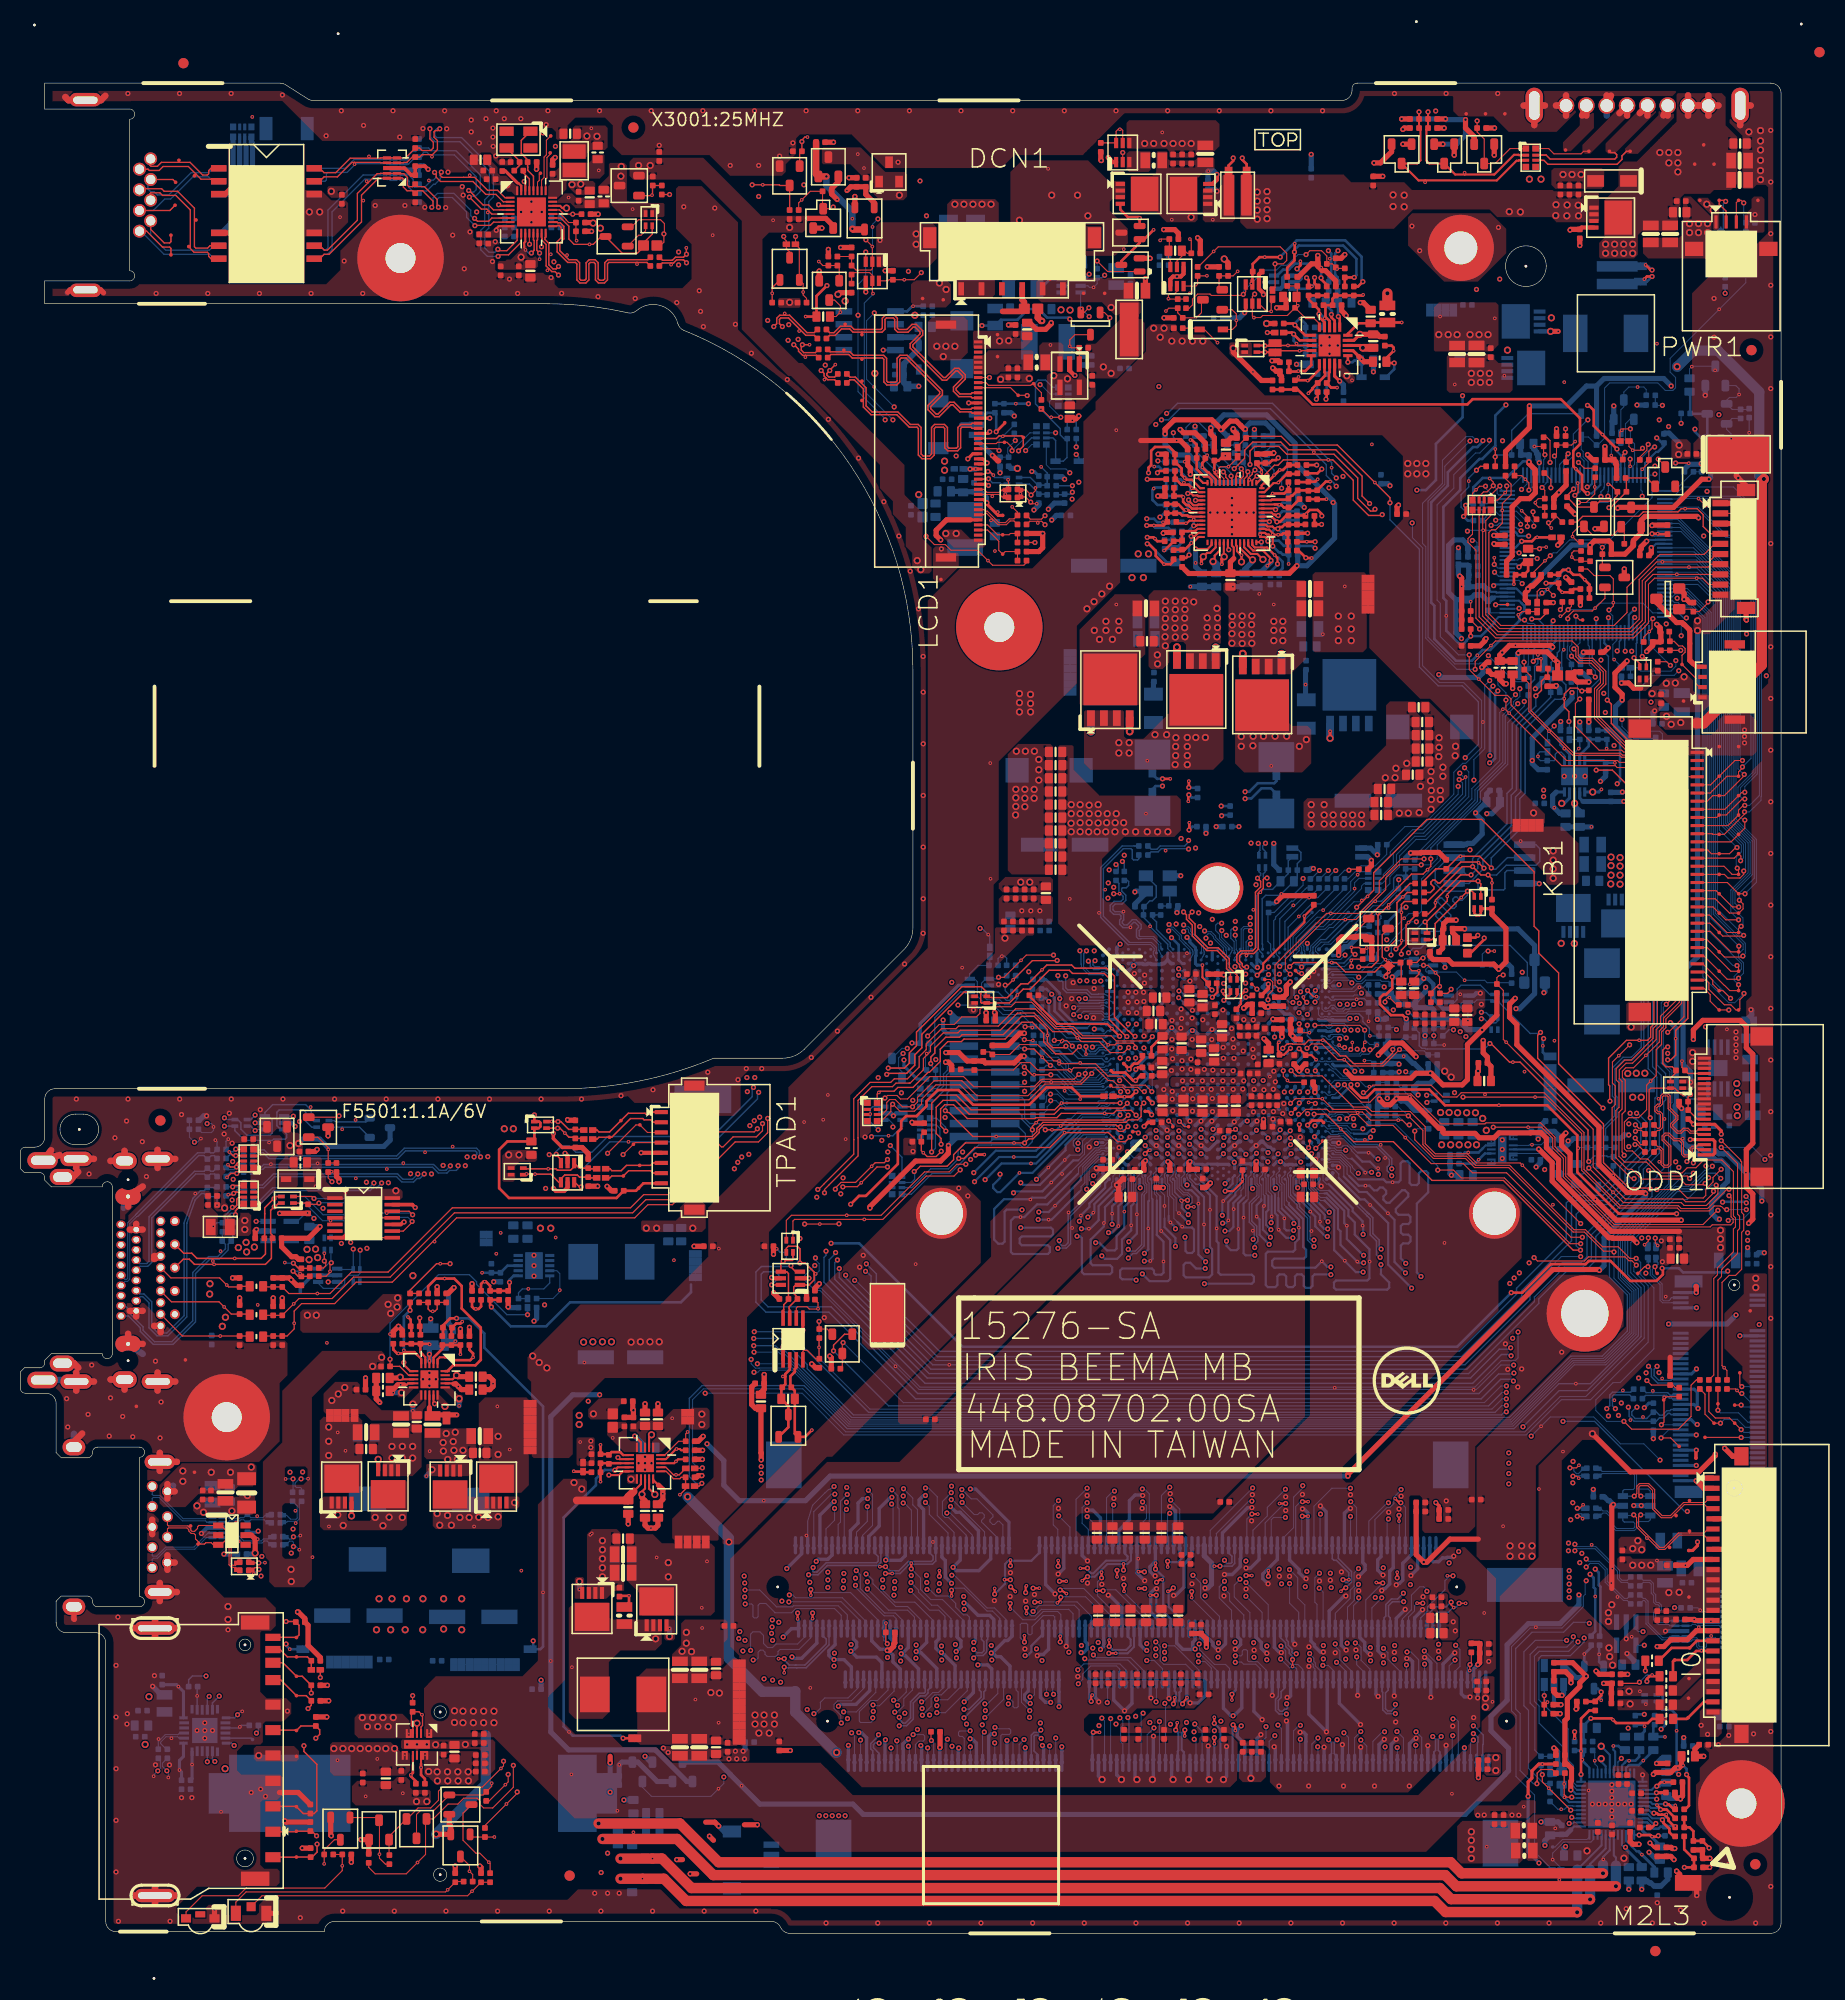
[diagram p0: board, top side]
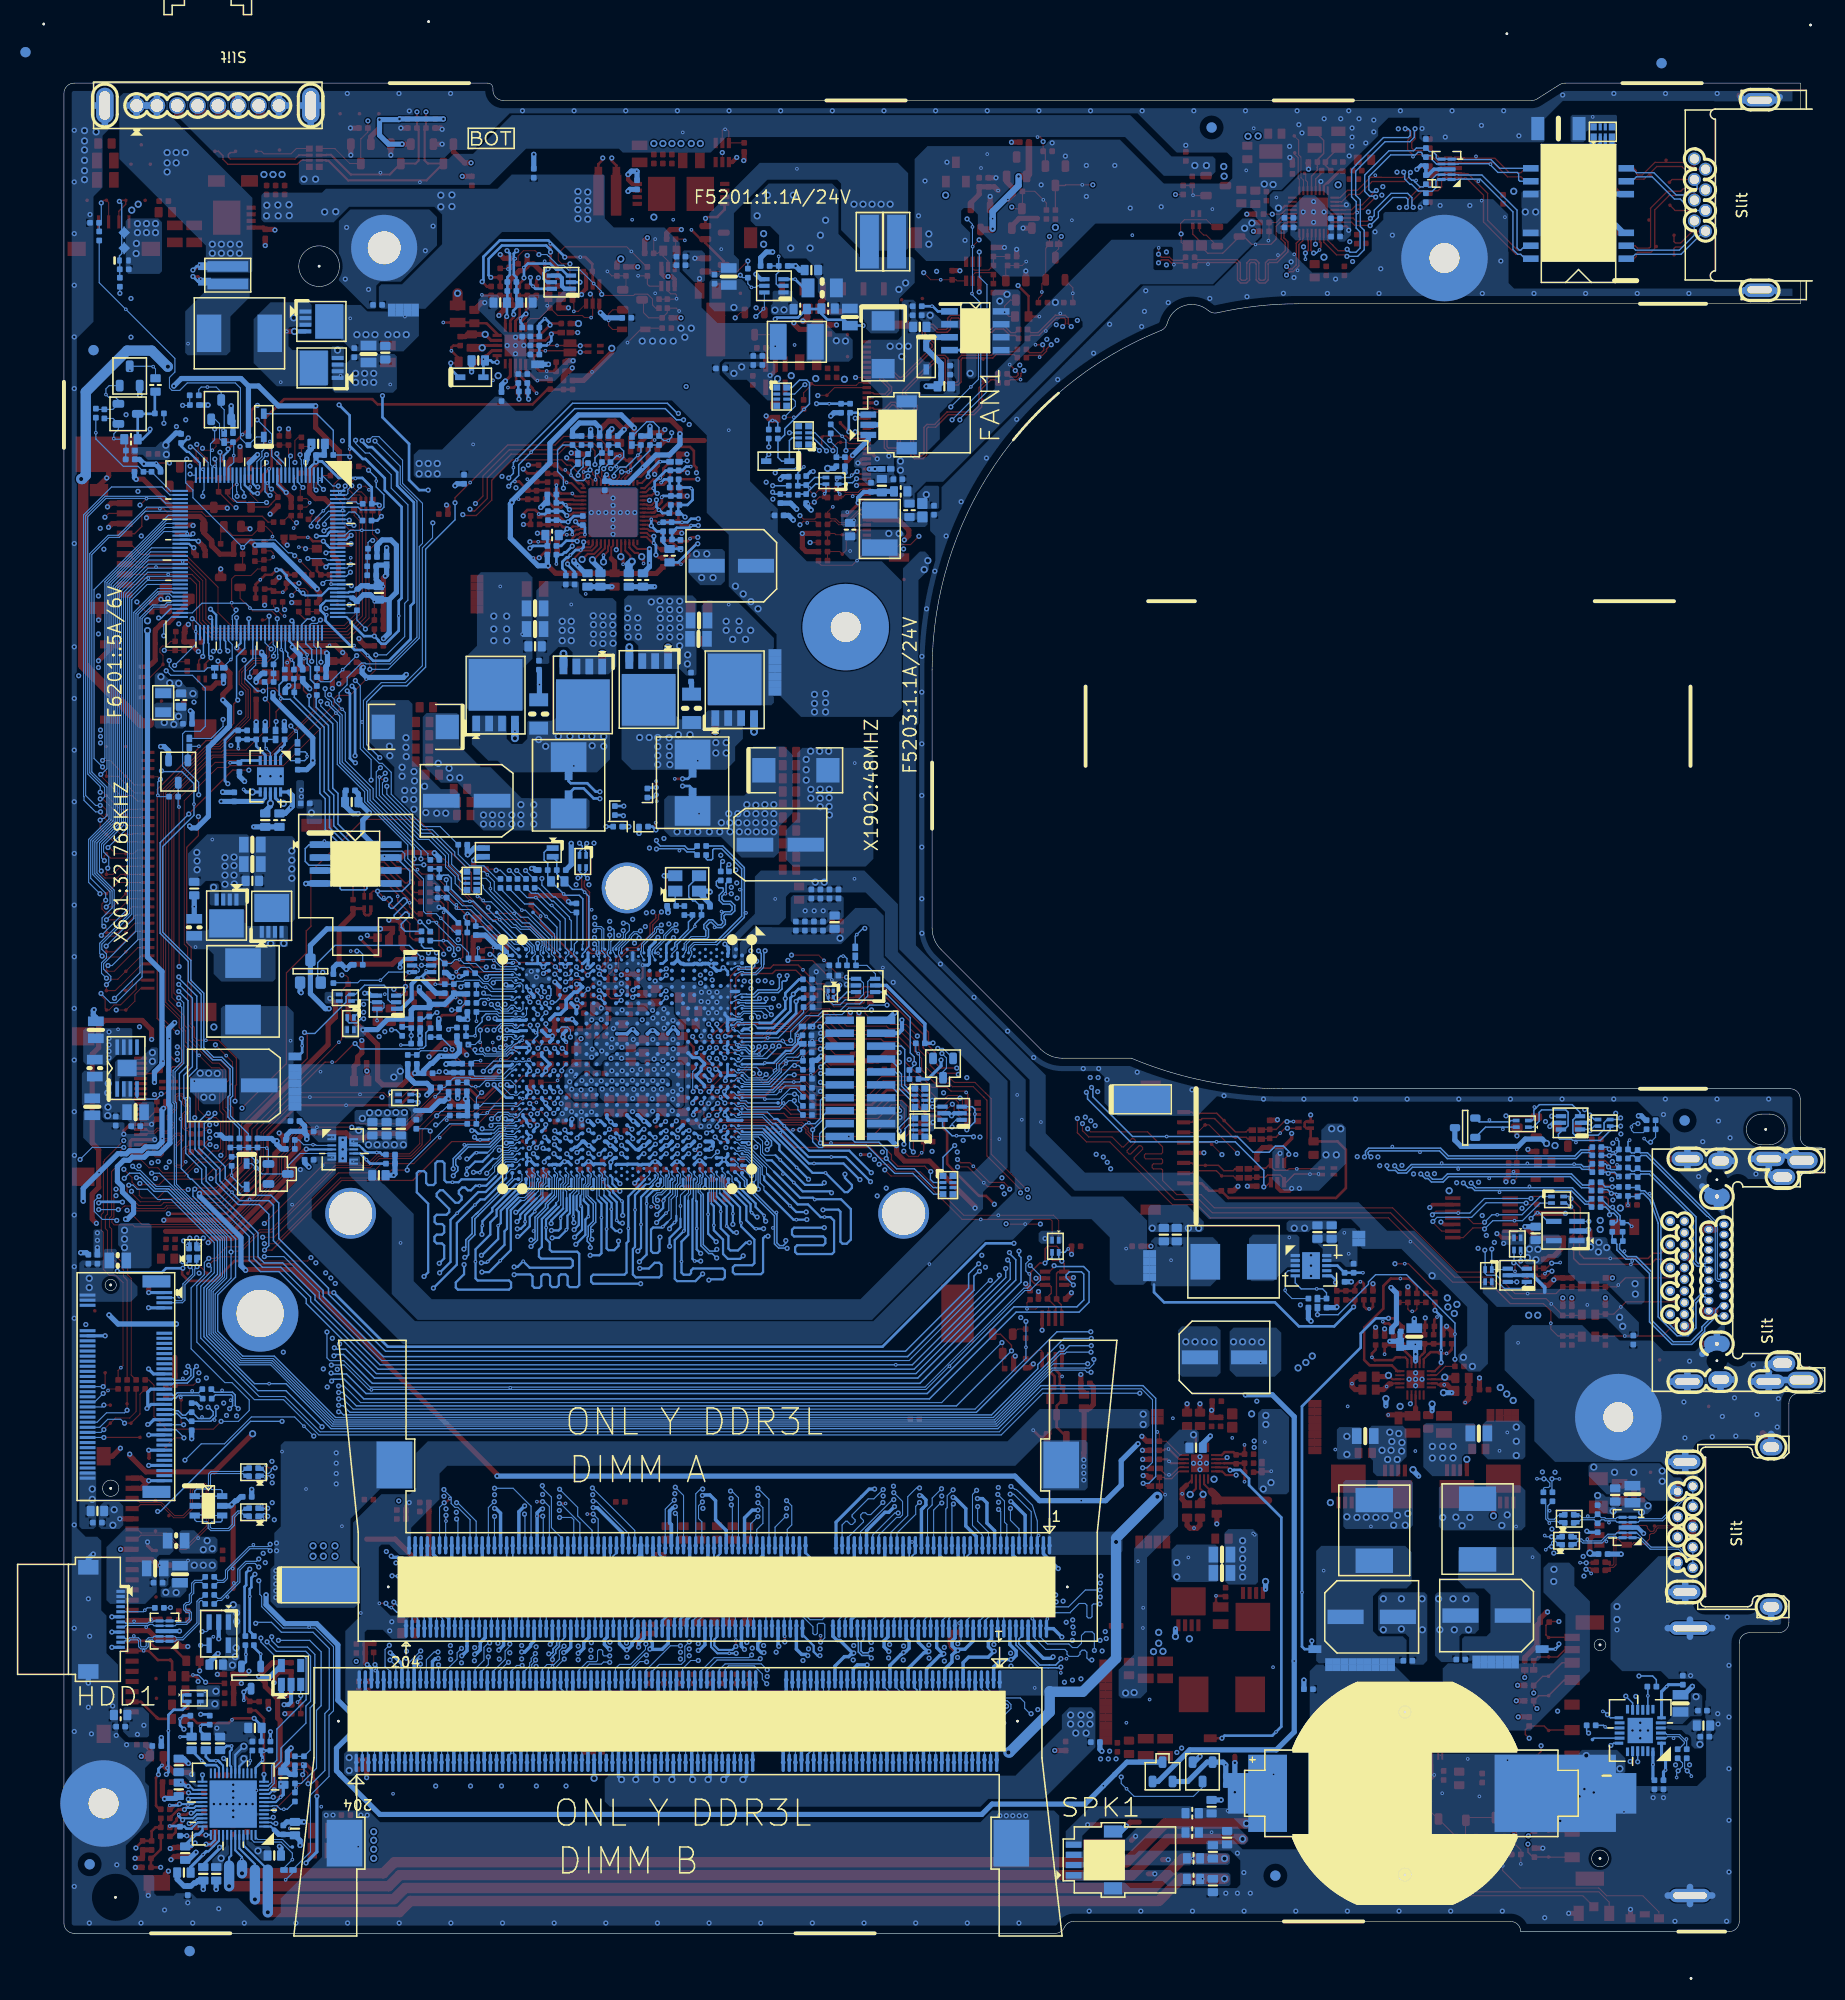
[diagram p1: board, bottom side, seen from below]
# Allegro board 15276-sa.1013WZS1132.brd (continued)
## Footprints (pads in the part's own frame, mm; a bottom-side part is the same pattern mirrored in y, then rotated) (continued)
NTC-402H22-U
  custom 0.14x0.14 smd: 1(0,0.445) 2(0,-0.445)
NTC-603H38
  custom 0.216x0.216 smd: 1(0,0.762) 2(0,-0.762)
OSC-3225-4P-3H36
  rect 1.397x0.914 smd: 1(-1.171,-0.825) 2(1.171,-0.825) 3(1.171,0.825) 4(-1.171,0.825)
OSC-3225-4P-4H36
  rect 1.397x1.067 smd: 1(-1.171,-0.756) 2(1.171,-0.756) 3(1.171,0.756) 4(-1.171,0.756)
PAD-2P-4516-U
  rect 1.854x4.013 smd: 1(0,1.969)
  rect 1.854x1.346 smd: 2(0,-1.969)
PAD-D-SUB-HDMI-COLAY-U
  round 0.254 hole 1.422 unplated: (-8.9,6.45) (8.9,6.45)
  round 0.914 hole 0.61: 1(-4.33,9.65) 2(-2.04,9.65) 3(0.25,9.65) 4(2.54,9.65) 5(4.83,9.65) 6(-5.475,9.65) 7(-3.185,9.65) 8(-0.895,9.65) 9(1.395,9.65) 10(3.685,9.65)
  round 0.965 hole 0.61: 11(-4.33,11.05) 12(-2.04,11.05) 13(0.25,11.05) 14(2.54,11.05) 15(4.83,11.05)
  oval 0.762x0.914 hole 0.508: HP1(-4.5,5.75) HP2(-4,7.25) HP3(-3.5,5.75) HP4(-3,7.25) HP5(-2.5,5.75) HP6(-2,7.25) HP7(-1.5,5.75) HP8(-1,7.25) HP9(-0.5,5.75) HP10(0,7.25) HP11(0.5,5.75) HP12(1,7.25) HP13(1.5,5.75) HP14(2,7.25) HP15(2.5,5.75) HP16(3,7.25) HP17(3.5,5.75) HP18(4,7.25) HP19(4.5,5.75)
  oval 1.422x3.124 hole 0.711x2.413: PTH1(10.95,9.35) PTH4(10.95,1.35) PTH7(-10.95,9.35) PTH10(-10.95,1.35)
  oval 1.626x2.413 hole 0.914x1.702: PTH2(10.75,6.1) PTH9(-10.75,6.1)
  custom 0.404x0.404 hole 0.914x1.803: PTH3(7.25,6.45) PTH8(-7.25,6.45)
  oval 1.575x2.515 hole 0.914x1.803: PTH5(9.15,0) PTH11(-9.15,0)
  oval 1.626x2.997 hole 0.914x2.413: PTH6(10.8,-1.9) PTH12(-10.8,-1.9)
POLYSW-2114H30
  rect 1.6x0.965 smd: 1(0,0.94) 2(0,-0.94)
POLYSW-2114H50
  rect 1.6x0.965 smd: 1(0,0.94) 2(0,-0.94)
POLYSW-4633-UH43
  rect 3.505x1.626 smd: 1(0,1.834) 2(0,-1.834)
PPAK-5PH45
  rect 0.762x1.524 smd: 1(-1.905,-3.81) 2(-0.635,-3.81) 3(0.635,-3.81) 4(1.905,-3.81)
  rect 5.283x5.08 smd: 5(0,0)
  rect 0.025x0.025 smd: 6(0.635,2.032) 7(-0.635,2.032) 8(-1.905,2.032)
PPAK-8P-2H45
  rect 0.406x1.168 smd: 1(-0.975,-2.351) 2(-0.325,-2.351) 3(0.325,-2.351) 4(0.975,-2.351)
  rect 3.404x2.769 smd: 5(0,0)
  rect 0.025x0.025 smd: 6(1.029,0.902) 7(0.013,0.902) 8(-0.991,0.902)
PPAK-8P-3232H36
  rect 0.406x0.914 smd: 1(-0.975,-2.396) 2(-0.325,-2.396) 3(0.325,-2.396) 4(0.975,-2.396)
  rect 3.353x2.692 smd: 5(0,0)
  rect 0.025x0.025 smd: 6(0.65,0.838) 7(0,0.838) 8(-0.65,0.838)
QFN20-G1D75H32
  rect 0.203x0.914 smd: 1(0.8,1.551) 2(0.4,1.551) 3(0,1.551) 4(-0.4,1.551) 5(-0.8,1.551) 11(-0.8,-1.551) 12(-0.4,-1.551) 13(0,-1.551) 14(0.4,-1.551) 15(0.8,-1.551)
  rect 0.914x0.203 smd: 6(-1.551,0.8) 7(-1.551,0.4) 8(-1.551,0) 9(-1.551,-0.4) 10(-1.551,-0.8) 16(1.551,-0.8) 17(1.551,-0.4) 18(1.551,0) 19(1.551,0.4) 20(1.551,0.8)
  rect 1.753x1.753 smd: 21(0,0)
QFN20G3D5-G2D15H40
  rect 0.305x0.914 smd: 1(1,1.801) 5(-1,1.801) 11(-1,-1.801) 15(1,-1.801)
  rect 0.305x0.965 smd: 2(0.5,1.775) 3(0,1.775) 4(-0.5,1.775) 12(-0.5,-1.775) 13(0,-1.775) 14(0.5,-1.775)
  rect 0.914x0.305 smd: 6(-1.801,1) 10(-1.801,-1) 16(1.801,-1) 20(1.801,1)
  rect 0.965x0.305 smd: 7(-1.775,0.5) 8(-1.775,0) 9(-1.775,-0.5) 17(1.775,-0.5) 18(1.775,0) 19(1.775,0.5)
  rect 2.159x2.159 smd: 21(0,0)
QFN24-G2D5H40-U
  rect 0.305x0.838 smd: 1(1.25,2.095) 6(-1.25,2.095) 13(-1.25,-2.095) 18(1.25,-2.095)
  rect 0.305x0.965 smd: 2(0.751,2.032) 3(0.25,2.032) 4(-0.25,2.032) 5(-0.751,2.032) 14(-0.751,-2.032) 15(-0.25,-2.032) 16(0.25,-2.032) 17(0.751,-2.032)
  rect 0.838x0.305 smd: 7(-2.095,1.25) 12(-2.095,-1.25) 19(2.095,-1.25) 24(2.095,1.25)
  rect 0.965x0.305 smd: 8(-2.032,0.751) 9(-2.032,0.25) 10(-2.032,-0.25) 11(-2.032,-0.751) 20(2.032,-0.751) 21(2.032,-0.25) 22(2.032,0.25) 23(2.032,0.751)
  rect 2.489x2.489 smd: 25(0,0)
QFN32J4-G2D85H36
  rect 0.203x0.864 smd: 1(1.4,2.085) 2(1,2.085) 3(0.6,2.085) 4(0.2,2.085) 5(-0.2,2.085) 6(-0.6,2.085) 7(-1,2.085) 8(-1.4,2.085) 17(-1.4,-2.085) 18(-1,-2.085) 19(-0.6,-2.085) 20(-0.2,-2.085) 21(0.2,-2.085) 22(0.6,-2.085) 23(1,-2.085) 24(1.4,-2.085)
  rect 0.864x0.203 smd: 9(-2.085,1.4) 10(-2.085,1) 11(-2.085,0.6) 12(-2.085,0.2) 13(-2.085,-0.2) 14(-2.085,-0.6) 15(-2.085,-1) 16(-2.085,-1.4) 25(2.085,-1.4) 26(2.085,-1) 27(2.085,-0.6) 28(2.085,-0.2) 29(2.085,0.2) 30(2.085,0.6) 31(2.085,1) 32(2.085,1.4)
  rect 2.845x2.845 smd: 33(0,0)
QFN48J6-G465H40
  rect 0.203x0.965 smd: 1(2.2,3.025) 2(1.8,3.025) 3(1.4,3.025) 4(1,3.025) 5(0.6,3.025) 6(0.2,3.025) 7(-0.2,3.025) 8(-0.6,3.025) 9(-1,3.025) 10(-1.4,3.025) 11(-1.8,3.025) 12(-2.2,3.025) 25(-2.2,-3.025) 26(-1.8,-3.025) 27(-1.4,-3.025) 28(-1,-3.025) 29(-0.6,-3.025) 30(-0.2,-3.025) 31(0.2,-3.025) 32(0.6,-3.025) 33(1,-3.025) 34(1.4,-3.025) 35(1.8,-3.025) 36(2.2,-3.025)
  rect 0.965x0.203 smd: 13(-3.025,2.2) 14(-3.025,1.8) 15(-3.025,1.4) 16(-3.025,1) 17(-3.025,0.6) 18(-3.025,0.2) 19(-3.025,-0.2) 20(-3.025,-0.6) 21(-3.025,-1) 22(-3.025,-1.4) 23(-3.025,-1.8) 24(-3.025,-2.2) 37(3.025,-2.2) 38(3.025,-1.8) 39(3.025,-1.4) 40(3.025,-1) 41(3.025,-0.6) 42(3.025,-0.2) 43(3.025,0.2) 44(3.025,0.6) 45(3.025,1) 46(3.025,1.4) 47(3.025,1.8) 48(3.025,2.2)
  rect 4.648x4.648 smd: 49(0,0)
R402H14
  custom 0.14x0.14 smd: 1(0,0.445) 2(0,-0.445)
R402H15
  custom 0.14x0.14 smd: 1(0,0.445) 2(0,-0.445)
R402H16
  custom 0.14x0.14 smd: 1(0,0.445) 2(0,-0.445)
R603H22
  custom 0.197x0.197 smd: 1(0,0.66) 2(0,-0.66)
R805H24
  rect 1.549x0.94 smd: 1(0,0.838) 2(0,-0.838)
R1206H28
  rect 1.854x1.27 smd: 1(0,1.397) 2(0,-1.397)
R3720H40
  rect 4.013x1.041 smd: 1(0,0.867) 2(0,-0.867)
SC70-6H44
  rect 0.406x1.016 smd: 1(-0.65,-0.94) 2(0,-0.94) 3(0.65,-0.94) 4(0.65,0.94) 5(0,0.94) 6(-0.65,0.94)
SE361413H182
  rect 1.372x3.556 smd: 1(0,2.424) 2(0,-2.424)
SE361414H178
  rect 1.372x3.607 smd: 1(0,2.499) 2(0,-2.499)
SE361416H178
  rect 1.422x3.556 smd: 1(0,2.574) 2(0,-2.574)
SKT-USB13-160166-7
  round 1.067 hole 0.711: 1(3.5,9.2) 2(1,9.2) 3(-1,9.2) 4(-3.5,9.2) 5(-4,7.7) 6(-2,7.7) 7(0,7.7) 8(2,7.7) 9(4,7.7)
  oval 1.422x2.997 hole 0.711x2.286: 10(6.4,8.45) 11(-6.4,8.45)
  oval 1.626x2.235 hole 0.914x1.524: 12(7.85,0) 13(-7.85,0)
SMD49-6914-0403H56
  rect 1.168x0.559 smd: 1(-3.38,-0.427) 2(3.38,-0.427) 3(3.38,0.427) 4(-3.38,0.427)
SMD-ARES4
  rect 0.356x0.66 smd: 1(-0.325,-0.599) 2(0.325,-0.599) 3(0.325,0.599) 4(-0.325,0.599)
SMD-ARES4-2H18-U
  rect 0.305x0.406 smd: 1(-0.25,-0.305) 2(0.25,-0.305) 3(0.25,0.305) 4(-0.25,0.305)
SMD-ARES4H18
  rect 0.356x0.66 smd: 1(-0.325,-0.599) 2(0.325,-0.599) 3(0.325,0.599) 4(-0.325,0.599)
SMD-ARES4H20
  rect 0.356x0.66 smd: 1(-0.325,-0.599) 2(0.325,-0.599) 3(0.325,0.599) 4(-0.325,0.599)
SOD123FLAKH40
  rect 1.143x1.651 smd: A(0,1.622) K(0,-1.622)
SOD323AKH38
  rect 0.559x1.016 smd: A(0,1.143) K(0,-1.143)
SOD323AKH42
  rect 0.559x1.016 smd: A(0,1.143) K(0,-1.143)
SOD882-10D6-1H20
  custom 0.114x0.114 smd: 1(0,0.445) 2(0,-0.445)
SOIC8-1H86
  rect 0.635x1.651 smd: 1(-1.905,-3.493) 2(-0.635,-3.493) 3(0.635,-3.493) 4(1.905,-3.493) 5(1.905,3.493) 6(0.635,3.493) 7(-0.635,3.493) 8(-1.905,3.493)
SOIC8H69
  rect 0.635x1.651 smd: 1(-1.905,-2.54) 2(-0.635,-2.54) 3(0.635,-2.54) 4(1.905,-2.54) 5(1.905,2.54) 6(0.635,2.54) 7(-0.635,2.54) 8(-1.905,2.54)
SOT23-2D4-312H44
  custom 0.191x0.191 smd: 1(-0.984,-0.953) 2(0.984,-0.953) 3(0,0.953)
SOT23-2D4-312H48
  custom 0.191x0.191 smd: 1(-0.984,-0.953) 2(0.984,-0.953) 3(0,0.953)
SOT23-2D6-312H46
  custom 0.165x0.165 smd: 1(-0.95,-1.092) 2(0.95,-1.092) 3(0,1.092)
SOT23-2D8-312H58
  custom 0.254x0.254 smd: 1(-1.016,-1.118) 2(1.016,-1.118) 3(0,1.118)
SOT23CBE2D4H44
  custom 0.191x0.191 smd: B(-0.984,-0.953) C(0,0.953) E(0.984,-0.953)
SOT23CBE2D6H46
  custom 0.165x0.165 smd: B(-0.95,-1.092) C(0,1.092) E(0.95,-1.092)
SOT23CBE2D6H62
  custom 0.165x0.165 smd: B(-0.95,-1.092) C(0,1.092) E(0.95,-1.092)
SOT23DGS2D4H44
  custom 0.191x0.191 smd: D(0,0.953) G(-0.984,-0.953) S(0.984,-0.953)
SOT23DGS2D4H48
  custom 0.191x0.191 smd: D(0,0.953) G(-0.984,-0.953) S(0.984,-0.953)
SOT23DGS2D8H56
  custom 0.254x0.254 smd: D(0,1.118) G(-1.016,-1.118) S(1.016,-1.118)
SOT323CBE2D2H40
  custom 0.152x0.152 smd: B(-0.65,-0.902) C(0,0.902) E(0.65,-0.902)
SOT323EBC2D2H40
  custom 0.152x0.152 smd: B(-0.65,-0.902) C(0.65,-0.902) E(0,0.902)
SOT-6H58
  rect 0.584x1.016 smd: 1(-0.953,-1.346) 2(0,-1.346) 3(0.953,-1.346) 4(0.953,1.346) 5(0,1.346) 6(-0.953,1.346)
SOT-23-5H51
  rect 0.508x1.524 smd: 1(-0.95,-1.143) 2(0,-1.143) 3(0.95,-1.143) 4(0.95,1.143) 5(-0.95,1.143)
SOT-23-5H58
  rect 0.508x1.524 smd: 1(-0.95,-1.143) 2(0,-1.143) 3(0.95,-1.143) 4(0.95,1.143) 5(-0.95,1.143)
SOT-23-9H44
  custom 0.178x0.178 smd: 1(-0.95,-0.999) 2(0.95,-0.999) 3(0,0.999)
SOT-23-10H44
  rect 0.762x1.143 smd: 1(-0.984,-0.953) 2(0.984,-0.953) 3(0,0.953)
SOT-23-2924-5PH46
  rect 0.686x1.295 smd: 1(-0.95,-0.933) 2(0,-0.933) 3(0.95,-0.933) 4(0.95,0.933) 5(-0.95,0.933)
SOT-363H44
  rect 0.406x1.016 smd: 1(-0.65,-0.94) 2(0,-0.94) 3(0.65,-0.94) 4(0.65,0.94) 5(0,0.94) 6(-0.65,0.94)
SPR5930H154
  rect 5.588x2.692 smd: 1(-1.702,0)
SPR6035H166
  rect 5.69x3.2 smd: 1(-1.6,0)
SPR6438H83
  rect 6.096x3.505 smd: 1(-1.6,0)
SPR7837H229
  rect 7.493x3.353 smd: 1(-2.095,0)
TPAD14-OP
  round 0.356 smd: 1(0,0)
TSOIC14H48
  rect 0.356x1.524 smd: 1(-1.949,-2.819) 2(-1.3,-2.819) 3(-0.65,-2.819) 4(0,-2.819) 5(0.65,-2.819) 6(1.3,-2.819) 7(1.949,-2.819) 8(1.949,2.819) 9(1.3,2.819) 10(0.65,2.819) 11(0,2.819) 12(-0.65,2.819) 13(-1.3,2.819) 14(-1.949,2.819)
unnamed
  round 1.016 smd: (0,0)
XFORM12A127097H91
  rect 0.635x1.524 smd: 1(-4.445,-4.699) 2(-3.175,-4.699) 3(-1.905,-4.699) 4(1.905,-4.699) 5(3.175,-4.699) 6(4.445,-4.699) 7(4.445,4.699) 8(3.175,4.699) 9(1.905,4.699) 10(-1.905,4.699) 11(-3.175,4.699) 12(-4.445,4.699)

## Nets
3V5V_CT1: C3602.1 U3601.12
3V5V_CT2: C3601.1 U3601.10
3V5V_S0_ON: R3609.1 U3601.3 U3601.5
3V_5V_EN: D3602.1 PR4527.1 PR4529.1 R3602.1 R3603.1
3V_5V_POK: PR4510.2 PR5010.1 PU4509.7 Q601.2 RN602.2(A)
5V_HDD_S0: AFTP5601.1 C5605.1 C5606.1 HDD1.1 HDD1.2 HDD1.3 R5601.2
5V_HDMI_CRT_S0: D5501.K F5501.2 R5506.1 RN5508.1(A) RN5508.2(A) U5603.1 U5603.4 U5603.14
5V_HDMI_CRT_S0_R: C5401.1 C5519.1 F5501.1 HDMI1.9 HDMI1.HP18
5V_PWR: PC4516.1 PG4511.2 PG4512.2 PG4514.2 PG4524.2 PG4527.2 PG4528.2 PG4529.2 PG4531.2 PG4535.2 PG4547.1 PL4503.2 TC4503.1
5V_PWR_2: PG4543.2
5V_PWR_2_R: PC4529.1 PG4543.1 PU4509.13
5V_S0: C2605.1 C2611.1 C3605.1 C5601.1 C5604.1 C5609.1 D5401.3 D5501.A EC9718.1 EC9719.1 EC9720.1 EC9721.1 EC9722.1 EC9723.1 EC9724.1 EC9725.1 EC9726.1 EC9727.1 EC9728.1 F6201.1 FAN261.2 Q5403.G Q6106.E Q6201.E R2702.1 R2703.1 R2704.1 R5230.1 R5413.1 R5506.2 R5601.1 R5603.1 R6205.1 U3601.13 U3601.14 U5601.2 U5601.3
5V_S5: C3505.1 C3510.1 EC9732.1 EC9733.1 EC9734.1 PC4608.1 PC4829.1 PC4901.1 PG4511.1 PG4512.1 PG4514.1 PG4524.1 PG4527.1 PG4528.1 PG4529.1 PG4531.1 PG4535.1 PR4203.1 PR4610.2 PR4660.2 PR4661.2 PU4601.33 PU4806.7 PU4901.12 Q6103.E Q6104.E U3503.5 U3504.5 U3601.1 U3601.2 U3601.4 U3603.4
+3V_1D5V_AVDD: C2715.1 HDA27.40 R2705.2
+3V_AVDD: C2701.1 HDA27.36 R2701.2 R2722.1
+5V_AVDD: C2710.1 C2711.1 HDA27.26 R2703.2
+5V_KB_BL: AFTP6248.1 C6204.1 F6201.2 KBLIT1.1 R6205.2
+5V_PVDD: C2706.1 C2707.1 C2708.1 C2709.1 HDA27.41 HDA27.46 R2702.2 R2704.2
GND: AFTP2501.1 AFTP2803.1 AFTP3301.1 AFTP3906.1 AFTP3909.1 AFTP3910.1 AFTP6102.1 AFTP6201.1 AFTP6217.1 AFTP6235.1 AFTP6245.1 AFTP6314.1 BATT1.6 BATT1.8 BATT1.9 BATT1.10 C1.1 C2.1 C3.1 C401.2 C402.2 C443.1 C501.2 C502.2 C601.1 C603.2 C604.2 C701.2 C702.2 C703.2 C704.2 C705.2 C762.2 C1001.2 C1002.2 C1003.2 C1004.2 C1005.2 C1006.2 C1007.2 C1008.2 C1009.2 C1010.2 C1011.2 C1012.2 C1013.2 C1014.2 C1015.2 C1016.2 C1017.2 C1022.2 C1023.2 C1024.2 C1025.2 C1026.2 C1027.2 C1028.2 C1029.2 C1030.2 C1031.2 C1032.2 C1033.2 C1034.2 C1035.2 C1036.2 C1037.2 C1038.2 C1039.2 C1040.2 C1041.2 C1042.2 C1043.2 C1044.2 C1045.2 C1046.2 C1047.2 C1049.2 C1050.2 C1051.1 C1053.2 C1054.2 C1055.2 C1056.1 C1057.1 C1058.1 C1059.1 C1060.2 C1061.1 C1062.1 C1063.1 C1064.2 C1065.2 C1066.2 C1067.2 C1068.2 C1069.2 C1070.2 C1071.2 C1072.2 C1073.2 C1074.2 C1075.2 C1077.2 C1080.2 C1081.2 C1082.2 C1083.2 C1084.2 C1085.2 C1086.2 C1087.2 C1088.2 C1089.2 C1090.2 C1092.1 C1093.2 C1094.2 C1095.2 C1096.2 C1097.2 C1098.2 C1099.2 C1100.2 C1101.2 C1105.2 C1106.2 C1107.2 C1113.2 C1114.2 C1115.2 C1201.2 C1202.2 C1203.2 C1204.2 C1205.2 C1208.2 C1209.2 C1210.2 C1211.2 C1212.2 C1213.2 C1214.2 C1215.2 C1216.2 C1217.2 C1218.2 C1219.2 C1220.2 C1221.2 C1222.2 C1223.2 C1224.2 C1225.2 C1306.2 C1307.2 C1326.2 C1327.2 C1328.2 C1329.2 C1330.2 C1331.2 C1332.2 C1333.2 C1334.2 C1335.2 C1336.2 C1337.2 C1338.2 C1339.2 C1340.2 C1341.2 C1342.2 C1343.2 C1344.2 C1345.2 C1346.2 C1904.1 C1905.1 C2406.2 C2407.2 C2408.2 C2409.2 C2410.2 C2411.2 C2412.2 C2413.2 C2415.1 C2416.2 C2418.2 C2421.2 C2501.2 C2502.2 C2503.1 C2601.2 C2602.2 C2603.2 C2604.2 C2605.2 C2608.2 C2609.2 C2610.2 C2611.2 C2704.1 C2706.2 C2707.2 C2708.2 C2709.2 C2716.2 C2717.2 C2718.2 C2719.2 C2723.1 C3001.2 C3002.2 C3003.2 C3004.2 C3005.2 C3007.2 C3008.2 C3009.2 C3010.2 C3011.2 C3012.2 C3013.2 C3017.2 C3018.2 C3019.2 C3021.2 C3022.2 C3023.2 C3024.2 C3025.2 C3101.2 C3106.2 C3201.1 C3202.2 C3203.2 C3204.2 C3205.2 C3206.2 C3301.2 C3302.2 C3303.2 C3401.2 C3402.2 C3405.2 C3406.2 C3505.2 C3507.2 C3508.2 C3510.2 C3512.2 C3513.2 C3519.2 C3520.2 C3521.2 C3601.2 C3602.2 C3603.2 C3605.2 C3607.2 C3612.2 C3613.2 C3617.2 C3618.2 C3619.2 C3620.1 C3621.1 C3625.2 C3626.2 C5201.2 C5202.2 C5204.2 C5205.1 C5206.1 C5207.2 C5208.2 C5214.2 C5401.2 C5506.2 C5508.2 C5509.2 C5510.2 C5511.2 C5519.2 C5539.2 C5540.2 C5541.2 C5542.2 C5543.2 C5601.2 C5604.2 C5605.2 C5606.2 C5609.2 C5610.2 C5801.2 C5802.2 C5803.2 C5804.2 C5805.2 C5806.2 C6202.2 C6203.2 C6204.2 CARD1.3 CARD1.6 CARD1.12 CARD1.13 CARD1.14 CARD1.15 CN6301.1 CN6301.2 CN6301.5 CN6301.8 CN6301.25 CN6301.26 CPU1.A8 CPU1.A13 CPU1.A15 CPU1.A31 CPU1.A35 CPU1.A39 CPU1.AA3 CPU1.AA7 CPU1.AA8 CPU1.AA11 CPU1.AA15 CPU1.AA19 CPU1.AA25 CPU1.AA29 CPU1.AA39 CPU1.AC3 CPU1.AC7 CPU1.AC11 CPU1.AC15 CPU1.AC19 CPU1.AC25 CPU1.AC29 CPU1.AC31 CPU1.AC39 CPU1.AC41 CPU1.AE3 CPU1.AE7 CPU1.AE25 CPU1.AE29 CPU1.AE32 CPU1.AE39 CPU1.AG3 CPU1.AG5 CPU1.AG10 CPU1.AG11 CPU1.AG13 CPU1.AG15 CPU1.AG19 CPU1.AG25 CPU1.AG29 CPU1.AG31 CPU1.AG39 CPU1.AG41 CPU1.AH1 CPU1.AH2 CPU1.AJ3 CPU1.AJ7 CPU1.AJ15 CPU1.AJ17 CPU1.AJ19 CPU1.AJ23 CPU1.AJ25 CPU1.AJ29 CPU1.AJ31 CPU1.AJ32 CPU1.AJ39 CPU1.AL3 CPU1.AL8 CPU1.AL15 CPU1.AL17 CPU1.AL19 CPU1.AL25 CPU1.AL29 CPU1.AL31 CPU1.AL39 CPU1.AL41 CPU1.AM11 CPU1.AM27 CPU1.AM29 CPU1.AM31 CPU1.AN3 CPU1.AN7 CPU1.AN39 CPU1.AP31 CPU1.AR3 CPU1.AR13 CPU1.AR17 CPU1.AR21 CPU1.AR25 CPU1.AR29 CPU1.AR39 CPU1.AR41 CPU1.AU1 CPU1.AU2 CPU1.AU3 CPU1.AU15 CPU1.AU19 CPU1.AU23 CPU1.AU27 CPU1.AU39 CPU1.AV9 CPU1.AW3 CPU1.AW7 CPU1.AW13 CPU1.AW15 CPU1.AW17 CPU1.AW19 CPU1.AW21 CPU1.AW23 CPU1.AW25 CPU1.AW27 CPU1.AW31 CPU1.AW33 CPU1.AW35 CPU1.AW37 CPU1.AW39 CPU1.AW41 CPU1.AY13 CPU1.AY15 CPU1.AY18 CPU1.AY30 CPU1.B8 CPU1.B13 CPU1.B23 CPU1.B31 CPU1.B39 CPU1.BA2 CPU1.BA7 CPU1.BA13 CPU1.BA15 CPU1.BA18 CPU1.BA21 CPU1.BA25 CPU1.BA31 CPU1.BA35 CPU1.BA39 CPU1.C1 CPU1.C2 CPU1.C5 CPU1.C7 CPU1.C9 CPU1.C11 CPU1.C13 CPU1.C15 CPU1.C17 CPU1.C19 CPU1.C21 CPU1.C23 CPU1.C25 CPU1.C27 CPU1.C29 CPU1.C31 CPU1.C33 CPU1.C35 CPU1.C37 CPU1.C39 CPU1.C41 CPU1.D9 CPU1.D11 CPU1.D13 CPU1.E3 CPU1.E4 CPU1.E9 CPU1.E11 CPU1.E13 CPU1.E27 CPU1.E31 CPU1.E35 CPU1.E38 CPU1.E39 CPU1.G3 CPU1.G7 CPU1.G11 CPU1.G13 CPU1.G15 CPU1.G17 CPU1.G21 CPU1.G25 CPU1.G29 CPU1.G35 CPU1.G37 CPU1.G39 CPU1.G41 CPU1.H11 CPU1.H13 CPU1.H23 CPU1.H31 CPU1.J3 CPU1.J7 CPU1.J8 CPU1.J39 CPU1.K11 CPU1.K13 CPU1.K17 CPU1.K19 CPU1.K21 CPU1.K23 CPU1.K25 CPU1.K27 CPU1.K29 CPU1.K31 CPU1.L3 CPU1.L7 CPU1.L8 CPU1.L10 CPU1.L11 CPU1.L15 CPU1.L19 CPU1.L31 CPU1.L39 CPU1.L41 CPU1.M1 CPU1.M2 CPU1.N3 CPU1.N7 CPU1.N15 CPU1.N19 CPU1.N25 CPU1.N29 CPU1.N31 CPU1.N39 CPU1.P1 CPU1.P2 CPU1.R3 CPU1.R7 CPU1.R15 CPU1.R19 CPU1.R25 CPU1.R29 CPU1.R39 CPU1.R41 CPU1.U1 CPU1.U2 CPU1.U3 CPU1.U7 CPU1.U8 CPU1.U11 CPU1.U15 CPU1.U19 CPU1.U25 CPU1.U29 CPU1.U31 CPU1.U39 CPU1.W3 CPU1.W5 CPU1.W11 CPU1.W15 CPU1.W19 CPU1.W25 CPU1.W29 CPU1.W39 CPU1.W41 CPU1.Y1 CPU1.Y2 D2601.A D4301.1 D4302.1 D4303.1 DB1.1 DB1.3 DB1.11 DB1.12 DCIN1.7 DCIN1.8 DM1.2 DM1.3 DM1.8 DM1.9 DM1.13 DM1.14 DM1.19 DM1.20 DM1.25 DM1.26 DM1.31 DM1.32 DM1.37 DM1.38 DM1.43 DM1.44 DM1.48 DM1.49 DM1.54 DM1.55 DM1.60 DM1.61 DM1.65 DM1.66 DM1.71 DM1.72 DM1.127 DM1.128 DM1.133 DM1.134 DM1.138 DM1.139 DM1.144 DM1.145 DM1.150 DM1.151 DM1.155 DM1.156 DM1.161 DM1.162 DM1.167 DM1.168 DM1.172 DM1.173 DM1.178 DM1.179 DM1.184 DM1.185 DM1.189 DM1.190 DM1.195 DM1.196 DM1.197 DM1.201 DM1.205 DM1.206 DM2.2 DM2.3 DM2.8 DM2.9 DM2.13 DM2.14 DM2.19 DM2.20 DM2.25 DM2.26 DM2.31 DM2.32 DM2.37 DM2.38 DM2.43 DM2.44 DM2.48 DM2.49 DM2.54 DM2.55 DM2.60 DM2.61 DM2.65 DM2.66 DM2.71 DM2.72 DM2.127 DM2.128 DM2.133 DM2.134 DM2.138 DM2.139 DM2.144 DM2.145 DM2.150 DM2.151 DM2.155 DM2.156 DM2.161 DM2.162 DM2.167 DM2.168 DM2.172 DM2.173 DM2.178 DM2.179 DM2.184 DM2.185 DM2.189 DM2.190 DM2.195 DM2.196 DM2.201 DM2.205 DM2.206 EC2501.2 EC2502.2 EC2503.2 EC2601.2 EC2602.2 EC2701.2 EC2703.2 EC2704.2 EC2705.2 EC2706.2 EC2707.2 EC2708.2 EC2709.2 EC2901.2 EC2902.2 EC2903.2 EC2904.2 EC3101.1 EC3102.1 EC3103.1 EC3104.1 EC3105.1 EC3106.1 EC3107.1 EC3108.1 EC3201.2 EC3301.2 EC3302.2 EC3303.2 EC3304.2 EC3305.2 EC3306.2 EC3307.2 EC4203.2 EC4301.2 EC4302.2 EC4303.2 EC4304.2 EC4305.1 EC4401.2 EC4402.2 EC4601.2 EC5205.2 EC5206.2 EC5210.2 EC5801.2 EC5802.2 EC6101.2 EC6103.2 EC6105.2 EC6106.2 EC6107.2 EC6205.2 EC6206.2 EC6207.2 EC6208.2 EC9701.2 EC9703.2 EC9704.2 EC9705.2 EC9707.2 EC9708.2 EC9709.2 EC9710.2 EC9711.2 EC9712.2 EC9713.2 EC9714.2 EC9715.2 EC9716.2 EC9717.2 EC9718.2 EC9719.2 EC9720.2 EC9721.2 EC9722.2 EC9723.2 EC9724.2 EC9725.2 EC9726.2 EC9727.2 EC9728.2 EC9732.2 EC9733.2 EC9734.2 EC9735.2 EC9736.2 EC9737.2 EC9738.2 EC9739.2 EC9740.2 EC9741.2 EC9742.2 EC9743.2 EC9744.2 EC9745.2 EC9746.2 EC9747.2 EC9748.2 EC9749.2 EC9750.2 EC9751.2 EC9752.2 EC9753.2 EC9754.2 EC9755.2 EC9756.2 EC9757.2 EC9758.2 EC9759.2 EC9760.2 EC9761.2 EC9762.2 ED2401.2 ED2402.2 ED2403.2 ED6101.2 EL4203.1 EU3403.2 EU3404.2 EU5602.3 EU5602.8 FAN1.2 FAN1.4 FAN1.5 FAN261.5 FAN261.6 FAN261.7 FAN261.8 G701.2 G6101.1 G6102.1 H1.1 H2.1 H3.1 H4.1 H5.1 H7.1 HDA27.4 HDA27.49 HDD1.6 HDD1.9 HDD1.12 HDD1.13 HDD1.14 HDLED1.2K HDMI1.5 HDMI1.6 HDMI1.7 HDMI1.8 HDMI1.10 HDMI1.HP2 HDMI1.HP5 HDMI1.HP8 HDMI1.HP11 HDMI1.HP17 HDMI1.PTH1 HDMI1.PTH2 HDMI1.PTH3 HDMI1.PTH4 HDMI1.PTH5 HDMI1.PTH6 HDMI1.PTH7 HDMI1.PTH8 HDMI1.PTH9 HDMI1.PTH10 HDMI1.PTH11 HDMI1.PTH12 HDT1.3 HDT1.5 HDT1.7 HDT1.17 KB1.1 KB1.31 KB1.32 KBC24.5 KBC24.12 KBC24.18 KBC24.45 KBC24.78 KBC24.89 KBC24.116 KBLIT1.5 KBLIT1.6 LCD1.13 LCD1.16 LCD1.19 LCD1.23 LCD1.24 LCD1.25 LCD1.29 LCD1.36 LCD1.41 LCD1.42 LED1.3 LOM30.33 ODD1.1 ODD1.4 ODD1.7 ODD1.18 ODD1.19 ODD1.20 ODD1.21 ODD1.22 PC4202.2 PC4203.2 PC4204.2 PC4205.2 PC4206.2 PC4209.2 PC4401.2 PC4406.2 PC4407.2 PC4408.2 PC4409.2 PC4415.2 PC4416.2 PC4417.2 PC4418.2 PC4419.2 PC4425.2 PC4426.2 PC4503.2 PC4504.2 PC4507.2 PC4508.2 PC4514.2 PC4516.2 PC4523.2 PC4524.2 PC4525.2 PC4528.2 PC4529.2 PC4530.2 PC4602.2 PC4604.2 PC4606.2 PC4607.1 PC4608.2 PC4609.2 PC4614.1 PC4616.1 PC4619.1 PC4622.2 PC4660.1 PC4713.2 PC4715.2 PC4716.2 PC4717.2 PC4718.2 PC4719.2 PC4720.2 PC4721.2 PC4722.2 PC4742.2 PC4743.2 PC4827.2 PC4828.2 PC4829.2 PC4830.2 PC4831.2 PC4834.2 PC4838.2 PC4901.2 PC4902.2 PC4903.2 PC4904.2 PC4906.2 PC4909.2 PC4911.2 PC4912.2 PC4913.1 PC4914.2 PC4915.2 PC4916.2 PC4917.2 PC4918.2 PC4920.2 PC4921.2 PC4922.2 PC4923.2 PC4924.2 PC4925.2 PC4926.2 PC5005.2 PC5010.2 PC5011.2 PC5012.2 PC5013.2 PC5015.2 PD4201.A PD4203.1 PD4204.3 PD4302.A PG4411.2 PQ4202.E PQ4203.1 PQ4203.4 PQ4204.E PQ4206.1 PQ4206.4 PQ4208.S PQ4402.1 PQ4402.4 PQ4408.1 PQ4408.4 PQ4410.1 PQ4410.4 PR4202.2 PR4208.2 PR4213.2 PR4216.2 PR4218.2 PR4405.2 PR4432.2 PR4433.2 PR4436.2 PR4464.2 PR4467.2 PR4470.1 PR4507.2 PR4511.2 PR4518.2 PR4523.2 PR4531.1 PR4604.1 PR4605.1 PR4606.1 PR4611.1 PR4618.1 PR4619.1 PR4625.2 PR4635.2 PR4636.2 PR4638.2 PR4646.2 PR4648.2 PR4817.1 PR4823.2 PR4824.2 PR4902.2 PR4906.2 PR4908.2 PR5013.2 PR5020.2 PT4701.2 PT4702.2 PT4703.2 PT4704.2 PT4705.2 PT4706.2 PT4803.2 PU4404.14 PU4406.1 PU4406.2 PU4406.3 PU4506.1 PU4506.2 PU4506.3 PU4507.1 PU4507.2 PU4507.3 PU4509.21 PU4601.32 PU4601.53 PU4702.1 PU4702.2 PU4702.3 PU4704.1 PU4704.2 PU4704.3 PU4706.1 PU4706.2 PU4706.3 PU4708.1 PU4708.2 PU4708.3 PU4805.1 PU4805.2 PU4805.3 PU4806.11 PU4901.4 PU4901.7 PU4901.10 PU4901.21 PU4903.1 PU4903.2 PU4903.3 PU5002.11 PWR1.4 PWR1.5 PWR1.6 Q601.1 Q601.4 Q603.1 Q603.4 Q701.S Q2401.S Q2403.S Q2404.C Q2505.S Q3001.S Q5403.S Q6203.S Q6205.S R401.2 R402.2 R405.2 R406.2 R407.2 R408.2 R410.2 R411.2 R412.1 R413.2 R415.2 R416.2 R419.2 R423.2 R425.2 R620.2 R621.2 R629.2 R632.2 R633.2 R640.1 R641.2 R643.2 R644.2 R645.1 R646.1 R647.1 R651.2 R702.2 R1902.1 R1903.1 R1909.2 R1912.2 R1914.2 R1916.2 R1917.2 R1919.2 R1926.2 R1928.2 R2435.2 R2437.2 R2442.2 R2445.2 R2447.1 R2504.2 R2605.1 R2612.2 R2706.2 R2717.2 R3015.2 R3023.2 R3032.1 R3203.2 R3501.2 R3602.2 R3626.2 R5201.2 R5202.1 R5209.2 R5410.2 R5412.2 R5413.2 R5418.1 R5523.1 R5524.1 R5525.1 R5604.2 R6207.2 R6208.2 R6301.1 R6302.1 R6305.2 RJ45.9 RJ45.10 RN5203.1(A) RN5203.2(A) RN5203.3(A) RN6502.6(B) RN6502.7(B) RN6502.8(B) RTC1.2 SPI25.4 SPK1.5 SPK1.6 SPR1.1 SPR2.1 SPR3.1 SPR4.1 SSKT2.4 TC3501.2 TC4501.2 TC4503.2 THM26.5 TPAD1.5 TPAD1.9 TPAD1.10 U402.2 U701.1 U3101.3 U3101.8 U3102.3 U3102.8 U3201.25 U3402.3 U3402.8 U3503.2 U3504.2 U3601.11 U3601.15 U3602.2 U3603.11 U3603.15 U5201.2 U5601.1 U5601.9 U5603.7 U5603.10 U5603.13 USB1.4 USB1.7 USB1.10 USB1.11 USB1.12 USB1.13 WLAN1.1 WLAN1.7 WLAN1.18 WLAN1.33 WLAN1.39 WLAN1.45 WLAN1.51 WLAN1.57 WLAN1.63 WLAN1.69 WLAN1.75 X601.2 X601.3 X1902.2 X1902.4
GND_R1: CN6301.9 R6301.2
GND_R2: CN6301.15 R6302.2
V3D3_STB: HDA27.20 R2712.1
V18: C3201.2 U3201.24
VBAT: C2404.1 C2405.1 KBC24.102 R2402.2 R2404.1 R2405.1 R2446.1 R2449.1 R2451.1
VDD10: C3012.1 C3018.1 C3019.1 C3021.1 C3022.1 C3023.1 C3024.1 C3025.1 L3001.2 LOM30.3 LOM30.8 LOM30.22 LOM30.30 R3001.2
VDD_095_FB_H: CPU1.AV33 TP422.1
VDD_095_FB_L: CPU1.AU33 TP423.1
VDDIO_MEM_SENSE: CPU1.E25 R417.2
VDDREG: C3009.1 C3010.1 LOM30.23 R3006.1
0D95_S5_EN: KBC24.79 PR4819.1 R2437.1
0D95V_GFX_S0: C703.1 C704.1 C762.1 CPU1.AA10 CPU1.U10 CPU1.W10 R703.1
0D95V_PWR: PC4834.1 PG4824.2 PG4825.2 PG4826.2 PG4828.2 PG4830.2 PG4831.2 PG4832.2 PL4802.2 PT4803.1
0D95V_PWRGD: C3625.1 D3603.1 PR3622.2 R3604.1 R3605.1
0D95V_S0: C1039.1 C1040.1 C1041.1 C1042.1 C1043.1 C1044.1 C1045.1 C1046.1 C1047.1 C3620.2 CPU1.AG23 CPU1.AG27 CPU1.AJ21 CPU1.AJ27 CPU1.AL21 CPU1.AL23 CPU1.AL27 CPU1.AM23 CPU1.AM25 R301.1 R302.1 R703.2 R1904.1 U3603.13 U3603.14
0D95V_S0_EN: C3626.1 R3624.2 U3603.3
0D95V_S5: C1012.1 C1013.1 C1014.1 C1015.1 C1016.1 C1092.2 C1093.1 C1094.1 C1095.1 C1096.1 C3613.1 CPU1.AE11 CPU1.AE13 CPU1.AJ11 CPU1.AJ13 CPU1.AR5 CPU1.AU4 CPU1.AV7 CPU1.AW5 PG4824.1 PG4825.1 PG4826.1 PG4828.1 PG4830.1 PG4831.1 R1910.2 U3603.1 U3603.2
0D95V_S5_PWRGD: KBC24.106 PR4821.2
0D675V_S0: C1208.1 C1209.1 C1210.1 C1211.1 C1212.1 C1331.1 C1338.1 C1339.1 C1340.1 C1341.1 DM1.203 DM1.204 DM2.203 DM2.204 PG4901.1 PG4902.1
1D5V_S0: C1034.1 C1035.1 C1036.1 C1037.1 C1038.1 C2719.1 C3607.1 CPU1.AL10 CPU1.AL11 HDA27.9 R2705.1 U3602.5
1D5V_S0_EN: R3625.2 R3626.1 U3602.3
1D8V_PWR: PC5010.1 PC5012.1 PC5014.1 PG5010.1 PG5011.1 PG5012.1 PG5013.1 PL5002.2 PR5009.1
1D8V_S0: C443.2 C1025.1 C1026.1 C1027.1 C1028.1 C1029.1 C1030.1 C1031.1 C1032.1 C1033.1 C3621.2 CPU1.A2 CPU1.A3 CPU1.B3 CPU1.C3 HDT1.1 HDT1.19 PC4604.1 PR4608.2 PR4628.1 PR4634.1 PR4645.1 PU4601.6 R403.1 R420.2 R421.1 R422.2 R424.2 R434.1 RN404.5(B) RN404.6(B) RN404.7(B) RN404.8(B) RN407.2(A) RN407.3(A) RN407.4(A) RN408.1(A) RN408.2(A) U402.5 U3603.8 U3603.9
1D8V_S5: C1003.1 C1004.1 C1005.1 C1006.1 C1007.1 C1008.1 C1009.1 C1010.1 C1011.1 C3617.1 CPU1.B1 CPU1.B2 PG5010.2 PG5011.2 PG5012.2 PG5013.2 R627.2 R649.1 U3603.6 U3603.7
1D8V_S5_PWRGD: PR5011.2 PU5002.4
1D35V_PGOOD: PR4904.2 PU4901.20
1D35V_PWR: EC4601.1 PC4904.1 PC4920.1 PC4921.1 PC4923.1 PC4924.1 PC4925.1 PC4926.1 PG4907.2 PG4908.2 PG4909.2 PG4910.2 PG4911.2 PG4913.2 PG4914.2 PG4915.2 PG4916.2 PG4917.2 PG4918.2 PG4919.2 PL4902.2 PU4901.2
1D35V_S3: C1049.1 C1050.1 C1051.2 C1053.1 C1054.1 C1055.1 C1056.2 C1057.2 C1058.2 C1059.2 C1060.1 C1061.2 C1062.2 C1063.2 C1213.1 C1214.1 C1215.1 C1216.1 C1217.1 C1218.1 C1219.1 C1220.1 C1222.1 C1223.1 C1224.1 C1225.1 C1326.1 C1327.1 C1328.1 C1329.1 C1330.1 C1332.1 C1335.1 C1337.1 C1342.1 C1343.1 C1344.1 C1346.1 CPU1.AA31 CPU1.AA35 CPU1.AC32 CPU1.AC37 CPU1.AE31 CPU1.AE35 CPU1.AG32 CPU1.AG37 CPU1.AJ35 CPU1.AL32 CPU1.AL37 CPU1.AR35 CPU1.J35 CPU1.L32 CPU1.L37 CPU1.N35 CPU1.R31 CPU1.R37 CPU1.U32 CPU1.U35 CPU1.W31 CPU1.W32 CPU1.W37 DM1.75 DM1.76 DM1.81 DM1.82 DM1.87 DM1.88 DM1.93 DM1.94 DM1.99 DM1.100 DM1.105 DM1.106 DM1.111 DM1.112 DM1.117 DM1.118 DM1.123 DM1.124 DM2.75 DM2.76 DM2.81 DM2.82 DM2.87 DM2.88 DM2.93 DM2.94 DM2.99 DM2.100 DM2.105 DM2.106 DM2.111 DM2.112 DM2.117 DM2.118 DM2.123 DM2.124 EC9746.1 EC9750.1 EC9751.1 EC9752.1 EC9753.1 EC9754.1 EC9755.1 EC9756.1 EC9757.1 EC9758.1 PG4908.1 PG4909.1 PG4910.1 PG4911.1 PG4913.1 PG4914.1 PG4915.1 PG4916.1 PG4917.1 PG4918.1 PG4919.1 R503.1 R504.1
3D3V_AUX_KBC: D4301.2 D4302.2 D4303.2 PR4412.1 PR4415.1 PR4439.1 Q2402.D R2402.1 R2403.2 R2413.2 R2414.2 R2418.2 R2426.2 R2434.1 R2436.1 R2453.2 R2622.1 RN401.3(B) RN401.4(B) RN2401.1(A) RN2401.2(A)
3D3V_AUX_KBC_VCC: C2406.1 C2407.1 C2408.1 C2409.1 C2410.1 C2411.1 KBC24.19 KBC24.46 KBC24.76 KBC24.88 KBC24.115 R2403.1
3D3V_AUX_S5: C2417.2 D2501.1 KBC24.75 PR4417.1 PR4419.1 PR4434.1 PR4435.1 PR4438.2 PR4526.2 PR4530.1 Q2402.S R2425.2 R2431.2 R2434.2 R2439.1 R2611.1 RN602.3(B) RN602.4(B)
3D3V_CAMERA_S0: AFTP5227.1 C5207.1 EC5210.1 LCD1.32 R5229.2
3D3V_CARD_S0: AFTP3310.1 C3202.1 C3204.1 C3301.1 C3302.1 C3303.1 CARD1.4 U3201.5
3D3V_LAN_S5: C3003.1 C3004.1 C3005.1 C3007.1 C3008.1 C3017.1 LOM30.11 LOM30.32 Q3004.D R3006.2 RN3001.1(A) RN3001.2(A)
3D3V_PWR: PC4508.1 PG4513.1 PG4522.1 PG4523.1 PG4525.1 PG4526.1 PG4530.1 PG4537.1 PL4504.1 TC4501.1
3D3V_PWR_2: PG4538.1 PR4526.1
3D3V_PWR_2_R: PC4528.1 PG4538.2 PU4509.3
3D3V_S0: C1022.1 C1023.1 C1024.1 C1201.1 C1202.1 C1306.1 C1334.1 C2412.1 C2413.1 C2601.1 C2602.1 C2716.1 C2717.1 C3203.1 C3205.1 C3603.1 C3612.1 C5204.1 C5801.1 C5802.1 C5805.1 CPU1.AM15 CPU1.AM17 DB1.10 DM1.199 DM2.199 EC9735.1 EC9736.1 EC9737.1 EC9738.1 EC9759.1 EC9760.1 EC9761.1 EC9762.1 HDA27.1 KBC24.4 PR3622.1 PR4614.1 PR4615.1 Q403.2 Q403.5 Q2601.2 Q2601.5 Q5401.C Q5402.2 Q5402.5 Q5502.2 Q5502.5 Q6105.G Q6202.2 Q6202.5 R426.1 R429.2 R601.2 R603.2 R604.2 R635.2 R638.1 R639.2 R642.1 R1301.2 R1931.1 R2401.2 R2412.2 R2415.2 R2441.2 R2443.2 R2603.1 R2604.1 R2624.1 R2701.1 R3003.1 R3004.1 R3014.1 R3624.1 R3625.1 R5208.1 R5229.1 R5231.1 R5809.1 R5812.2 R6110.1 R6209.1 R6217.1 RN402.3(B) RN402.4(B) RN405.1(A) RN405.2(A) RN405.3(A) RN405.4(A) RN601.1(A) RN601.2(A) RN2602.1(A) RN2602.2(A) RN5509.3(B) RN5509.4(B) RN5601.1(A) RN5601.2(A) RN6201.3(B) RN6201.4(B) THM26.1 U3201.4 U3601.8 U3601.9 U3602.1 U5201.4 U5201.5
3D3V_S5: AFTP6103.1 C1001.1 C1002.1 C2501.1 C2502.1 C3013.1 C3015.1 CPU1.AL13 CPU1.AM13 PD4203.2 PG4513.2 PG4522.2 PG4523.2 PG4525.2 PG4526.2 PG4530.2 PG5009.1 PG5014.1 PR4204.1 PR4211.2 PR4473.2 PR4510.1 PR4835.1 PR4904.1 PR5011.1 PWR1.1 Q3004.S R608.2 R617.2 R626.2 R630.2 R631.2 R634.2 R637.2 R648.1 R650.2 R1911.1 R1913.1 R1915.1 R1918.2 R1920.1 R1927.2 R1929.2 R2421.2 R2429.2 R2452.2 R2501.2 R2712.2 R3021.1 R3033.2 R5610.2 R5810.1 R6215.1 RN603.3(B) RN603.4(B) RN1904.3(B) RN1904.4(B) RN2501.3(B) RN2501.4(B) SPI25.8 SSKT2.8 U3601.6 U3601.7
3D3V_WLAN_S0: AFTP5801.1 C5803.1 C5804.1 C5806.1 R5809.2 R5810.2 WLAN1.2 WLAN1.4 WLAN1.72 WLAN1.74
3D_VEDIO: CPU1.E21 R403.2 R426.2
32K_X1: C603.1 CPU1.AJ2 R623.1 X601.4
32K_X2: C604.1 CPU1.AJ1 R623.2 X601.1
48M_X1: C1904.2 CPU1.N2 R1905.1 X1902.3
48M_X2: CPU1.N1 R1905.2 R1930.2
51123_PGOOD_2: Q601.5 Q601.6 RN602.1(A)
+0D675V_DDR_P: PC4915.1 PC4916.1 PC4917.1 PG4901.2 PG4902.2 PU4901.1 PU4901.3
+DC_IN: AFTP3801.1 AFTP3805.1 EL4201.2 EL4202.2 PC4201.1 PC4202.1 PD4201.K PQ4205.E PR4207.1 PR4212.1 PR4214.1 PU4201.1 PU4201.2 PU4201.3
+DC_IN_C: DCIN1.1 DCIN1.2 EC4201.1 EC4202.1 EL4201.1 EL4202.1
+PWR_SRC_1D35V: PC4909.1 PC4911.1 PC4912.1 PC4913.2 PC4914.1 PG4903.1 PG4904.1 PG4905.1 PG4906.1 PU4902.5 PU4902.6 PU4902.7 PU4902.8
+RTC_VCC: AFTP2502.1 R2502.2 RTC1.1
AC_IN#: PC4401.1 PQ4408.5 PR4425.2 PR4433.1 PR4434.2 PU4404.5 R2413.1 R2430.1
AC_IN#_G: PQ4206.2 PR4212.2 PR4213.1
AC_IN_KBC#: KBC24.65 PQ4206.6 R2426.1
AC_PRESENT: CPU1.AP15 KBC24.84 R617.1
AD+: PC4203.1 PC4204.1 PC4205.1 PC4206.1 PR4404.1 PR4405.1 PR4407.1 PR4408.1 PR4469.1 PU4201.5 PU4201.6 PU4201.7 PU4201.8 PU4402.5 PU4402.6 PU4402.7 PU4402.8 PU4403.4
AD+_G_1: PQ4402.5 PQ4402.6 PR4401.1
AD+_G_2: PR4401.2 PR4403.2 PU4402.4
AD+_TO_SYS: PG4402.1 PR4402.1 PR4403.1 PU4402.1 PU4402.2 PU4402.3
AD_IA: C2414.2 KBC24.97 PR4422.2
AD_IA_HW: KBC24.105 PQ4407.5
AD_IA_HW2: KBC24.25 PQ4407.2
AD_OFF_L: PQ4204.C PQ4205.B
AD_OFF_R: PC4201.2 PC4208.1 PQ4205.C PR4207.2 PR4208.1 PU4201.4
ALERT#: R2603.2 THM26.6
ALL_SYS_PWRGD: ED2402.1 KBC24.10 R3604.2
AMBER_LED_BAT: Q6104.C R6103.2
AMP_MUTE#: KBC24.30 R2708.1
APU_ALERT#: CPU1.B18 RN405.8(B)
APU_DBRDY: CPU1.B25 HDT1.14
APU_DBREQ#: CPU1.A25 HDT1.16 R434.2
APU_DIGON: CPU1.A17 R404.1
APU_LPC_AD0: CPU1.AT2 RN1901.5(B)
APU_LPC_AD1: CPU1.AT1 RN1901.6(B)
APU_LPC_AD2: CPU1.AR2 RN1901.7(B)
APU_LPC_AD3: CPU1.AR1 RN1901.8(B)
APU_PWROK: CPU1.B19 R414.2 R418.2 U402.3
APU_PWROK_C: C402.1 R414.1
APU_PWROK_HDT: HDT1.10 RN408.3(B) U402.4
APU_RST#: CPU1.B20 R409.2 R421.2 U402.1
APU_RST#_C: C401.1 R409.1
APU_RST_L_BUF: HDT1.12 RN408.4(B) U402.6
APU_SIC: CPU1.B22 Q403.1 RN405.7(B) RN2601.1(A)
APU_SID: CPU1.B21 Q403.4 RN405.6(B) RN2601.2(A)
APU_SPI_CLK: CPU1.AU7 R1925.1
APU_SPI_CS0#: CPU1.AW9 R1908.1
APU_SPI_HOLD#: CPU1.AU11 R1923.1
APU_SPI_SI_R: CPU1.AR11 R1921.1
APU_SPI_SO_R: CPU1.AR7 R1922.1
APU_SPI_WP#: CPU1.AU9 R1924.1
APU_SVC: CPU1.D27 PR4638.1 PR4645.2 PR4653.1 RN407.7(B)
APU_SVD: CPU1.E29 PR4634.2 PR4648.1 PR4652.1 RN407.6(B)
APU_SVT: CPU1.G31 PR4628.2 PR4651.1 RN407.5(B)
APU_TCK: CPU1.D35 HDT1.2 RN404.3(A)
APU_TDI: CPU1.D29 HDT1.6 RN404.4(A)
APU_TDO: CPU1.D31 HDT1.8
APU_TEST0: CPU1.AU13 R647.2
APU_TEST1: CPU1.AY10 R646.2
APU_TEST2: CPU1.AY6 R645.2
APU_TEST6_DIRECRACKMON: CPU1.D25 TP403.1
APU_TEST14_BP0: CPU1.A27 R410.1
APU_TEST15_BP1: CPU1.B27 TP404.1
APU_TEST16_BP2: CPU1.A26 R411.1
APU_TEST17_BP3: CPU1.B26 R413.1
APU_TEST18_PLLTEST1: CPU1.B28 HDT1.20 R415.1
APU_TEST19_PLLTEST0: CPU1.A28 HDT1.18 R416.1
APU_TEST28_H_PLLCHRZ: CPU1.AV35 TP410.1
APU_TEST28_L_PLLCHRZ: CPU1.AU35 TP411.1
APU_TEST31_M_TEST: CPU1.E33 TP409.1
APU_TEST36_FREE_2: CPU1.H21 R422.1 R423.1
APU_TEST37_FREE_2: CPU1.H25 R424.1 R425.1
APU_THERMDA: CPU1.H27 TP401.1
APU_THERMDC: CPU1.H29 TP402.1
APU_TMS: CPU1.D33 HDT1.4 RN404.2(A)
APU_TRST#: CPU1.G27 HDT1.9 RN404.1(A)
APU_VDD: C1017.1 C1077.1 C1080.1 C1081.1 C1082.1 C1083.1 C1084.1 C1085.1 C1086.1 C1087.1 C1088.1 C1089.1 C1090.1 C1097.1 C1098.1 C1099.1 C1100.1 C1101.1 CPU1.AA21 CPU1.AA23 CPU1.AA27 CPU1.AC21 CPU1.AC23 CPU1.AC27 CPU1.AE21 CPU1.AE23 CPU1.AE27 CPU1.L21 CPU1.L23 CPU1.L25 CPU1.L27 CPU1.L29 CPU1.N21 CPU1.N23 CPU1.N27 CPU1.R21 CPU1.R23 CPU1.R27 CPU1.U21 CPU1.U23 CPU1.U27 CPU1.W21 CPU1.W23 CPU1.W27 PG4702.2 PL4701.2 PR4602.1 PT4701.1 PT4702.1
APU_VDD_RUN_FB_H: CPU1.G23 PR4601.1 PR4602.2 TP434.1
APU_VDD_RUN_FB_L: CPU1.E23 PC4605.2 PR4603.1 PR4604.2
APU_VDDNB: C1064.1 C1065.1 C1066.1 C1067.1 C1068.1 C1069.1 C1070.1 C1071.1 C1072.1 C1073.1 C1074.1 C1075.1 C1105.1 C1106.1 C1107.1 C1113.1 C1114.1 C1115.1 CPU1.AA13 CPU1.AA17 CPU1.AC13 CPU1.AC17 CPU1.AE15 CPU1.AE17 CPU1.AE19 CPU1.AG17 CPU1.AG21 CPU1.L13 CPU1.L17 CPU1.N11 CPU1.N13 CPU1.N17 CPU1.R11 CPU1.R13 CPU1.R17 CPU1.U13 CPU1.U17 CPU1.W13 CPU1.W17 PG4719.2 PL4702.2 PR4620.1 PT4703.1 PT4704.1
APU_VDDNB_RUN_FB_H: CPU1.D23 PR4620.2 PR4621.1 TP433.1
AUD_AGND: AFTP6313.1 C2701.2 C2702.1 C2705.1 C2710.2 C2711.2 C2712.1 C2713.2 C2715.2 C2901.2 CN6301.16 CN6301.24 EC2703.1 EC2704.1 EC2705.1 EC2706.1 EC2707.1 EC2905.2 EC2906.2 EC2907.2 EC2908.2 EC9739.1 EC9743.1 EC9744.1 EC9745.1 HDA27.25 HDA27.38 R2706.1 R2707.2 R2711.1 R2919.2 R2920.2 R6305.1
AUD_HP1_JACK_L: HDA27.32 R2908.1
AUD_HP1_JACK_L1: EC2907.1 R2907.2 R2908.2 R2912.2 R2919.1 R2922.2
AUD_HP1_JACK_R: HDA27.33 R2910.1
AUD_HP1_JACK_R1: EC2908.1 R2909.2 R2910.2 R2913.2 R2920.1 R2921.2
AUD_PC_BEEP: C2720.2 HDA27.12
AUD_PC_BEEP_C: C2720.1 D2701.3 R2717.1
AUD_PORTA_L_R_B: AFTP6306.1 CN6301.17 R2907.1
AUD_PORTA_R_R_B: AFTP6309.1 CN6301.18 R2909.1
AUD_SENSE: C2901.1 R2709.2 R2923.1
AUD_SENSE_A: HDA27.13 R2709.1 R2722.2
AUD_SPK_L+: EC2902.1 HDA27.42 R2902.2
AUD_SPK_L+_C: AFTP2902.1 R2902.1 SPK1.3
AUD_SPK_L-: EC2901.1 HDA27.43 R2901.2
AUD_SPK_L-_C: AFTP2901.1 R2901.1 SPK1.4
AUD_SPK_R+: EC2904.1 HDA27.45 R2904.2
AUD_SPK_R+_C: AFTP2904.1 R2904.1 SPK1.1
AUD_SPK_R-: EC2903.1 HDA27.44 R2903.2
AUD_SPK_R-_C: AFTP2903.1 R2903.1 SPK1.2
AUD_VREF: C2705.2 HDA27.28
BAT_ALERT: AFTP3901.1 BATT1.7
BAT_AMBER: EC6105.1 LED1.1 R6103.1
BAT_IN#: D4302.3 EC4305.2 KBC24.80 PC4210.2 PQ4203.2 PR4215.2 PR4216.1 R2414.1 RN4301.1(A)
BAT_SCL: D4301.3 EC4301.1 KBC24.70 PG4407.2 PR4415.2 RN2401.3(B) RN4301.3(A)
BAT_SDA: D4303.3 EC4302.1 KBC24.69 PG4408.2 PR4412.2 RN2401.4(B) RN4301.2(A)
BAT_WHITE: EC6103.1 LED1.2 R6101.1
BATT_WHITE_LED#: KBC24.32 R6105.2
BATT_WHITE_LED_R#: Q6103.B Q6107.D R6105.1
BKLT_CTRL: D5202.K R5222.1 RN5201.7(B) RN5203.8(B)
BLINK: CPU1.AU17 R1928.1 R1929.1
BLON_OUT: KBC24.27 RN5201.6(B)
BLON_OUT_C: AFTP5205.1 LCD1.21 RN5201.3(A) RN5203.7(B)
BLUETOOTH_EN: CPU1.AP27 R635.1 R5804.1
BLUETOOTH_EN_NGFF: AFTP5804.1 R5804.2 WLAN1.54
BOOST_MODE#: KBC24.20 PR4418.1 PR4435.2 PR4439.2
BT+: AFTP3905.1 AFTP3907.1 AFTP3908.1 BATT1.1 BATT1.2 EC4303.1 EC4304.1 PC4415.1 PC4416.1 PC4417.1 PC4418.1 PC4419.1 PD4302.K PG4410.2 PR4416.2 PU4403.5 PU4403.6 PU4403.7 PU4403.8
BT+_R: PG4409.2 PL4401.2 PR4416.1
BYPASSCLK_H: CPU1.B24 R419.1
BYPASSCLK_L: CPU1.A24 R420.1
CAP_LED: KB1.4 R6201.2
CAP_LED#: KBC24.109 R6202.1
CAP_LED_Q: Q6201.C R6201.1
CAP_LED_R#: Q6201.B R6202.2
CARD_WLAN_OUT#: KBC24.83 KBC24.100 TP2401.1 TP2402.1
CBN: C2703.1 HDA27.35
CBP: C2703.2 HDA27.37
CHARGER_SRC: EC4401.1 EC4402.1 PC4406.1 PC4408.1 PC4409.1 PC4426.1 PG4412.2 PG4413.2 PG4414.2 PG4415.2 PU4405.5 PU4405.6 PU4405.7 PU4405.8
CHG_AGND: PC4010.2 PC4403.2 PC4404.2 PC4412.2 PC4420.2 PC4422.2 PC4423.2 PG4411.1 PQ4407.1 PQ4407.4 PR4413.2 PR4423.2 PR4424.2 PR4431.2 PU4404.21
CHG_AMBER_LED#: KBC24.16 R6104.2
CHG_AMBER_LED_R#: Q6104.B R6104.1
CLK_LAN_REQ0#_R: LOM30.12 Q3002.E R3004.2 R3005.2
CLK_LAN_REQ#_EN: Q3002.B R3003.2
CLK_MINI1#_R: CPU1.AE5 RN1903.4(B)
CLK_MINI1_R: CPU1.AE4 RN1903.3(B)
CLK_PCI_KBC: KBC24.2 R1906.1
CLK_PCI_LPC: DB1.2 R1907.2
CLK_PCIE_LAN_N0: LOM30.16 RN1902.1(A)
CLK_PCIE_LAN_N0_R: CPU1.AC10 RN1902.4(B)
CLK_PCIE_LAN_P0: LOM30.15 RN1902.2(A)
CLK_PCIE_LAN_P0_R: CPU1.AC8 RN1902.3(B)
CLK_PCIE_LAN_REQ0#: CPU1.AU29 Q3002.C R3005.1
CLK_PCIE_WLAN_N1: EC5801.1 RN1903.1(A) WLAN1.49
CLK_PCIE_WLAN_P1: EC5802.1 RN1903.2(A) WLAN1.47
CLK_PCIE_WLAN_REQ1#: CPU1.AW29 R5803.2 R5812.1
CLK_PCIE_WLAN_REQ#: AFTP5802.1 R5803.1 WLAN1.53
CODEC_BITCLK_R: HDA27.6 R2720.2
CODEC_SDOUT_R: HDA27.5 R2719.2
COMBO-GPI: HDA27.48 TP2702.1
COMPNB_R: PC4611.2 PR4624.2
CPVEE: C2704.2 HDA27.34
CR_GPIO0: TP3201.1 U3201.17
CRT_B: C5543.1 HDMI1.3 L5508.2
CRT_DDCCLK_CON: C5511.1 HDMI1.15 R5527.2
CRT_DDCCLK_CON_R: Q5502.6 R5527.1 RN5508.4(B)
CRT_DDCDATA_CON: C5508.1 HDMI1.12 R5526.2
CRT_DDCDATA_CON_R: Q5502.3 R5526.1 RN5508.3(B)
CRT_G: C5542.1 HDMI1.2 L5509.2
CRT_HSYNC1_1: RN5507.2(A) U5603.8
CRT_HSYNC_CON: C5509.1 HDMI1.13 RN5506.4(B) RN5507.3(B)
CRT_R: C5541.1 HDMI1.1 L5507.2
CRT_VSYNC1_1: RN5507.1(A) U5603.11
CRT_VSYNC_CON: C5510.1 HDMI1.14 RN5506.3(B) RN5507.4(B)
DAC_BLUE: C5540.1 CPU1.B15 L5508.1 R408.1 R5523.2
DAC_GREEN: C5539.1 CPU1.A14 L5509.1 R406.1 R5524.2
DAC_HSYNC: CPU1.G19 R429.1 RN5506.1(A) U5603.9
DAC_RED: C5506.1 CPU1.B14 L5507.1 R405.1 R5525.2
DAC_SCL: CPU1.D19 Q5502.1 RN5509.2(A)
DAC_SDA: CPU1.D21 Q5502.4 RN5509.1(A)
DAC_VSYNC: CPU1.E19 RN5506.2(A) U5603.12
DAC_ZVSS: CPU1.A16 R407.1
DBC_EN: CPU1.AY28 R601.1 R5449.2
DBC_EN_R: LCD1.8 R5449.1
DBRDY1: HDT1.15 RN6502.1(A)
DBRDY2: HDT1.13 RN6502.2(A)
DBRDY3: HDT1.11 RN6502.3(A)
DC_IN_D: PQ4402.3 PR4404.2
DCBATOUT: EC9701.1 EC9703.1 EC9704.1 EC9705.1 EC9707.1 EC9708.1 EC9709.1 EC9710.1 EC9711.1 EC9712.1 EC9713.1 EC9714.1 EC9715.1 EC9716.1 EC9717.1 EC9740.1 EC9741.1 EC9742.1 EC9747.1 EC9748.1 EC9749.1 F5201.1 PC4507.1 PC4524.1 PG4403.1 PG4412.1 PG4413.1 PG4414.1 PG4415.1 PG4502.2 PG4503.2 PG4504.2 PG4505.2 PG4515.2 PG4516.2 PG4517.2 PG4518.2 PG4519.2 PG4520.2 PG4521.2 PG4703.2 PG4704.2 PG4707.2 PG4708.2 PG4709.2 PG4710.2 PG4711.2 PG4712.2 PG4716.2 PG4717.2 PG4718.2 PG4827.2 PG4834.2 PG4837.2 PG4838.2 PG4903.2 PG4904.2 PG4905.2 PG4906.2 PR4402.2 PR4468.1 PR4612.1 PT4705.1 PT4706.1 PU4403.1 PU4403.2 PU4403.3 PU4509.12
DCBATOUT_LCD: AFTP5204.1 C5202.1 C5205.2 F5201.2 LCD1.1 LCD1.2
DDC_CLK_HDMI: HDMI1.HP15 Q5402.3 RN5401.2(A) RN5404.4(B)
DDC_CLK_PH1: D5401.2 RN5401.3(B)
DDC_DATA_HDMI: HDMI1.HP16 Q5402.6 RN5401.1(A) RN5404.3(B)
DDC_DATA_PH2: D5401.1 RN5401.4(B)
DDR3_DRAMRST#: C1221.1 C1333.1 CPU1.G38 DM1.30 DM2.30
DDR_VREF_S3: C501.1 C502.1 C1203.1 C1204.1 C1205.1 C1307.1 C1336.1 C1345.1 CPU1.AC38 CPU1.AD40 DM1.1 DM1.126 DM2.1 DM2.126 PR4911.2
DDR_VTT_PG_CTRL_R: PR4910.1 PU4901.17
DGPU_PRESENT#: CPU1.BA26 R642.2 R643.1
DIFFNB_R: PC4610.1 PR4623.2
DM2_SA0: DM2.197 R1301.1
DMIC_CLK: C2723.2 EC5206.1 R2716.1 RN5204.3(B)
DMIC_CLK_EDP: LCD1.27 RN5204.2(A)
DMIC_CLK_R: HDA27.3 R2716.2
DMIC_DATA: EC5205.1 R2714.1 RN5204.4(B)
DMIC_DATA_EDP: LCD1.28 RN5204.1(A)
DMIC_DATA_R: EC2701.1 HDA27.2 R2714.2
DP_2K_ZVSS: CPU1.A21 R402.1
DP_150_ZVSS: CPU1.B16 R401.1
E51_RX1: TP5802.1 WLAN1.46
E51_RX2: TP5803.1 WLAN1.58
E51_TX1: R5806.2 WLAN1.44
E51_TX2: TP5804.1 WLAN1.38
E51_TXD: KBC24.111 R5806.1
EAPD#: HDA27.47 R2708.2
EC_AGND: C2402.1 C2403.1 C2404.2 C2405.2 C2414.1 KBC24.103 R2406.2 R2407.2 R2435.1
EC_BRIGHTNESS: D5202.A KBC24.62
EC_SCI#: CPU1.AN5 R2408.1
EC_SMI#: CPU1.AL7 R2409.1
EC_SPI_CLK_C: KBC24.92 R2420.2
EC_SPI_CS#_C: KBC24.90 R2419.1
EC_SPI_DI_C: KBC24.87 R2422.1
EC_SPI_DO_C: KBC24.86 R2423.1
EC_SWI#: CPU1.BA9 R608.1 R2410.1
EC_VBKUP: KBC24.114 R2428.1
ECRST#: C2418.1 KBC24.85 Q2404.E R2418.1 R2424.2
ECSCI#_KBC: KBC24.29 R2408.2
ECSMI#_KBC: KBC24.6 R2409.2
ECSWI#_KBC: KBC24.123 R2410.2
EDP_AUX: AFTP5206.1 C5212.2 LCD1.11
EDP_AUX#: AFTP5208.1 C5209.2 LCD1.12
EDP_AUX_DN: C5209.1 CPU1.E15
EDP_AUX_DP: C5212.1 CPU1.D15
EDP_BKLT_CTRL: R5206.2 R5222.2
EDP_HPD: CPU1.H17 R5233.2 RN5203.6(B)
EDP_HPD_CONN: AFTP5201.1 LCD1.9 R5233.1
EDP_TX0: AFTP5210.1 C5210.2 LCD1.15
EDP_TX0#: AFTP5213.1 C5203.2 LCD1.14
EDP_TX0_DN: C5203.1 CPU1.B4
EDP_TX0_DP: C5210.1 CPU1.A4
EDP_TX1: AFTP5212.1 C5213.2 LCD1.18
EDP_TX1#: AFTP5211.1 C5211.2 LCD1.17
EDP_TX1_DN: C5211.1 CPU1.B5
EDP_TX1_DP: C5213.1 CPU1.A5
EDP_VDD_EN: D401.1 D5201.1 R404.2
FAN1_DAC_1: FAN261.4 KBC24.101
FAN_TACH1: EC2602.1 KBC24.31 R2415.1 R2606.1
FAN_TACH1_C: AFTP2802.1 FAN1.3 R2606.2
FAN_VCC1: AFTP2801.1 C2603.1 C2604.1 D2601.K EC2601.1 FAN1.1 FAN261.3
FON#: FAN261.1 R2605.2
GEVENT4#: CPU1.BA4 R620.1
GEVENT7#: CPU1.AR15 R621.1
GPIO71: CPU1.AM21 R632.1
H_A20GATE: CPU1.AR31 KBC24.121 R603.1
H_CPUPWRGD_REG: PR4607.1 PR4608.1 R418.1
H_PROCHOT#: C2421.1 CPU1.A22 PQ4203.3 PR4426.2 PR4466.2 PR4613.2 R2440.2 RN405.5(B)
H_PROCHOT#_EC: Q2401.D R2438.2 R2440.1
H_RCIN#: CPU1.AR23 KBC24.122 R2412.1
HDA_CODEC_BITCLK: EC2709.1 R616.2 R651.1 R2720.1
HDA_CODEC_BITCLK_R: CPU1.AN2 R616.1
HDA_CODEC_RST#: HDA27.11 R614.1
HDA_CODEC_RST#_R: CPU1.AL1 R614.2
HDA_CODEC_SDIN0: HDA27.8 R2718.2
HDA_CODEC_SDOUT: EC2708.1 R612.1 R2719.1
HDA_CODEC_SDOUT_R: CPU1.AN1 R612.2
HDA_CODEC_SYNC: HDA27.10 R613.1
HDA_CODEC_SYNC_R: CPU1.AM2 R613.2
HDA_SDIN0: CPU1.AK2 R633.1 R2718.1
HDA_SPKR: CPU1.BA27 R2721.1
HDA_SPKR_R: D2701.2 R2721.2
HDD_DEVSLP: CPU1.AV23 R5605.1
HDD_DEVSLP_R: HDD1.5 R5605.2
HDMI_CLK: C5403.1 CPU1.A12
HDMI_CLK#: C5402.1 CPU1.B12
HDMI_CLK#_R: C5402.2 R5401.1 RN5403.7(B)
HDMI_CLK#_R_C: HDMI1.HP12 R5401.2 R5414.1
HDMI_CLK_R: C5403.2 R5402.1 RN5403.8(B)
HDMI_CLK_R_C: HDMI1.HP10 R5402.2 R5414.2
HDMI_CRT_DET: CPU1.H19 R5419.1
HDMI_DATA0: C5405.1 CPU1.A11
HDMI_DATA0#: C5404.1 CPU1.B11
HDMI_DATA0#_R: C5404.2 R5403.1 RN5403.5(B)
HDMI_DATA0#_R_C: HDMI1.HP9 R5403.2 R5416.1
HDMI_DATA0_R: C5405.2 R5404.1 RN5403.6(B)
HDMI_DATA0_R_C: HDMI1.HP7 R5404.2 R5416.2
HDMI_DATA1: C5406.1 CPU1.A10
HDMI_DATA1#: C5409.1 CPU1.B10
HDMI_DATA1#_R: C5409.2 R5407.1 RN5402.5(B)
HDMI_DATA1#_R_C: HDMI1.HP6 R5407.2 R5417.1
HDMI_DATA1_R: C5406.2 R5408.1 RN5402.6(B)
HDMI_DATA1_R_C: HDMI1.HP4 R5408.2 R5417.2
HDMI_DATA2: C5408.1 CPU1.A9
HDMI_DATA2#: C5407.1 CPU1.B9
HDMI_DATA2#_R: C5407.2 R5405.1 RN5402.7(B)
HDMI_DATA2#_R_C: HDMI1.HP3 R5405.2 R5415.1
HDMI_DATA2_R: C5408.2 R5406.1 RN5402.8(B)
HDMI_DATA2_R_C: HDMI1.HP1 R5406.2 R5415.2
HDMI_HPD_B: Q5401.B R5411.2
HDMI_HPD_E: Q5401.E R5412.1 R5419.2
HDMI_PLL_GND: Q5403.D R5418.2 RN5402.1(A) RN5402.2(A) RN5402.3(A) RN5402.4(A) RN5403.1(A) RN5403.2(A) RN5403.3(A) RN5403.4(A)
HPD_HDMI_CON: HDMI1.HP19 R5410.1 R5411.1
ILIM_R: PR4642.2 PR4643.1 PR4678.2
ILIMNB_R: PR4629.2 PR4630.1 PR4677.2
IMVP_PWRGD: KBC24.107 PR4616.2 PR4617.2 Q2602.G
INT_SERIRQ: CPU1.AV29 KBC24.125 R2441.1
INT_TP#: AFTP6241.1 R2448.1 R6203.1 TPAD1.4
IRIS_BEEMA_ID: CPU1.AY21 R639.1 R640.2
ISOLATE#: LOM30.20 R3014.2 R3015.1
JACK_PLUG: AFTP6307.1 CN6301.23 R2923.2
JDREF: HDA27.15 R2707.1
JGND: AFTP3803.1 AFTP3806.1 DCIN1.5 DCIN1.6 EC4201.2 EC4202.2 EC4203.1 EL4203.2
KB_BL_CTRL: KBC24.22 Q6203.G R6208.1
KB_BL_CTRL#: AFTP6247.1 KBLIT1.4 Q6203.D
KB_DET#: AFTP6202.1 CPU1.BA28 KB1.30 R604.1
KB_LED_BL_DET: CPU1.AV21 R6206.1 R6207.1
KB_LED_DET_C: AFTP6246.1 C6203.1 KBLIT1.2 R6206.2
KBC_BEEP: KBC24.118 R2723.1
KBC_BEEP_R: D2701.1 R2723.2
KBC_ON#_GATE: C2417.1 Q2402.G Q2403.G R2433.2
KBC_ON#_GATE_L: R2431.1 R2432.2 R2433.1
KBC_PWRBTN#: R2427.1 R6102.1
KBC_PWRBTN#_C: AFTP6101.1 EC6101.1 ED6101.1 G6101.2 G6102.2 PWR1.2 R6102.2
KBC_VCORF: C2416.1 KBC24.44
KCOL0: AFTP6207.1 KB1.13 KBC24.53
KCOL1: AFTP6206.1 KB1.15 KBC24.52
KCOL2: AFTP6226.1 KB1.14 KBC24.51
KCOL3: AFTP6208.1 KB1.16 KBC24.50
KCOL4: AFTP6224.1 KB1.20 KBC24.49
KCOL5: AFTP6215.1 KB1.21 KBC24.48
KCOL6: AFTP6223.1 KB1.18 KBC24.47
KCOL7: AFTP6213.1 KB1.19 KBC24.43
KCOL8: AFTP6231.1 KB1.17 KBC24.42
KCOL9: AFTP6219.1 KB1.7 KBC24.41
KCOL10: AFTP6232.1 KB1.5 KBC24.40
KCOL11: AFTP6220.1 KB1.6 KBC24.39
KCOL12: AFTP6233.1 KB1.12 KBC24.38
KCOL13: AFTP6203.1 KB1.9 KBC24.37
KCOL14: AFTP6216.1 KB1.8 KBC24.36
KCOL15: AFTP6229.1 KB1.10 KBC24.35
KCOL16: AFTP6225.1 KB1.11 KBC24.34
KROW0: AFTP6228.1 KB1.22 KBC24.54
KROW1: AFTP6227.1 KB1.24 KBC24.55
KROW2: AFTP6218.1 KB1.26 KBC24.56
KROW3: AFTP6234.1 KB1.23 KBC24.57
KROW4: AFTP6230.1 KB1.27 KBC24.58
KROW5: AFTP6214.1 KB1.25 KBC24.59
KROW6: AFTP6222.1 KB1.28 KBC24.60
KROW7: AFTP6221.1 KB1.29 KBC24.61
L_BKLT_CTRL: CPU1.A18 R5206.1
L_BKLT_EN: CPU1.B17 R2444.1
L_BKLT_EN_EC: KBC24.9 R2444.2 R2445.1
LAN_ENABLE_R_C: Q3001.D R3021.2 R3022.1
LAN_MDI0N: EC3102.2 LOM30.2 U3101.2 U3101.9 XF3101.11
LAN_MDI0P: EC3101.2 LOM30.1 U3101.1 U3101.10 XF3101.12
LAN_MDI1N: EC3104.2 LOM30.5 U3101.5 U3101.6 XF3101.7
LAN_MDI1P: EC3103.2 LOM30.4 U3101.4 U3101.7 XF3101.8
LAN_MDI2N: EC3107.2 LOM30.7 U3102.2 U3102.9 XF3102.8
LAN_MDI2P: EC3108.2 LOM30.6 U3102.1 U3102.10 XF3102.7
LAN_MDI3N: EC3105.2 LOM30.10 U3102.5 U3102.6 XF3102.12
LAN_MDI3P: EC3106.2 LOM30.9 U3102.4 U3102.7 XF3102.11
LAN_TXN_C_PCH_RXN0: C3016.1 LOM30.18
LAN_TXP_C_PCH_RXP0: C3014.1 LOM30.17
LANXIN: C3001.1 LOM30.28 X3001.1
LANXOUT: LOM30.29 R3002.1
LANXOUT.R: C3011.1 R3002.2 X3001.3
LCD_BRIGHTNESS: AFTP5203.1 LCD1.20 RN5201.2(A)
LCD_TST: R2417.2 RN5201.8(B)
LCD_TST_C: AFTP5207.1 LCD1.10 RN5201.1(A)
LCD_TST_EN: D5201.2 KBC24.28 R2417.1
LCDVDD: R5211.2 U5201.3
LCDVDD_EN: D5201.3 R5202.2 U5201.1
LCDVDD_LCD: AFTP5202.1 C5201.1 C5206.2 LCD1.4 LCD1.5 LCD1.6 LCD1.7 R5211.1
LDO1_CAP: C2702.2 HDA27.27 R2711.2
LDO2_CAP: C2712.2 HDA27.39
LDO3_CAP: C2718.1 HDA27.7
LDRQ0#: CPU1.AP1 TP1903.1
LED0: LOM30.27 TP3003.1
LED1: LOM30.26 TP3002.1
LED2: LOM30.25 TP3001.1
LID_CLOSE#: D2401.K KBC24.17 R2421.1 R6109.1
LID_CLOSE#_C: AFTP6104.1 EC6107.1 PWR1.3 R6109.2
LINE1-L_C: C2907.2 R2922.1
LINE1-L_R: C2908.2 R2921.1
LINE1_L: C2907.1 HDA27.22
LINE1_R: C2908.1 HDA27.21
LINE1_VREFO_L: HDA27.31 R2912.1
LINE1_VREFO_R: HDA27.30 R2913.1
LOM_TCT: C3106.1 XF3101.9 XF3101.10 XF3102.9 XF3102.10
LPC_AD0: KBC24.126 RN1901.4(A) RN6501.4(A)
LPC_AD1: KBC24.127 RN1901.3(A) RN6501.3(A)
LPC_AD2: KBC24.128 RN1901.2(A) RN6501.2(A)
LPC_AD3: KBC24.1 RN1901.1(A) RN6501.1(A)
LPC_FRAME#: KBC24.3 R1901.1 R1913.2 R1914.1 R6501.1
LPC_FRAME#_DEBUG: DB1.5 R6501.2
LPC_FRAME#_R: CPU1.AP2 R1901.2
LPC_LAD0_R: DB1.9 RN6501.5(B)
LPC_LAD1_R: DB1.8 RN6501.6(B)
LPC_LAD2_R: DB1.7 RN6501.7(B)
LPC_LAD3_R: DB1.6 RN6501.8(B)
LPC_PD#: CPU1.AV2 TP1901.1
LPC_RST#: R602.1 R2416.2 R6502.1
LPC_RST#_C: CPU1.AY4 R602.2
LPCCLK0: CPU1.AY2 R1906.2 R1911.2 R1919.1
LPCCLK1: CPU1.AW2 R1907.1 R1912.1 R1920.2
M_A_A0: CPU1.AG38 DM1.98 DM2.98
M_A_A1: CPU1.W35 DM1.97 DM2.97
M_A_A2: CPU1.W38 DM1.96 DM2.96
M_A_A3: CPU1.W34 DM1.95 DM2.95
M_A_A4: CPU1.U38 DM1.92 DM2.92
M_A_A5: CPU1.U37 DM1.91 DM2.91
M_A_A6: CPU1.U34 DM1.90 DM2.90
M_A_A7: CPU1.R35 DM1.86 DM2.86
M_A_A8: CPU1.R38 DM1.89 DM2.89
M_A_A9: CPU1.N38 DM1.85 DM2.85
M_A_A10: CPU1.AG34 DM1.107 DM2.107
M_A_A11: CPU1.R34 DM1.84 DM2.84
M_A_A12: CPU1.N37 DM1.83 DM2.83
M_A_A13: CPU1.AN34 DM1.119 DM2.119
M_A_A14: CPU1.L38 DM1.80 DM2.80
M_A_A15: CPU1.L35 DM1.78 DM2.78
M_A_BS0: CPU1.AJ38 DM1.109 DM2.109
M_A_BS1: CPU1.AG35 DM1.108 DM2.108
M_A_BS2: CPU1.N34 DM1.79 DM2.79
M_A_CAS#: CPU1.AL34 DM1.115 DM2.115
M_A_DIM0_CKE0: CPU1.L34 DM1.73
M_A_DIM0_CKE1: CPU1.J38 DM1.74
M_A_DIM0_CLK_DDR0: CPU1.AC35 DM1.101
M_A_DIM0_CLK_DDR1: CPU1.AA34 DM1.102
M_A_DIM0_CLK_DDR#0: CPU1.AC34 DM1.103
M_A_DIM0_CLK_DDR#1: CPU1.AA32 DM1.104
M_A_DIM0_CS#0: CPU1.AJ34 DM1.114
M_A_DIM0_CS#1: CPU1.AR38 DM1.121
M_A_DIM0_ODT0: CPU1.AN38 DM1.116
M_A_DIM0_ODT1: CPU1.AU38 DM1.120
M_A_DM0: CPU1.B32 DM1.11 DM2.11
M_A_DM1: CPU1.B38 DM1.28 DM2.28
M_A_DM2: CPU1.G40 DM1.46 DM2.46
M_A_DM3: CPU1.N41 DM1.63 DM2.63
M_A_DM4: CPU1.AG40 DM1.136 DM2.136
M_A_DM5: CPU1.AN41 DM1.153 DM2.153
M_A_DM6: CPU1.AY40 DM1.170 DM2.170
M_A_DM7: CPU1.AY34 DM1.187 DM2.187
M_A_DQ<0>: CPU1.B30 DM1.5 DM2.5
M_A_DQ<1>: CPU1.A32 DM1.7 DM2.7
M_A_DQ<2>: CPU1.B35 DM1.15 DM2.15
M_A_DQ<3>: CPU1.A36 DM1.17 DM2.17
M_A_DQ<4>: CPU1.B29 DM1.4 DM2.4
M_A_DQ<5>: CPU1.A30 DM1.6 DM2.6
M_A_DQ<6>: CPU1.A34 DM1.16 DM2.16
M_A_DQ<7>: CPU1.B34 DM1.18 DM2.18
M_A_DQ<8>: CPU1.B37 DM1.21 DM2.21
M_A_DQ<9>: CPU1.A38 DM1.23 DM2.23
M_A_DQ<10>: CPU1.D40 DM1.33 DM2.33
M_A_DQ<11>: CPU1.D41 DM1.35 DM2.35
M_A_DQ<12>: CPU1.B36 DM1.22 DM2.22
M_A_DQ<13>: CPU1.A37 DM1.24 DM2.24
M_A_DQ<14>: CPU1.B41 DM1.34 DM2.34
M_A_DQ<15>: CPU1.C40 DM1.36 DM2.36
M_A_DQ<16>: CPU1.F40 DM1.39 DM2.39
M_A_DQ<17>: CPU1.F41 DM1.41 DM2.41
M_A_DQ<18>: CPU1.K40 DM1.51 DM2.51
M_A_DQ<19>: CPU1.K41 DM1.53 DM2.53
M_A_DQ<20>: CPU1.E40 DM1.40 DM2.40
M_A_DQ<21>: CPU1.E41 DM1.42 DM2.42
M_A_DQ<22>: CPU1.J40 DM1.50 DM2.50
M_A_DQ<23>: CPU1.J41 DM1.52 DM2.52
M_A_DQ<24>: CPU1.M41 DM1.57 DM2.57
M_A_DQ<25>: CPU1.N40 DM1.59 DM2.59
M_A_DQ<26>: CPU1.T41 DM1.67 DM2.67
M_A_DQ<27>: CPU1.U40 DM1.69 DM2.69
M_A_DQ<28>: CPU1.L40 DM1.56 DM2.56
M_A_DQ<29>: CPU1.M40 DM1.58 DM2.58
M_A_DQ<30>: CPU1.R40 DM1.68 DM2.68
M_A_DQ<31>: CPU1.T40 DM1.70 DM2.70
M_A_DQ<32>: CPU1.AF40 DM1.129 DM2.129
M_A_DQ<33>: CPU1.AF41 DM1.131 DM2.131
M_A_DQ<34>: CPU1.AK40 DM1.141 DM2.141
M_A_DQ<35>: CPU1.AK41 DM1.143 DM2.143
M_A_DQ<36>: CPU1.AE40 DM1.130 DM2.130
M_A_DQ<37>: CPU1.AE41 DM1.132 DM2.132
M_A_DQ<38>: CPU1.AJ40 DM1.140 DM2.140
M_A_DQ<39>: CPU1.AJ41 DM1.142 DM2.142
M_A_DQ<40>: CPU1.AM41 DM1.147 DM2.147
M_A_DQ<41>: CPU1.AN40 DM1.149 DM2.149
M_A_DQ<42>: CPU1.AT41 DM1.157 DM2.157
M_A_DQ<43>: CPU1.AU40 DM1.159 DM2.159
M_A_DQ<44>: CPU1.AL40 DM1.146 DM2.146
M_A_DQ<45>: CPU1.AM40 DM1.148 DM2.148
M_A_DQ<46>: CPU1.AR40 DM1.158 DM2.158
M_A_DQ<47>: CPU1.AT40 DM1.160 DM2.160
M_A_DQ<48>: CPU1.AV41 DM1.163 DM2.163
M_A_DQ<49>: CPU1.AW40 DM1.165 DM2.165
M_A_DQ<50>: CPU1.BA38 DM1.175 DM2.175
M_A_DQ<51>: CPU1.AY37 DM1.177 DM2.177
M_A_DQ<52>: CPU1.AU41 DM1.164 DM2.164
M_A_DQ<53>: CPU1.AV40 DM1.166 DM2.166
M_A_DQ<54>: CPU1.AY39 DM1.174 DM2.174
M_A_DQ<55>: CPU1.AY38 DM1.176 DM2.176
M_A_DQ<56>: CPU1.BA36 DM1.181 DM2.181
M_A_DQ<57>: CPU1.AY35 DM1.183 DM2.183
M_A_DQ<58>: CPU1.BA32 DM1.191 DM2.191
M_A_DQ<59>: CPU1.AY31 DM1.193 DM2.193
M_A_DQ<60>: CPU1.BA37 DM1.180 DM2.180
M_A_DQ<61>: CPU1.AY36 DM1.182 DM2.182
M_A_DQ<62>: CPU1.BA33 DM1.192 DM2.192
M_A_DQ<63>: CPU1.AY32 DM1.194 DM2.194
M_A_DQS_DN<0>: CPU1.A33 DM1.10 DM2.10
M_A_DQS_DN<1>: CPU1.A40 DM1.27 DM2.27
M_A_DQS_DN<2>: CPU1.H40 DM1.45 DM2.45
M_A_DQS_DN<3>: CPU1.P40 DM1.62 DM2.62
M_A_DQS_DN<4>: CPU1.AH40 DM1.135 DM2.135
M_A_DQS_DN<5>: CPU1.AP40 DM1.152 DM2.152
M_A_DQS_DN<6>: CPU1.AY41 DM1.169 DM2.169
M_A_DQS_DN<7>: CPU1.BA34 DM1.186 DM2.186
M_A_DQS_DP<0>: CPU1.B33 DM1.12 DM2.12
M_A_DQS_DP<1>: CPU1.B40 DM1.29 DM2.29
M_A_DQS_DP<2>: CPU1.H41 DM1.47 DM2.47
M_A_DQS_DP<3>: CPU1.P41 DM1.64 DM2.64
M_A_DQS_DP<4>: CPU1.AH41 DM1.137 DM2.137
M_A_DQS_DP<5>: CPU1.AP41 DM1.154 DM2.154
M_A_DQS_DP<6>: CPU1.BA40 DM1.171 DM2.171
M_A_DQS_DP<7>: CPU1.AY33 DM1.188 DM2.188
M_A_EVENT#: CPU1.AE34 DM1.198 DM2.198 R504.2
M_A_RAS#: CPU1.AJ37 DM1.110 DM2.110
M_A_WE#: CPU1.AL35 DM1.113 DM2.113
M_ANALOGIN: CPU1.R32 TP418.1
M_ANALOGOUT: CPU1.N32 TP420.1
M_B_DIM0_CKE0: CPU1.J37 DM2.73
M_B_DIM0_CKE1: CPU1.J34 DM2.74
M_B_DIM0_CLK_DDR0: CPU1.AE38 DM2.101
M_B_DIM0_CLK_DDR1: CPU1.AA37 DM2.102
M_B_DIM0_CLK_DDR#0: CPU1.AE37 DM2.103
M_B_DIM0_CLK_DDR#1: CPU1.AA38 DM2.104
M_B_DIM0_CS#0: CPU1.AL38 DM2.114
M_B_DIM0_CS#1: CPU1.AN35 DM2.121
M_B_DIM0_ODT0: CPU1.AN37 DM2.116
M_B_DIM0_ODT1: CPU1.AR37 DM2.120
M_ZVDDIO: CPU1.AD41 R503.2
MCT: C3101.1 RN3101.5(B) RN3101.6(B) RN3101.7(B) RN3101.8(B)
MCT0: RN3101.4(A) XF3102.3
MCT1: RN3101.1(A) XF3102.4
MCT2: RN3101.3(A) XF3101.4
MCT3: RN3101.2(A) XF3101.3
MDO0+: AFTP3107.1 RJ45.1 XF3101.1
MDO0-: AFTP3102.1 RJ45.2 XF3101.2
MDO1+: AFTP3101.1 RJ45.3 XF3101.5
MDO1-: AFTP3106.1 RJ45.6 XF3101.6
MDO2+: AFTP3103.1 RJ45.4 XF3102.6
MDO2-: AFTP3104.1 RJ45.5 XF3102.5
MDO3+: AFTP3105.1 RJ45.7 XF3102.2
MDO3-: AFTP3108.1 RJ45.8 XF3102.1
MEM_1V5: CPU1.BA3 R644.1
MIC2_VREFO: HDA27.29 RN2901.1(A) RN2901.2(A)
MIC_CAP: C2713.1 HDA27.19
MIC_GND: LCD1.26 R5201.1
MODEL_ID_DET: C2403.2 KBC24.94 R2405.2 R2407.1 R2446.2 R2449.2 R2451.2
NCT7718_DXN: C2606.2 C2607.2 Q2603.E THM26.3
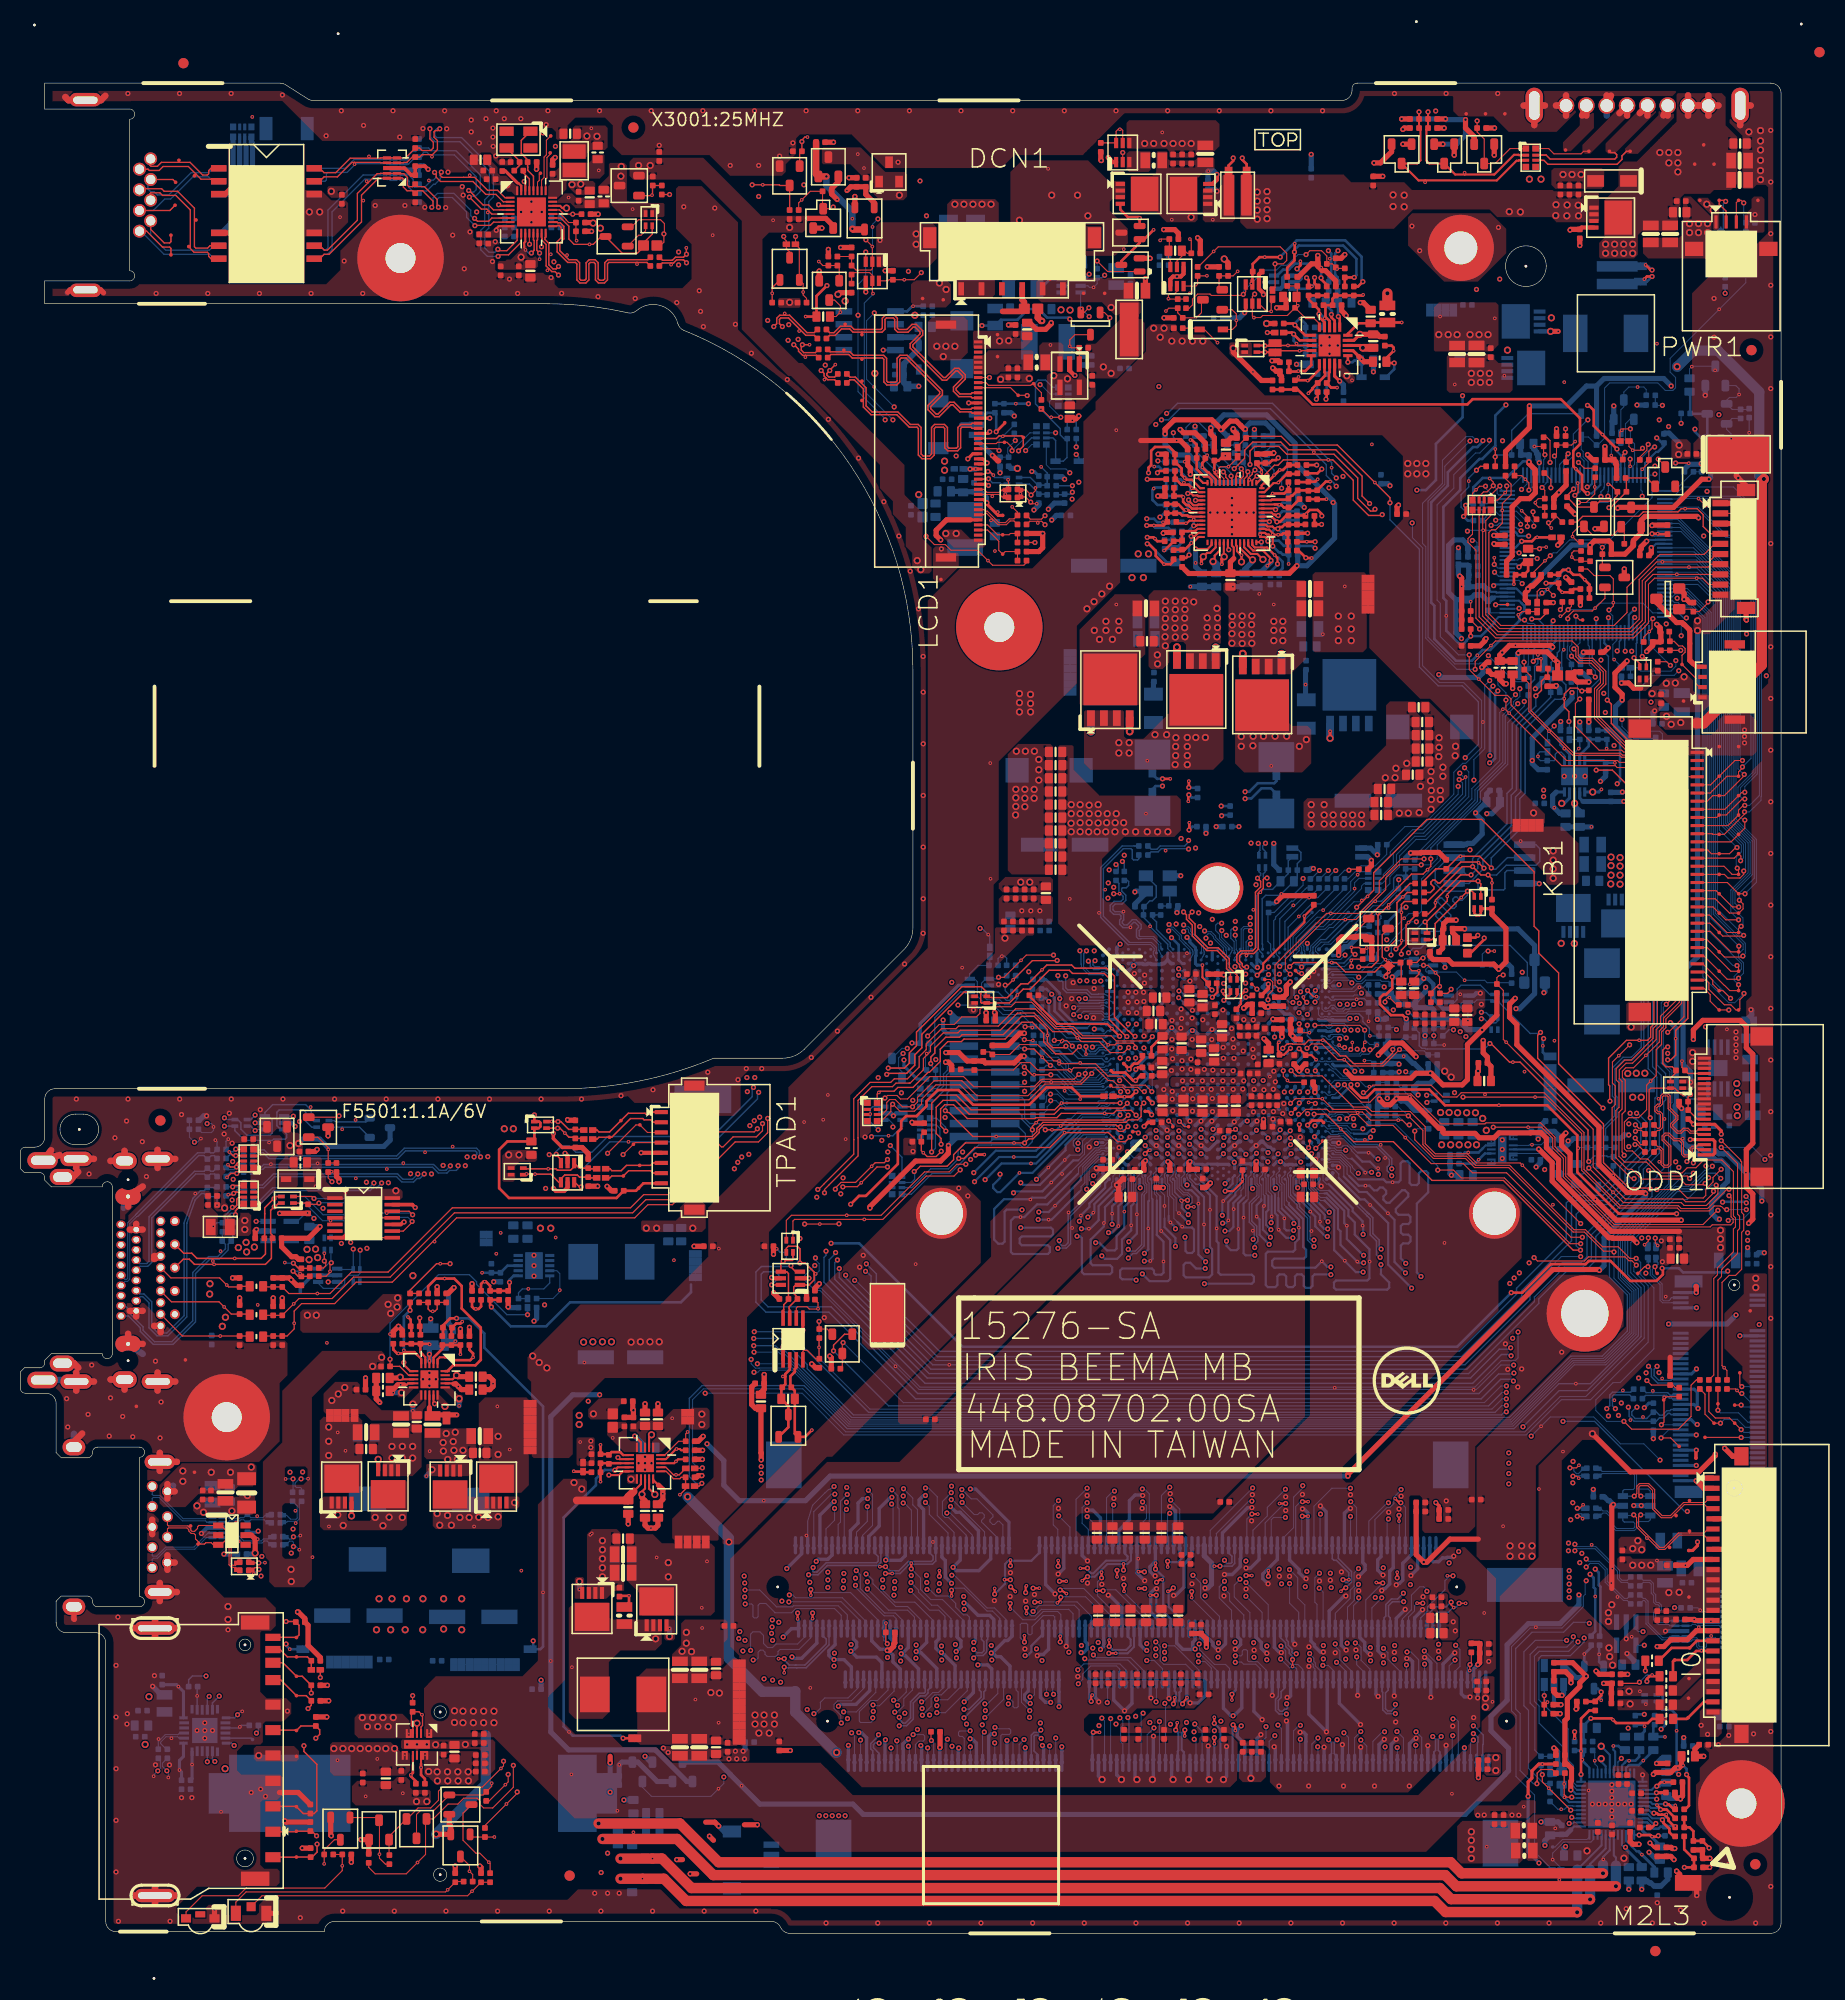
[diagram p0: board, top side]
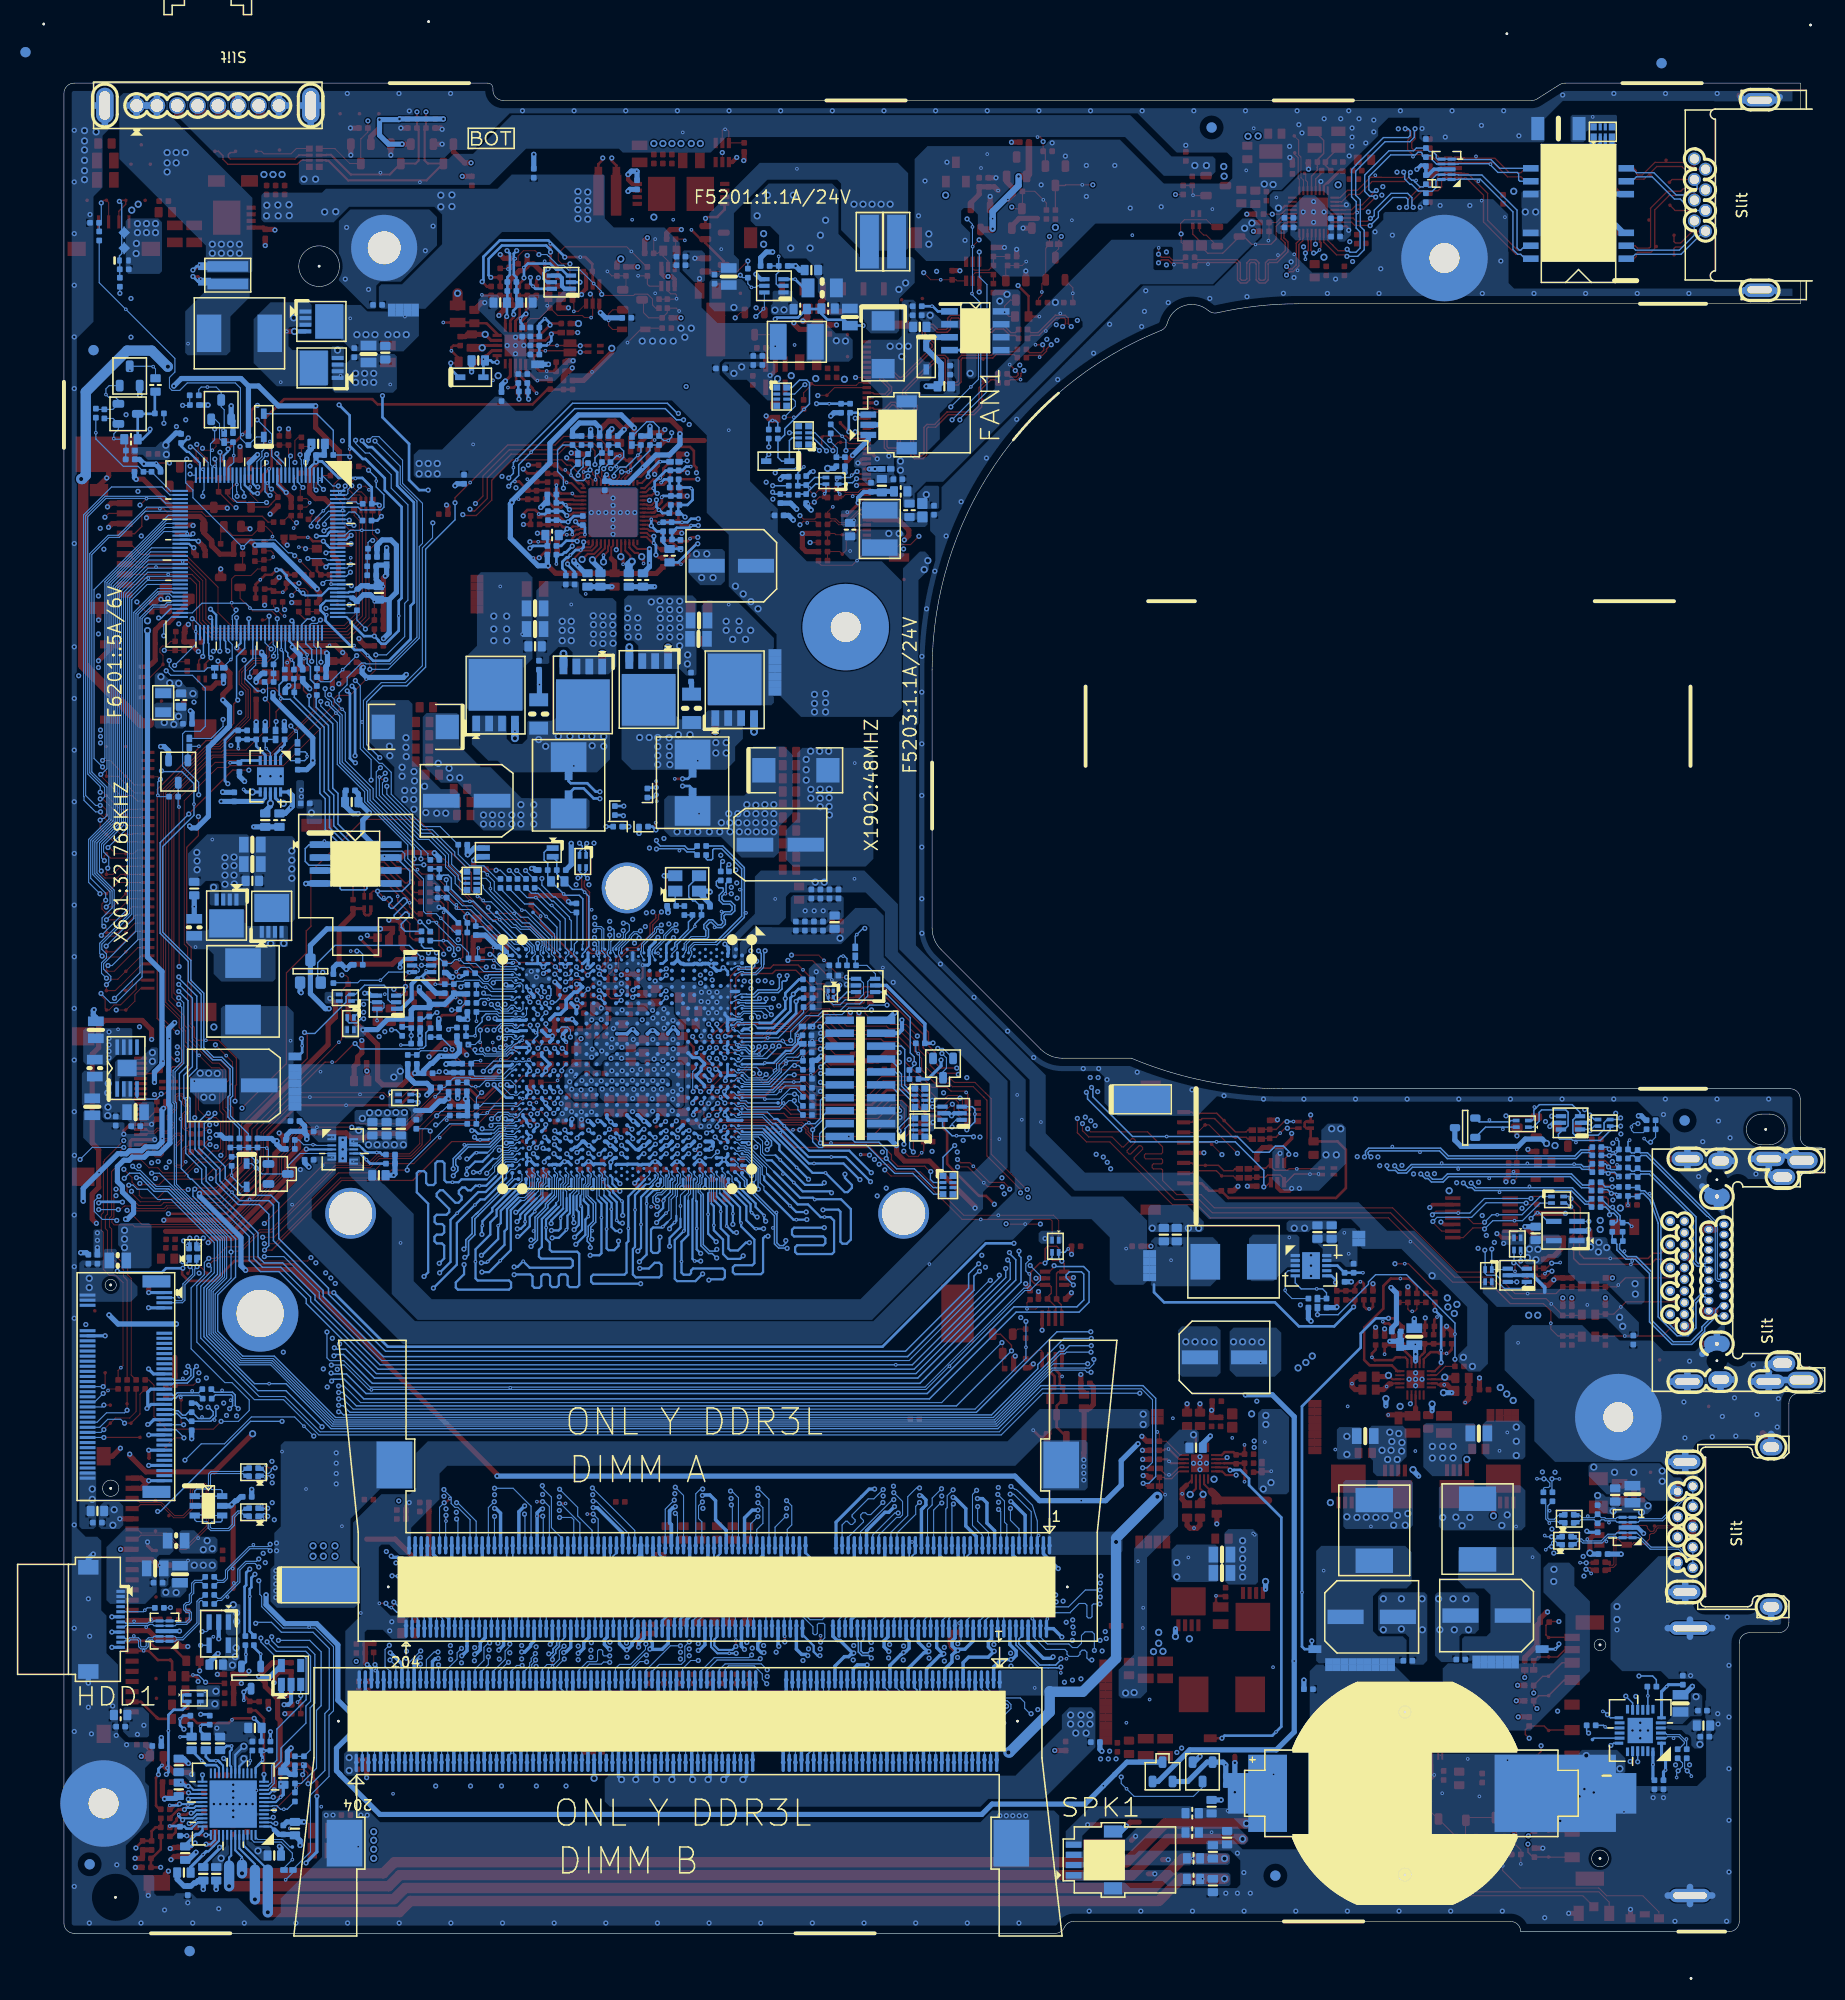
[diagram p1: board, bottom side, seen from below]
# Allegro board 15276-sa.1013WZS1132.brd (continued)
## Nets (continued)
NCT7718_DXP: C2606.1 C2607.1 Q2603.B Q2603.C THM26.2
ODD_PWR_5V: C5610.1 ODD1.10 ODD1.11 ODD1.12 ODD1.13 ODD1.14 ODD1.15 R5603.2 U5601.6 U5601.7 U5601.8
P_RX_ZVDD_095: CPU1.W7 R301.2
P_TX_ZVDD_095: CPU1.W8 R302.2
PANEL_SIZE_ID: CPU1.AY26 R5208.2 R5209.1 R5210.2
PANEL_SIZE_ID_CONN: LCD1.22 R5210.1
PBAT_PRES1#: AFTP3902.1 BATT1.5 RN4301.8(B)
PBAT_SMBCLK1: AFTP3904.1 BATT1.3 RN4301.6(B)
PBAT_SMBDAT1: AFTP3903.1 BATT1.4 RN4301.7(B)
PCB_VER_AD: C2402.2 KBC24.98 R2404.2 R2406.1
PCH_HDMI_CLK: CPU1.D17 Q5402.4 RN402.1(A) RN5404.1(A)
PCH_HDMI_DATA: CPU1.E17 Q5402.1 RN402.2(A) RN5404.2(A)
PCH_SUSCLK_KBC: KBC24.77 R609.2
PCIE_PRX_LANTX_N0: C3016.2 CPU1.R8
PCIE_PRX_LANTX_P0: C3014.2 CPU1.R10
PCIE_PRX_WLANTX_N1: CPU1.R4 R5808.2
PCIE_PRX_WLANTX_N3_R: R5808.1 WLAN1.43
PCIE_PRX_WLANTX_P1: CPU1.R5 R5811.2
PCIE_PRX_WLANTX_P3_R: R5811.1 WLAN1.41
PCIE_PTX_LANRX_N0: C306.1 CPU1.L1
PCIE_PTX_LANRX_N0_C: C306.2 LOM30.14
PCIE_PTX_LANRX_P0: C305.1 CPU1.L2
PCIE_PTX_LANRX_P0_C: C305.2 LOM30.13
PCIE_PTX_WLANRX_N1_C: C304.2 WLAN1.37
PCIE_PTX_WLANRX_P1_C: C303.2 WLAN1.35
PCIE_RST#_C: CPU1.AY9 R618.2
PCIE_TXN1_C: C304.1 CPU1.K1
PCIE_TXP1_C: C303.1 CPU1.K2
PCIE_WAKE#: KBC24.113 LOM30.21 R622.1 R3033.1
PCIE_WAKE#_R: CPU1.AW11 R622.2 R626.1
PD4403_A: PD4404.A PQ4409.B
PD4403_K: PD4404.K PR4468.2
PLT_RST#: C601.2 D401.3 Q3003.E R618.1 R3016.1 R5448.2 R5807.1
PLT_RST#_DEBUG: DB1.4 R6502.2
PLT_RST#_EC: C2415.2 ED2401.1 KBC24.7 R2416.1
PLT_RST#_LAN: LOM30.19 Q3003.C R3016.2 RN3001.4(B)
PLT_RST_NGFF#: AFTP5805.1 R5807.2 WLAN1.52
PM_CLKRUN#_EC: CPU1.AP25 KBC24.8 R2401.1
PM_LAN_ENABLE: KBC24.119 Q3001.G R3023.1
PM_LAN_ENABLE_R: C3015.2 Q3004.G R3022.2
PM_PWRBTN#: KBC24.117 R625.1
PM_PWRBTN#_R: CPU1.BA8 R625.2 R630.1
PM_RSMRST#: Q601.3 Q603.5 R628.1 R629.1
PM_RSMRST#_R: CPU1.AY5 Q603.6 R649.2
PM_SLP_S3#: CPU1.AY3 D3603.3 D3606.K KBC24.64 PR4910.2 R3609.2 U3603.5
PM_SLP_S5#: CPU1.BA5 KBC24.21 PR4907.1
PQ3802_1: PQ4202.B PR4202.1 PR4209.2
PQ3808D: PC4208.2 PQ4208.D
PQ3808G: PC4209.1 PQ4208.G PR4215.1
PQ3809_D: PQ4206.3 PR4214.2
PQ4008_2: PC4425.1 PQ4408.2 PR4437.2
PQ4008_6: PQ4408.6 PR4426.1
PQ4203_5: PC4210.1 PQ4203.5 PR4218.1
PQ4405_2: PQ4410.2 PR4475.2 PR4476.2
PQ4405_3: PQ4410.3 PR4466.1
PQ4405_5: PC4434.1 PQ4410.5 PR4470.2
PQ4405_6: PC4434.2 PQ4410.6 PR4473.1
PQ4408_C: PQ4409.C PR4464.1 PR4475.1
PQ4408_E: PQ4409.E PR4467.1 PR4469.2
PR4601_1: PR4901.2 PR4906.1
PR4605_2: PC4919.1 PR4905.2
PROCHOT_EC: KBC24.24 Q2401.G R2438.1 R2442.1
PS_ID: PQ4201.S PR4205.1
PS_ID_R: AFTP3802.1 DCIN1.4 PR4217.1
PS_ID_R2: PD4204.1 PD4204.2 PQ4201.D PR4209.1 PR4217.2
PSID_DISABLE#_R_C: PQ4201.G PQ4202.C PR4203.2
PSID_EC: KBC24.99 PD4203.3 PR4204.2 PR4205.2
PSL_IN1#: KBC24.73 R2430.2
PSL_IN2#: KBC24.93 R2425.1 R2427.2
PSL_OUT#: KBC24.74 R2432.1
PURE_HW_SHUTDOWN#: C2610.1 D3602.3 Q2404.B Q2602.D R2424.1 R2439.2 R2602.2
PWR_0D95V_BOOT: PR4820.1 PU4806.10
PWR_0D95V_BOOT_R: PC4833.2 PR4820.2
PWR_0D95V_CCM: PR4824.1 PU4806.5
PWR_0D95V_EN: PC4831.1 PR4819.2 PU4806.3
PWR_0D95V_FB: PC4832.2 PR4822.2 PR4823.1 PU4806.4
PWR_0D95V_LGATE: PU4805.4 PU4806.6
PWR_0D95V_PHASE: PC4833.1 PL4802.1 PR4837.1 PU4805.5 PU4805.6 PU4805.7 PU4805.8 PU4806.8 PU4808.1 PU4808.2 PU4808.3
PWR_0D95V_PWR: PC4832.1 PG4832.1 PR4822.1
PWR_0D95V_PWRGD: PR4821.1 PR4835.2 PU4806.1
PWR_0D95V_TRIP: PR4817.2 PU4806.2
PWR_0D95V_UGATE: PU4806.9 PU4808.4
PWR_1D05V_SNUB: PC4838.1 PR4837.2
PWR_1D8V_EN: PC5005.1 PR5010.2 PU5002.5
PWR_1D8V_FB: PC5014.2 PC5020.1 PR5009.2 PR5013.1 PU5002.6
PWR_1D8V_FB_A: PC5020.2 PR5020.1
PWR_1D8V_PHASE: PL5002.1 PU5002.1 PU5002.2 PU5002.3
PWR_1D8V_PVDD: PC5011.1 PC5015.1 PG5009.2 PG5014.2 PR5012.1 PU5002.9 PU5002.10
PWR_1D8V_SVIN: PC5013.1 PR5012.2 PU5002.8
PWR_1D35V_DRVH: PU4901.14 PU4902.4
PWR_1D35V_DRVL: PU4901.11 PU4903.4
PWR_1D35V_EN: PC4906.1 PR4907.2 PU4901.16
PWR_1D35V_MODE: PR4908.1 PU4901.19
PWR_1D35V_REFIN: PC4902.1 PR4901.1 PR4903.2 PU4901.8
PWR_1D35V_SW: PC4919.2 PL4902.1 PR4912.1 PU4901.13 PU4902.1 PU4902.2 PU4902.3 PU4903.5 PU4903.6 PU4903.7 PU4903.8
PWR_1D35V_TRIP: PR4902.1 PU4901.18
PWR_1D35V_VBST: PR4905.1 PU4901.15
PWR_1D35V_VREF: PC4903.1 PR4903.1 PU4901.6
PWR_1D35V_VTTREF: PC4918.1 PR4911.1 PU4901.5
PWR_3D3V_BOOT: PR4505.2 PU4509.9
PWR_3D3V_BOOT_A: PC4505.2 PR4505.1
PWR_3D3V_CS: PR4507.1 PU4509.5
PWR_3D3V_EN2: PR4529.2 PU4509.6
PWR_3D3V_FB: PC4506.2 PR4516.2 PR4518.1 PU4509.4
PWR_3D3V_FB_A: PC4506.1 PR4506.2
PWR_3D3V_FB_B: PG4537.2 PR4506.1 PR4516.1
PWR_3D3V_HG: PU4509.10 PU4510.4
PWR_3D3V_LG: PU4506.4 PU4509.11
PWR_3D3V_PH: PC4505.1 PL4504.2 PU4506.5 PU4506.6 PU4506.7 PU4506.8 PU4509.8 PU4510.1 PU4510.2 PU4510.3
PWR_5V_BOOT: PR4524.1 PU4509.17
PWR_5V_BOOT_A: PC4510.1 PR4524.2
PWR_5V_CS: PR4511.1 PU4509.1
PWR_5V_EN1: PR4528.2 PU4509.20
PWR_5V_EN1_R: PR4527.2 PR4528.1 PR4530.2 PR4531.2
PWR_5V_FB: PC4521.2 PR4514.2 PR4523.1 PU4509.2
PWR_5V_FB_A: PC4521.1 PR4513.2
PWR_5V_HG: PU4508.4 PU4509.16
PWR_5V_LG: PU4507.4 PU4509.15
PWR_5V_PH: PC4510.2 PL4503.1 PU4507.5 PU4507.6 PU4507.7 PU4507.8 PU4508.1 PU4508.2 PU4508.3 PU4509.18
PWR_5V_VO: PG4547.2 PR4513.1 PR4514.1 PU4509.14
PWR_APU_SVC: PR4653.2 PU4601.5
PWR_APU_SVD: PR4652.2 PU4601.3
PWR_APU_SVT: PR4651.2 PU4601.4
PWR_APU_VDD_BST1: PR4701.1 PU4601.28
PWR_APU_VDD_BST1_1: PC4736.1 PR4701.2
PWR_APU_VDD_CSN1: PG4702.1 PR4639.2
PWR_APU_VDD_DCBATOUT: PC4713.1 PC4715.1 PC4719.1 PC4720.1 PG4703.1 PG4704.1 PG4707.1 PG4708.1 PG4709.1 PG4710.1 PU4701.5 PU4701.6 PU4701.7 PU4701.8 PU4703.5 PU4703.6 PU4703.7 PU4703.8
PWR_APU_VDD_HG1: PU4601.29 PU4701.4 PU4703.4
PWR_APU_VDD_LG1: PU4601.31 PU4702.4 PU4704.4
PWR_APU_VDD_PGOOD: PR4615.2 PR4616.1 PU4601.7
PWR_APU_VDD_SNUB: PC4742.1 PR4709.2
PWR_APU_VDD_SW1: PC4736.2 PG4701.2 PL4701.1 PR4709.1 PU4601.30 PU4701.1 PU4701.2 PU4701.3 PU4702.5 PU4702.6 PU4702.7 PU4702.8 PU4703.1 PU4703.2 PU4703.3 PU4704.5 PU4704.6 PU4704.7 PU4704.8
PWR_APU_VDD_SWN1: PG4701.1 PR4637.2 PR4644.2
PWR_APU_VDDNB_DCBATOUT: PC4716.1 PC4717.1 PC4718.1 PC4721.1 PC4722.1 PG4711.1 PG4712.1 PG4716.1 PG4717.1 PG4718.1 PU4707.5 PU4707.6 PU4707.7 PU4707.8
PWR_CHG_ACDET: PC4412.1 PR4407.2 PR4431.1 PU4404.6
PWR_CHG_ACN: PC4402.2 PC4403.1 PG4403.2 PR4406.1 PU4404.1
PWR_CHG_ACOK: PQ4402.2 PQ4408.3 PR4419.2 PR4428.2 PR4436.1 PR4476.1
PWR_CHG_ACP: PC4402.1 PC4404.1 PG4402.2 PR4406.2 PU4404.2
PWR_CHG_AD_OFF: KBC24.11 PQ4206.5 PR4210.1
PWR_CHG_AD_OFF_R: PQ4203.6 PQ4204.B PR4210.2 PR4211.1
PWR_CHG_BAT_SCL: PG4407.1 PU4404.9
PWR_CHG_BAT_SDA: PG4408.1 PU4404.8
PWR_CHG_BTST: PR4409.1 PU4404.17
PWR_CHG_BTST_R: PC4411.1 PD4401.K PR4409.2
PWR_CHG_CMPIN: PR4411.2 PR4413.1 PR4414.2 PR4427.2 PR4429.1 PU4404.4
PWR_CHG_CMPIN_R: PQ4407.3 PR4429.2
PWR_CHG_CMPIN_RR: PQ4407.6 PR4427.1
PWR_CHG_CMPOUT: PR4414.1 PR4430.2 PR4432.1 PR4437.1 PR4438.1 PU4404.3
PWR_CHG_CSON_1: PC4421.2 PC4423.1 PG4410.1 PR4420.2
PWR_CHG_CSOP_1: PC4420.1 PC4421.1 PG4409.1 PR4421.2
PWR_CHG_HIDRV: PC4413.2 PU4404.18 PU4405.4
PWR_CHG_IFAULT: PR4418.2 PU4404.11
PWR_CHG_ILIM: PR4417.2 PR4423.1 PU4404.10
PWR_CHG_IOUT: PC4422.1 PR4411.1 PR4422.1 PR4424.1 PU4404.7
PWR_CHG_LODRV: PU4404.15 PU4406.4
PWR_CHG_PHASE: PC4411.2 PC4413.1 PL4401.1 PU4404.19 PU4405.1 PU4405.2 PU4405.3 PU4406.5 PU4406.6 PU4406.7 PU4406.8
PWR_CHG_REGN: PC4407.1 PD4401.A PR4425.1 PR4428.1 PR4430.1 PU4404.16
PWR_CHG_SRN: PR4420.1 PU4404.12
PWR_CHG_SRP: PR4421.1 PU4404.13
PWR_CHG_VCC: PC4010.1 PR4408.2 PU4404.20
PWR_COMP_R: PC4626.2 PR4647.2
PWR_CPU_COMP: PC4626.1 PC4627.2 PU4601.48
PWR_CPU_COMPNB: PC4611.1 PC4612.2 PU4601.18
PWR_CPU_CSCOMP: PC4603.2 PC4615.1 PC4618.1 PR4640.2 PR4641.2 PR4642.1 PR4678.1 PU4601.45
PWR_CPU_CSCOMPNB: PC4613.1 PC4617.1 PC4624.2 PR4626.2 PR4627.2 PR4629.1 PR4677.1 PU4601.21
PWR_CPU_CSP1: PC4628.2 PR4637.1 PU4601.40
PWR_CPU_CSP1NB: PC4623.1 PR4631.1 PU4601.26
PWR_CPU_CSP2: PR4661.1 PU4601.41
PWR_CPU_CSP2NB: PR4660.1 PU4601.25
PWR_CPU_CSREF: PC4606.1 PC4628.1 PR4639.1 PU4601.42
PWR_CPU_CSREFNB: PC4622.1 PC4623.2 PR4632.1 PU4601.24
PWR_CPU_CSSUM: PC4615.2 PC4618.2 PR4643.2 PR4644.1 PU4601.43
PWR_CPU_CSSUMNB: PC4613.2 PC4617.2 PR4630.2 PR4633.1 PU4601.23
PWR_CPU_DIFF: PR4649.1 PR4650.1 PU4601.50
PWR_CPU_DIFFNB: PR4622.1 PR4623.1 PU4601.16
PWR_CPU_DROOP: PC4603.1 PR4641.1 PU4601.46
PWR_CPU_DROOPNB: PC4624.1 PR4627.1 PU4601.20
PWR_CPU_EN: PR4609.2 PU4601.9
PWR_CPU_FB: PC4627.1 PC4648.2 PR4647.1 PR4649.2 PU4601.49
PWR_CPU_FBNB: PC4610.2 PC4612.1 PR4622.2 PR4624.1 PU4601.17
PWR_CPU_ILIM: PR4640.1 PU4601.44
PWR_CPU_ILIMNB: PR4626.1 PU4601.22
PWR_CPU_IOUT: PC4609.1 PR4646.1 PU4601.47
PWR_CPU_IOUTNB: PC4616.2 PR4625.1 PU4601.19
PWR_CPU_PHCONFIG: PR4635.1 PU4601.38
PWR_CPU_ROSC: PR4611.2 PU4601.11
PWR_CPU_SR: PR4636.1 PU4601.39
PWR_CPU_TEENSE: PC4607.2 PR4605.2 PR4606.2 PU4601.1
PWR_CPU_TSENSENB: PC4619.2 PR4618.2 PR4619.2 PU4601.14
PWR_CPU_VCC: PC4602.1 PR4610.1 PU4601.10
PWR_CPU_VDD: PC4601.1 PR4601.2 PU4601.51
PWR_CPU_VDDNB: PC4605.1 PR4621.2 PU4601.15
PWR_CPU_VRMP: PC4614.2 PR4612.2 PU4601.12
PWR_CPU_VSS: PC4601.2 PR4603.2 PU4601.52
PWR_DCBATOUT_0D95V: PC4827.1 PC4828.1 PC4830.1 PG4827.1 PG4834.1 PG4837.1 PG4838.1 PU4808.5 PU4808.6 PU4808.7 PU4808.8
PWR_DCBATOUT_3D3V: PC4503.1 PC4504.1 PC4523.1 PG4502.1 PG4503.1 PG4504.1 PG4505.1 PU4510.5 PU4510.6 PU4510.7 PU4510.8
PWR_DCBATOUT_5V: PC4514.1 PC4525.1 PC4530.1 PG4515.1 PG4516.1 PG4517.1 PG4518.1 PG4519.1 PG4520.1 PG4521.1 PU4508.5 PU4508.6 PU4508.7 PU4508.8
PWR_DIFF_R: PC4648.1 PR4650.2
PWR_VDDNB_BST2: PR4702.1 PU4601.37
PWR_VDDNB_BST2_1: PC4734.1 PR4702.2
PWR_VDDNB_CSN1NB: PG4719.1 PR4632.2
PWR_VDDNB_HG2: PU4601.36 PU4707.4
PWR_VDDNB_LG2: PU4601.34 PU4706.4 PU4708.4
PWR_VDDNB_PGOOD: PR4614.2 PR4617.1 PU4601.8
PWR_VDDNB_SNUB: PC4743.1 PR4710.2
PWR_VDDNB_SW2: PC4734.2 PG4720.2 PL4702.1 PR4710.1 PU4601.35 PU4706.5 PU4706.6 PU4706.7 PU4706.8 PU4707.1 PU4707.2 PU4707.3 PU4708.5 PU4708.6 PU4708.7 PU4708.8
PWR_VDDNB_SWN1NB: PG4720.1 PR4631.2 PR4633.2
PWR_VDDQ_SENSE_APU: PG4907.1 PU4901.9 R417.1
PWR_VR_HOT: PR4613.1 PU4601.13
PWROK: PR4607.2 PU4601.2
Q402_1: Q3003.B RN3001.3(B)
Q603_2: Q603.2 Q603.3 R648.2
Q6205_Q: Q6205.D R6214.2
R1930.R: C1905.2 R1930.1 X1902.1
REGOUT: C3002.1 L3001.1 LOM30.24 R3001.1
RING2: EC2905.1 HDA27.17 R2906.2 RN2901.3(B)
RING2_R: AFTP6305.1 CN6301.21 CN6301.22 R2906.1
RREF: R3203.1 U3201.1
RSET: LOM30.31 R3032.2
RSMRST#_KBC: KBC24.15 R628.2
RTC_1D5V_PWR: C702.1 R701.1 U701.2
RTC_1D5V_S5: C701.1 CPU1.AN4 G701.1 Q701.D R701.2
RTC_AUX_S5: C705.1 C2503.2 D2501.3 R2428.2 U701.3
RTC_CLK: CPU1.AV11 R609.1 R1917.1 R1918.1
RTC_DET#: CPU1.AV15 Q2505.D R634.1
RTC_PWR: D2501.2 Q2505.G R2502.1 R2504.1
RTCRST_ON: KBC24.120 Q701.G R702.1
RUNPWROK_D: D3606.A R3627.1
S0_PWR_GOOD_R: CPU1.AM19 R611.2 R627.1
S5_ENABLE: KBC24.14 Q2403.D R2436.2 R3603.2
SATA3_PRX_HDDTX_N0: C5616.1 CPU1.BA16
SATA3_PRX_HDDTX_P0: C5615.1 CPU1.AY16
SATA3_PTX_HDDRX_N0: C5603.2 CPU1.AY14
SATA3_PTX_HDDRX_P0: C5602.2 CPU1.BA14
SATA_LED: Q6106.C R6108.1
SATA_LED#: CPU1.BA30 Q6105.S Q6107.S R1931.2 R2450.1 R6106.1
SATA_LED#_B: Q6105.D Q6106.B R6106.2
SATA_LED#_R: KBC24.95 Q6107.G R2450.2 R6110.2
SATA_LED_R: EC6106.1 HDLED1.1A R6108.2
SATA_ODD_DA#: CPU1.AN8 R5602.2 RN5601.3(B)
SATA_ODD_DA#_C: ODD1.17 R5602.1
SATA_ODD_PRSNT#: CPU1.AV1 ODD1.8 R5604.1 R5610.1
SATA_ODD_PWRGT: CPU1.AV31 RN5601.4(B) U5601.4
SATA_PRX_ODDTX_N1: C5607.2 CPU1.AY17
SATA_PRX_ODDTX_P1: C5608.2 CPU1.BA17
SATA_PTX_ODDRX_N1: C5611.2 CPU1.BA19
SATA_PTX_ODDRX_P1: C5612.2 CPU1.AY19
SATA_RXN0_R: C5616.2 EU5602.4 EU5602.7 HDD1.8
SATA_RXN2_R: C5607.1 ODD1.5
SATA_RXP0_R: C5615.2 EU5602.5 EU5602.6 HDD1.7
SATA_RXP2_R: C5608.1 ODD1.6
SATA_TXN0_R: C5603.1 EU5602.2 EU5602.9 HDD1.10
SATA_TXN2_R: C5611.1 ODD1.3
SATA_TXP0_R: C5602.1 EU5602.1 EU5602.10 HDD1.11
SATA_TXP2_R: C5612.1 ODD1.2
SATA_ZVDD_095: CPU1.AP19 R1904.2
SATA_ZVSS: CPU1.AR19 R1903.2
SD_CD#: R3301.1 U3201.13
SD_CD_R#: AFTP3304.1 CARD1.10 EC3305.1 R3301.2
SD_CLK: AFTP3303.1 CARD1.5 EC3201.1 R3201.2
SD_CLK_5170: R3201.1 U3201.15
SD_CMD: AFTP3302.1 CARD1.2 EC3304.1 U3201.18
SD_D0: AFTP3306.1 CARD1.7 EC3306.1 U3201.11
SD_D1: AFTP3307.1 CARD1.8 EC3301.1 U3201.10
SD_D2: AFTP3308.1 CARD1.9 EC3302.1 U3201.21
SD_D3: AFTP3309.1 CARD1.1 EC3303.1 U3201.20
SD_WP: AFTP3305.1 CARD1.11 EC3307.1 R3202.1
SD_WP_5170: R3202.2 U3201.8
SDREFG: C3206.1 U3201.6
SLEEVE: EC2906.1 HDA27.18 R2911.2 RN2901.4(B)
SLEEVE_R: AFTP6310.1 CN6301.19 CN6301.20 R2911.1
SMB0_CLK: CPU1.AU25 DM1.202 DM2.202 RN601.4(B)
SMB0_DATA: CPU1.AV25 DM1.200 DM2.200 RN601.3(B)
SMB1_CLK: CPU1.AY11 Q6202.6 RN603.2(A)
SMB1_DATA: CPU1.BA11 Q6202.3 RN603.1(A)
SML1_CLK: KBC24.67 Q403.6 Q2601.3 RN401.1(A)
SML1_DATA: KBC24.68 Q403.3 Q2601.6 RN401.2(A)
SPI_CLK_R: EC2503.1 R1925.2 R2420.1 SPI25.6 SSKT2.6
SPI_CS0#_R: R1908.2 R2419.2 R2501.1 SPI25.1 SSKT2.1
SPI_CS2#: CPU1.AR4 TP1904.1
SPI_HOLD#: R1923.2 RN1904.1(A) RN2501.2(A) SPI25.7 SSKT2.7
SPI_SI_R: EC2501.1 R1921.2 R2422.2 SPI25.5 SSKT2.5
SPI_SO_R: EC2502.1 R1922.2 R2423.2 SPI25.2 SSKT2.2
SPI_SW: CPU1.AV17 R1915.2 R1916.1
SPI_WP#: R1924.2 RN1904.2(A) RN2501.1(A) SPI25.3 SSKT2.3
SYS_PWRGD: ED2403.1 KBC24.26 R611.1 R3627.2
SYS_RESET#: CPU1.AY7 R1926.1 R1927.1
T_CRIT#: R2601.1 R2604.2 THM26.4
TEMPINRETURN: CPU1.A23 R412.2
THERM_SYS_SHDN#: Q2602.S R2601.2 R2607.2
THM_SML1_CLK: C2608.1 Q2601.4 RN2601.4(B) RN2602.4(B) THM26.8
THM_SML1_DATA: C2609.1 Q2601.1 RN2601.3(B) RN2602.3(B) THM26.7
TOUCH_PANEL_INTR#: D2401.A R2411.1 R2443.1 R5205.2
TOUCH_PANEL_INTR_KBC#: KBC24.124 R2411.2
TP41: CPU1.AP29 TP421.1
TP_LOCK#: AFTP6242.1 R2454.2 TPAD1.3
TP_LOCK#_R: KBC24.23 R2454.1
TP_ON#: KBC24.33 R2452.1 R2453.1 R6218.1
TP_ON#_GATE: C6205.2 Q6204.G Q6205.G R6218.2
TP_ON#_S: C6205.1 Q6204.S R6215.2 R6216.1 R6217.2
TP_RESET: AFTP5214.1 C5214.1 LCD1.38 R5448.1
TP_RS: AFTP5209.1 C5208.1 LCD1.37 R5205.1
TP_SMB1_CLK: EC6207.1 Q6202.1 R6212.1 RN6201.2(A)
TP_SMB1_CLK_R: AFTP6237.1 R6212.2 TPAD1.6
TP_SMB1_DATA: EC6206.1 Q6202.4 R6213.1 RN6201.1(A)
TP_SMB1_DATA_R: AFTP6240.1 R6213.2 TPAD1.7
TP_VDD: AFTP6239.1 C6202.1 Q6204.D R6203.2 R6209.2 R6214.1 R6216.2 RN6203.1(A) RN6203.2(A) TPAD1.8
TP_WAKE_KBC#: KBC24.63 R2448.2
TPAN_VDD: F5203.2 LCD1.40 R5232.1
TPAN_VDD_F: F5203.1 R5230.2 R5231.2 R5232.2
TPCLK: EC6205.1 KBC24.72 R6210.1 RN6203.4(B)
TPCLK_C: AFTP6238.1 R6210.2 TPAD1.1
TPDATA: EC6208.1 KBC24.71 R6211.1 RN6203.3(B)
TPDATA_C: AFTP6236.1 R6211.2 TPAD1.2
TPS51216_PHS_SET: PC4922.1 PR4912.2
USB3_PRX_CTX_N0: CPU1.V1 R3411.1 TR3402.1
USB3_PRX_CTX_N0_C: R3411.2 TR3402.2 U3402.1 U3402.10 USB1.5
USB3_PRX_CTX_P0: CPU1.V2 R3410.1 TR3402.4
USB3_PRX_CTX_P0_C: R3410.2 TR3402.3 U3402.2 U3402.9 USB1.6
USB3_PTX_CRX_N0: C3403.1 CPU1.T1
USB3_PTX_CRX_N0_C: C3402.1 R3409.2 TR3401.2 U3402.4 U3402.7 USB1.8
USB3_PTX_CRX_N0_R: C3403.2 R3409.1 TR3401.1
USB3_PTX_CRX_P0: C3404.1 CPU1.T2
USB3_PTX_CRX_P0_C: C3401.1 R3408.2 TR3401.3 U3402.5 U3402.6 USB1.9
USB3_PTX_CRX_P0_R: C3404.2 R3408.1 TR3401.4
USB20_VCCA: AFTP6311.1 C3406.1 C3519.1 C3520.1 C3521.1 CN6301.10 CN6301.11 CN6301.12 CN6301.13 CN6301.14 EU3404.5 U3503.1
USB30_VCCC: AFTP3401.1 C3405.1 C3507.1 C3508.1 C3512.1 C3513.1 EU3403.5 R3501.1 TC3501.1 U3504.1 USB1.1
USB_ATEST0: CPU1.AJ10 TP416.1
USB_ATEST1: CPU1.AJ8 TP417.1
USB_CAMERA_EDP: LCD1.31 R5207.1 TR5209.2
USB_CAMERA_EDP#: LCD1.30 R5212.1 TR5209.3
USB_OC#0: CPU1.AY8 R650.1 U3503.3
USB_OC#1: CPU1.AW1 R631.1 U3504.3
USB_OC#3: CPU1.AY1 R637.1
USB_PN0: CPU1.AL5 R3414.1 TR3406.4
USB_PN0_C: AFTP6303.1 CN6301.7 EU3404.4 R3414.2 TR3406.3
USB_PN1: CPU1.AJ5 R3412.1 TR3405.1
USB_PN1_C: AFTP6301.1 CN6301.3 EU3404.6 R3412.2 TR3405.2
USB_PN4: CPU1.AF2 R3204.1
USB_PN4_R: R3204.2 U3201.2
USB_PN5: CPU1.AE2 R5801.2 TR5801.3
USB_PN5_R: AFTP5806.1 R5801.1 TR5801.4 WLAN1.5
USB_PN6: CPU1.AD2 R5203.2
USB_PN6_TPNL: LCD1.34 R5203.1
USB_PN7: CPU1.AC2 R5212.2 TR5209.4
USB_PN8: CPU1.AB2 R3401.1 TR3404.4
USB_PN8_C: AFTP3402.1 EU3403.1 R3401.2 TR3404.3 USB1.2
USB_PP0: CPU1.AL4 R3415.1 TR3406.1
USB_PP0_C: AFTP6304.1 CN6301.6 EU3404.3 R3415.2 TR3406.2
USB_PP1: CPU1.AJ4 R3413.1 TR3405.4
USB_PP1_C: AFTP6302.1 CN6301.4 EU3404.1 R3413.2 TR3405.3
USB_PP4: CPU1.AF1 R3205.1
USB_PP4_R: R3205.2 U3201.3
USB_PP5: CPU1.AE1 R5802.2 TR5801.2
USB_PP5_R: AFTP5807.1 R5802.1 TR5801.1 WLAN1.3
USB_PP6: CPU1.AD1 R5204.2
USB_PP6_TPNL: LCD1.35 R5204.1
USB_PP7: CPU1.AC1 R5207.2 TR5209.1
USB_PP8: CPU1.AB1 R3402.1 TR3404.1
USB_PP8_C: AFTP3403.1 EU3403.3 R3402.2 TR3404.2 USB1.3
USB_PWR_EN#: KBC24.91 R2429.1 U3503.4 U3504.4
USB_RCOMP: CPU1.AG4 R1902.2
USB_SS_ZVDD_095: CPU1.AE8 R1910.1
USB_SS_ZVSS: CPU1.AE10 R1909.1
VCORE_EN: PC4660.2 PR4609.1 R3605.2
VD1_EN#: KBC24.66 R2447.2
VD_IN1: C2615.1 C2616.1 KBC24.104 R2610.1 R2611.2 R2622.2
VD_IN1_C: C2615.2 C2616.2 R2610.2 R2612.1
VD_OUT1#: KBC24.110 R2602.1 R2607.1 R2624.2
VRAM SIZE1: CPU1.BA22 R638.2 R641.1
VTT_CT_0.95V: C3619.1 U3603.12
VTT_CT_1.8V: C3618.1 U3603.10
WHITE_LED_BAT: Q6103.C R6101.2
WIFI_RF_EN: KBC24.82 R5805.1
WLAN_DISABLE#1: AFTP5803.1 R5805.2 WLAN1.56
WLAN_WAKE: TP5801.1 WLAN1.55

Pads without a net: CPU1 A6 A7 A19 A20 A29 AA1 AA2 AA4 AA5 AA40 AA41 AB40 AB41 AC4 AC5 AC40 AG1 AG2 AG7 AG8 AK1 AL2 AM1 AP11 AP13 AP17 AP21 AP23 AR27 AU21 AU31 AV13 AV19 AV27 AY12 AY20 AY22 AY23 AY24 AY25 AY27 AY29 B6 B7 BA6 BA10 BA12 BA20 BA23 BA24 BA29 D1 D2 D7 E1 E2 E7 F1 F2 G1 G2 G4 G5 H1 H2 H15 J1 J2 J4 J5 K15 L4 L5 N4 N5 N8 N10 R1 R2 U4 U5 U41 V40 V41 W1 W2 W4 W40 Y40 Y41; D401 2; D3602 2; D3603 2; DCIN1 3; DM1 77 122 125; DM2 77 122 125; EU3403 4 6; HDA27 14 16 23 24; HDD1 4; HDLED1 3; HDMI1 4 11 HP13 HP14; KB1 2 3; KBC24 13 81 96 108 112; KBLIT1 3; LCD1 3 33 39; ODD1 9 16; PU4509 19; PU4601 27; PU5002 7; RN407 1 8; RN4301 4 5; RN5201 4 5; RN5203 4 5; RN6502 4 5; U3201 7 9 12 14 16 19 22 23; U3602 4; U5601 5; U5603 2 3 5 6; WLAN1 6 16 17 19 20 21 22 23 24 25 26 27 28 29 30 31 32 34 36 40 42 48 50 59 60 61 62 64 65 66 67 68 70 71 73 76 77; X3001 2 4

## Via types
v1: diameter 0.508, hole 0.254, TOP to BOTTOM, 2725 vias
v2: diameter 0.356, hole 0.178, TOP to BOTTOM, 877 vias
v3: diameter 0.711, hole 0.406, TOP to BOTTOM, 678 vias

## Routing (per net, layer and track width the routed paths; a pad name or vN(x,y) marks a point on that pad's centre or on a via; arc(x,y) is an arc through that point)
3V5V_CT1: length 3
  TOP w0.203: U3601.12 39.42,16.67
  TOP w0.254: 39.42,16.67 v2(39.42,16.32) 39.42,15.58 39.79,15.2 C3602.1
3V5V_CT2: length 3.1
  TOP w0.203: U3601.10 38.62,16.55
  TOP w0.254: C3601.1 38.91,14.96 38.41,15.45 v2(38.41,15.58) 38.62,15.78 38.62,16.55
3V5V_S0_ON: length 5.2
  TOP w0.127: U3601.5 38.62,20.28 38.47,20.43 38.47,21.66 38.46,21.66 R3609.1 39.21,21.79 v2(39.5,21.5) 39.56,21.44 39.56,20.44 39.42,20.3 U3601.3
3V_5V_EN: length 232.9
  TOP w0.127: PR4527.1 PR4529.1 38.34,63.26 40.94,65.86 v2(41.31,65.86) v1(42.27,65.86) ; D3602.1 160,143.14 R3602.1 157.99,143.06 R3603.1 156.43,140.22 v1(156.27,140.22)
  L3 w0.127: v1(42.27,65.86) 47.18,65.86 50.74,62.3 50.74,61.88 51.4,61.22 70.14,61.22 v1(72.19,59.17) ; v1(146.18,51.93) 146.33,52.08 151.93,52.08 159.11,59.26 159.11,62.67 158.5,63.28 158.5,68.05 159.3,68.85 160.01,68.85 162.95,71.79 165.02,71.79 165.92,72.68 165.92,73.31 166.52,73.91 166.52,74.74 166,75.26 166,75.28 v1(165.81,75.47)
  L4 w0.127: v1(156.27,140.22) 156.27,139.24 157.33,138.17 157.33,132.29 157.78,131.85 157.78,129.66 158.69,128.75 159.53,128.75 161.39,126.88 161.39,124.08 159.96,122.65 159.96,120.38 162.42,117.92 163.12,117.92 166.16,114.88 166.16,90.09 166.69,89.56 166.69,84.73 166.39,84.42 166.39,79.59 166.16,79.36 166.16,76.38 165.81,76.02 v1(165.81,75.47)
  BOTTOM w0.127: v1(146.18,51.93) 146.16,51.93 146.13,51.9 145.73,51.9 145.07,51.24 83.44,51.24 75.51,59.17 v1(72.19,59.17)
3V_5V_POK: length 191.2
  TOP w0.127: v1(36.37,56.46) PR4510.2 37.32,55.76 38.19,54.89 PU4509.7 ; v1(160.33,73.2) 160.23,73.3 158.23,73.3 155.73,75.8 155.73,79.59 149.26,86.07 149.26,88.33 v1(149.54,88.61)
  L3 w0.127: v1(49.89,60.84) 51.06,60.84 51.19,60.72 69.22,60.72 v1(72.14,57.8)
  BOTTOM w0.127: v1(72.14,57.8) 74.29,57.8 74.84,57.24 75.27,57.24 81.78,50.73 146.48,50.73 152.51,56.77 155.61,56.77 158.08,59.24 158.08,62.78 156.32,64.54 156.32,68.3 160.51,72.49 160.51,73.02 v1(160.33,73.2) ; v1(36.37,56.46) v2(36.37,58.94) 36.37,60.02 41.13,64.78 44.17,64.78 44.88,64.08 44.88,63.83 47.86,60.84 v1(49.89,60.84) PR5010.1 ; Q601.2 141.08,91.58 141.33,91.83 141.33,92.87 141.71,93.25 143.62,93.25 144.53,92.34 RN602.2 145.24,92.34 145.45,92.14 145.45,91.58 148.52,88.5 149.44,88.5 v1(149.54,88.61)
5V_HDD_S0: length 1.4
  TOP w0.305: AFTP5601.1 164.5,37.65 164.98,38.14 v1(164.98,38.49)
5V_HDMI_CRT_S0: length 9.6
  L3 w0.508: v1(31.58,67.85) 31.58,71.38 33.23,73.04 v3(36.94,73.04)
  vias: v2(29.24,75.73) v3(22.08,70.11) v3(22.08,69.23)
5V_HDMI_CRT_S0_R: length 3.2
  TOP w0.635: HDMI1.HP18 11.4,69.78 ; HDMI1.HP18 12.04,69.22 ; HDMI1.HP18 10.76,69.22 ; 13.16,66.61 HDMI1.9 13.15,66.33
  vias: v2(17.2,72.76)
5V_PWR:
  vias: v2(49.28,35.67)
5V_PWR_2_R: length 4.6
  TOP w0.203: 40.24,51.7 PU4509.13
  TOP w0.508: v2(42.93,50.99) PG4543.1 40.65,50.99 PC4529.1 40.24,51.19 40.24,51.7
5V_S0: length 205.5
  TOP w0.508: v1(165.59,17.41) R2703.1 164.73,18.13 EC9719.1 ; Q6106.E 30.53,9.65 v1(30.59,9.59)
  TOP w1.016: v3(171.51,143.04) 171.3,142.83 171.3,124.73 165.58,119.01 164.83,119.01
  L3 w0.508: v1(165.59,17.41) 167.24,17.41 169.27,19.44 169.27,32.14 168.13,33.28
  L3 w1.016: v3(84.06,153.43) 88.37,149.11 v3(88.37,141.5) ; v3(162.97,154.09) 163.05,154.16 163.05,163.83 160.38,166.5 160.38,170.69 156.94,174.13 147.3,174.13 146.32,173.15 135.96,173.15 133.84,175.27 130.18,175.27 128.14,173.23 119.19,173.23 118.47,173.95 107.55,173.95 105.95,172.35 90.63,172.35 86.52,168.24 86.52,166.69 84.06,164.22 84.06,163.16 87.99,159.22 v3(87.99,159.14)
  BOTTOM w0.508: v3(27.36,77.68) 27.79,78.12 29.45,78.12 30.17,77.39 35.76,77.39 36.38,78.01 36.38,79.22 D5401.3 ; Q6201.E 162.91,116.3 163.34,116.72 v1(163.68,116.72)
  BOTTOM w1.016: v3(162.97,154.09) 163,154.09 164.57,155.66 166.99,155.66 171.05,151.6 171.05,143.39 171.41,143.04 v3(171.51,143.04)
  vias: v2(144.25,8.52) v2(160,38.87) v3(26.52,77.48) v3(40.17,15.91) v3(41,15.89) v3(41.03,15) v3(42.02,15.89) v3(42.04,15) v3(43.03,15.89) v3(43.06,15) v3(44.05,15.89) v3(44.08,15) v3(142.73,9.99) v3(142.73,9.15) v3(142.73,8.27) v3(142.73,7.38) v3(158.6,37.83) v3(159.11,38.62) v3(159.49,37.73) v3(161.93,119.7) v3(162.39,118.91) v3(163.33,119.09) v3(168.84,83.58) v3(168.89,82.66) v3(168.87,81.27) v3(168.89,80.43)
5V_S5: length 321.4
  TOP w0.203: U3601.4 v3(39.02,20.67) ; 60.33,43.46 61.05,44.19 PU4901.12 ; 119.36,135.22 119.36,136.31 119.18,136.49 PU4601.33
  TOP w0.508: v1(159.01,67.93) 158.58,68.36 156.65,68.36 156.6,68.41 156.26,68.41 150.68,73.99 150.68,75.81 v1(149.36,77.13) ; v1(166.73,47.13) 166.73,46.99 165.12,45.38 158.39,45.38 v3(154.64,49.13) ; v3(40.9,9.76) 40.93,9.74 Q6104.E 42.34,10.55 42.2,10.69 Q6103.E ; v1(170.01,69.84) 170.42,70.24 170.42,72.73 169.78,73.36 169.78,77.08 170.42,77.71 170.42,86.47 169.78,87.11 169.78,89.2 169.18,89.79 165.5,89.79 164.57,88.86 v1(164.57,87.92) ; PR4610.2 117.46,147.1 117.1,147.46 v1(117.1,148.06) ; PR4203.1 v1(79.99,176.16) ; PR4660.2 114.93,133.74 119.01,133.74 PC4608.1 ; PC4608.1 119.03,134.88 119.36,135.22 ; PC4608.1 124.84,133.77 v1(125.57,134.5)
  TOP w0.762: 60.33,43.46 59.8,42.94 PC4901.1 54.73,42.58
  L3 w0.508: v1(164.57,87.92) 164.22,88.28 164.22,108.43 161.32,111.33 v1(157.73,111.33) ; v3(154.64,49.13) 154.64,51.09 158.18,54.62 v1(159.19,54.62)
  L4 w0.508: v1(129.14,140.73) 137.98,131.89 137.98,122.31 143.53,116.76 153.55,116.76 156.13,114.19 156.13,112.75 157.55,111.33 v1(157.73,111.33) ; v1(159.19,54.62) 159.19,64.45 158.17,65.47 158.17,67.5 158.6,67.93 v1(159.01,67.93) ; v1(79.99,176.16) 79.29,176.86 75.86,176.86 74.05,175.06 74.05,167.03 74.83,166.25 76.82,166.25 80.32,162.75 84.4,162.75 85.27,161.88 89.19,161.88 90.28,160.79 96.13,160.79 99.67,157.25 107.79,157.25 116.98,148.06 v1(117.1,148.06) ; v1(170.01,69.84) 169.83,69.84 169.27,69.28 169.27,65.31 169.97,64.61 169.97,51.16 166.73,47.92 v1(166.73,47.13)
  BOTTOM w0.203: v1(149.36,77.13) 149.33,77.1 U3603.4
  BOTTOM w0.305: PU4806.7 153.39,111.65 153.72,111.33
  BOTTOM w0.508: v1(157.73,111.33) PC4829.1 153.72,111.33 ; PR4661.2 125.65,134.58 v1(125.57,134.5) 126.56,134.5 129.28,137.23 129.28,140.58 v1(129.14,140.73) 129.14,140.87 125.39,144.62 125.39,146.54 122.6,149.34 118.38,149.34 v1(117.1,148.06)
  BOTTOM w1.016: v3(40.9,9.76) 45.79,14.65 45.79,19.48
  vias: v2(54.21,15.63) v2(140.82,13.73) v2(149.08,30.11) v2(151.75,47.38) v3(28.2,67.27) v3(28.23,60.79) v3(28.4,66.25) v3(29.04,67.3) v3(29.12,60.79) v3(29.24,66.46) v3(36.18,61.86) v3(36.43,60.97) v3(37.12,62.49) v3(37.07,61.61) v3(42.71,21.88) v3(42.71,20.74) v3(43.54,21.85) v3(43.54,20.71) v3(44.56,21.85) v3(44.56,20.71) v3(45.57,21.85) v3(45.57,20.71) v3(46.59,21.85) v3(46.59,20.71) v3(54.46,44.33) v3(54.97,50.94) v3(54.97,50.05) v3(55.23,43.7) v3(156.27,28.08) v3(156.34,27.21) v3(156.62,26.38)
+3V_1D5V_AVDD: length 25.6
  TOP w0.305: R2705.2 v2(149.71,16.65) 149.37,16.65 148.69,15.97 148.69,15.27 148.32,14.9 v1(148.32,13.47)
  L3 w0.305: v1(149.38,6.92) 149.55,6.75 156.18,6.75 v1(157.89,8.47)
  BOTTOM w0.203: v1(157.89,8.47) 157.77,8.47 157.55,8.69 HDA27.40
  BOTTOM w0.305: C2715.1 159.49,6.74 157.89,8.34 v1(157.89,8.47) ; v1(149.38,6.92) 149.38,6.95 148.32,8.01 v1(148.32,13.47)
+3V_AVDD: length 25.7
  TOP w0.305: v1(160.3,8.89) 160.31,8.88 160.31,8.86 160.71,8.46 R2701.2 ; v1(152.89,19.82) v2(152.89,19.19)
  L3 w0.305: v1(152.89,19.82) 152.51,19.82 152.09,19.4 152.09,15.8 153.4,14.49 153.4,10.55 153.91,10.04 156.32,10.04 157.21,10.93 159.24,10.93 160.18,9.99 160.18,9.03 160.3,8.91 v1(160.3,8.89)
  BOTTOM w0.203: HDA27.36 159.57,10.09
  BOTTOM w0.305: 159.57,10.09 159.93,9.74 160.21,9.74 161.27,8.67 C2701.1 160.66,8.55 160.32,8.89 v1(160.3,8.89) ; R2722.1 v1(152.89,19.82)
+5V_AVDD: length 4
  TOP w0.508: R2703.2 163.41,16.52 163.15,16.27 v2(163.05,16.27) 162.8,16.27 162.35,15.82 C2710.1 160.83,15.82 v1(160.64,15.63)
+5V_KB_BL:
  vias: v3(160.51,121.93) v3(161.91,122.95) v3(162.8,122.97) v3(163.66,123.58)
+5V_PVDD:
  vias: v2(150.98,10.32) v2(155.71,7.28) v3(154.11,8.11) v3(157.74,7.39)
GND: length 1248.6
  TOP w0.203: PU4601.32 118.78,136.25 118.83,136.21 118.83,136.12 v1(118.87,136.08) ; PU4901.4 61.05,48.29 v1(60.43,48.91) ; PU4901.7 58.94,46.64 v1(58.78,46.8) ; PU4901.10 59.28,45.44 58.91,45.07 v1(57.89,45.07)
  TOP w0.305: ODD1.1 166.51,76.57 166.68,76.74 166.68,77.89 166.5,78.07 ODD1.4 v1(164.27,78.07) ; LCD1.23 93.7,145.52 v1(93.2,145.02) ; LCD1.36 93.45,139.02 ; LCD1.29 95.01,142.52 95.13,142.4 v1(95.24,142.4) ; THM26.5 v1(76.98,59.32) ; v1(95.36,147.69) 95.19,147.52 LCD1.19 ; v1(167.32,78.6) 167.32,78.93 166.68,79.57 ODD1.7 v1(164.58,79.57) R5604.2 ; LCD1.24 94.65,145.02 94.72,144.95 94.76,144.95 94.92,144.79 94.92,144.74 95.05,144.61 v1(95.1,144.61) 95.01,144.52 LCD1.25 ; PQ4408.4 120.54,159.51 v1(120.43,159.4) ; PU4404.14 129.29,153.16 v1(129.78,152.66) ; LCD1.16 v1(95.36,149.02) ; G701.2 134.6,94.54 134.32,94.26 v1(134.32,94.09) ; LCD1.13 v1(93.29,150.52)
  TOP w0.33: EC6208.2 53.31,77.29 52.43,78.17 v1(52.43,78.67) ; v1(110.54,79.37) 110.94,79.77 C1063.1 ; AFTP6314.1 164.83,47.49 v1(164.86,47.52) ; PC4606.2 v1(126.63,137.7)
  TOP w0.356: U5603.13 38.56,71.67 v1(38.84,71.38) ; v1(37.75,69.96) 37.68,69.96 37.43,69.72 U5603.10 ; v1(32.24,68.82) 32.16,68.82 31.76,68.42 U5603.7 ; v1(122.77,93.36) 122.77,92.93 R1909.2 ; U3102.8 U3102.3 37.78,173.62 38.48,172.92 EC3107.1 EC3106.1 39.8,173.81 v1(40.11,173.49)
  TOP w0.406: TPAD1.5 v1(61.07,76.77) ; PQ4203.4 83.16,161.44 v1(83.17,161.43) ; PC4425.2 121.84,163.16 PQ4408.1 121.84,161.74 122.28,161.3 v1(122.28,161.17) ; U5201.2 103.22,153.7 103.67,153.24 103.68,153.22 v1(103.74,153.22) ; PQ4402.1 107.45,174.2 107.02,174.64 v1(107.02,174.66) ; PQ4410.1 113.12,162.68 113.39,162.95 v1(113.77,162.95) 114.15,162.95 114.42,163.22 PQ4410.4
  TOP w0.508: v1(117.06,73.79) 116.62,73.35 C1056.1 ; C5214.2 100.18,135.9 100.57,136.28 v1(100.57,137.68) C5208.2 ; PD4203.1 v1(78.85,167.71) ; R423.2 97.07,87.32 97.09,87.34 97.13,87.34 98.32,88.53 v1(98.76,88.53) ; PC4602.2 119.08,147.08 PC4660.1 119.68,147.46 119.31,147.83 v1(119.31,147.97) ; PR4467.2 v1(116.76,163.9) ; v1(80.69,165.81) PR4216.2 ; CN6301.8 v1(167.63,37.77) ; v1(123.58,101.48) 124.15,102.06 R1902.1 ; EC6106.2 v1(32.56,7) ; C5802.2 162.39,8.46 162.5,8.34 v1(162.75,8.34) ; C5539.2 v1(24.87,62.49) ; PQ4202.E v1(82.09,170.83) ; v1(122.29,80.05) 122.28,80.05 122.28,79.62 122.27,79.61 C1058.1 ; C1002.2 139.91,96.89 C705.2 139.91,98.73 C2503.1 140,99.29 140.37,99.66 v1(141.23,99.66) ; C1221.2 86.02,28.57 85.91,28.46 85.91,28.22 85.54,27.85 85.3,27.85 v1(85.28,27.82) ; PR4470.1 116.07,166.5 v1(115.81,166.76) ; v1(167.65,47.71) 168.44,46.92 CN6301.25 ; C2411.2 v1(146.79,122.44) ; R632.2 127.17,83.45 127.34,83.28 v1(127.34,82.72) ; R2437.2 v1(154.29,119.14) ; PR4464.2 v1(112.5,158.89) ; EC6208.2 55.27,77.29 55.86,76.69 EC6207.2 ; v1(153.75,125.99) C2410.2 ; EC3305.2 29.51,27.13 28.3,28.33 28.3,30.3 EC3307.2 27.99,30.96 27.34,31.61 v1(27.26,31.61) ; v1(120.34,91) 120.37,91 120.74,91.36 C1035.2 C1012.2 ; R3602.2 157.02,144.44 156.95,144.51 156.95,144.73 ED2403.2 156.71,144.92 C2408.2 v1(155.87,146.23) ; v1(152.03,133.36) 152.05,133.36 152.52,132.89 R2612.2 ; PR5013.2 v1(47.99,61.61) ; PR4908.2 v1(67.11,47.51) ; EC3201.2 v1(30.14,21.28) ; v1(111.92,145.48) 112.67,145.48 PR4619.1 PC4619.1 ; LED1.3 v1(25.18,1.97) ; v1(114.09,147.9) 114.1,147.9 114.42,147.58 115.55,147.58 116.57,146.57 PR4611.1 ; R651.2 132.9,105 v1(132.9,105.52) ; v1(160.97,128.74) 161.31,128.4 C6203.2 161.37,127.96 R6207.2 161.31,127.01 R2447.1 160.57,126.67 v1(159.98,126.07) ; Q6203.S 163.66,131.79 v1(163.66,131.2) 163.91,131.2 164.23,130.88 R6208.2 ; C3612.2 C3607.2 152.01,25.73 152.53,25.21 v1(152.53,24.65) ; v1(68.69,10.55) 68.31,10.93 AFTP2501.1 ; C1059.1 121.55,75.87 v1(121.6,75.91) ; PQ4208.S v1(78.58,163.49) ; C1062.1 113.08,75.71 v1(112.89,75.9) ; C5202.2 v1(97.2,158.19) ; v1(159.98,136.92) 159.43,136.37 159.43,136.16 159.3,136.03 C2409.2 ; C1333.2 90.47,18.3 v1(90.45,18.28) ; R5524.1 v1(25.76,62.49) ; v1(115.04,75.9) 114.95,75.81 C1061.1 114.96,75.14 C1050.2 ; PC4917.2 v1(62.72,52.08) ; EC2503.2 151.03,122.65 v1(151.09,122.72) ; v1(124.92,93.57) 124.54,93.19 124.54,92.38 C1037.2 C1034.2 ; C3001.2 50.79,173.53 v1(50.77,173.51) ; PR4218.2 80.6,161.36 v3(80.43,161.2) ; v1(144.18,127.34) 144.06,127.23 144.06,127.12 143.58,126.63 EC9707.2 ; C5540.2 R5523.1 26.46,64.46 v1(26.65,64.27) 27.2,63.73 C5508.2 ; C1060.2 112.4,73.35 v1(112.43,73.33) ; PR4523.2 v1(43.29,59.45) ; EC3304.2 28.52,12.67 27.34,13.85 25.48,13.85 ; R621.2 125.48,87.92 v1(125.15,88.25) 124.98,88.42 C1022.2 124.92,89.04 124.92,89.8 C1001.2 ; v1(136.76,106.26) 137.77,106.26 137.82,106.31 139.54,106.31 EC2502.2 ; PC4906.2 66.51,44.85 66.68,45.02 v1(67.04,45.02) ; C2416.2 160.55,138.5 v1(160.5,138.46) ; PC4614.1 114.83,144.38 115.08,144.13 115.08,143.75 115.09,143.74 v1(115.09,143.5) ; v1(136,175.97) D4301.1 ; EC6105.2 v1(42.78,6.61) ; C1338.2 C1340.2 v1(143.43,15.31) ; PR4405.2 v1(153.4,166) ; C2406.2 v1(144.95,137.49) ; C1017.2 95.02,90.52 v1(94.99,90.55) ; C2608.2 74.1,62.96 v1(74.1,63) ; v1(135.57,140.47) 135.43,140.33 EC9715.2 ; PR4902.2 v1(67.09,46.62) ; 4.66,161.4 4.9,161.64 RJ45.9 7.89,161.64 8.19,161.35 ; R425.2 91.61,85.37 91.3,85.68 v1(91.02,85.68) ; EC6206.2 v1(56.79,73.48) ; C3002.2 52.36,174.41 v1(52.61,174.66) ; v1(134.02,172.81) 133.09,172.81 EC9711.2 ; v1(72.88,46.57) 72.88,47.23 72.85,47.25 C2601.2 72.3,51.65 71.94,52.01 71.94,53.74 C2602.2 ; v1(136,177.43) 136.13,177.56 EC4301.2 ; C1049.2 110.51,75.83 v1(110.67,75.99) ; C2609.2 v1(77.34,63.12) ; v1(90.53,137.04) 90.09,137.49 90.09,138 91.11,139.02 93.45,139.02 ; EC4203.2 v1(110.68,162.75) ; EC3302.2 v1(27.73,8.38) ; v1(130.41,159.12) 130.28,159.24 130.28,159.28 129.97,159.6 PR4432.2 ; USB1.13 5.27,30.92 5.32,30.87 ; EC9714.2 v1(66.28,67.57) ; v1(169.81,125.16) 168.65,126.31 KBLIT1.6 ; Q2404.C v1(157.78,134.19) ; C5510.2 23.11,69.11 v1(23.22,69.23) ; DB1.11 169.76,142.38 v1(168.99,143.14) 168.8,143.33 SPR4.1 ; C6202.2 58.15,73.04 v1(57.72,73.47) ; v1(31.35,73.92) 31.35,74.18 31.1,74.43 R5412.2 ; EC9740.2 v1(74.09,66.79) ; C2610.2 79.78,56.61 v1(79.62,56.77) ; v1(101.4,158.41) 101.4,158.3 100.86,157.76 99.94,157.76 99.3,158.41 C5205.1 ; v1(123.3,145.6) 123.27,145.6 123.21,145.54 122.52,145.54 PC4607.1 PR4606.1 ; PR4531.1 v1(41,63.59) ; C1204.2 60.24,51.51 v1(60.31,51.45) PC4915.2 PC4918.2 ; C5511.2 27.37,66.29 27.12,66.55 26.69,66.55 25.7,67.54 C5509.2 28.33,68.36 v1(29.47,69.51) ; v1(129.68,96.21) 129.68,97.7 129.97,97.99 R702.2 131.36,98.05 132.41,98.05 Q701.S 132.94,97.53 R644.2 R620.2 ; AFTP6235.1 164.86,63.6 v1(164.86,63.02) ; D4303.1 v1(141.05,174.89) ; v1(26.02,11.06) 26.13,10.95 EC3303.2 ; EC6205.2 54.55,79.96 54.54,79.97 53.88,79.97 v1(53.83,80.02) ; R2445.2 v1(151.11,147.97) ; Q2403.S 155.54,138.14 v1(154.9,138.14) ; C1045.2 125.31,85.44 125.64,85.11 125.64,85.01 v1(125.81,84.84) 125.97,85 125.97,85.08 126.34,85.46 126.4,85.46 R1903.1 ; DB1.12 169.76,129.25 169.78,129.22 169.78,129.19 v1(169.8,129.17) ; PR4511.2 v1(44.18,59.6) ; C501.2 C502.2 105.91,75.2 v1(105.84,75.26) ; EC3301.2 v1(30.21,24.39) ; PR4518.2 37.57,59.32 v1(37.19,59.7) 36.68,59.19 PR4507.2 ; v1(153.04,22.06) 153.11,22.12 R2717.2 ; CN6301.2 165.61,43.77 v1(164.86,44.52) 165.37,44.52 165.62,44.77 CN6301.1 ; PC4401.2 124.51,160.65 PR4433.2 v1(123.58,159.88) ; PC4622.2 112.5,137.78 v1(112.43,137.7) ; v1(45.19,6.61) 45.32,6.49 EC6103.2 ; v1(29.19,77.1) 28.99,76.9 EC9725.2 ; PC4616.1 PR4625.2 v1(111.89,141.36) ; EC4305.1 v1(145.02,177.56) ; C2415.1 ED2401.2 150.85,141.22 v1(151.34,141.71) 152.05,142.42 ED2402.2 ; v1(168.82,138.29) 168.45,138.66 DB1.3 ; EC9756.2 v1(75.74,17.98) ; C1038.2 144.66,85.27 C1036.2 144.32,86.18 143.9,86.6 v1(143.9,87.82) ; DB1.1 168.56,140.66 168.91,140.3 v1(168.92,140.3) ; v1(130.28,165.11) 129.92,164.74 PR4436.2 ; R2706.2 v1(164.9,3.72) ; C5204.2 103.84,148.96 v1(104.12,149.24) ; R3626.2 v1(151.54,22.49) ; PR5020.2 v1(44.43,63.89) ; C5542.2 v1(21.57,62.49) ; EC4302.2 v1(140.06,177.56) ; PQ4204.E v1(111.13,164.75) ; C2719.2 151.05,18.03 v1(150.86,18.22) ; PC4209.2 v1(79.48,165.62) ; R3015.2 v1(56.19,167.4) ; C1055.2 108.03,73.41 v1(107.85,73.6) 108.43,74.18 EC9752.2 ; CN6301.5 v1(167.71,40.77) ; v1(155,25.79) 155.32,25.47 EC9744.2 ; HDLED1.2K v1(19.1,2.36) ; C5543.2 v1(20.87,64.46) ; EC3306.2 v1(30.33,22.87) ; D4302.1 v1(144.98,174.89) ; EC9710.2 v1(33.95,54.62) ; PC4901.2 v1(59.8,40.27) ; PC4916.2 v1(61.45,52.08) ; PR4202.2 v1(81.52,172.67)
  TOP w0.635: USB1.4 15.18,36.47 ; USB1.4 14.47,35.76 ; USB1.4 14.47,37.18 ; USB1.11 15.4,33.57 ; USB1.11 13.72,32.68 ; USB1.11 13.72,34.46 ; 12.04,73.45 HDMI1.PTH3 10.6,71.48 ; 13.25,29.18 CARD1.15 ; CARD1.15 13.25,30.86 ; CARD1.15 11.07,30.02 ; CARD1.15 15.43,30.02 ; 151.06,179.77 BATT1.8 ; BATT1.8 152.05,180.76 ; BATT1.8 152.05,178.78 ; 8.87,75.97 HDMI1.PTH2 10.25,76.96 ; 10.6,58.96 HDMI1.PTH8 12.04,57.97 ; 11.4,60.66 HDMI1.HP2 ; HDMI1.HP2 12.04,61.22 ; HDMI1.HP2 10.76,61.22 ; USB1.10 13.72,47.26 ; USB1.10 13.72,45.48 ; USB1.10 15.4,46.37 ; 3.02,77.01 HDMI1.PTH6 3.86,76.55 ; 169.17,177.84 BATT1.9 170.22,179.77 ; 12.97,39.26 USB1.7 12.97,40.68 ; 11.07,3.72 CARD1.14 ; CARD1.14 13.25,2.88 ; CARD1.14 15.43,3.72 ; CARD1.14 13.25,4.56 ; 148.93,177.84 BATT1.10 ; BATT1.10 149.97,179.77 ; BATT1.10 147.88,179.77 ; 156.47,180.75 BATT1.6 156.05,180.76 ; 13.8,59.11 HDMI1.6 13.16,59.74 ; HDMI1.PTH10 7.24,54.27 ; HDMI1.PTH10 5.5,53.38 ; HDMI1.PTH10 5.5,55.16 ; 5.5,75.28 HDMI1.PTH4 7.24,76.17 ; USB1.12 5.27,48.35 6.08,49.16 ; 8.36,180.73 7.93,180.3 RJ45.10 4.74,180.3 4.43,180.6 ; HDMI1.PTH7 15.24,54.27 ; HDMI1.PTH7 13.5,53.38 ; HDMI1.PTH7 13.5,55.16 ; 10.25,53.48 HDMI1.PTH9 8.87,54.47 ; 5.7,74.89 5.18,74.37 HDMI1.PTH5 ; 13.5,75.28 HDMI1.PTH1 ; HDMI1.PTH1 13.5,77.06 ; HDMI1.PTH1 15.24,76.17 ; HDMI1.PTH11 5.26,56.07 5.7,55.64
  L3 w0.508: 8.21,161.33 7.89,161.64 RJ45.9 4.9,161.64 4.63,161.38 ; 5.82,55.64 5.39,56.07 HDMI1.PTH11 ; HDMI1.HP11 10.62,65.72 ; HDMI1.HP5 10.62,62.72 ; HDMI1.HP17 10.57,68.72
  L3 w0.635: HDMI1.PTH10 5.5,55.16 ; HDMI1.PTH10 7.24,54.27 ; HDMI1.PTH10 5.5,53.38 ; 13.16,64.32 HDMI1.8 14.44,64.32 ; 10.76,61.22 HDMI1.HP2 ; HDMI1.HP2 11.4,60.66 ; HDMI1.HP2 12.04,61.22 ; 152.47,180.75 BATT1.8 152.05,180.76 ; 13.25,29.18 CARD1.15 ; CARD1.15 15.43,30.02 ; CARD1.15 11.07,30.02 ; CARD1.15 13.25,30.86 ; USB1.13 5.27,30.92 ; 10.25,76.96 HDMI1.PTH2 8.87,75.97 ; 10.6,71.48 HDMI1.PTH3 12.04,72.47 ; 13.72,47.26 USB1.10 13.72,45.48 ; HDMI1.6 14.44,59.74 ; HDMI1.6 13.16,59.74 ; HDMI1.6 13.8,59.11 ; 14.44,68.9 HDMI1.10 13.16,68.9 ; CARD1.14 15.43,3.72 ; CARD1.14 13.25,2.88 ; CARD1.14 13.25,4.56 ; CARD1.14 11.07,3.72 ; 13.16,62.03 HDMI1.7 14.44,62.03 ; 13.5,55.16 HDMI1.PTH7 13.5,53.38 ; 147.88,180.74 BATT1.10 149.97,180.74 ; USB1.11 13.72,34.46 ; USB1.11 15.4,33.57 ; USB1.11 13.72,32.68 ; 170.22,180.74 BATT1.9 168.13,180.74 ; 13.5,75.28 HDMI1.PTH1 ; HDMI1.PTH1 15.24,76.17 ; HDMI1.PTH1 13.5,77.06 ; 10.76,64.22 HDMI1.HP8 12.04,64.22 ; 8.87,54.47 HDMI1.PTH9 10.25,53.48 ; USB1.4 15.18,36.47 ; USB1.4 14.47,35.76 ; USB1.4 14.47,37.18 ; 12.97,39.26 USB1.7 ; USB1.7 12.97,40.68 ; USB1.7 13.68,39.97 ; 3.86,76.55 HDMI1.PTH6 3.02,77.01 ; 8.36,180.73 7.93,180.3 RJ45.10 4.74,180.3 4.43,180.6 ; 13.8,70.69 HDMI1.5 13.16,70.05 ; 156.05,180.76 BATT1.6 156.47,180.75 ; 12.04,57.97 HDMI1.PTH8 10.6,58.96 ; 7.24,76.17 HDMI1.PTH4 5.5,75.28 ; 5.52,74.79 5.1,74.37 HDMI1.PTH5 ; USB1.12 5.27,49.08
  L4 w0.508: 5.82,55.64 5.39,56.07 HDMI1.PTH11 ; 4.6,161.35 4.9,161.64 RJ45.9 7.89,161.64 8.16,161.38
  L4 w0.635: HDMI1.PTH7 13.5,55.16 ; HDMI1.PTH7 13.5,53.38 ; HDMI1.PTH7 15.24,54.27 ; USB1.11 13.72,34.46 ; USB1.11 15.4,33.57 ; USB1.11 13.72,32.68 ; CARD1.15 15.43,30.02 ; CARD1.15 11.07,30.02 ; CARD1.15 13.25,30.86 ; CARD1.15 13.25,29.18 ; 10.6,58.96 HDMI1.PTH8 12.04,57.97 ; 10.6,71.48 HDMI1.PTH3 12.04,72.47 ; 5.27,30.97 USB1.13 ; 11.4,60.66 HDMI1.HP2 ; HDMI1.HP2 12.04,61.22 ; HDMI1.HP2 10.76,61.22 ; 11.07,3.72 CARD1.14 ; CARD1.14 15.43,3.72 ; CARD1.14 13.25,4.56 ; CARD1.14 13.25,2.88 ; HDMI1.6 14.44,59.74 ; HDMI1.6 13.16,59.74 ; HDMI1.6 13.8,59.11 ; 5.5,53.38 HDMI1.PTH10 ; HDMI1.PTH10 5.5,55.16 ; HDMI1.PTH10 7.24,54.27 ; USB1.7 13.68,39.97 ; USB1.7 12.97,40.68 ; USB1.7 12.97,39.26 ; 170.22,180.74 BATT1.9 168.13,180.74 ; 14.47,35.76 USB1.4 ; USB1.4 14.47,37.18 ; USB1.4 15.18,36.47 ; HDMI1.PTH1 13.5,77.06 ; HDMI1.PTH1 15.24,76.17 ; HDMI1.PTH1 13.5,75.28 ; 156.47,180.75 BATT1.6 156.05,180.76 ; 4.43,180.6 4.74,180.3 RJ45.10 7.93,180.3 8.36,180.73 ; 5.6,74.92 5.05,74.37 HDMI1.PTH5 ; USB1.10 13.72,47.26 ; USB1.10 13.72,45.48 ; USB1.10 15.4,46.37 ; 8.87,75.97 HDMI1.PTH2 10.25,76.96 ; 10.25,53.48 HDMI1.PTH9 8.87,54.47 ; 7.24,76.17 HDMI1.PTH4 5.5,75.28 ; 147.88,180.74 BATT1.10 149.97,180.74 ; 3.86,76.55 HDMI1.PTH6 3.02,77.01 ; 152.47,180.75 BATT1.8 152.05,180.76
  BOTTOM w0.152: CPU1.A13 CPU1.B13
  BOTTOM w0.203: KBC24.5 v1(149.42,144.64) ; v1(154.13,142.25) 154.29,142.25 154.62,142.58 KBC24.18 ; KBC24.89 150.62,128.93 v1(150.78,129.09) ; v1(159.98,136.92) 160.13,136.92 160.26,137.04 160.85,137.04 160.88,137.07 KBC24.45 ; v1(151.34,141.71) 151.38,141.71 152.22,142.54 KBC24.12 ; v1(144.95,137.49) 145.16,137.28 145.21,137.28 145.42,137.07 KBC24.116 ; KBC24.78 v1(155.02,129.3)
  BOTTOM w0.254: CPU1.BA39 129.48,75.53 129.48,75.53 v1(129.66,75.34) ; CPU1.AW3 127.67,95.35 126.62,95.35 CPU1.AU3 CPU1.AU2 ; CPU1.G41 110.1,73.42 110.16,73.35 v1(110.16,73.32) ; CPU1.R41 114.51,74.17 114.51,74.14 114.51,74.13 114.51,73.86 v1(114.76,73.61) ; CPU1.AW41 127.75,73.7 v1(127.97,73.48) ; v1(113.24,97.93) 113.95,97.22 CPU1.P1 CPU1.P2 114.3,95.38 CPU1.R3 ; CPU1.E4 108.64,94.68 v1(108.35,94.97) 108.28,94.97 107.9,94.59 CPU1.C5 ; CPU1.AY15 128.49,88.68 128.8,88.68 128.81,88.69 129.01,88.69 CPU1.BA15 ; CPU1.AR41 125.5,73.48 v1(125.65,73.32) ; CPU1.C23 107.92,84.41 107.92,85.45 CPU1.C21 ; CPU1.AL41 123.3,73.44 v1(123.46,73.28) ; v1(105.85,77.69) 105.93,77.78 CPU1.A35 ; CPU1.W41 116.7,74.14 117.04,73.79 v1(117.06,73.79) ; v1(129.77,80.11) 129.64,79.98 129.1,79.98 CPU1.BA31 ; CPU1.M1 CPU1.M2 ; v1(126.6,97.36) 126.6,97.27 126.6,97.26 CPU1.AU1 ; v1(121.21,73.25) 121.1,73.36 CPU1.AG41 ; v1(105.84,75.26) 106.11,75.53 106.36,75.53 ; v1(118.51,73.73) 118.51,73.77 118.9,74.16 CPU1.AC41 ; CPU1.A31 106.53,79.95 107.16,79.95 CPU1.B31 ; CPU1.E38 108.47,76.28 v1(108.27,76.08) ; CPU1.C41 v1(107.85,73.6) ; v1(112.43,73.33) 112.3,73.46 CPU1.L41
  BOTTOM w0.305: CPU1.AN3 124.16,95.38 v1(123.88,95.1) 123.6,95.38 CPU1.AL3 ; CPU1.A15 106.33,88.94 v1(105.65,88.94) ; CPU1.C2 107.9,96.35 107.85,96.4 CPU1.C1 107.85,96.95 v1(108.19,97.29) ; DM1.71 97.25,40.44 94.72,42.96 93.99,43.7 v1(93.45,43.7) ; v1(127.35,79.43) 127.7,79.78 CPU1.AW31 128.05,80.33 CPU1.AY30 ; CPU1.B13 CPU1.C13 ; CPU1.C13 107.9,89.55 107.95,89.5 107.95,89.16 107.9,89.11 CPU1.C15 ; CPU1.C13 107.9,90.07 108.18,90.35 108.18,90.53 ; WLAN1.69 v1(164.86,46.02) ; v1(108.27,76.08) 107.9,75.7 CPU1.C39 CPU1.B39 ; v1(108.27,76.08) 107.9,76.45 CPU1.C37 ; v1(108.27,76.08) 108.77,75.58 CPU1.E39 ; CPU1.AE39 120.1,75.68 120.99,75.68 CPU1.AG39 121.41,75.89 121.6,75.89 ; WLAN1.75 v1(164.86,44.52) ; WLAN1.51 164.36,50.52 164.83,50.05 v1(164.95,50.05) ; 115.04,75.87 114.79,75.87 CPU1.R39 ; 115.04,75.87 115.3,75.87 CPU1.U39 115.66,75.58 115.71,75.63 116.31,75.63 116.37,75.58 CPU1.W39 116.77,75.65 117.72,75.65 CPU1.AA39 117.85,75.63 118.84,75.63 CPU1.AC39 ; 115.04,75.87 v1(115.04,75.9) ; CPU1.C25 107.9,83.16 108.23,82.83 v1(108.23,82.78) 108.23,82.51 CPU1.C27 ; CPU1.AU3 126.38,95.38 v1(126.04,95.04) 125.69,95.38 CPU1.AR3 ; HDD1.9 v1(168.49,29.63) ; v1(127.43,87.05) 127.43,86.84 CPU1.AW19 ; v1(127.43,87.05) 127.43,87.42 CPU1.AW17 ; v1(127.43,87.05) 127.52,87.13 CPU1.AY18 CPU1.BA18 ; R645.1 133.87,94.2 133.99,94.2 134.1,94.09 v1(134.32,94.09) ; WLAN1.18 v1(169.15,58.77) ; CPU1.N39 113.08,75.9 v1(112.89,75.9) 112.62,75.9 CPU1.L39 ; v1(129.73,93.31) 129.6,93.18 CPU1.BA7 ; DM2.61 99.15,23.83 98.79,23.47 98.79,23.03 99.11,22.71 99.25,22.71 v1(99.34,22.62) ; CPU1.AH2 121.65,95.04 v1(121.69,95) 121.48,95 CPU1.AG3 ; CPU1.AH2 CPU1.AH1 ; CPU1.AH2 121.79,95.73 122.14,95.38 CPU1.AJ3 ; CPU1.G39 110.51,75.99 v1(110.67,75.99) 110.84,75.99 111.2,75.64 CPU1.J39 ; C3402.2 23.29,39.44 v1(23.4,39.56) ; v1(127.42,76.11) 127.7,76.39 CPU1.AW37 ; v1(127.42,76.11) 127.7,75.84 CPU1.AW39 ; v1(127.42,76.11) 126.88,75.58 CPU1.AU39 ; HDD1.12 v1(168.49,28.13) ; v1(120.68,79.89) 120.41,79.89 CPU1.AE32 ; CPU1.B23 CPU1.C23 108.14,84.14 v1(108.14,83.88) ; CPU1.A8 CPU1.B8 ; v1(129.68,96.21) 129.65,96.18 CPU1.BA2 ; CPU1.A39 106.36,75.53 ; CPU1.BA35 129.63,77.78 v1(129.68,77.72) ; CPU1.AU27 126.2,82.05 v1(125.81,81.66) 125.81,81.49 CPU1.AR29 ; CPU1.AU23 125.81,84.77 v1(125.81,84.84) 125.81,85.07 CPU1.AR21 126.2,86.28 CPU1.AU19 ; CPU1.C29 108.18,80.8 v1(108.18,80.49) 108.16,80.49 107.9,80.23 CPU1.C31 CPU1.B31 ; CPU1.AR25 125.4,83.13 v1(125.02,82.75) ; 121.6,75.89 v1(121.6,75.91) ; 121.6,75.89 121.71,75.89 122.03,75.58 CPU1.AJ39 ; Q603.4 137.53,94.54 138.06,94.02 v1(138.06,93.91) ; v1(131.27,84.79) 130.73,85.32 129.26,85.32 CPU1.BA21 ; v1(130.79,89.98) 130.61,89.8 129.18,89.8 CPU1.BA13 129.04,89.82 128.45,89.82 CPU1.AY13 128.32,89.8 127.78,89.8 CPU1.AW13 ; WLAN1.39 164.66,53.52 164.95,53.22 164.95,51.7 ; v1(164.86,63.02) WLAN1.1 ; CPU1.AW21 127.38,85.17 v1(127.38,84.84) 127.7,84.52 CPU1.AW23 ; v1(127.39,92.74) 127.7,93.04 CPU1.AW7 ; WLAN1.33 164.39,55.02 v1(164.88,55.51) ; CPU1.AW35 127.7,77.96 v1(127.31,78.35) 127.7,78.74 CPU1.AW33 ; EC5206.2 99.74,143.77 v1(99.5,143.77) ; v1(129.62,88.84) 129.56,88.78 CPU1.BA15 ; WLAN1.63 v1(164.86,47.52) ; 164.95,51.7 164.63,52.02 WLAN1.45 ; 164.95,51.7 v1(165.03,51.62) ; CPU1.AW25 127.7,83.08 v1(127.34,82.72) 127.7,82.37 CPU1.AW27 ; v1(129.62,83.47) 129.43,83.28 CPU1.BA25 ; EC5802.2 160.19,52.14 v1(159.75,51.7) ; CPU1.C19 107.9,86.82 v1(108.19,87.11) 107.9,87.4 CPU1.C17 ; WLAN1.57 v1(164.86,49.02) ; CPU1.C33 107.9,78.69 v1(108.28,78.31) 107.9,77.92 CPU1.C35 ; CPU1.AL39 123.61,75.9 v1(123.96,75.9) 124.08,75.9 CPU1.AN39 124.72,75.58 124.78,75.63 125.11,75.63 125.17,75.58 CPU1.AR39 ; v1(164.88,61.53) 164.73,61.53 164.72,61.52 WLAN1.7 ; CPU1.Y2 CPU1.Y1 ; CPU1.K19 111.34,86.13 110.76,86.13 110.2,85.56 CPU1.G21 110.52,85.16 110.52,84.86 CPU1.H23 111,84.22 110.2,83.42 CPU1.G25 ; CPU1.AW15 CPU1.AY15 ; 116.13,95.23 115.75,95.23 CPU1.U3 CPU1.U2 115.65,96.14 115.65,96.72 CPU1.U1 115.6,96.94 115.04,97.5 115.04,97.67 v1(114.76,97.95) ; HDD1.6 v1(168.49,31.13) ; CPU1.AC15 CPU1.AA15
  BOTTOM w0.33: v1(131.83,20.53) 129.75,22.62 DM2.155 ; DM2.145 126.75,21.55 v1(128.48,19.82) 128.55,19.89 DM2.151 ; v1(122.61,27.54) 122.45,27.71 122.39,27.71 122.07,28.03 122.07,28.61 121.55,29.13 DM1.144 ; DM1.172 129.95,28.32 130.29,27.99 130.3,27.99 v1(130.42,27.86) ; v1(85.1,19.04) 85.1,18.96 85.05,18.91 DM2.14 ; DM1.2 75.86,29.97 v1(75.04,29.14) ; DM1.133 118.25,39.39 120.73,41.87 v1(121.14,41.87) ; DM1.55 92.45,36.7 v1(91.75,36) 92.08,35.67 94.29,35.67 95.45,36.83 DM1.65 ; v1(143.36,23.16) 143.36,23.66 143.55,23.85 DM2.201 ; DM2.3 81.75,26.19 81.02,26.92 v1(80.04,26.92) 79.95,27.01 79.85,27.01 79.53,27.33 79.53,27.78 80.15,28.4 DM1.14 ; DM1.161 126.65,41.37 126.27,41.74 v1(126.12,41.74) ; DM1.168 128.75,31.71 130.22,33.18 v1(130.39,33.18) ; DM1.156 125.15,28.75 125.25,28.65 125.25,28.54 v1(125.37,28.43) ; DM2.167 133.35,23.51 v1(133.56,23.3) ; DM2.138 124.65,20.78 v1(124.54,20.89) ; DM2.37 91.95,26.34 90.86,27.43 90.8,27.43 v1(90.61,27.62) 90.52,27.71 90.38,27.71 90.06,28.03 90.06,28.67 90.35,28.96 DM1.48 ; v1(128.18,27.67) 127.87,27.67 127.3,28.24 127.3,28.41 126.95,28.75 DM1.162 ; DM2.128 121.65,19.16 v1(122.03,19.54) ; DM2.31 90.15,26.05 88.59,27.61 88.23,27.61 v1(88.12,27.72) 88.21,27.81 88.35,27.81 89.15,28.62 DM1.44 ; v1(134.17,19.09) 133.65,18.57 DM2.168 ; v1(136.38,27.04) 136.41,27.01 136.67,27.01 136.95,26.73 DM2.179 ; v1(101.35,22.72) 100.85,22.72 100.35,23.21 DM2.65 ; v1(85.28,27.82) 85.16,27.94 84.58,27.94 83.75,28.77 DM1.26 ; v1(85.28,27.82) 85.39,27.94 85.5,27.94 85.82,28.26 85.82,28.78 85.55,29.05 DM1.32 ; v1(85.28,27.82) 85.33,27.82 85.47,27.68 85.53,27.68 85.85,27.36 85.85,26.69 86.55,25.99 DM2.19 ; DM2.2 v1(81.45,18.49) ; DM1.37 87.05,37.14 86.6,36.69 85.14,36.69 v1(85.12,36.71) 85.25,36.84 DM1.31 ; v1(130.84,41.79) 130.72,41.79 130.25,41.33 DM1.173 ; DM2.38 92.25,18.14 92.31,18.2 v1(92.31,18.23) ; v1(137.29,19.19) 137.15,19.05 137.04,19.05 136.65,18.66 DM2.178 ; v1(137.93,31.84) 137.93,31.82 137.15,31.04 DM1.196 ; v1(75.9,27.19) 76.04,27.05 76.86,27.05 78.35,28.54 DM1.8 ; v1(124.62,23.2) 124.64,23.23 124.82,23.23 124.95,23.35 DM2.139 ; DM1.61 94.25,39.6 92.44,41.41 92.06,41.41 v1(91.5,41.97) ; v1(89.03,43.06) 88.84,43.06 88.41,42.64 88.41,42.12 88.68,41.85 88.85,41.68 DM1.43 ; v1(75.39,35.88) 76.85,37.33 DM1.3 ; v1(134.07,27.29) 133.88,27.48 133.87,27.48 133.55,27.8 133.55,28.25 133.55,28.26 DM1.184 ; v1(135.35,34.28) 135.49,34.42 135.67,34.42 135.99,34.74 135.99,36.4 136.85,37.26 DM1.195 ; DM2.162 v1(131.85,18.31) ; v1(135.34,19.09) 134.85,18.6 DM2.172 ; v1(87.36,19.11) 87.19,18.95 87.13,18.95 86.81,18.63 86.81,18.17 86.85,18.14 DM2.20 ; DM2.9 83.55,23.86 82.2,22.52 80.65,22.52 v1(80.47,22.34) ; v1(83.34,42.76) 82.84,42.76 82.4,42.33 82.4,40.35 81.65,39.59 DM1.19 ; DM2.43 93.75,23.67 v1(92.84,22.77) ; DM2.195 141.75,23.55 142.05,23.25 v1(142.6,23.25) ; v1(102.18,22.3) 102.18,23.74 102.15,23.76 DM2.71 ; v1(80.06,42.47) 79.99,42.47 78.65,41.12 DM1.9 ; DM2.173 v1(135.15,23.35) ; DM2.49 95.55,26.01 95.16,26.4 v1(94.19,26.4) ; DM1.197 137.45,35.85 v1(136.79,35.19) ; v1(119.51,27.95) 119.65,28.09 119.72,28.09 120.04,28.41 120.04,28.86 119.75,29.15 DM1.138 ; v1(100.54,18.48) 100.65,18.37 DM2.66 ; v1(124.04,27.62) 123.95,27.7 123.78,27.7 123.35,28.13 DM1.150 ; DM1.178 131.75,29.1 132.24,28.61 132.24,28.22 132.25,28.21 132.25,27.88 132.57,27.56 132.68,27.56 v1(132.8,27.44) ; DM2.32 v1(90.45,18.28) ; v1(138.13,27.14) 138.24,27.14 138.68,26.7 138.68,26.65 138.75,26.58 DM2.185 v1(138.75,23.22) ; DM2.150 v1(128.25,18.31) ; DM2.26 88.65,18.4 v1(88.58,18.48) ; DM2.196 v1(142.05,18.25) ; v1(127.88,42.03) 128.45,41.47 DM1.167 ; DM2.144 126.45,18.85 126.46,18.86 126.46,19.56 126.25,19.77 v1(125.89,19.77) ; DM1.20 81.95,28.95 82.27,28.63 82.27,28.18 81.83,27.75 v1(81.69,27.75) 82.28,27.16 84.21,27.16 84.75,26.62 DM2.13 ; DM2.72 102.45,17.92 102.45,17.92 v1(102.45,18.35) ; v1(92.82,32.5) 92.98,32.5 94.21,31.27 95.35,31.27 95.75,30.88 DM1.66 ; DM1.145 121.85,36.76 121.01,35.93 v1(120.57,35.93) ; DM2.55 97.35,26.29 96.43,27.21 96,27.21 95.79,27.43 95.65,27.43 v1(95.51,27.57) 95.61,27.57 96.84,28.8 97.13,28.8 97.55,29.22 DM1.72 ; v1(126.47,34.89) 126.37,34.89 125.79,35.47 125.79,35.77 124.85,36.71 DM1.155 ; v1(87.71,87.57) 87.74,87.57 87.77,87.54 C401.2 88.51,89.46 92.29,93.23 U402.2 ; DM2.127 121.35,21.82 v1(122.16,21.02) ; DM1.134 118.55,28.48 117.95,27.87 v1(117.84,27.87) 117.7,28.01 117.64,28.01 117.32,28.33 117.32,28.56 116.75,29.13 DM1.128 ; DM1.185 133.85,37.05 133.52,36.73 133.52,35.73 133.84,35.41 133.88,35.41 v1(134.04,35.24) ; v1(133.92,33.72) 134.11,33.91 134.24,33.91 134.7,34.37 134.7,35.62 135.05,35.97 DM1.189 ; DM2.54 v1(97.05,18.97) ; v1(123.33,18.35) 123.45,18.23 DM2.134 ; v1(131.63,35.09) 132.28,35.74 132.28,36.24 132.05,36.47 DM1.179 ; v1(92.06,27.72) 92.2,27.86 92.21,27.86 92.53,28.18 92.53,28.78 92.15,29.15 DM1.54 ; v1(130.05,18.56) DM2.156 ; DM1.190 135.35,30.99 v1(136.23,31.86) ; DM1.151 123.65,36.77 122.22,35.34 122.22,34.89 122.73,34.38 v1(122.74,34.38) ; DM1.139 120.05,36.89 120,36.84 120,36.08 119.21,35.29 v1(118.45,35.29) ; DM2.189 139.95,26.48 140.9,27.43 140.94,27.43 v1(141.1,27.6) ; DM1.201 138.65,36.88 138.98,36.55 139.52,36.55 139.9,36.93 140.31,36.93 140.36,36.98 140.89,36.98 v1(141,37.09) ; DM2.44 94.05,18.72 93.63,19.14 v1(93.43,19.14) ; DM1.25 83.45,39.03 84.49,40.07 84.49,41.78 85.52,42.81 85.66,42.81 v1(85.73,42.89) ; v1(93.78,28.61) 93.95,28.78 DM1.60 ; DM2.48 95.25,19.36 95.51,19.62 v1(95.82,19.62) ; DM2.184 v1(138.45,18.46) ; DM1.38 87.35,28.11 86.82,27.58 86.74,27.58 v1(86.65,27.5) 86.82,27.33 87.04,27.33 88.35,26.02 DM2.25 ; DM2.133 v1(123.15,23.4) ; DM1.13 79.85,37.21 79.43,36.79 78.49,36.79 v1(78.29,36.59) ; v1(91.6,34.43) 90.99,35.04 90.99,36.66 90.65,37 DM1.49 ; DM2.60 v1(98.85,18.26) ; DM2.8 83.25,19.23 82.74,19.75 v1(82.48,19.75) ; DM2.190 v1(140.25,18.49) ; DM2.161 v1(131.55,23.4)
  BOTTOM w0.356: CPU1.AV9 127,92.23 127.39,92.63 v1(127.39,92.74) ; CPU1.E3 109.29,95.38 109.37,95.3 109.38,95.3 v1(109.51,95.17) ; v1(109.51,95.17) 109.01,94.68 CPU1.E4 ; v1(109.51,95.17) 109.63,95.3 109.72,95.3 109.8,95.38 CPU1.G3 110.39,95.38 110.47,95.3 110.82,95.3 110.9,95.38 CPU1.J3 111.28,95.3 112.22,95.3 CPU1.L3 112.5,95.38 CPU1.M2 113.2,95.38 CPU1.N3 ; 123.8,91.78 CPU1.AM11 124.38,90.4 124.88,90.4 CPU1.AR13 ; Q603.1 139.66,95.84 140.14,95.36 v1(140.14,95.01) ; v1(117.22,88.9) 117.38,88.9 CPU1.AA15 ; CPU1.AR17 125.15,87.92 v1(125.15,88.25) 125.67,88.25 CPU1.AU15 ; CPU1.U15 115.48,88.8 v1(115.29,88.8) 115.12,88.8 CPU1.R15 ; CPU1.AL8 123.01,92.57 122.71,92.57 CPU1.AJ7 122.47,93.36 v1(122.77,93.36) ; v1(40.11,173.49) 39.71,173.9 39.31,173.9 EC3103.1 EC3102.1 39.01,172.92 38.44,173.49 U3101.8 ; CPU1.L15 112.8,88.62 v1(113.26,89.08) 113.8,88.54 CPU1.N15
  BOTTOM w0.381: v1(124.92,93.57) 124.88,93.57 CPU1.AN7 ; R633.2 123.39,101.29 v1(123.58,101.48) ; v1(117.22,88.9) 117.15,88.82 117.14,88.82 CPU1.W15 ; 123.8,91.78 CPU1.AL8 ; CPU1.G37 109.72,77.08 109.61,77.19 v1(109.53,77.19) 109.53,77.26 109.37,77.41 109.37,77.76 CPU1.E35 109.5,77.88 CPU1.G35
  BOTTOM w0.406: v1(143.62,92.47) 143.21,92.47 142.97,92.23 Q601.4 ; EU5602.8 EU5602.3 v1(161.83,29.73) ; HDT1.17 91.12,88.53 90.76,88.89 90.76,89.81 v1(90.77,89.83) ; PQ4206.4 104.65,162.69 v1(105.14,163.18) ; v1(135.63,84.74) 135.55,84.66 C1024.2 134.85,84.65 R640.1 ; v1(138.06,93.91) 138.44,93.91 139,93.36 139,91.92 139.99,90.93 Q601.1 ; U3602.2 150.86,22.74 151.11,22.49 v1(151.54,22.49) ; U3503.2 v1(157.97,28.97) ; v1(17.81,39.33) 18.39,39.91 U3402.3 U3402.8
  BOTTOM w0.457: R1917.2 138.16,88.27 v1(138.17,88.28)
  BOTTOM w0.508: v1(129.78,152.66) 130.16,152.28 EC9704.2 ; C3625.2 157.42,78.18 157.77,78.52 v1(158.22,78.52) ; v1(152,8.55) 151.85,8.39 C2708.2 ; EU3404.2 159.47,42.05 v1(159.44,42.07) v1(158.71,42.07) ; v1(60.43,48.91) 61.17,48.17 PC4904.2 ; C5804.2 v1(169.91,67.45) ; C3617.2 149.52,75.79 v1(149.11,75.37) ; X1902.4 v1(114.15,104.02) ; C2421.2 v1(159.03,150.31) ; R5410.2 17.61,79.97 18.04,80.4 v1(18.32,80.4) ; v1(71.1,17.92) 71.29,18.11 EC9746.2 ; PC4609.2 PR4646.2 125.84,140.7 v1(126.3,140.24) ; v1(149.03,122.41) 149.71,123.1 C2407.2 ; v1(151.09,122.72) 151.43,122.37 EC2501.2 ; DM1.127 116.47,38.15 116.47,37.12 117.18,36.41 117.18,34.34 116.81,33.97 116.54,33.97 v1(116.54,33.95) ; C604.2 126.82,104.57 126.98,104.73 v1(127.19,104.73) ; v1(61.45,17.41) 62.02,16.84 Q2505.S ; v1(133.48,89.88) 133.51,89.91 ; 133.51,89.91 134.26,89.91 C601.1 ; 133.51,89.91 R646.1 ; v1(149.87,92.52) 149.97,92.62 U701.1 ; v1(156.75,150.23) Q2401.S 156.57,148.73 R2442.2 ; PC4202.2 100.82,163.59 v1(101.23,163.99) PR4213.2 ; v1(138.17,88.28) 138.17,88.8 138.15,88.82 R1916.2 ; v1(102.72,143.01) 102.47,143.27 C2723.1 ; v1(113.77,100.39) 113.79,100.41 113.79,100.72 113.83,100.76 113.83,101.02 C1905.1 ; EC9728.2 160.6,120.06 v1(160.76,120.23) ; v1(129.68,96.21) 129.68,96.47 129.68,96.47 129.68,96.48 130.05,96.85 130.06,96.85 130.25,97.04 130.62,97.04 131.75,98.18 R1919.2 ; EC2701.2 101.72,140.66 v1(101.12,140.07) ; C3303.2 13.85,23.46 v1(13.01,24.29) ; C3613.2 149.52,78.71 149.31,78.5 v1(149.31,78.12) ; C3613.2 149.52,79.42 150,79.89 PC4834.2 ; C3613.2 150.91,78.88 151.29,78.5 151.29,78.13 C3626.2 ; EC2901.2 v1(59.37,13.12) ; v1(149.41,103.24) 149.38,103.26 SPI25.4 ; C3405.2 v1(20.02,37.3) ; C2706.2 v1(158.22,4.33) ; EC9741.2 119.92,158.89 v1(120.43,159.4) ; v1(157.59,112.25) 157.55,112.22 PC4829.2 ; C1904.1 109.65,101.24 110.72,102.32 X1902.2 109.72,102.51 v1(109.63,102.42) ; v1(119.31,147.97) 119.62,147.66 PR4638.2 ; EC2602.2 97.45,149.55 v1(97.77,149.24) ; EC9713.2 134.54,142.57 v1(134.73,142.38) ; X601.2 132.83,106.74 v1(133.48,106.08) 133.52,106.12 R1914.2 ; EC9703.2 v1(126.98,174.97) ; R1928.2 139.38,84.28 138.93,83.83 138.92,83.83 138.69,83.6 137.48,83.6 R641.2 137.08,82.88 v1(137.5,82.46) ; PR4817.1 151.49,118.46 151.52,118.49 v1(151.52,119.19) ; 4.6,161.35 4.9,161.64 RJ45.9 7.89,161.64 8.16,161.38 ; R5209.2 v1(96.37,143.65) ; EC2708.2 EC2709.2 150.98,15.63 151.29,15.94 C2718.2 151.62,16.39 151.22,16.79 151.22,17.86 v1(150.86,18.22) ; v1(144.25,110.12) 144.76,110.12 145.55,110.91 C2501.2 145.55,112.32 C2502.2 ; v1(136.76,106.26) 136.76,106.26 136.27,105.77 R1912.2 ; R2504.2 58.02,13.88 v1(58.02,13.88) ; C3621.1 v1(140.77,74.56) 140.63,74.7 C3618.2 C3619.2 ; v1(99.7,139.99) 100.18,140.47 EC5205.2 ; PR4618.1 v1(117.63,108.85) ; PC4528.2 v1(40.37,60.44) ; HDD1.13 170.8,36.81 v1(170.31,37.3) ; C3505.2 158.88,26.68 v1(158.05,27.52) ; PR4648.2 v1(121.39,147.92) ; C2413.2 148.85,146.01 149.16,145.7 149.16,145.51 C2412.2 149.29,144.96 149.42,144.83 v1(149.42,144.64) ; v1(47.99,61.61) 48.05,61.54 PC5005.2 ; v1(23.22,69.23) 23.38,69.07 U3504.2 ; v1(170.24,90.84) 170.31,90.77 170.31,90.33 170.06,90.08 C5610.2 ; v1(149.59,10.96) C2716.2 151.28,10.96 C2717.2 ; 10.14,71.28 10.14,72.01 HDMI1.PTH3 ; C603.2 123.3,105.11 v1(123.3,107.2) ; C3510.2 v1(29.47,69.51) ; PR4823.2 v1(154.29,119.14) ; v1(101.45,139) 101.91,139.46 EC9708.2 ; v1(132.9,105.52) 132.54,105.88 X601.3 ; PR4824.2 155.94,113.8 v1(155.43,113.29) ; v1(138.06,93.91) 138.03,93.91 136.58,92.46 R1926.2 ; v1(153.75,125.99) 153.75,125.84 153.47,125.56 C2418.2 ; PC4831.2 v1(153.4,119.14) ; v1(116.63,108.19) PR4605.1 ; R643.2 v1(134.47,82.13) ; HDD1.14 v1(170.8,24.62) ; Q6205.S 165.75,151.33 165.74,151.32 v1(165.74,151.27) ; EC5801.2 v1(160.64,48.65) ; PC5013.2 v1(46.57,64.08) ; SPK1.6 69.22,10.02 v1(68.69,10.55) ; PC4407.2 v1(133.1,153.58) ; PG4411.2 v1(125.53,154.32) ; C3406.2 v1(154.73,43.66) ; FAN1.2 92.59,148.37 ; EC9733.2 v1(51.23,24.9) ; R2435.2 v1(141.46,136.28)
  BOTTOM w0.635: 7.24,76.17 HDMI1.PTH4 5.5,75.28 ; 11.07,3.72 CARD1.14 ; CARD1.14 13.25,2.88 ; CARD1.14 13.25,4.56 ; CARD1.14 15.43,3.72 ; 148.93,177.84 BATT1.10 ; BATT1.10 149.97,179.77 ; BATT1.10 147.88,179.77 ; 10.6,71.48 HDMI1.PTH3 12.04,73.45 ; 169.17,177.84 BATT1.9 170.22,179.77 ; 13.5,53.38 HDMI1.PTH7 ; HDMI1.PTH7 15.24,54.27 ; HDMI1.PTH7 13.5,55.16 ; 151.06,179.77 BATT1.8 ; BATT1.8 152.05,180.76 ; BATT1.8 152.05,178.78 ; 11.07,30.02 CARD1.15 ; CARD1.15 15.43,30.02 ; CARD1.15 13.25,29.18 ; CARD1.15 13.25,30.86 ; 156.05,180.76 BATT1.6 156.05,178.78 ; USB1.10 15.4,46.37 ; USB1.10 13.72,45.48 ; USB1.10 13.72,47.26 ; 13.72,32.68 USB1.11 ; USB1.11 13.72,34.46 ; USB1.11 15.4,33.57 ; 5.7,55.64 5.26,56.07 HDMI1.PTH11 ; 3.86,76.55 HDMI1.PTH6 3.02,77.01 ; HDMI1.PTH10 5.5,55.16 ; HDMI1.PTH10 5.5,53.38 ; HDMI1.PTH10 7.24,54.27 ; HDMI1.PTH10 5.35,54.42 HDMI1.PTH12 ; 5.65,74.92 5.1,74.37 HDMI1.PTH5 ; 10.6,58.96 HDMI1.PTH8 12.04,56.99 ; 8.87,75.97 HDMI1.PTH2 10.25,76.96 ; 10.25,53.48 HDMI1.PTH9 8.87,54.47 ; 13.5,75.28 HDMI1.PTH1 13.5,77.06 ; USB1.13 5.27,30.98 ; USB1.12 5.27,49.13 ; 8.24,180.6 7.93,180.3 RJ45.10 4.74,180.3 4.43,180.6 ; 14.47,35.76 USB1.4 15.18,36.47
  vias: v1(4.55,52.59) v1(4.66,49.79) v1(5.51,82.05) v1(6.66,51.04) v1(6.76,74.69) v1(7.02,55.89) v1(8.74,48.91) v1(8.87,52.67) v1(9.3,78.24) v1(9.42,26.35) v1(9.42,21.27) v1(9.42,16.19) v1(9.42,11.11) v1(9.42,6.03) v1(9.59,31.1) v1(9.65,1.19) v1(10.07,50.84) v1(10.45,79.89) v1(10.52,21.6) v1(10.48,20.58) v1(10.58,180.95) v1(10.59,82.05) v1(11.06,48.84) v1(12,77.86) v1(12.4,74.43) v1(13.19,25.35) v1(13.29,56.27) v1(13.29,16.57) v1(13.36,161.29) v1(13.75,48.73) v1(13.85,52.26) v1(14.67,16.56) v1(14.73,1.19) v1(15.66,180.95) v1(15.67,82.05) v1(15.86,80.53) v1(15.86,13.35) v1(16.87,13.35) v1(17.38,19.95) v1(18.14,20.71) v1(18.14,19.95) v1(18.14,19.19) v1(18.44,161.29) v1(18.9,19.95) v1(20.05,78.62) v1(20.43,29.86) v1(20.56,80.66) v1(20.74,180.95) v1(20.75,82.05) v1(20.84,77.71) v1(20.84,72.12) v1(20.89,75.91) v1(20.94,74.15) v1(22.71,13.85) v1(23.52,161.29) v1(23.6,81.01) v1(23.64,14.19) v1(23.68,35.14) v1(23.76,37.07) v1(24.11,13.47) v1(25.78,180.81) v1(25.83,82.05) v1(26.27,21.85) v1(26.52,45.35) v1(26.65,37.4) v1(26.83,39.76) v1(27.46,79.84) v1(27.54,1.53) v1(27.77,45.38) v1(28.6,161.29) v1(29.78,71.31) v1(30.08,176.79) v1(30.91,82.05) v1(31.58,179.25) v1(31.71,2.19) v1(31.86,164.48) v1(32.49,67.96) v1(33.28,68.64) v1(33.68,161.29) v1(33.69,70.6) v1(33.76,177.81) v1(34.04,73.87) v1(34.09,67.37) v1(34.91,169.94) v1(35.99,82.05) v1(36.2,73.82) v1(36.66,179.25) v1(36.79,2.19) v1(37.32,176.67) v1(37.83,169.94) v1(38.05,18.58) v1(38.39,74.71) v1(39.02,18.58) v1(39.61,177.51) v1(39.61,54.49) v1(39.78,169.76) v1(39.98,18.58) v1(40.24,55.13) v1(40.24,54.49) v1(40.24,53.86) v1(40.44,74.69) v1(40.88,54.49) v1(41.07,82.05) v1(41.59,75.53) v1(41.74,179.25) v1(41.84,169.73) v1(41.94,177.48) v1(41.87,2.19) v1(42.07,173.21) v1(42.53,167.02) v1(43.47,171.79) v1(43.56,170.95) v1(43.67,163.71) v1(43.84,161.29) v1(43.77,75.5) v1(43.95,76.36) v1(44.23,167.35) v1(44.36,178.34) v1(44.36,177.18) v1(44.89,169.3) v1(45.14,176.08) v1(45.8,178.47) v1(45.98,76.39) v1(46.15,82.05) v1(46.44,164.43) v1(46.49,177.56) v1(46.49,176.67) v1(46.51,175.75) v1(46.72,166.38) v1(46.82,179.25) v1(46.77,174.81) v1(46.95,2.19) v1(47.61,178.47) v1(48.11,162.7) v1(48.92,161.29) v1(49.23,178.47) v1(49.26,169.3) v1(50.27,170.32) v1(50.27,169.3) v1(50.27,168.29) v1(50.53,66.69) v1(50.53,65.67) v1(50.53,64.65) v1(51.23,82.05) v1(51.29,169.3) v1(51.26,165.87) v1(51.42,177.07) v1(51.72,177.89) v1(51.9,179.25) v1(52.03,76.59) v1(52.03,2.19) v1(52.2,162.85) v1(52.48,164.4) v1(52.64,175.75) v1(53.25,161.3) v1(55.2,82.05) v1(56.12,48.42) v1(56.12,47.79) v1(56.5,3.95) v1(56.83,160.97) v1(56.98,179.25) v1(57.13,5.98) v1(57.11,2.19) v1(57.77,7.88) v1(57.77,3.95) v1(58.91,3.95) v1(59.09,82.38) v1(60.48,160.79) v1(60.81,46.24) v1(61.45,46.87) v1(61.45,46.24) v1(61.45,45.6) v1(62.06,179.25) v1(62.08,46.24) v1(62.24,82.97) v1(62.19,2.19) v1(62.85,175.86) v1(63.25,18.22) v1(63.72,17.79) v1(64.57,160.39) v1(64.75,165.36) v1(64.75,164.09) v1(65.26,169.81) v1(66.78,161.55) v1(66.91,159.52) v1(67.14,179.25) v1(67.19,158.02) v1(67.27,2.19) v1(67.62,84.69) v1(68.31,169.68) v1(69.7,17.16) v1(69.83,173.87) v1(70.24,75.19) v1(70.34,158.25) v1(70.34,17.92) v1(70.47,17.16) v1(70.59,83.96) v1(71.08,27.77) v1(71.23,17.16) v1(71.25,34.45) v1(71.25,33.08) v1(71.28,28.81) v1(71.41,85.05) v1(71.51,82.79) v1(71.66,76.62) v1(71.76,79.44) v1(71.91,155.41) v1(72.22,179.25) v1(72.19,79.92) v1(72.35,2.19) v1(72.63,173.87) v1(72.63,170.83) v1(72.73,80.27) v1(72.93,85.05) v1(72.88,45.91) v1(72.88,45.25) v1(72.88,44.59) v1(73.51,158.63) v1(74,24.9) v1(74.61,30.59) v1(74.69,174.79) v1(74.91,32.68) v1(75.45,152.82) v1(75.52,156.68) v1(75.59,158.22) v1(75.99,176.1) v1(76.51,156.77) v1(77.07,171.97) v1(77.3,179.25) v1(77.4,22.01) v1(77.66,34.53) v1(77.81,86.14) v1(78.34,72.4) v1(78.59,11.57) v1(79.08,60.56) v1(79.18,154.24) v1(79.23,11.57) v1(79.26,1.02) v1(79.43,34.76) v1(79.48,148.91) v1(79.86,11.57) v1(80.37,88.73) v1(80.5,11.57) v1(80.7,72.73) v1(80.93,74.31) v1(80.98,34.68) v1(81.13,11.57) v1(81.29,43.85) v1(81.26,42.4) v1(81.36,21.12) v1(82.15,34.94) v1(82.38,179.25) v1(82.46,145.1) v1(82.56,65.52) v1(82.91,66.69) v1(83.32,34.58) v1(83.67,92.06) v1(83.9,21.83) v1(84.34,1.02) v1(84.39,84.16) v1(84.56,166.51) v1(84.74,77.99) v1(84.82,34.76) v1(84.94,140.8) v1(85.33,76.85) v1(85.99,33.92) v1(86.34,174.19) v1(86.29,22.41) v1(86.42,137.42) v1(86.85,43.01) v1(86.98,95.34) v1(87,21.65) v1(87.46,179.25) v1(87.54,133.97) v1(87.64,35.19) v1(87.79,81.93) v1(88.25,20.05) v1(88.35,130.26) v1(88.5,172.35) v1(88.7,22.11) v1(88.81,125.59) v1(88.82,122.07) v1(88.82,116.99) v1(88.82,111.91) v1(88.82,106.83) v1(88.82,101.75) v1(88.81,98.36) v1(89.14,168.92) v1(89.16,34.5) v1(89.44,21.47) v1(89.42,1.02) v1(90.15,22.39) v1(90.41,34.4) v1(90.61,136.15) v1(90.96,80.25) v1(91.6,43.98) v1(92.06,145.3) v1(92.31,73.29) v1(92.54,179.25) v1(92.62,43.01) v1(93.07,20.58) v1(93.2,72.53) v1(94.5,1.02) v1(94.62,20.51) v1(94.93,21.91) v1(97.19,22.57) v1(97.62,179.25) v1(98.51,100.57) v1(98.79,82.81) v1(99.19,94.58) v1(99.27,21.25) v1(99.4,100.57) v1(99.58,1.02) v1(100.29,100.57) v1(100.34,20.69) v1(102.7,179.25) v1(102.88,91.22) v1(103.41,91.93) v1(103.46,141.06) v1(103.56,93.51) v1(104.12,142.72) v1(104.66,1.02) v1(105.64,96.63) v1(105.62,92.92) v1(105.57,90.05) v1(107.02,103.31) v1(106.99,101.81) v1(107.11,104.6) v1(107.78,179.25) v1(108.59,106.03) v1(108.97,92.56) v1(108.97,91.58) v1(108.99,90.55) v1(109.73,92.56) v1(109.73,79.37) v1(109.74,1.02) v1(109.84,91.6) v1(109.8,90.53) v1(109.79,81.62) v1(110.49,92.56) v1(110.52,91.65) v1(110.52,88.25) v1(111.69,148.4) v1(112.86,179.25) v1(113.27,86.98) v1(113.34,86.02) v1(113.36,80.9) v1(113.7,99.27) v1(114.18,107.68) v1(114.28,85.83) v1(114.32,83.85) v1(114.82,1.02) v1(115.04,93.66) v1(115.15,85.99) v1(115.25,34.38) v1(115.27,83.88) v1(115.3,80.86) v1(115.6,106.74) v1(115.91,100.37) v1(116.01,99.02) v1(116.31,89.85) v1(116.28,83.85) v1(117.05,139.74) v1(117.08,97.39) v1(117.25,99.73) v1(117.28,83.91) v1(117.27,80.83) v1(117.76,139.74) v1(117.94,179.25) v1(118.3,90.82) v1(118.35,86.07) v1(118.29,83.85) v1(118.36,93.42) v1(118.4,33.18) v1(118.47,139.74) v1(118.63,98.16) v1(119.18,141.16) v1(119.18,140.45) v1(119.18,139.74) v1(119.18,139.03) v1(119.18,138.31) v1(119.18,137.6) v1(119.3,83.85) v1(119.38,86.06) v1(119.51,99.53) v1(119.48,95.07) v1(119.9,139.74) v1(119.9,1.02) v1(120.34,83.85) v1(120.53,93.46) v1(120.61,139.74) v1(120.57,33.87) v1(120.99,99.91) v1(121.06,107.22) v1(121.11,40.57) v1(121.24,86.96) v1(121.19,43.14) v1(121.32,139.74) v1(121.29,86.17) v1(121.32,83.86) v1(121.3,80.79) v1(121.37,27.85) v1(121.55,103.13) v1(122.26,83.88) v1(122.3,80.8) v1(122.82,103.13) v1(123.02,179.25) v1(123.27,80.82) v1(123.84,35.12) v1(123.81,14.49) v1(124.18,80.62) v1(124.28,81.61) v1(124.47,42.94) v1(124.47,41.59) v1(124.85,35.11) v1(124.98,1.02) v1(126.12,43.17) v1(126.73,14.49) v1(126.75,28.18) v1(126.75,26.25) v1(127.79,34.66) v1(128.1,179.25) v1(128.73,142.17) v1(128.86,34.73) v1(129.34,27.6) v1(129.8,91.37) v1(129.95,35.55) v1(130.11,143.29) v1(130.06,1.02) v1(130.16,14.49) v1(130.84,43.14) v1(131.38,27.87) v1(131.5,86.96) v1(131.55,88.83) v1(131.66,33.69) v1(133.2,14.49) v1(134.6,41.41) v1(135.14,1.02) v1(135.17,180.95) v1(135.16,27.65) v1(135.29,20.79) v1(135.62,41.74) v1(135.82,42.99) v1(136.63,14.49) v1(136.89,167.9) v1(137.65,165.49) v1(137.98,33.11) v1(139.22,179.23) v1(139.5,27.75) v1(140.25,180.95) v1(140.22,1.02) v1(140.27,42.53) v1(140.9,20.38) v1(141.64,88.68) v1(142.96,21.22) v1(143.24,161.68) v1(143.36,11.62) v1(143.72,91.37) v1(144,11.63) v1(144.44,26.74) v1(145.33,180.95) v1(145.3,1.02) v1(145.4,167.78) v1(145.52,162.7) v1(145.78,78.04) v1(145.78,77.1) v1(145.78,76.21) v1(146.08,57.97) v1(146.31,55.47) v1(146.41,47.25) v1(146.41,46.24) v1(146.41,45.22) v1(146.41,44.21) v1(146.73,11.63) v1(147.3,53.73) v1(147.4,11.62) v1(147.68,55.51) v1(149.84,112.43) v1(149.84,111.8) v1(150.38,1.02) v1(151.62,57.16) v1(151.87,113.8) v1(152.29,38.38) v1(152.28,37.63) v1(152.36,35.67) v1(152.36,35.01) v1(152.36,34.35) v1(152.36,33.69) v1(152.36,33.03) v1(152.51,40.68) v1(152.74,46.42) v1(152.71,44.31) v1(152.71,42.35) v1(152.89,113.8) v1(153.4,36.46) v1(153.6,37.37) v1(153.91,113.8) v1(154.64,12.71) v1(155.28,12.71) v1(155.46,1.02) v1(155.76,121.96) v1(155.91,12.71) v1(156.22,50.89) v1(156.55,14.62) v1(156.55,13.98) v1(156.55,13.35) v1(156.55,12.71) v1(156.55,12.08) v1(156.55,11.44) v1(157.21,50.94) v1(157.18,12.71) v1(157.49,52.16) v1(157.82,12.71) v1(157.97,2.42) v1(158.22,79.61) v1(158.22,77.38) v1(158.5,126.1) v1(158.45,12.71) v1(159.49,68.39) v1(159.9,64.93) v1(159.93,55.13) v1(160.54,1.02) v1(161.02,3.01) v1(161.2,55.15) v1(161.42,68.11) v1(161.53,66.05) v1(162.05,86.55) v1(163.3,2.3) v1(165.62,1.02) v1(166.61,160.79) v1(166.61,156.98) v1(167.04,18.55) v1(168,6.74) v1(168.05,19.47) v1(168.41,22.36) v1(169.6,118.35) v1(169.6,117.71) v1(169.6,117.08) v1(169.91,68.9) v1(169.91,68.16) v1(170.49,19.62) v1(170.63,169.05) v1(170.67,29.22) v1(170.7,1.02) v1(170.8,32.9) v1(170.8,22.24) v1(172.18,177.33) v1(172.18,172.25) v1(172.18,167.17) v1(172.18,162.09) v1(172.18,157.01) v1(172.18,151.93) v1(172.18,136.69) v1(172.18,126.53) v1(172.18,121.45) v1(172.18,116.37) v1(172.18,111.29) v1(172.18,106.21) v1(172.18,101.13) v1(172.18,96.05) v1(172.18,90.97) v1(172.18,85.89) v1(172.18,80.81) v1(172.17,76.52) v1(172.18,70.65) v1(172.18,65.57) v1(172.18,60.49) v1(172.18,40.17) v1(172.18,30.01) v1(172.18,19.85) v1(172.18,4.61) v2(19.74,11.95) v2(30.16,58.08) v2(33.97,13.47) v2(37.62,13.78) v2(40.27,47.43) v2(55.07,48.32) v2(56.07,39.2) v2(56.22,39.33) v2(67.06,30.03) v2(68.1,167.02) v2(74.05,168.49) v2(88.07,65.82) v2(91.37,55.92) v2(95.41,115.1) v2(112.33,177.13) v2(121.88,131.74) v2(123.3,130.69) v2(129.29,53.66) v2(141.1,152.33) v2(141.64,92.37) v2(142.96,53.45) v2(144,31.51) v2(145.98,153.2) v2(147.89,12.46) v2(149.38,43.7) v2(154.26,14.06) v2(158.5,29.17) v2(158.6,107.58) v2(160.99,36.66) v2(166.71,153.73) v3(17.38,42.05) v3(18.02,41.41) v3(20.1,71.33) v3(20.43,32.14) v3(20.43,30.87) v3(20.81,41.54) v3(22.33,43.06) v3(30.59,171.33) v3(35.03,29.86) v3(35.29,32.9) v3(36.43,29.86) v3(36.56,47.89) v3(36.56,46.75) v3(36.56,32.9) v3(37.57,47.89) v3(37.57,46.75) v3(37.85,29.86) v3(37.98,32.9) v3(38.59,47.89) v3(38.59,46.75) v3(38.97,12.96) v3(39.61,32.9) v3(39.58,29.86) v3(39.99,12.96) v3(40.85,18.55) v3(41.59,48.27) v3(41.62,47.43) v3(41.64,32.9) v3(41.64,29.93) v3(41.89,49.16) v3(42.04,46.61) v3(42.58,48.37) v3(42.65,47.51) v3(42.78,49.29) v3(42.99,46.61) v3(43.42,32.9) v3(43.42,29.86) v3(43.54,47.51) v3(43.77,18.58) v3(51.16,69.35) v3(52.18,69.35) v3(54.26,171.99) v3(55.13,172.05) v3(55.4,58.15) v3(56.32,58.18) v3(57.26,58.18) v3(57.26,38.62) v3(57.26,37.73) v3(57.26,36.84) v3(57.26,35.95) v3(57.26,35.06) v3(58.15,58.18) v3(61.58,69.35) v3(62.59,69.35) v3(65.09,27.74) v3(65.51,29.6) v3(65.51,28.54) v3(66.02,27.71) v3(66.15,69.35) v3(81.13,160.54) v3(88.12,167.14) v3(88.12,166.13) v3(90.15,156.09) v3(90.79,155.08) v3(91.04,156.09) v3(91.93,156.09) v3(96.43,152.84) v3(97.92,112.52) v3(97.92,111.68) v3(97.92,110.83) v3(97.9,109.99) v3(97.98,116.27) v3(98.81,112.52) v3(98.81,111.64) v3(98.81,110.81) v3(98.86,116.27) v3(99.25,152.92) v3(99.73,112.51) v3(99.73,111.64) v3(99.75,116.27) v3(100.18,115.45) v3(100.18,114.44) v3(100.18,113.42) v3(102.37,159.68) v3(103.26,159.65) v3(104.38,167.17) v3(104.38,166.13) v3(106.53,154.06) v3(107.3,153.43) v3(109.35,133.34) v3(109.96,135.67) v3(110.47,133.34) v3(110.6,176.03) v3(110.98,135.67) v3(111.49,176.03) v3(111.84,125.74) v3(111.87,124.85) v3(112.5,176.03) v3(112.63,131.02) v3(112.63,130.16) v3(112.63,129.32) v3(112.61,128.46) v3(112.61,127.52) v3(112.63,126.63) v3(113.39,176.03) v3(113.61,131.02) v3(113.61,130.19) v3(113.58,129.32) v3(113.58,128.38) v3(113.61,127.49) v3(114.28,176.03) v3(114.54,129.35) v3(114.54,128.41) v3(114.56,131.05) v3(114.56,130.21) v3(114.56,127.52) v3(115.17,176.03) v3(115.42,130.95) v3(116.75,129.37) v3(116.75,128.43) v3(116.69,127.52) v3(117.71,130.31) v3(117.71,127.52) v3(117.76,129.37) v3(117.76,128.43) v3(119.21,129.53) v3(119.21,128.69) v3(119.18,127.82) v3(119.18,126.88) v3(120.19,129.55) v3(120.16,128.69) v3(120.16,127.75) v3(120.19,126.86) v3(121.14,129.58) v3(121.11,128.71) v3(121.11,127.77) v3(121.14,126.88) v3(123.3,129.04) v3(123.3,128.15) v3(123.3,127.14) v3(124.19,129.04) v3(124.19,128.15) v3(124.19,127.14) v3(135.64,110.17) v3(136.53,110.17) v3(137.6,110.22) v3(137.73,112.81) v3(138.72,113.35) v3(138.77,114.26) v3(138.79,112.41) v3(138.79,111.52) v3(138.77,110.55) v3(139.53,115.73) v3(139.55,117.59) v3(139.55,116.65) v3(139.68,112.41) v3(139.68,111.52) v3(139.71,80.73) v3(139.94,114.69) v3(139.94,113.8) v3(140.55,80.73) v3(141.14,115.82) v3(141.18,116.75) v3(141.38,80.71) v3(142.27,80.71) v3(142.73,153.43) v3(142.73,152.54) v3(143.14,80.71) v3(143.62,153.43) v3(143.62,152.54) v3(143.85,80.15) v3(144.51,153.43) v3(144.51,152.54) v3(151.75,172.98) v3(152.64,172.98) v3(153.52,172.98) v3(156.45,103.21) v3(156.47,105.85) v3(156.47,105.01) v3(156.47,104.07) v3(157.36,105.8) v3(157.36,104.96) v3(157.36,104.07) v3(157.36,103.19) v3(158.12,84.57) v3(158.45,89.14) v3(158.6,82.23) v3(158.6,36.21) v3(158.96,84.59) v3(159.44,82.23) v3(159.49,36.21) v3(159.8,84.59) v3(160.13,106.31) v3(160.1,105.47) v3(160.1,104.61) v3(160.38,36.21) v3(164.19,168.16) v3(164.19,167.27) v3(164.5,86.62) v3(164.5,85.76) v3(165.08,168.16) v3(165.08,167.27) v3(165.97,168.16) v3(165.97,167.27) v3(166.07,166.2) v3(166.1,165.21) v3(168.26,41.67) v3(168.38,40.14) v3(170.03,177.18) v3(171.18,177.3) v3(171.18,176.29) v3(171.18,175.4) v3(171.18,174.38) v3(171.18,173.37) v3(171.18,172.48)
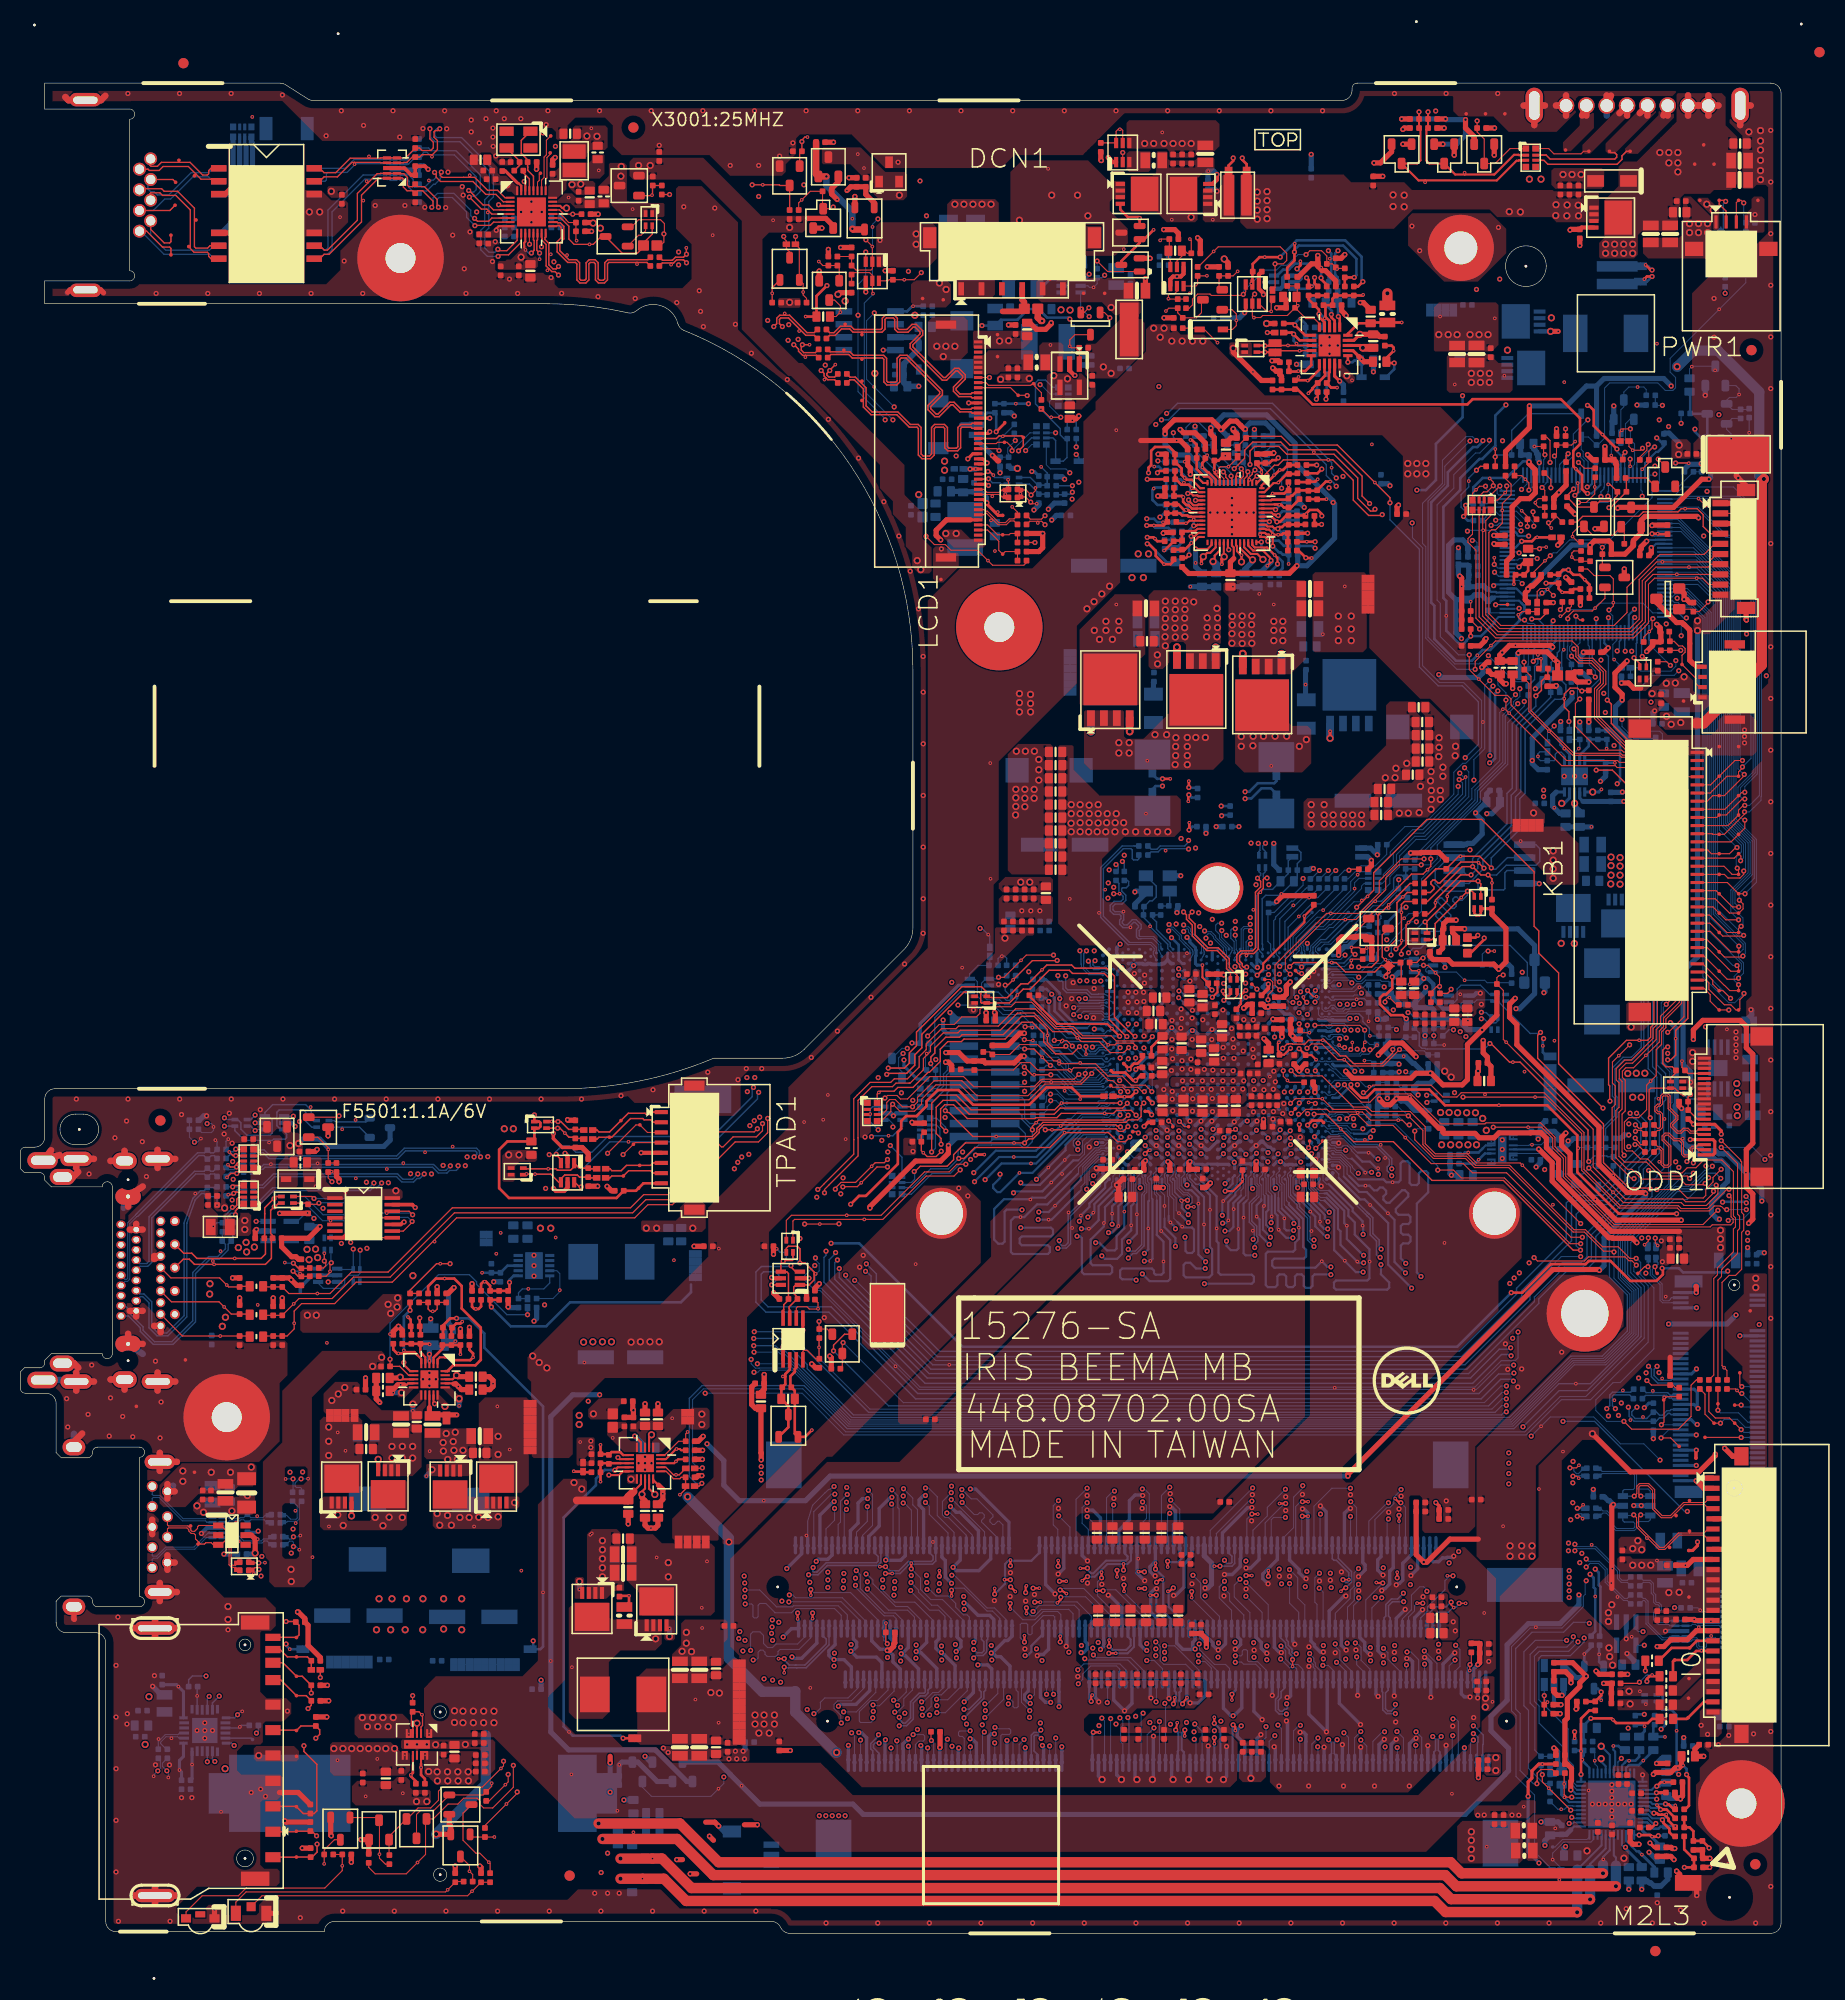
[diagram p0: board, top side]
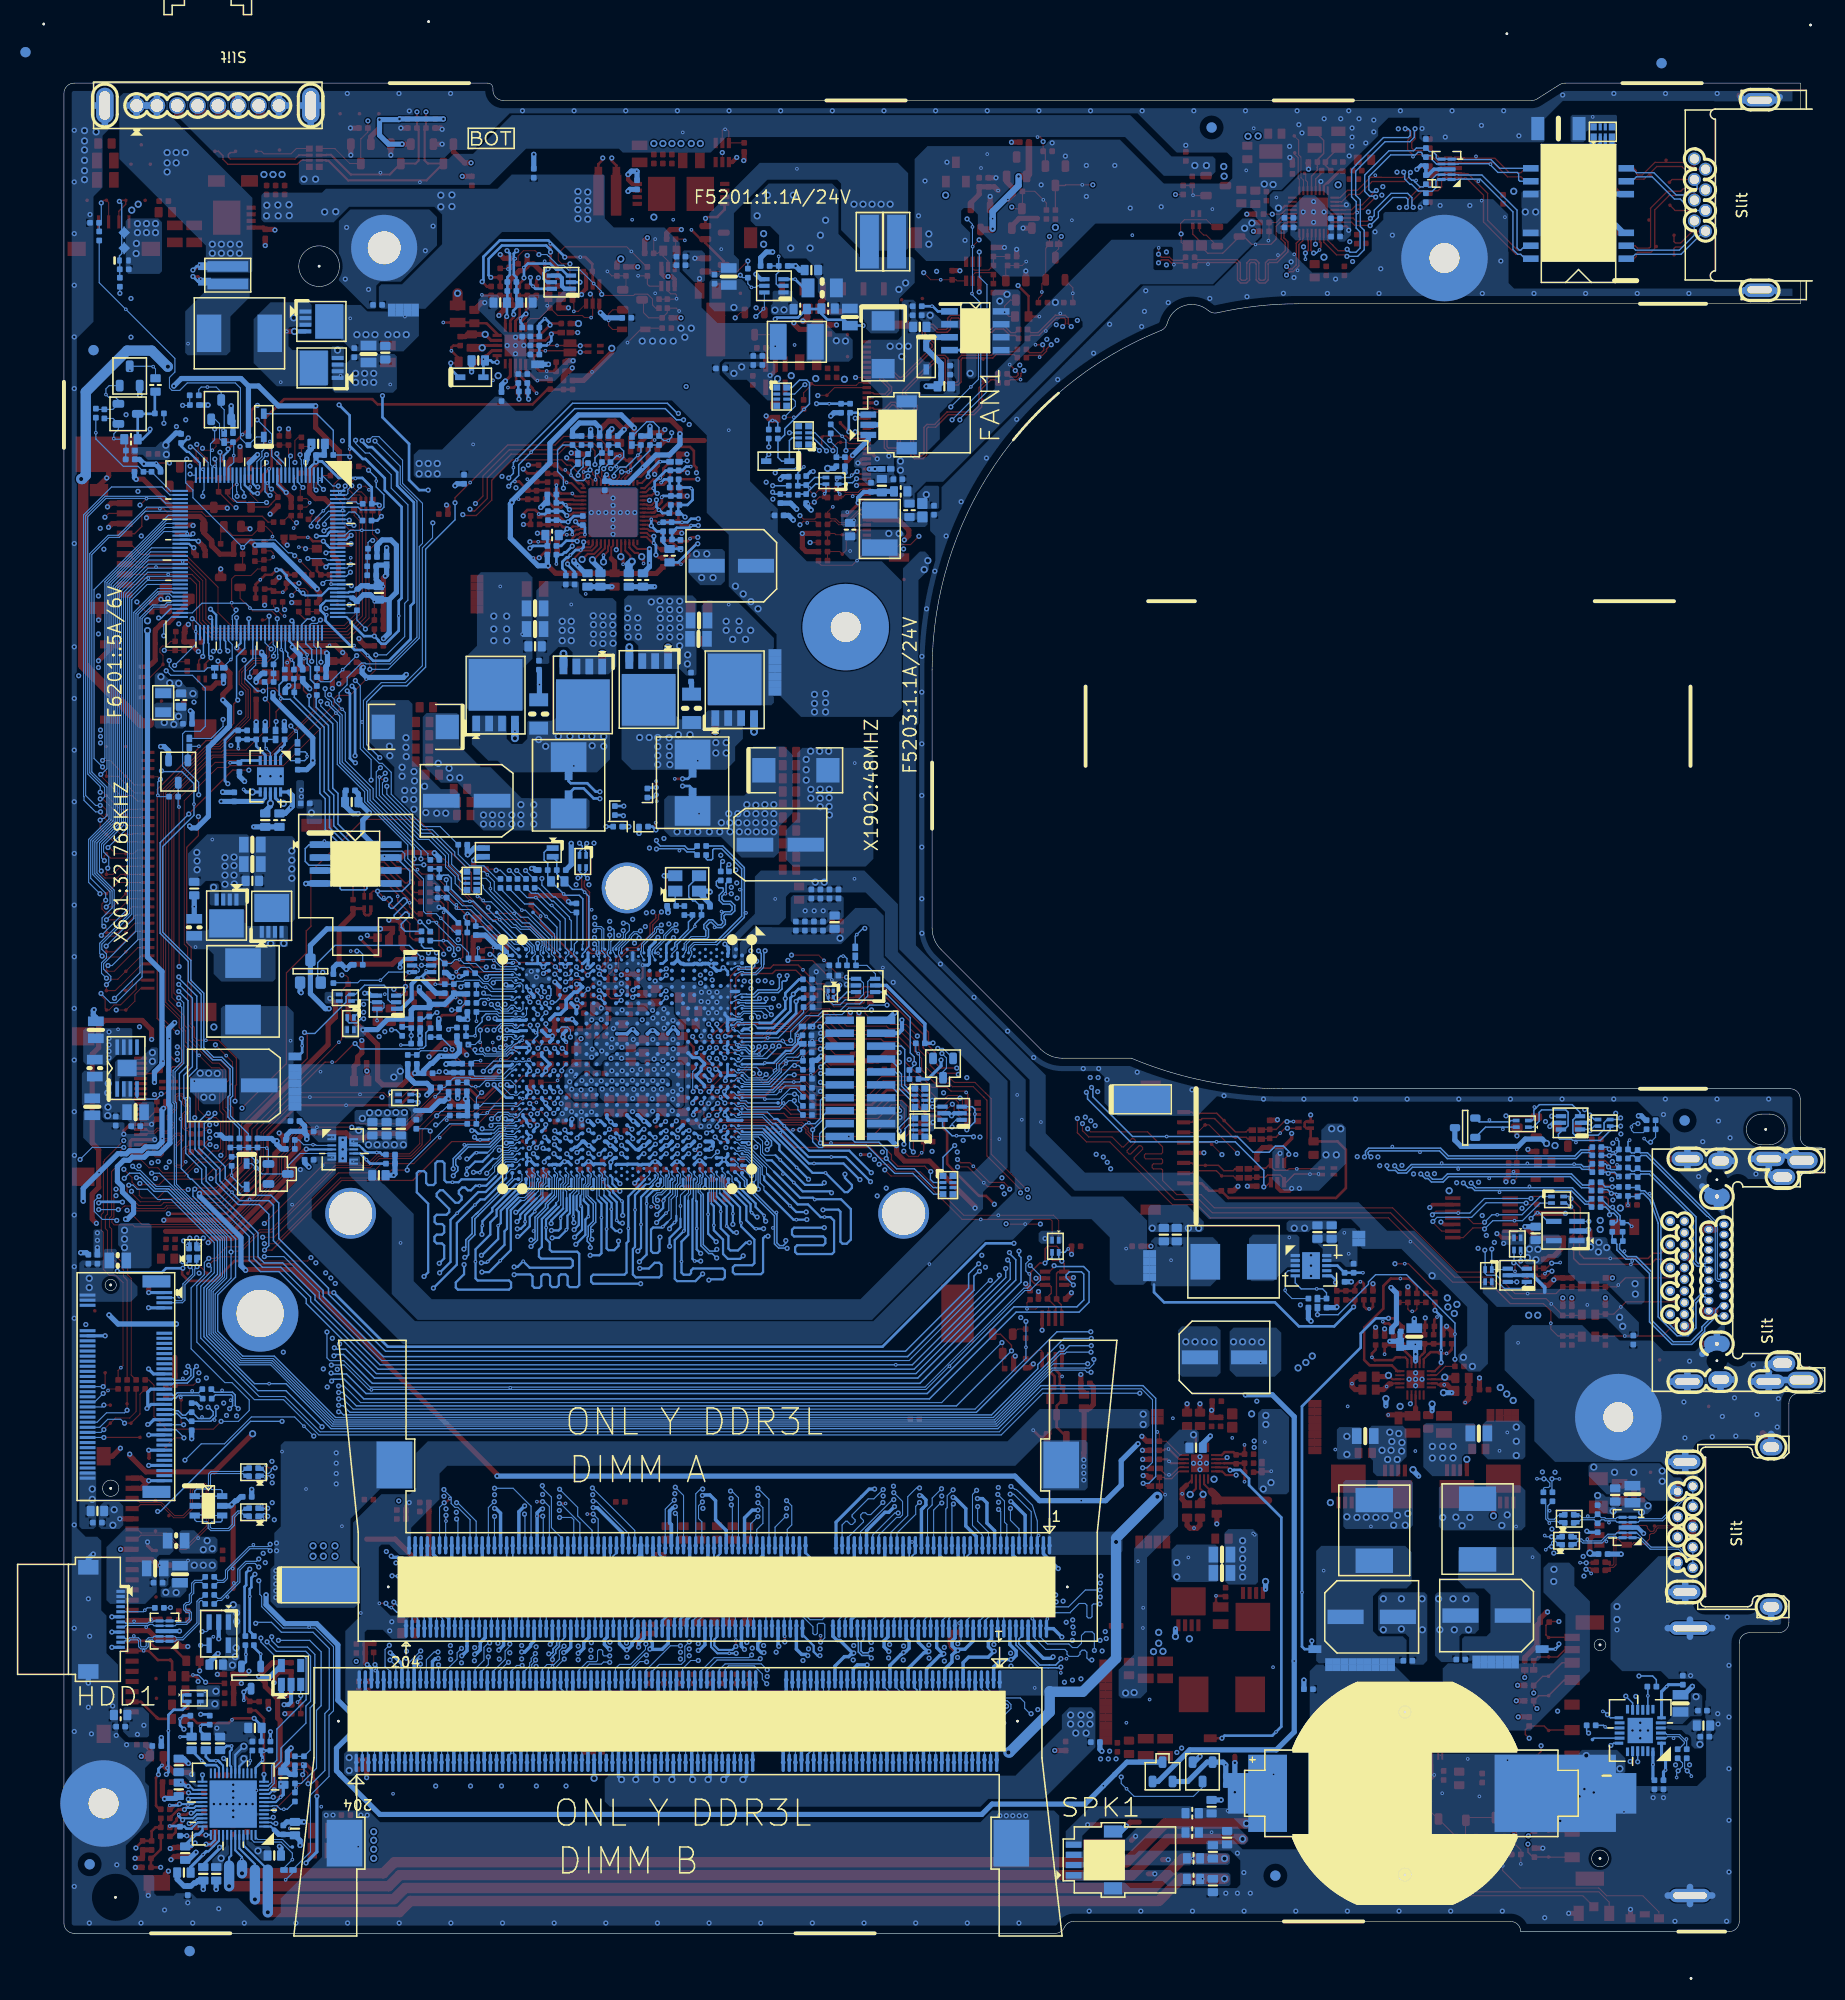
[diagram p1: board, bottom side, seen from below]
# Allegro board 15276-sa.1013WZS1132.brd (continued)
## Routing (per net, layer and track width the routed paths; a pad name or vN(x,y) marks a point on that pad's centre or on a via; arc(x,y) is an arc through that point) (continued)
GND_R1: length 3.9
  TOP w0.508: R6301.2 v2(163.79,36.21) 163.99,36.21 164.55,36.77 CN6301.9
GND_R2: length 2.8
  TOP w0.508: CN6301.15 164.75,30.77 v2(164.65,30.87) R6302.2
V3D3_STB: length 13.6
  TOP w0.127: v1(159.27,24.7) 159.15,24.59 R2712.1
  L3 w0.127: v1(157.49,17.21) 157.72,17.44 157.72,21.07 158.33,21.68 158.91,21.68 159.27,22.03 v1(159.27,24.7)
  BOTTOM w0.127: v2(160.51,25.41) 160.07,25.41 160.03,25.37 159.94,25.37 v1(159.27,24.7) ; HDA27.20 157.15,16.84 157.49,17.18 v1(157.49,17.21)
V18: length 2.9
  BOTTOM w0.305: U3201.24 v2(16.89,16.6) 16.89,15.21 C3201.2
VBAT: length 33.2
  TOP w0.508: v1(147.35,125.92) 147.48,126.04 150.18,126.04 v2(151.24,124.98) 151.21,124.95 R2402.2
  L3 w0.508: v1(147.35,125.92) 146.59,126.68 142.43,126.68 v1(141.76,127.34)
  BOTTOM w0.203: KBC24.102 145.03,131.47 144.89,131.33
  BOTTOM w0.508: R2449.1 R2451.1 147.42,124.63 147.28,124.77 147.28,125.84 v1(147.35,125.92) ; 141.21,131.18 C2405.1 142.58,131.18 143.05,131.65 C2404.1 143.75,131.65 R2404.1 144.44,131.01 144.76,131.33 144.89,131.33 ; 141.21,131.18 141.21,127.9 v1(141.76,127.34) ; 141.21,131.18 140.49,131.89 140.49,136.51 141.03,137.04 141.89,137.04 142.2,136.74 142.2,136.73 142.4,136.52 R2405.1 R2446.1
VDD10: length 5.2
  TOP w0.203: LOM30.3 47.16,169.9 v1(47.05,170.01) ; v1(49.56,172.3) 49.67,172.19 LOM30.30 ; LOM30.8 47.05,167.9 46.82,167.68 v1(46.82,167.5) ; LOM30.22 53.1,169.9 53.32,169.68 v3(53.73,169.68)
  vias: v2(56.17,177.53) v3(55.73,176.77) v3(56.73,176.74)
VDD_095_FB_H: length 2.6
  TOP w0.254: TP422.1 128,79.94 127.08,79.94 v1(126.63,79.49)
  BOTTOM w0.254: CPU1.AV33 127,79.02 126.63,79.39 v1(126.63,79.49)
VDD_095_FB_L: length 1.4
  TOP w0.254: v1(125.81,79.54) 125.81,79.54 125.81,79 TP423.1
  BOTTOM w0.254: v1(125.81,79.54) 125.81,79.54 125.81,79.26 CPU1.AU33
VDDIO_MEM_SENSE: length 3.1
  TOP w0.254: R417.2 107.96,82.33 108.02,82.28 v2(108.62,82.28) 109.23,82.28 v1(109.74,82.78)
  BOTTOM w0.254: CPU1.E25 109.45,82.99 v1(109.74,82.78)
VDDREG:
  vias: v2(53.93,170.72)
0D95_S5_EN: length 13.7
  TOP w0.127: v1(152.33,119.19) 152.33,120.15 151.87,120.61 v2(151.87,121.42) 151.87,121.9 152.45,122.47 153.18,122.47 153.47,122.18 v1(153.6,122.18) 153.66,122.25 R2437.1
  BOTTOM w0.127: v1(153.6,122.18) 154.18,122.18 155.37,123.37 155.37,124.66 154.62,125.41 KBC24.79 ; PR4819.1 152.38,119.14 v1(152.33,119.19)
0D95V_GFX_S0: length 9.5
  TOP w0.508: v1(122.33,88) 122.79,87.54 R703.1
  L4 w0.508: v1(122.33,88) 121.42,88.91 120.35,88.91 119.49,89.77 117.86,89.77 116.86,90.78 v1(115.3,90.78)
0D95V_PWR:
  vias: v2(150.91,87.79)
0D95V_PWRGD: length 5.2
  BOTTOM w0.102: D3603.1 153.08,77.06 v2(153.25,77.23) 153.31,77.29 PR3622.2 R3604.1 R3605.1 C3625.1
0D95V_S0: length 19.7
  TOP w0.508: v1(118.37,94.27) 118.31,94.33 R302.1 R301.1
  L4 w0.254: v1(118.37,94.27) 117.76,94.27 114.76,91.27 114.76,87.7 116.98,85.48 119.72,85.48 120.4,84.8 123.29,84.8 v1(123.3,84.8)
  vias: v1(121.36,83.01) v1(122.32,82.96) v1(123.25,83.02) v1(123.45,83.75) v1(131.52,83.47) v2(122.92,84.26) v3(139.81,77.56) v3(140.7,77.56) v3(141.54,77.56) v3(142.4,77.56) v3(143.24,77.56) v3(144.2,78.98)
0D95V_S0_EN: length 4.7
  BOTTOM w0.102: R3624.2 C3626.1 150.1,78.04 149.62,77.56 v2(148.7,77.56) 148.45,77.56 148.39,77.5 U3603.3
0D95V_S5:
  vias: v1(120.35,89.87) v1(121.29,89.84) v1(126.73,94.07) v1(127.23,94.62) v2(144.08,82.51) v2(147.96,84.75) v3(140.11,84.8) v3(140.75,84.21)
0D95V_S5_PWRGD: length 26.5
  L3 w0.102: v1(147.73,132.75) 147.53,132.75 145.88,131.1 144.91,131.1 141.33,127.52 141.33,125.49 146.56,120.25 149.36,120.25 150.86,118.76 150.88,118.76 v1(150.88,118.75)
  BOTTOM w0.102: PR4821.2 150.22,118.09 v2(150.37,118.23) v1(150.88,118.75) ; v1(147.73,132.75) 147.42,133.07 KBC24.106
0D675V_S0: length 1.7
  TOP w0.33: v1(139.24,42.37) 139.57,42.04 C1210.1
  TOP w0.508: C1211.1 C1210.1
  vias: v1(140.95,30.64) v1(141.16,29.75) v2(144.81,22.77) v3(67.04,51.06) v3(67.04,50.05) v3(144.13,23.12) v3(144.1,22.26) v3(145.14,17.28) v3(145.14,16.01)
1D5V_S0: length 139.6
  TOP w0.508: C1036.1 143.43,84.83 v1(143.4,84.81) 143.34,84.75 C1038.1 ; v1(133.59,86.4) 133.59,86.41 134.75,87.56 135.95,87.56 v1(137.29,86.22) ; C1037.1 C1034.1 122.81,91.18 v1(122.73,91.11) 122.49,91.11 122.23,91.36 C1035.1 ; v1(163.38,70.14) 156.98,70.14 v2(154.93,72.18) 152.45,74.67 152.45,76.66 151.62,77.48 151.62,78.31 v1(152.03,78.71) ; C3607.1 152.7,26.62 v1(154.03,25.28) 153.4,24.65 153.4,24.27 152.18,23.05 152.18,21.17 151.94,20.93 C2719.1 R2705.1 152.15,16.65 152.59,16.22 152.59,15.02 152.51,14.95 v1(152.51,14.11)
  L3 w0.508: v1(152.03,78.71) 151.05,78.71 146.03,83.73 144.48,83.73 v1(143.4,84.81) 141.47,84.81 140.47,85.81 137.7,85.81 v1(137.29,86.22) ; v1(163.38,70.14) 163.38,69.72 163.2,69.54 163.2,65.43 162.14,64.37 v1(162.14,59.93)
  L4 w0.381: v1(133.59,86.4) 133.5,86.4 133.2,86.1 129.43,86.1 128.81,86.73 128.81,87.49 127.92,88.38 126.04,88.38 123.76,90.66 123.18,90.66 v1(122.73,91.11)
  L4 w0.508: v1(154.03,25.28) 154.03,27.03 156,29 156.89,29 158.67,30.78 158.67,31.8 162.28,35.41 162.28,37.2 161.73,37.75 161.73,45.29 164.6,48.16 164.89,48.16 166.17,49.43 166.17,51.65 167.52,53 167.52,59.57 v1(168.76,60.82)
  BOTTOM w0.203: v1(152.51,14.11) 152.61,14.11 153.01,13.71 HDA27.9
  BOTTOM w0.381: CPU1.AL10 122.93,91.11 v1(122.73,91.11) 122.8,91.05 CPU1.AL11
  BOTTOM w0.508: v1(168.76,60.82) 167.88,59.93 v1(162.14,59.93) ; U3602.5 151.83,26.34 153.02,25.16 153.91,25.16 v1(154.03,25.28)
1D5V_S0_EN: length 3.6
  TOP w0.127: v1(149.91,23.38) 149.91,23.38 R3626.1 R3625.2
  BOTTOM w0.127: v2(150.22,22.74) 149.91,23.06 v1(149.91,23.38) U3602.3
1D8V_PWR: length 24.2
  TOP w0.254: PR5009.1 PC5014.1 46.21,61.73 v1(46.34,61.61)
  BOTTOM w0.254: 65.97,63.82 65.97,63.05 64.98,62.06 54.08,62.06 51.72,59.7 48.24,59.7 v1(46.34,61.61)
  vias: v2(64.29,66.2)
1D8V_S0: length 140.6
  TOP w0.203: v1(119.82,143.47) 119.78,143.47 119.58,143.27 PU4601.6
  TOP w0.508: v1(98.74,86.27) 98.43,86.27 97.77,85.61 94.91,85.61 R422.2 R424.2 93.14,85.8 92.31,86.62 v1(91.04,86.62) ; v1(87.71,79.77) 87.8,79.68 R403.1 ; v1(120.5,147.94) 120.4,147.94 120.07,148.27 120.07,148.29 119.62,148.73 118.99,148.73 118.16,147.9 v1(118.09,147.9) 118.09,147.97 117.74,148.32 117.74,148.32 117.37,148.69 117.36,148.69 117.2,148.85 113.52,148.85 112.61,147.94 v1(112.61,147.48) ; v1(91.29,77.48) 91.29,76.73 90.52,75.96 88.06,75.96 83.57,71.47 v1(83.57,71.33)
  L3 w0.406: v1(91.63,93.53) 91.09,93 91.09,90.87 91.4,90.56 v1(91.45,90.56) 91.45,87.03 v1(91.04,86.62)
  L3 w0.508: v1(91.63,93.53) 92.01,93.91 92.01,129.3 95.84,133.13 98.38,133.13 109.76,144.51 109.76,145.47 111.77,147.48 v1(112.61,147.48) ; v1(86.92,85.89) 87.31,85.51 87.31,82.39 87.13,82.21 87.13,80.35 v1(87.71,79.77) 89.24,78.24 90.84,78.24 91.21,77.87 91.21,77.57 v1(91.29,77.48)
  BOTTOM w0.305: R421.1 88.2,84.03 86.92,85.31 v1(86.92,85.89) ; v1(119.82,143.47) 120,143.29 PC4604.1
  BOTTOM w0.508: PC4604.1 119.5,142.82 119.37,142.69 117.68,142.69 114.97,145.4 113.65,145.4 112.61,146.44 v1(112.61,147.48) ; HDT1.19 92.21,89.8 v1(91.45,90.56) ; R434.1 R420.2 99.57,85.86 99.14,85.86 v1(98.74,86.27) ; PR4628.1 v1(120.5,147.94) 120.5,148.09 120.96,148.55 122.49,148.55 123.17,147.86 PR4608.2 PR4634.1 ; HDT1.1 92.18,78.37 v1(91.29,77.48) ; v1(118.09,147.9) PR4645.1
  vias: v1(96.22,93.33) v2(81.19,78.12) v2(92.64,94.98) v2(140.09,67.91) v3(96.86,97.88)
1D8V_S5: length 30.6
  TOP w0.254: v1(136.33,89.95) 136.33,89.96 135.98,90.31 134.82,90.31 133.74,91.39 133.74,91.98 134.09,92.34 134.35,92.34 134.95,92.95 v1(134.95,94.07)
  L4 w0.508: v1(136.33,89.95) 137.04,89.24 139.45,89.24 142.74,85.96 143.15,85.96 148.67,80.44 148.67,76.92 149.94,75.65 v1(149.94,75.12)
  BOTTOM w0.508: v1(136.33,89.95) 136.33,89.78 136.35,89.76 136.35,89.23 136.33,89.21 136.33,89.07 R627.2 ; v1(134.95,94.07) 135.14,94.07 135.57,94.49 R649.1
  vias: v2(68.71,67.35) v2(79.43,82.46) v2(95.44,103.72) v2(150.76,71.66) v3(98.41,103.39) v3(99.3,103.39)
1D8V_S5_PWRGD: length 5.5
  BOTTOM w0.102: PR5011.2 52.39,62.43 53.07,63.1 v2(53.07,63.26) 53.07,64.88 52.78,65.17 PU5002.4
1D35V_PGOOD: length 4
  TOP w0.102: PU4901.20 63.39,47.04 64.75,48.4 PR4904.2 65.45,49.12 v2(65.64,49.31)
1D35V_PWR: length 1.3
  TOP w0.203: v3(62.08,49.03) 61.85,48.8 PU4901.2
  vias: v2(66.4,23) v2(68.69,20.71) v3(67.93,23.68) v3(68.77,23.63)
1D35V_S3: length 133.6
  BOTTOM w0.305: CPU1.W37 116.93,77.08 117.73,77.88 CPU1.AA35 ; CPU1.AL37 123.2,77.08 122.95,77.32 122.75,77.32 CPU1.AJ35 ; CPU1.AR35 125.5,77.9 v1(125.91,78.31) ; CPU1.AE31 119.8,80.2 v1(119.41,79.82) 119.07,79.48 CPU1.AC32
  BOTTOM w0.33: DM2.106 115.05,15.26 v3(114.92,15.12) ; v3(111.36,15.12) 111.45,15.21 DM2.94 111.45,19.38 v1(111.46,19.39) ; DM1.112 111.95,30.84 111.2,31.6 111.2,33.49 111.6,33.89 v1(111.77,33.89) ; v3(106.41,15.12) 106.05,15.48 DM2.76 ; v1(112.99,23.1) 112.95,23.14 DM2.99 ; v3(118.35,15.12) 118.65,15.43 DM2.118 v1(118.65,18.38) ; DM2.123 120.15,22.16 119.52,21.54 119.44,21.54 v1(119.3,21.4) 119.09,21.4 118.35,22.14 DM2.117 ; DM1.82 102.95,28.33 102.88,28.26 v1(102.88,28.23) ; DM2.105 114.75,22.99 v1(115.07,22.67) 115.87,22.67 116.55,23.35 DM2.111 ; v3(109.84,15.12) 109.65,15.31 DM2.88 ; DM2.93 111.15,23.31 111.21,23.25 111.21,23.15 v1(111.21,23.15) ; DM2.124 120.45,18.62 119.7,19.37 119.7,20.01 v1(120.1,20.41) ; DM2.81 107.55,22.95 v1(108.62,21.88) 109.35,22.61 DM2.87 ; DM1.87 104.45,37.16 v1(104.97,36.63) ; DM1.99 108.05,39.63 109.1,40.68 109.1,42.56 109.66,43.11 110.34,43.11 v1(110.4,43.06) ; v1(106.26,27.93) 106.56,28.23 106.56,28.44 106.57,28.46 106.57,28.81 106.55,28.83 DM1.94 ; DM1.124 115.55,28.84 115.32,28.6 115.32,28.24 115.56,27.99 v1(115.56,27.96) 115.56,27.96 115.53,27.93 114.36,27.93 113.75,28.53 DM1.118 ; v1(110.6,34.68) 109.85,35.43 DM1.105 ; DM1.123 115.25,37.1 114.46,36.31 114.46,34.05 113.65,33.23 v1(113.44,33.23) ; DM1.76 101.15,27.95 100.63,27.43 100.15,27.43 v1(100.03,27.32) ; v1(106.08,22.77) 106.08,22.86 105.75,23.18 DM2.75 ; DM1.93 106.25,40.86 105.49,41.62 v1(104.93,41.62) ; DM1.81 102.65,35.89 102.32,35.56 102.31,35.56 v1(102.09,35.34) ; DM1.88 104.75,28.71 104.95,28.51 104.95,27.97 104.59,27.61 v1(104.35,27.61) ; v3(108.31,15.12) 107.85,15.59 DM2.82 ; v1(101.78,33.39) 100.85,34.32 DM1.75 ; DM2.100 113.25,15.27 v3(113.39,15.12) ; v1(111.63,35.15) 111.5,35.28 111.44,35.28 111.12,35.6 111.12,36.05 111.65,36.58 DM1.111 ; v1(110.8,27.82) 110.7,27.82 110.15,28.38 DM1.106 ; v1(107.02,33.26) 107.13,33.26 108.35,32.04 DM1.100 ; v3(116.95,15.12) 116.85,15.22 DM2.112 v1(116.85,18.42)
  BOTTOM w0.356: DM1.117 113.45,40.2 113.62,40.37 113.62,41.54 113.29,41.87 113.16,41.87 v1(113.06,41.97) ; v1(117.2,79.88) 117.25,79.88 117.8,80.43 CPU1.AA31 ; v1(115.05,79.88) 114.8,80.13 CPU1.R31
  BOTTOM w0.381: v1(117.2,79.88) 117.1,79.88 CPU1.W32 ; CPU1.W37 116.64,77.08 116.24,77.48 v1(116.15,77.48) 116.04,77.48 115.64,77.88 CPU1.U35 ; CPU1.W31 116.75,80.48 v1(116.15,79.88) 116,79.88 CPU1.U32 ; v1(112.8,78.99) 112.31,79.48 CPU1.L32 ; CPU1.R37 114.46,77.08 114.06,77.48 v1(113.95,77.48) 113.78,77.48 113.4,77.86 CPU1.N35 ; CPU1.J35 111.6,77.48 v1(111.75,77.48) 111.87,77.48 112.27,77.08 CPU1.L37 ; v1(121.65,79.88) 121.5,79.88 CPU1.AG32 ; v1(123.22,80.08) 123.3,80 CPU1.AL32 ; CPU1.AJ35 122.05,77.88 121.65,77.48 v1(121.57,77.48) 121.5,77.48 CPU1.AG37 ; CPU1.AE35 119.85,77.88 v1(119.45,77.48) 119.3,77.48 118.9,77.08 CPU1.AC37
  vias: v1(95.82,32.73) v1(97.39,35.47) v1(97.37,33.13) v1(98.81,27.98) v1(98.89,32.68) v1(99.76,33.32) v1(102.12,41.79) v1(104.02,25.26) v1(104.93,43.06) v1(104.97,34.45) v1(106.1,20.43) v1(106.38,34.33) v1(107.57,42.77) v1(107.78,20.58) v1(108.52,34.91) v1(109.71,21.35) v1(110.35,41.79) v1(111.11,20.74) v1(111.69,27.98) v1(112.55,27.65) v1(113.11,43.24) v1(113.14,20.56) v1(114.71,20.74) v1(115.45,19.82) v1(117.46,19.92) v1(118.09,20.86) v2(77.32,39.13) v2(77.71,24.14) v2(89.77,38.49) v2(109.96,36.84) v3(72.27,21.47) v3(72.27,20.58) v3(72.65,19.7) v3(73.16,21.47) v3(73.16,20.58) v3(73.67,19.7) v3(74.18,21.47) v3(74.18,20.58)
3D3V_AUX_KBC: length 155
  TOP w0.508: v1(152.92,139.58) 152.15,140.35 R2436.1 ; R2622.1 v1(153.46,130.63) ; v3(119.31,155.89) 119.31,155.51 v2(121.25,153.57) 122.09,152.73 PR4439.1 ; D4301.2 134.89,175.23 133.79,174.13 v1(133.15,174.13) ; D4303.2 v1(139.94,175.97) ; v1(154.29,123.07) 153.17,123.07 R2402.1 152.89,124.06 R2414.2 ; D4302.2 143.02,176.7 142.16,177.56 v1(142.16,178.38) ; PR4412.1 v1(140.19,178.45) ; 159.39,122.46 158.71,122.46 158.2,122.97 v1(157.5,122.97) ; v1(146.16,122.9) 145.96,122.9 145.52,123.33 R2403.2 144.75,123.81 R2434.1 ; PR4415.1 v1(135.87,178.45) ; v1(166.1,143.01) 165.39,143.01 162.62,140.25 Q2402.D 157.21,140.25 v1(157.13,140.17)
  L3 w0.508: v1(157.13,140.17) 156.55,139.58 v1(152.92,139.58) ; v3(119.31,155.89) 119.31,156.14 118.58,156.87 118.58,161.51 131.2,174.13 v1(133.15,174.13) ; v1(146.16,122.9) 146.61,123.35 152.49,123.35 152.76,123.07 v1(154.29,123.07) 154.51,123.07 154.66,122.92 155.19,122.92 155.34,123.07 157.4,123.07 v1(157.5,122.97)
  L4 w0.508: v1(133.15,174.13) 133.15,175.73 v1(135.87,178.45) ; v1(154.29,123.07) 154.29,124.59 154.85,125.15 154.85,128.09 153.98,128.96 153.98,130.11 v1(153.46,130.63) 153.46,138.25 152.92,138.8 v1(152.92,139.58) 152.13,140.37 152.13,144.03 151.62,144.54 151.62,145.49 149.44,147.66 126.65,147.66 119.59,154.72 119.59,155.61 v3(119.31,155.89)
  BOTTOM w0.508: v1(135.87,178.45) v1(140.19,178.45) 140.25,178.38 v1(142.16,178.38) 142.16,176.86 141.27,175.97 v1(139.94,175.97) ; R2418.2 153.73,123.91 154.29,123.35 v1(154.29,123.07) ; R2453.2 166.26,143.18 v1(166.1,143.01) ; R2413.2 v1(157.5,122.97)
3D3V_AUX_KBC_VCC: length 71.6
  TOP w0.508: C2408.1 154.67,144.92 v1(154.16,145.43) ; v1(150.73,126.5) 150.56,126.68 v2(147.07,126.68) 146.48,126.68 v1(145.78,125.97) 145.52,125.72 R2403.1 C2411.1 ; v1(156.19,126.43) 155.76,125.99 C2410.1 ; v1(144.96,136.67) 145.03,136.6 C2406.1 ; C2409.1 160.43,135.76 v1(160.43,136.28)
  L3 w0.508: v1(161.91,128.79) 161.53,128.41 161.53,128.4 160.19,127.06 156.83,127.06 v1(156.19,126.43) 155.48,126.43 154.77,127.14 153.7,127.14 153.68,127.16 151.92,127.16 151.26,126.5 v1(150.73,126.5) ; v1(160.79,144.31) 159.75,144.31 158.97,143.52 156.06,143.52 v1(154.16,145.43)
  L4 w0.508: v1(144.96,136.67) 145.67,136.67 146.15,136.19 146.15,126.34 v1(145.78,125.97) ; v1(160.79,144.31) 160.94,144.16 161.05,144.16 161.42,143.78 161.42,143.67 161.45,143.65 161.45,142.61 161.22,142.38 161.22,136.99 160.51,136.28 v1(160.43,136.28) 160.43,130.9 161.91,129.42 v1(161.91,128.79)
  BOTTOM w0.203: KBC24.88 151.02,127.07 150.73,126.78 v1(150.73,126.5) ; 154.99,144.6 155.02,144.57 KBC24.19 ; v1(156.19,126.43) 156.19,126.51 155.82,126.88 KBC24.76 ; KBC24.46 160.9,136.67 160.51,136.28 v1(160.43,136.28) ; KBC24.115 v1(144.96,136.67)
  BOTTOM w0.508: v1(154.16,145.43) 154.99,144.6 ; C2407.1 149.71,124.5 149.97,124.76 149.97,125.74 v1(150.73,126.5)
3D3V_AUX_S5: length 399.5
  TOP w0.508: PR4419.1 127,164.2 125.72,162.91 PR4434.1 ; PR4419.1 v1(127.63,165.02) ; PR4419.1 127.63,163.98 128.07,163.54 128.38,163.54 129.39,162.52 PR4438.2 ; PR4435.1 124.06,153.13 123.9,153.3 PR4417.1 123.54,153.63 123.27,153.89 123.26,153.89 v1(123.2,153.96) ; R2425.2 148.04,131.16 148.04,131.85 148.29,132.1 v1(148.29,132.22) 148.6,132.52 148.78,132.52 149.6,133.35 R2611.1 ; v1(147.05,91.96) 146.49,91.4 146.49,90.1 147.21,89.38 147.21,87.4 155.29,79.33 155.29,75.62 158.05,72.86 159.77,72.86 v1(159.87,72.76) ; R2434.2 144.27,125.02 v1(143.76,124.51) ; v1(42.65,63.51) 42.08,62.94 PR4530.1 ; v1(130.59,44.97) 130.59,45.14 150.74,65.29 155.25,65.29 v1(155.33,65.21) ; v1(165.08,139.22) 164.94,139.36 159.83,139.36 159.44,138.97 Q2402.S 159.44,137.75 158.67,136.98 C2417.2 158.67,136.47 157.84,135.65 R2439.1 156.51,136.7 156.27,136.94 154.82,136.94 v1(154.41,136.54) R2431.2
  L3 w0.508: v1(155.48,125.23) 155.05,124.8 153.63,124.8 153.22,124.39 145.08,124.39 144.96,124.51 v1(143.76,124.51) ; v1(139.53,123.81) 147.48,115.85 147.48,97.85 146.54,96.91 146.54,93.56 147.05,93.05 v1(147.05,91.96) ; v1(42.65,63.51) 43.8,63.51 45.07,62.24 46.6,62.24 47.23,61.62 47.23,61.47 49.25,59.45 52.94,59.45 56.98,55.4 v1(56.98,52.97) 59.78,50.18 63.61,50.18 65.64,48.14 v1(67.55,48.14) ; v1(127.63,165.02) 127.63,164.84 121.57,158.78 121.57,157.63 122.4,156.81 123.08,156.81 123.76,156.13 123.76,154.41 123.36,154.01 123.27,154.01 123.22,153.96 v1(123.2,153.96)
  L4 w0.508: v1(165.08,139.22) 165.08,143.14 165.97,144.03 165.97,145.71 164.09,147.58 164.09,148.69 163.19,149.59 127.74,149.59 123.44,153.89 123.26,153.89 v1(123.2,153.96) ; v1(154.41,136.54) 154.41,131.12 156.01,129.53 156.09,129.53 v1(156.22,129.4) 156.22,128.05 155.48,127.32 v1(155.48,125.23)
  BOTTOM w0.203: KBC24.75 v1(156.22,129.4)
  BOTTOM w0.508: v1(143.76,124.51) 143.87,124.39 143.87,123.96 143.43,123.52 139.81,123.52 v1(139.53,123.81) ; v1(155.33,65.21) 155.79,65.67 155.79,68.44 159.87,72.53 v1(159.87,72.76) ; v1(148.29,132.22) 152.61,136.54 v1(154.41,136.54) ; v1(56.98,52.97) 56.98,52.97 54.34,52.97 52.18,50.81 v2(52.18,26.78) 52.18,19.8 53.94,18.04 62.46,18.04 65.57,14.93 D2501.1 ; PR4526.2 42.59,59.51 42.12,59.98 42.12,62.98 v1(42.65,63.51) ; v1(130.59,44.97) 79.65,44.97 77.24,42.56 70.72,42.56 69.2,44.08 69.2,46.49 v1(67.55,48.14)
3D3V_CAMERA_S0: length 7.5
  TOP w0.305: LCD1.32 94.76,141.02 v1(95.08,140.7) 95.08,140.57 96.2,139.46 AFTP5227.1
  BOTTOM w0.406: v1(95.08,140.7) 95.08,141.21 94.52,141.77 93.82,141.77 EC5210.1
  BOTTOM w0.508: R5229.2 92.64,141.82 C5207.1 92.81,141.78 EC5210.1
3D3V_CARD_S0: length 13.3
  L3 w1.016: v3(20.14,16.19) 20.14,18.85 20.15,18.85 20.15,21.04 18.78,22.41 13.52,22.41 v3(12.66,23.28)
  vias: v3(23.45,17.49)
3D3V_LAN_S5: length 1.5
  TOP w0.203: 49.56,165.8 49.56,166.27 49.67,166.38 LOM30.11
  vias: v2(60.23,169.58) v3(47.86,171.97) v3(49.26,164.86) v3(59.11,173.77) v3(59.08,172.82)
3D3V_PWR:
  vias: v2(28.73,36.99)
3D3V_PWR_2: length 2
  BOTTOM w0.508: PR4526.1 41.76,59.13 PG4538.1 v2(42.78,58.23)
3D3V_PWR_2_R: length 4
  TOP w0.203: v1(40.24,56.96) PU4509.3
  BOTTOM w0.508: v2(40.24,56.3) v1(40.24,56.96) 40.24,57.72 PC4528.1 40.77,57.85 41,57.62 PG4538.2
3D3V_S0: length 328.4
  TOP w0.254: v1(142.17,140.45) 142.17,139.56 v1(141.97,139.36)
  TOP w0.356: THM26.1 v1(75.03,57.68)
  TOP w0.406: Q2601.2 v1(77.58,64.43) ; v1(73.9,64.5) 73.97,64.43 Q2601.5 ; Q6202.2 53.83,76.46 v1(53.58,76.72) ; v1(52.43,73.26) 52.69,73.01 53.49,73.01 53.83,73.35 Q6202.5
  TOP w0.508: v1(133.69,82.07) 133.71,82.04 133.71,81.98 134.2,81.49 134.75,81.49 v1(135.36,82.1) 135.39,82.13 136.61,82.13 139.55,79.18 139.81,79.18 139.94,79.06 139.94,78.8 140.06,78.67 143.09,78.67 143.52,78.24 144.97,78.24 145.45,78.73 148.55,78.73 148.58,78.75 149.57,78.75 150.12,78.2 150.12,77.27 151.32,76.07 151.32,74.26 156.52,69.05 163.2,69.05 ; R1301.2 143.49,28.52 C1334.1 C1306.1 143.56,26.62 v1(143.36,26.43) ; v1(124.11,88.17) 124.09,88.19 C1022.1 C1023.1 ; R3014.1 56.29,168.26 v3(56.34,168.21) ; v1(77.85,56.01) 78.23,55.62 R2604.1 ; R2603.1 78.16,63.46 v1(78.59,63.89) ; R2701.1 C5802.1 162.35,7.57 v1(162.67,7.25) ; R6110.1 34.27,9.19 Q6105.G v1(33.51,9.22) ; R2624.1 146.2,134.95 146.74,135.49 146.74,140.3 147.56,141.11 148.45,141.11 149.03,141.68 149.03,142.21 149.02,142.22 R2401.2 149.02,143.94 148.4,144.55 v1(148.4,144.72) ; C3612.1 150.86,23.73 151.19,23.4 v1(151.65,23.4) ; C1202.1 C1201.1 137.31,37.25 v1(138.05,36.51) 138.36,36.51 140.62,38.77 143.42,38.77 ; Q5401.C v1(30.27,78.43) ; R5812.2 162.29,56.65 ; C2601.1 72.85,53.2 73.17,53.52 C2602.1 v1(73.17,54.96) ; R429.2 v1(25.51,70.81) ; R3625.1 v1(151.47,21.6)
  L3 w0.508: v1(149.97,8.65) 150.5,9.18 158.08,9.18 158.59,8.67 158.59,8.5 159.84,7.25 v1(162.67,7.25) ; v1(112,152.13) 111.95,152.18 103.72,152.18 v3(103,152.89) ; 164.07,145.17 164.07,143.52 163.43,142.89 155.33,142.89 154.42,143.8 149.32,143.8 v1(148.4,144.72) ; v1(87.81,76.91) 90.46,74.26 92.29,74.26 93.25,73.29 94.96,73.29 95.54,73.86 95.54,77.4 93.76,79.18 v1(93.76,90.82) ; v1(87.81,76.91) 87.17,76.91 85.17,78.9 85.17,80 85.55,80.38 85.86,80.38 v1(85.88,80.4) 85.88,80.61 85.58,80.91 83.8,80.91 83.09,80.2 v1(83.09,78.32) ; v1(87.81,76.91) 86.82,75.93 86.82,66.66 82.3,62.14 78.11,62.14 ; v1(135.62,85.48) 136.9,85.48 139.65,82.74 141.03,82.74 v1(141.08,82.69) 141.36,82.97 145.78,82.97 150.81,77.94 v1(152.25,77.94)
  L4 w0.356: v1(124.11,88.17) 124.59,87.69 127.69,87.69 128.12,87.26 128.12,86.35 128.89,85.58 132.29,85.58 133.07,84.8 134.9,84.8 135.4,85.29 135.43,85.29 v1(135.62,85.48)
  L4 w0.508: v1(115.55,148.22) 115.55,148.58 v1(112,152.13)
  BOTTOM w0.203: KBC24.4 149.02,144.15 148.92,144.25 148.92,144.26 148.8,144.38 148.79,144.38 148.45,144.72 v1(148.4,144.72) ; HDA27.1 152.85,10.51 152.51,10.17
  BOTTOM w0.254: v1(148.4,144.72) 148.36,144.77 147.81,144.77 146.18,143.14 143.85,143.14 142.92,142.21 R2441.2 142.32,140.6 v1(142.17,140.45) ; R2412.2 142.37,138.95 v1(141.97,139.36)
  BOTTOM w0.33: v1(143.36,26.43) 143.15,26.21 143.15,26.2 142.95,26 DM2.199 ; DM1.199 v1(138.05,36.51)
  BOTTOM w0.356: Q5502.5 Q5502.2 28.72,64.72 27.54,63.54 27.54,63.07 ; CPU1.AM15 124.11,88.46 v1(124.11,88.17) 124.11,88 CPU1.AM17
  BOTTOM w0.406: Q5402.5 26.68,79.72 v1(27.03,79.36) ; Q403.2 85.63,80.66 v1(85.88,80.4) 86.14,80.66 Q403.5 ; Q5402.2 v1(23.1,79.72)
  BOTTOM w0.508: v3(164.98,128.13) 164.98,96.02 163.56,94.6 163.56,85.61 163.56,85.61 163.56,85.53 163.56,85.53 163.56,85.45 164.29,84.71 v1(164.29,83.7) ; v1(135.62,85.48) 135.55,85.55 C1024.1 134.03,85.55 R639.2 ; 152.51,10.17 152.06,9.73 C2717.1 150.57,9.73 C2716.1 149.97,9.13 v1(149.97,8.65) ; R635.2 R604.2 ; R604.2 133.51,81.89 v1(133.69,82.07) 133.58,82.18 R642.1 ; R604.2 R601.2 R603.2 ; R3624.1 151.8,77.15 152.25,77.61 v1(152.25,77.94) 152.53,77.94 152.78,78.18 PR3622.1 ; R2415.2 161.77,147.56 162.19,147.56 163.18,146.57 v3(163.18,146.37) ; 138.64,80.93 137.17,80.93 136.24,81.86 135.81,81.86 135.57,82.1 v1(135.36,82.1) R638.1 ; PR4615.1 PR4614.1 v1(115.55,148.22) ; U3602.1 151.81,23.57 v1(151.65,23.4) ; C2413.1 147.59,146.43 R2443.2 148.38,145.4 C2412.1 v1(148.4,144.72) ; R5208.1 97.43,144.08 v3(98.08,144.08)
  vias: v1(51.67,73.26) v1(76.69,68.34) v2(23.35,61.81) v2(31.2,17.03) v2(35.11,17.16) v2(49.79,74.69) v2(145.85,40.04) v2(161.86,62.62) v3(12.28,18.58) v3(19.87,59.7) v3(20.17,60.59) v3(30.84,18.17) v3(31.73,18.17) v3(32.6,18.17) v3(33.43,18.17) v3(34.27,18.17) v3(35.11,18.17) v3(35.95,18.17) v3(36.81,18.17) v3(47.61,79.13) v3(48.04,76.57) v3(48.5,79.13) v3(49.05,76.57) v3(57.06,167.7) v3(75.67,160.41) v3(90.91,144.79) v3(90.91,143.9) v3(101.66,153.2) v3(146.54,38.11) v3(146.54,37.09) v3(147.68,38.11) v3(147.68,37.09) v3(148.7,38.11) v3(148.7,37.09) v3(163.13,145.45) v3(164.98,129.09) v3(167.24,69.15) v3(167.24,68.29) v3(167.24,67.45)
3D3V_S5: length 451.1
  TOP w0.254: RN2501.3 143.01,100.32 143.2,100.14 143.52,100.14 143.66,100.28 RN2501.4
  TOP w0.305: R2501.2 144.76,100.78 RN2501.4
  TOP w0.508: R2429.2 v1(150.79,130.88) ; PD4203.2 79.96,167.94 79.23,168.67 77.43,168.67 ; R3033.2 v1(56.84,169.08) ; R1913.1 146.1,145.74 148.44,148.09 v1(148.44,150.23) ; v1(123.22,89.92) 123.27,89.87 C1001.1 ; v1(67.16,48.88) 66.68,48.4 PR4904.1 ; R650.2 145.24,90.31 v1(143.8,88.86) 142.35,87.41 142.35,83.96 141.84,83.45 139.94,83.45 138.79,84.59 v1(138.69,84.59) 137.29,84.59 136.8,84.1 131.06,84.1 130.38,84.78 v1(130.38,84.79) ; C1002.1 138.67,96.1 139,95.77 140.46,95.77 140.9,95.32 144.93,95.32 v1(145.42,94.83) 146.13,95.54 146.13,98.84 144.76,100.21 R2501.2 ; R2712.2 v1(158.11,25.47) ; v1(163.41,81.14) 163.16,81.38 R5610.2 ; PR4211.2 v1(85.07,163.52) ; v1(112.47,167.57) 113.55,167.57 113.91,167.21 PR4473.2
  L3 w0.508: v1(165.34,144.54) 167.09,146.29 v1(167.09,149.36) ; v3(60.81,173.87) 60.81,173.05 v1(56.84,169.08) ; v1(143.15,110.21) 141.56,110.21 137.42,106.07 137.42,105.7 136.99,105.27 136.99,101.59 136.33,100.93 v1(136.3,100.93) 136.48,100.75 136.48,98.46 137.35,97.6 v1(137.35,96.43) ; v1(85.07,163.52) 86.02,163.52 87.23,164.73 105.14,164.73 107.97,167.57 v1(112.47,167.57) ; v1(169.81,131.53) 167.44,131.53 167.32,131.66 167.32,131.84 167.19,131.96 152.66,131.96 151.58,130.88 v1(150.79,130.88) ; v3(38.62,64.68) 44.54,64.68 45.97,63.26 47.48,63.26 49,61.73 49,60.72 49.51,60.21 v1(50.53,60.21) 64.75,60.21 65.89,59.07 65.89,49.67 66.68,48.88 v1(67.16,48.88) ; v1(171.55,66.94) 171.55,60.38 v1(171.05,59.88)
  L4 w0.254: v1(123.22,89.92) 122.87,89.57 122.87,86.85 123.79,85.93 127.33,85.93 127.74,85.52
  L4 w0.381: 127.74,85.52 128.47,84.79 v1(130.38,84.79)
  L4 w0.508: v1(171.55,66.94) 171.53,66.96 171.53,70.72 171.3,70.95 v1(171.3,72.02) 171.3,73.42 170.87,73.85 170.87,78.42 171.13,78.67 171.13,123.41 171.12,123.42 171.12,123.95 171.13,123.96 171.13,128.74 169.81,130.06 v1(169.81,131.53) 169.81,134.66 171.14,135.99 171.14,140.43 170.24,141.34 170.24,143.43 169.68,143.99 169.68,149.29 ; v1(150.79,130.88) 150.83,130.85 150.83,129.95 151.54,129.24 151.54,125.03 152.64,123.94 v1(152.64,122.03) ; v1(85.07,163.52) 80.61,163.52 76.36,167.78 v3(75.67,167.78) ; v1(143.15,110.21) 148.29,115.35 v1(148.72,115.35) ; v1(138.23,93.05) 138.01,93.28 137.79,93.28 137.35,93.73 v1(137.35,96.43) ; 168.69,149.36 v1(167.09,149.36) 166.75,149.36 163.93,152.18 v1(162.39,152.18) ; v1(171.05,59.88) 171.05,49.65 167.06,45.65 166.92,45.65 163.06,41.8 163.06,38.75 164.4,37.41 164.4,33.72 163.35,32.67 162.46,32.67 160.79,31.01 160.79,29.95 159.81,28.97 159.48,28.97 158.68,28.16 158.68,26.05 v1(158.11,25.47)
  BOTTOM w0.254: R1911.1 134.41,99.38 135.85,100.82 136.2,100.82 v1(136.3,100.93)
  BOTTOM w0.356: CPU1.AM13 123.25,89.88 v1(123.22,89.92) 122.8,89.5 CPU1.AL13
  BOTTOM w0.508: v1(163.41,81.14) 163.56,80.99 163.56,77.83 164.04,77.35 165.18,77.35 165.43,77.1 165.56,76.97 166.75,76.97 167.05,76.67 167.58,76.67 167.61,76.69 167.87,76.69 v2(169.75,74.82) 171.3,73.26 v1(171.3,72.02) ; R648.1 146.69,94.98 146.36,95.31 145.9,95.31 v1(145.42,94.83) 144.99,95.26 R608.2 ; 155.05,152.18 155.79,152.92 161.65,152.92 v1(162.39,152.18) ; 155.05,152.18 154.06,152.18 152.1,150.23 v1(148.44,150.23) ; 155.05,152.18 R2421.2 ; R5810.1 170.99,66.94 v1(171.55,66.94) ; R2452.2 163.7,144.02 164.17,144.49 165.29,144.49 v1(165.34,144.54) 165.77,144.97 R6215.1 ; PR5011.1 50.78,60.46 v1(50.53,60.21) ; 138.62,84.59 138.62,84.67 138.49,84.8 R1929.2 ; 138.62,84.59 v1(138.69,84.59) ; 138.62,84.59 R617.2 137.83,84.85 137.12,85.56 136.99,85.56 136.28,86.27 v2(136.08,86.27) 134.73,86.27 134.3,86.7 R634.2 134.54,87.65 R626.2 ; v1(138.23,93.05) 138.23,92.64 137.26,91.67 R1915.1 ; R1915.1 136.95,91.37 135.74,91.37 134.85,92.27 R1927.2 134.78,92.4 R630.2 ; R1915.1 137.28,91.04 138.79,91.04 139.04,90.8 R1918.2 141.34,89.92 142.37,88.89 143.57,88.89 ; v1(152.64,122.03) 152.64,121.48 148.72,117.57 v1(148.72,115.35) 148.72,115.05 149.32,114.45 PR4835.1 ; C2502.1 144.23,112.06 C2501.1 144.23,111.01 143.95,111.01 v1(143.15,110.21) 143.15,110.14 143.8,109.49 143.8,108.11 142.88,107.2 142.34,107.2 142.21,107.07 SSKT2.8
  vias: v2(40.75,68.03) v2(77.1,79.79) v3(26.63,35.8) v3(26.65,34.61) v3(33.64,21.22) v3(34.14,20.33) v3(34.65,55.76) v3(34.65,21.22) v3(35.16,20.33) v3(35.54,56.65) v3(35.67,21.22) v3(36.18,20.33) v3(36.68,21.22) v3(61.96,173.87) v3(88.22,135.01) v3(88.58,134.12) v3(148.44,172.53) v3(149.59,172.53) v3(165.89,170.06) v3(166.53,169.48)
3D3V_WLAN_S0:
  vias: v3(170.42,43.7) v3(170.42,42.68) v3(170.71,64.43) v3(170.71,63.51)
3D_VEDIO: length 29.2
  TOP w0.127: v1(90.59,76.93) 90.59,76.9 90.09,76.4 89.2,76.4 v2(88.83,76.77) 88.63,76.97 R426.2 88.63,78.51 R403.2
  L4 w0.127: v1(109.71,86.09) 109.06,85.44 108.9,85.44 108.88,85.42 107.41,85.42 106.45,84.46 106.45,82.68 101.05,77.29 95.86,77.29 95.65,77.49 92.45,77.49 91.99,77.04 90.72,77.04 90.61,76.93 v1(90.59,76.93)
  BOTTOM w0.127: CPU1.E21 109.71,85.79 v1(109.71,86.09)
32K_X1: length 12.1
  BOTTOM w0.14: X601.4 124.72,105.48 C603.1 124.72,104.23 R623.1 123.17,102.68 122.26,102.68 v2(121.98,102.4) 121.57,101.99 121.57,101.5 121.57,97.05 121.87,96.75 arc(121.89,96.66) 121.94,96.58 122.2,96.33 CPU1.AJ2
32K_X2: length 13
  BOTTOM w0.14: X601.1 125.54,106.74 125.97,106.31 125.97,105.57 125.61,105.22 C604.1 125.61,103.8 R623.2 v2(124.04,102.23) 123.91,102.09 122.5,102.09 122.16,101.75 122.16,97.32 122.2,97.27 CPU1.AJ1
48M_X1: length 10.2
  BOTTOM w0.102: CPU1.N2 113.4,96.32 112.88,96.84
  BOTTOM w0.14: 112.88,96.84 112.88,97.27 111.13,99.01 v2(111.13,99.05) 111.13,99.27 110.48,99.92 R1905.1 110.48,100.93 C1904.2 111.09,101.53 111.34,101.53 111.74,101.94 111.74,103 X1902.3
48M_X2: length 5
  BOTTOM w0.14: R1930.2 112.16,100.16 R1905.2 111.37,99.86 111.77,99.47 111.77,98.74 113.12,97.39 113.12,97.06 CPU1.N1
51123_PGOOD_2: length 5.7
  BOTTOM w0.102: RN602.1 144.8,91.81 143.27,91.81 143.04,91.58 Q601.5 141.84,91.58 141.71,91.45 141.71,91.04 141.83,90.93 Q601.6 142.4,89.78 v2(142.4,89.78)
+0D675V_DDR_P:
  vias: v2(64.12,50.66)
+DC_IN: length 2.2
  BOTTOM w0.508: PR4212.1 104.67,164.79 104.1,165.36 v1(103.49,165.36)
  vias: v3(90.41,162.32) v3(91.07,161.68) v3(98.28,168.49) v3(98.79,167.02) v3(99.8,165.75) v3(101.45,170.95) v3(101.71,165.75) v3(103.99,170.95) v3(105.01,168.92)
+DC_IN_C:
  vias: v2(101.1,173.54) v2(108.54,165.64) v3(91.93,170.06) v3(92.82,170.06) v3(93.71,170.06) v3(94.6,170.06) v3(95.49,170.06)
+PWR_SRC_1D35V:
  vias: v2(62.59,36.97) v2(67.04,32.01) v2(67.55,36.59) v3(63.74,36.46) v3(63.74,35.06)
+RTC_VCC: length 4.9
  TOP w0.508: AFTP2502.1 v1(58.02,16.77)
  BOTTOM w0.508: v1(58.02,16.77) 58.02,16.77 R2502.2 57.5,15.47 RTC1.1
AC_IN#: length 96.2
  TOP w0.102: PR4433.1 126.46,158.81 127.29,158.81 127.79,158.31 PU4404.5 ; PR4433.1 125.53,160.02 PC4401.1 125.61,161.02 PR4434.2 PR4425.2 ; PR4433.1 124.63,159.12 122.21,159.12 122,158.91 v2(121.34,158.91) 121.19,159.07 PQ4408.5 121.19,161 v1(121.42,161.22)
  L3 w0.102: v1(162.14,148.19) 162.14,150.28 161.67,150.74 147.21,150.74 146.36,149.9 145.8,149.9 144.51,151.19 142.44,151.19 142.05,150.8 129.56,150.8 129.22,150.46 127.26,150.46 124.7,153.01 122.89,153.01 121.32,154.58 121.32,156.44 120.76,157 120.76,159.12 121.42,159.78 v1(121.42,161.22)
  L4 w0.102: v1(162.85,125.18) 162.85,125.77 162.57,126.05 162.57,130.11 162.11,130.57 162.11,147.58 162.14,147.6 v1(162.14,148.19)
  BOTTOM w0.102: v1(162.85,125.18) 162.85,124.62 162.36,124.14 159.39,124.14 159.06,124.47 R2430.1 158.39,124.44 R2413.1
AC_IN#_G: length 4.5
  BOTTOM w0.127: PR4213.1 102.89,163.4 103.13,163.16 103.13,162.22 102.95,162.04 PQ4206.2 ; PR4213.1 v2(102.89,164.93) ; PR4213.1 PR4212.2
AC_IN_KBC#: length 94.5
  TOP w0.102: v1(162.31,124.7) 161.95,125.07 R2426.1
  L3 w0.102: v1(161.22,148.85) 161.07,148.7 159.72,148.7 158.56,147.53 155.07,147.53 155.04,147.56 153.28,147.56 153.25,147.53 145.83,147.53 144.51,148.86 130.28,148.86 130,148.58 126.48,148.58 123.92,151.13 122.11,151.13 118.06,155.18 109.94,155.18 106.11,159.01 v1(105.14,159.01)
  L4 w0.102: v1(161.22,148.85) 161.22,147.89 161.88,147.23 161.88,130.47 162.34,130.01 162.34,128.61 162.34,128.61 162.34,124.73 v1(162.31,124.7)
  BOTTOM w0.102: PQ4206.6 104.3,159.85 v2(104.38,159.77) v1(105.14,159.01) ; KBC24.65 160.22,126.8 160.28,126.73 160.28,126.73 161.52,125.49 161.53,125.49 v1(162.31,124.7)
AC_PRESENT: length 119.9
  TOP w0.102: v1(157.77,76.52) 157.77,76.64 157.56,76.85 157.56,80.57 157.87,80.88 157.87,83.91 157.59,84.19 157.59,84.79 157.93,85.13 158.68,85.13 v2(159.91,86.35) 161.22,87.67 161.22,88.75 161.64,89.17 161.64,90.02 163.19,91.57 163.19,112.15 158.86,116.49 157.84,116.49 154.85,119.48 154.85,122.41 155.43,123 155.43,124.01 154.52,124.93 153.27,124.93 v1(152.59,125.61)
  L3 w0.102: v1(157.77,76.52) 157.77,76.34 148.42,66.99 v1(148.42,65.95)
  L4 w0.102: v1(148.42,65.95) 148.42,67.82 148.73,68.14 148.73,72.65 146.63,74.75 146.21,75.17 146.21,78.9 141.71,83.4 139.45,83.4 138.96,83.88 137.19,83.88 136.33,84.75 v1(136.28,84.75) 135.84,84.3 133.06,84.3 132.14,85.23 128.52,85.23 127.54,86.21 124.41,86.21 123.38,87.24 v1(123.38,88.15)
  BOTTOM w0.102: v1(152.59,125.61) 152.59,125.94 152.38,126.15 152.38,126.5 152.62,126.74 KBC24.84 ; CPU1.AP15 124.24,89.13 123.65,89.13 123.38,88.86 v1(123.38,88.15) ; v1(136.28,84.75) 136.43,84.59 R617.1
AD+: length 54.2
  TOP w0.406: PR4405.1 153.58,167.77 PU4403.4
  TOP w0.508: v1(152.45,167.52) 152.51,167.59 PR4405.1 ; PR4407.1 v3(122.59,158.33) ; PR4469.1 118.8,164.3 v3(118.42,164.68)
  TOP w1.016: PR4408.1 v3(134.47,161.3)
  L3 w1.016: v3(134.47,161.3) 134.25,161.53 127.11,161.53 123.91,158.33 v3(122.59,158.33)
  L4 w0.508: v3(134.47,161.3) 135.74,162.57 142.35,162.57 147.3,167.52 v1(152.45,167.52)
  L4 w1.016: v3(115.17,168.79) 118.42,165.54 v3(118.42,164.68) 119.41,163.69 119.41,159.07 120.15,158.33 v3(122.59,158.33)
  vias: v2(113.27,168.54)
AD+_G_1: length 4.7
  TOP w0.102: PQ4402.5 108.44,177.33 108.34,177.43 v2(108.16,177.43) 107.98,177.43 107.79,177.24 PQ4402.6 107.78,176.1 PR4401.1
AD+_G_2: length 16.3
  TOP w0.406: v1(117.71,172.98) 117.71,172.48 117.29,172.06 PU4402.4
  TOP w0.508: v1(106.33,174.36) 106.28,174.41 PR4401.2
  L4 w0.508: v1(106.33,174.36) 106.81,173.87 116.82,173.87 v1(117.71,172.98)
  BOTTOM w0.508: v1(117.71,172.98) 117.38,173.32 v2(116.85,173.32) 116.82,173.29 PR4403.2
AD+_TO_SYS: length 1
  BOTTOM w0.508: PR4403.1 117.52,171.52 v1(117.71,171.33)
  vias: v2(117.3,168.54)
AD_IA: length 62
  TOP w0.254: C2414.2 v1(142.67,127.58) ; PR4422.2 v1(122.66,157.44)
  L3 w0.254: v1(122.66,157.44) 123.68,157.44 124.29,156.83 124.29,154.54 125.13,153.7 127.29,153.7 129.26,151.74 144.72,151.74 v1(146.13,150.33)
  BOTTOM w0.203: 144.99,129.04 145.42,129.47 KBC24.97
  BOTTOM w0.254: v1(146.13,150.33) 145.09,149.29 145.09,146.3 143.8,145.01 143.53,145.01 141.64,143.11 141.64,141.95 139.99,140.3 139.99,131.33 140.27,131.05 v2(140.27,129.58) 140.27,128.12 141.55,126.83 141.98,126.83 142.27,127.13 142.27,127.19 v1(142.67,127.58) 143.68,127.58 144.99,128.89 144.99,129.04
AD_IA_HW: length 64
  TOP w0.254: v2(125.92,164.45) 125.92,164.04 v1(125.58,163.71)
  L3 w0.254: v1(141.87,151.23) 129.22,151.23 127.14,153.32 123.01,153.32 121.62,154.71 121.62,156.85 121.06,157.41 121.06,158.99 125.58,163.51 v1(125.58,163.71)
  L4 w0.254: v1(137.37,141.95) 141.76,141.95 143.8,139.91 143.8,133.61 144.86,132.54 v1(144.93,132.54)
  BOTTOM w0.203: v1(144.93,132.54) 145.05,132.67 KBC24.105
  BOTTOM w0.254: v1(137.37,141.95) 138.26,141.95 139.25,142.94 139.25,146.49 141.87,149.11 v1(141.87,151.23) ; v1(125.58,163.71) 125.6,163.71 126.02,163.3 126.02,162.72 125.69,162.39 PQ4407.5
AD_IA_HW2: length 55.2
  TOP w0.254: v1(157.06,145.98) v2(155.63,147.41) 154.77,148.27 154.77,149.79 154.29,150.28 v1(154.16,150.28)
  L3 w0.254: v1(154.16,150.28) 153.47,149.59 145.68,149.59 144.38,150.89 142.57,150.89 142.17,150.49 129.69,150.49 129.34,150.15 127.14,150.15 124.58,152.71 122.76,152.71 120.91,154.56 120.91,156.41 119.92,157.4 119.92,159.65 120.81,160.54 120.81,161.56 121.64,162.39 v1(122.44,162.39)
  BOTTOM w0.203: v1(157.06,145.98) 157.06,145.75 157.49,145.32 157.49,144.92 157.42,144.85 KBC24.25
  BOTTOM w0.254: PQ4407.2 v1(122.44,162.39)
AD_OFF_L: length 5
  TOP w0.254: v2(111.48,167.54) 110.55,166.62 PQ4205.B 110.1,166.27 108.3,164.46 PQ4204.C
AD_OFF_R: length 48
  TOP w0.254: PU4201.4 108.2,169.54 108.95,168.79 109.96,168.79 v1(110.09,168.67) 110.1,168.65 PQ4205.C ; v1(79.35,162.06) 78.32,161.03 PC4208.1 v2(77.25,159.01)
  L4 w0.254: v1(110.09,168.67) 110.09,167.4 104.12,161.43 104.12,159.27 103.61,158.76 v1(103.23,158.76) ; v1(79.35,162.06) 79.37,162.04 84.21,162.04 85,161.24 88.93,161.24 90.02,160.16 92.56,160.16 v1(94.6,158.13)
  BOTTOM w0.254: v1(94.6,158.13) PC4201.2 96.46,158.7 98.09,158.7 98.69,159.29 PR4207.2 98.74,159.75 PR4208.1 100.16,159.75 101,158.91 103.08,158.91 v1(103.23,158.76)
ALERT#: length 4.3
  TOP w0.102: THM26.6 76.33,61.5 76.46,61.63 77.38,61.63 77.6,61.4 78.44,61.4 v2(78.47,61.43) 78.47,62.03 R2603.2
ALL_SYS_PWRGD: length 84.9
  TOP w0.127: v1(152.25,145.53) 152.05,145.32 ED2402.1
  L4 w0.127: v1(163.61,114.34) 163.61,114.85 159,119.46 159,123.09 160.42,124.51 160.42,126.43 159.07,127.78 158.29,127.78 156.81,129.26 156.81,131.27 156.06,132.01 156.06,137.72 153.72,140.07 153.72,140.91 153.65,140.97 153.65,143.5 152.25,144.89 v1(152.25,145.53)
  BOTTOM w0.127: KBC24.10 151.42,144.46 152.25,145.3 v1(152.25,145.53) ; R3604.2 155.05,78.62 156.81,80.39 156.81,82.14 156.61,82.35 156.61,85.12 157.65,86.17 158.47,86.17 159.44,87.14 159.44,92.47 159.58,92.6 159.58,92.6 160.71,93.74 160.71,95.7 163.48,98.47 163.48,106.89 160.41,109.97 v2(160.41,111.06) 160.41,113.07 161.6,114.26 163.53,114.26 v1(163.61,114.34)
AMBER_LED_BAT: length 3
  TOP w0.102: Q6104.C 44.18,6.67 v2(44.18,6.11) 44.5,5.79 R6103.2
AMP_MUTE#: length 166.6
  L3 w0.102: v1(159.54,141.34) 161.91,141.34 163.2,140.04 167.77,140.04 v1(169.63,138.19) ; v1(168,70.11) 167.44,70.67 166.72,70.67 166.4,70.36 166.4,69.98 164.27,67.85 164.27,64.73 163.56,64.02 163.56,59.77 161.84,58.05 160.99,58.05 154.11,51.16 154.11,47.97 156.18,45.9 156.18,35.75 155.11,34.68 v1(154.03,34.68)
  L4 w0.102: v1(169.63,138.19) 168.41,136.97 168.41,92.97 169.17,92.21 169.17,90.21 169.81,89.57 169.81,79.51 169.55,79.26 169.55,72.68 v1(169.76,72.48)
  BOTTOM w0.102: KBC24.30 159.42,141.95 159.54,141.82 v1(159.54,141.34) ; v1(169.76,72.48) 170.21,72.02 170.21,71 169.43,70.22 168.1,70.22 v1(168,70.11) ; v2(151.39,5.27) 150.67,5.99 R2708.1 150.67,6.3 148.95,8.01 148.95,13.6 147.12,15.43 147.12,21.45 146.69,21.89 146.69,28.2 148.52,30.03 151.64,30.03 153.75,32.13 153.75,33.15 153.93,33.34 153.93,34.58 v1(154.03,34.68)
APU_ALERT#: length 30.5
  TOP w0.127: v1(104.19,87.21) 103.48,86.5 101.84,86.5 100.67,87.67 100.67,88.49 99.55,89.61 98.52,89.61 96.87,87.96 92.83,87.96 92.57,87.7 91.23,87.7 90.49,86.97 90.49,85.75 89.42,84.68 89.29,84.68 87.81,83.2 86.32,83.2 85.95,82.83 84.58,82.83 v2(84.45,82.7) 84.29,82.54 RN405.8
  BOTTOM w0.127: v1(104.19,87.21) 104.92,86.49 105.79,86.49 106.2,86.9 106.64,86.9 106.72,86.81 106.99,86.81 107.07,86.9 107.31,86.9 CPU1.B18
APU_DBRDY: length 11.7
  TOP w0.127: v1(98.76,85.2) 99.52,84.44 v2(99.73,84.44) v1(101.37,84.44)
  BOTTOM w0.127: HDT1.14 97.98,85.99 v1(98.76,85.2) ; CPU1.B25 106.94,83.28 106.63,82.96 103.46,82.96 101.99,84.44 v1(101.37,84.44)
APU_DBREQ#: length 12.3
  TOP w0.127: v1(101.33,85.35) v2(100.52,86.16) 99.7,86.98 v1(98.79,86.98)
  BOTTOM w0.127: CPU1.A25 103.63,83.28 101.56,85.35 v1(101.33,85.35) 100.92,85.35 R434.2 ; v1(98.79,86.98) 98.71,87.06 98.41,87.06 98.2,87.26 HDT1.16
APU_DIGON: length 7.4
  BOTTOM w0.127: R404.1 101.26,88.48 101.26,87.62 101.53,87.36 102.09,87.36 v2(102.43,87.7) 104.54,87.7 104.57,87.68 CPU1.A17
APU_LPC_AD0: length 10.8
  BOTTOM w0.102: CPU1.AT2 126.05,96 126.35,96.3 126.35,96.6 126.26,96.68 126.26,97.07 126.17,97.17 126.17,97.54 127.37,98.75 128.3,98.75 128.75,99.2 128.92,99.2 131.18,101.46 131.83,101.46 v2(131.96,101.59) 132.59,102.22 RN1901.5
APU_LPC_AD1: length 10.3
  BOTTOM w0.102: RN1901.6 132.19,103.27 131.93,103.01 131.93,102.77 128.17,99 127.34,99 125.96,97.63 125.96,97.05 126.05,96.97 CPU1.AT1
APU_LPC_AD2: length 11.6
  BOTTOM w0.102: CPU1.AR2 125.5,96.35 125.8,96.65 125.8,96.91 125.76,96.94 125.76,97.71 127.43,99.38 128.11,99.38 131.25,102.51 v2(131.25,102.75) 131.25,103.34 131.68,103.77 RN1901.7
APU_LPC_AD3: length 11.4
  BOTTOM w0.102: RN1901.8 131.84,104.42 v2(131.55,104.12) 130.87,103.44 130.87,102.56 128.24,99.93 127.55,99.93 125.5,97.88 CPU1.AR1
APU_PWROK: length 22.1
  TOP w0.102: v1(103.49,87.26) 102.93,87.82 v2(102.52,87.82) v1(101.71,87.82)
  BOTTOM w0.102: v1(103.49,87.26) 104.48,86.27 106.63,86.27 106.8,86.44 107.05,86.44 CPU1.B19 ; R418.2 95.36,95.28 R414.2 94.21,95.2 93.38,94.37 93.38,93.9 U402.3 93.86,93.88 94.13,93.61 94.13,92.19 94.91,91.41 96.18,91.41 96.82,90.77 98.51,90.77 99.02,90.26 100.19,90.26 101.71,88.74 v1(101.71,87.82)
APU_PWROK_C: length 2.4
  BOTTOM w0.127: C402.1 97.02,95.91 96.82,96.11 v2(96.55,96.11) 96.41,96.11 96.18,95.87 R414.1
APU_PWROK_HDT: length 38.1
  TOP w0.102: v1(101.63,96.21) 98.95,96.21 v2(98.44,95.7) 96.77,94.03 v1(96.22,94.03)
  L4 w0.102: v1(101.63,96.21) 102.08,96.21 103.63,94.66 106.21,94.66 107.55,93.33 107.55,89.07 106.18,87.7 102.65,87.7 98.79,83.83 v1(98.79,83.7)
  BOTTOM w0.102: RN408.3 98.02,91.84 97.52,91.33 96.83,91.33 96.34,91.82 95.08,91.82 94.55,92.35 94.55,93.46 94.97,93.88 U402.4 96.03,93.88 96.18,94.03 v1(96.22,94.03) ; v1(98.79,83.7) 98.53,83.45 HDT1.10
APU_RST#: length 34.3
  TOP w0.127: v1(89.55,85.55) 89.57,85.56 89.57,86.18 89.96,86.57 89.96,87.06 91.03,88.14 92.39,88.14 92.65,88.39 96.69,88.39 98.48,90.18 99.74,90.18 101.03,88.89 v2(101.03,88.32) 101.03,87.63 101.56,87.11 102.7,87.11 v1(102.85,87.26)
  BOTTOM w0.127: U402.1 92.47,92.58 89.95,90.05 89.95,86.6 89.55,86.2 v1(89.55,85.55) 89.57,85.53 89.57,85.38 R409.2 R421.2 ; v1(102.85,87.26) 104.07,86.04 106.38,86.04 106.71,85.71 106.98,85.71 107.29,86.03 CPU1.B20
APU_RST#_C: length 2.8
  BOTTOM w0.102: C401.1 89.4,86.76 v2(89.16,86.52) 89.03,86.4 89.03,85.02 R409.1
APU_RST_L_BUF: length 33.2
  TOP w0.127: v1(96.88,93.25) 96.93,93.31 97.19,93.31 v2(97.66,93.78) 99.55,95.67 101.97,95.67 v1(101.99,95.69)
  L4 w0.127: v1(98.76,84.57) 99.12,84.57 102.46,87.91 106.09,87.91 107.34,89.16 107.34,93.24 106.12,94.45 103.23,94.45 v1(101.99,95.69)
  BOTTOM w0.127: v1(98.76,84.57) 98.74,84.59 98.15,84.59 98.03,84.72 HDT1.12 ; v1(96.88,93.25) 96.88,92.71 97.51,92.09 RN408.4 97.52,91.96 97.31,91.75 97.01,91.75 96.18,92.58 U402.6
APU_SIC: length 61.2
  TOP w0.102: RN405.7 84.69,81.03 84.82,81.16 84.82,81.93 v1(85.05,82.15) 85.3,82.41 86.23,82.41 86.58,82.06 87.26,82.06 89.46,84.26 92.78,84.26 93.77,83.27 99.72,83.27 100.41,83.96 100.53,83.96 100.58,84.01 103.65,84.01 v1(104.13,84.48) ; RN2601.1 76,70.06 76.16,70.22 v2(83.01,70.22) 84.84,70.22 89.11,74.48 91.85,74.48 v1(92.46,75.09)
  L3 w0.102: v1(85.05,82.15) 85.15,82.05 85.99,82.05 86.52,81.52 86.52,80.17 85.83,79.49 v1(85.83,79.31) 85.83,79.26 87.54,77.56 88.27,77.56 90.3,75.53 91.72,75.53 92.16,75.09 v1(92.46,75.09)
  BOTTOM w0.102: Q403.1 85.44,80.01 85.83,79.61 v1(85.83,79.31) ; v1(104.13,84.48) 104.47,84.14 105.82,84.14 106.37,84.68 106.67,84.68 106.72,84.63 106.99,84.63 107.29,84.93 CPU1.B22
APU_SID: length 61.5
  TOP w0.102: v1(93.01,75.64) 92.12,75.64 91.37,74.89 89.28,74.89 89.28,74.89 88.94,74.89 84.67,70.62 v2(81.29,70.62) 75.85,70.62 75.35,70.12 RN2601.2 ; v1(104.76,84.57) 104.76,84.26 104.25,83.75 100.49,83.75 99.12,82.38 94.09,82.38 92.62,83.86 89.9,83.86 88.25,82.2 88.25,81.76 87.77,81.29 v1(87.76,81.29) 86.77,81.29 86.06,82 85.51,82 85.22,81.72 85.22,81 84.76,80.53 RN405.6
  L3 w0.102: v1(93.01,75.64) 92.27,75.64 91.82,76.09 91.82,78.12 91.57,78.37 91.57,81.27 91.17,81.67 88.15,81.67 87.97,81.49 v1(87.76,81.29)
  BOTTOM w0.102: Q403.4 86.79,81.29 v1(87.76,81.29) ; CPU1.B21 107.01,85.29 106.76,85.29 106.64,85.18 105.06,85.18 104.81,84.92 104.81,84.62 v1(104.76,84.57)
APU_SPI_CLK: length 29.7
  TOP w0.14: v1(135.85,96.3) 135.85,96.71 136.31,97.18 136.31,99.18 v2(136.55,99.42) 137.26,100.12 R1925.1
  L4 w0.127: v1(125.93,92.6) 125.93,92.68 126.44,93.18 128.77,93.18 128.9,93.31 128.9,94.91 129.02,95.03 129.28,95.03 129.41,94.91 129.41,94.04 129.53,93.91 129.79,93.91 129.91,94.04 129.91,95.21 130.04,95.34 130.29,95.34 130.42,95.21 130.42,94.09 130.55,93.97 130.87,93.97 131,94.09 131,94.35 131.2,94.55 132.24,94.55 132.47,94.78 132.47,95.93 132.6,96.06 133.71,96.06 133.84,96.19 133.84,96.44 133.71,96.57 131.71,96.57 131.58,96.7 131.58,97.13 131.71,97.25 134.86,97.25 134.98,97.38 134.98,97.61 135.11,97.74 135.8,97.74 136.15,97.38 136.15,96.94 136.02,96.81 135.97,96.81 135.85,96.68 v1(135.85,96.3)
  BOTTOM w0.14: v1(125.93,92.6) 125.93,92.68 126.2,92.95 CPU1.AU7
APU_SPI_CS0#: length 22.3
  TOP w0.14: R1908.1 136.15,101.48 135.85,101.19 v2(135.85,100.42) 135.85,97.35 v1(135.31,96.81)
  L4 w0.127: v1(127.36,91.59) 128.06,91.59 128.78,92.31 131.1,92.31 131.86,93.08 132.37,93.08 132.49,92.95 132.49,92.75 132.62,92.62 136.02,92.62 136.13,92.72 136.13,93.25 136,93.38 135.54,93.38 135.41,93.51 135.41,93.91 135.54,94.04 136,94.04 136.13,94.17 136.13,95.46 136,95.59 135.44,95.59 135.31,95.72 v1(135.31,96.81)
  BOTTOM w0.14: v1(127.36,91.59) 127.7,91.93 CPU1.AW9
APU_SPI_HOLD#: length 18.7
  TOP w0.14: v2(126.22,92.09) 126.22,91.89 v1(126.54,91.57)
  L4 w0.127: v1(126.54,91.57) 126.74,91.57 127.16,91.15 128.99,91.15 129.12,91.28 129.12,91.81 129.24,91.93 132.13,91.93 132.38,92.19 136.28,92.19 136.56,92.47 v1(136.56,96.44)
  BOTTOM w0.14: R1923.1 138.03,97.17 137.75,96.88 137,96.88 v1(136.56,96.44) ; v1(126.54,91.57) 126.2,91.22 CPU1.AU11
APU_SPI_SI_R: length 26.6
  TOP w0.14: R1921.1 136.43,102.37 v2(136,101.94) 135.96,101.91 135.95,101.91 135.41,101.37 135.41,97.81 v1(134.41,96.81)
  L3 w0.127: v1(131.83,91.45) 131.33,91.96 130.82,91.96 130.41,92.37 130.41,93.64 131.26,94.49 131.74,94.49 132.5,95.25 132.68,95.25 132.98,94.94 133.16,94.94 133.34,95.12 133.34,95.3 132.86,95.78 132.86,95.96 133.04,96.14 133.22,96.14 134.07,95.29 134.25,95.29 134.43,95.47 134.43,95.65 133.76,96.32 133.76,96.57 133.99,96.81 v1(134.41,96.81)
  L4 w0.127: v1(125.81,91.48) 126.01,91.48 126.45,91.03 126.87,91.03 127.03,90.87 131.48,90.87 131.83,91.22 v1(131.83,91.45)
  BOTTOM w0.14: v1(125.81,91.48) 125.81,91.35 125.44,90.98 CPU1.AR11
APU_SPI_SO_R: length 28
  TOP w0.14: R1922.1 136.71,103.26 v2(134.6,101.15) 133.55,100.11 133.55,95.67 132.92,95.03 v1(131.66,95.03)
  L4 w0.127: v1(131.66,95.03) 132.01,95.39 132.01,95.59 131.88,95.72 129.25,95.72 129.08,95.55 128.94,95.55 128.75,95.74 128.75,95.92 129.88,97.06 129.88,97.24 129.7,97.42 129.52,97.42 128.39,96.28 128.21,96.28 128.12,96.37 127.94,96.37 127.76,96.19 127.76,96.01 128.58,95.19 128.58,95.01 126.98,93.41 126.33,93.41 125.97,93.05 125.75,93.05 125.49,92.79 125.49,92.13 v1(125.56,92.06)
  BOTTOM w0.14: v1(125.56,92.06) 125.49,92.06 125.3,92.25 125.3,92.88 CPU1.AR7
APU_SPI_WP#: length 24.5
  TOP w0.14: v2(127.5,92.13) 127.19,92.13 126.62,92.7 v1(126.62,92.74)
  L4 w0.127: v1(134.83,96.23) 134.83,95.76 134.7,95.63 133.03,95.63 132.9,95.5 132.9,95.24 133.03,95.11 135.34,95.11 135.47,94.98 135.47,94.68 135.34,94.55 133.97,94.55 133.84,94.42 133.84,94.37 133.71,94.24 133.43,94.24 133.08,94.6 132.9,94.6 132.72,94.42 132.72,94.24 133.54,93.41 133.54,93.23 133.36,93.05 133.18,93.05 132.36,93.88 132.18,93.88 131.07,92.77 128.13,92.77 128,92.64 128,92.29 127.87,92.16 126.75,92.16 126.62,92.29 v1(126.62,92.74)
  BOTTOM w0.14: CPU1.AU9 126.62,92.5 v1(126.62,92.74) ; R1924.1 v2(135.87,97.64) 135.5,97.64 134.86,97 134.86,96.26 v1(134.83,96.23)
APU_SVC: length 246.3
  TOP w0.127: v1(108.18,81.66) v2(102.41,81.66) 101.75,81 93.52,81 92.71,81.8 92.08,82.43 90.44,82.43 89.64,81.64 v1(89.64,76.85) ; v1(132.72,140.63) 131.99,141.36 131.99,143.32 129.4,145.91 124.75,145.91 123.99,146.67 121.23,146.67 120.43,145.87 120.43,145.07 v1(119.41,144.05)
  L4 w0.127: v1(89.64,76.85) 89.64,76.8 88.25,75.4 87.77,75.4 85.02,72.65 85.02,69.6 81.19,65.77 v1(81.19,64.73) ; v1(161.91,94.07) 161.43,94.55 161.43,95.82 162.34,96.73 162.34,106.62 159.04,109.92 159.04,113.82 154.61,118.25 144.37,118.25 140.95,121.67 140.95,125.99 139.63,127.31 139.63,135.04 134.04,140.63 v1(132.72,140.63)
  BOTTOM w0.127: RN407.7 89.9,79.01 90.02,78.89 90.02,77.22 v1(89.64,76.85) ; v1(108.18,81.66) 108.6,82.08 CPU1.D27 ; v1(161.91,94.07) 161.91,93.96 160.13,92.18 160.13,85.05 160.98,84.2 160.98,82.32 160.79,82.13 160.79,76.9 159.21,75.32 159.21,73.99 154.11,68.89 154.11,66.55 153.5,65.95 151.69,65.95 148.5,62.76 148.5,62.31 142.11,55.92 89.75,55.92 81.19,64.48 v1(81.19,64.73) ; v1(119.41,144.05) 119.26,144.05 118.14,145.17 118.14,145.79 PR4645.2 PR4638.1 119.62,145.77 PR4653.1
APU_SVD: length 243.4
  TOP w0.127: v1(90.57,77.61) 90.57,78.18 90.09,78.67 90.09,81.25 90.76,81.93 91.98,81.93 92.29,81.61 92.72,81.18 93.34,80.57 101.7,80.57 102.3,81.17 108.42,81.17 v1(108.89,81.64) ; v1(122.61,143.39) 122.61,143.65 123.36,144.4 123.72,144.4 124.24,144.92 v2(128.66,144.92) 129.11,144.92 131.12,142.9 131.12,140.96 132.63,139.45 133.88,139.45 v1(133.97,139.53)
  L4 w0.127: v1(90.57,77.61) 90.35,77.38 89.54,77.38 87.99,75.83 87.59,75.83 84.59,72.82 84.59,69.78 80.56,65.75 v1(80.56,65.38) ; v1(161.91,93.33) 161,94.24 161,96 161.91,96.91 161.91,106.44 158.6,109.74 158.6,113.65 154.43,117.82 144.19,117.82 140.52,121.49 140.52,125.81 139.2,127.13 139.2,134.86 134.83,139.23 134.27,139.23 v1(133.97,139.53)
  BOTTOM w0.127: v1(108.89,81.64) 109.4,81.13 CPU1.E29 ; v1(122.61,143.39) 122.61,143.75 122.13,144.23 122.13,145.01 PR4652.1 121.39,145.74 PR4648.1 PR4634.2 ; v1(90.57,77.61) 90.46,77.73 90.46,79.16 90.11,79.51 RN407.6 ; v1(80.56,65.38) 80.56,64.5 89.57,55.48 142.29,55.48 148.93,62.13 148.93,62.58 151.87,65.51 153.68,65.51 154.54,66.37 154.54,68.71 159.65,73.81 159.65,75.14 161.22,76.72 161.22,81.95 161.41,82.14 161.41,84.38 160.56,85.23 160.56,91.98 v1(161.91,93.33)
APU_SVT: length 245.9
  TOP w0.127: v1(120.96,144.46) 120.96,145.79 121.41,146.24 123.81,146.24 124.57,145.48 129.22,145.48 131.55,143.14 131.55,141.13 132.81,139.88 133.07,139.88 v1(133.26,140.07) ; v1(91.04,78.9) 90.52,79.42 90.52,81.07 90.94,81.49 91.8,81.49 92.12,81.18 93.16,80.14 99.8,80.14 99.89,80.22 101.96,80.22 102.39,80.65 v2(106.66,80.65) 107.53,80.65 107.82,80.94 109.28,80.94 v1(109.75,80.47)
  L4 w0.127: v1(133.26,140.07) 133.16,139.97 133.16,139.68 134.21,138.63 134.82,138.63 135.1,138.34 138.77,134.68 138.77,126.95 140.09,125.63 140.09,121.17 143.87,117.38 154.26,117.38 158.17,113.47 158.17,109.56 161.47,106.26 161.47,97.09 160.56,96.18 160.56,93.99 v1(161.91,92.64) ; v1(91.04,78.9) 89.95,77.81 89.36,77.81 87.81,76.26 87.42,76.26 84.16,73 84.16,69.96 80.43,66.23 v1(80.37,66.23)
  BOTTOM w0.127: RN407.5 90.14,80.16 91.02,79.28 91.02,78.93 v1(91.04,78.9) ; v1(120.96,144.46) 120.96,145.12 120.49,145.59 PR4651.1 120.28,146.15 PR4628.2 ; v1(80.37,66.23) 80.11,65.97 80.11,64.33 89.39,55.05 142.47,55.05 149.37,61.95 149.37,62.4 152.05,65.08 153.86,65.08 154.97,66.19 154.97,68.53 160.61,74.17 160.74,74.17 161.01,74.43 161.01,74.56 161.65,75.21 161.65,81.78 161.84,81.97 161.84,84.56 160.99,85.41 160.99,91.73 v1(161.91,92.64) ; CPU1.G31 110.2,80.03 v1(109.75,80.47)
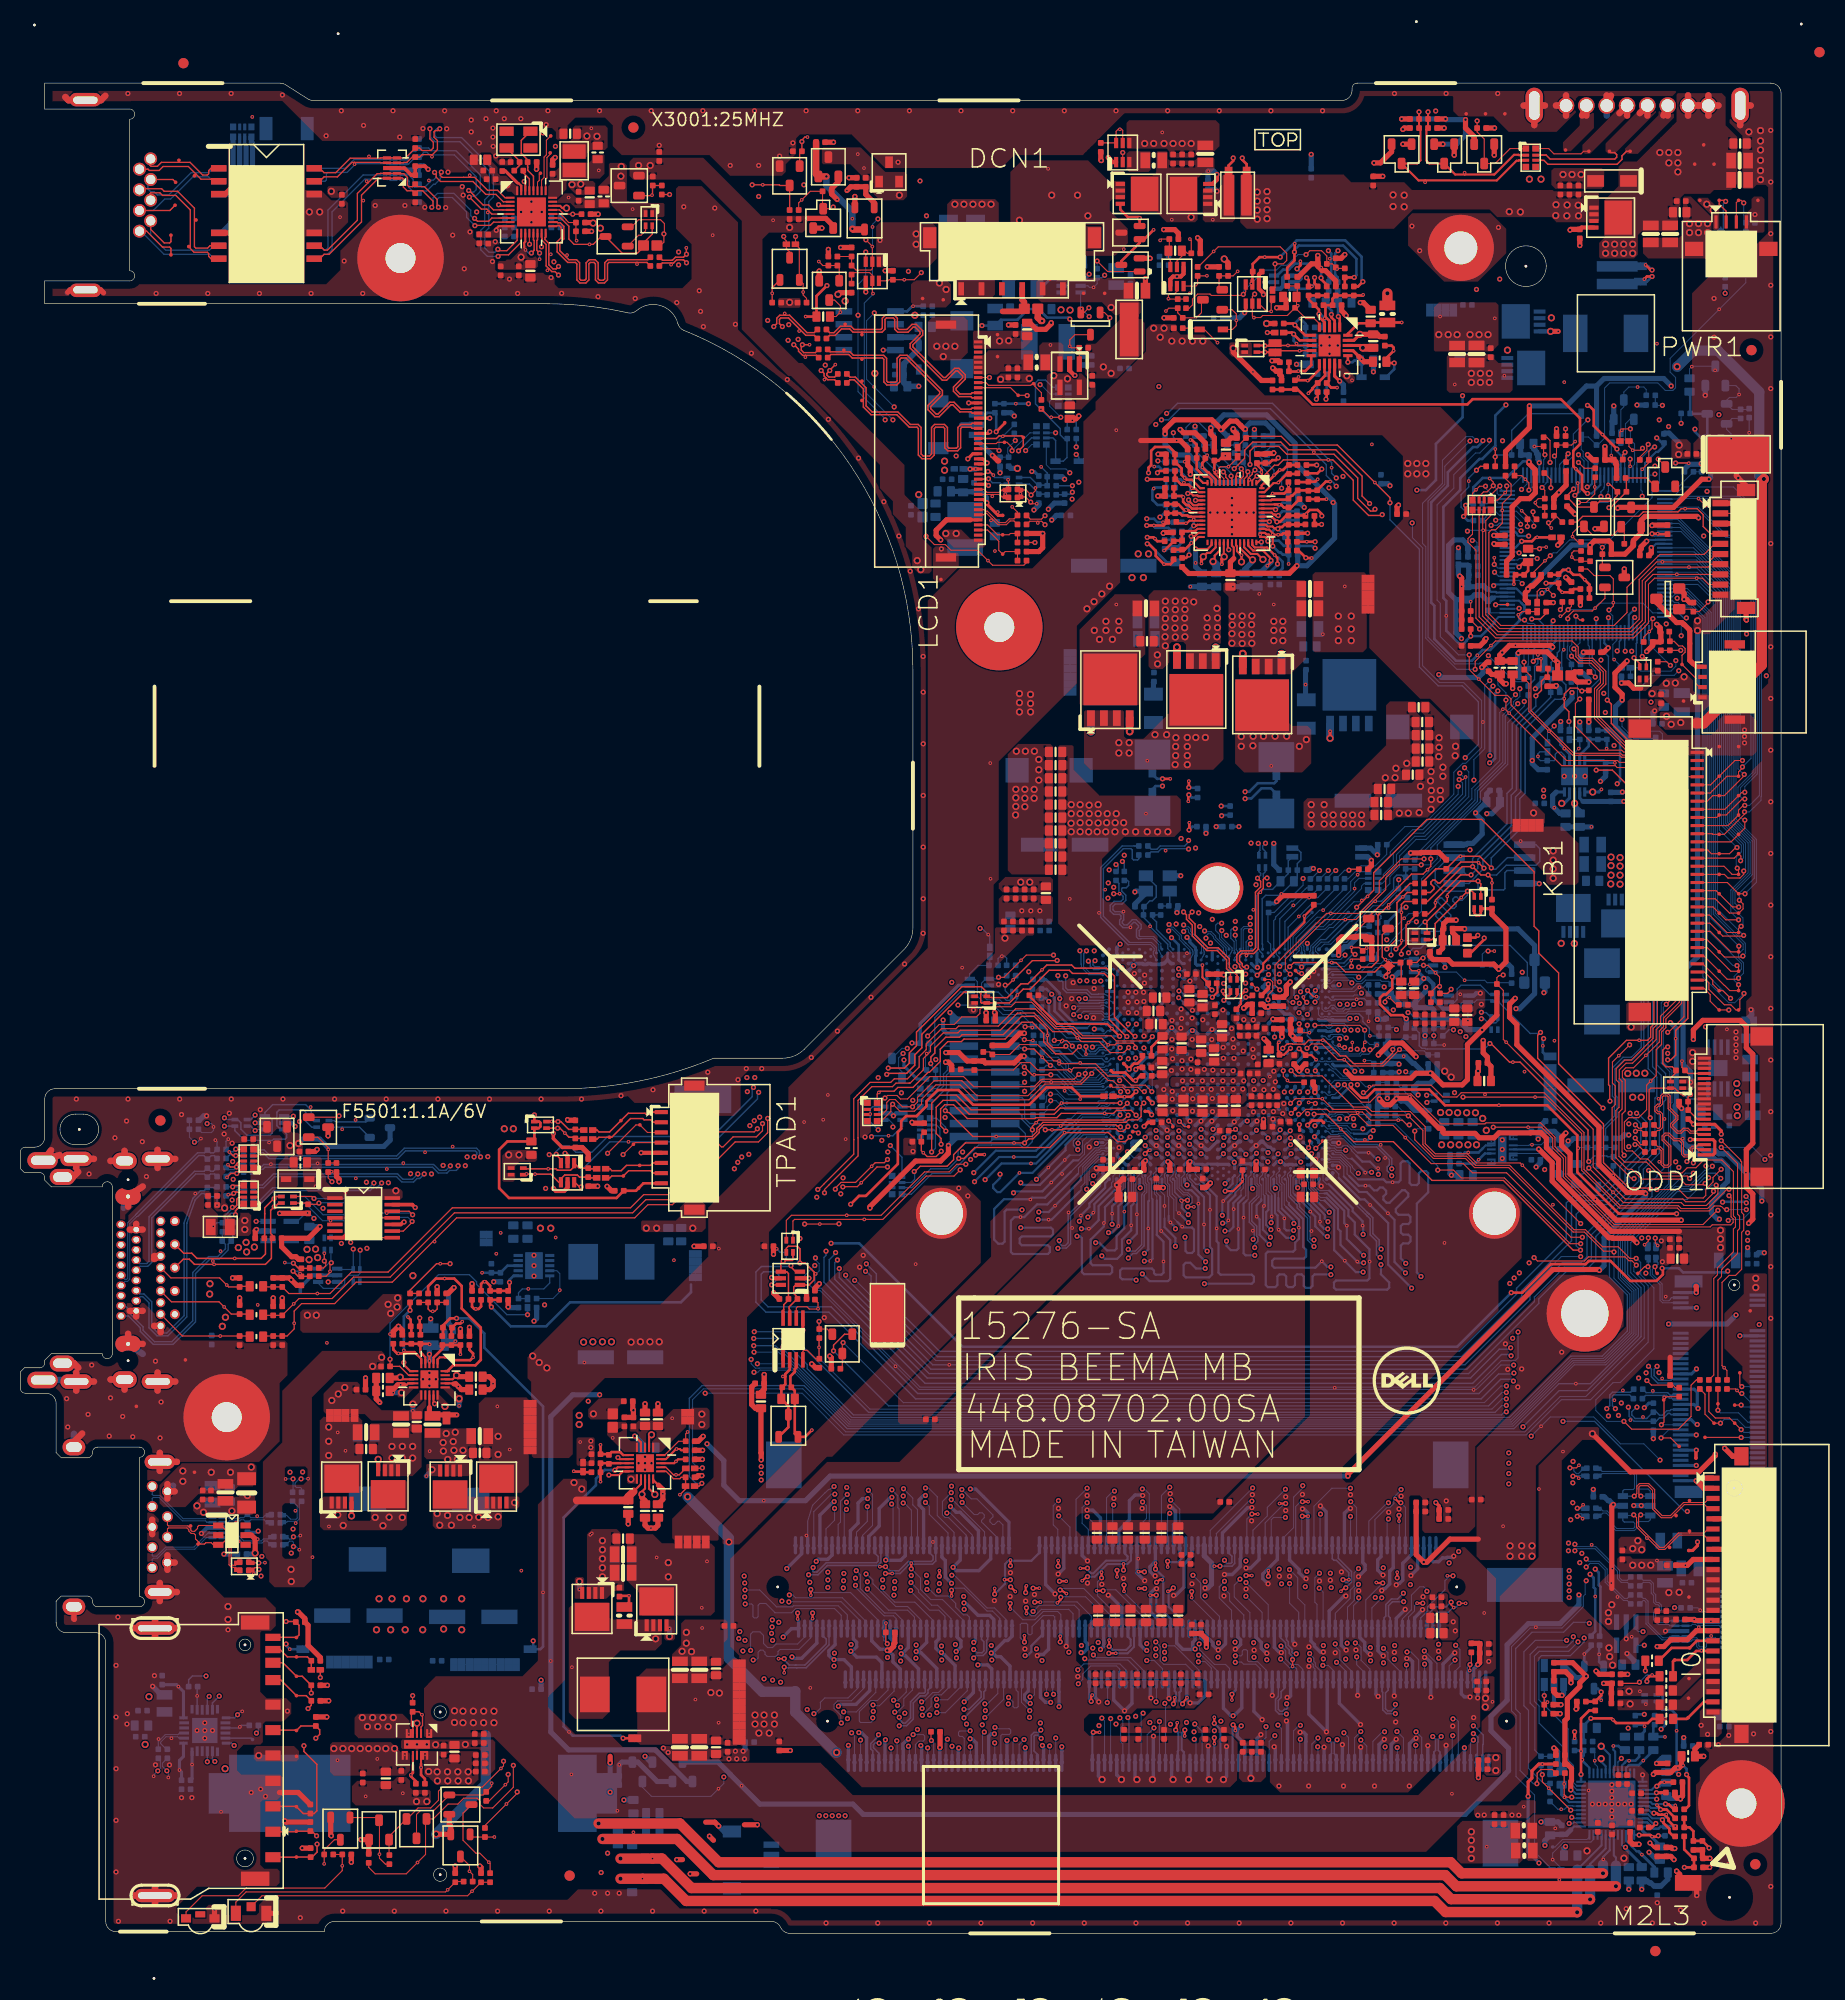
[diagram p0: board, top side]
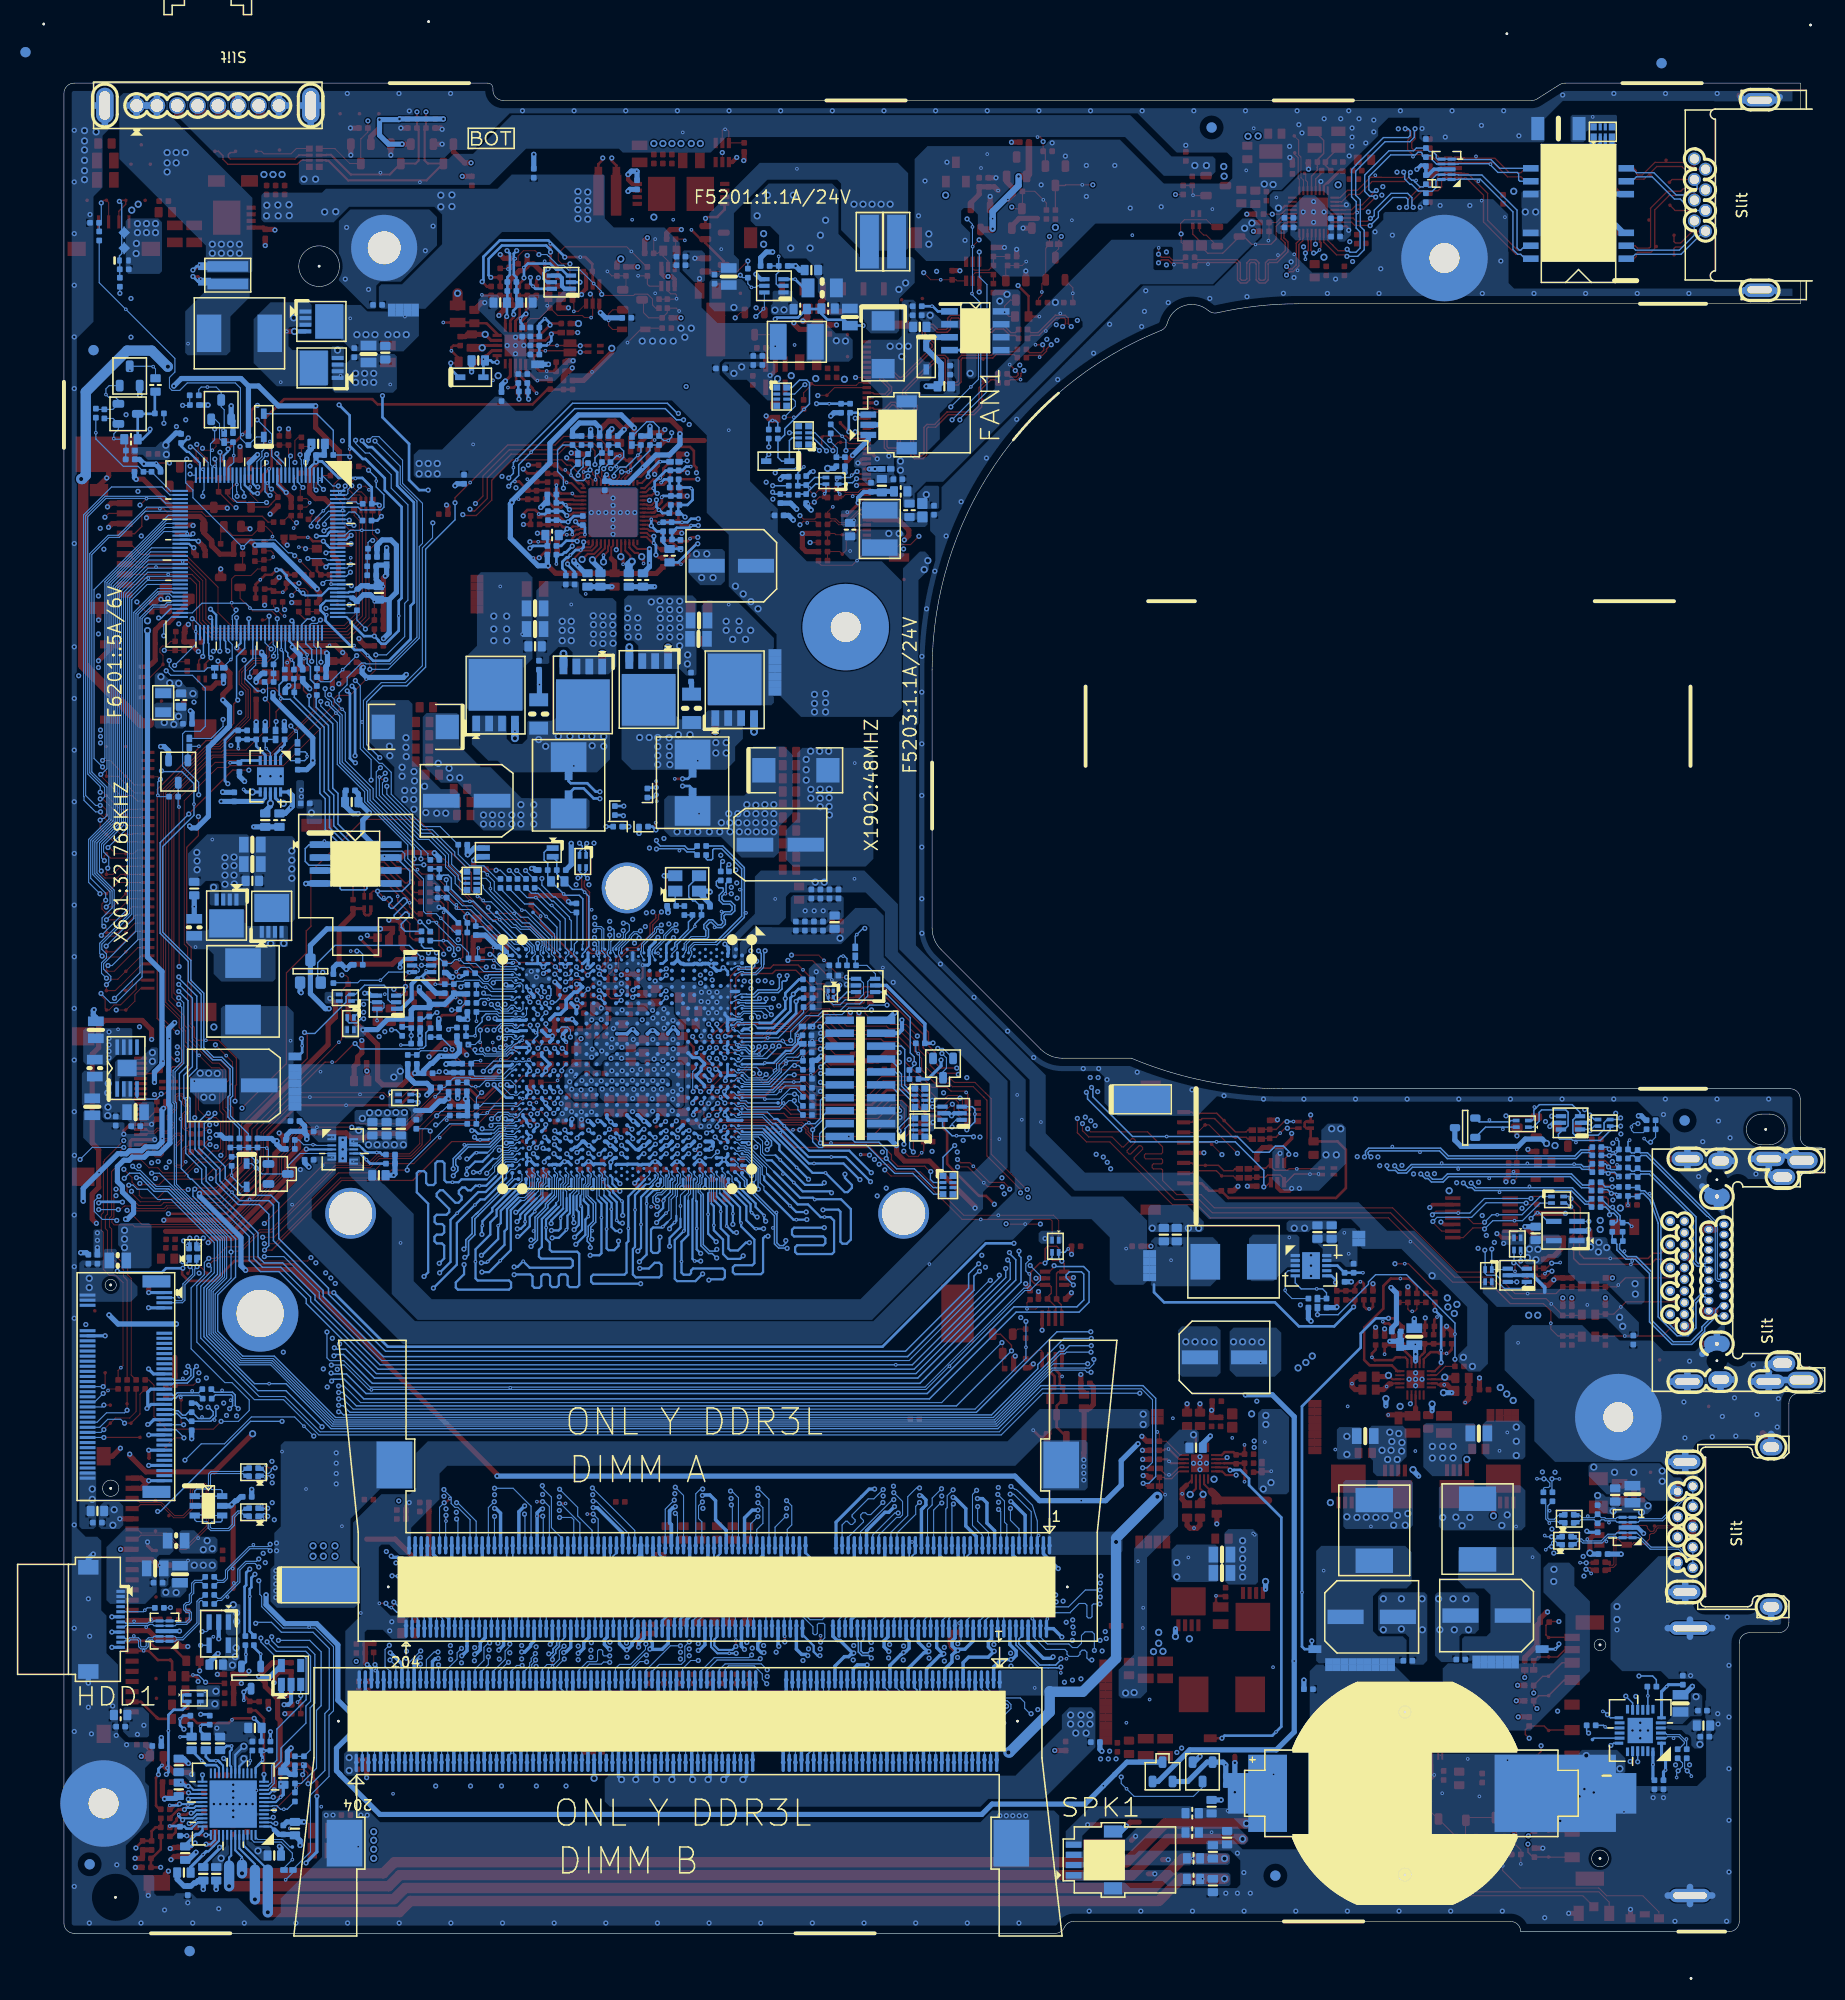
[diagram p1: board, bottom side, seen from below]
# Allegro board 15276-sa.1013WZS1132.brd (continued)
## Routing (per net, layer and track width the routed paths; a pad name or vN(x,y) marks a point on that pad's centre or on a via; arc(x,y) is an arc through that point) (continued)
APU_TCK: length 32
  TOP w0.127: v1(92.31,76.21) 92.82,76.21 93.9,77.29 101.26,77.29 v2(102.72,78.75) 107.04,78.75 107.93,77.86 108.69,77.86 109.14,78.31 v1(109.14,78.33)
  BOTTOM w0.127: HDT1.2 95.95,78.37 95.39,77.81 93.03,77.81 92.25,77.03 92.25,76.27 v1(92.31,76.21) 91.29,75.19 89.54,75.19 87.69,73.34 RN404.3 ; CPU1.D35 109.09,78.28 109.09,78.28 v1(109.14,78.33)
APU_TDI: length 31
  TOP w0.127: v1(108.97,80.46) 108.5,79.99 100.18,79.99 v2(99.92,79.73) 99.55,79.36 v1(99.55,79.03)
  BOTTOM w0.127: CPU1.D29 108.6,80.84 v1(108.97,80.46) ; HDT1.6 98.03,80.91 98.53,80.4 98.53,80.05 v1(99.55,79.03) 99.55,77.87 98.97,77.29 98.6,77.29 98.34,77.55 95.53,77.55 95.5,77.53 94.27,77.53 91.47,74.74 89.69,74.74 87.65,72.69 RN404.4
APU_TDO: length 15.5
  TOP w0.127: v1(108.95,79.34) 108.49,78.87 108.03,78.87 107.78,79.12 102.57,79.12 102.47,79.03 v2(101.48,79.03) v1(100.82,79.03)
  BOTTOM w0.127: HDT1.8 98.53,82.18 98.79,81.93 98.79,80.15 99.3,79.64 100.21,79.64 v1(100.82,79.03) ; CPU1.D31 108.95,79.62 v1(108.95,79.34)
APU_TEST0: length 11.8
  TOP w0.102: v1(134.25,91.6) 134.25,91.81 134.47,92.04 v2(134.68,92.04) 135.39,91.32 R647.2
  L4 w0.102: v1(125.78,90.55) 126.11,90.55 126.38,90.82 126.78,90.82 126.95,90.65 132.07,90.65 133.03,91.6 v1(134.25,91.6)
  BOTTOM w0.102: CPU1.AU13 126.2,90.14 v1(125.78,90.55)
APU_TEST1: length 6.4
  BOTTOM w0.102: CPU1.AY10 128.05,90.9 128.27,90.68 128.57,90.68 128.62,90.73 128.92,90.73 129.15,90.5 130.41,90.5 130.6,90.69 132.56,90.69 R646.2 132.62,89.71 v2(132.62,89.71)
APU_TEST2: length 7.6
  BOTTOM w0.102: CPU1.AY6 128.14,93.83 128.41,93.83 128.61,94.03 128.88,94.03 128.94,93.98 131.11,93.98 131.48,93.61 131.86,93.61 132.68,94.43 R645.2 133.33,95.01 134.17,95.01 v2(134.61,94.57)
APU_TEST6_DIRECRACKMON: length 2.6
  TOP w0.102: TP403.1 107.44,83.22 108.41,83.22 108.84,82.78 v1(108.94,82.78)
  BOTTOM w0.102: v1(108.94,82.78) 108.94,82.78 108.6,83.12 CPU1.D25
APU_TEST14_BP0: length 6.9
  BOTTOM w0.102: R410.1 100.5,82.42 101.18,83.09 101.76,83.09 102.8,82.05 v2(104.25,82.05) 104.38,82.18 CPU1.A27
APU_TEST15_BP1: length 4.5
  BOTTOM w0.102: CPU1.B27 106.92,82.18 106.62,81.88 106.1,81.88 105.9,81.67 TP404.1
APU_TEST16_BP2: length 6.9
  BOTTOM w0.102: R411.1 100.82,83.73 v2(101.4,83.73) 102.38,83.73 103.38,82.73 CPU1.A26
APU_TEST17_BP3: length 7.6
  BOTTOM w0.102: R413.1 100.69,83.35 102.25,83.35 v2(102.72,82.87) 103.11,82.48 106.67,82.48 106.72,82.43 107.01,82.43 107.31,82.73 CPU1.B26
APU_TEST18_PLLTEST1: length 22.6
  TOP w0.102: v1(98.84,89.16) 99.47,89.16 v2(99.55,89.09)
  L4 w0.102: v1(101.35,81.9) 99.01,81.9 97.29,83.62 97.29,87.67 98.58,88.96 98.64,88.96 v1(98.84,89.16)
  BOTTOM w0.102: R415.1 101,80.98 101,81.29 101.35,81.64 v1(101.35,81.9) 101.89,81.9 102.78,81.01 106,81.01 106.37,81.38 106.62,81.38 106.68,81.33 106.97,81.33 107.27,81.63 CPU1.B28 ; v1(98.84,89.16) 98.76,89.16 98.13,89.8 HDT1.20
APU_TEST19_PLLTEST0: length 20
  TOP w0.102: v2(99.6,87.82) 98.84,87.82 v1(98.76,87.89)
  L4 w0.102: v1(98.76,87.89) 97.57,86.71 97.57,83.66 97.98,83.25 100.55,83.25 101.26,82.54 v1(101.34,82.54)
  BOTTOM w0.102: v1(98.76,87.89) 98.61,87.89 97.98,88.53 HDT1.18 ; CPU1.A28 106.26,81.63 105.93,81.29 102.83,81.29 102.6,81.52 102.6,81.97 102.03,82.54 v1(101.34,82.54) 101.12,82.54 100.92,82.33 100.92,81.8 R416.1
APU_TEST28_H_PLLCHRZ: length 1.7
  TOP w0.102: TP410.1 128.09,77.87 v1(127.43,77.21)
  BOTTOM w0.102: CPU1.AV35 127,77.65 v1(127.43,77.21)
APU_TEST28_L_PLLCHRZ: length 1.4
  TOP w0.102: v1(126.72,77.26) 126.82,77.37 TP411.1
  BOTTOM w0.102: v1(126.72,77.26) 126.21,77.78 CPU1.AU35
APU_TEST31_M_TEST: length 1.3
  TOP w0.102: v1(109.98,78.72) 109.86,78.84 TP409.1
  BOTTOM w0.102: CPU1.E33 109.82,78.88 v1(109.98,78.72)
APU_TEST36_FREE_2: length 21.9
  TOP w0.102: R422.1 95.36,86.69 R423.1 97.33,86.43 98.31,87.41 100.06,87.41 101.66,85.81 v2(102.17,85.81) 102.45,85.53 105.76,85.53 106.98,84.31 108.39,84.31 109.28,83.42 110.67,83.42 v1(111.3,82.78)
  BOTTOM w0.102: v1(111.3,82.78) 111.35,82.83 111.35,84.76 111,85.11 CPU1.H21
APU_TEST37_FREE_2: length 20.4
  TOP w0.102: R425.1 92.56,84.91 R424.1 97.68,84.91 98.41,85.63 99.35,85.63 100.06,84.92 v2(103.18,84.92) 103.41,84.92 103.61,85.13 105.76,85.13 107.02,83.87 107.47,83.87 107.9,83.45 108.47,83.45 108.7,83.22 109.92,83.22 110.35,82.78 v1(110.57,82.78)
  BOTTOM w0.102: CPU1.H25 111,83.21 v1(110.57,82.78)
APU_THERMDA: length 1.4
  TOP w0.254: TP401.1 110.9,82.12 v1(111.35,81.66)
  BOTTOM w0.254: v1(111.35,81.66) 111.35,81.82 CPU1.H27
APU_THERMDC: length 1.5
  TOP w0.254: v1(111.29,80.51) 110.95,80.85 TP402.1
  BOTTOM w0.254: CPU1.H29 111.29,80.79 v1(111.29,80.51)
APU_TMS: length 28.8
  TOP w0.127: v1(108.21,79.32) 108.15,79.39 107.89,79.39 107.77,79.51 100.67,79.51 100.22,79.07 100.22,78.75 99.61,78.14 99.19,78.14 v1(98.79,77.73) v2(97.75,77.73) 92.95,77.73 91.8,76.59 91.8,76.08 91.17,75.45 88.53,75.45 88,74.93 v1(87.93,74.93)
  BOTTOM w0.127: CPU1.D33 108.6,78.94 v1(108.21,79.32) ; RN404.2 87.66,73.84 87.97,74.15 87.97,74.89 v1(87.93,74.93) ; HDT1.4 97.87,79.64 98.86,78.65 98.86,77.81 v1(98.79,77.73)
APU_TRST#: length 37.5
  TOP w0.127: v1(90.99,80.91) 91.17,80.73 91.35,80.73 93.71,78.37 v2(95.99,78.37) 99.52,78.37 99.99,78.85 99.99,79.17 100.59,79.76 108.75,79.76 109,80.01 109.93,80.01 110.25,80.33 110.25,81.4 v1(110.52,81.66)
  L4 w0.127: v1(85.58,77.48) 86.91,78.81 88.54,78.81 90.64,80.91 v1(90.99,80.91)
  BOTTOM w0.127: v1(85.58,77.48) 86.73,76.33 RN404.1 ; HDT1.9 91.96,83.45 91.17,82.66 91.17,81.42 91.02,81.27 91.02,80.94 v1(90.99,80.91) ; CPU1.G27 110.2,81.98 v1(110.52,81.66)
APU_VDD: length 0.8
  TOP w0.508: C1017.1 95.91,90.5 v1(95.83,90.57)
  vias: v1(109.43,93.76) v1(109.58,94.4) v1(110.59,94.24) v1(110.57,93.46) v1(112.48,82.99) v1(113.23,84.86) v1(113.31,82.8) v1(113.31,82.04) v1(114.28,85) v1(114.42,83.04) v1(115.15,84.97) v1(115.19,83.01) v1(115.32,82.08) v1(116.28,83.03) v1(116.47,84.97) v1(117.15,83.01) v1(117.3,84.9) v1(117.25,82.1) v1(118.29,84.84) v1(118.25,83.03) v1(119.3,84.84) v1(119.3,83.01) v1(120.25,83.03) v2(103.23,101.74) v2(109.2,98.94) v2(110.73,110.12) v3(103.37,111.01) v3(103.37,110.12) v3(103.36,109.18) v3(103.37,108.34) v3(104.25,111.01) v3(104.25,110.12) v3(104.25,109.23) v3(104.25,108.34) v3(105.14,110.96) v3(105.14,110.12) v3(105.14,109.23) v3(105.09,108.33) v3(105.93,108.34) v3(106.03,111.01) v3(106.03,110.12) v3(106.02,109.21) v3(106.77,108.34) v3(106.92,110.12) v3(106.86,109.23) v3(107.69,109.23) v3(107.68,108.34) v3(107.8,110.12) v3(108.53,109.23) v3(108.69,108.34) v3(109.71,108.34) v3(110.85,108.34) v3(111.87,108.34) v3(112.88,108.34)
APU_VDD_RUN_FB_H: length 121.1
  TOP w0.254: PR4602.2 110.17,84.34 v1(109.7,83.88) 109.46,83.88 108.68,84.66 107.48,84.66 TP434.1 ; PR4601.1 127.6,143.6 128.02,144.01 v1(128.02,144.01)
  L3 w0.254: v1(128.02,144.01) 127.99,143.99 127.91,143.99 127.82,143.9 123.7,143.9 122.05,145.55 114.65,145.55 100.87,131.77 100.87,128.47 93.53,121.13 93.53,91.49 93.12,91.08 93.12,78.89 94.47,77.54 94.47,76.33 94.17,76.03 93.56,76.03 v1(93.48,76.11)
  L4 w0.254: v1(93.48,76.11) 93.71,75.88 101.1,75.88 107.47,82.26 107.47,83.94 107.92,84.38 108.43,84.38 108.71,84.1 109.48,84.1 v1(109.7,83.88)
  BOTTOM w0.254: CPU1.G23 109.8,83.99 109.8,83.98 v1(109.7,83.88)
APU_VDD_RUN_FB_L: length 117.9
  TOP w0.254: PR4603.1 v1(127.52,144.41) ; v2(94.83,76.59) 94.01,76.59 v1(93.96,76.54) ; v1(109.73,84.97) 109.93,85.17 PR4604.2 ; PC4605.2 112.05,143.83 111.87,143.65 v1(111.86,143.65)
  L3 w0.254: v1(93.96,76.54) 93.96,77.51 92.74,78.73 92.74,91.31 93.15,91.72 93.15,121.29 100.49,128.63 100.49,131.93 111.86,143.3 v1(111.86,143.65) 112.21,143.65 114.49,145.93 122.21,145.93 123.86,144.28 127.39,144.28 v1(127.52,144.41)
  L4 w0.254: v1(109.73,84.97) 109.73,84.92 109.29,84.48 108.87,84.48 108.59,84.77 107.77,84.77 107.09,84.09 107.09,82.41 100.94,76.26 94.24,76.26 v1(93.96,76.54)
  BOTTOM w0.254: v1(109.73,84.97) 109.73,84.79 109.4,84.45 CPU1.E23
APU_VDDNB: length 2.4
  TOP w0.254: PR4620.1 111.27,87.16 C1071.1
  vias: v1(113.29,89.79) v1(113.29,87.92) v1(114.19,90.91) v1(114.23,89.98) v1(114.15,89.02) v1(115.27,90.02) v1(115.27,87.92) v1(117.2,87.91) v1(118.32,87.13) v1(119.15,88.98) v1(119.28,87.95) v1(119.34,87.12) v1(120.3,86.79) v2(114.76,96.39) v3(126.98,111.01) v3(126.98,109.99) v3(126.98,109.1) v3(128.25,111.01) v3(128.25,109.99) v3(128.25,109.1) v3(129.14,109.99) v3(129.14,109.1) v3(130.16,109.99) v3(130.16,109.1) v3(131.05,109.99) v3(131.05,109.1) v3(131.93,109.99) v3(131.93,109.1) v3(134.27,113.65) v3(135.23,113.66) v3(135.31,114.59) v3(136.38,115.07)
APU_VDDNB_RUN_FB_H: length 101.2
  TOP w0.254: TP433.1 108.85,85.24 108.85,85.22 v1(109.08,84.99) 109.08,85.08 109.54,85.53 109.88,85.53 110.38,86.03 PR4620.2 ; PR4621.1 v1(110.85,143.01)
  L3 w0.254: v1(92.69,76.85) 92.69,77.93 92.11,78.52 92.11,90.71 91.73,91.09 91.73,91.98 92.64,92.89 92.64,121.5 99.98,128.84 99.98,132.14 v1(110.85,143.01)
  L4 w0.254: v1(92.69,76.85) 92.72,76.85 92.92,77.05 95.05,77.05 95.05,77.05 95.47,77.05 95.75,76.77 100.95,76.77 106.74,82.56 106.74,84.33 107.53,85.12 108.73,85.12 108.86,84.99 v1(109.08,84.99)
  BOTTOM w0.254: CPU1.D23 108.6,84.62 108.97,84.99 108.99,84.99 109,84.99 v1(109.08,84.99)
AUD_AGND: length 30.7
  TOP w0.508: EC2905.2 EC2906.2 156.51,24.52 EC9744.1 v1(155.75,24.59) ; v1(159.23,8.76) 158.62,8.76 158.35,9.03 EC2705.1 ; C2705.1 162.76,13.51 162.96,13.31 163.3,13.31 ; 163.3,13.31 163.3,13.31 163.51,13.52 163.51,14.86 R2711.1 ; 163.3,13.31 v1(163.3,13.22) ; C2710.2 v1(160.95,16.71) ; R2706.1 163.23,5.8 162.92,6.11 v1(162.92,6.12) ; EC2907.2 R2919.2 165.46,7.44 EC2908.2 v1(166.2,7.38) ; R2920.2 v1(166.17,6.49) ; v1(161.02,28.2) 161.67,28.2 162.35,28.88 AFTP6313.1 163.98,28.88 164.87,29.77 CN6301.16
  BOTTOM w0.203: v1(159.23,8.76) 158.77,8.76 158.35,9.18 HDA27.38 ; HDA27.25 v1(159.57,15.58)
  BOTTOM w0.508: v1(159.49,4.33) C2715.2 160,5.19 160.23,4.96 160.38,4.96 160.7,4.65 EC2703.1 161.39,4.65 162.06,5.32 C2712.1 ; C2711.2 161.42,17.18 v1(160.95,16.71) ; v1(163.3,13.22) 163.25,13.27 162.18,13.27 162.09,13.36 162.05,13.36 C2702.1 ; C2701.2 160.96,7.22 v1(160.22,7.97) ; EC9739.1 v1(163.62,19.25)
  vias: v1(158.16,20.18) v1(165.34,20.46) v1(165.97,19.57)
AUD_HP1_JACK_L: length 4
  TOP w0.254: v1(160.69,11.82) 160.99,11.82 161.14,11.67 161.48,11.67 161.49,11.66 161.74,11.66 162.14,11.27 162.14,11.07 R2908.1
  BOTTOM w0.203: v1(160.69,11.82) 160.52,11.82 160.47,11.87 160.44,11.87 160.2,12.11 HDA27.32
AUD_HP1_JACK_L1: length 28.4
  TOP w0.254: R2912.2 R2908.2 164.19,10.42 164.57,10.04 EC2907.1 R2919.1 166.12,8.43 v1(166.12,8.39) ; R2907.2 v1(159.85,25.82)
  L3 w0.254: v1(159.85,25.82) 161.4,24.27 v1(161.4,20.08) 161.4,19.14 164.5,16.05 164.5,15.3 164.09,14.9 164.09,10.42 v1(166.12,8.39)
  BOTTOM w0.254: R2922.2 161.46,21.41 v2(161.78,21.09) 161.78,20.46 v1(161.4,20.08)
AUD_HP1_JACK_R: length 5.1
  TOP w0.254: v1(161.53,11.16) 161.63,11.06 161.63,10.86 162.21,10.28 162.21,9.94 162.62,9.54 R2910.1
  BOTTOM w0.203: v1(161.53,11.16) 161.37,11.31 160.51,11.31 160.11,11.71 HDA27.33
  BOTTOM w0.254: v1(161.53,11.16) 161.91,11.54 v2(161.91,11.69)
AUD_HP1_JACK_R1: length 32.8
  TOP w0.254: R2913.2 163.79,12.2 164.14,12.56 164.14,15.3 163.9,15.54 v1(163.9,15.62) ; v1(160,24.78) 160,25.03 160.26,25.28 R2909.2 ; v1(163.68,6.49) R2920.1 EC2908.1 164.57,7.44 164.49,7.44 163.67,8.26 R2910.2
  L3 w0.254: v1(163.68,6.49) 163.68,8.84 162.8,9.73 162.8,14.5 163.63,15.34 163.63,15.35 v1(163.9,15.62) 163.89,15.63 163.89,15.81 160.76,18.93 160.76,20.52 v1(159.75,21.54) 159.75,24.52 v1(160,24.78)
  BOTTOM w0.254: v1(163.9,15.62) 163.9,16.17 v2(163.56,16.52) ; v1(159.75,21.54) 158.99,21.54 R2921.2
AUD_PC_BEEP: length 7.9
  TOP w0.254: C2720.2 154.33,21.92 153.52,21.12 v2(153.52,17.92) v1(153.52,15.63)
  BOTTOM w0.254: HDA27.12 v1(153.52,15.63)
AUD_PC_BEEP_C: length 3.8
  TOP w0.254: R2717.1 154.91,22.79 C2720.1 155.51,23.39 v1(155.51,23.73)
  BOTTOM w0.254: v2(155.51,22.92) v1(155.51,23.73) 155.18,24.06 D2701.3
AUD_PORTA_L_R_B: length 6.1
  TOP w0.254: CN6301.17 164.91,28.77 AFTP6306.1 162.43,28.07 R2907.1
AUD_PORTA_R_R_B: length 5.8
  TOP w0.254: CN6301.18 164.85,27.77 163.96,26.88 AFTP6309.1 162.57,26.73 R2909.1
AUD_SENSE: length 9.7
  TOP w0.254: R2923.1 160.51,21.09 160.1,20.69 156.98,20.69 v2(156.67,21) 156.52,21.14 v1(154.49,21.14)
  BOTTOM w0.254: v1(154.49,21.14) 153.75,20.41 C2901.1 153.78,20.18 R2709.2
AUD_SENSE_A: length 3.5
  BOTTOM w0.203: HDA27.13 154.35,16.28 154.08,16.55
  BOTTOM w0.254: R2722.2 R2709.1 153.78,17.49 153.66,17.36 v2(153.66,17.07) 153.66,16.97 154.08,16.55
AUD_SPK_L+: length 106.8
  TOP w1.016: v3(57.26,9.28) 64.61,9.28 68.16,5.73 140.16,5.73 141.25,4.63 v3(156.95,4.63)
  BOTTOM w0.203: 156.95,6.67 156.95,7.45 156.75,7.66 HDA27.42
  BOTTOM w1.016: v3(156.95,4.63) 156.95,6.67
  vias: v2(60.31,9.94)
AUD_SPK_L+_C: length 0.6
  TOP w0.508: v1(67.79,9.55) AFTP2902.1
AUD_SPK_L-: length 104.9
  TOP w1.016: v3(155.68,5.9) 141.78,5.9 140.69,7 68.69,7 64.88,10.81 v3(56.88,10.81)
  BOTTOM w0.203: HDA27.43 156.35,8.17 155.68,7.5 155.68,6.77
  BOTTOM w1.016: v3(155.68,5.9) 155.68,6.77
  vias: v2(58.73,12.05)
AUD_SPK_L-_C: length 1.3
  TOP w0.508: AFTP2901.1 v1(72.5,10.68)
AUD_SPK_R+: length 104.1
  TOP w1.016: v3(59.04,5.37) v2(61.2,5.37) 63.31,5.37 65.5,3.19 139.11,3.19 140.2,2.09 153.12,2.09 v3(153.14,2.07)
  BOTTOM w0.203: HDA27.45 155.55,8.66 153.14,6.26
  BOTTOM w1.016: v3(153.14,2.07) 153.14,6.26
AUD_SPK_R+_C: length 0.6
  TOP w0.508: AFTP2904.1 v1(65.89,5.85)
AUD_SPK_R-: length 104
  TOP w1.016: v3(154.41,3.34) 154.39,3.36 140.73,3.36 139.64,4.46 66.02,4.46 63.13,7.35 v2(62.19,7.35) v3(59.04,7.35)
  BOTTOM w0.203: HDA27.44 155.95,8.35 154.41,6.82 154.41,6.26
  BOTTOM w1.016: v3(154.41,3.34) 154.41,6.26
AUD_SPK_R-_C: length 0.6
  TOP w0.508: AFTP2903.1 v1(64.57,7.25)
AUD_VREF: length 2.4
  TOP w0.305: C2705.2 161.41,13.85 161.38,13.83 v1(160.94,13.83)
  BOTTOM w0.203: v1(160.94,13.83) 160.82,13.71 HDA27.28
BAT_ALERT: length 2.1
  TOP w0.635: 153.63,178.79 BATT1.7 154.05,178.78
BAT_AMBER: length 24.3
  TOP w0.102: LED1.1 21.2,3.07 22.21,4.07 41.83,4.07 v2(42.04,4.28) EC6105.1 42.84,5.09 R6103.1
BAT_IN#: length 185.2
  TOP w0.102: RN4301.1 146.55,175.54 145.08,174.06 D4302.3 144,176.48 143.3,177.18 EC4305.2 v1(143.3,178.26) ; PR4215.2 PR4216.1 PC4210.2 82.21,163.59 83.67,163.59 83.81,163.72 PQ4203.2 v2(83.81,165.9) 83.81,165.92 v1(83.17,166.56) ; R2414.1 154.41,124.06 v1(154.92,123.56)
  L3 w0.102: v1(143.3,178.26) 145.08,178.26 145.6,177.73 161.21,177.73 171.43,167.52 171.43,143.72 170.97,143.26 170.97,142.82 171.43,142.36 171.43,127.26 170.54,126.38 169.65,126.38 169.03,125.75 164.03,125.75 163.28,125 163.03,124.75 163.02,124.75 161.98,123.71 155.43,123.71 155.28,123.56 v1(154.92,123.56)
  L4 w0.102: v1(83.17,166.56) 83.23,166.56 83.43,166.76 83.43,175.53 85.83,177.94 131.3,177.94 133.46,180.1 141.46,180.1 v1(143.3,178.26)
  BOTTOM w0.102: v1(154.92,123.56) 154.92,124.15 154.34,124.74 154.34,126.58 154.22,126.7 KBC24.80
BAT_SCL: length 116.1
  TOP w0.203: 138.18,172.4 145.24,172.4 147.18,174.34 147.38,174.34 147.42,174.39 RN4301.3 ; 138.18,172.4 137.54,172.4 D4301.3 137.41,174.06 137.73,174.38 137.73,177.42 EC4301.1 PR4415.2 v1(137.59,179.14) ; 138.18,172.4 v2(138.18,172.22) ; PG4407.2 122.84,155.48 122.82,155.51 v1(122.41,155.51) 122.4,155.51 RN2401.3
  L4 w0.203: v1(137.59,179.14) 137.57,179.16 134.68,179.16 132.32,176.79 132.32,166 132.32,165.63 126.47,159.79 126.47,156.77 125.24,155.54 122.74,155.54 122.71,155.51 v1(122.41,155.51) 122.41,155.42 122.21,155.22 122.21,154.11 127.29,149.03 152.66,149.03 153.86,147.84 157.23,147.84 159.09,145.98 159.09,145.78 159.65,145.22 159.65,143.29 158.96,142.61 158.96,133.28 158.78,133.11 v1(158.78,130.24)
  BOTTOM w0.203: KBC24.70 158.22,129.67 v1(158.78,130.24)
BAT_SDA: length 113.9
  TOP w0.203: RN4301.2 147.42,174.89 147.38,174.93 146.94,174.93 144.99,172.98 142.07,172.98 ; 142.07,172.98 141.14,172.98 D4303.3 138.6,174.06 138.31,174.36 138.31,177.39 EC4302.1 PR4412.2 v1(138.48,179.14) ; 142.07,172.98 v2(142.07,173.16) ; PG4408.2 123.04,156.4 122.79,156.14 v1(122.41,156.14) 122.39,156.17 RN2401.4
  L4 w0.203: v1(158.8,129.42) 158.2,130.02 158.2,133.35 158.38,133.53 158.38,142.85 159.06,143.53 159.06,144.98 158.5,145.54 158.5,145.74 156.99,147.25 153.62,147.25 152.42,148.45 127.04,148.45 121.62,153.87 121.62,155.46 122.31,156.14 v1(122.41,156.14) 122.71,156.14 122.74,156.12 125,156.12 125.89,157.01 125.89,160.03 131.73,165.88 131.73,177.04 134.44,179.74 137.88,179.74 v1(138.48,179.14)
  BOTTOM w0.203: KBC24.69 158.62,129.23 v1(158.8,129.42)
BAT_WHITE: length 24.5
  TOP w0.102: LED1.2 23.77,3.69 43.99,3.69 v2(44.43,4.14) EC6103.1 R6101.1
BATT_WHITE_LED#: length 247
  TOP w0.102: v1(47.99,15.63) 47.99,14.9 v2(47.71,14.62) 46.12,13.03 R6105.2
  L4 w0.102: v1(166.44,75.45) 166.44,79.3 166.63,79.49 166.63,84.32 166.94,84.63 166.94,89.66 166.4,90.19 166.4,116.8 161.37,121.83 161.37,123.4 161.86,123.88 161.86,127.08 159.54,129.39 159.54,138.59 160.74,139.79 160.74,143.47 v1(160.79,143.52) ; v1(47.99,15.63) 48.22,15.63 52.89,20.3 52.89,45.81 62.72,55.64 71.71,55.64 v1(72.17,55.18)
  BOTTOM w0.102: KBC24.32 160.68,143.41 v1(160.79,143.52) ; v1(166.44,75.45) 166.22,75.23 166.18,75.23 165.98,75.04 165.69,75.04 164.12,73.47 162.79,73.47 157.6,68.28 157.6,64.61 158.93,63.29 158.93,58.89 155.96,55.92 152.86,55.92 146.83,49.88 81.43,49.88 75.92,55.4 72.77,55.4 72.55,55.18 v1(72.17,55.18)
BATT_WHITE_LED_R#: length 11.2
  TOP w0.102: v2(46.36,14.77) 46.36,14.45 R6105.1 45.52,13.61 Q6103.B 42.2,13.6 40.67,12.08 39.35,12.08 38.97,11.69 Q6107.D
BKLT_CTRL: length 15.8
  BOTTOM w0.14: RN5201.7 101.58,147.08 101.84,146.82 D5202.K 102.6,144.79 102.96,145.15 102.96,146.99 ; 102.96,146.99 R5222.1 ; 102.96,146.99 102.68,146.99 102.3,147.38 102.3,147.99 v2(100.4,149.89) 99.86,150.43 99.86,152.5 100.13,152.77 100.84,152.77 101.57,152.04 RN5203.8
BLINK: length 15.6
  TOP w0.102: v1(126.57,87.05) 127,87.48 128.03,87.48 129.58,85.93 v2(130.23,85.93) 130.85,85.3 134.04,85.3 v1(135.67,86.93)
  BOTTOM w0.102: R1928.1 R1929.1 138.08,86.8 135.79,86.8 v1(135.67,86.93) ; CPU1.AU17 126.2,87.42 v1(126.57,87.05)
BLON_OUT: length 65.1
  TOP w0.102: v1(158.36,145) 158.36,144.29 v2(158.35,144.28)
  L3 w0.102: v1(101.84,147.58) 103.23,147.58 106.48,150.84 113.91,150.84 116.24,148.5 116.24,147.88 116.76,147.36 123.52,147.36 125.08,145.79 146.13,145.79 146.99,146.66 156.05,146.66 156.29,146.42 157.71,146.42 158.29,145.84 158.29,145.07 v1(158.36,145)
  BOTTOM w0.102: v1(158.36,145) 158.36,144.92 158.27,144.84 158.27,144.75 158.22,144.69 KBC24.27 ; v1(101.84,147.58) 101.71,147.58 101.71,147.58 RN5201.6
BLON_OUT_C: length 18.5
  TOP w0.102: LCD1.21 95.99,146.52 96.12,146.65 AFTP5205.1 97.06,146.65 97.56,146.15 v1(97.56,145.82)
  L3 w0.102: v1(97.56,145.82) 97.56,146.53 97.44,146.64 97.44,146.65 96.76,147.33 96.76,150.51 98.41,152.16 100.15,152.16 v1(100.31,152.32)
  BOTTOM w0.102: v1(97.56,145.82) 99.32,147.58 RN5201.3 ; RN5203.7 101.32,151.39 100.39,152.32 v1(100.31,152.32)
BLUETOOTH_EN: length 77.2
  TOP w0.102: v1(158.95,66.38) 158.33,66.38 157.18,67.52 155.63,67.52 153.96,69.2 152.84,69.2 146.64,75.4 146.5,75.54 143.15,75.54 142.25,76.44 139.1,76.44 137.97,77.57 137.97,78.97 v1(136.53,80.4) 136.46,80.48 132.87,80.48 132.32,81.04 129.12,81.04 v2(128.07,82.09) 125.41,82.09 v1(124.95,81.63) ; v1(157.74,50.35) 158.51,49.59 163.1,49.59 164.35,50.84 164.35,53.91 164.87,54.43 R5804.1
  BOTTOM w0.102: v1(124.95,81.63) 124.95,81.83 CPU1.AP27 ; v1(158.95,66.38) 158.99,66.38 159.39,65.97 159.39,64.78 160.69,63.49 160.69,57.49 157.36,54.16 156.67,54.16 154.97,52.46 154.97,51.42 156.04,50.35 v1(157.74,50.35) ; v1(136.53,80.4) 136.08,80.86 135.97,80.86 135.51,81.32 R635.1
BLUETOOTH_EN_NGFF: length 8.7
  TOP w0.102: R5804.2 165.72,53.03 165.72,51.06 AFTP5804.1 v1(167.24,50.18)
  BOTTOM w0.102: v1(167.24,50.18) 167.62,50.56 168.89,50.56 169.68,49.77 WLAN1.54
BOOST_MODE#: length 42.7
  TOP w0.254: PR4439.2 PR4435.2 125.36,151.84 PR4418.1 125.62,151.86 127.11,150.38 142.35,150.38 142.86,150.89 151.54,150.89 153.42,149.01 153.42,146.47 152.76,145.81 152.76,144.28 v2(153.02,144.03) 153.63,143.42 153.63,142.04 154.05,141.62 v1(154.16,141.62)
  BOTTOM w0.203: v1(154.16,141.62) 154.59,141.62 155.42,142.44 KBC24.20
BT+: length 13.9
  TOP w0.635: 165.06,179.77 BATT1.1 ; BATT1.1 166.05,178.78 ; BATT1.1 166.05,180.76 ; BATT1.1 167.04,179.77 ; 164.05,178.78 BATT1.2 ; BATT1.2 164.05,180.76 ; BATT1.2 165.04,179.77
  BOTTOM w0.635: BATT1.1 167.04,179.77 ; BATT1.1 166.05,178.78 ; BATT1.1 165.06,179.77 ; BATT1.1 166.05,180.76 ; BATT1.2 164.05,180.76 ; BATT1.2 165.04,179.77 ; BATT1.2 164.05,178.78
  vias: v3(155.94,166.13) v3(155.94,165.24) v3(156.83,166.13) v3(156.83,165.24) v3(157.72,166.13) v3(157.72,165.24) v3(158.6,166.13) v3(158.6,165.24) v3(161.27,175.14) v3(162.16,175.14) v3(162.16,174.13) v3(163.05,175.14) v3(163.05,174.13) v3(163.05,173.24)
BT+_R:
  vias: v2(160.99,156.35)
BYPASSCLK_H: length 8.9
  BOTTOM w0.102: R419.1 101.01,86.17 102.07,86.17 102.85,85.39 102.85,84.78 103.57,84.06 103.93,83.7 106.2,83.7 106.58,84.08 106.62,84.08 106.68,84.13 106.97,84.13 107.27,83.83 CPU1.B24
BYPASSCLK_L: length 7.7
  BOTTOM w0.102: CPU1.A24 106.6,83.58 106.37,83.58 106.28,83.5 103.84,83.5 103.36,83.98 102.65,84.69 102.65,85.05 v2(102.17,85.52) 101.88,85.82 R420.1
CAP_LED: length 4.2
  TOP w0.102: KB1.4 163.96,113.75 v1(163.71,113.5)
  BOTTOM w0.102: v1(163.71,113.5) 163.96,113.25 v2(163.96,111.92) 163.84,111.8 R6201.2
CAP_LED#: length 35.6
  TOP w0.102: v2(144.99,135.29) v1(144.99,134.63)
  L3 w0.102: v1(155.91,120.08) 156.6,119.39 v1(157.55,119.39)
  L4 w0.102: v1(155.91,120.08) 155.66,120.08 155.23,120.51 144.71,120.51 143.52,121.7 143.52,123.57 145.16,125.21 145.16,128.6 145.55,128.99 145.55,134.07 v1(144.99,134.63)
  BOTTOM w0.102: KBC24.109 145.35,134.27 v1(144.99,134.63) ; R6202.1 158.72,117.52 157.55,118.7 v1(157.55,119.39)
CAP_LED_Q: length 2.4
  BOTTOM w0.102: Q6201.C 161.96,111.81 R6201.1 161.97,110.87 v2(161.88,110.78)
CAP_LED_R#: length 2.3
  BOTTOM w0.102: Q6201.B 161.01,116.49 R6202.2 160.75,116.75 v2(159.93,116.75)
CARD_WLAN_OUT#: length 13.1
  TOP w0.102: TP2401.1 153.4,129.17 v1(153.02,129.55) ; v1(145.12,130.67) 145.14,130.69 TP2402.1
  L3 w0.102: v1(145.12,130.67) 146.06,129.73 152.4,129.73 152.57,129.55 v1(153.02,129.55)
  BOTTOM w0.102: KBC24.83 153.02,129.55 v1(153.02,129.55) ; KBC24.100 v1(145.12,130.67)
CBN: length 3.6
  BOTTOM w0.203: HDA27.35 160.04,10.91 160.64,10.32 160.64,10.3
  BOTTOM w0.254: 160.64,10.3 161.14,10.3 161.34,10.49 C2703.1 161.84,10.55 v2(162.8,10.55)
CBP: length 3.1
  TOP w0.254: v1(159.24,9.66) 160.36,9.66 v2(160.51,9.51) 161.03,9.51 v1(161.12,9.6)
  BOTTOM w0.203: v1(159.24,9.66) 159.08,9.66 159.06,9.69 HDA27.37
  BOTTOM w0.254: C2703.2 v1(161.12,9.6)
CHARGER_SRC:
  vias: v2(139.66,159.01) v2(145.04,158.84) v3(139.53,157.24) v3(140.46,157.24) v3(141.33,157.24) v3(142.6,157.24) v3(143.49,157.24) v3(144.38,157.24)
CHG_AGND: length 5
  TOP w0.508: v1(131.81,160.39) 132.11,160.39 PC4010.2 ; PR4423.2 123.74,154.67 v1(123.12,154.67)
  BOTTOM w0.406: PQ4407.1 123.94,161.74 124.21,162.01 124.21,162.8 124.46,163.04 PQ4407.4
  vias: v1(127.97,156.17) v1(128.79,156.98) v1(128.79,156.17) v1(128.79,155.36) v1(129.6,156.17) v2(125.66,160.08) v2(125.74,153.07)
CHG_AMBER_LED#: length 257.1
  TOP w0.102: v1(48.88,13.9) 48.88,13.78 v2(47.82,12.72) 45.7,10.6 R6104.2
  L4 w0.102: v1(71.89,56.45) 62.96,56.45 52.48,45.98 52.48,27.48 47.99,22.99 47.99,16.39 47.56,15.96 47.56,15.23 v1(48.88,13.9) ; v1(153.27,145.43) 155.05,143.65 155.05,139.51 156.83,137.73 156.83,132.07 157.28,131.61 157.28,129.45 158.48,128.25 159.32,128.25 160.89,126.68 160.89,124.28 159.47,122.86 159.47,119.77 165.67,113.57 165.67,89.89 166.2,89.36 166.2,84.93 165.89,84.63 165.89,79.79 165.54,79.44 165.54,76.48 165.06,75.99 165.06,75.12 164.7,74.76 v1(164.57,74.76)
  BOTTOM w0.102: KBC24.16 153.82,144.81 153.5,145.13 153.5,145.2 v1(153.27,145.43) ; v1(71.89,56.45) 71.89,56.02 72.32,55.59 72.67,55.59 72.68,55.6 76,55.6 81.51,50.09 146.74,50.09 152.78,56.12 155.88,56.12 158.73,58.97 158.73,63.2 157.4,64.53 157.4,68.37 163.8,74.76 v1(164.57,74.76)
CHG_AMBER_LED_R#: length 2.5
  TOP w0.102: v2(46.63,9.47) R6104.1 44.51,9.47 Q6104.B
CLK_LAN_REQ0#_R: length 35.2
  TOP w0.102: R3004.2 77.34,160.81 77.01,161.14 v2(77.01,161.43) 77.01,162.24 Q3002.E 76.62,165.75 R3005.2 76.26,166.14 v1(76.26,166.89) ; v1(50.09,166.13) 50.09,166.13 50.07,166.15 LOM30.12
  L3 w0.102: v1(50.09,166.13) 50.29,166.33 56.04,166.33 56.06,166.31 60.97,166.31 62.31,167.65 75.05,167.65 75.45,167.24 75.9,167.24 v1(76.26,166.89)
CLK_LAN_REQ#_EN: length 2.6
  TOP w0.127: Q3002.B 73.96,161.86 v2(73.96,161.3) R3003.2
CLK_MINI1#_R: length 13.7
  TOP w0.14: v1(120.54,94.34) 120.17,94.7 120.17,94.8 119.93,95.05 119.93,95.26 119.67,95.53 119.67,96.25 120.05,96.63 121.22,96.63 121.5,96.91 121.5,100.67 ; 121.5,100.67 121.5,102.4 122,102.91 122,103.47 v1(121.7,103.77) ; 121.5,100.67 v2(121.29,100.67)
  BOTTOM w0.14: RN1903.4 121.83,104.43 122,104.25 122,104.07 v1(121.7,103.77) ; CPU1.AE5 v1(120.54,94.34)
CLK_MINI1_R: length 13.6
  TOP w0.14: 120.61,96.37 121.33,96.37 121.76,96.8 121.76,102.29 122.27,102.8 122.27,103.66 122.41,103.8 v1(122.64,103.8) ; 120.61,96.37 v2(120.61,96.18) ; 120.61,96.37 120.16,96.37 119.93,96.14 119.93,95.64 120.2,95.37 120.2,95.16 120.32,95.03 v1(120.63,95.03)
  BOTTOM w0.14: RN1903.3 122.48,104.43 122.27,104.21 122.27,103.91 122.38,103.8 v1(122.64,103.8) ; v1(120.63,95.03) 120.63,94.88 120.54,94.79 120.35,94.79 120.24,94.68 CPU1.AE4
CLK_PCI_KBC: length 60.6
  L3 w0.102: v1(147.67,142.01) 147,141.34 145.04,141.34 144.69,140.98 142.09,140.98 137.8,136.69 137.8,124.09 137.8,123.05 143.8,117.05 143.8,107.76 v1(142.6,106.56)
  BOTTOM w0.102: KBC24.2 148.22,142.56 v1(147.67,142.01) ; R1906.1 134.73,98.44 v2(136.13,99.83) 136.58,100.29 137.6,100.29 137.83,100.52 137.83,103.69 139.68,105.55 139.68,106.18 139.94,106.44 142.48,106.44 v1(142.6,106.56)
CLK_PCI_LPC: length 63.5
  TOP w0.102: DB1.2 168.8,139.66 v1(169.17,139.28)
  L3 w0.102: v1(147.07,121.83) 147.2,121.83 147.38,121.65 148.12,121.65 148.9,120.86 158.2,120.86 159.99,122.66 161.08,122.66 161.45,122.29 167.14,122.29 169.35,124.5 v1(169.81,124.5)
  L4 w0.102: v1(169.81,124.5) 170.31,125 170.31,127.93 169.27,128.97 169.27,135.39 170.06,136.18 170.06,138.39 v1(169.17,139.28)
  BOTTOM w0.102: R1907.2 137.4,105.82 137.4,106.19 142.78,111.57 142.78,112.59 145.52,115.33 145.52,120.08 v2(145.84,120.39) 146.57,121.12 146.57,121.32 v1(147.07,121.83)
CLK_PCIE_LAN_N0: length 150.1
  TOP w0.14: v1(52.94,163.94) 52.7,163.7 52.39,163.7 51.99,164.1 51.99,165.14 ; LOM30.16 51.67,166.83 51.61,166.76 51.61,166.59 51.99,166.21 51.99,165.14 ; RN1902.1 119.69,94.23 118.92,95 118.92,95.85 117.85,96.92 116.83,96.92 115.55,98.2 115.55,99.27 114.98,99.85 114.98,100.17 v1(115.27,100.46) ; 51.99,165.14 v2(52.18,165.14)
  L4 w0.127: v1(115.27,100.46) 115.07,100.66 115.07,104.45 113.77,105.75 109.61,105.75 107.89,104.04 106.27,104.04 105.15,105.15 97.35,105.15 94.03,108.48 94.03,129.39 107.44,142.8 107.44,151 104.22,154.21 88.48,154.21 86.21,156.47 81.26,156.47 75.03,162.71 55.48,162.71 55.48,162.71 54.96,162.71 53.98,163.69 53.19,163.69 v1(52.94,163.94)
CLK_PCIE_LAN_N0_R: length 2.5
  TOP w0.14: v1(118.39,91.76) 118.4,91.77 118.44,91.77 118.6,91.93 119.39,91.93 119.69,92.23 RN1902.4
  BOTTOM w0.14: CPU1.AC10 v1(118.39,91.76)
CLK_PCIE_LAN_P0: length 150.2
  TOP w0.14: 52,163.71 51.72,163.99 51.72,166.1 51.34,166.48 51.34,166.7 51.27,166.76 LOM30.15 ; 52,163.71 v2(51.85,163.56) ; 52,163.71 52.28,163.43 52.6,163.43 v1(52.94,163.09) ; RN1902.2 119.04,94.5 118.65,94.89 118.65,95.74 117.74,96.66 116.72,96.66 115.29,98.09 115.29,99.16 114.71,99.74 114.71,100.17 v1(114.42,100.46)
  L4 w0.127: v1(114.42,100.46) 114.8,100.83 114.8,104.34 113.66,105.48 109.72,105.48 108,103.77 106.16,103.77 105.04,104.89 97.24,104.89 93.76,108.37 93.76,129.5 107.17,142.91 107.17,150.89 104.11,153.95 88.37,153.95 86.1,156.21 81.15,156.21 74.92,162.44 55.59,162.44 54.84,162.44 53.87,163.42 53.27,163.42 v1(52.94,163.09)
CLK_PCIE_LAN_P0_R: length 2.4
  TOP w0.14: RN1902.3 119.04,92.34 118.91,92.21 118.7,92.21 118.67,92.24 118.45,92.24 118.32,92.37 v1(118.32,92.67)
  BOTTOM w0.14: CPU1.AC8 118.83,92.21 118.45,92.21 118.32,92.34 v1(118.32,92.67)
CLK_PCIE_LAN_REQ0#: length 226
  TOP w0.102: v1(142.53,125.74) 142.53,124.29 v2(143.46,123.36) 145.07,121.75 146.29,121.75 146.64,121.4 146.64,120.81 152.1,115.35 157.11,115.35 157.29,115.17 158.31,115.17 161.87,111.61 v1(161.87,95.08) ; v1(75.09,166.89) 75.09,166.71 75.36,166.44 R3005.1 75.36,165.68 75.67,165.36 Q3002.C
  L3 w0.102: v1(75.09,166.89) 75.79,166.19 77.3,166.19 81.88,161.6 81.88,158.91 83.51,157.29 84.72,157.29 84.72,157.29 85.15,157.29 92.58,157.29 94.05,155.81 108.15,155.81 109.6,154.37 117.8,154.37 121.79,150.37 123.61,150.37 126.17,147.81 130.31,147.81 130.59,148.09 143.5,148.09 144.51,147.09 v1(144.51,146.85) ; v1(161.87,95.08) 163.48,93.47 163.48,88 163.96,87.51 163.96,85.51 164.73,84.75 164.73,81.85 159.83,76.95 157.16,76.95 150.08,69.87 150.08,69.74 147.45,67.11 v1(147.45,64.96)
  L4 w0.102: v1(147.45,64.96) 147.45,67.9 148,68.44 148,72.3 143.95,76.35 143.95,77.6 142.77,78.78 139.15,78.78 137.09,80.83 136.35,80.83 136.09,80.57 131.58,80.57 131.4,80.75 128.89,80.75 127.58,82.05 127.21,82.05 126.96,81.8 126.96,80.94 v1(126.63,80.61)
  BOTTOM w0.102: v1(142.53,125.74) 141.47,125.74 139.68,127.53 139.68,130.81 139.36,131.12 139.36,140.5 141.01,142.14 141.01,143.46 143.14,145.59 143.56,145.59 144.51,146.54 v1(144.51,146.85) ; v1(126.63,80.61) 126.63,80.64 CPU1.AU29
CLK_PCIE_WLAN_N1: length 96.3
  L4 w0.127: v1(121.77,107.2) 122.03,106.95 122.03,106.42 125.72,102.73 130.08,102.73 131.72,104.37 141.21,104.37 146.81,98.77 146.81,96.34 148.48,94.66 148.48,88.35 154.77,82.06 154.77,81.02 155.38,80.41 155.38,76.78 155.65,76.51 155.65,73.51 158.39,70.76 160.88,70.76 162.94,68.71 162.94,64.92 162.56,64.54 161.36,63.34 161.36,56.61 161.77,56.2 161.77,54.98 159.91,53.12 158.85,53.12 158.57,52.84 158.57,52.14 v1(158.18,51.75)
  BOTTOM w0.14: v2(158.38,50.48) 158.5,50.61 ; 158.5,50.61 158.25,50.86 158.25,51.67 v1(158.18,51.75) ; 158.5,50.61 158.74,50.37 EC5801.1 160.9,50.37 161.23,50.7 161.64,50.7 162.08,51.14 162.25,51.14 162.37,51.02 WLAN1.49 ; v1(121.77,107.2) 121.94,107.03 121.94,106.51 121.83,106.4 RN1903.1
CLK_PCIE_WLAN_P1: length 96.4
  L4 w0.127: v1(122.48,107.22) 122.29,107.03 122.29,106.53 125.83,103 129.97,103 131.61,104.63 141.32,104.63 147.07,98.88 147.07,96.45 148.75,94.77 148.75,88.46 155.04,82.17 155.04,81.13 155.64,80.52 155.64,76.89 155.91,76.62 155.91,73.62 158.5,71.03 160.99,71.03 163.2,68.82 163.2,64.81 162.67,64.28 161.63,63.23 161.63,56.73 162.04,56.31 162.04,54.87 160.02,52.86 158.96,52.86 158.83,52.73 158.83,51.94 v1(159.02,51.75)
  BOTTOM w0.14: 159.62,50.63 159.98,50.63 160.6,51.26 EC5802.1 160.95,51.26 161.25,50.96 161.53,50.96 161.97,51.4 162.25,51.4 162.37,51.52 WLAN1.47 ; 159.62,50.63 158.86,50.63 158.52,50.97 158.52,51.3 158.96,51.75 v1(159.02,51.75) ; 159.62,50.63 v2(159.62,50.79) ; RN1903.2 122.48,106.4 122.21,106.67 122.21,106.94 v1(122.48,107.22)
CLK_PCIE_WLAN_REQ1#: length 53.5
  TOP w0.102: v1(160,54.37) 160.45,53.92 R5812.1 162.55,53.92 162.81,53.67 R5803.2 ; v1(130.48,80.11) 130.91,80.54 131.53,80.54 132.61,79.47 135.03,79.47 v2(136.24,78.26) 138.79,75.7 141.94,75.7 142.84,74.8 146.2,74.8 152.53,68.46 v1(153.65,68.46)
  L4 w0.102: v1(160,54.37) 159.75,54.11 158.58,54.11 157.94,54.75 157.94,64.53 154.01,68.46 v1(153.65,68.46)
  BOTTOM w0.102: CPU1.AW29 127.93,81.08 128.42,80.58 128.42,80.43 128.62,80.23 128.89,80.23 129.04,80.37 129.39,80.37 129.56,80.54 130.05,80.54 v1(130.48,80.11)
CLK_PCIE_WLAN_REQ#: length 6.1
  TOP w0.102: R5803.1 161.97,52.78 AFTP5802.1 161.68,52.43 161.68,50.28 v1(161.42,50.02)
  BOTTOM w0.102: WLAN1.53 v1(161.42,50.02)
CODEC_BITCLK_R: length 3.5
  BOTTOM w0.114: R2720.2 151.24,12.2 v2(151.57,12.2) 151.9,12.2 152.25,12.55 152.69,12.55 152.73,12.51 HDA27.6
CODEC_SDOUT_R: length 6.6
  TOP w0.114: v1(152.51,12.11) v2(150.35,14.27) 149.71,14.9 v1(149.71,15.61)
  BOTTOM w0.114: R2719.2 149.59,15.88 149.71,15.76 v1(149.71,15.61) ; HDA27.5 v1(152.51,12.11)
COMBO-GPI: length 4.2
  BOTTOM w0.102: TP2702.1 150.96,8.49 151.7,9.23 154.11,9.23 154.35,9.47 HDA27.48
COMPNB_R: length 1.8
  BOTTOM w0.254: v2(114.41,141.23) 114.27,141.37 PC4611.2 PR4624.2
CPVEE: length 2.4
  TOP w0.254: v1(160.88,10.81) 160.5,10.42 C2704.2
  BOTTOM w0.203: HDA27.34 160.08,11.31 160.58,10.81 v1(160.88,10.81)
CR_GPIO0: length 2.7
  BOTTOM w0.14: TP3201.1 22.7,19.2 U3201.17
CRT_B: length 9.6
  TOP w0.114: L5508.2 21.64,63.64 C5543.1 20.49,63.57 v2(20.3,63.76) 19.6,64.46 14.81,64.46 HDMI1.3
CRT_DDCCLK_CON: length 17
  TOP w0.14: R5527.2 28.43,65.4 C5511.1 27.36,65.4 v1(26.86,65.91)
  L4 w0.127: v1(26.86,65.91) 26.83,65.91 26.69,65.77 19.06,65.77 17.99,66.84 17,66.84 16.59,67.24 16.59,68.66 HDMI1.15
  BOTTOM w0.14: v2(26.02,65.97) 26.08,65.91 v1(26.86,65.91)
CRT_DDCCLK_CON_R: length 6.2
  TOP w0.114: v2(29.9,66.89) v1(29.9,66.13) 30.04,65.99 30.04,65.67 29.81,65.44 R5527.1
  L4 w0.102: v1(29.9,66.13) 29.9,64.45 v1(30.28,64.07)
  BOTTOM w0.114: v1(29.9,66.13) 29.91,66.13 RN5508.4 ; Q5502.6 v1(30.28,64.07)
CRT_DDCDATA_CON: length 17
  TOP w0.14: v1(26.83,65.12) 27.34,64.62 C5508.1 28.46,64.62 R5526.2
  L4 w0.127: HDMI1.12 15.45,63.18 16.59,64.32 16.59,65.92 17,66.33 17.78,66.33 18.85,65.26 26.69,65.26 v1(26.83,65.12)
  BOTTOM w0.14: v2(27.52,64.88) 27.27,65.12 v1(26.83,65.12)
CRT_DDCDATA_CON_R: length 5.1
  TOP w0.114: R5526.1 30.08,64.63 30.46,65.01 v2(30.46,65.11) 30.46,65.82 v1(30.59,65.95)
  BOTTOM w0.114: Q5502.3 29.81,65.37 30.39,65.95 v1(30.59,65.95) 30.56,65.98 RN5508.3
CRT_G: length 9.7
  TOP w0.114: HDMI1.2 14.87,62.11 19.54,62.11 v2(20.05,61.61) 20.75,60.91 C5542.1 22.5,60.91 L5509.2
CRT_HSYNC1_1: length 11.2
  TOP w0.114: v1(33.46,69.28) 33.56,69.38 34.6,69.38 35.56,68.42 U5603.8
  BOTTOM w0.114: v1(33.46,69.28) 32.65,70.09 v2(30.51,70.09) 29.73,70.09 27.99,71.82 RN5507.2
CRT_HSYNC_CON: length 17.3
  TOP w0.14: HDMI1.13 16.04,66.3 16.62,66.3 17.13,65.8 v2(19.06,65.8) 24.11,65.8 24.7,66.38 24.7,68.25 C5509.1 24.81,68.64 24.62,68.83 24.62,71.11 v1(24.98,71.46) 25.05,71.46 25.41,71.82 RN5506.4
  BOTTOM w0.14: v1(24.98,71.46) 25.05,71.46 25.41,71.82 RN5506.4
CRT_R: length 9.7
  TOP w0.114: L5507.2 22.5,58.75 C5541.1 v2(19.67,58.75) 15.94,58.75 HDMI1.1
CRT_VSYNC1_1: length 11
  TOP w0.114: v1(33.46,69.94) 33.59,69.81 34.55,69.81 35.11,70.37 U5603.11
  BOTTOM w0.114: v1(33.46,69.94) 32.72,70.67 v2(32.21,70.67) 29.78,70.67 27.98,72.47 RN5507.1
CRT_VSYNC_CON: length 17.2
  TOP w0.14: RN5506.3 25.17,72.47 v1(24.95,72.25) 24.92,72.25 24.04,71.36 24.04,70.76 24.04,68.69 24,68.65 C5510.1 24.11,68.25 24.11,66.81 23.68,66.38 v2(21.09,66.38) 17.37,66.38 16.86,66.89 16.07,66.89 HDMI1.14
  BOTTOM w0.14: RN5506.3 25.17,72.47 v1(24.95,72.25)
DAC_BLUE: length 107.8
  TOP w0.114: v1(72.5,79.13) 72.19,78.83 66.61,78.83 65.13,77.35 65.13,76.79 65.25,76.67 66.78,76.67 66.91,76.55 66.91,76.3 66.78,76.18 65.25,76.18 65.13,76.06 65.13,75.8 65.25,75.68 66.03,75.68 66.15,75.57 66.15,75.3 66.03,75.19 65.25,75.19 65.13,75.07 65.13,74.06 63.73,72.65 61.32,72.65 60.03,71.36 42.5,71.36 36.17,65.04 32.57,65.04 30.46,62.93 v2(29.22,62.93) 26.41,62.93 R5523.2 C5540.1 23.95,63.57 L5508.1
  L4 w0.114: v1(72.5,79.13) 75.99,79.13 91.33,94.47 97.83,94.47 99.19,93.1 99.73,93.1 v1(101.18,91.65)
  BOTTOM w0.114: CPU1.B15 106.94,88.78 106.62,88.47 105.5,88.47 105.44,88.53 105.16,88.53
  BOTTOM w0.254: R408.1 100.87,91.99 101.18,91.68 v1(101.18,91.65) 101.18,90.49 103.13,88.53 105.16,88.53
DAC_GREEN: length 107.2
  TOP w0.114: v1(73.01,79.64) 73.01,78.94 72.4,78.33 70.11,78.33 69.13,77.35 68.96,77.35 68.14,78.17 67.98,78.17 67.79,77.98 67.79,77.82 68.61,77 68.61,76.84 68.43,76.65 68.26,76.65 67.44,77.47 67.28,77.47 67.09,77.28 67.09,77.12 67.91,76.3 67.91,76.14 63.94,72.16 61.53,72.16 60.23,70.86 42.7,70.86 36.38,64.54 32.78,64.54 30.67,62.43 27.41,62.43 v2(26.89,61.91) R5524.2 C5539.1 23.95,60.78 L5509.1
  L4 w0.114: v1(73.01,79.64) 75.62,79.64 90.94,94.96 98.1,94.96 99.32,93.74 100.08,93.74 v1(101.45,92.37)
  BOTTOM w0.114: 104.93,89.04 105.28,89.38 106.25,89.38 106.28,89.36 106.82,89.36 CPU1.A14
  BOTTOM w0.254: 104.93,89.04 103.41,89.04 101.73,90.71 101.73,92.01 101.45,92.29 v1(101.45,92.37) 100.94,92.88 R406.1
DAC_HSYNC: length 105.5
  TOP w0.114: U5603.9 37.67,69.07 38.54,69.94 v1(38.54,70.01) ; RN5506.1 28.18,71.82 R429.1 29.26,71.7 v1(29.37,71.82) ; v1(109.68,87.11) 109.68,87.33 109.46,87.56 107.85,87.56 107.68,87.39 v2(107.01,87.39) 106.38,88.02 104.4,88.02 103.44,88.98 101.8,88.98 99.85,90.93 97.91,90.93 96.21,89.23 92.3,89.23 92.04,88.98 90.62,88.98 89.11,87.47 89.11,87.27 89.11,86.92 88.41,86.22 88.41,85.2 87.25,84.04 85.97,84.04 85.62,83.69 83.59,83.69 82.55,82.66 82.54,82.66 82.32,82.44 81.98,82.09 81.98,78.07 81.99,78.06 81.99,76.64 79.09,73.75 79.09,73.74 78.51,73.16 v1(78.44,73.16)
  L3 w0.102: v1(38.54,70.01) 38.77,70.24 40.01,70.24 43.75,73.98 53.12,73.98 57.13,77.99 66.21,77.99 69.42,74.78 70.7,73.49 78.11,73.49 v1(78.44,73.16)
  BOTTOM w0.114: v1(38.54,70.01) 38.13,70.42 34.73,70.42 33.29,71.85 29.41,71.85 v1(29.37,71.82) ; CPU1.G19 109.68,87.09 v1(109.68,87.11)
DAC_RED: length 107.1
  TOP w0.114: v1(73.51,80.15) 73.51,78.75 73.49,78.73 73.49,78.72 72.6,77.84 70.31,77.84 64.14,71.66 61.73,71.66 60.44,70.37 42.91,70.37 36.59,64.05 33.03,64.05 30.92,61.94 27.67,61.94 26.94,61.21 v2(26.94,60.01) 26.94,59.45 26.24,58.75 R5525.2 C5506.1 23.95,58.75 L5507.1
  L4 w0.114: v1(102.24,91.93) 102.24,92.29 98.95,95.58 90.69,95.58 75.38,80.27 73.64,80.27 v1(73.51,80.15)
  BOTTOM w0.114: CPU1.B14 107.28,89.33 106.97,89.64 106.69,89.64 106.62,89.57 106.37,89.57 106.34,89.6 104.81,89.6 104.77,89.55
  BOTTOM w0.254: R405.1 100.89,93.82 102.24,92.47 v1(102.24,91.93) 102.24,90.92 103.61,89.55 104.76,89.55 104.77,89.55
DAC_SCL: length 95.7
  TOP w0.114: v1(80.17,73.19) 80.17,73.3 80.72,73.86 82.16,73.86 v2(83.74,75.44) 84.09,75.79 84.98,75.79 v1(85.3,76.11)
  L3 w0.102: v1(70.57,75.83) 70.91,75.83 71.16,75.58 72.94,75.58 74.21,74.31 79.44,74.31 80.17,73.58 v1(80.17,73.19)
  L4 w0.102: v1(70.57,75.83) 70.47,75.93 65.3,75.93 64.31,74.94 55.91,74.94 54.67,73.7 44.35,73.7 39.39,68.74 34.77,68.74 33.43,67.41 v1(33.43,67.19) ; v1(85.3,76.11) 85.33,76.14 85.36,76.14 87.62,78.4 88.71,78.4 90.06,79.74 90.4,79.74 92.15,79.74 93.5,78.4 101.55,78.4 106.03,82.87 106.03,84.63 107.24,85.84 107.93,85.84 v1(108.19,86.09)
  BOTTOM w0.114: CPU1.D19 108.6,86.5 v1(108.19,86.09) ; Q5502.1 29.29,63.94 29.8,63.43 31.51,63.43 31.87,63.79 31.87,63.8 31.91,63.84 31.91,64.35 32.29,64.73 33.23,64.73 33.4,64.9 RN5509.2 33.4,67.16 v1(33.43,67.19)
DAC_SDA: length 93
  TOP w0.114: v1(80.91,73.42) 80.93,73.44 82.33,73.44 v2(82.72,73.82) 84.27,75.37 v1(85.3,75.37)
  L3 w0.102: v1(70.96,76.35) 71.33,75.98 73.11,75.98 74.38,74.71 79.61,74.71 v1(80.91,73.42)
  L4 w0.102: v1(70.96,76.35) 70.94,76.34 65.13,76.34 64.14,75.35 55.74,75.35 55.51,75.11 54.5,74.1 44.18,74.1 39.22,69.15 34.6,69.15 v1(32.75,67.3) ; v1(108.99,86.02) 108.6,85.63 107.32,85.63 106.23,84.54 106.23,82.79 101.61,78.17 98.61,78.17 98.43,77.99 93.33,77.99 91.98,79.34 90.23,79.34 88.88,77.99 87.79,77.99 85.3,75.5 v1(85.3,75.37)
  BOTTOM w0.114: v1(32.75,67.3) RN5509.1 31.25,65.29 Q5502.4 ; v1(108.99,86.02) 108.6,85.63 CPU1.D21
DAC_VSYNC: length 105.1
  TOP w0.114: v1(38.59,70.67) 38.24,71.02 U5603.12 ; RN5506.2 28.69,72.47 v1(28.89,72.27) ; v1(79.1,72.83) 79.1,73.16 79.51,73.56 79.51,73.57 82.4,76.46 82.4,78.24 82.4,78.24 82.4,81.92 82.47,81.99 82.72,82.24 82.72,82.24 83.76,83.27 85.79,83.27 86.14,83.62 87.43,83.62 87.44,83.63 87.54,83.63 88.83,84.92 88.83,85.02 88.83,85.03 88.83,86.04 89.53,86.74 89.53,87.3 90.79,88.56 92.22,88.56 92.47,88.82 96.39,88.82 98.08,90.51 98.38,90.51 98.38,90.52 99.72,90.52 101.56,88.68 103.39,88.68 104.35,87.72 106.12,87.72 107.21,86.62 108.54,86.62 v1(109.02,87.11)
  L3 w0.102: v1(79.1,72.83) 79.1,73.42 78.62,73.9 70.87,73.9 69.7,75.07 66.38,78.4 56.96,78.4 52.95,74.38 43.58,74.38 39.84,70.65 38.62,70.65 v1(38.59,70.67)
  BOTTOM w0.114: v1(38.59,70.67) 38.42,70.84 v2(36.05,70.84) 34.9,70.84 33.47,72.27 v1(28.89,72.27) ; CPU1.E19 109.02,86.95 v1(109.02,87.11)
DAC_ZVSS: length 8
  BOTTOM w0.114: R407.1 100.44,90.56 102.93,88.07 v2(103.97,88.07) 106.69,88.07 CPU1.A16
DBC_EN: length 5.9
  BOTTOM w0.102: CPU1.AY28 128.27,81.63 128.58,81.33 128.87,81.33 128.93,81.38 130.88,81.38 v2(131.56,80.7) 131.73,80.53 132.53,80.53 R601.1 132.63,80.43 R5449.2
DBC_EN_R: length 189.7
  TOP w0.102: LCD1.8 v1(95.33,153.02) ; v1(153.49,67.83) 152.45,67.83 145.99,74.29 141.75,74.29 140.98,75.07 v1(139.43,75.07) ; v1(162.05,88.62) 162.06,88.63 162.14,88.63 163.65,90.15 163.65,112.34 159.05,116.95 158.03,116.95 155.3,119.67 155.3,122.19 155.96,122.85 155.96,124.13 154.68,125.41 153.5,125.41 153.25,125.66 153.25,126.5 152.64,127.11 145.11,127.11 v2(144.66,126.66) 143.11,125.11 v1(143.11,124.32)
  L3 w0.102: v1(160.17,75.03) 159.8,74.66 158.56,74.66 157.63,73.73 157.63,72.89 153.64,68.9 153.47,68.9 153.22,68.64 153.22,68.1 v1(153.49,67.83) ; v1(143.24,146.81) 143.18,146.81 142.79,147.2 133.23,147.2 132.95,146.92 125.8,146.92 123.24,149.48 121.42,149.48 117.43,153.48 108.84,153.48 107.49,154.82 97.14,154.82 v1(95.33,153.02)
  L4 w0.102: v1(162.05,88.62) 160.79,87.36 160.79,75.37 160.45,75.03 v1(160.17,75.03)
  BOTTOM w0.102: R5449.1 135.26,79.61 139.43,75.45 v1(139.43,75.07) ; v1(143.24,146.81) 142.85,147.2 142.21,147.2 139.89,144.88 139.89,142.6 137.93,140.64 137.93,136.71 138.25,136.39 138.25,127.39 141.31,124.32 v1(143.11,124.32)
DBRDY1: length 7.1
  BOTTOM w0.127: HDT1.15 90.83,87.26 90.49,86.93 90.49,83.41 90.16,83.08 RN6502.1
DBRDY2: length 5.7
  BOTTOM w0.127: RN6502.2 89.91,82.43 90.81,83.33 90.81,84.51 91.19,84.89 91.19,85.23 91.96,85.99 HDT1.13
DBRDY3: length 5.2
  BOTTOM w0.127: HDT1.11 91.42,84.72 91.09,84.39 91.09,83.13 89.89,81.93 RN6502.3
DCBATOUT: length 5.1
  TOP w0.508: 110.22,146.82 114.1,146.82 114.83,146.1 PR4612.1
  vias: v2(55.48,56.14) v2(78.98,80.02) v2(107.8,147.84) v2(115.04,161.3) v2(132.95,146.44) v2(143.87,119.14) v3(30.64,52.41) v3(31.27,53.05) v3(31.91,53.68) v3(50.4,56.78) v3(51.04,56.14) v3(51.8,55.61) v3(60.08,58.15) v3(60.99,58.18) v3(61.93,58.18) v3(62.85,58.18) v3(98.28,121.93) v3(98.28,121.04) v3(98.28,120.13) v3(99.37,121.85) v3(99.37,120.97) v3(99.37,120.13) v3(104.92,130.27) v3(105.62,130.97) v3(106.38,131.73) v3(107.15,132.5) v3(111.49,157.87) v3(112.12,156.98) v3(112.5,157.87) v3(113.27,156.6) v3(114.28,156.6) v3(115.3,156.6) v3(116.31,156.6) v3(121.67,171.26) v3(121.67,170.37) v3(121.67,169.48) v3(121.67,168.59) v3(122.64,171.31) v3(122.64,170.42) v3(122.64,169.53) v3(122.64,168.64) v3(135.03,170.98) v3(135.03,169.84) v3(136.13,170.95) v3(136.13,169.81) v3(136.48,144.56) v3(136.48,143.55) v3(137.37,144.56) v3(137.37,143.55) v3(138.26,144.56) v3(138.26,143.55) v3(146.46,169.33) v3(147.56,169.3) v3(148.85,110.2) v3(151.04,168.95) v3(151.06,170.01) v3(152.13,168.92) v3(152.15,169.99) v3(153.25,169.96) v3(153.27,168.92)
DCBATOUT_LCD:
  vias: v3(96.32,156.61) v3(97.22,156.64)
DDC_CLK_HDMI: length 32.2
  L4 w0.102: 11.56,70.56 11.56,70.32 11.34,70.09 11.1,70.09 10.53,69.53 10.53,68.35 HDMI1.HP15
  L4 w0.127: v1(20.07,80.2) 19.87,80 19.51,80 18.19,78.68 18.19,77.19 11.56,70.56
  BOTTOM w0.14: v1(20.07,80.2) 20.23,80.04 RN5404.4 21.37,80.04 21.7,79.72 21.7,79.08 22.28,78.5 24.57,78.5 24.77,78.7 24.77,80 24.4,80.37 Q5402.3 24.06,80.73 24.84,81.51 28.06,81.51 28.43,81.14 ; 28.43,81.14 28.61,80.96 28.61,80.09 28.76,79.94 RN5401.2 ; 28.43,81.14 v2(28.56,81.27)
DDC_CLK_PH1: length 4.4
  BOTTOM w0.14: D5401.2 33.99,79.81 32.98,79.81 ; RN5401.3 30.88,79.94 31.01,79.81 32.98,79.81 ; v2(32.98,80) 32.98,79.81
DDC_DATA_HDMI: length 32.6
  L4 w0.102: 11.93,70.21 11.74,70.21 11.42,69.89 11.18,69.89 10.74,69.45 10.74,67.93 10.87,67.8 11.27,67.8 11.4,67.93 HDMI1.HP16
  L4 w0.127: 11.93,70.21 18.7,76.98 18.7,78.47 19.72,79.49 19.98,79.49 v1(20.07,79.39)
  BOTTOM w0.14: v1(20.07,79.39) RN5404.3 21.1,78.94 22.06,77.98 24.47,77.98 ; RN5401.1 28.67,79.29 28.09,79.88 28.09,80.74 27.85,80.99 25.46,80.99 25.24,80.76 25.24,79.43 25.6,79.07 Q5402.6 25.94,78.85 26.19,78.6 26.19,78.24 26.07,78.12 24.92,78.12 24.79,77.98 24.47,77.98 ; 24.47,77.98 v2(24.47,77.79)
DDC_DATA_PH2: length 4.6
  BOTTOM w0.14: D5401.1 33.36,79.29 31.66,79.29 ; v2(31.66,79.08) 31.66,79.29 ; 31.66,79.29 RN5401.4
DDR3_DRAMRST#: length 85.3
  TOP w0.114: v1(89.62,18.97) 89.58,19 C1333.1 ; v2(85.15,30.52) 85.15,29.83 C1221.1 85.14,28.62 v1(85.28,28.48)
  L3 w0.102: v1(108.91,76.86) 108.89,76.85 106.74,76.85 101.1,71.21 101.1,70.52 87.43,56.86 87.43,39.91 84.03,36.51 82.38,36.51 81.72,35.85 81.72,33.36 85.28,29.81 v1(85.28,28.48) 84.84,28.05 84.84,26.98 85.12,26.71 85.63,26.71 86.62,25.72 88.17,25.72 90.58,23.31 90.58,21.52 89.62,20.56 v1(89.62,18.97)
  BOTTOM w0.114: CPU1.G38 109.5,76.28 109.14,76.64 109.1,76.64 108.92,76.82 108.92,76.85 v1(108.91,76.86) ; v1(85.28,28.48) 84.95,28.81 DM1.30 ; DM2.30 89.85,18.73 v1(89.62,18.97)
DDR_VREF_S3: length 128.2
  TOP w0.508: C1205.1 C1203.1 116.67,28.95 v1(116.67,28.15)
  L3 w0.305: v1(116.67,28.15) 116.44,27.93 116.44,27.19 117.08,26.55
  L3 w0.508: 117.08,26.55 121.05,22.58 v3(121.05,15.25)
  L3 w1.016: v3(65.64,42.94) 65.64,45.48 63.1,48.02 59.44,48.02 v3(56.37,51.09)
  L4 w0.508: v1(116.67,28.15) 116.67,25.11 121.05,20.73 v3(121.05,15.25)
  L4 w1.016: v3(121.05,15.25) 119.93,14.13 82.15,14.13 80.3,15.99 v3(80.3,17.79)
  BOTTOM w0.305: CPU1.AD40 119.45,75.8 v1(119.41,75.83)
  BOTTOM w0.33: v1(119.41,75.83) 119.41,75.91 119.05,76.28 CPU1.AC38 ; DM2.126 v3(121.05,15.25) ; v1(116.67,28.15) 116.67,28.54 116.15,29.05 DM1.126
  BOTTOM w0.508: 69.7,38.87 v3(69.7,38.49)
  BOTTOM w1.016: v3(69.7,38.49) 69.7,27.04 72.98,23.76 76.18,23.76 76.23,23.81 76.23,21.76 80.2,17.79 v3(80.3,17.79) ; v3(65.64,42.94) 69.7,38.87
  vias: v1(105.15,77.34) v1(108.08,77.28) v2(73.13,42.56) v2(86.09,55.76) v2(102.47,74.69)
DDR_VTT_PG_CTRL_R: length 3
  TOP w0.127: PR4910.1 64.82,45.1 v2(64.5,45.1) 64.24,45.1 63.5,45.84 PU4901.17
DGPU_PRESENT#: length 7
  BOTTOM w0.102: R643.1 R642.2 133.15,83.27 v2(132.7,83.27) 132.33,83.27 131.7,83.9 129.28,83.9 128.75,83.36 CPU1.BA26
DIFFNB_R: length 1.9
  BOTTOM w0.254: v2(114.46,142.68) 114.14,143 PR4623.2 113.61,142.94 PC4610.1
DM2_SA0: length 3.4
  TOP w0.102: v2(142.58,25.84) 142.58,26.4 v1(142.6,26.43) 142.73,26.55 R1301.1
  BOTTOM w0.102: DM2.197 142.35,26.17 v1(142.6,26.43)
DMIC_CLK: length 5.2
  BOTTOM w0.14: v2(100.41,144.23) 101.01,143.64 C2723.2 R2716.1 100.95,142.44 EC5206.1 100.1,142.44 99.35,143.19 RN5204.3
DMIC_CLK_EDP: length 3.9
  TOP w0.14: v2(95.71,143.42) 95.36,143.77 v1(95.18,143.77) 95.13,143.77 94.88,143.52 LCD1.27
  BOTTOM w0.14: v1(95.18,143.77) 95.26,143.77 95.85,143.19 RN5204.2
DMIC_CLK_R: length 203.6
  L3 w0.127: v1(112.76,149.49) 108.81,149.49 106.41,147.09 106.41,143.22 105.47,142.28 103.59,142.28 v1(103.49,142.38)
  L4 w0.127: v1(152.61,11.42) 152.47,11.42 152,11.88 152,20.33 152.59,20.92 152.59,23.07 153.48,23.97 153.48,25.02 153.46,25.05 153.46,27.27 155.77,29.58 156.66,29.58 157.77,30.69 157.77,31.71 161.7,35.65 161.7,36.97 160.73,37.95 160.73,46.68 164.47,50.43 164.47,51.69 166.64,53.87 166.64,70.66 166.54,70.76 166.54,70.95 162.39,75.1 162.39,75.79 161.98,76.19 161.98,83.72 163,84.74 163,88.54 163.28,88.82 163.28,110.11 160.81,112.57 160.81,114.13 154.81,120.14 143.89,120.14 141.89,122.13 141.89,126.38 140.57,127.7 140.57,137.72 136.55,141.74 131.05,141.74 129.96,142.84 129.75,142.84 v1(129.45,143.14)
  BOTTOM w0.14: HDA27.3 152.72,11.31 v1(152.61,11.42) ; v1(112.76,149.49) 112.85,149.49 113.84,150.48 123.17,150.48 128.99,144.66 v2(128.99,144.16) 128.99,143.6 v1(129.45,143.14) ; R2716.2 v1(103.49,142.38)
DMIC_DATA: length 4.2
  BOTTOM w0.14: R2714.1 100.95,141.55 EC5205.1 100.18,141.62 99.27,142.54 RN5204.4 98.24,141.73 v2(98.38,141.59)
DMIC_DATA_EDP: length 4.1
  TOP w0.14: LCD1.28 95.19,143.02 v1(95.23,143.06)
  BOTTOM w0.14: v2(96.88,141.55) 97.05,141.72 RN5204.1 96.48,142.54 96.35,142.66 95.63,142.66 v1(95.23,143.06)
DMIC_DATA_R: length 203.8
  L3 w0.127: v1(103.49,141.74) 103.51,141.77 105.68,141.77 106.92,143.01 106.92,146.88 109.02,148.98 112.12,148.98 v1(112.25,148.85)
  L4 w0.127: v1(129.45,142.33) 129.75,142.33 130.84,141.23 136.34,141.23 140.06,137.51 140.06,127.49 141.38,126.17 141.38,121.92 143.68,119.63 154.6,119.63 160.31,113.92 160.31,112.36 160.61,112.06 162.77,109.9 162.77,89.03 162.49,88.75 162.49,84.95 161.48,83.93 161.48,75.98 161.88,75.58 161.88,74.89 166.03,70.74 166.03,70.55 166.14,70.45 166.14,54.08 163.96,51.9 163.96,50.64 160.22,46.89 160.22,37.74 161.2,36.76 161.2,35.86 157.26,31.92 157.26,30.9 156.45,30.08 155.56,30.08 152.95,27.48 152.95,24.84 152.98,24.81 152.98,24.18 152.08,23.28 152.08,21.13 151.49,20.54 151.49,11.67 v1(152.36,10.81)
  BOTTOM w0.14: HDA27.2 152.8,10.91 152.68,10.79 152.42,10.79 152.41,10.81 v1(152.36,10.81) ; R2714.2 102.66,141.49 EC2701.1 103.3,141.55 v1(103.49,141.74) ; v1(112.25,148.85) 112.95,148.85 114.05,149.96 122.95,149.96 v2(127.24,145.67) 128.47,144.44 128.47,143.38 129.22,142.63 129.22,142.56 v1(129.45,142.33)
DP_2K_ZVSS: length 7.3
  BOTTOM w0.203: CPU1.A21 104.38,85.48 v2(104.25,85.61) 103.39,85.61 102.2,86.8 101.71,86.8 101,87.51 101,87.88 R402.1
DP_150_ZVSS: length 11.2
  TOP w0.203: R401.1 99.26,92.17 101.99,89.44 106.92,89.44 v2(107.38,88.98) v1(108.14,88.23)
  BOTTOM w0.203: CPU1.B16 108.13,88.23 v1(108.14,88.23)
E51_RX1: length 2.3
  TOP w0.102: TP5802.1 v1(169.27,51.95)
  BOTTOM w0.102: v1(169.27,51.95) 169.46,51.77 WLAN1.46
E51_RX2: length 5.2
  TOP w0.102: TP5803.1 169.26,48.78 v1(169.27,48.77)
  BOTTOM w0.102: WLAN1.58 v1(169.27,48.77)
E51_TX1: length 3.5
  TOP w0.102: R5806.2 168.72,53.54 v2(168.86,53.39) 169.16,53.1 v1(169.34,53.1)
  BOTTOM w0.102: v1(169.34,53.1) 170.17,52.27 WLAN1.44
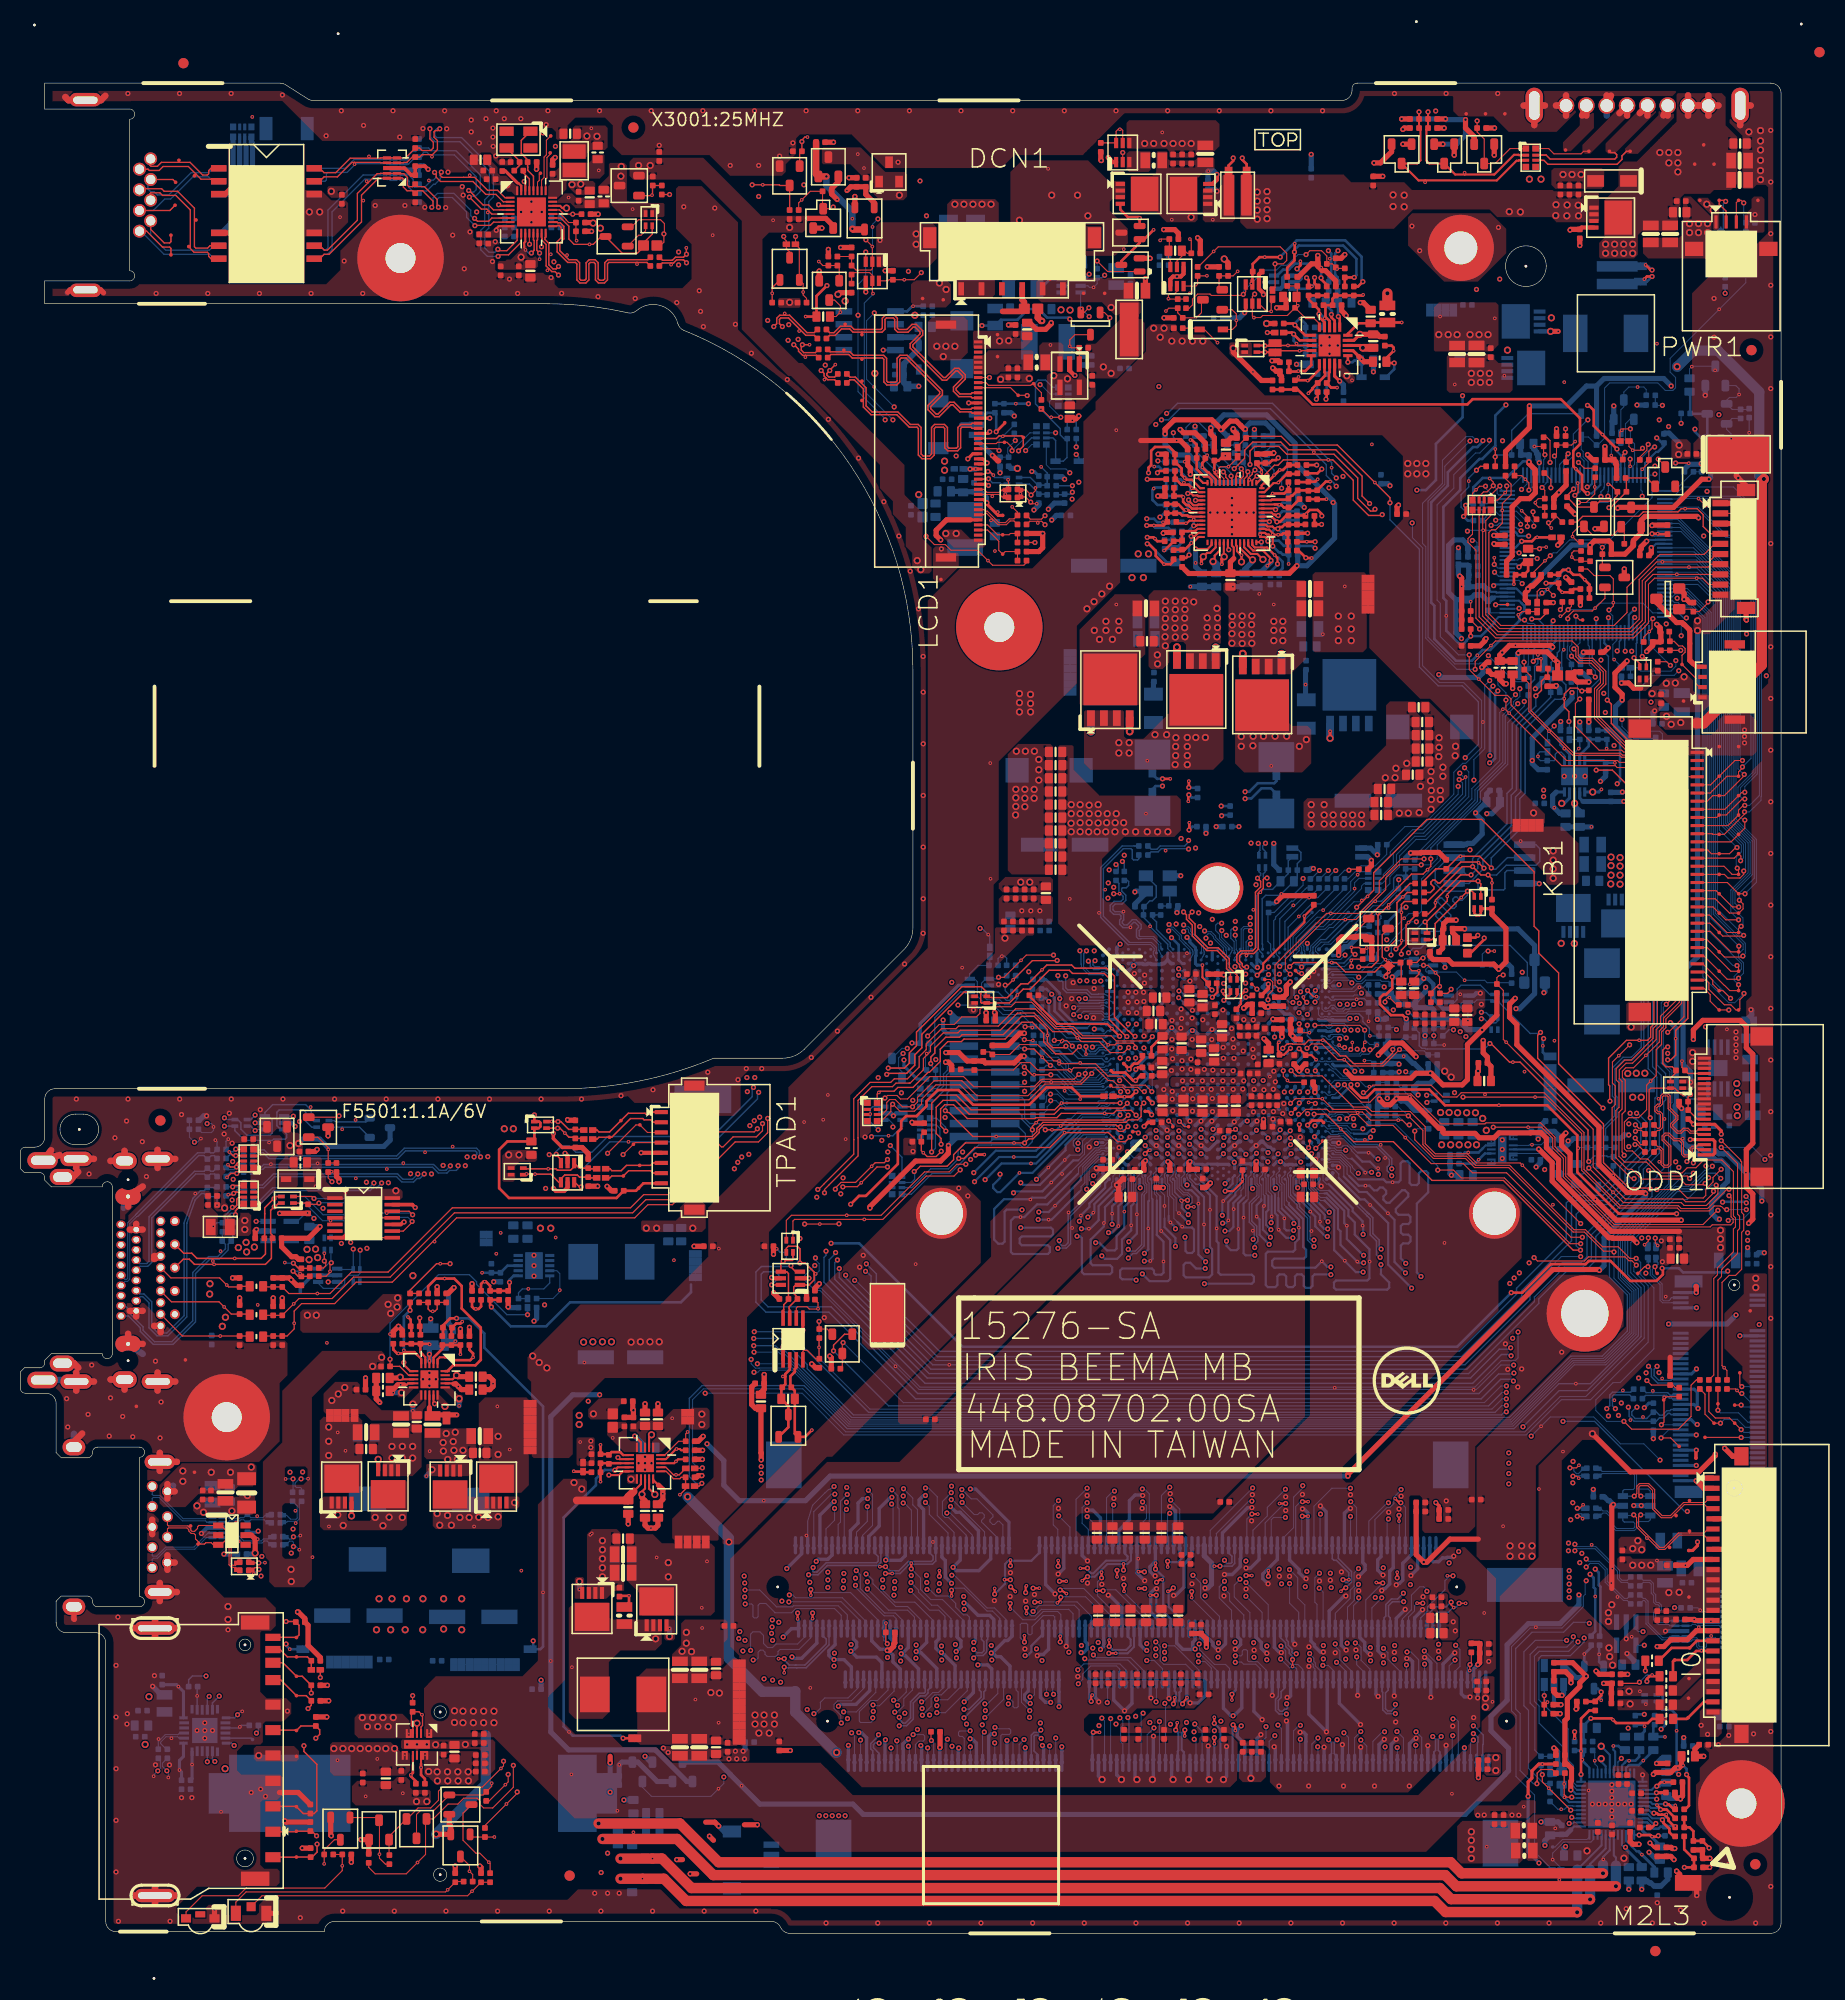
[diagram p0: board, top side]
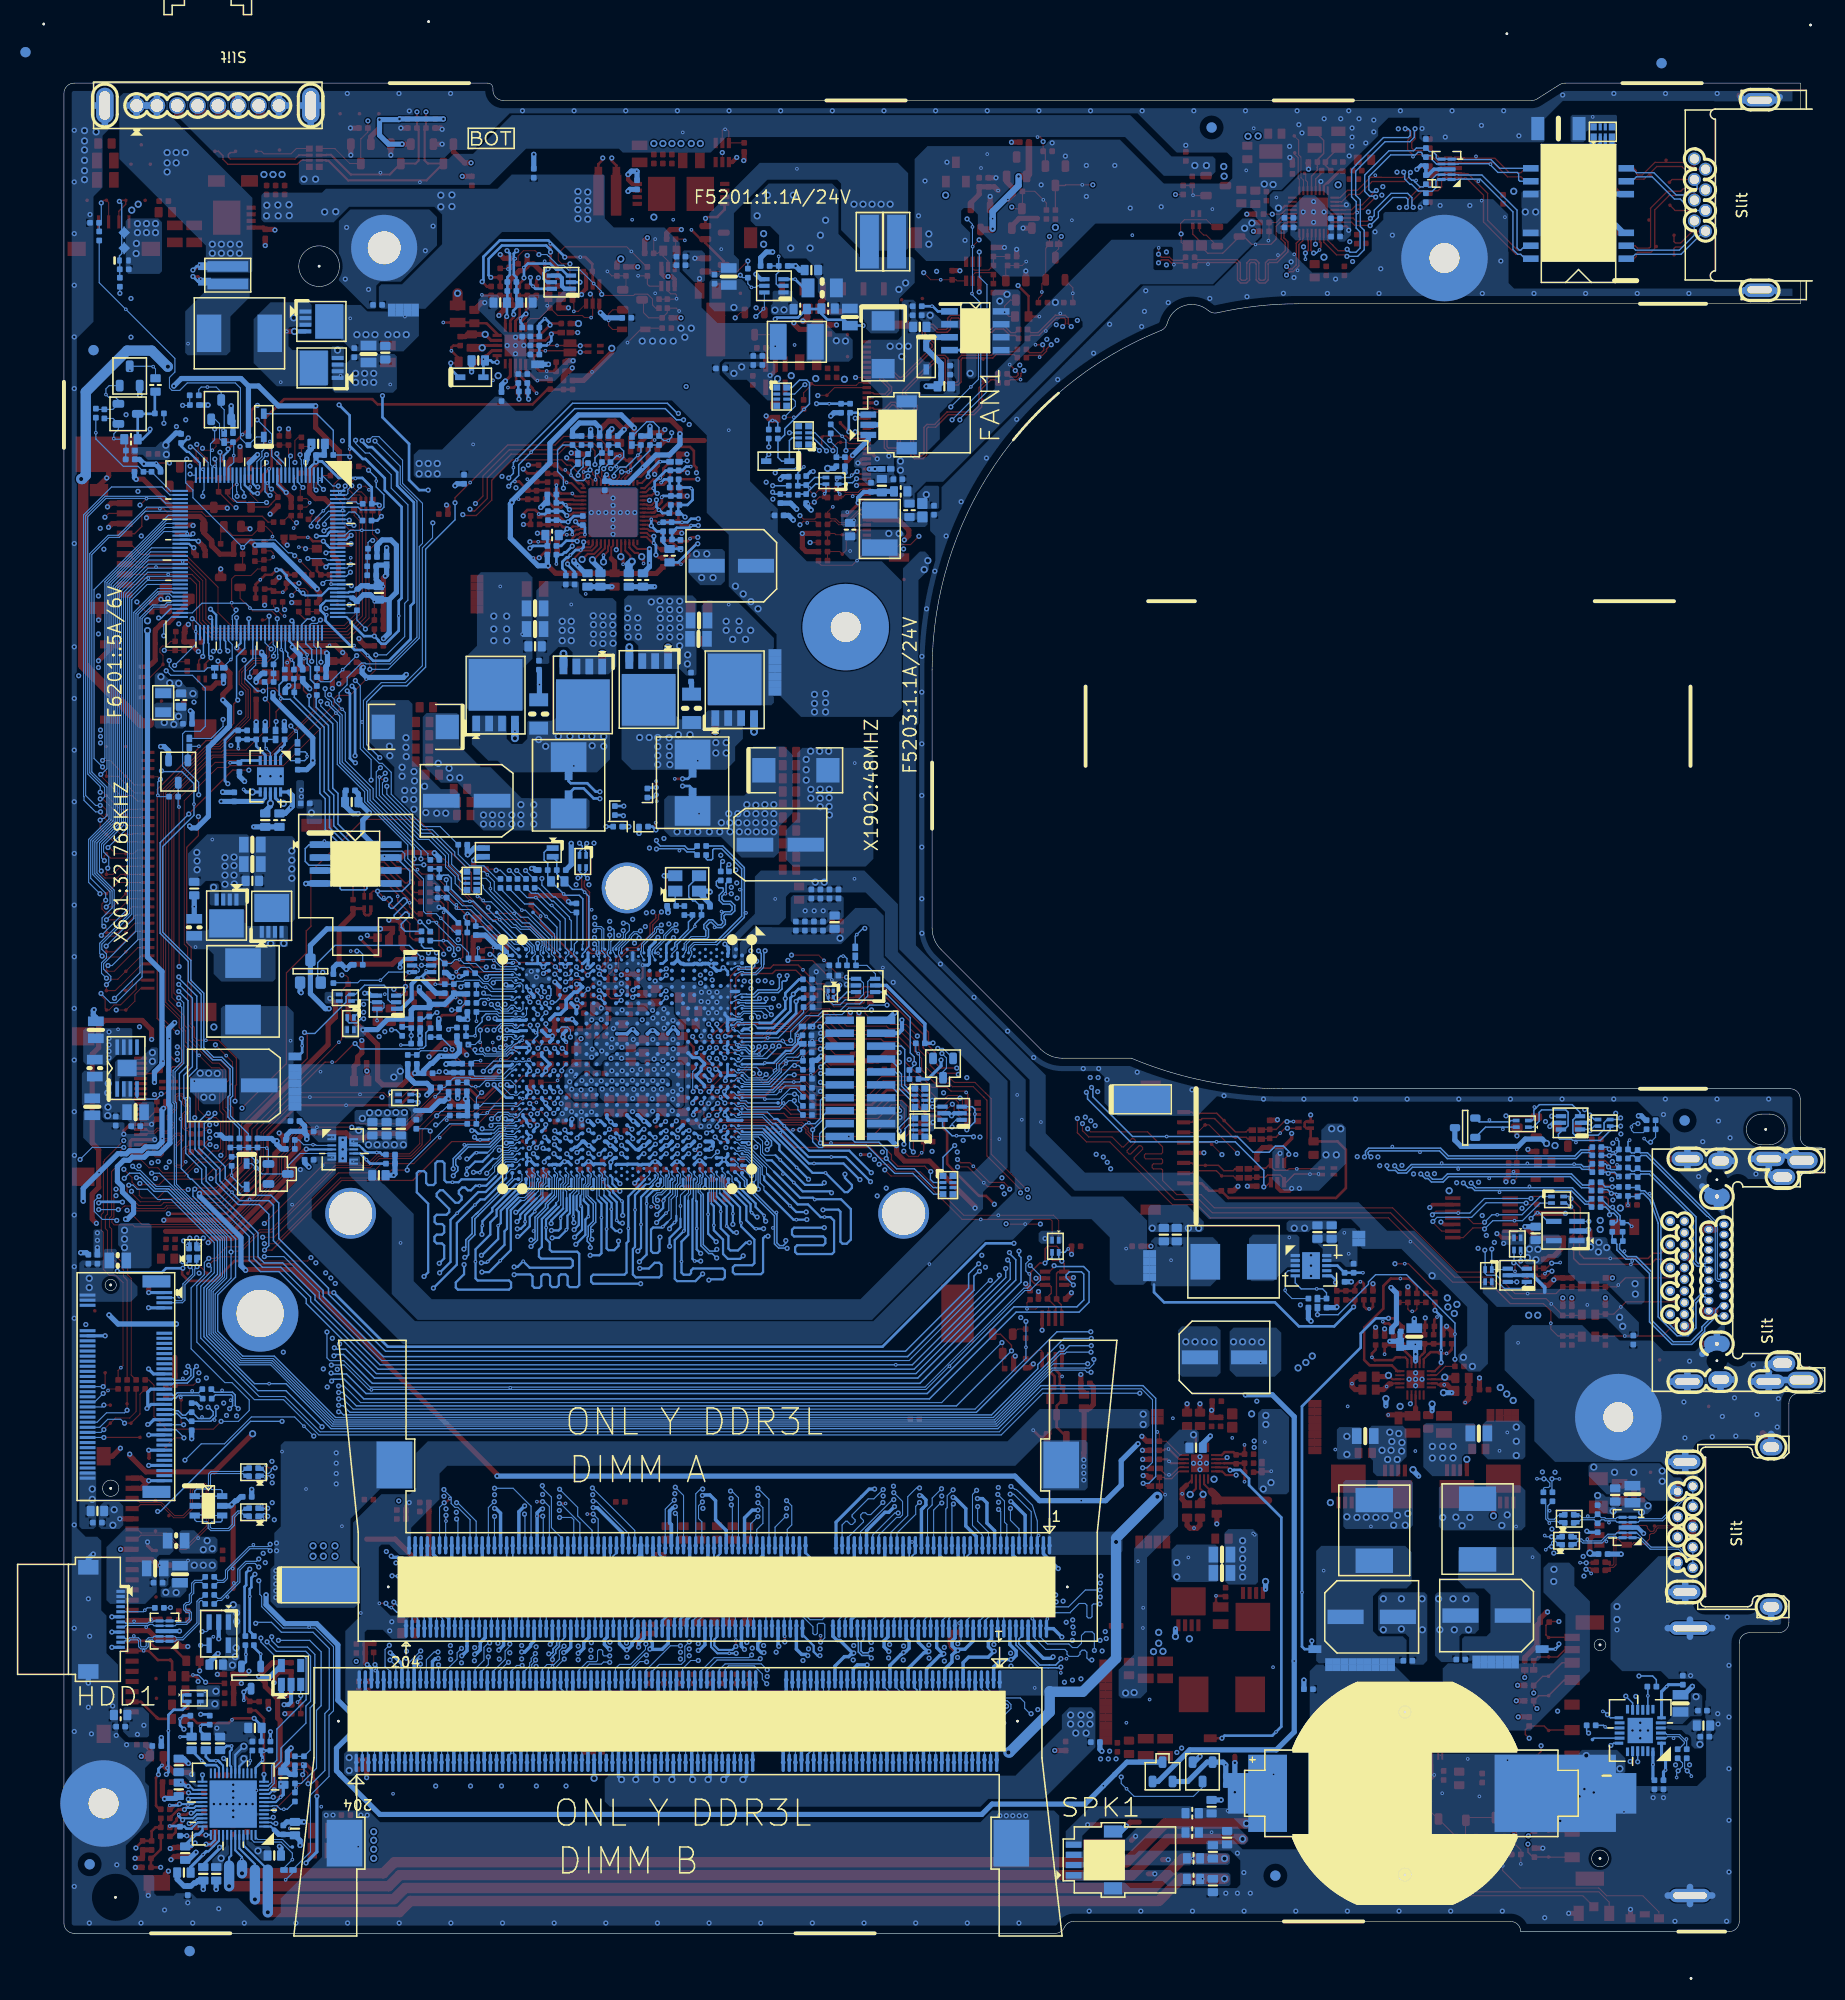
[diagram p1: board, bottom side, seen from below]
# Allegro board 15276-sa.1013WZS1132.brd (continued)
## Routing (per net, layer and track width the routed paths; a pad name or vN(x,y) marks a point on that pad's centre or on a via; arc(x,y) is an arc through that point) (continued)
E51_TX2: length 3
  TOP w0.102: v1(169.34,53.77) 169.15,53.96 TP5804.1
  BOTTOM w0.102: v1(169.34,53.77) WLAN1.38
E51_TXD: length 107.4
  TOP w0.102: R5806.1 167.88,55.36 v2(167.6,55.63) 167.39,55.84 167.39,64.02 168.08,64.7 168.1,64.71 168.72,64.71 169.32,65.31 169.32,68.95 169.53,69.15 169.53,70.7 169.32,70.9 169.32,75.87 169.22,75.97 169.22,76.06 v1(167.32,77.96)
  L3 w0.102: v1(167.32,77.96) 167.52,77.96 168.08,78.52 168.08,89.48 166.85,90.71 166.85,109.5 158.43,117.92 151.06,117.92 149.03,119.95 146.44,119.95 141.03,125.36 141.03,127.65 144.79,131.41 145.5,131.41 149.21,135.11 v1(149.21,135.22)
  BOTTOM w0.102: KBC24.111 147.31,135.07 147.45,135.22 v1(149.21,135.22)
EAPD#: length 7
  BOTTOM w0.102: HDA27.47 154.75,9.23 154.49,8.98 151.82,8.98 150.73,7.89 v2(150.73,7.25) 151.56,6.42 R2708.2
EC_AGND: length 13.9
  TOP w0.508: v1(141.59,133.49) 141.78,133.3 v2(141.78,132.47) R2406.2 C2402.1 C2414.1
  BOTTOM w0.203: 144.38,132.22 144.66,131.94 145.14,131.94 145.21,131.87 KBC24.103
  BOTTOM w0.508: v1(141.59,133.49) 141.46,133.61 R2435.1 142.37,134.57 C2403.1 R2407.2 142.48,133.13 142.22,132.88 C2405.2 142.27,132.45 143.28,132.45 C2404.2 143.94,132.54 144.25,132.22 144.38,132.22
EC_BRIGHTNESS: length 88.9
  TOP w0.14: v1(162.82,144.61) 164.09,144.61 v2(164.12,144.59)
  L3 w0.127: v1(103.87,145.45) 103.42,145.9 103.42,146.5 106.86,149.93 113.21,149.93 114.54,148.61 114.54,147.58 115.67,146.45 123.15,146.45 124.71,144.89 131.33,144.89 133.22,143 141.14,143 141.36,143.23 145.44,143.23 148.18,145.97 154.49,145.97 156.32,144.15 158.71,144.15 160,145.44 162,145.44 v1(162.82,144.61)
  L4 w0.127: v1(162.82,144.61) 162.76,144.55 162.76,133.27 164.1,131.93 164.1,130.38 163.89,130.16 v1(163.89,129.37)
  BOTTOM w0.14: v1(103.87,145.45) 103.87,145.43 104.12,145.17 D5202.A ; KBC24.62 162.71,130.27 163.61,129.37 v1(163.89,129.37)
EC_SCI#: length 83.1
  TOP w0.102: v1(137.8,105.09) 135.62,105.09 134.31,103.78 134.31,102.65 131.37,99.71 v2(130.33,99.71) 128.33,99.71 124.44,95.81 124.44,94.82 v1(124.92,94.34) ; v1(160.13,146.44) 160,146.31 160,145.88 159.3,145.18 R2408.1
  L3 w0.102: v1(147.94,121.16) 148,121.16 148.6,120.56 159.16,120.56 159.7,121.09 v1(160.41,121.09)
  L4 w0.102: v1(160.13,146.44) 160.13,140.83 159.32,140.01 159.32,129.3 161.63,126.99 161.63,123.98 161.13,123.48 161.13,121.74 160.48,121.09 v1(160.41,121.09)
  BOTTOM w0.102: v1(137.8,105.09) 138.77,105.09 139.38,105.7 139.38,107.05 143.62,111.29 143.62,112.28 146.31,114.97 146.31,119.09 147.94,120.71 v1(147.94,121.16) ; v1(124.92,94.34) 124.85,94.34 CPU1.AN5
EC_SMI#: length 71.1
  TOP w0.102: v1(138.08,105.67) 135.85,105.67 133.67,103.5 133.67,102.33 131.66,100.32 v2(128.91,100.32) 128.49,100.32 123.42,95.25 123.42,93.26 v1(123.89,92.79) ; R2409.1 150.16,147.14 150.48,146.82 v1(150.48,144.66)
  L4 w0.102: v1(147.51,122.41) 148.18,122.41 150.27,124.51 150.27,131.79 150.52,132.03 150.52,134.11 149.89,134.73 149.89,141.22 150.12,141.45 150.12,142.67 150.48,143.03 v1(150.48,144.66)
  BOTTOM w0.102: v1(138.08,105.67) 138.08,106.44 143.09,111.44 143.09,112.46 145.83,115.2 145.83,119.81 146.87,120.85 146.87,121.12 147.12,121.37 147.23,121.37 147.51,121.65 v1(147.51,122.41) ; CPU1.AL7 123.6,93.08 v1(123.89,92.79)
EC_SPI_CLK_C: length 5
  TOP w0.14: v1(148.83,125.11) 149.08,125.36 v2(149.59,125.36) 149.59,124.61 R2420.2
  BOTTOM w0.14: KBC24.92 149.42,126.85 148.83,126.26 v1(148.83,125.11)
EC_SPI_CS#_C: length 6
  BOTTOM w0.14: R2419.1 148.95,123.32 148.95,124.6 149.28,124.92 v2(149.28,125.74) 149.28,125.81 150.22,126.75 KBC24.90
EC_SPI_DI_C: length 4
  BOTTOM w0.14: R2422.1 150.58,125 v2(150.83,125.25) 151.18,125.6 151.18,125.94 151.42,126.17 KBC24.87
EC_SPI_DO_C: length 3.8
  BOTTOM w0.14: R2423.1 151.62,124.44 151.62,125.99 151.82,126.2 v2(151.82,126.25) 151.82,126.3 151.82,126.31 KBC24.86
EC_SWI#: length 75.4
  TOP w0.102: R2410.1 148.8,139.42 v1(148.8,139.81) ; v1(144.38,96.61) v2(144.99,96.61)
  L3 w0.102: v1(148.8,139.81) 148.42,140.19 144.02,140.19 138.59,134.76 138.59,123.76 138.59,123.37 146.57,115.4 146.57,98.79 v1(144.38,96.61) 144.03,96.25 140.25,96.25 138.52,94.52 136,94.52 136,94.52 133.97,94.52 v1(131.92,92.48)
  BOTTOM w0.102: CPU1.BA9 129.2,92.19 131.13,92.19 131.23,92.29 131.74,92.29 v1(131.92,92.48) ; v1(144.38,96.61) 144.11,96.61 143.81,96.3 R608.1
EC_VBKUP: length 4.8
  TOP w0.254: v1(147.68,136.92) 148.7,136.92 149.08,137.3 v2(149.21,137.3) R2428.1
  BOTTOM w0.203: v1(147.68,136.92) 147.26,136.5 147.26,136.47 147.13,136.34 147.1,136.34 147.03,136.27 KBC24.114
ECRST#: length 12.1
  TOP w0.102: Q2404.E 155.87,131.31 v2(154.91,130.34) 154.63,130.06 152.76,130.06 152.22,129.51 v1(152.22,129.3)
  BOTTOM w0.102: v1(152.22,129.3) KBC24.85 152.22,126.63 152.18,126.59 152.18,125.82 152.15,125.79 152.15,125.43 152.58,125.01 C2418.1 R2418.1 152.57,123.91 R2424.2
ECSCI#_KBC: length 6.4
  TOP w0.102: v2(159.54,143.99) 160.19,144.65 R2408.2 160.19,145.74 160.64,146.19 v1(160.76,146.19)
  BOTTOM w0.102: KBC24.29 159.02,144.67 160.54,146.19 v1(160.76,146.19)
ECSMI#_KBC: length 3.9
  TOP w0.102: v2(148.93,146.24) 149.83,146.24 R2409.2 149.84,145.55 v1(149.97,145.43)
  BOTTOM w0.102: v1(149.97,145.43) 149.97,145.04 149.85,144.93 149.85,144.46 149.82,144.43 KBC24.6
ECSWI#_KBC: length 4.6
  TOP w0.102: v2(147.68,139.91) 148.25,139.34 R2410.2 148.25,138.37 v1(148.24,138.36)
  BOTTOM w0.102: KBC24.123 147.17,139.87 148.24,138.8 v1(148.24,138.36)
EDP_AUX: length 26.2
  TOP w0.14: C5212.2 79.61,157.43 80.03,157.43 80.67,158.06 81.13,158.06 ; LCD1.11 93.63,151.52 93.51,151.4 92.43,151.4 92.06,151.77 92.06,151.97 92.96,152.87 92.96,153.29 92.32,153.92 91.91,153.92 91.01,153.02 90.81,153.02 87.8,156.03 87.8,156.23 88.76,157.19 88.76,157.61 88.13,158.24 87.71,158.24 87.21,157.74 86.41,157.74 86.27,157.88 86.27,158.85 85.98,159.14 85.08,159.14 84.79,158.85 84.79,157.88 84.65,157.74 82.02,157.74 81.7,158.06 81.13,158.06 ; AFTP5206.1 81.13,158.06
EDP_AUX#: length 26.3
  TOP w0.14: LCD1.12 93.63,151.02 93.51,151.14 92.32,151.14 91.79,151.66 91.79,152.08 92.69,152.98 92.69,153.18 92.21,153.66 92.02,153.66 91.12,152.75 90.7,152.75 87.53,155.92 87.53,156.34 88.49,157.3 88.49,157.5 88.02,157.98 87.82,157.98 87.32,157.48 86.3,157.48 86.01,157.77 86.01,158.74 85.87,158.88 85.19,158.88 85.05,158.74 85.05,157.77 84.76,157.48 82.79,157.48 ; AFTP5208.1 82.79,157.48 ; 82.79,157.48 81.91,157.48 81.59,157.8 80.78,157.8 80.14,157.16 79.6,157.16 C5209.2
EDP_AUX_DN: length 98.7
  TOP w0.14: v1(74.96,158.03) 74.67,158.32 74.67,158.74 74.81,158.88 75.56,158.88 76.73,157.71 ; v2(76.61,157.59) 76.73,157.71 ; 76.73,157.71 77.27,157.17 78.09,157.17 C5209.1
  L4 w0.127: v1(109.78,89.43) 109.13,90.08 108.8,90.08 108.52,90.36 108.52,94.04 107.53,95.03 107.53,96.76 102.83,101.46 97.16,101.46 91.41,107.22 91.41,133.68 93.17,135.44 93.17,139.84 89.62,143.39 89.62,149.46 83.93,155.15 81.03,155.15 78.7,157.48 74.8,157.48 74.67,157.61 74.67,157.74 v1(74.96,158.03)
  BOTTOM w0.127: v1(109.78,89.43) 109.4,89.04 CPU1.E15
EDP_AUX_DP: length 98.7
  TOP w0.14: 75.19,159.14 75.67,159.14 77.38,157.43 78.09,157.43 C5212.1 ; 75.19,159.14 v2(75.19,159.32) ; 75.19,159.14 74.7,159.14 74.4,158.85 74.4,158.32 v1(74.11,158.03)
  L4 w0.127: v1(108.98,89.43) 108.98,89.52 108.25,90.25 108.25,93.93 107.26,94.92 107.26,96.65 102.72,101.19 97.05,101.19 91.14,107.11 91.14,133.79 92.91,135.55 92.91,139.73 89.35,143.28 89.35,149.35 83.82,154.89 80.92,154.89 78.59,157.22 74.69,157.22 74.4,157.5 74.4,157.74 v1(74.11,158.03)
  BOTTOM w0.127: v1(108.98,89.43) 108.98,89.17 CPU1.D15
EDP_BKLT_CTRL: length 2.4
  BOTTOM w0.14: R5222.2 102.98,148.58 103.2,148.8 v2(103.49,148.8) 103.67,148.8 103.87,148.6 R5206.2
EDP_HPD: length 98
  TOP w0.102: v1(111.35,88.2) 110.93,87.77 107.8,87.77 107.3,88.28 104.5,88.28 103.59,89.19 101.88,89.19 99.5,91.58 97.9,91.58 97.45,91.13 94.66,91.13 94.39,90.87 94.39,90.49 94.04,90.13 92.61,90.13 91.87,89.39 90.39,89.39 89.26,88.27 89.26,88.26 v1(89.25,88.25) ; v1(102.34,149.11) v2(101.4,149.11) 101.26,149.11 R5233.2
  L3 w0.102: v1(102.34,149.11) 101.25,148.02 101.25,144.59 99.27,142.61 98.66,142.61 90.91,134.86 90.91,94.5 89.25,92.84 v1(89.25,88.25)
  BOTTOM w0.102: CPU1.H17 111.35,88.04 v1(111.35,88.2) ; v1(102.34,149.11) 101.25,150.2 101.25,150.68 101.46,150.89 RN5203.6
EDP_HPD_CONN: length 7.5
  TOP w0.102: R5233.1 100.44,151.52 99.8,152.16 99.8,152.28 AFTP5201.1 99.57,152.41 99.53,152.37 99.46,152.32 99.39,152.25 95.25,152.25 94.98,152.52 LCD1.9
EDP_TX0: length 25.9
  TOP w0.14: 82.79,154.94 81.83,154.94 81.49,155.28 79.73,155.28 C5210.2 ; 82.79,154.94 AFTP5210.1 ; 82.79,154.94 84.81,154.94 84.94,154.8 84.94,152.58 85.24,152.28 86.21,152.28 86.51,152.58 86.51,154.8 86.65,154.94 87.12,154.94 90.43,151.62 90.43,151.43 89.28,150.27 89.28,149.85 89.97,149.17 90.39,149.17 91.54,150.32 91.74,150.32 92.42,149.64 93.51,149.64 93.63,149.52 LCD1.15
EDP_TX0#: length 25.9
  TOP w0.14: C5203.2 79.66,155.55 81.01,155.55 ; 81.01,155.55 81.6,155.55 81.94,155.2 84.92,155.2 85.21,154.91 85.21,152.69 85.35,152.55 86.1,152.55 86.24,152.69 86.24,154.91 86.54,155.2 87.23,155.2 90.7,151.73 90.7,151.32 89.55,150.16 89.55,149.96 90.08,149.43 90.27,149.43 91.43,150.59 91.85,150.59 92.53,149.9 93.51,149.9 93.63,150.02 LCD1.14 ; 81.01,155.55 AFTP5213.1
EDP_TX0_DN: length 81.6
  TOP w0.14: v2(77.63,156.24) v1(76.93,156.24) 76.82,156.13 76.82,155.71 77.06,155.47 78.21,155.47 C5203.1
  L4 w0.127: v1(76.93,156.24) 76.66,155.98 76.66,154.85 86.18,145.33 86.18,141.09 88.41,138.86 88.41,136.39 89.81,135 89.81,106.55 98.14,98.22 101.98,98.22 102.98,97.22 103.78,96.42 104.05,96.15 105.23,96.15 v1(105.72,95.66)
  BOTTOM w0.102: CPU1.B4 106.97,95.13 106.72,95.13 106.62,95.03 106.16,95.03 106.13,95.06 106.1,95.06
  BOTTOM w0.14: v1(105.72,95.66) 105.52,95.47 105.52,95.24 105.69,95.06 106.1,95.06
EDP_TX0_DP: length 81
  TOP w0.14: C5210.1 78.31,155.2 77.22,155.2 ; v1(76.08,156.24) 76.11,156.24 76.55,155.81 76.55,155.6 76.95,155.2 77.22,155.2 ; v2(77.22,155.03) 77.22,155.2
  L4 w0.127: v1(105.06,95.62) 105.06,95.77 104.95,95.88 103.94,95.88 103.19,96.63 102.79,97.03 101.87,97.95 98.03,97.95 89.54,106.44 89.54,134.89 88.15,136.28 88.15,138.75 85.91,140.98 85.91,145.22 76.4,154.74 76.4,155.93 v1(76.08,156.24)
  BOTTOM w0.102: CPU1.A4 106.16,94.83 106.13,94.8 106.1,94.8
  BOTTOM w0.14: v1(105.06,95.62) 105.25,95.43 105.25,95.13 105.58,94.8 106.1,94.8
EDP_TX1: length 26
  TOP w0.14: 82.93,150.76 82.93,151.89 82.03,152.79 81.6,152.79 C5213.2 ; 82.93,150.76 82.93,150.12 83.68,149.36 86.21,149.36 87.44,148.14 88.2,148.14 88.34,148 88.34,145.39 88.7,145.03 89.54,145.03 89.9,145.39 89.9,148 90.04,148.14 90.79,148.14 90.93,148 90.93,146.1 91.23,145.81 92.2,145.81 92.49,146.1 92.49,148 92.63,148.14 93.51,148.14 93.63,148.02 LCD1.18 ; 82.93,150.76 AFTP5212.1
EDP_TX1#: length 26
  TOP w0.14: LCD1.17 93.63,148.52 93.51,148.4 92.52,148.4 92.23,148.11 92.23,146.21 92.09,146.07 91.34,146.07 91.2,146.21 91.2,148.11 90.9,148.4 89.93,148.4 89.64,148.11 89.64,145.5 89.43,145.3 88.81,145.3 88.61,145.5 88.61,148.11 88.31,148.4 87.55,148.4 86.33,149.63 83.79,149.63 83.19,150.23 83.19,152 82.66,152.54 ; AFTP5211.1 82.66,152.54 ; 82.66,152.54 82.14,153.06 81.62,153.06 C5211.2
EDP_TX1_DN: length 78
  TOP w0.14: C5211.1 80.1,153.06 79.54,153.06 79.33,153.27 79.33,153.41 v1(79.62,153.7) 79.62,153.74 v2(80.17,154.29)
  L4 w0.127: v1(79.62,153.7) 79.42,153.5 79.42,153.23 87,145.65 87,141.44 89.81,138.63 89.81,136.24 90.61,135.45 90.61,106.89 98.23,99.26 103.27,99.26 104.7,97.83 104.7,96.81 v1(104.88,96.63)
  BOTTOM w0.102: CPU1.B5 106.62,94.58 106.37,94.58 106.27,94.48 105.19,94.48 104.58,95.09 104.58,95.31 104.6,95.33
  BOTTOM w0.14: v1(104.88,96.63) 104.6,96.36 104.6,95.33
EDP_TX1_DP: length 77.4
  TOP w0.14: v2(79.1,152.82) 79.26,152.97 ; 79.26,152.97 79.43,152.8 80.1,152.8 C5213.1 ; 79.26,152.97 79.06,153.16 79.06,153.41 v1(78.78,153.7)
  L4 w0.127: v1(104.22,96.64) 104.43,96.85 104.43,97.72 103.16,98.99 98.12,98.99 90.34,106.77 90.34,135.34 89.54,136.13 89.54,138.52 86.74,141.33 86.74,145.54 86.34,145.93 79.15,153.12 79.15,153.33 v1(78.78,153.7)
  BOTTOM w0.102: CPU1.A5 105.1,94.28 104.38,95.01 104.38,95.3 104.34,95.33
  BOTTOM w0.14: v1(104.22,96.64) 104.23,96.63 104.34,96.52 104.34,95.33
EDP_VDD_EN: length 122.2
  TOP w0.102: D5201.1 106.64,159.42 v1(107.17,158.89)
  L3 w0.102: v1(85.96,150.12) 86.9,149.19 86.9,141.32 89.97,138.24 89.97,135.89 90.48,135.38 90.48,94.72 87.25,91.48 v1(87.25,87.04) ; v1(107.17,158.89) 106.88,158.89 105.46,160.31 104.5,160.31 104.25,160.06 104.25,158.63 103.36,157.74 99.04,157.74 98.03,158.76 93.45,158.76 92.97,158.28 85.1,158.28 v1(84.01,159.37)
  L4 w0.102: v1(92.23,91.3) 91.43,91.3 88.78,88.65 88.78,88.03 87.79,87.04 v1(87.25,87.04)
  BOTTOM w0.102: R404.2 98.5,90.36 96.66,90.36 96.01,91.01 94.25,91.01 93.96,91.3 v1(92.23,91.3) ; v1(85.96,150.12) v2(83.99,152.1) 83.24,152.84 83.24,158.61 v1(84.01,159.37) ; v1(87.25,87.04) 86.72,87.04 D401.1
FAN1_DAC_1: length 101.4
  L3 w0.254: v1(143.87,146.81) 143.74,146.94 143.74,147.02 143.26,147.51 130.83,147.51 130.55,147.23 125.92,147.23 123.37,149.79 121.55,149.79 117.56,153.78 109.35,153.78 107.91,155.23 93.81,155.23 92.34,156.7 88.35,156.7 87.36,155.71 v1(84.88,155.71)
  BOTTOM w0.203: 147.68,130.82 147.44,131.07 KBC24.101
  BOTTOM w0.254: v1(143.87,146.81) 143.87,146.73 143.32,146.18 142.89,146.18 140.42,143.7 140.42,142.38 138.78,140.74 138.78,130.88 139.1,130.57 139.1,127.29 141.23,125.16 142.78,125.16 v2(143.32,125.69) 143.85,126.22 144.59,126.22 147.46,129.09 147.46,129.62 147.96,130.13 147.96,130.54 147.68,130.82 ; FAN261.4 v1(84.88,155.71)
FAN_TACH1: length 76.4
  L3 w0.254: v1(160.97,147.08) 156.25,147.08 156.23,147.09 146.81,147.09 145.95,146.23 125.28,146.23 122.99,148.52 119.4,148.52 115.1,152.82 106.13,152.82 104.99,153.95 101.4,153.95 101,153.56 101,152.96 101.18,152.79 101.18,151.96 100.61,151.39 99.96,151.39 99.17,150.61 v1(99.17,150.44)
  BOTTOM w0.203: 161.09,145.71 160.92,145.71 159.82,144.61 KBC24.31
  BOTTOM w0.254: 161.09,145.71 161.68,146.29 R2415.1 161.49,146.58 160.99,147.08 v1(160.97,147.08) ; v1(99.17,150.44) v2(97.92,150.44) EC2602.1 R2606.1
FAN_TACH1_C: length 5
  TOP w0.254: AFTP2802.1 96.83,148.52 v1(95.99,147.69)
  BOTTOM w0.254: FAN1.3 94.93,149.37 95.12,149.55 R2606.2 95.99,149.43 v1(95.99,147.69)
FAN_VCC1: length 22.7
  TOP w0.508: v1(95.62,145.35) 96.16,144.82 AFTP2801.1
  L3 w0.508: v1(88.37,152.16) 89.39,152.16 91.93,149.62 91.93,149.05 v1(95.62,145.35)
  BOTTOM w0.508: v1(95.62,145.35) 94.07,146.9 FAN1.1
  BOTTOM w0.559: v1(88.37,152.16) C2604.1 86.91,152.5 C2603.1 EC2601.1 86.91,154.38 88.37,155.84 D2601.K 88.37,156.6 87.99,156.98 86.09,156.98
FON#: length 2.9
  BOTTOM w0.254: FAN261.1 87.23,159.52 87.74,160.03 v2(87.82,160.03) R2605.2
GEVENT4#: length 4.1
  TOP w0.102: v1(130.94,95.08) 130.92,95.11 v2(130.92,95.69) 131.05,95.82 R620.1
  BOTTOM w0.102: v1(130.94,95.08) 130.69,94.83 CPU1.BA4
GEVENT7#: length 2.5
  TOP w0.102: v1(125.8,89.46) 125.89,89.36 R621.1 126.12,88.58 v2(126.8,88.58)
  BOTTOM w0.102: CPU1.AR15 125.79,89.17 125.79,89.45 v1(125.8,89.46)
GPIO71: length 3.7
  TOP w0.102: R632.1 124.82,83.7 v2(124.64,83.89) 124.23,84.29 v1(124.23,84.84)
  BOTTOM w0.102: CPU1.AM21 124.23,85.04 v1(124.23,84.84)
H_A20GATE: length 142
  TOP w0.102: v1(125.74,80.56) 125.97,80.56 126.45,81.04 128.53,81.04 128.79,80.78 132.01,80.78 132.82,79.98 v2(135.54,79.98) 135.94,79.98 136.41,79.51 v1(136.63,79.51)
  L3 w0.102: v1(146.51,63.92) 147.84,63.92 151.54,67.63 151.54,68.94 158.54,75.93 160.92,75.93 162.14,77.15 164.39,77.15 165.4,78.16 165.4,79.63 166.07,80.3 166.07,87.77 165.03,88.81 165.03,108.77 157.66,116.14 150.6,116.14 148.14,118.6 145.88,118.6 139.68,124.8 139.68,132.8 143.78,136.9 143.78,138.19 144.57,138.98 v1(145.13,138.98)
  L4 w0.102: v1(136.63,79.51) 137.26,79.51 138.34,78.44 138.34,77.84 140.01,76.16 141.54,76.16 142.35,75.35 142.35,69.96 142.51,69.8 142.51,69.79 143.97,68.33 143.98,68.33 146.34,65.97 146.34,64.1 v1(146.51,63.92)
  BOTTOM w0.102: KBC24.121 145.26,139.07 145.18,138.98 v1(145.13,138.98) ; CPU1.AR31 125.74,80.33 v1(125.74,80.56) ; R603.1 135.48,80.43 136.41,79.51 v1(136.63,79.51)
H_CPUPWRGD_REG: length 75.1
  L3 w0.127: v1(94.42,98.84) 94.29,98.84 94.09,99.05 94.09,120.48 101.32,127.71 101.32,131.59 114.83,145.11 121.86,145.11 124.09,142.89 124.09,142.15 v1(124.07,142.13)
  BOTTOM w0.127: PR4607.1 122.64,145.85 PR4608.1 124.12,146.38 124.65,145.86 124.65,143.77 124.07,143.2 v1(124.07,142.13) ; R418.1 95.36,98.08 v2(95.21,98.23) 94.6,98.84 v1(94.42,98.84)
H_PROCHOT#: length 295.6
  TOP w0.102: RN405.5 84.69,79.88 85.63,80.83 85.63,81.34 85.81,81.52 v1(85.81,81.54) 85.83,81.54 86.52,80.86 87.95,80.86 88.65,81.56 88.65,82.04 90.07,83.45 92.45,83.45 93.92,81.98 99.22,81.98 100.77,83.53 104.35,83.53 v1(105.39,84.57) ; PR4426.2 123.43,161.87 v1(123.43,164.2) 124.24,164.2 124.57,164.52 124.57,165.24 123.93,165.87 117.84,165.87 v2(117.38,165.42) 115.87,163.9 PR4466.2 ; PQ4203.3 v1(83.16,165.36)
  L3 w0.102: v1(161.53,150.28) 159.6,150.28 158.79,149.46 154.13,149.46 153.78,149.11 145.48,149.11 144.87,149.72 129.92,149.72 129.64,149.44 126.84,149.44 124.28,152 122.47,152 120.2,154.26 120.2,156.12 119.21,157.11 119.21,161.05 121.04,162.88 122.11,162.88 v1(123.43,164.2) ; v1(85.81,81.54) 84.94,81.54 84.61,81.87 84.61,82.99 85.83,84.21 85.83,92.09 89.26,95.51 89.26,134.88 88.26,135.88 88.26,138.23 85.68,140.81 85.68,148.25 v1(85.07,148.85)
  L4 w0.102: v1(123.43,164.2) 123.43,165.36 126.07,168.01 126.07,172.31 125.42,172.96 119.32,172.96 117.57,174.71 108.26,174.71 106.78,176.19 84.66,176.19 83.93,175.46 83.93,166.13 83.29,165.49 83.29,165.49 v1(83.16,165.36) ; v1(82.4,159.14) 82.81,159.14 84.08,160.41 89.08,160.41 89.82,159.68 92.18,159.68 94.49,157.36 98.7,157.36 99.42,156.64 106.13,156.64 110.12,152.66 110.12,146.52 111.82,144.82 v1(111.89,144.82)
  BOTTOM w0.102: v1(161.53,150.28) 160.84,150.28 C2421.1 160.83,150.33 R2440.2 ; v1(85.07,148.85) 85.07,148.96 82.4,151.62 v1(82.4,159.14) 82.4,162.16 83.16,162.92 v1(83.16,165.36) ; v1(111.89,144.82) 111.97,144.74 PR4613.2 ; v1(105.39,84.57) 105.39,84.69 105.63,84.93 CPU1.A22
H_PROCHOT#_EC: length 7.2
  BOTTOM w0.102: R2440.1 159.94,151.84 159.7,152.08 v2(159.09,152.08) 158.22,152.08 157.73,151.59 Q2401.D 157.73,150.14 157.44,149.85 R2438.2
H_RCIN#: length 138
  TOP w0.102: v1(125,84.85) 125.51,84.34 128.05,84.34 131.12,81.27 132.52,81.27 132.95,80.83 136.71,80.83 138.2,79.35 138.2,77.67 139.19,76.67 142.34,76.67 143.24,75.77 147.53,75.77 v2(147.75,75.55) v1(153.49,69.81)
  L3 w0.102: v1(153.49,69.81) 153.49,70.55 158.64,75.7 161.01,75.7 162.23,76.92 164.49,76.92 165.63,78.06 165.63,79.4 166.3,80.07 166.3,87.86 165.26,88.9 165.26,108.86 157.75,116.37 150.76,116.37 148.29,118.83 145.97,118.83 139.91,124.9 139.91,131.01 146.03,137.12 146.03,137.96 146.64,138.57 147.58,138.57 v1(147.58,138.57)
  BOTTOM w0.102: CPU1.AR23 125.4,84.45 v1(125,84.85) ; R2412.1 144.18,139.29 144.18,139.38 144.58,139.79 145.17,139.79 145.49,139.47 KBC24.122 146.95,139.47 147.58,138.84 147.58,138.57 v1(147.58,138.57)
HDA_CODEC_BITCLK: length 130.9
  TOP w0.114: R651.1 130.79,104.66 v1(130.69,104.56)
  L4 w0.102: v1(130.69,104.56) 130.69,104.74 132.65,106.69 137.62,106.69 138.21,107.28 144.53,107.28 146.21,105.6 146.21,100.62 147.73,99.1 147.73,96.67 149.37,95.03 149.37,89.53 150.27,88.63 150.27,87.82 155.66,82.43 155.66,81.9 156.53,81.02 156.53,73.88 158.76,71.65 161.25,71.65 163.82,69.08 163.82,64.5 162.8,63.47 162.8,54.01 155.46,46.67 155.46,43.55 154.85,42.94 154.85,41.41 155.43,40.82 155.43,34.71 152.1,31.38 v1(152.1,28.81)
  BOTTOM w0.114: R2720.1 EC2709.1 149.85,14.74 148.36,16.23 148.36,21.93 147.9,22.39 147.9,27.69 149.02,28.81 v1(152.1,28.81) ; v1(130.69,104.56) 130.27,104.56 R616.2
HDA_CODEC_BITCLK_R: length 9.3
  BOTTOM w0.114: CPU1.AN2 124.4,96.34 124.7,96.65 124.7,98.95 v2(125.76,100.01) 126.99,101.24 127.89,101.24 129.2,102.56 129.2,102.6 R616.1
HDA_CODEC_RST#: length 134.6
  L4 w0.102: v1(153.83,29.04) 153.83,31.09 156.86,34.12 156.86,41.41 156.27,42 156.27,42.35 156.97,43.05 156.97,46.17 165.31,54.52 165.31,69.6 164.87,70.05 164.87,70.59 161.41,74.05 159.96,74.05 159.33,74.68 159.33,77.09 159.42,77.18 159.42,80.83 158.99,81.27 158.82,81.27 157.96,82.12 157.96,82.15 151.7,88.41 151.7,89.22 151.12,89.8 151.12,95.3 150.75,95.66 149.16,97.26 149.16,99.69 147.63,101.21 147.63,106.19 145.12,108.7 137.62,108.7 137.04,108.11 132.06,108.11 129.62,105.67 128.94,105.67 v1(127.79,104.53)
  BOTTOM w0.114: v1(127.79,104.53) 126.97,103.7 R614.1 ; v1(153.83,29.04) 153.83,28.66 152.49,27.32 149.63,27.32 149.38,27.07 149.38,22.97 152.25,20.09 152.25,17.03 152.76,16.52 152.76,14.84 153.1,14.51 HDA27.11
HDA_CODEC_RST#_R: length 7.9
  BOTTOM w0.114: R614.2 126.51,102.81 126.4,102.7 126.39,102.7 125.21,101.52 125.04,101.52 123.47,99.95 123.47,99.77 123.3,99.6 CPU1.AL1
HDA_CODEC_SDIN0: length 3.9
  TOP w0.114: R2718.2 151.86,15.68 v2(151.86,14.69) 151.86,13.66 152.13,13.39 v1(152.61,13.39)
  BOTTOM w0.114: v1(152.61,13.39) 152.63,13.37 152.71,13.37 152.77,13.31 HDA27.8
HDA_CODEC_SDOUT: length 128.2
  L4 w0.102: v1(129.39,104.53) 129.73,104.86 129.96,104.86 132.39,107.3 137.37,107.3 137.96,107.88 144.79,107.88 146.82,105.85 146.82,100.87 148.34,99.35 148.34,96.92 149.98,95.29 150.3,94.97 150.3,89.47 150.88,88.88 150.88,88.07 157.14,81.81 157.14,74.64 159.48,72.3 162.01,72.3 164.05,70.26 164.05,69.71 164.43,69.33 164.43,64.25 163.41,63.22 163.41,53.76 156.15,46.51 156.15,43.39 155.46,42.69 155.46,41.66 156.04,41.07 156.04,34.45 152.76,31.17 v1(152.76,29.17)
  BOTTOM w0.114: EC2708.1 R2719.1 148.98,18.02 148.98,22.19 148.52,22.64 148.52,27.43 149.24,28.15 152.13,28.15 152.76,28.79 v1(152.76,29.17) ; v1(129.39,104.53) 129.32,104.53 128.58,103.8 R612.1
HDA_CODEC_SDOUT_R: length 8.3
  BOTTOM w0.114: R612.2 127.63,101.86 v2(126.78,101.86) 126.74,101.86 124.4,99.52 CPU1.AN1
HDA_CODEC_SYNC: length 133.9
  L4 w0.102: v1(128.66,104.53) 129.39,105.27 129.79,105.27 132.23,107.71 137.2,107.71 137.79,108.29 144.95,108.29 147.23,106.02 147.23,101.04 148.75,99.52 148.75,97.09 150.71,95.14 150.71,89.64 151.29,89.05 151.29,88.24 157.55,81.98 157.55,77.44 158.2,76.79 158.2,74.16 158.71,73.65 161.24,73.65 164.46,70.42 164.46,69.88 164.84,69.5 164.84,64.08 163.86,63.1 163.86,53.64 156.56,46.34 156.56,43.22 155.86,42.52 155.86,41.83 156.45,41.24 156.45,34.29 153.4,31.23 153.4,28.85 v1(153.22,28.67)
  BOTTOM w0.114: HDA27.10 153.11,14.11 152.88,14.34 152.88,14.37 152.5,14.75 152.5,16.27 151.84,16.94 151.84,18.24 149.4,20.67 149.4,22.36 148.94,22.82 148.94,27.26 149.41,27.74 152.3,27.74 153.22,28.65 v1(153.22,28.67) ; R613.1 127.83,103.71 v1(128.66,104.53)
HDA_CODEC_SYNC_R: length 9.4
  BOTTOM w0.114: R613.2 127.22,102.3 126.8,102.3 126.79,102.28 126.56,102.28 125.38,101.1 v2(125.22,101.1) 123.89,99.77 123.89,96.91 123.54,96.56 123.54,96.3 123.85,95.99 CPU1.AM2
HDA_SDIN0: length 152.1
  TOP w0.114: R2718.1 150.69,16.11 149.56,16.11 149.21,15.76 149.21,15 149.18,14.97 v1(149.18,14.72)
  L4 w0.102: v1(154.34,30.49) 154.34,31.02 157.37,34.06 157.37,46 160.96,49.59 161.6,49.59 161.93,49.92 161.93,50.56 165.72,54.35 165.72,70.28 165.62,70.38 165.62,70.42 161.5,74.54 160.05,74.54 159.73,74.85 159.73,76.92 159.9,77.08 159.9,81.42 159.98,81.49 159.98,82.45 159.61,82.81 157.86,82.81 152.1,88.57 152.1,89.51 151.52,90.09 151.52,95.47 149.64,97.35 149.64,99.83 148.04,101.43 148.04,106.36 147.58,106.81 147.58,106.82 145.3,109.1 145.29,109.1 137.45,109.1 136.87,108.52 131.89,108.52 129.45,106.08 128.77,106.08 128.06,105.37 126.91,105.37 126.18,104.65 v1(126.18,103.74)
  BOTTOM w0.114: v1(126.18,103.74) 126.18,103.09 125.03,101.94 124.87,101.94 123.33,100.4 R633.1 122.73,100.34 122.73,97.55 122.99,97.29 122.99,96.63 123.05,96.57 123.05,96.28 122.75,95.97 CPU1.AK2 ; v1(154.34,30.49) 154.24,30.59 152.79,30.59 151.81,29.61 148.7,29.61 147.1,28.01 147.1,22.06 147.54,21.62 147.54,16.01 148.83,14.72 v1(149.18,14.72)
HDA_SPKR: length 89.4
  TOP w0.254: v1(162.92,70.78) 157.24,70.78 153.16,74.86 153.16,78.48 150.19,81.44 v2(145.45,81.44) 140.14,81.44 138.59,82.99 133.23,82.99 132.42,82.18 131.9,82.18 130.89,83.2 v1(130.89,83.47)
  L3 w0.254: v1(162.92,70.78) 162.57,70.42 162.57,65.7 159.75,62.88 159.75,59.02 153.17,52.44 153.17,47.5 155.24,45.43 155.24,36.14 v1(154.92,35.82)
  BOTTOM w0.254: CPU1.BA27 129.69,82.18 130.89,83.38 v1(130.89,83.47) ; R2721.1 155.43,29.31 155.43,34.09 155.27,34.24 155.27,35.47 v1(154.92,35.82)
HDA_SPKR_R: length 2.3
  BOTTOM w0.254: D2701.2 155.3,26.69 v2(155.3,27.44) 155.3,28.29 R2721.2
HDD_DEVSLP: length 98.5
  TOP w0.102: v1(167.85,71.18) 167.65,71.18 167.34,71.49 167.27,71.49 167.21,71.54 166.63,71.54 166.15,71.05 163.28,71.05 163,71.33 157.29,71.33 153.59,75.04 153.59,78.66 150,82.24 v2(149,82.24) v1(141.92,82.24)
  L4 w0.102: v1(169.78,71.18) 170.47,70.5 170.47,66.64 171.48,65.62 171.48,48.64 168.06,45.22 167.1,45.22 163.49,41.62 163.49,38.93 164.83,37.59 164.83,33.54 164.59,33.3 164.59,32.95 163.67,32.04 v1(162.72,32.04) ; v1(141.92,82.24) 141.68,82 140.14,82 138.72,83.42 132.71,83.42 131.78,84.35 127.07,84.35 v1(126.6,84.82)
  BOTTOM w0.102: v1(126.6,84.82) 126.6,84.77 CPU1.AV23 ; v1(162.72,32.04) 162.85,32.04 162.87,32.01 R5605.1 ; v1(167.85,71.18) v1(169.78,71.18)
HDD_DEVSLP_R: length 3.5
  BOTTOM w0.102: R5605.2 165.01,32.01 v2(165.24,31.78) 165.39,31.63 HDD1.5
HDMI_CLK: length 94.5
  L4 w0.127: v1(43.06,75.5) 43.01,75.5 42.79,75.28 42.79,75.13 42.88,75.04 54.1,75.04 56.76,77.7 76.72,77.7 91.11,92.09 94.47,92.09 95,91.55 99.22,91.55 100.92,89.85 104.1,89.85 104.22,89.98 v1(104.22,90.18)
  BOTTOM w0.102: CPU1.A12 106.66,90.43 106.4,90.69 104.6,90.69 104.22,90.31 v1(104.22,90.18)
  BOTTOM w0.14: C5403.1 23.13,75.14 23.85,75.14 24.06,75.35 36.05,75.35 ; v2(36.05,75.17) 36.05,75.35 ; 36.05,75.35 40.55,75.35 41.12,74.78 41.97,74.78 42.22,75.04 42.88,75.04 43.06,75.21 v1(43.06,75.5)
HDMI_CLK#: length 94.5
  L4 w0.127: v1(104.88,90.1) 104.88,90.08 104.39,89.59 100.8,89.59 99.11,91.29 94.89,91.29 94.36,91.82 91.22,91.82 76.83,77.43 56.87,77.43 54.21,74.78 42.77,74.78 42.53,75.02 42.53,75.26 v1(42.3,75.49)
  BOTTOM w0.102: CPU1.B12 106.97,90.13 106.67,90.13 106.32,90.49 105.26,90.49 v1(104.88,90.1)
  BOTTOM w0.14: v1(42.3,75.49) 41.85,75.04 41.23,75.04 40.66,75.61 37.68,75.61 ; 37.68,75.61 v2(37.68,75.75) ; 37.68,75.61 23.95,75.61 23.74,75.4 23.13,75.4 C5402.1
HDMI_CLK#_R: length 4.1
  TOP w0.14: v2(20.42,75.59) 20.64,75.37 v1(21.26,75.37) 21.26,75.65 21.34,75.72 21.34,75.75 21.55,75.96 RN5403.7
  BOTTOM w0.14: C5402.2 21.57,75.68 v1(21.26,75.37) 21.01,75.12 20.44,75.12 R5401.1
HDMI_CLK#_R_C: length 14.8
  BOTTOM w0.14: R5401.2 18.98,74.95 18.71,74.95 18.41,75.26 R5414.1 18.09,74.95 17.14,74.95 12.66,70.47 12.66,66.1 12.43,65.87 11.75,65.87 HDMI1.HP12
HDMI_CLK_R: length 4
  TOP w0.14: RN5403.8 21.87,75.31 v1(21.29,74.74) 20.71,74.74 v2(20.33,74.36)
  BOTTOM w0.14: C5403.2 21.42,74.86 v1(21.29,74.74) 21.18,74.85 20.66,74.85 R5402.1
HDMI_CLK_R_C: length 14.8
  BOTTOM w0.14: R5402.2 19.1,74.69 18.71,74.69 R5414.2 18.09,74.68 17.25,74.68 12.93,70.36 12.93,65.99 12.54,65.61 11.79,65.61 HDMI1.HP10
HDMI_CRT_DET: length 107.3
  TOP w0.102: v1(30.65,73.92) 30.28,74.29 R5419.1 ; v1(80.53,69.78) 80.5,69.76 v2(78.65,69.76) v1(77.15,69.76)
  L3 w0.102: v1(30.65,73.92) 30.31,73.58 30.31,68.41 32.03,66.69 46.69,66.69 v1(51.57,61.81)
  L4 w0.102: v1(51.57,61.81) 52.6,61.81 53.56,60.85 53.8,60.62 66.71,60.62 67.04,60.62 76.19,69.76 v1(77.15,69.76) ; v1(110.52,87.08) 110.12,86.68 107.79,86.68 105.82,84.71 105.82,82.96 101.46,78.6 99.07,78.6 98.86,78.8 94.73,78.8 91.96,81.57 90.49,81.57 88.26,79.34 86.77,79.34 84.81,77.37 84.81,74.87 82.25,72.32 82.25,71.51 v1(80.53,69.78)
  BOTTOM w0.102: CPU1.H19 111,86.61 v1(110.52,87.08)
HDMI_DATA0: length 94.2
  L4 w0.127: v1(44.64,76.36) 44.64,75.96 44.76,75.83 45.42,75.83 45.68,75.58 53.88,75.58 56.54,78.23 76.5,78.23 90.97,92.71 94.61,92.71 95.24,92.09 99.27,92.09 100.85,90.51 103.46,90.51 v1(103.61,90.36)
  BOTTOM w0.102: v1(103.61,90.36) 104.24,90.98 CPU1.A11
  BOTTOM w0.14: 39.81,76.96 44.76,76.96 44.9,76.81 44.9,76.63 v1(44.64,76.36) ; 39.81,76.96 v2(39.81,76.82) ; 39.81,76.96 37.89,76.96 37.13,76.2 24.46,76.2 23.87,76.79 23.13,76.79 C5405.1
HDMI_DATA0#: length 94.3
  L4 w0.127: v1(103.61,91.04) 103.35,90.78 100.96,90.78 99.38,92.35 95.35,92.35 94.72,92.97 90.86,92.97 80.28,82.4 76.39,78.5 56.42,78.5 53.77,75.84 45.79,75.84 45.27,76.36 v1(45.27,76.36)
  BOTTOM w0.102: CPU1.B11 106.64,91.26 106.62,91.28 106.37,91.28 106.27,91.18 103.75,91.18 v1(103.61,91.04)
  BOTTOM w0.14: v1(45.27,76.36) 45.17,76.46 45.17,76.92 44.87,77.22 42.53,77.22 ; 42.53,77.22 37.78,77.22 37.02,76.46 24.57,76.46 23.98,77.06 23.13,77.06 C5404.1 ; 42.53,77.22 v2(42.53,77.38)
HDMI_DATA0#_R: length 3.9
  TOP w0.14: RN5403.5 21.2,77.11 v1(21.19,77.13)
  BOTTOM w0.14: C5404.2 21.39,77.33 v1(21.19,77.13) 20.94,76.87 20.47,76.87 R5403.1 20.24,77.9 20.45,78.11 v2(20.45,78.12)
HDMI_DATA0#_R_C: length 19.3
  BOTTOM w0.102: HDMI1.HP9 10.29,64.33 10.29,64.32 10.46,64.32 10.56,64.42 10.56,69.88 11.32,70.64 11.33,70.67 11.37,70.71
  BOTTOM w0.14: 11.37,70.71 17.43,76.77 18.13,76.77 R5416.1 18.43,77.04 18.71,76.76 19.01,76.76 R5403.2 19.35,77.85 v2(19.18,78.01)
HDMI_DATA0_R: length 3.5
  TOP w0.14: RN5403.6 21.22,76.46 v1(21.19,76.49) 20.91,76.49 v2(20.56,76.85)
  BOTTOM w0.14: C5405.2 21.22,76.52 v1(21.19,76.49) 21.08,76.6 20.63,76.6 R5404.1
HDMI_DATA0_R_C: length 18.3
  BOTTOM w0.102: 11.56,70.52 11.54,70.51 11.48,70.51 11.47,70.49 11.46,70.49 10.76,69.8 10.76,64.34 10.55,64.12 10.3,64.12 HDMI1.HP7
  BOTTOM w0.14: 11.56,70.52 17.54,76.5 18.04,76.5 R5416.2 18.44,76.15 18.78,76.49 19.07,76.49 R5404.2
HDMI_DATA1: length 97.1
  L4 w0.127: v1(39.73,74.69) 39.61,74.81 39.61,75.09 41.66,77.15 53.24,77.15 55.15,79.06 69.62,79.06 71.64,81.08 73.28,81.08 74.46,82.26 76.4,82.26 90.31,96.18 99.05,96.18 102.58,92.64 104,92.64 104.3,92.34 104.3,92.07 v1(104.14,91.91)
  BOTTOM w0.102: 106.13,91.49 106.17,91.53 CPU1.A10
  BOTTOM w0.14: 106.13,91.49 104.24,91.49 104.14,91.59 v1(104.14,91.91) ; v1(39.73,74.69) 39.56,74.51 39.28,74.24 39.02,74.24 38.68,73.9 37.52,73.9 37,74.42 33,74.42 ; C5406.1 23.2,73.33 23.92,73.33 25.01,74.42 33,74.42 ; 33,74.42 v2(33,74.26)
HDMI_DATA1#: length 97.2
  L4 w0.127: v1(39.1,74.69) 39.34,74.93 39.34,75.2 41.55,77.42 53.13,77.42 55.04,79.32 69.51,79.32 71.53,81.34 73.17,81.34 74.35,82.52 76.28,82.52 90.2,96.44 99.16,96.44 102.69,92.91 104.11,92.91 104.57,92.45 104.57,92.15 v1(104.77,91.95)
  BOTTOM w0.102: CPU1.B10 106.99,91.83 106.72,91.83 106.64,91.75 106.15,91.75
  BOTTOM w0.14: C5409.1 23.2,73.6 23.81,73.6 24.9,74.69 30.61,74.69 ; 30.61,74.69 v2(30.61,74.92) ; 30.61,74.69 37.11,74.69 37.63,74.17 38.57,74.17 v1(39.1,74.69) ; v1(104.77,91.95) 104.96,91.75 106.15,91.75
HDMI_DATA1#_R: length 3.1
  TOP w0.14: v1(20.89,73.42) 21.02,73.56 RN5402.5
  BOTTOM w0.14: C5409.2 21.58,73.42 v1(20.89,73.42) R5407.1
HDMI_DATA1#_R_C: length 23.1
  BOTTOM w0.14: HDMI1.HP6 11.74,62.88 12.16,62.88 12.93,62.12 12.93,59.66 13.55,59.04 14.41,59.04 16.11,60.74 16.11,69.83 16.13,69.93 16.97,72.29 17.71,73.04 18.08,73.04 R5417.1 19.29,73.35 R5407.2
HDMI_DATA1_R: length 3.7
  TOP w0.14: RN5402.6 21.11,72.91 v1(20.99,72.78) 20.85,72.65 v2(20.45,72.65)
  BOTTOM w0.14: R5408.1 20.49,72.78 v1(20.99,72.78) 21.36,73.15 21.95,73.15 C5406.2
HDMI_DATA1_R_C: length 24.1
  BOTTOM w0.14: HDMI1.HP4 11.8,62.62 12.05,62.62 12.66,62.01 12.66,59.55 13.44,58.77 14.52,58.77 16.38,60.63 16.38,69.81 16.39,69.86 17.2,72.15 17.83,72.77 18.09,72.77 R5417.2 19.29,72.46 R5408.2 v2(19.35,71.61)
HDMI_DATA2: length 98.9
  L4 w0.127: v1(102.06,94.19) 102.06,94.55 99.63,96.99 90,96.99 76.06,83.06 74.13,83.06 72.95,81.88 71.17,81.88 69.38,80.08 55.01,80.08 52.88,77.95 46.88,77.95 46.26,78.57 41.71,78.57 39.56,76.41 36.84,76.41 35.06,74.64 35.06,74.28 v1(35.54,73.8)
  BOTTOM w0.14: 31.99,73.06 24.92,73.06 23.57,71.71 23.2,71.71 C5408.1 ; 31.99,73.06 34.42,73.06 34.7,73.34 35.08,73.34 v1(35.54,73.8) ; 31.99,73.06 v2(31.99,72.88) ; v1(102.06,94.19) 102.06,93.79 102.19,93.66 102.46,93.66 102.56,93.56 102.56,92.89 102.92,92.53 104.83,92.53 105.27,92.08 CPU1.A9
HDMI_DATA2#: length 98.9
  L4 w0.127: v1(34.78,73.8) 34.79,73.81 34.79,74.75 36.73,76.68 39.44,76.68 41.6,78.84 46.37,78.84 46.99,78.22 52.77,78.22 54.9,80.35 69.27,80.35 71.06,82.14 72.84,82.14 74.02,83.32 75.95,83.32 89.89,97.25 99.74,97.25 v1(102.83,94.17)
  BOTTOM w0.102: 106.05,92.38 106.62,92.38 CPU1.B9
  BOTTOM w0.14: 29.04,73.33 34.31,73.33 v1(34.78,73.8) ; 29.04,73.33 24.81,73.33 23.46,71.98 23.2,71.98 C5407.1 ; 29.04,73.33 v2(29.04,73.47) ; v1(102.83,94.17) 102.83,93 103.03,92.79 104.94,92.79 105.39,92.35 106.02,92.35 106.05,92.38
HDMI_DATA2#_R: length 6.4
  TOP w0.14: RN5402.7 21.5,72.4 21.29,72.19 21.29,71.61 21.09,71.41 v1(20.86,71.41)
  BOTTOM w0.14: v2(18.98,69.53) 19.34,69.89 R5405.1 20.12,70.14 20.12,70.58 20.86,71.31 v1(20.86,71.41) 21.14,71.41 21.98,72.25 C5407.2
HDMI_DATA2#_R_C: length 20.7
  BOTTOM w0.14: 19.82,66.97 19.41,66.56 18.52,66.56 16.96,65 16.96,60.25 14.9,58.19 13.19,58.19 12.07,59.31 12.07,59.65 10.74,60.99 10.74,61.29 10.31,61.72 HDMI1.HP3 ; 19.82,66.97 v2(19.69,67.09) ; 19.82,66.97 20.17,67.32 20.17,67.77 R5415.1 19.88,68.1 R5405.2
HDMI_DATA2_R: length 4.9
  TOP w0.14: v1(21.17,70.67) 21.17,71.08 21.31,71.22 21.31,71.26 21.81,71.75 RN5402.8
  BOTTOM w0.14: C5408.2 21.54,71.44 21.17,71.06 v1(21.17,70.67) 21.01,70.83 20.75,70.83 20.39,70.47 20.39,70.03 20.53,69.89 R5406.1
HDMI_DATA2_R_C: length 20.7
  BOTTOM w0.14: R5406.2 20.89,68.23 R5415.2 20.44,67.78 20.44,67.21 19.52,66.29 18.93,66.29 ; HDMI1.HP1 10.63,60.72 11.81,59.54 11.81,59.2 13.08,57.92 15.01,57.92 17.23,60.14 17.23,64.89 18.63,66.29 18.93,66.29 ; 18.93,66.29 v2(18.93,66.13)
HDMI_HPD_B: length 20.2
  TOP w0.102: Q5401.B 31.22,80.27 v1(31.35,80.4)
  L4 w0.102: v1(18.37,79.64) 18.4,79.64 20.3,81.54 30.21,81.54 v1(31.35,80.4)
  BOTTOM w0.102: R5411.2 17.85,78.75 18.78,78.75 19.01,78.98 v2(19.01,79.31) 19.01,79.44 18.8,79.64 v1(18.37,79.64)
HDMI_HPD_E: length 4.7
  TOP w0.102: Q5401.E 29.26,78.3 30.28,77.28 v2(30.28,77.1) R5419.2 R5412.1
HDMI_PLL_GND:
  vias: v2(24.65,75.65)
HPD_HDMI_CON: length 14.4
  L4 w0.102: v1(17.13,77.81) 16.52,77.2 16.52,76.03 10.2,69.72 HDMI1.HP19
  BOTTOM w0.102: v2(17.76,78.17) 17.41,77.81 v1(17.13,77.81) 16.63,78.31 R5411.1 R5410.1
ILIM_R: length 50.2
  TOP w0.254: v1(114.94,112.7) v2(114.94,113.32) ; PR4642.2 PR4643.1 v1(128,138.57)
  L4 w0.254: v1(128,138.57) 128.1,138.57 135.87,130.8 135.87,117.93 131.62,113.68 117.8,113.68 117.2,113.68 116.11,112.58 115.06,112.58 v1(114.94,112.7)
  BOTTOM w0.254: v1(114.94,112.7) 114.97,112.67 115.73,112.67 PR4678.2
ILIMNB_R: length 51.8
  L4 w0.254: v1(110.8,139.13) 108.96,139.13 101.62,131.79 101.62,131.12 101.62,116.3 105.52,112.41 107.84,112.41 110.19,110.05 113.11,110.05 113.75,109.41 117.66,109.41 v1(118.17,109.92)
  BOTTOM w0.254: v1(110.8,139.13) 111.51,139.13 111.86,138.78 v2(112.4,138.78) PR4629.2 PR4630.1 ; v1(118.17,109.92) 118.23,109.98 PR4677.2
IMVP_PWRGD: length 232.3
  TOP w0.127: v1(79.99,57.29) 79.99,57.85 81.07,58.93 Q2602.G
  L3 w0.127: v1(145.02,133.87) 140.41,129.26 140.41,125.1 146.18,119.33 148.72,119.33 150.75,117.3 157.17,117.3 166.23,108.23 166.23,90.45 166.77,89.91 166.77,79.63 166.12,78.98 166.12,76.87 165.06,75.8 165.06,74.41 163.07,72.43 162.66,72.43 159.78,69.54 159.1,69.54 157.87,68.31 157.87,63.02 158.48,62.41 158.48,59.53 151.83,52.88 146.49,52.88 v1(146.18,53.2)
  L4 w0.127: v1(145.02,133.87) 144.11,134.77 144.11,140.36 139.14,145.34 126.33,145.34 124.21,147.46 113.55,147.46 v1(113.42,147.58)
  BOTTOM w0.127: KBC24.107 145.42,133.47 v1(145.02,133.87) ; v1(79.99,57.29) 85.4,51.88 144.43,51.88 145.75,53.2 v1(146.18,53.2) ; v1(113.42,147.58) 113.42,147.15 v2(113.75,146.82) 114.22,146.82 PR4617.2 114.66,148.09 115.23,148.66 115.87,148.66 117.27,147.27 PR4616.2
INT_SERIRQ: length 148
  TOP w0.102: v1(127.39,81.62) 127.29,81.72 v2(126.73,81.72)
  L3 w0.102: v1(146.95,64.45) 147.94,64.45 151.24,67.75 151.24,69.06 158.41,76.24 160.79,76.24 162.01,77.46 162.01,78.34 165.77,82.1 165.77,87.64 164.73,88.68 164.73,108.64 157.53,115.83 150.48,115.83 148.01,118.3 145.75,118.3 139.38,124.67 139.38,132.93 143.48,137.03 143.48,138.32 144.59,139.43 145.5,139.43 145.93,139 148.27,139 v1(148.88,138.39)
  L4 w0.102: v1(146.95,64.45) 146.95,68.11 147.49,68.65 147.49,72.09 143.11,76.46 140.14,76.46 138.64,77.96 138.64,78.57 137.24,79.97 131.89,79.97 131.32,80.54 128.47,80.54 v1(127.39,81.62)
  BOTTOM w0.102: CPU1.AV29 127,81.23 v1(127.39,81.62) ; v1(148.88,138.39) 148.88,138.47 148.85,138.5 148.85,138.75 147.18,140.41 147.18,140.43 147.1,140.52 147.08,140.52 146.93,140.67 KBC24.125 145.41,140.67 145.28,140.79 144.47,140.79 144.28,140.6 R2441.1
INT_TP#: length 228.7
  TOP w0.102: v1(167.3,75.14) 166.5,74.34 166.5,73.9 165.79,73.19 165.79,72.58 165.54,72.32 163.96,72.32 163.14,73.15 v1(160.98,73.15) ; v1(151.49,130.19) 151.68,130.38 R2448.1 ; TPAD1.4 60.47,77.77 AFTP6241.1 v1(59.29,76.59)
  L3 w0.102: v1(78.15,65.68) 77.76,66.07 77.76,68.03 76.89,68.9 74.2,68.9 68.33,74.76 61.12,74.76 v1(59.29,76.59) ; v1(151.49,130.19) 152.37,131.06 162.63,131.06 162.88,131.31 v1(162.98,131.31) ; v1(160.98,73.15) 158.96,71.13 158.38,71.13 155.39,68.14 155.39,66.43 153.65,64.69 152.57,64.69 149.61,61.74 149.61,58.61 v1(146.9,55.89)
  L4 w0.102: v1(163.37,148.51) 162.34,147.48 162.34,131.95 v1(162.98,131.31) 162.98,131.3 162.95,131.26 162.95,127.29 166.86,123.38 166.86,90.38 167.39,89.85 167.39,84.44 167.22,84.26 167.22,79.62 167.75,79.09 167.75,77.12 167.14,76.51 167.14,75.31 v1(167.3,75.14)
  BOTTOM w0.102: v1(78.15,65.68) 77.15,64.68 77.15,64.25 78.17,63.22 78.67,63.22 88.4,53.49 143.23,53.49 145.63,55.9 146.89,55.9 v1(146.9,55.89) ; R6203.1 v1(163.37,148.51)
IRIS_BEEMA_ID: length 7.3
  BOTTOM w0.102: CPU1.AY21 128.66,85.48 129.13,85.01 129.41,85.01 130.12,84.3 132.79,84.3 R640.2 R639.1 132.83,85.84 v2(132.21,85.84)
ISOLATE#: length 4.5
  TOP w0.102: v2(54.72,166.48) 54.66,166.55 R3015.1 R3014.2 53.94,168.26 53.68,168.53 53.68,168.57 53.14,169.1 LOM30.20
JACK_PLUG: length 4.6
  TOP w0.254: R2923.2 163.94,21.09 AFTP6307.1 165.62,22.77 CN6301.23
JDREF: length 2.4
  BOTTOM w0.102: R2707.1 154.87,17.78 v2(154.87,16.98) 154.87,16.67 155.15,16.4 HDA27.15
JGND:
  vias: v3(107.3,159.9)
KB_BL_CTRL: length 26.8
  TOP w0.102: Q6203.G 164.33,130.24 R6208.1 165.15,130 166.02,130.87 v1(166.02,130.95) ; v2(165.08,141.11) v1(165.72,140.47)
  L3 w0.102: v1(156.17,141.34) 156.6,141.77 164.22,141.77 165.51,140.47 v1(165.72,140.47)
  L4 w0.102: v1(166.02,130.95) 166.02,136.31 165.11,137.22 165.11,138.39 165.72,139 v1(165.72,140.47)
  BOTTOM w0.102: KBC24.22 156.22,141.82 156.17,141.77 v1(156.17,141.34)
KB_BL_CTRL#: length 9.3
  TOP w0.406: 164.57,124.85 164.86,124.57 KBLIT1.4
  TOP w0.508: Q6203.D 160.94,130.9 162.92,128.92 163.45,128.92 163.63,128.74 163.66,128.74 164.19,128.2 164.19,128.12 164.22,128.1 AFTP6247.1 164.22,125.21 164.57,124.85
KB_DET#: length 72.8
  TOP w0.102: v1(132.11,82.69) 132.31,82.69 133.05,83.42 138.77,83.42 139.94,82.26 141.32,82.26 141.74,82.68 149.9,82.68 153.82,78.75 153.82,75.13 157.39,71.56 163.1,71.56 163.37,71.28 165.97,71.28 167.88,73.19 168.08,73.19 v1(168.08,73.19) ; KB1.30 165.61,92.95 166.22,92.34 166.22,91.67 167.08,90.82 AFTP6202.1 v1(168.05,90.82)
  L4 w0.102: v1(168.05,90.82) 168.26,90.61 168.26,84.08 168.08,83.9 168.08,80.05 168.7,79.43 168.7,73.81 v1(168.08,73.19)
  BOTTOM w0.102: v1(132.11,82.69) 132.14,82.69 132.62,82.2 R604.1 132.26,81.32 131.95,81.63 CPU1.BA28
KB_LED_BL_DET: length 156.9
  TOP w0.102: v1(163.33,126.19) R6206.1 R6207.1
  L4 w0.102: v1(161.3,46.54) 162.24,46.54 164.29,48.6 164.29,49.24 164.57,49.52 165.26,49.52 165.67,49.92 165.67,51.75 167.03,53.11 167.03,59.74 167.01,59.75 167.01,66.45 167.83,67.26 167.83,69.68 167.57,69.94 167.57,70.85 167.42,71 167.42,71.31 166.12,72.6 166.12,73.53 166.5,73.91 166.5,74.66 166.87,75.03 166.87,84.24 167.16,84.53 167.16,89.76 166.63,90.29 166.63,122.88 166.35,123.16 v1(163.33,126.19) ; v1(131.95,84.79) 133.08,83.65 138.87,83.65 139.35,83.17 141.61,83.17 145.32,79.46 145.32,75.69 148.51,72.51 148.51,68.23 147.96,67.69 147.96,64.75 147.81,64.6 147.81,57.36 148.6,56.58 148.6,48.91 v1(148.62,48.91)
  BOTTOM w0.102: v1(131.95,84.79) 130.95,85.78 128.97,85.78 128.91,85.73 128.58,85.73 128.52,85.78 128.27,85.78 128.22,85.73 127.92,85.73 127.86,85.78 127.3,85.78 CPU1.AV21 ; v1(148.62,48.91) v2(149.59,49.87) 150.5,50.79 154.76,50.79 157.4,48.14 159.7,48.14 v1(161.3,46.54)
KB_LED_DET_C: length 7.7
  TOP w0.102: KBLIT1.2 165.18,122.57 164.83,122.92 164.83,123.42 AFTP6246.1 163.46,125.7 163.76,126.01 163.76,126.36 163.51,126.62 163.14,126.62 162.68,127.07 R6206.2 162.26,127.96 C6203.1
KBC_BEEP: length 144.8
  L3 w0.254: v1(169.27,136.13) 168.64,136.76 164.64,136.76 162.44,138.97 160.29,138.97 160.22,138.9 154.46,138.9 152.99,137.42 v1(148.37,137.42) ; v1(154.41,35.32) 155.13,35.32 155.75,35.93 155.75,45.68 153.68,47.75 153.68,51.34 160.84,58.51 161.69,58.51 162.92,59.74 162.92,64.15 163.84,65.06 163.84,68.02 165.97,70.16 165.97,71.2 166.69,71.92 v1(167.44,71.92)
  L4 w0.254: v1(169.27,136.13) 168.84,135.7 168.84,109.56 170.16,108.24 170.16,91.78 169.73,91.35 169.73,90.26 170.24,89.75 170.24,79.33 169.98,79.08 169.98,73.26 170.26,72.99 170.26,72.27 169.84,71.84 v1(169.78,71.84)
  BOTTOM w0.203: KBC24.118 147,137.87 147.1,137.77 147.12,137.77 147.24,137.65 147.24,137.57 147.38,137.42 v1(148.37,137.42)
  BOTTOM w0.254: v1(167.44,71.92) 167.6,71.92 167.62,71.94 169.68,71.94 v1(169.78,71.84) ; R2723.1 154.52,29.3 154.92,29.71 v2(154.92,33.13) 154.92,33.88 154.76,34.03 154.76,34.97 v1(154.41,35.32)
KBC_BEEP_R: length 2.4
  BOTTOM w0.254: R2723.2 154.52,28.14 v2(153.85,27.47) D2701.1
KBC_ON#_GATE: length 9
  TOP w0.102: R2433.2 153.21,136.85 v2(152.69,137.37) 152.69,137.73 153.33,138.38 Q2403.G 154.7,137.49 156.62,137.49 Q2402.G 157.78,138.04 C2417.1
KBC_ON#_GATE_L: length 3.4
  TOP w0.102: R2431.1 153.65,134.95 R2432.2 152.9,135.08 v2(152.61,135.37) 152.61,135.37 152.61,135.75 152.83,135.96 R2433.1
KBC_PWRBTN#: length 55.6
  TOP w0.102: v1(150.8,131.58) 150.8,131.62 v2(150.22,132.19) 150.15,132.27 149.51,132.27 149.21,131.96 R2427.1
  L3 w0.102: v1(167.7,161.3) 167.7,150.07 170.06,147.71 170.06,136.31 169.45,135.7 154.24,135.7 152.97,136.97 151.06,136.97 150.07,135.98 150.07,134.78 150.8,134.06 v1(150.8,131.58)
  BOTTOM w0.102: R6102.1 v1(167.7,161.3)
KBC_PWRBTN#_C: length 10.8
  TOP w0.127: PWR1.2 167.8,169.38 167.11,170.06 AFTP6101.1 167.65,170.44 v1(167.75,170.34)
  BOTTOM w0.127: R6102.2 167.71,162.85 EC6101.1 167.71,164.5 ED6101.1 167.74,164.98 167.52,165.2 G6102.2 G6101.2 167.52,170.11 v1(167.75,170.34)
KBC_VCORF: length 2.9
  TOP w0.254: C2416.1 161.11,137.62 v2(161.07,137.65) v1(160.51,137.65)
  BOTTOM w0.203: KBC24.44 160.7,137.47 v1(160.51,137.65)
KCOL0: length 36.2
  TOP w0.102: KB1.13 165.98,106.55 166.35,106.18 AFTP6207.1 168.13,106.18 168.74,106.79 v1(168.87,106.79)
  BOTTOM w0.102: v1(168.87,106.79) 167.14,108.52 167.14,131.68 164.96,133.87 KBC24.53
KCOL1: length 39.8
  TOP w0.102: v1(168.89,104.76) 169.02,104.63 AFTP6206.1 168.38,104.15 167.58,104.95 KB1.15
  BOTTOM w0.102: v1(168.89,104.76) 168.79,104.86 168.79,105.85 169.3,106.36 169.3,107.01 167.34,108.97 167.34,131.86 164.94,134.27 KBC24.52
KCOL2: length 39.4
  TOP w0.102: v1(169.22,105.5) 169.25,105.52 169.25,105.95 AFTP6226.1 168.59,105.75 KB1.14
  BOTTOM w0.102: KBC24.51 164.92,134.67 167.55,132.04 167.55,109.07 169.5,107.12 169.5,105.78 v1(169.22,105.5)
KCOL3: length 41
  TOP w0.102: KB1.16 167.11,104.15 ; 167.11,104.15 AFTP6208.1 ; 167.11,104.15 167.62,104.15 167.98,103.8 169.17,103.8 169.53,104.16 v1(169.53,104.48)
  BOTTOM w0.102: v1(169.53,104.48) 169.7,104.66 169.7,107.22 167.75,109.17 167.75,132.22 164.9,135.07 KBC24.50
KCOL4: length 46.6
  TOP w0.102: v1(169.02,99.68) 167.77,99.68 AFTP6224.1 166.5,100.95 KB1.20
  BOTTOM w0.102: KBC24.49 164.79,135.47 167.95,132.3 167.95,109.26 169.96,107.25 169.96,104.3 168.26,102.6 168.26,100.44 v1(169.02,99.68)
KCOL5: length 48.7
  TOP w0.102: v1(169.27,99.05) 169.22,99.05 169.02,98.84 AFTP6215.1 167.88,98.44 166.16,100.15 KB1.21
  BOTTOM w0.102: v1(169.27,99.05) 169.45,99.22 169.45,99.86 168.46,100.85 168.46,102.52 170.16,104.22 170.16,107.34 168.16,109.34 168.16,132.39 164.67,135.87 KBC24.48
KCOL6: length 46.2
  TOP w0.102: v1(169.03,100.94) 168.95,100.94 168.94,100.95 168.41,100.95 AFTP6223.1 166.81,102.55 KB1.18
  BOTTOM w0.102: KBC24.47 164.59,136.27 168.36,132.5 168.36,109.43 170.37,107.42 170.37,104.13 168.66,102.43 168.66,101.31 v1(169.03,100.94)
KCOL7: length 47.7
  TOP w0.102: v1(169.1,101.61) 169.46,101.24 169.46,100.76 169.05,100.34 AFTP6213.1 168.13,100.34 166.72,101.75 KB1.19
  BOTTOM w0.102: KBC24.43 163.37,137.87 168.56,132.68 168.56,109.51 170.57,107.5 170.57,103.77 169.1,102.3 v1(169.1,101.61)
KCOL8: length 46.3
  TOP w0.102: v1(169.65,102.25) AFTP6231.1 167.91,103.35 KB1.17
  BOTTOM w0.102: KBC24.42 163.26,138.27 168.76,132.76 168.76,109.6 170.77,107.59 170.77,103.36 v1(169.65,102.25)
KCOL9: length 34.6
  TOP w0.102: v1(169.58,113.98) 169.58,113.85 167.62,111.9 AFTP6219.1 166.48,111.9 165.93,111.35 KB1.7
  BOTTOM w0.102: KBC24.41 163.14,138.67 168.97,132.84 168.97,114.54 169.53,113.98 v1(169.58,113.98)
KCOL10: length 33.1
  TOP w0.102: KB1.5 166.26,112.95 AFTP6232.1 168.66,115.35 v1(169.4,115.35)
  BOTTOM w0.102: KBC24.40 163.03,139.07 169.17,132.93 169.17,115.58 v1(169.4,115.35)
KCOL11: length 35.1
  TOP w0.102: KB1.6 166.22,112.15 167.88,113.8 AFTP6220.1 169.02,114.23 169.4,114.62 v1(169.4,114.72)
  BOTTOM w0.102: v1(169.4,114.72) 170.24,115.56 170.24,132.15 162.92,139.47 KBC24.39
KCOL12: length 43.6
  TOP w0.102: v1(169.63,109.49) 169.63,108.7 AFTP6233.1 168.28,107.35 KB1.12
  BOTTOM w0.102: v1(169.63,109.49) 169.62,109.49 169.47,109.64 169.27,109.64 168.97,109.94 168.97,112.74 170.46,114.23 170.46,135.61 168.76,137.3 167.75,137.3 165.18,139.87 KBC24.38
KCOL13: length 41.3
  TOP w0.102: v1(169.63,111.57) 169.37,111.57 167.8,109.99 AFTP6203.1 166.87,109.75 KB1.9
  BOTTOM w0.102: v1(169.63,111.57) 169.43,111.57 169.2,111.8 169.2,112.68 170.66,114.14 170.66,135.69 168.85,137.5 167.83,137.5 165.07,140.27 KBC24.37
KCOL14: length 43
  TOP w0.102: KB1.8 167.67,110.55 AFTP6216.1 169.32,112.2 169.55,112.2 169.58,112.23 v1(169.63,112.23)
  BOTTOM w0.102: v1(169.63,112.23) 169.63,112.8 170.86,114.03 170.86,139.33 169.06,141.13 163.69,141.13 163.22,140.67 KBC24.36
KCOL15: length 45.3
  TOP w0.102: KB1.10 167.98,108.95 AFTP6229.1 169.02,110.48 169.48,110.93 v1(169.63,110.93)
  BOTTOM w0.102: v1(169.63,110.93) 170.09,110.93 171.07,111.91 171.07,139.42 169.15,141.34 163.28,141.34 163.01,141.07 KBC24.35
KCOL16: length 46.9
  TOP w0.102: v1(169.6,110.3) 169.6,110.07 167.62,108.09 AFTP6225.1 166.48,108.09 166.42,108.15 KB1.11
  BOTTOM w0.102: v1(169.6,110.3) 169.63,110.3 170.09,110.3 170.52,110.73 170.53,110.73 171.23,111.43 171.23,111.79 171.27,111.83 171.27,139.5 168.52,142.25 163.56,142.25 162.77,141.47 KBC24.34
KROW0: length 45.5
  TOP w0.102: KB1.22 166.2,99.35 AFTP6228.1 167.47,98.08 169.27,98.08 169.3,98.11 169.48,98.11 v1(169.52,98.15)
  BOTTOM w0.102: KBC24.54 164.97,133.47 166.94,131.51 166.94,100.73 v1(169.52,98.15)
KROW1: length 47.5
  TOP w0.102: KB1.24 165.9,97.75 AFTP6227.1 167.62,96.02 169.31,96.02 169.4,96.12 v1(169.44,96.12)
  BOTTOM w0.102: KBC24.55 164.99,133.07 166.73,131.33 166.73,100.32 169.68,97.38 169.68,96.35 v1(169.44,96.12)
KROW2: length 49.5
  TOP w0.102: KB1.26 165.59,96.15 AFTP6218.1 167.9,93.84 168.92,93.84 v1(169.02,93.94)
  BOTTOM w0.102: v1(169.02,93.94) 169.5,94.42 169.5,95.45 169.01,95.94 169.01,96.32 169.48,96.78 169.48,97.29 166.53,100.24 166.53,131.15 165.01,132.67 KBC24.56
KROW3: length 45
  TOP w0.102: v1(169.04,97.09) 169.04,96.56 AFTP6234.1 168.26,96.53 166.24,98.55 KB1.23
  BOTTOM w0.102: v1(169.04,97.09) 166.33,99.81 166.33,129.91 163.96,132.27 KBC24.57
KROW4: length 49.3
  TOP w0.102: KB1.27 165.5,95.35 167.62,93.23 167.65,93.23 168.16,92.72 AFTP6230.1 v1(169.02,93.31)
  BOTTOM w0.102: v1(169.02,93.31) 168.59,93.74 168.59,94.12 169.3,94.83 169.3,95.36 166.12,98.54 166.12,129.81 163.99,131.94 162.55,131.94 162.47,131.87 KBC24.58
KROW5: length 46.8
  TOP w0.102: KB1.25 165.93,96.95 168.26,94.63 AFTP6214.1 169.02,95.03 v1(168.87,95.18)
  BOTTOM w0.102: v1(168.87,95.18) 168.46,95.18 165.92,97.72 165.92,129.73 163.91,131.74 162.8,131.74 162.53,131.47 KBC24.59
KROW6: length 47.7
  TOP w0.102: KB1.28 165.67,94.55 166.48,93.74 166.48,93.36 AFTP6222.1 167.47,92.72 v1(168.23,91.96)
  BOTTOM w0.102: v1(168.23,91.96) 165.72,94.47 165.72,129.4 164.47,130.64 163.3,130.64 163.08,130.87 162.72,130.87 162.52,131.07 KBC24.60
KROW7: length 52.5
  TOP w0.102: KB1.29 165.83,93.75 166.1,93.48 166.1,92.85 167.62,91.32 168.26,91.32 168.76,90.82 AFTP6221.1 169.15,90.94 169.15,91.83 169.55,92.24 v1(169.55,92.44)
  BOTTOM w0.102: v1(169.55,92.44) 168.64,91.53 168.05,91.53 165.51,94.07 165.51,129.31 164.39,130.44 163.18,130.44 162.95,130.67 KBC24.61
L_BKLT_CTRL: length 93.2
  TOP w0.14: v1(104.83,87.21) 104.83,86.48 v2(104.83,86.47)
  L3 w0.127: v1(103.87,146.19) 104.31,145.74 104.31,143.83 102.98,142.5 102.98,139.34 97.56,133.92 95.75,133.92 91.38,129.55 91.38,94.17 90.05,92.84 v1(90.05,85.94)
  L4 w0.127: v1(104.83,87.21) 104.34,86.73 102.9,86.73 101.84,85.66 101.84,81.67 101.58,81.42 98.57,81.42 98.36,81.63 95.73,81.63 92.86,84.5 90.88,84.5 90.05,85.33 v1(90.05,85.94)
  BOTTOM w0.14: R5206.1 v1(103.87,146.19) ; v1(104.83,87.21) 104.9,87.14 104.9,87.14 104.99,87.05 104.99,86.99 105.25,86.72 105.27,86.72 105.27,86.72 105.65,86.72 105.69,86.76 105.74,86.76 106.1,87.13 CPU1.A18
L_BKLT_EN: length 218.6
  TOP w0.102: R2444.1 v1(152,147.97)
  L3 w0.102: v1(85.83,148.85) 86.09,148.6 86.09,140.98 88.67,138.4 88.67,136.05 89.67,135.05 89.67,95.05 86.4,91.79 86.4,83.52 86.67,83.25 v1(86.67,82.66)
  L4 w0.102: v1(152,147.97) 151.57,147.53 150.71,147.53 150.15,148.09 126.9,148.09 121.27,153.72 121.27,156.09 122.16,156.98 122.92,156.98 124.01,158.08 124.01,160.79 122.99,161.81 122.99,165.51 125.18,167.69 125.18,171.92 124.59,172.5 119.09,172.5 117.29,174.31 108.09,174.31 107.31,175.09 89.85,175.09 84.36,169.6 v1(84.36,168.62) ; v1(86.67,82.66) 88.09,84.08 92.68,84.08 95.55,81.21 98.47,81.21 98.48,81.2 101.67,81.2 102.05,81.58 102.05,85.42 103.13,86.5 104.79,86.5 v1(105.46,87.17)
  BOTTOM w0.102: v1(105.46,87.17) 105.7,87.21 105.83,87.35 106.6,87.35 106.75,87.5 107.02,87.5 CPU1.B17 ; v1(84.36,168.62) 83.83,168.08 v2(83.83,167.83) 83.83,161.15 83.02,160.34 83.02,151.67 v1(85.83,148.85)
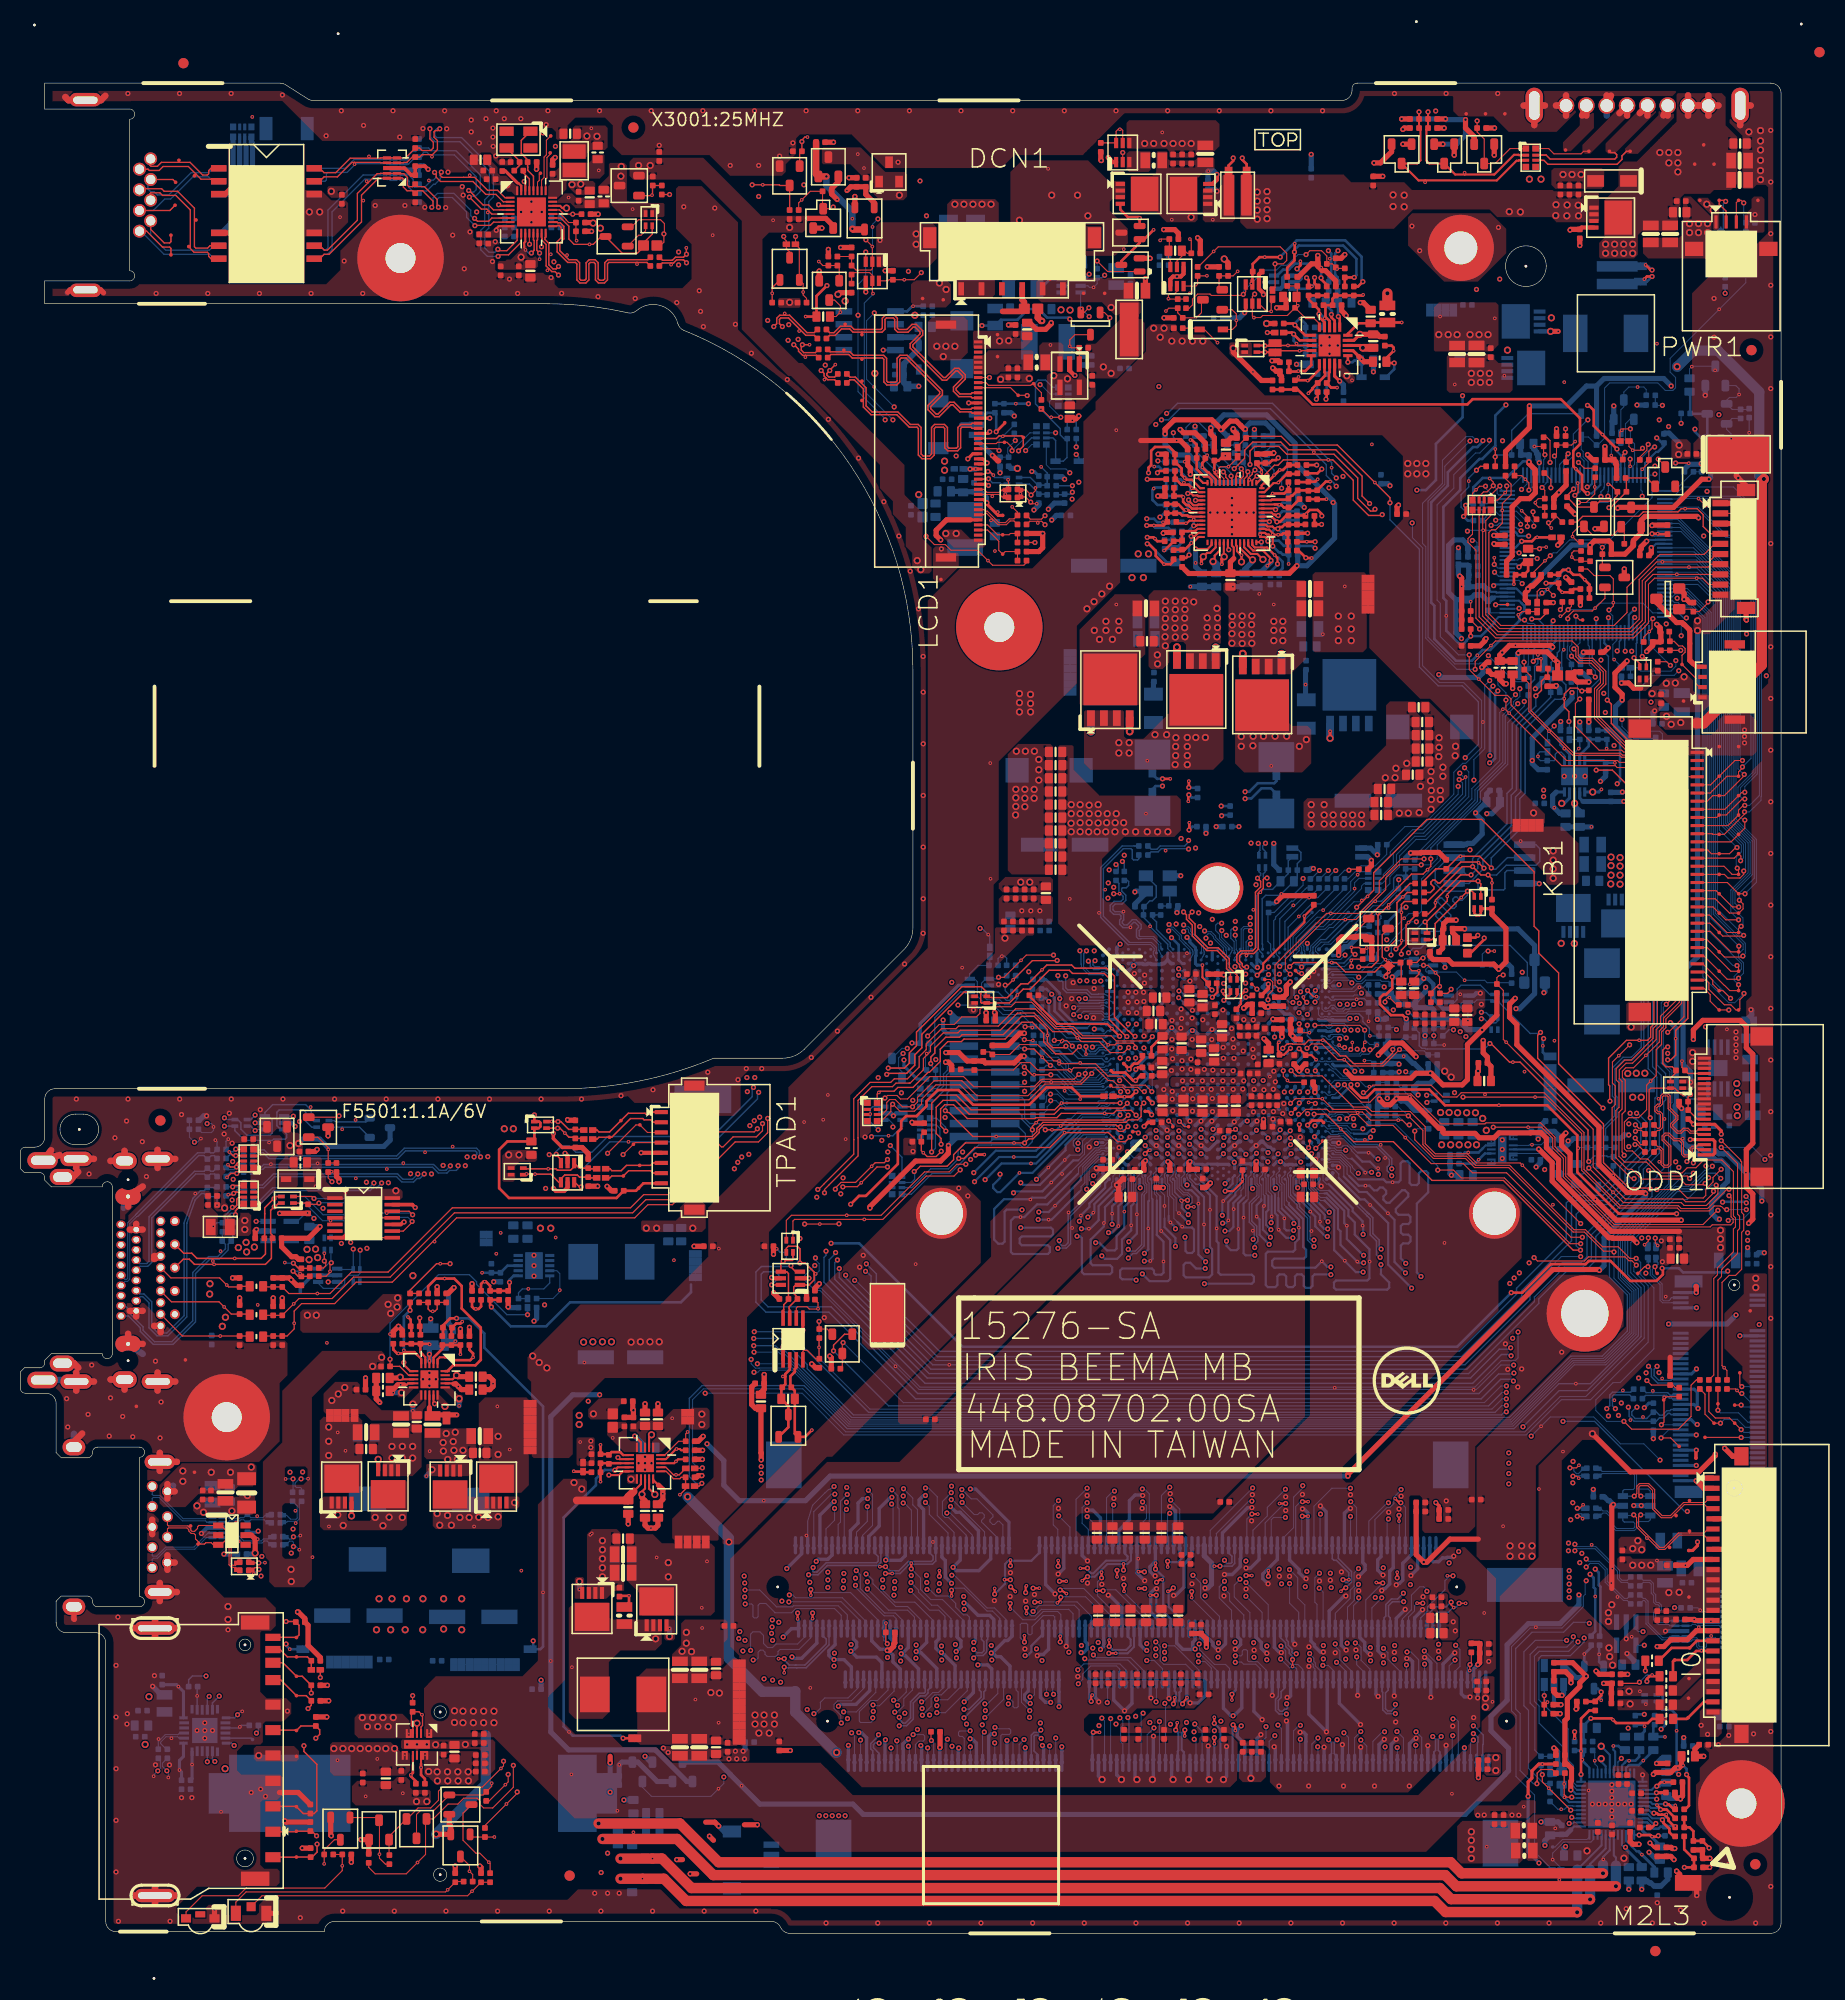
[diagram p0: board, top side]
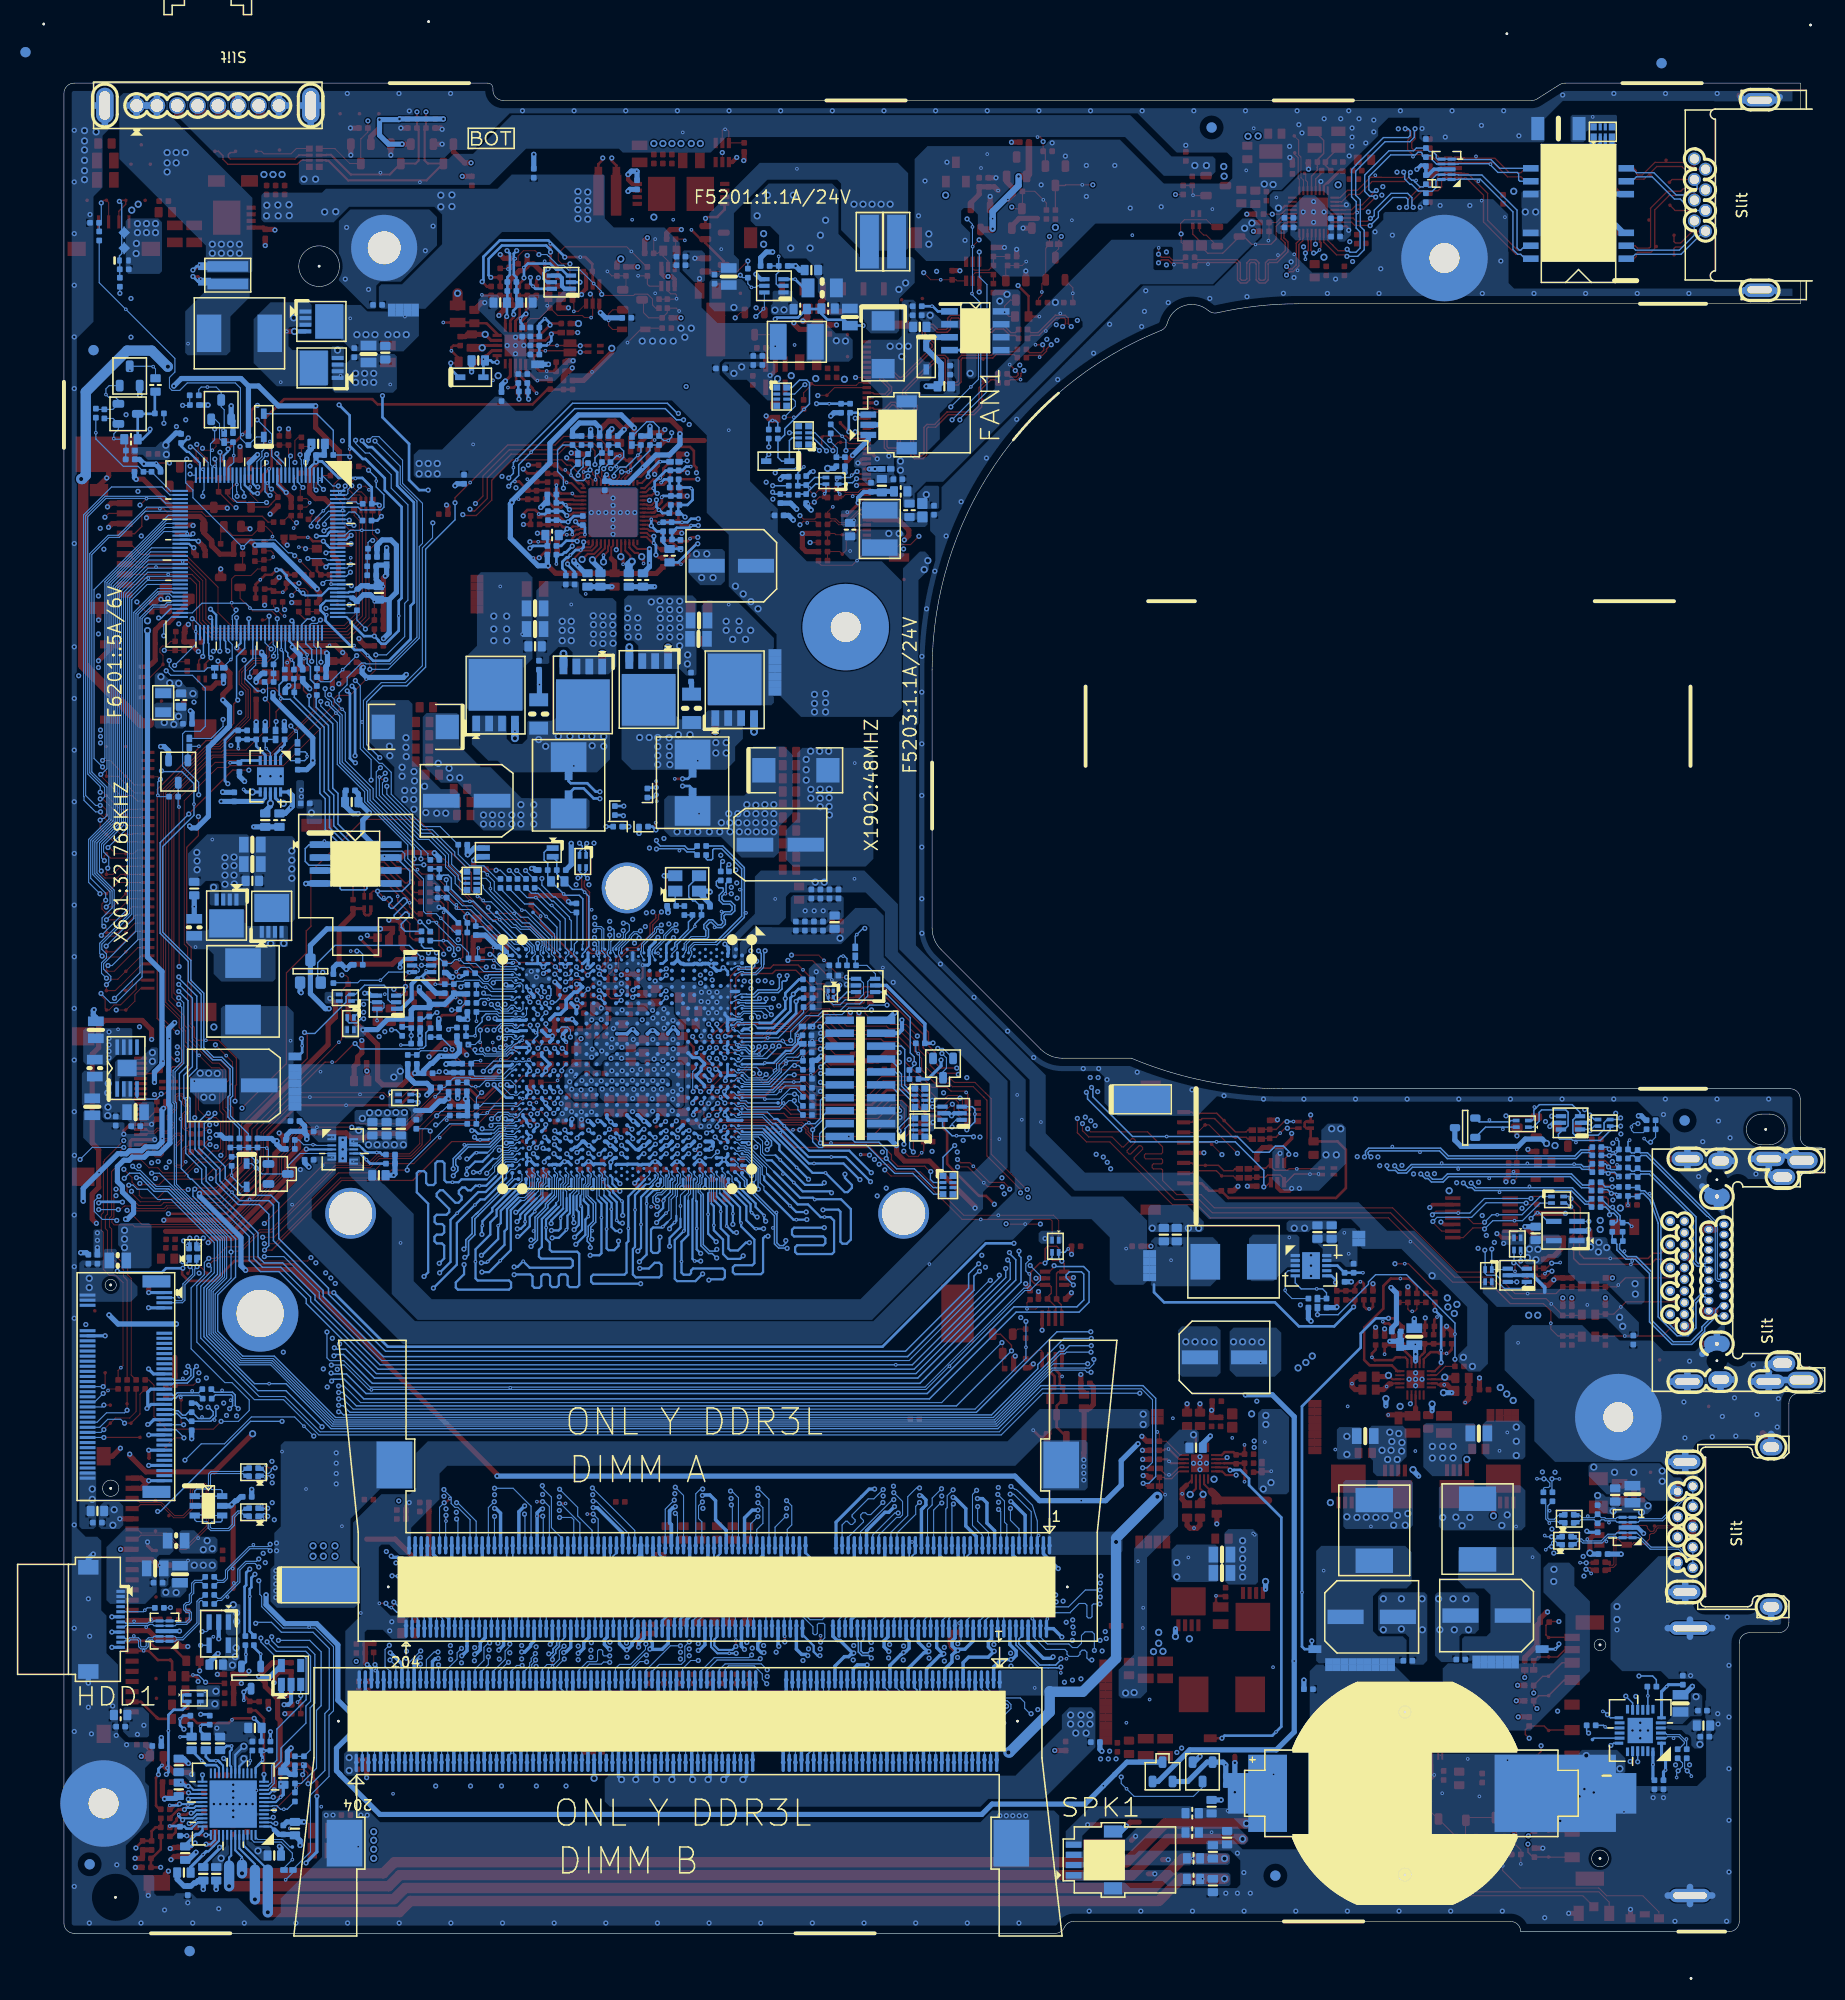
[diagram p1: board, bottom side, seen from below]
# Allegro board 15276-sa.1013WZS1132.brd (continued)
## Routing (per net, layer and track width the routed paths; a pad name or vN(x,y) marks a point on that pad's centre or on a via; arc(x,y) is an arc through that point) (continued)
L_BKLT_EN_EC: length 5.1
  TOP w0.102: v1(150.91,145.3) 151.11,145.5 R2445.1 R2444.2 152.6,146.38 v2(152.94,146.72)
  BOTTOM w0.102: KBC24.9 151.02,145.14 150.91,145.25 v1(150.91,145.3)
LAN_ENABLE_R_C: length 15.4
  TOP w0.127: R3021.2 Q3001.D 74.72,171.91 74.66,171.97 v2(73.03,171.97) v1(71.99,171.97) ; R3022.1 v1(63.86,171.02)
  L4 w0.127: v1(71.99,171.97) 64.82,171.97 v1(63.86,171.02)
LAN_MDI0N: length 28.5
  TOP w0.127: LOM30.2 47.51,170.3 46.78,171.03 45.79,171.03 44.52,172.3 41.33,172.3 40.91,172.72 40.91,173.03 v1(40.75,173.19)
  BOTTOM w0.127: v2(40.19,172.4) 40.32,172.27 ; 40.32,172.27 39.81,171.77 39.49,171.77 EC3102.2 38.93,171.74 38.77,171.74 38.64,171.87 38.64,172.51 38.18,172.97 U3101.9 U3101.2 36.06,172.97 36.03,172.94 33.71,172.94 30.26,169.48 30.26,165.77 30.03,165.54 29.9,165.54 29.47,165.97 XF3101.11 ; 40.32,172.27 40.47,172.43 40.62,172.43 40.9,172.71 40.9,173.04 v1(40.75,173.19)
LAN_MDI0P: length 28.4
  TOP w0.127: 44.2,172.71 44.69,172.71 45.96,171.44 46.95,171.44 47.68,170.7 LOM30.1 ; 44.2,172.71 v2(44.2,172.91) ; 44.2,172.71 43.62,172.71 41.5,172.71 41.32,172.89 41.32,173.12 v1(41.41,173.22)
  BOTTOM w0.127: v1(41.41,173.22) 41.31,173.11 41.31,172.54 40.79,172.02 40.64,172.02 39.98,171.36 39.44,171.36 EC3101.2 39.03,171.33 38.6,171.33 38.23,171.7 38.23,172.34 38.08,172.49 U3101.10 U3101.1 36.06,172.49 36.03,172.53 33.88,172.53 30.67,169.31 30.67,165.6 30.2,165.14 29.9,165.14 29.47,164.7 XF3101.12
LAN_MDI1N: length 26.2
  TOP w0.127: 46.1,169.37 45.89,169.58 45.35,169.58 v1(44.17,170.77) ; 46.1,169.37 v2(45.98,169.25) ; 46.1,169.37 46.38,169.1 47.31,169.1 47.31,169.1 47.47,169.1 47.48,169.1 LOM30.5
  BOTTOM w0.127: v1(44.17,170.77) 44.25,170.85 44.77,170.85 45.24,171.32 45.24,172.93 42.86,175.32 40.43,175.32 40.16,175.59 EC3104.2 38.88,175.25 38.55,175.25 38.21,174.91 38.21,174.61 38.09,174.49 U3101.6 U3101.5 36.06,174.49 36.03,174.46 32.83,174.46 31.97,173.59 XF3101.7
LAN_MDI1P: length 26.2
  TOP w0.127: v1(44.1,171.41) 44.15,171.41 44.55,171.01 44.61,170.95 44.61,170.9 45.52,169.99 46.06,169.99 46.54,169.51 47.48,169.51 47.48,169.5 LOM30.4
  BOTTOM w0.127: XF3101.8 29.98,172.32 30.11,172.45 30.11,173.06 30.23,173.19 32.14,173.19 33,174.05 36.03,174.05 36.06,174.01 U3101.4 U3101.7 38.19,174.01 38.62,174.44 38.62,174.74 38.72,174.84 39.09,174.84 EC3103.2 39.45,174.7 39.58,174.83 39.58,175.06 39.71,175.18 40,175.18 40.26,174.92 40.49,174.92 ; 40.49,174.92 42.69,174.92 44.84,172.77 44.84,171.49 44.61,171.26 44.3,171.26 44.15,171.41 v1(44.1,171.41) ; 40.49,174.92 v2(40.49,174.74)
LAN_MDI2N: length 29.4
  TOP w0.127: XF3102.8 29.47,165.97 29.9,165.54 30.21,165.54 33.15,168.49 33.15,171.12 34.21,172.18 ; v1(41.13,169.76) 41,169.89 41,170.53 39.75,171.79 39.09,171.79 EC3107.2 38.6,171.79 38.21,171.79 38.08,171.92 38.08,172.7 37.72,173.06 37.47,173.06 37.44,173.1 U3102.2 U3102.9 35.43,173.1 35.39,173.06 35.09,173.06 34.21,172.18 ; 34.21,172.18 v2(34.07,172.32) ; LOM30.7 47.48,168.3 47.48,168.3 46.55,168.3 46.24,167.98 44.74,167.98 v1(44.71,167.96)
  BOTTOM w0.127: v1(44.71,167.96) 43.9,168.77 43.9,169.3 42.48,170.72 41.19,170.72 41,170.54 41,169.89 v1(41.13,169.76)
LAN_MDI2P: length 29.3
  TOP w0.127: v1(40.47,169.76) 40.6,169.89 40.6,170.37 39.58,171.38 39.09,171.38 EC3108.2 38.6,171.38 38.04,171.38 37.68,171.75 37.68,172.53 37.55,172.66 37.42,172.66 37.39,172.62 U3102.1 U3102.10 35.43,172.62 35.39,172.66 35.26,172.66 33.56,170.95 33.56,170.42 ; v1(44.69,168.67) 44.97,168.39 46.07,168.39 46.38,168.71 47.31,168.71 47.31,168.71 47.47,168.71 47.48,168.7 LOM30.6 ; 33.56,170.42 33.56,168.32 30.38,165.14 29.88,165.14 29.45,164.7 XF3102.7 ; 33.56,170.42 v2(33.74,170.42)
  BOTTOM w0.127: v1(40.47,169.76) 40.6,169.89 40.6,170.71 41.02,171.13 42.65,171.13 44.3,169.47 44.3,168.94 44.57,168.67 v1(44.69,168.67)
LAN_MDI3N: length 37.2
  TOP w0.127: v2(34.3,174.76) 34.3,174.58 ; 34.3,174.58 35.39,174.58 35.43,174.62 U3102.6 U3102.5 37.69,174.62 37.73,174.58 37.85,174.58 38.84,175.57 EC3105.2 39.28,175.59 39.52,175.35 40.37,175.35 40.62,175.6 40.62,176.16 40.29,176.49 v1(40.29,177.48) ; 34.3,174.58 32.44,174.58 31.02,173.16 29.88,173.16 29.45,173.59 XF3102.12 ; LOM30.10 49.27,166.51 49.28,166.5 49.28,166.34 48.03,165.09 47.15,165.09 v1(47,164.93)
  BOTTOM w0.127: v1(47,164.93) 45.94,164.93 45.29,165.58 45.29,167.49 45.68,167.88 45.68,170.5 46.13,170.95 46.13,173.3 45.68,173.76 45.68,173.77 43.24,176.21 40.8,176.21 40.37,176.64 40.37,177.4 v1(40.29,177.48)
LAN_MDI3P: length 37.2
  TOP w0.127: XF3102.11 29.45,172.32 29.88,172.76 31.19,172.76 32.61,174.18 32.87,174.18 ; v1(41.26,177.48) 41.08,177.3 40.82,177.3 40.7,177.18 40.7,176.66 41.03,176.33 41.03,175.43 40.54,174.94 39.52,174.94 39.28,174.7 EC3106.2 38.76,174.78 38.62,174.78 38.02,174.18 37.73,174.18 37.69,174.14 U3102.4 U3102.7 35.43,174.14 35.39,174.18 32.87,174.18 ; 32.87,174.18 v2(32.87,174) ; LOM30.9 48.87,167.21 48.87,166.5 48.4,166.03 47.86,165.49 47.11,165.49 v1(46.97,165.63)
  BOTTOM w0.127: v1(41.26,177.48) 40.96,177.48 40.77,177.3 40.77,176.81 40.97,176.62 43.41,176.62 46.08,173.94 46.08,173.93 46.54,173.47 46.54,170.78 46.08,170.33 46.08,167.71 45.7,167.33 45.7,165.75 46.11,165.34 46.68,165.34 v1(46.97,165.63)
LAN_TXN_C_PCH_RXN0: length 20.5
  TOP w0.14: 53.64,164.92 53.07,165.49 53.07,166.25 53.46,166.65 53.46,167.89 53.11,168.24 52.88,168.24 52.81,168.3 LOM30.18 ; 53.64,164.92 v2(53.78,165.06) ; 53.64,164.92 53.96,164.6 54.72,164.6 55.01,164.31 55.01,162.72 55.15,162.58 55.52,162.58 55.66,162.72 55.66,164.31 55.95,164.6 56.54,164.6 56.84,164.31 56.84,162.72 56.98,162.58 57.35,162.58 57.49,162.72 57.49,164.31 57.78,164.6 61.73,164.6 C3016.1
LAN_TXP_C_PCH_RXP0: length 20.5
  TOP w0.14: 60.66,164.34 57.89,164.34 57.75,164.2 57.75,162.61 57.46,162.32 56.87,162.32 56.57,162.61 56.57,164.2 56.43,164.34 56.07,164.34 55.93,164.2 55.93,162.61 55.63,162.32 55.04,162.32 54.74,162.61 54.74,164.2 54.6,164.34 53.85,164.34 52.8,165.38 52.8,166.36 53.19,166.76 53.19,167.78 53,167.97 52.81,167.97 52.75,167.9 LOM30.17 ; 60.66,164.34 61.63,164.34 C3014.1 ; 60.66,164.34 v2(60.66,164.17)
LANXIN: length 6.7
  TOP w0.14: LOM30.28 50.47,172.83 49.91,173.4 49.91,173.72 49.9,173.73 C3001.1 49.9,174.43 49.28,175.05 49.28,176.34 X3001.1
LANXOUT: length 2.2
  TOP w0.14: LOM30.29 50.07,172.55 49.47,173.15 R3002.1
LANXOUT.R: length 3
  TOP w0.14: R3002.2 49.11,173.89 C3011.1 49.11,174.31 X3001.3
LCD_BRIGHTNESS: length 8.4
  TOP w0.14: v1(98.19,145.8) 98.66,146.27 AFTP5203.1 98.51,147.27 96.27,147.27 96.01,147.02 LCD1.20
  BOTTOM w0.14: v1(98.19,145.8) 99.47,147.08 RN5201.2
LCD_TST: length 73.2
  TOP w0.102: R2417.2 158.24,146.23 v2(158.6,145.87) 159.38,145.87 v1(159.57,146.06)
  L3 w0.102: v1(159.57,146.06) 159.57,145.6 158.54,144.56 156.49,144.56 154.67,146.39 147.83,146.39 146.23,144.79 142.15,144.79 141.63,145.31 124.88,145.31 123.32,146.87 115.84,146.87 114.96,147.76 114.96,148.78 113.38,150.35 106.69,150.35 103,146.67 103,143.88 v1(103.23,143.65)
  BOTTOM w0.102: v1(103.23,143.65) 102.85,144.03 101.33,144.03 100.93,144.43 RN5201.8
LCD_TST_C: length 12.5
  TOP w0.102: LCD1.10 97.4,152.02 AFTP5207.1 99.02,151.27 v1(99.04,151.25)
  L3 w0.102: v1(98.89,145.83) 99.42,146.37 99.42,149.58 98.74,150.26 98.74,150.79 99.04,151.09 v1(99.04,151.25)
  BOTTOM w0.102: RN5201.1 99.49,146.43 v1(98.89,145.83)
LCD_TST_EN: length 66.3
  TOP w0.102: v1(105.11,159.88) 104.65,159.42 D5201.2 ; R2417.1 157.35,147.65 v2(157.54,147.84) 157.67,147.97 v1(158.38,147.97)
  L3 w0.102: v1(105.11,159.88) 105.57,159.88 110.04,155.41 118.16,155.41 122.2,151.36 124.02,151.36 126.58,148.8 129.9,148.8 130.18,149.08 144.6,149.08 145.21,148.47 153.86,148.47 154.36,147.97 v1(158.38,147.97)
  BOTTOM w0.102: KBC24.28 158.62,144.3 158.79,144.47 158.79,146.49 158.38,146.9 v1(158.38,147.97)
LCDVDD:
  vias: v2(101.33,156.22)
LCDVDD_EN: length 5.5
  TOP w0.102: D5201.3 103.74,157.23 103.23,156.73 v2(103.23,156.09) 103.39,155.94 R5202.2 104.17,155.93 U5201.1
LDO1_CAP: length 4.4
  TOP w0.254: R2711.2 v2(161.7,14.87) 161.38,14.87 v1(160.97,14.46)
  BOTTOM w0.203: HDA27.27 160.46,14.11 160.81,14.46 v1(160.97,14.46)
  BOTTOM w0.305: v1(160.97,14.46) 161.22,14.46 161.58,14.82 C2702.2
LDO2_CAP: length 5
  BOTTOM w0.203: 159.19,8.06 158.99,8.06 158.47,8.57 158.47,8.57 157.95,9.1 HDA27.39
  BOTTOM w0.305: C2712.2 160.74,6.51 v2(159.51,7.74) 159.19,8.06
LDO3_CAP: length 3.2
  BOTTOM w0.203: v2(151.89,13.38) 151.89,13.38 152.36,12.91 HDA27.7
  BOTTOM w0.305: v2(151.89,13.38) 151.62,13.65 C2718.1
LDRQ0#: length 4.9
  BOTTOM w0.102: TP1903.1 127.06,100.39 124.95,98.28 CPU1.AP1
LED0: length 1.8
  TOP w0.102: LOM30.27 50.87,172.23 51.05,172.41 51.05,172.99 TP3003.1
LED1: length 5.8
  TOP w0.102: TP3002.1 51.75,176.35 51.75,174.93 51.52,174.7 51.52,172.68 51.27,172.44 LOM30.26
LED2: length 3.9
  TOP w0.102: LOM30.25 51.67,172.51 51.8,172.64 51.8,174.65 52.12,174.98 TP3001.1
LID_CLOSE#: length 37.3
  BOTTOM w0.102: KBC24.17 154.22,144.73 153.73,145.22 153.73,145.75 153.54,145.93 D2401.K 154.26,147.17 R2421.1 155.16,146.38 155.84,147.05 155.84,151.98 156.34,152.49 161.07,152.49 161.81,151.75 162.57,151.75 162.82,152 162.82,153.02 162.29,153.55 162.29,154.9 v2(167.11,159.73) 169.73,162.34 R6109.1
LID_CLOSE#_C: length 5.7
  TOP w0.102: v1(169.53,170.19) 169.27,170.44 AFTP6104.1 168.8,170.23 PWR1.3
  BOTTOM w0.102: R6109.2 169.73,168.22 EC6107.1 169.53,168.45 v1(169.53,170.19)
LINE1-L_C: length 2.4
  BOTTOM w0.254: v2(161.78,19.31) 161.75,19.34 C2907.2 160.64,20.39 R2922.1
LINE1-L_R: length 2.2
  BOTTOM w0.254: C2908.2 159.77,19.87 v2(159.77,20.37) 159.62,20.52 R2921.1
LINE1_L: length 4
  BOTTOM w0.203: HDA27.22 157.95,16.27 158.22,16.55
  BOTTOM w0.254: 158.22,16.55 159.2,16.55 v2(159.65,16.99) 160.64,17.98 C2907.1
LINE1_R: length 3.5
  BOTTOM w0.203: HDA27.21 157.55,16.5 157.84,16.8
  BOTTOM w0.254: 157.84,16.8 158.02,16.98 v2(158.25,16.98) 158.86,16.98 159.24,17.36 C2908.1
LINE1_VREFO_L: length 4.3
  TOP w0.254: v2(161,12.61) 161.35,12.26 v1(161.35,12.18) 161.69,12.18 161.7,12.17 161.95,12.17 162.64,11.48 162.64,11.45 R2912.1
  BOTTOM w0.203: v1(161.35,12.18) 161.3,12.18 161.14,12.33 160.41,12.33 160.23,12.51 HDA27.31
LINE1_VREFO_R: length 4.5
  TOP w0.254: R2913.1 162.64,12.2 162.15,12.69 161.87,12.69 v1(161.83,12.72)
  BOTTOM w0.203: HDA27.30 160.36,12.91 160.56,12.71 161.81,12.71 161.82,12.72 v1(161.83,12.72)
  BOTTOM w0.254: v1(161.83,12.72) 161.97,12.58 v2(162.8,12.58)
LOM_TCT:
  vias: v2(31.45,168.79) v3(28.43,169.3) v3(29.45,169.3)
LPC_AD0: length 56.9
  TOP w0.102: RN6501.4 142.85,141.63 v2(143.2,141.98) 143.54,142.33 v1(144.13,142.33)
  L3 w0.102: v1(142.07,114.64) 142.56,115.13 142.56,116.56 136.31,122.81 136.31,136.92 141.6,142.21 144.01,142.21 v1(144.13,142.33)
  BOTTOM w0.102: KBC24.126 145.18,141.07 144.13,142.12 v1(144.13,142.33) ; v1(142.07,114.64) 142.48,114.23 142.48,111.78 138.29,107.59 137.3,107.59 135.67,105.96 135.67,104.88 134.72,103.93 134.72,103.25 134.08,102.62 RN1901.4
LPC_AD1: length 57.2
  TOP w0.102: RN6501.3 143.5,141.33 143.93,141.77 144.28,141.77 v1(144.89,142.38) 144.89,142.73 v2(144.53,143.09)
  L3 w0.102: v1(141.59,114.11) 142.14,114.11 142.87,114.83 142.87,116.69 136.62,122.94 136.62,136.8 141.71,141.9 144.31,141.9 144.66,142.25 144.76,142.25 v1(144.89,142.38)
  BOTTOM w0.102: KBC24.127 145.42,141.47 145.27,141.62 145.27,142 v1(144.89,142.38) ; v1(141.59,114.11) 142.17,113.52 142.17,111.91 138.16,107.9 137.17,107.9 135.36,106.09 135.36,105.01 134.41,104.05 134.41,103.7 133.98,103.27 RN1901.3
LPC_AD2: length 55.9
  TOP w0.102: v2(142.17,113.73) 141.92,113.47 v1(141.54,113.47) ; RN6501.2 144,141.33 144.13,141.47 144.65,141.47 v1(145.54,142.35)
  L3 w0.102: v1(145.54,142.35) 145.13,141.95 144.79,141.95 144.43,141.59 141.84,141.59 136.92,136.67 136.92,123.07 143.17,116.82 143.17,114.7 141.94,113.47 v1(141.54,113.47)
  BOTTOM w0.102: v1(145.54,142.35) 145.54,142.31 145.62,142.23 145.62,142.08 145.83,141.87 KBC24.128 ; RN1901.2 133.94,103.77 134.07,103.9 134.07,104.15 135.06,105.13 135.06,106.22 137.05,108.2 138.04,108.2 141.87,112.04 141.87,113.14 v1(141.54,113.47)
LPC_AD3: length 55.4
  TOP w0.102: RN6501.1 145.32,140.96 v2(146.06,141.69) 146.21,141.84 v1(146.21,142.35)
  L3 w0.102: v1(141.44,112.81) 141.71,112.81 143.47,114.57 143.47,116.94 137.23,123.19 137.23,136.54 141.97,141.29 144.56,141.29 144.91,141.64 145.5,141.64 v1(146.21,142.35)
  BOTTOM w0.102: KBC24.1 146.75,142.35 v1(146.21,142.35) ; RN1901.1 133.56,104.81 134.75,106 134.75,106.34 136.96,108.55 137.95,108.55 141.44,112.04 v1(141.44,112.81)
LPC_FRAME#: length 65.4
  TOP w0.102: v1(148.39,141.95) 148.39,142.66 v2(148.04,143.01) 147.68,143.37 R6501.1 R1913.2
  L3 w0.102: v1(148.39,141.95) 147.53,142.81 141.54,142.81 137.45,138.72 v1(136.91,138.72)
  BOTTOM w0.102: R1901.1 130.6,103.71 131.88,104.99 133.28,104.99 134.41,106.12 R1914.1 136.19,108.85 137.82,108.85 141.01,112.04 141.01,114.19 141.89,115.07 142.18,115.07 143.74,116.63 143.74,121.25 141.98,123.01 139.6,123.01 137.94,124.67 137.94,136.26 136.94,137.26 136.94,138.69 v1(136.91,138.72) ; KBC24.3 148.62,142.17 v1(148.39,141.95)
LPC_FRAME#_DEBUG: length 43
  TOP w0.102: R6501.2 146.1,143.08 146.64,142.53 146.64,141.49 145.78,140.63 v2(145.78,139.96) 145.78,138.69 145.13,138.05 144.72,138.05 144.46,137.78 144.46,129.8 145.63,128.63 156.77,128.63 158.05,129.91 158.05,132.39 161.27,135.62 165.63,135.62 166.66,136.66 DB1.5
LPC_FRAME#_R: length 9.5
  BOTTOM w0.102: R1901.2 130.04,102.6 130.04,102.52 128.16,100.64 v2(128.16,100.63) 128.15,100.63 128.14,100.63 127.8,100.63 125.19,98.02 125.19,96.65 125.25,96.6 125.25,96.3 124.95,96 CPU1.AP2
LPC_LAD0_R: length 40.9
  TOP w0.102: DB1.9 166.09,132.65 165.46,133.28 v2(164.9,133.28) 160.76,133.28 160.15,132.68 160.15,128.87 158.7,127.41 145.12,127.41 143.19,129.35 143.19,136.03 142.4,136.81 142.4,137.17 142.85,137.62 RN6501.5
LPC_LAD1_R: length 39.7
  TOP w0.102: DB1.8 v2(162.95,133.65) 160.6,133.65 159.85,132.9 159.85,128.99 158.57,127.72 145.25,127.72 143.5,129.47 RN6501.6
LPC_LAD2_R: length 39.6
  TOP w0.102: DB1.7 166.33,134.65 166.05,134.38 v2(164.14,134.38) 160.89,134.38 159.54,133.03 159.54,129.12 158.45,128.02 145.38,128.02 143.85,129.55 143.85,139.46 143.89,139.51 143.89,139.88 RN6501.7
LPC_LAD3_R: length 39.5
  TOP w0.102: RN6501.8 144.65,139.44 144.15,138.95 144.15,129.68 145.5,128.33 158.32,128.33 159.24,129.25 159.24,133.16 160.97,134.88 v2(161.53,134.88) 166.08,134.88 166.85,135.65 DB1.6
LPC_PD#: length 6.6
  BOTTOM w0.102: TP1901.1 129.14,98.92 128.76,98.92 126.93,97.09 126.93,96.66 126.84,96.57 126.84,96.29 127.15,95.98 CPU1.AV2
LPC_RST#: length 66.2
  TOP w0.102: v2(150.6,138.21) 150.32,138.49 v1(150.32,138.73) 150.49,138.73 150.85,139.09 R2416.2 151.05,139.43 R6502.1
  L3 w0.102: v1(137.33,99.49) 137.33,100.4 144.76,107.83 144.76,110.68 144.1,111.34 144.1,117.18 138.11,123.17 138.11,123.96 138.11,123.96 138.11,136.11 141.92,139.91 142.55,139.91 143.31,140.68 149,140.68 150.32,139.35 v1(150.32,138.73)
  BOTTOM w0.102: v1(137.33,99.49) 136.76,99.49 134.88,97.61 134.88,97.58 134.54,97.24 134.17,97.24 133.4,96.47 R602.1
LPC_RST#_C: length 6
  BOTTOM w0.102: CPU1.AY4 128.16,94.95 128.39,94.95 128.58,95.13 128.87,95.13 128.93,95.08 130.26,95.08 130.95,95.77 132.38,95.77 R602.2 132.51,96.85 v2(132.44,96.91)
LPCCLK0: length 9.4
  BOTTOM w0.14: CPU1.AY2 129.78,97.47 130.44,97.47 131.98,99.01 132.63,99.01 R1919.1 132.69,99.63 133.36,100.3 v2(133.51,100.3) 133.59,100.3 133.84,100.05 133.84,99.83 133.51,99.51 R1911.2 133.52,99.37 R1906.2
LPCCLK1: length 15.3
  BOTTOM w0.102: 129.1,97.89 128.7,97.49 127.95,97.49 127.39,96.93 127.39,96.61 127.41,96.6 127.7,96.31 CPU1.AW2
  BOTTOM w0.14: R1907.1 R1912.1 136.28,104.68 R1920.2 136.1,103.87 135.9,104.08 135.4,104.08 135.09,103.77 135.09,102.7 133.89,101.5 v2(133.27,101.5) 132.92,101.5 130.97,99.55 130.77,99.55 129.1,97.89
M_A_A0: length 93
  TOP w0.216: v1(106.35,34.96) 106.36,34.96 v2(106.36,35.52)
  L3 w0.102: 121.79,73.54 121.16,74.17 121.16,76.16 121.6,76.59 v1(121.6,76.72)
  L3 w0.203: 121.79,73.54 121.79,72.53 123.52,70.81 123.52,67.33 123.22,67.03 123.22,59.73 117.94,54.44 117.94,53.03 109.35,44.44 109.35,41.28 106.64,38.56 106.64,35.39 107.55,34.47 107.55,32.65 110.29,29.91 110.29,27.65 110.6,27.34 111.66,27.34 v1(111.69,27.31)
  L4 w0.102: v1(106.35,34.96) 106.56,34.76 106.56,34.76 107.53,33.79 107.53,33.26 111.23,29.55 111.23,27.76 v1(111.69,27.31) 111.74,27.26 111.74,27.14 115.58,23.3 115.58,22.52 115.04,21.98 113.22,21.98 v1(112.58,22.62)
  BOTTOM w0.102: v1(112.58,22.62) 112.65,22.55 DM2.98 ; DM1.98 107.75,31.41 105.95,33.21 105.95,34.56 v1(106.35,34.96)
  BOTTOM w0.216: v1(121.6,76.72) 121.54,76.66 121.48,76.66 CPU1.AG38
M_A_A1: length 85.3
  TOP w0.216: v2(102.88,34.63) v1(102.22,34.63)
  L3 w0.102: v1(116.15,78.28) 116.58,77.85 116.58,76.47 115.6,75.5 115.6,72.5 115.68,72.43
  L3 w0.203: 115.68,72.43 115.81,72.3 115.81,67.98 115.56,67.74 115.56,64.39 108.87,57.7 108.87,55.88 108.51,55.52 108.23,55.52 107.63,56.11 107.34,56.11 107.06,55.83 107.06,55.54 107.65,54.94 107.65,54.66 107.36,54.37 107.08,54.37 106.52,54.93 106.23,54.93 105.94,54.64 105.94,54.35 106.5,53.79 106.5,53.51 104.36,51.37 104.36,48.22 102.69,46.54 102.69,40.55 102.15,40.01 102.15,38.88 101.59,38.32 101.59,35.15 102.12,34.63 v1(102.22,34.63)
  L4 w0.102: v1(110.8,26.83) 110.75,26.83 102.95,34.63 v1(102.22,34.63) 102.75,35.16 102.75,35.49 104.48,37.22 106.26,37.22 107.47,38.44 107.47,42.06 v1(107.55,42.14)
  BOTTOM w0.102: DM2.97 112.35,26.02 111.54,26.83 v1(110.8,26.83) ; v1(107.55,42.14) 107.45,42.04 DM1.97
  BOTTOM w0.216: v1(116.15,78.28) 116.3,78.28 CPU1.W35
M_A_A2: length 88.3
  TOP w0.216: v2(102.9,33.41) 102.37,33.77 v1(102.29,33.77)
  L3 w0.102: v1(116.15,76.68) 116.15,76.39 115.2,75.44 115.2,72.37 115.29,72.28
  L3 w0.203: v1(106.03,28.61) 105.88,28.61 101.3,33.19 101.3,34.48 101.09,34.69 101.09,38.53 101.58,39.03 101.58,46.16 103.86,48.43 103.86,51.58 105.38,53.11 105.38,54.93 115.06,64.61 115.06,67.94 115.4,68.29 115.4,72.17 115.29,72.28
  L4 w0.102: v1(102.29,33.77) 102.29,33.77 102.47,33.77 105.81,30.43 105.81,30.29 105.69,30.16 105.69,29.99 105.8,29.87 105.97,29.87 106.1,30 106.24,30 106.46,29.78 106.46,29.35 106.03,28.92 v1(106.03,28.61) 106.08,28.66 107.3,28.66 110.5,25.46 110.5,23.2 112.05,21.65 v1(112.05,20.84)
  BOTTOM w0.102: v1(102.29,33.77) 102.29,33.77 102.45,33.92 104.6,33.92 107.15,31.37 DM1.96 ; DM2.96 v1(112.05,20.84)
  BOTTOM w0.216: v1(116.15,76.68) 116.3,76.68 CPU1.W38
M_A_A3: length 91.5
  TOP w0.216: v2(102.09,36.66) v1(102.09,36.1)
  L3 w0.102: v1(116.15,79.08) 116.58,78.65 116.58,78.26 116.78,78.06 116.78,76.39 115.93,75.54 115.93,72.82
  L3 w0.203: 115.93,72.82 116.24,72.52 116.24,67.68 116.07,67.51 116.07,64.18 109.38,57.49 109.38,55.67 104.87,51.16 104.87,48.01 103.19,46.33 103.19,40.34 102.66,39.8 102.66,38.67 102.1,38.11 102.1,36.12 v1(102.09,36.1)
  L4 w0.102: v1(107.63,43.5) 107.55,43.5 106.89,42.84 106.89,40.04 106.79,39.94 106,39.94 105.9,39.84 105.9,39.63 106,39.53 106.79,39.53 106.89,39.43 106.89,39.13 106.53,38.77 105.67,38.77 105.54,38.64 105.54,38.36 105.67,38.24 106.36,38.24 106.48,38.11 106.48,37.91 106.36,37.78 104.3,37.78 102.88,36.36 102.88,36.23 102.75,36.1 v1(102.09,36.1) 101.66,35.67 101.66,34.58 102.04,34.2 102.5,34.2 111.69,25 111.69,23.56 111.72,23.54 v1(111.72,22.77)
  BOTTOM w0.102: DM1.95 106.85,42.85 107.5,43.5 v1(107.63,43.5) ; v1(111.72,22.77) 111.75,22.8 DM2.95
  BOTTOM w0.216: v1(116.15,79.08) 116.3,79.08 CPU1.W34
M_A_A4: length 86.7
  TOP w0.216: v1(102.34,33.06) 102.34,32.83 v2(102.01,32.5)
  L3 w0.102: 114.56,74.1 114.61,74.16 114.61,76.08 114.78,76.25 114.78,76.42 v1(115.05,76.68)
  L3 w0.203: 114.56,74.1 114.13,73.67 114.13,68.71 114.08,68.67 114.08,67.98 114.55,67.51 114.55,64.82 104.88,55.14 104.88,53.32 103.35,51.79 103.35,48.64 101.07,46.37 101.07,39.24 100.58,38.74 100.58,34.48 100.79,34.26 100.79,32.75 101.17,32.38 v1(105.49,28.05)
  L4 w0.102: v1(102.34,33.06) 102.34,32.6 104.03,30.92 104.17,30.92 104.43,31.18 104.6,31.18 104.72,31.06 104.72,30.89 104.46,30.63 104.46,30.48 104.6,30.34 104.75,30.34 104.97,30.57 105.12,30.57 105.26,30.42 105.26,30.28 105.03,30.05 105.03,29.91 105.49,29.45 v1(105.49,28.05) 106.33,27.21 106.33,26.71 111.56,21.47 111.56,20.25 v1(111.51,20.2)
  BOTTOM w0.102: DM1.92 105.95,31.94 104.78,33.11 102.39,33.11 v1(102.34,33.06) ; DM2.92 110.85,19.54 v1(111.51,20.2)
  BOTTOM w0.216: v1(115.05,76.68) 115.2,76.68 CPU1.U38
M_A_A5: length 87.3
  TOP w0.216: v1(99.63,33.95) v2(100.24,33.95)
  L3 w0.102: 113.32,73.92 114.18,74.79 114.18,76.3 114.38,76.5 114.38,76.97 v1(115.02,77.61)
  L3 w0.203: 113.32,73.92 113.32,70.83 112.6,70.11 112.6,66.99 113.53,66.06 113.53,65.24 103.86,55.57 103.86,53.74 103.5,53.38 103.21,53.38 102.61,53.99 102.32,53.99 102.03,53.7 102.03,53.41 102.64,52.81 102.64,52.52 102.33,52.21 102.33,49.06 100.06,46.79 100.06,39.66 99.56,39.17 99.56,34.01 v1(99.63,33.95)
  L4 w0.102: v1(105.56,27.38) 105.06,27.87 105.06,29.45 101.28,33.23 101.13,33.23 100.91,33.01 100.77,33.01 100.62,33.15 100.62,33.3 100.85,33.52 100.85,33.67 100.57,33.95 v1(99.63,33.95) 99.63,34.35 99.82,34.54 100.74,34.54 100.87,34.67 100.87,35.65 104.05,38.82 105.21,38.82 105.34,38.95 105.34,39.3 105.21,39.43 103.89,39.43 103.77,39.56 103.77,39.79 103.89,39.91 104.74,39.91 104.94,40.12 v1(104.94,40.99)
  BOTTOM w0.102: v1(105.56,27.38) 105.82,27.11 109.23,27.11 110.55,25.79 DM2.91 ; v1(104.94,40.99) 104.95,40.98 104.95,40.97 105.65,40.27 DM1.91
  BOTTOM w0.216: CPU1.U37 115.2,77.48 115.15,77.48 v1(115.02,77.61)
M_A_A6: length 88.8
  TOP w0.216: v2(100.34,32.57) v1(99.78,32.57)
  L3 w0.102: 114.18,74.28 114.38,74.48 114.38,76.22 114.58,76.42 114.58,76.83 114.93,77.18 115.2,77.18 115.45,77.43 115.45,77.88 v1(115.05,78.28)
  L3 w0.203: 114.18,74.28 113.75,73.85 113.75,70.32 113.11,69.68 113.11,67.2 114.04,66.27 114.04,65.03 104.37,55.35 104.37,53.53 102.84,52 102.84,48.85 100.57,46.58 100.57,39.45 100.07,38.95 100.07,34.27 100.29,34.05 100.29,32.4 100.81,31.88 v1(104.38,28.31)
  L4 w0.102: v1(110.45,21.65) 110.45,21.88 105.14,27.19 105.14,27.19 104.89,27.44 104.89,27.62 104.76,27.75 104.76,27.89 104.38,28.27 v1(104.38,28.31) 104.38,29.02 100.82,32.57 v1(99.78,32.57)
  BOTTOM w0.102: v1(110.45,21.65) 110.25,21.46 DM2.90 ; DM1.90 105.35,31.19 103.94,32.6 99.8,32.6 v1(99.78,32.57)
  BOTTOM w0.216: v1(115.05,78.28) 115.2,78.28 CPU1.U34
M_A_A7: length 90.8
  TOP w0.216: v2(102.29,29.22) v1(102.29,28.66)
  L3 w0.102: v1(113.95,78.28) 113.51,77.85 113.51,76.5 113.52,76.49 113.52,75.31
  L3 w0.203: v1(102.29,28.66) 102.29,29.12 100.29,31.13 99.17,31.13 98.41,31.89 98.41,39.45 99.04,40.08 99.04,52.18 111.58,64.72 111.58,70.79 112.38,71.59 112.38,72.57 111.94,73.01 111.94,73.59 113.52,75.18 113.52,75.31
  L4 w0.102: v1(108.95,21.22) 109.05,21.32 109.05,22.06 108.8,22.31 108.79,22.31 104.4,26.71 104.21,26.71 103.61,27.31 103.61,28.21 103.16,28.66 v1(102.29,28.66) 102.64,29 102.64,29.18 102.36,29.46 102.18,29.46 101.82,29.1 101.68,29.1 101.53,29.24 101.53,29.38 101.9,29.75 101.9,29.89 101.76,30.04 101.61,30.04 101.25,29.67 101.1,29.67 100.96,29.82 100.96,29.96 101.32,30.32 101.32,30.47 101.18,30.61 101.04,30.61 100.67,30.25 100.53,30.25 100.38,30.39 100.38,30.52 100.75,30.89 100.75,31.07 100.61,31.21 100.43,31.21 100.21,31 100.01,31 99.88,31.13 99.88,31.4 v1(99.63,31.66)
  BOTTOM w0.102: v1(99.63,31.66) 100.24,32.27 103.69,32.27 104.15,31.81 DM1.86 ; DM2.86 109.05,21.12 v1(108.95,21.22)
  BOTTOM w0.216: CPU1.R35 114.1,78.28 v1(113.95,78.28)
M_A_A8: length 89.4
  TOP w0.216: v1(98.89,33.51) 98.89,34.1 v2(98.97,34.17)
  L3 w0.203: v1(113.95,76.68) 113.9,76.63 113.9,75.07 112.91,74.08 112.91,71.26 112.09,70.45 112.09,64.51 101.52,53.95 101.52,52.33 101.32,52.12 99.85,52.12 99.65,51.92 99.65,51.51 99.85,51.31 101.32,51.31 101.52,51.11 101.52,50.7 101.32,50.5 99.85,50.5 99.65,50.29 99.65,49.89 99.85,49.68 101.32,49.68 101.52,49.48 101.52,48.97 99.55,47 99.55,39.87 99.05,39.38 99.05,33.68 v1(98.89,33.51)
  L4 w0.102: v1(104.71,27.01) 104.34,27.01 103.92,27.43 103.92,28.34 100.13,32.12 99.62,32.12 99.35,32.39 99.35,32.98 98.89,33.44 v1(98.89,33.51) 98.89,34.12 103.23,38.47 103.23,39.91 104.5,41.18 104.5,41.92 v1(104.93,42.35)
  BOTTOM w0.102: DM2.89 109.95,25.88 108.95,26.88 104.83,26.88 v1(104.71,27.01) ; DM1.89 105.05,39.72 104.45,40.33 104.45,41.86 v1(104.93,42.35)
  BOTTOM w0.216: CPU1.R38 114.1,76.68 v1(113.95,76.68)
M_A_A9: length 91.5
  TOP w0.216: v2(97.39,36.71) v1(97.39,36.16)
  L3 w0.102: v1(112.85,76.68) 112.85,76.47 112.45,76.08 112.45,75.04 111.13,73.72 111.13,73.44
  L3 w0.203: v1(97.39,36.16) 97.39,39.87 98.03,40.5 98.03,52.6 98.78,53.36 98.78,53.64 98.31,54.11 98.31,54.4 98.6,54.68 98.89,54.68 99.35,54.22 99.64,54.22 99.93,54.51 99.93,54.79 99.46,55.26 99.46,55.55 99.75,55.83 100.04,55.83 100.5,55.37 100.79,55.37 101.08,55.66 101.08,55.94 100.61,56.41 100.61,56.7 100.9,56.98 101.19,56.98 101.65,56.52 101.94,56.52 108.69,63.27 108.69,64.72 110.08,66.11 110.08,67.08 110.42,67.42 110.42,71.26 111.13,71.97 111.13,73.44
  L4 w0.102: v1(104.02,25.92) 103.97,25.92 98.46,31.43 98.46,35.09 v1(97.39,36.16) 97.42,36.18 98.71,36.18 99.42,35.47 99.8,35.47 102.93,38.59 102.93,40.42 103.92,41.41 103.92,42.76 v1(104.93,43.78)
  BOTTOM w0.102: DM1.85 103.85,42.69 v1(104.93,43.78) ; DM2.85 108.75,25.91 108.16,26.5 104.6,26.5 v1(104.02,25.92)
  BOTTOM w0.216: v1(112.85,76.68) 113,76.68 CPU1.N38
M_A_A10: length 88.8
  TOP w0.216: v2(107.88,35.06) v1(107.88,35.7)
  L3 w0.102: v1(121.59,78.99) 122.28,78.3 122.28,74.53 122.64,74.18
  L3 w0.203: v1(107.88,35.7) 107.88,35.8 107.65,36.03 107.65,38.14 111.03,41.52 111.03,44.68 112.23,45.88 112.82,45.88 119.67,52.73 119.67,53.02 118.95,53.74 118.95,54.02 119.24,54.31 119.53,54.31 120.24,53.59 120.53,53.59 120.82,53.88 120.82,54.17 120.1,54.89 120.1,55.17 120.39,55.46 120.68,55.46 121.39,54.74 121.68,54.74 121.97,55.03 121.97,55.32 121.25,56.04 121.25,56.32 124.7,59.77 124.7,66.32 124.24,66.78 124.24,71.31 122.69,72.86 122.64,72.91 122.64,74.18
  L4 w0.102: v1(111.69,28.66) 111.69,29.78 107.88,33.59 v1(107.88,35.7) 108.08,35.9 108.34,36.16 108.52,36.16 110.32,37.96 110.32,39.43 110.19,39.56 109.83,39.56 109.71,39.68 109.71,39.85 109.83,39.97 110.05,39.97 110.17,40.08 110.17,40.25 110.05,40.37 109.88,40.37 109.76,40.49 109.76,40.66 109.88,40.78 110.17,40.78 110.29,40.9 110.29,41.18 110.17,41.31 109.74,41.31 109.61,41.44 109.61,42.3 109.74,42.43 v1(110.4,42.43)
  BOTTOM w0.102: DM2.107 115.35,25.74 114.64,26.45 112.48,26.45 112.12,26.81 112.12,28.23 v1(111.69,28.66) ; v1(110.4,42.43) 110.78,42.05 110.78,40.8 110.45,40.48 DM1.107
  BOTTOM w0.216: CPU1.AG34 121.29,78.68 v1(121.59,78.99)
M_A_A11: length 89.1
  TOP w0.216: v2(98.97,31.46) v1(98.97,32.01)
  L3 w0.102: 112.98,75.3 113.32,75.64 113.32,76.41 113.31,76.42 113.31,78.27 v1(113.97,78.93)
  L3 w0.203: v1(103.14,27.65) 101.92,27.65 97.9,31.68 97.9,39.66 98.53,40.29 98.53,52.39 109.2,63.06 109.2,64.51 110.08,65.39 110.62,65.39 111.06,65.82 111.06,71.05 111.63,71.63 111.63,73.72 112.98,75.07 112.98,75.3
  L4 w0.102: v1(98.97,32.01) 98.97,31.38 102.69,27.65 v1(103.14,27.65) 103.13,27.64 103.13,27.34 104.12,26.35 104.32,26.35 108.16,22.51 v1(108.16,21.19)
  BOTTOM w0.102: DM1.84 103.55,31.44 103.13,31.86 100.44,31.86 100.06,31.48 100.06,31.48 99.81,31.23 99.45,31.23 98.97,31.71 v1(98.97,32.01) ; DM2.84 108.45,18.63 108.23,18.85 108.23,20.21 108.45,20.43 108.45,20.91 v1(108.16,21.19)
  BOTTOM w0.216: v1(113.97,78.93) 114.25,78.93 CPU1.R34
M_A_A12: length 90.5
  TOP w0.216: v2(96.81,34.78) 97.34,34.78 v1(97.39,34.77)
  L3 w0.102: 110.69,73.61 111.71,74.63 112.22,75.14 112.22,76.19 112.38,76.35 112.38,77.01 v1(112.85,77.48)
  L3 w0.203: 110.69,73.61 110.69,72.32 109.91,71.54 109.91,67.68 109.58,67.34 109.58,66.32 108.19,64.93 108.19,63.48 102.49,57.79 100.75,57.79 97.52,54.56 97.52,40.71 96.88,40.08 96.88,35.28 v1(97.39,34.77)
  L4 w0.102: v1(104.07,24.55) 103.59,25.03 103.59,25.87 98.15,31.3 98.15,34.01 v1(97.39,34.77) 97.39,34.8 96.96,35.23 96.96,36.33 97.21,36.59 98.74,36.59 99.35,35.98 99.88,35.98 100.16,36.25 100.16,36.4 99.72,36.84 99.72,37.01 99.84,37.13 100,37.13 100.45,36.69 100.59,36.69 100.73,36.83 100.73,36.97 100.23,37.48 100.23,37.65 100.35,37.77 100.52,37.77 101.02,37.26 101.16,37.26 101.31,37.4 101.31,37.55 100.82,38.04 100.82,38.21 100.94,38.33 101.1,38.33 101.6,37.84 101.74,37.84 102.62,38.72 102.62,40.57 v1(102.14,41.06)
  BOTTOM w0.102: DM2.83 108.15,25.98 107.83,26.3 105.29,26.3 104.5,25.51 104.5,24.98 v1(104.07,24.55) ; DM1.83 103.25,39.95 v1(102.14,41.06)
  BOTTOM w0.216: CPU1.N37 113,77.48 v1(112.85,77.48)
M_A_A13: length 85.2
  TOP w0.216: v2(112.33,34.78) 112.08,34.78 v1(111.77,34.53)
  L3 w0.102: 127.86,74.09 127.11,74.09 125.5,75.7 125.5,76.79 125.17,77.13 124.78,77.13 124.52,77.39 124.52,78.54 v1(124.92,78.94)
  L3 w0.127: 128.04,74.09 127.86,74.09
  L3 w0.203: 128.04,74.09 128.04,74.09 130.08,72.05 130.08,55.29 122.49,47.7 120.39,47.7 116.64,43.96 116.64,41.22 112.22,36.8 112.22,34.99 v1(111.77,34.53)
  L4 w0.102: v1(113.16,42.61) 113.49,42.28 113.49,36.26 v1(111.77,34.53) 112.71,34.53 112.91,34.33 112.91,31.51 v1(115.96,28.46)
  BOTTOM w0.102: v1(115.96,28.46) 116,28.42 116,27.91 117.46,26.45 118.55,26.45 118.95,26.05 DM2.119 ; DM1.119 114.05,41.72 v1(113.16,42.61)
  BOTTOM w0.216: CPU1.AN34 124.66,78.68 v1(124.92,78.94)
M_A_A14: length 89.5
  TOP w0.216: v2(97.37,31.89) v1(97.37,32.45)
  L3 w0.102: v1(111.75,76.68) 111.75,75.81 110.76,74.82
  L3 w0.203: 110.76,74.82 110.24,74.31 110.03,74.31 108.82,73.1 108.82,69.23 107.99,68.39 107.99,66.17 107.17,65.35 107.17,63.9 102.07,58.8 100.33,58.8 96.5,54.98 96.5,41.13 95.87,40.5 95.87,34.77 96.83,33.81 96.83,31.99 99.96,28.87 v1(99.96,27.98)
  L4 w0.102: v1(97.37,32.45) 97.54,32.27 97.54,31.3 97.54,31.05 99.25,29.35 99.25,29.04 99.37,28.92 99.68,28.92 99.83,28.77 99.83,28.59 99.7,28.46 99.37,28.46 99.25,28.33 99.25,27.72 99.37,27.6 99.7,27.6 99.96,27.85 v1(99.96,27.98) 100.59,27.98 102.98,25.59 102.98,24.57 105.21,22.34 106.03,22.34 v1(107.25,21.12)
  BOTTOM w0.102: v1(97.37,32.45) 97.37,32.09 98.61,30.85 99.81,30.85 100.62,31.66 102.04,31.66 102.35,31.35 DM1.80 ; DM2.80 v1(107.25,21.12)
  BOTTOM w0.216: CPU1.L38 111.9,76.68 v1(111.75,76.68)
M_A_A15: length 89.9
  TOP w0.216: v2(98.77,29.27) v1(98.77,28.65)
  L3 w0.102: 110.2,74.71 110.67,75.19 110.76,75.19 111.31,75.73 111.31,77.84 v1(111.75,78.28)
  L3 w0.203: 110.2,74.71 110.01,74.71 108.29,72.99 108.29,69.45 107.48,68.65 107.48,66.38 106.66,65.56 106.66,64.11 101.86,59.31 100.12,59.31 95.99,55.19 95.99,41.35 95.36,40.71 95.36,34.56 96.32,33.6 96.32,31.78 99.42,28.68 99.42,27.24 99.83,26.83 v1(100.5,26.83)
  L4 w0.102: v1(98.77,28.65) 98.31,28.65 98.18,28.52 98.18,26.96 98.31,26.83 v1(100.5,26.83) 101.3,26.83 102.67,25.46 102.67,24.44 105.95,21.17 v1(106.38,21.17)
  BOTTOM w0.102: v1(98.77,28.65) 98.36,29.06 98.36,30.36 98.48,30.49 98.97,30.49 99.09,30.36 99.09,29.5 99.22,29.37 99.4,29.37 99.52,29.5 99.52,30.16 100.62,31.25 101.62,31.25 101.75,31.13 DM1.78 ; DM2.78 106.65,20.9 v1(106.38,21.17)
  BOTTOM w0.216: v1(111.75,78.28) 111.9,78.28 CPU1.L35
M_A_BS0: length 92.4
  TOP w0.216: v2(108.52,36.33) v1(108.52,35.72)
  L3 w0.102: v1(122.71,75.88) 122.71,74.81 122.97,74.56 122.97,73.16 123.53,72.59 123.57,72.59
  L3 w0.203: 123.57,72.59 124.65,71.51 124.65,67.09 125.2,66.53 125.2,57.55 124.84,57.19 124.56,57.19 123.84,57.9 123.55,57.9 123.26,57.62 123.26,57.33 123.98,56.61 123.98,56.33 123.69,56.04 123.41,56.04 122.69,56.75 122.4,56.75 122.12,56.47 122.12,56.18 122.83,55.46 122.83,55.18 113.03,45.38 112.44,45.38 111.54,44.47 111.54,41.31 108.52,38.29 v1(108.52,35.72)
  L4 w0.102: v1(110.37,43.7) 110.4,43.7 110.83,43.27 110.83,41.13 110.93,41.03 111.84,41.03 111.95,40.93 111.95,40.72 111.84,40.62 110.93,40.62 110.83,40.52 110.83,40.32 110.93,40.22 111.84,40.22 111.95,40.11 111.95,39.91 111.84,39.81 110.93,39.81 110.83,39.71 110.83,38.03 v1(108.52,35.72) 109.46,35.72 109.84,35.34 109.84,34.73 109.74,34.63 109.23,34.63 109.13,34.53 109.13,34.33 109.23,34.22 109.74,34.22 109.84,34.12 109.84,33.92 109.74,33.82 109.23,33.82 109.13,33.72 109.13,33.51 109.23,33.41 110.47,33.41 110.62,33.26 110.62,33.03 110.47,32.88 109.91,32.88 109.84,32.8 109.84,32.6 112.66,29.78 112.66,28.38 v1(112.55,28.28)
  BOTTOM w0.102: DM2.109 115.95,25.88 113.55,28.28 v1(112.55,28.28) ; v1(110.37,43.7) 110.58,43.7 111.05,43.23 DM1.109
  BOTTOM w0.216: v1(122.71,75.88) 122.61,75.98 122.61,76 122.33,76.28 CPU1.AJ38
M_A_BS1: length 91.9
  TOP w0.216: v2(105.87,33.69) v1(106.51,33.69)
  L3 w0.102: v1(120.56,78.29) 120.94,77.91 121.83,77.91 122.05,77.68 122.05,72.92 122.51,72.47
  L3 w0.203: 122.51,72.47 123.88,71.09 123.88,67.26 123.73,67.1 123.73,59.52 118.45,54.23 118.45,52.82 109.86,44.23 109.86,41.07 107.14,38.35 107.14,35.6 108.06,34.68 108.06,32.99 110.8,30.24 v1(110.8,28.5)
  L4 w0.102: v1(106.51,33.69) 106.51,33.01 109.8,29.71 109.8,29.57 109.2,28.96 109.2,28.82 109.34,28.67 109.48,28.67 110.09,29.28 110.23,29.28 110.8,28.71 v1(110.8,28.5) 110.8,28.45 110.37,28.01 110.37,27.64 110.66,27.35 110.97,27.35 112.18,26.14 112.18,23.33 112.15,23.29 112.15,22.44 112.48,22.1 112.48,20.56 113.95,19.09 v1(115.48,19.09)
  BOTTOM w0.102: v1(115.48,19.09) 115.65,18.91 DM2.108 ; DM1.108 110.75,30.8 107.75,33.79 106.61,33.79 v1(106.51,33.69)
  BOTTOM w0.216: CPU1.AG35 120.97,77.88 v1(120.56,78.29)
M_A_BS2: length 91.3
  TOP w0.216: v2(97.87,33.62) v1(97.42,34.07)
  L3 w0.102: v1(112.85,78.28) 112.18,77.61 112.18,76.44 112.02,76.28 112.02,75.38 111.51,74.88 110.94,74.31
  L3 w0.203: 110.94,74.31 110.63,73.99 110.15,73.99 109.35,73.2 109.35,69.02 108.5,68.16 108.5,65.96 107.68,65.14 107.68,63.69 102.28,58.3 100.54,58.3 97.01,54.77 97.01,40.92 96.37,40.29 96.37,35.07 97.29,34.15 97.34,34.15 v1(97.42,34.07)
  L4 w0.102: v1(106.92,22.69) 106.13,23.48 105.49,24.12 103.89,24.12 103.28,24.72 103.28,25.74 97.85,31.18 97.85,33.64 v1(97.42,34.07) 96.65,34.83 96.65,36.46 97.09,36.89 98.97,36.89 100.71,38.63 101.94,38.63 102.06,38.76 102.06,38.97 101.94,39.1 101.79,39.1 101.66,39.23 101.66,39.43 101.79,39.56 101.96,39.56 102.09,39.69 102.09,39.94 101.96,40.07 101.81,40.07 101.68,40.19 101.68,42.12 v1(102.12,42.56)
  BOTTOM w0.102: DM2.79 106.95,22.73 v1(106.92,22.69) ; v1(102.12,42.56) 101.61,42.05 101.61,40.17 102.05,39.73 DM1.79
  BOTTOM w0.216: CPU1.N34 113.25,78.68 v1(112.85,78.28)
M_A_CAS#: length 85.4
  TOP w0.216: v1(110.57,35.55) 110.55,35.57 v2(109.99,35.57)
  L3 w0.102: 125.84,73.82 125.83,73.82 124.67,74.98 124.67,76.11 124.37,76.42 124.37,76.97 123.41,77.92 123.41,78.51 v1(123.93,79.03)
  L3 w0.203: v1(110.57,35.55) 110.57,37.33 115.12,41.88 115.12,44.59 126.11,55.58 127.9,55.58 128.46,56.14 128.46,63.3 127.72,64.04 127.72,67.34 127.74,67.36 127.74,68.46 127.37,68.83 127.37,71.92 126.31,72.99 126.31,73.35 125.84,73.82
  L4 w0.102: v1(113.06,41.31) 113.09,41.29 113.09,39.58 112.43,38.92 112.43,38.44 112.53,38.34 112.99,38.34 113.11,38.22 113.11,38.05 112.99,37.93 112.27,37.93 112.15,37.81 112.15,37.65 112.27,37.53 112.97,37.53 113.09,37.41 113.09,37.24 112.97,37.12 112.25,37.12 112.12,36.99 112.12,36.71 112.73,36.1 112.73,35.92 112.54,35.74 112.39,35.74 111.87,36.26 111.29,36.26 v1(110.57,35.55) 111.26,34.86 111.26,32.68 111.77,32.17 111.91,32.17 112.17,32.43 112.32,32.43 112.46,32.29 112.46,32.14 112.2,31.88 112.2,31.74 114.84,29.09 114.84,28 115.48,27.37 v1(115.91,27.37)
  BOTTOM w0.102: v1(115.91,27.37) 116.19,27.37 117.75,25.8 DM2.115 ; DM1.115 112.85,41.1 v1(113.06,41.31)
  BOTTOM w0.216: CPU1.AL34 123.63,78.68 123.93,78.98 v1(123.93,79.03)
M_A_DIM0_CKE0: length 72.1
  TOP w0.216: v2(95.84,33.92) v1(95.84,33.36)
  L3 w0.102: 110.54,75.5 110.79,75.5 111.1,75.81 111.1,78.35 v1(111.71,78.96)
  L3 w0.203: 110.54,75.5 110.17,75.5 108.76,74.1 107.66,74.1 107.36,73.8 107.36,73.4 107.6,73.16 107.6,70.77 106.56,69.73 106.56,67.49 105.9,66.84 105.9,64.07 105.17,63.34 104.88,63.34 104.1,64.13 103.81,64.13 103.52,63.84 103.52,63.55 104.31,62.77 104.31,62.48 104.02,62.19 103.73,62.19 102.95,62.98 102.66,62.98 102.37,62.69 102.37,62.4 103.16,61.62 103.16,61.33 102.87,61.04 102.58,61.04 101.8,61.83 101.51,61.83 101.22,61.54 101.22,61.25 102.01,60.47 102.01,60.18 101.65,59.82 99.91,59.82 95.49,55.4 95.49,41.56 94.85,40.92 94.85,34.35 v1(95.84,33.36)
  BOTTOM w0.216: CPU1.L34 112.01,78.96 v1(111.71,78.96) ; v1(95.84,33.36) 96.86,34.38 96.86,36.31 97.19,36.64 99.45,36.64 100.25,37.44 DM1.73
M_A_DIM0_CKE1: length 73.1
  TOP w0.216: v1(110.65,76.68) 110.99,77.02 v2(111.11,77.02)
  L3 w0.203: v1(98.84,27.32) 98.79,27.32 98.28,27.83 98.28,29.1 95.33,32.05 95.33,33.15 94.34,34.14 94.34,41.13 94.98,41.77 94.98,56.01 96,57.03 96,57.32 95.27,58.05 95.27,58.34 95.55,58.63 95.84,58.63 96.57,57.89 96.86,57.89 97.15,58.18 97.15,58.47 96.42,59.2 96.42,59.49 96.7,59.77 96.99,59.77 97.72,59.04 98.01,59.04 98.3,59.33 98.3,59.62 97.57,60.35 97.57,60.64 97.85,60.92 98.14,60.92 98.87,60.19 99.16,60.19 99.45,60.48 99.45,60.77 98.71,61.5 98.71,61.79 99,62.07 99.29,62.07 100.02,61.34 100.31,61.34 105.29,66.33 105.29,68.5 105.96,69.16 105.96,69.89 106.94,70.88 106.94,74.08 107.45,74.59 108.62,74.59 110.19,76.16 110.19,76.19 110.65,76.65 v1(110.65,76.68)
  BOTTOM w0.216: v1(98.84,27.32) 99.07,27.32 99.45,27.7 99.45,28.28 100.55,29.38 DM1.74 ; v1(110.65,76.68) 110.8,76.68 CPU1.J38
M_A_DIM0_CLK_DDR0: length 75.5
  TOP w0.203: v2(104.27,35.9) 104.95,35.9 v1(104.97,35.92)
  L3 w0.102: v1(119.42,78.28) 119.33,78.37 118.9,78.37 118.83,78.29 118.83,78.12 118.98,77.97 118.98,76.01 118.98,76.01 118.98,75.55 119.03,75.5 119.03,75.47
  L3 w0.178: 119.03,75.47 119.03,74.95 119.29,74.69 119.29,72.85 120.78,71.36 120.78,60.54 120.01,59.77 119.51,59.77 119.26,60.02 118.97,60.02 118.63,59.68 118.63,59.39 118.88,59.14 118.88,58.63 118.32,58.08 117.82,58.08 117.49,58.41 117.2,58.41 116.86,58.06 116.86,57.78 117.19,57.45 117.19,56.94 116.63,56.39 116.13,56.39 115.83,56.69 115.54,56.69 115.2,56.35 115.2,56.06 115.81,55.45 115.81,54.91 115.29,54.39 114.75,54.39 114.18,54.96 113.89,54.96 113.55,54.62 113.55,54.33 114.5,53.38 114.5,52.84 113.98,52.32 113.44,52.32 112.64,53.12 112.35,53.12 112.01,52.78 112.01,52.49 112.98,51.52 112.98,51.03 112.41,50.46 111.92,50.46 110.8,51.59 110.51,51.59 110.17,51.24 110.17,50.96 111.24,49.89 111.24,49.34 110.72,48.82 110.18,48.82 109.1,49.91 108.81,49.91 108.47,49.57 108.47,49.28 109.32,48.43 109.32,47.37 107.04,45.1 107.04,40.83 105.04,38.82 105.04,37.58 104.5,37.04 104.5,35.89 104.6,35.79 104.84,35.79 v1(104.97,35.92)
  BOTTOM w0.203: DM1.101 108.65,37.34 108.92,37.07 108.92,36.82 108.75,36.65 106.79,36.65 105.55,35.41 105.33,35.41 104.97,35.77 v1(104.97,35.92) ; v1(119.42,78.28) 119.04,78.28 118.9,78.13 CPU1.AC35
M_A_DIM0_CLK_DDR1: length 74.8
  TOP w0.203: v2(107.11,28.84) v1(107.11,28.22)
  L3 w0.102: 116.68,73.1 116.68,73.17 116.36,73.48 116.36,74.89 117.08,75.6 117.08,77.34 117.75,78.01 117.75,78.55 117.65,78.65 117.1,78.65 116.97,78.52 116.97,78.42 v1(117.25,78.15)
  L3 w0.178: 116.68,73.1 116.8,72.98 116.8,68.58 117.99,67.38 117.99,63 117.31,62.32 116.7,62.32 116.43,62.58 115.89,62.58 115.37,62.06 115.37,61.52 115.78,61.11 115.78,60.82 115.44,60.48 115.15,60.48 114.69,60.94 114.15,60.94 113.63,60.42 113.63,59.88 114.11,59.41 114.11,59.12 113.77,58.78 113.48,58.78 113.07,59.19 112.53,59.19 112.01,58.67 112.01,58.13 112.42,57.72 112.42,57.43 111.95,56.97 111.67,56.97 111.34,57.29 110.8,57.29 110.28,56.77 110.28,56.23 110.52,55.99 110.52,55.53 105.77,50.79 105.77,47.64 104.1,45.96 104.1,40.54 103.16,39.6 103.16,38.47 102.6,37.91 102.6,35.06 103.08,34.58 103.08,33.39 107.92,28.55 107.92,27.98 107.79,27.85 107.43,27.85 107.11,28.18 v1(107.11,28.22)
  BOTTOM w0.203: v1(117.25,78.15) 117.25,78.32 117.6,78.68 CPU1.AA34 ; DM1.102 108.95,29.17 109.22,28.9 109.22,28.31 108.79,27.87 107.45,27.87 v1(107.11,28.22)
M_A_DIM0_CLK_DDR#0: length 75.4
  TOP w0.203: v1(104.97,35.08) 104.95,35.08 v2(104.45,34.68)
  L3 w0.102: 118.73,75.47 118.73,75.5 118.78,75.55 118.78,76.09 118.78,77.88 118.67,77.99 v1(118.4,78.26)
  L3 w0.178: v1(104.97,35.08) 104.88,35.08 104.2,35.76 104.2,37.17 104.73,37.7 104.73,38.95 106.74,40.95 106.74,45.22 109.01,47.5 109.01,48.3 108.16,49.15 108.16,49.69 108.68,50.21 109.22,50.21 110.31,49.13 110.59,49.13 110.94,49.47 110.94,49.76 109.86,50.83 109.86,51.37 110.38,51.89 110.92,51.89 112.05,50.77 112.28,50.77 112.68,51.16 112.68,51.4 111.71,52.37 111.71,52.91 112.22,53.43 112.77,53.43 113.57,52.62 113.86,52.62 114.2,52.96 114.2,53.25 113.24,54.21 113.24,54.75 113.76,55.27 114.3,55.27 114.88,54.69 115.17,54.69 115.51,55.03 115.51,55.32 114.89,55.94 114.89,56.48 115.41,57 115.95,57 116.26,56.69 116.51,56.69 116.89,57.07 116.89,57.32 116.56,57.65 116.56,58.19 117.08,58.71 117.62,58.71 117.95,58.38 118.2,58.38 118.57,58.76 118.57,59.01 118.32,59.26 118.32,59.8 118.84,60.32 119.38,60.32 119.63,60.07 119.88,60.07 120.48,60.67 120.48,71.23 118.99,72.73 118.99,74.56 118.73,74.82 118.73,75.47
  BOTTOM w0.203: v1(118.4,78.26) 118.81,78.68 CPU1.AC34 ; v1(104.97,35.08) 105.69,35.08 106.93,36.32 108.89,36.32 109.25,36.68 DM1.103
M_A_DIM0_CLK_DDR#1: length 74.9
  TOP w0.203: v2(107.75,27.54) v1(107.07,27.54)
  L3 w0.102: v1(117.32,79.08) 117.55,78.85 117.73,78.85 117.95,78.63 117.95,77.92 117.28,77.25 117.28,75.52 116.57,74.81 116.57,73.57 116.82,73.32 116.89,73.32
  L3 w0.178: 116.89,73.32 117.1,73.11 117.1,68.7 118.3,67.51 118.3,62.87 117.43,62.01 116.57,62.01 116.31,62.28 116.02,62.28 115.68,61.93 115.68,61.65 116.09,61.24 116.09,60.69 115.57,60.17 115.03,60.17 114.57,60.64 114.28,60.64 113.94,60.3 113.94,60.01 114.41,59.53 114.41,58.99 113.89,58.47 113.35,58.47 112.94,58.88 112.65,58.88 112.31,58.54 112.31,58.26 112.72,57.84 112.72,57.3 112.08,56.66 111.54,56.66 111.22,56.98 110.93,56.98 110.59,56.64 110.59,56.35 110.83,56.12 110.83,55.4 106.08,50.66 106.08,47.51 104.4,45.83 104.4,40.41 103.46,39.47 103.46,38.34 102.9,37.78 102.9,35.19 103.39,34.71 103.39,33.51 108.22,28.67 108.22,27.85 107.92,27.54 v1(107.07,27.54)
  BOTTOM w0.203: CPU1.AA32 v1(117.32,79.08) ; DM1.104 109.55,28.17 108.92,27.54 v1(107.07,27.54)
M_A_DIM0_CS#0: length 70.1
  TOP w0.216: v2(111.13,33.26) v1(111.74,33.26)
  L3 w0.102: v1(122.74,78.22) 123.85,77.1 123.91,77.1 124.16,76.85 124.16,76.34 124.16,76.33 124.39,76.1 124.39,75.72 124.34,75.66 124.34,74.53 125.13,73.74 125.13,73.42
  L3 w0.203: 125.13,73.42 125.13,73.16 126.73,71.56 126.73,62.92 126.93,62.71 127.74,62.71 127.95,62.51 127.95,62.1 127.74,61.9 126.93,61.9 126.73,61.7 126.73,61.29 126.93,61.09 127.74,61.09 127.95,60.89 127.95,60.48 127.74,60.28 126.93,60.28 126.73,60.07 126.73,59.67 126.93,59.46 127.74,59.46 127.95,59.26 127.95,58.85 127.74,58.65 126.93,58.65 126.73,58.45 126.73,57.94 127.94,56.73 127.94,56.44 127.65,56.15 127.36,56.15 126.81,56.71 126.52,56.71 114.61,44.8 114.61,43.82 114.41,43.61 113.88,43.61 113.67,43.41 113.67,43 113.88,42.8 114.41,42.8 114.61,42.6 114.61,42.17 114.41,41.97 113.78,41.97 113.58,41.77 113.58,41.05 110.07,37.54 110.07,33.77 110.58,33.26 v1(111.74,33.26)
  BOTTOM w0.216: DM1.114 112.55,30.93 111.74,31.74 v1(111.74,33.26) ; v1(122.74,78.22) 122.74,78.3 122.36,78.68 CPU1.AJ34
M_A_DIM0_CS#1: length 70
  TOP w0.216: v2(112.86,36.03) v1(112.86,36.59)
  L3 w0.102: v1(125.95,75.86) 125.96,75.86 127.11,74.71 127.97,74.71
  L3 w0.203: v1(112.86,36.59) 112.86,36.71 117.15,41.01 117.15,43.75 120.6,47.19 122.7,47.19 123.72,48.21 124.56,48.21 125.25,47.51 125.54,47.51 125.88,47.86 125.88,48.14 124.91,49.11 124.91,49.4 125.2,49.69 125.49,49.69 126.49,48.68 126.78,48.68 127.07,48.97 127.07,49.26 126.06,50.26 126.06,50.55 126.35,50.84 126.64,50.84 127.64,49.83 127.93,49.83 128.22,50.12 128.22,50.41 127.21,51.41 127.21,51.7 127.5,51.99 127.79,51.99 128.79,50.98 129.08,50.98 129.37,51.27 129.37,51.56 128.36,52.56 128.36,52.85 128.65,53.14 128.94,53.14 129.97,52.1 130.2,52.1 130.59,52.49 130.59,52.82 129.78,53.63 129.78,54.27 130.59,55.08 130.59,72.1 127.97,74.71
  BOTTOM w0.216: v1(112.86,36.59) 112.94,36.51 113.88,36.51 114.65,37.29 DM1.121 ; v1(125.95,75.86) 125.94,75.87 125.94,76.01 125.67,76.28 CPU1.AR38
M_A_DIM0_ODT0: length 71.9
  TOP w0.216: v2(111.67,36.41) v1(111.67,35.83)
  L3 w0.102: v1(125,76.68) 125,76.44 125.1,76.34 125.1,75.19 125.78,74.51
  L3 w0.203: 125.78,74.51 126.16,74.51 127.82,72.86 128.35,72.86 129.47,71.74 129.47,55.4 127.97,53.9 127.57,53.9 126.91,54.56 126.62,54.56 126.3,54.24 126.3,53.95 126.99,53.26 126.99,52.97 126.7,52.69 126.41,52.69 125.68,53.42 125.39,53.42 125.1,53.13 125.1,52.85 125.81,52.14 125.81,51.85 125.52,51.56 125.24,51.56 124.53,52.27 124.24,52.27 123.95,51.98 123.95,51.7 124.7,50.95 124.7,50.66 124.41,50.38 124.13,50.38 123.38,51.12 123.09,51.12 122.8,50.84 122.8,50.55 123.55,49.8 123.55,49.51 123.26,49.23 122.98,49.23 122.23,49.97 121.94,49.97 121.65,49.69 121.65,49.4 122.3,48.75 122.3,48.47 122.04,48.21 121.69,48.21 121.08,48.82 120.79,48.82 116.14,44.17 116.14,41.43 111.67,36.96 v1(111.67,35.83)
  BOTTOM w0.216: DM1.116 113.15,30.94 112.43,31.66 112.43,35.07 v1(111.67,35.83) ; v1(125,76.68) 124.6,76.28 CPU1.AN38
M_A_DIM0_ODT1: length 70.4
  TOP w0.216: v1(113.42,33.97) 113.01,33.64 v2(112.88,33.64)
  L3 w0.203: v1(113.42,33.97) 113.8,34.35 113.8,35.39 118.7,40.3 118.7,43.14 121.23,45.67 125.92,45.67 132.75,52.49 132.75,54.3 132.54,54.51 132.32,54.51 132.11,54.71 132.11,55.12 132.32,55.32 132.54,55.32 132.75,55.52 132.75,55.93 132.54,56.13 132.32,56.13 132.11,56.34 132.11,56.74 132.32,56.94 132.54,56.94 132.75,57.15 132.75,57.66 132.54,57.86 132.32,57.86 132.11,58.06 132.11,58.47 132.32,58.67 132.54,58.67 132.75,58.88 132.75,59.28 132.54,59.48 132.32,59.48 132.11,59.69 132.11,60.09 132.32,60.3 132.54,60.3 132.75,60.5 132.75,60.91 132.54,61.11 132.32,61.11 132.11,61.31 132.11,61.72 132.32,61.92 132.54,61.92 132.75,62.13 132.75,62.53 132.54,62.74 132.32,62.74 132.11,62.94 132.11,63.35 132.32,63.55 132.54,63.55 132.75,63.75 132.75,69.29 132.54,69.49 132.32,69.49 132.11,69.7 132.11,70.1 132.32,70.31 132.54,70.31 132.75,70.51 132.75,73.43 132.07,74.11 131.57,74.11 131.12,74.56 131.12,75.68 130.92,75.88 129.34,75.88 128.86,76.36 128.86,77.07 128.63,77.3 128.21,77.3 127.59,76.68 v1(127.02,76.68)
  BOTTOM w0.216: v1(113.42,33.97) 112.95,33.51 112.95,32.12 114.35,30.73 DM1.120 ; CPU1.AU38 126.61,76.28 v1(127.02,76.68)
M_A_DM0: length 121.7
  L3 w0.102: v1(80.98,21.78) 80.98,22.85 75.52,28.31 73.59,28.31 71.23,30.67 71.23,31.86 70.8,32.29 70.8,34.73 v1(71.2,35.14) 71.31,35.14 72.23,36.06 72.37,36.06 72.69,35.75 72.83,35.75 72.98,35.9 72.98,36.04 72.66,36.35 72.66,36.5 72.81,36.64 72.95,36.64 73.26,36.33 73.41,36.33 73.55,36.47 73.55,36.61 73.24,36.93 73.24,37.07 73.46,37.29 73.6,37.29 73.98,36.91 74.12,36.91 74.27,37.06 74.27,37.2 73.89,37.58 73.89,37.72 74.03,37.87 74.18,37.87 74.55,37.49 74.7,37.49 74.84,37.63 74.84,37.78 74.46,38.15 74.46,38.3 74.73,38.57 74.88,38.57 75.18,38.26 75.32,38.26 75.46,38.41 75.46,38.55 75.16,38.85 75.16,39 77.4,41.24 77.71,41.24 77.81,41.34 77.81,41.85 77.93,41.97 78.1,41.97 78.21,41.85 78.21,41.34 78.32,41.24 78.52,41.24 78.62,41.34 78.62,42.06 78.74,42.17 78.91,42.17 79.03,42.06 79.03,41.34 79.13,41.24 79.43,41.24 79.84,41.64 79.94,41.64 v1(80.09,41.79)
  L4 w0.203: v1(71.2,35.14) 71.26,35.2 71.26,35.47 72.75,36.96 72.75,40.5 74.2,41.95 74.2,47.25 85.66,58.71 88.36,58.71 97.16,67.51 97.16,71.44 97.37,71.64 100.37,71.64 100.57,71.84 100.57,72.27 100.37,72.48 98.89,72.48 98.69,72.68 98.69,73.11 98.89,73.32 102.06,73.32 102.89,74.14 102.89,74.42 102.54,74.77 102.25,74.77 101.64,74.16 v1(99.96,74.16)
  BOTTOM w0.102: v1(80.09,41.79) 80.09,40.63 79.25,39.78 DM1.11 ; v1(80.98,21.78) 82.23,21.78 84.15,23.7 DM2.11 ; 104.34,79.07 104.46,79.18 106.62,79.18 106.68,79.13 107,79.13 107.3,79.43 CPU1.B32
  BOTTOM w0.216: 104.34,79.07 102.82,77.55 102.82,77.02 101.12,75.33 v2(101.12,75.32) 101.12,75.32 v1(99.96,74.16)
M_A_DM1: length 101
  TOP w0.216: v2(77.76,33.26) v1(77.76,33.82)
  L3 w0.102: v1(77.76,33.82) 78.52,33.82 81.72,30.62 v1(81.72,28.41) 82.05,28.41 83.32,27.14 83.32,26.25 89.19,20.38 89.19,18.3 v1(89.25,18.24)
  L4 w0.203: v1(81.72,28.41) 82.42,27.71 82.42,27.37 82.22,27.16 80.93,27.16 80.73,27.37 80.73,30.14 77.15,33.72 77.15,34.33 76.89,34.58 76.89,39.08 78.63,40.82 78.63,45.65 87.43,54.44 90.13,54.44 101.48,65.79 101.48,68.49 102.17,69.18 102.17,70.82 103.97,72.63 105.2,72.63 105.97,73.4 105.97,74.11 v1(105.57,74.52)
  BOTTOM w0.102: v1(105.57,74.52) 105.6,74.55 105.77,74.55 106.35,75.13 106.6,75.13 106.89,75.43 106.89,75.71 107.31,76.13 CPU1.B38 ; DM1.28 84.35,30.83 81.67,33.51 78.06,33.51 v1(77.76,33.82) ; DM2.28 v1(89.25,18.24)
M_A_DM2: length 91.9
  L3 w0.102: v1(84.84,34.02) 84.84,33.74 88.7,29.88 88.7,29.6 88.58,29.47 88.44,29.47 88.32,29.36 88.32,29.19 88.44,29.07 88.81,29.07 88.93,28.94 88.93,28.71 88.81,28.59 88.35,28.59 v1(88.12,28.36) 89.26,27.21 89.26,26.78 90.32,25.73 90.8,25.73 94.14,22.39 94.14,20.1 94.44,19.8 v1(94.83,19.8)
  L4 w0.203: v1(88.12,28.36) 88.12,29.12 84.31,32.93 84.31,35.57 84.2,35.69 84.2,35.74 83.97,35.97 83.97,38.55 87.36,41.94 87.36,45.17 90.18,47.99 92.81,47.99 108.26,63.45 108.26,67.91 108.47,68.11 108.96,68.11 v1(109.04,68.02)
  BOTTOM w0.102: CPU1.G40 110.1,74.63 109.73,74.27 109.73,72.89 109.83,72.79 ; DM2.46 94.65,19.62 v1(94.83,19.8) ; DM1.46 89.75,30.82 87.99,32.57 86.01,32.57 84.84,33.74 v1(84.84,34.02)
  BOTTOM w0.216: 109.83,72.79 v2(109.83,70.72) 109.83,68.81 v1(109.04,68.02)
M_A_DM3: length 95.2
  TOP w0.216: v2(90.41,35.67) v1(90.41,35.11)
  L3 w0.102: v1(99.32,23.25) 98.71,23.86 97.97,23.86 94.27,27.57 94.27,28.79 91.17,31.89 91.17,34.35 v1(90.41,35.11) 90.41,35.27 91.93,36.79 91.93,39.33 91.8,39.46 90.78,39.46 90.66,39.58 90.66,39.75 90.78,39.86 91.8,39.86 91.93,39.99 91.93,40.14 91.8,40.27 90.78,40.27 90.66,40.39 90.66,40.56 90.78,40.68 91.8,40.68 91.93,40.8 91.93,42.3 v1(91.57,42.66)
  L4 w0.203: v1(114.89,70.69) 114.13,71.45 114.13,72.73 113.93,72.93 113.55,72.93 113.34,72.73 113.34,71.38 113.19,71.23 112.43,71.23 112.22,71.03 112.22,70.55 112.43,70.34 113.42,70.34 115.05,68.71 115.05,68.27 114.23,67.45 114.23,61.15 90.41,37.33 v1(90.41,35.11)
  BOTTOM w0.102: v1(91.57,42.66) 91.68,42.66 94.85,39.48 DM1.63 ; v1(99.32,23.25) 99.53,23.25 99.75,23.47 DM2.63
  BOTTOM w0.14: CPU1.N41 113.56,74.01 113.56,72.89 114.07,72.39
  BOTTOM w0.216: 114.07,72.39 114.26,72.2 v2(114.26,72.02) 114.26,71.34 114.89,70.71 v1(114.89,70.69)
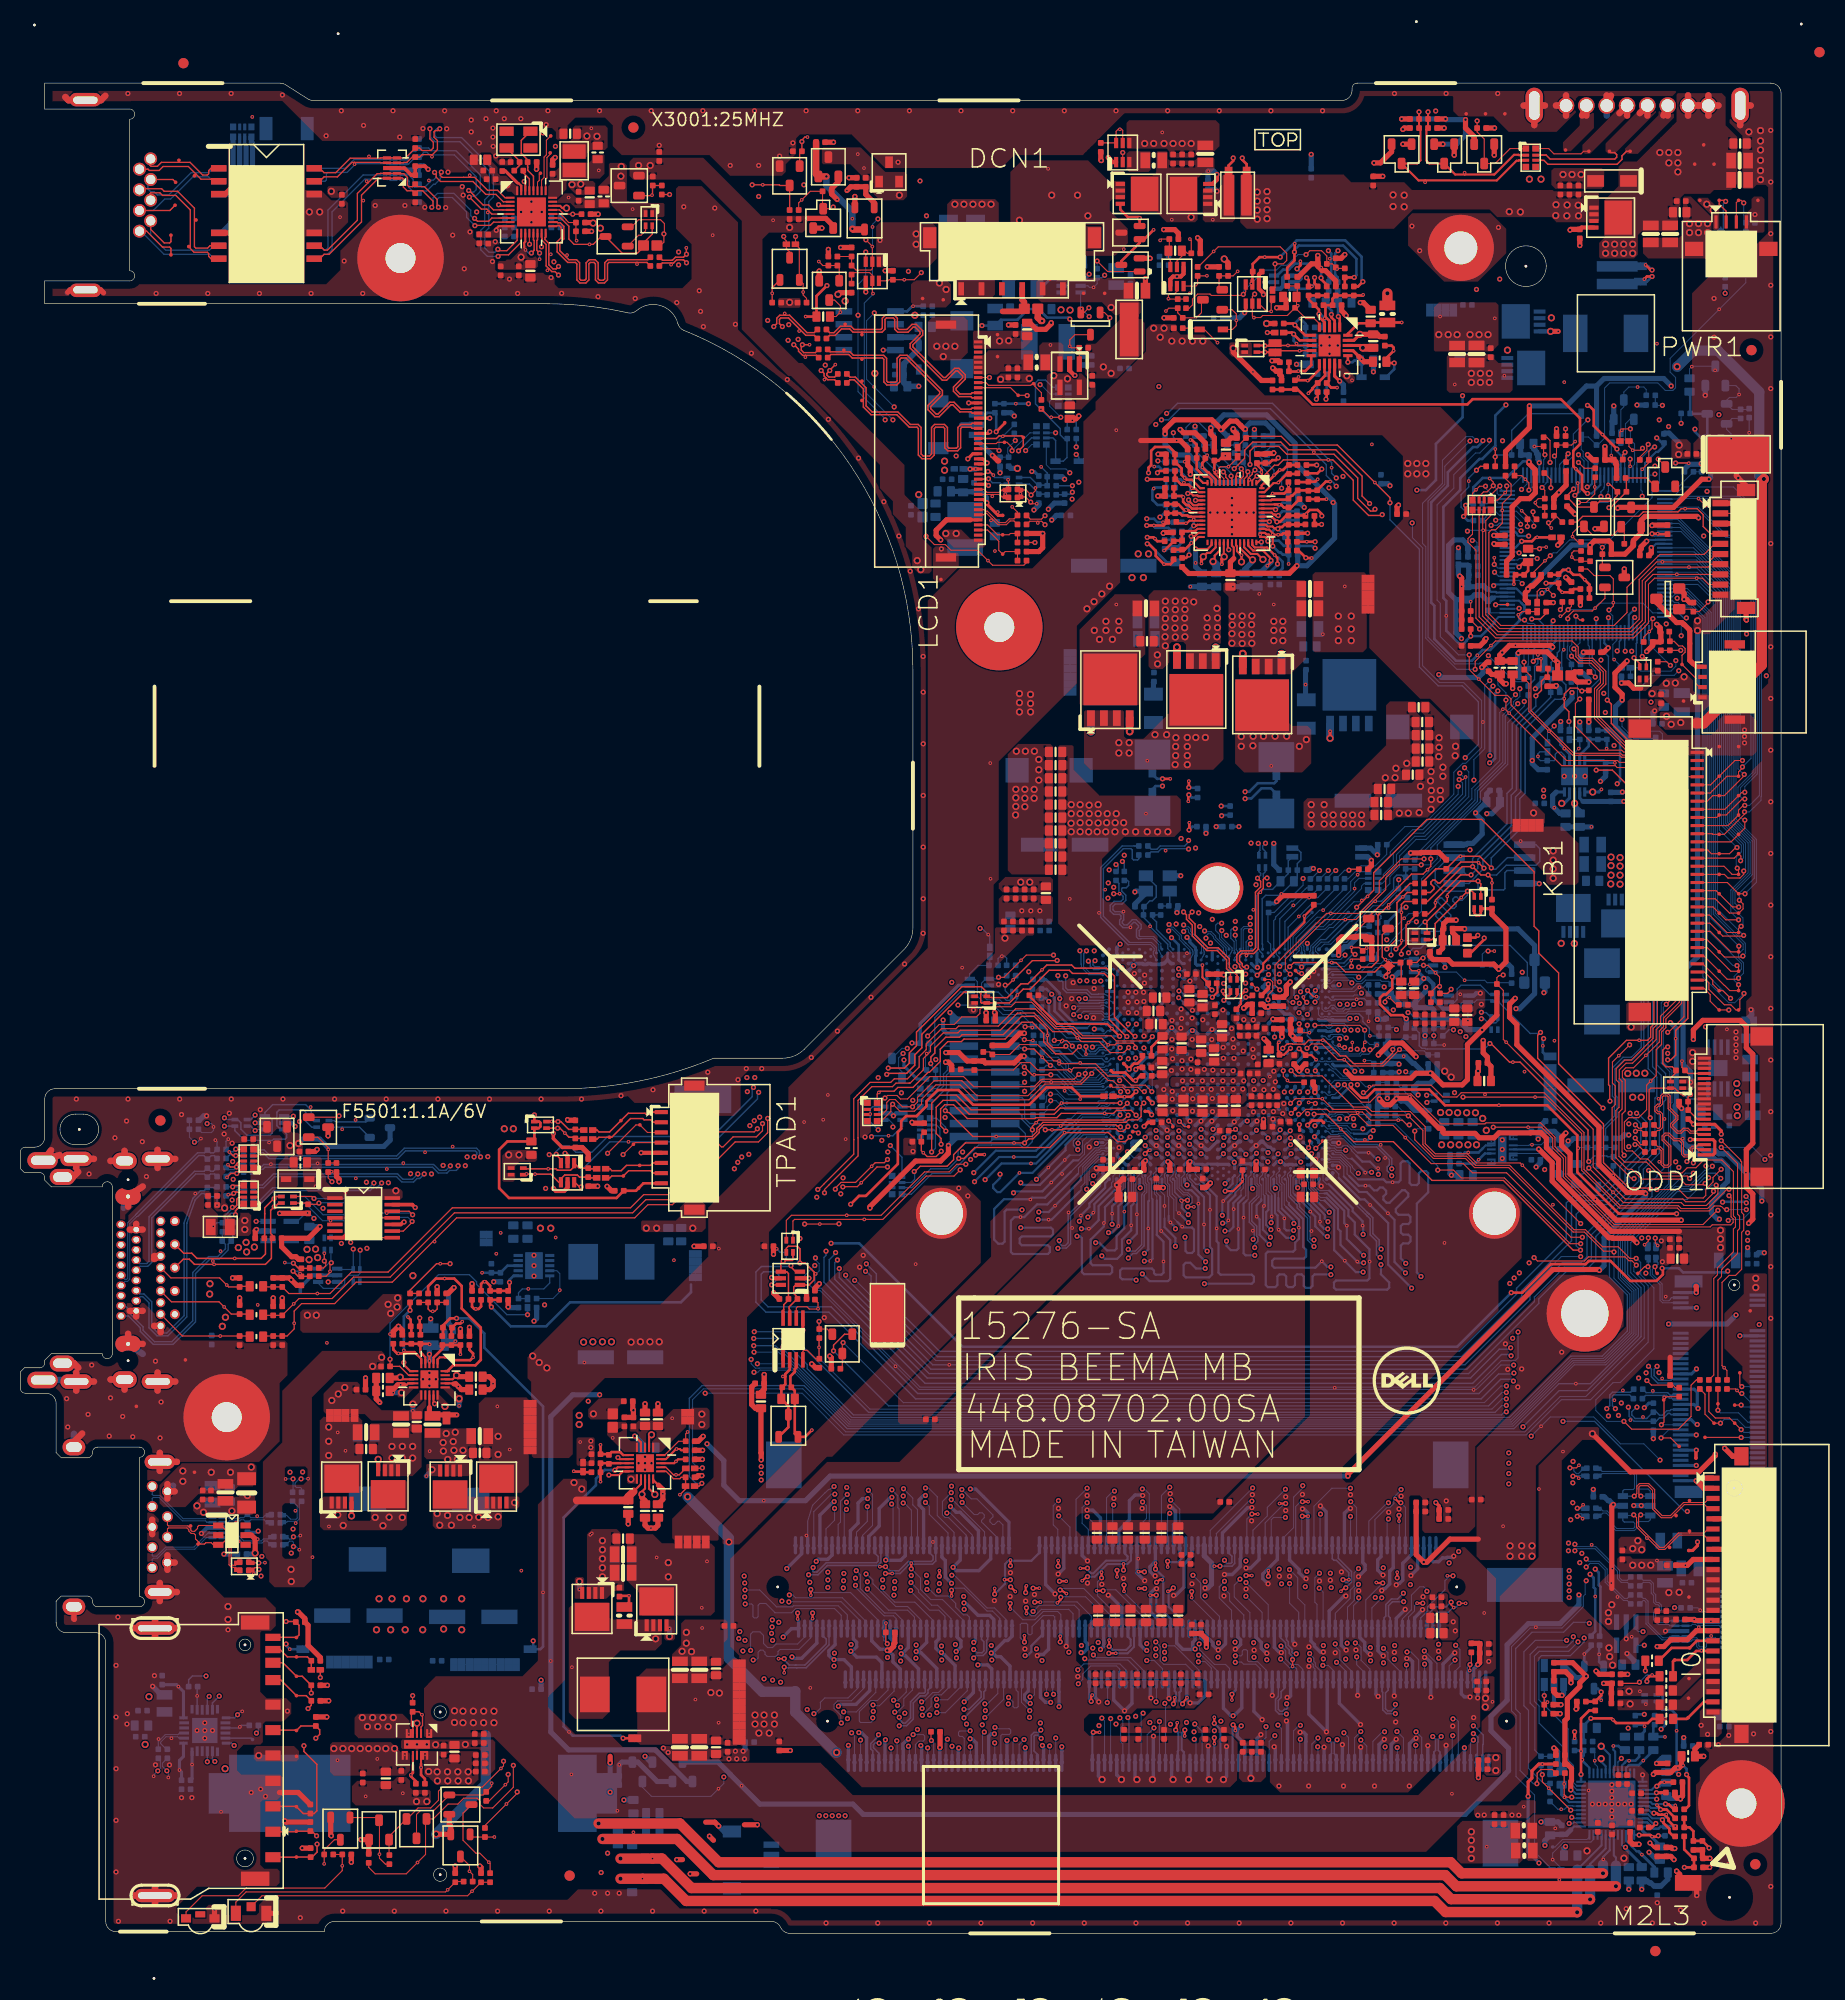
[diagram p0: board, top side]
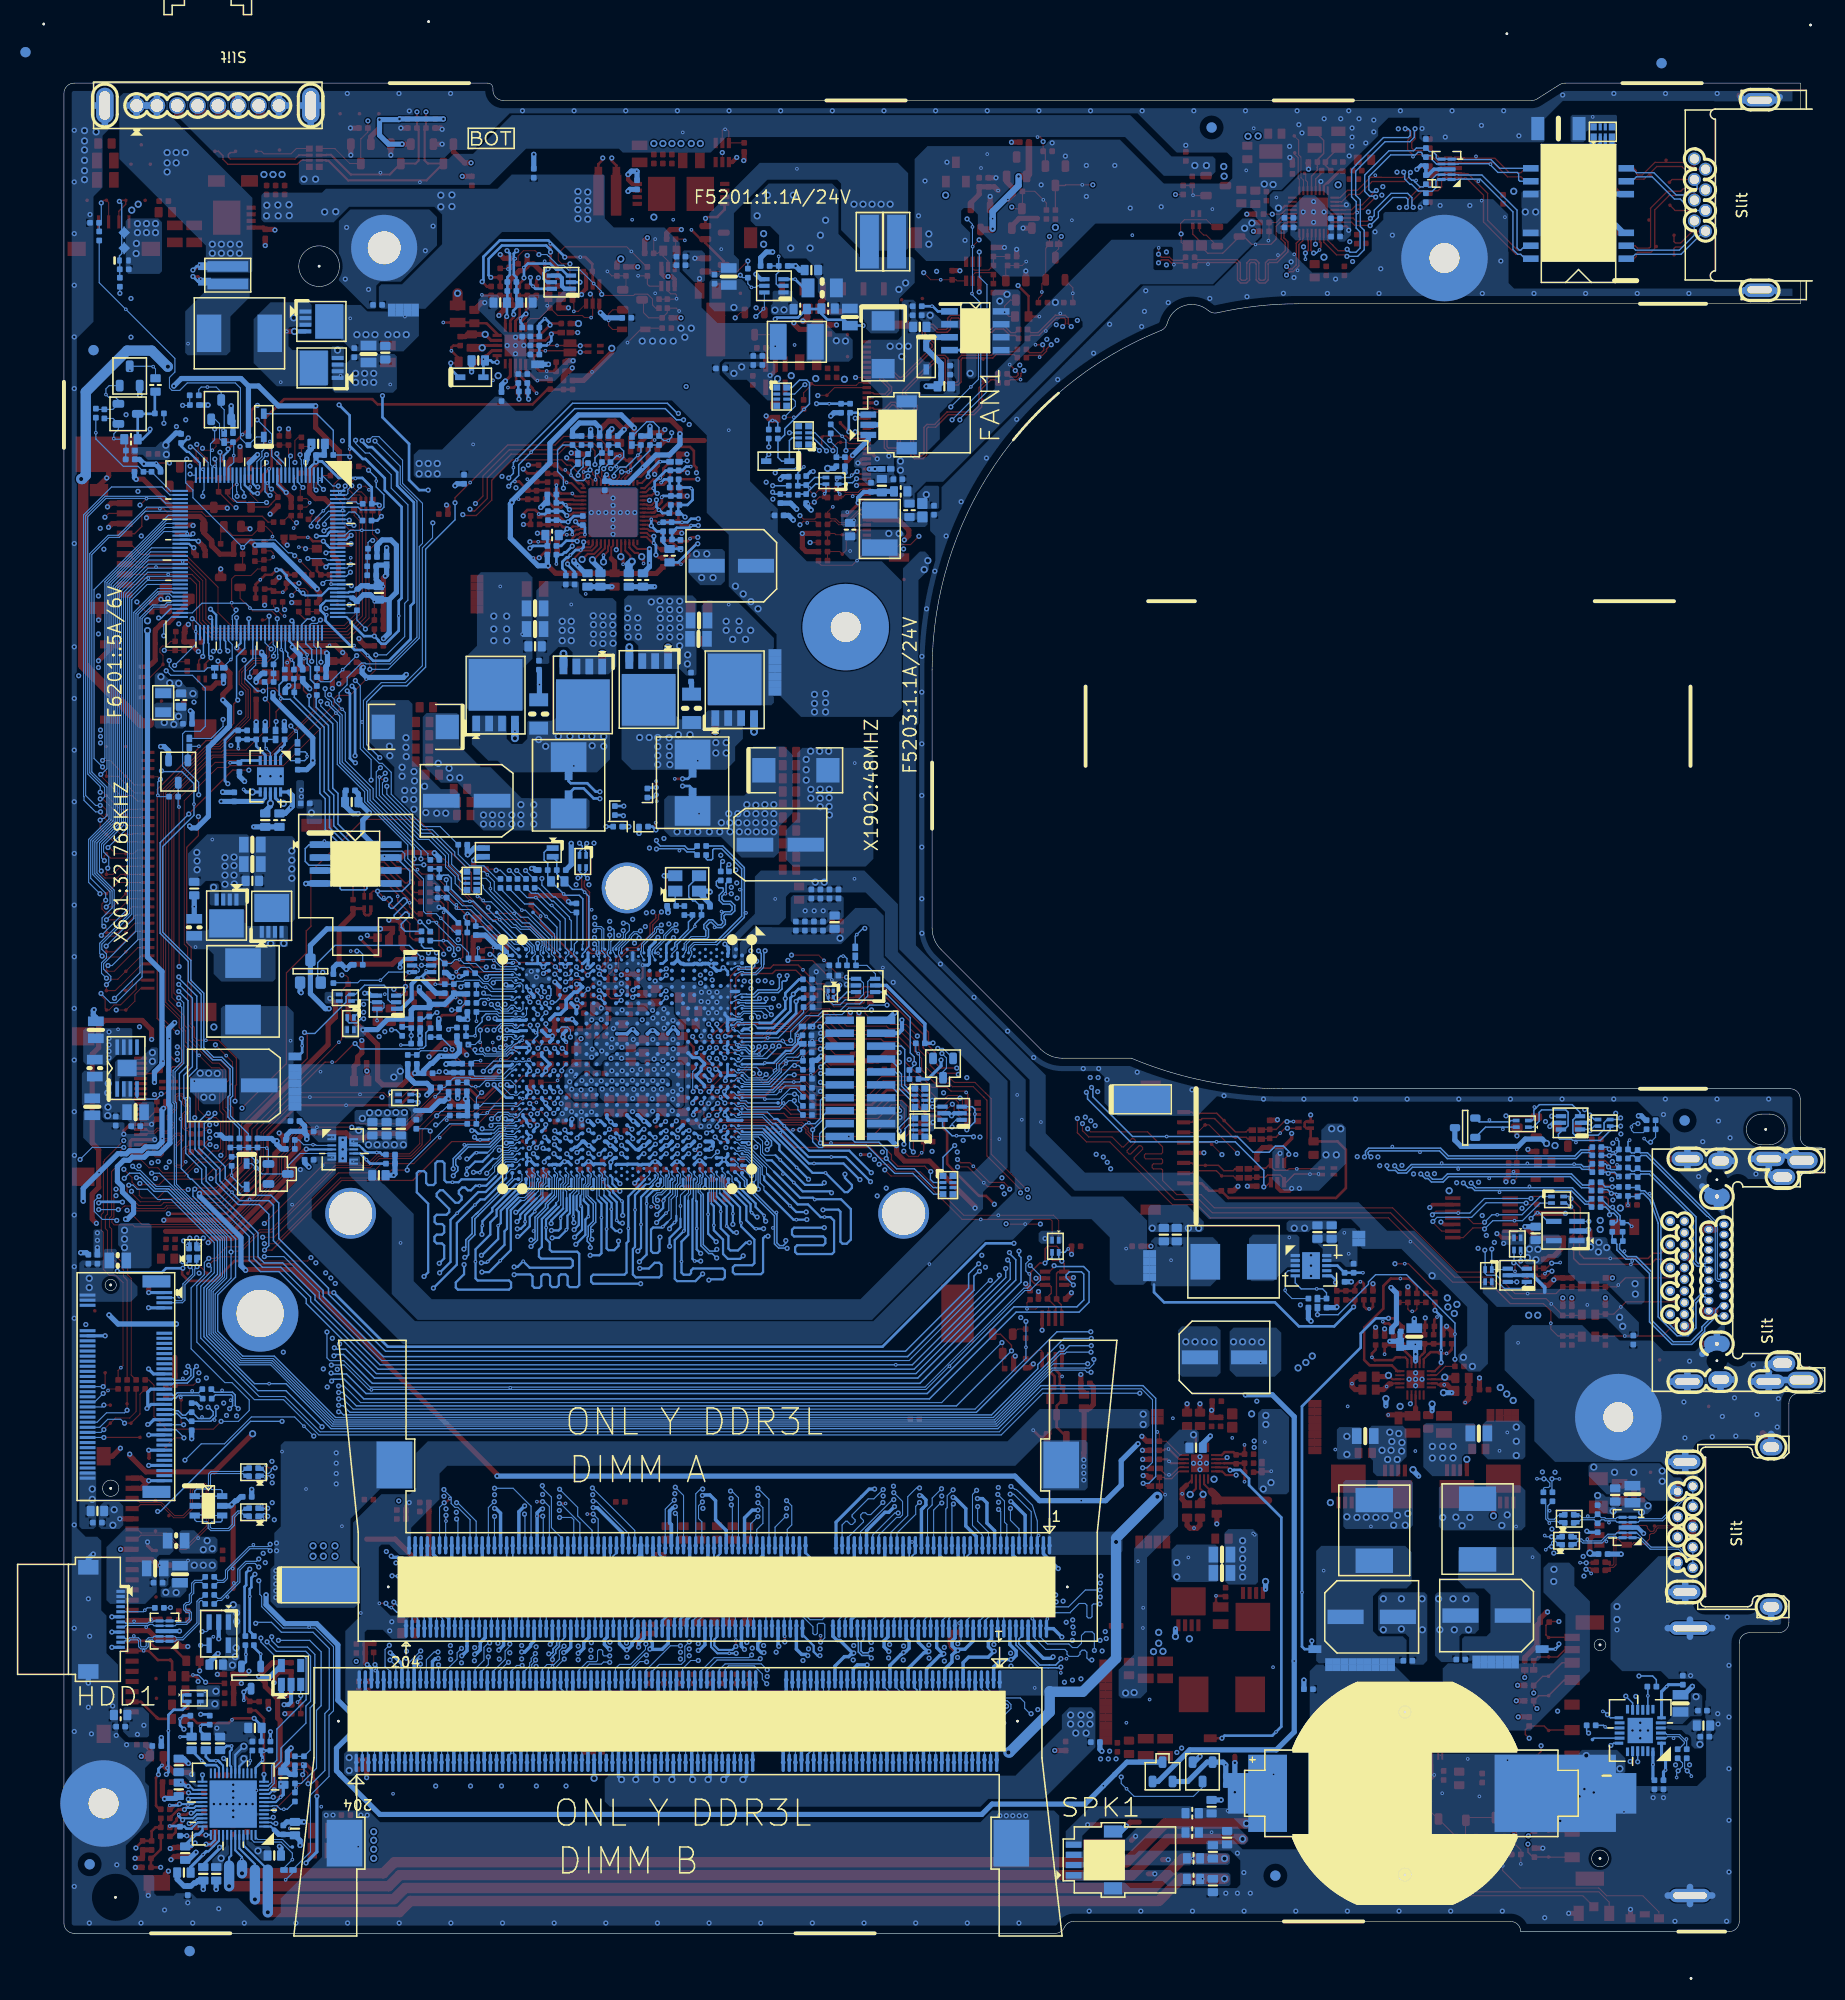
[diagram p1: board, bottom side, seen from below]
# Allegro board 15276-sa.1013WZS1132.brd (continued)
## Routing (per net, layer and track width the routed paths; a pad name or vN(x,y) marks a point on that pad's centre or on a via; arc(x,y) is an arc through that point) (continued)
M_A_DM4: length 80.8
  L3 w0.102: v1(123.71,20.48) 123.48,20.71 123.48,22.41 120.25,25.64 120.25,27.87 v1(119.49,28.64) 119.49,30.88 117.96,32.41 117.96,32.88 117.86,32.98 117.47,32.98 117.36,33.1 117.36,33.27 117.47,33.39 117.86,33.39 117.96,33.49 117.96,33.79 117.86,33.89 117.58,33.89 117.46,34.01 117.46,34.25 117.59,34.38 118.19,34.38 v1(118.45,34.63)
  L4 w0.203: v1(119.49,28.64) 118.37,29.75 118.37,30.16 117.19,31.34 117.19,36.04 117.43,36.28 117.43,44.66 117.23,44.87 117.23,45.38 117.03,45.58 116.57,45.58 116.36,45.78 116.36,46.19 116.57,46.39 117.03,46.39 117.23,46.59 117.23,47 117.03,47.2 116.57,47.2 116.36,47.41 116.36,47.81 116.57,48.02 117.03,48.02 117.23,48.22 117.23,53.17 121.35,57.29 121.35,66.6 v1(121.43,66.69)
  BOTTOM w0.102: v1(123.71,20.48) 124.05,20.14 DM2.136 ; CPU1.AG40 121.06,74.84 121.06,74.6 120.78,74.33 120.78,72.22 120.62,72.06 ; DM1.136 119.15,31.77 117.94,32.98 117.94,34.1 118.45,34.61 v1(118.45,34.63)
  BOTTOM w0.216: 120.62,72.06 120.33,71.76 v2(120.33,70.39) 120.33,66.89 120.53,66.69 v1(121.43,66.69)
M_A_DM5: length 86.2
  L3 w0.102: v1(128.12,26.35) 127.87,26.1 127.87,24.42 127.69,24.24 127.44,24.24 127.26,24.42 127.26,28.76 124.06,31.96 v1(124.06,34.38) 124.06,34.53 124.37,34.83 124.37,40.12 125.36,41.11 125.36,43.24 v1(126.14,44.03)
  L4 w0.203: v1(128.91,65.54) 129.01,65.54 129.52,65.03 129.52,54.11 128.02,52.61 128.02,49.83 126.8,48.62 126.8,45.13 127.13,44.8 127.13,39.97 124.34,37.17 124.34,34.81 124.06,34.53 v1(124.06,34.38)
  BOTTOM w0.102: CPU1.AN41 124.54,74.04 124.54,72.08 124.79,71.83 ; v1(128.12,26.35) 128.66,26.35 129.15,25.86 DM2.153 ; DM1.153 124.25,38.91 125.25,39.91 125.25,42.91 126.14,43.8 v1(126.14,44.03)
  BOTTOM w0.216: v1(128.91,65.54) 128.58,65.54 v2(128.02,66.1) 127.39,65.47 123.35,65.47 123.15,65.67 123.15,66.15 123.35,66.36 126.27,66.36 126.47,66.56 126.47,67.23 126.19,67.51 126.19,70.26 124.79,71.65 124.79,71.83
M_A_DM6: length 83.4
  L3 w0.102: v1(134.25,18.35) 134.63,18.72 134.63,21.74 134.53,21.84 133.73,21.84 133.61,21.96 133.61,22.13 133.73,22.25 134.53,22.25 134.63,22.35 134.63,23.23 132.37,25.49 132.37,27.62 132.8,28.05 v1(132.8,28.1) 132.82,28.13 132.82,29.15 131.2,30.78 131.2,35.44 v1(131.63,35.88)
  L4 w0.203: v1(132.09,68.74) 133.55,68.74 135.64,66.66 135.64,51.96 134.15,50.47 134.15,42.71 134.09,42.66 134.09,39.53 131.15,36.58 131.15,30.69 132.8,29.04 v1(132.8,28.1)
  BOTTOM w0.102: DM2.170 v1(134.25,18.35) ; 128.7,73.69 128.49,73.69 128.14,74.03 128.14,74.63 CPU1.AY40 ; DM1.170 129.35,31.49 130.82,32.95 130.82,33.75 131.2,34.13 131.2,35.44 v1(131.63,35.88)
  BOTTOM w0.216: 128.7,73.69 131.06,71.33 131.06,71.01 132.04,70.04 v2(132.04,69.61) 132.09,69.56 v1(132.09,68.74)
M_A_DM7: length 86.5
  L3 w0.102: v1(138.11,27.77) 138.08,27.77 137.14,28.71 137.14,33.89 v1(136.74,34.3) 136.74,34.63 136.35,35.01 136.35,35.8 134.58,37.58 v1(134.58,40.75)
  L4 w0.203: v1(136.74,34.3) 137.09,34.3 137.29,34.5 137.29,35.32 137.5,35.52 138.59,35.52 139.17,36.1 139.17,37 141.82,39.64 141.82,47.57 141.61,47.77 140.39,47.77 140.21,47.96 140.21,48.4 140.39,48.58 141.61,48.58 141.82,48.79 141.82,49.26 141.28,49.79 141.28,64.82 141.28,65.32 134.8,71.81 134.17,71.81 133.97,72.02 133.97,72.63 134.17,72.83 135.03,72.83 135.2,73 135.2,73.52 135,73.72 134.4,73.72 134.2,73.92 134.2,74.39 134.2,74.9 133.63,75.46 132.56,75.46 130.93,77.08 130.93,77.37 131.23,77.67 131.52,77.67 133.03,76.16 v1(133.56,76.16)
  BOTTOM w0.102: v1(138.11,27.77) 138.11,27.77 139.35,26.53 DM2.187 ; v1(134.58,40.75) 134.58,40.73 134.45,40.6 DM1.187 ; 131.58,76.78 131.53,76.78 130.15,78.16 129.04,78.16 128.91,78.03 128.58,78.03 128.27,78.33 CPU1.AY34
  BOTTOM w0.216: 131.58,76.78 132.61,76.78 v2(132.62,76.77) 132.77,76.77 133.38,76.16 v1(133.56,76.16)
M_A_DQ<0>: length 126.7
  L3 w0.102: v1(78.06,21.6) 78.06,22.38 77.96,22.48 77.1,22.48 76.99,22.59 76.99,22.79 77.1,22.89 78.32,22.89 78.44,23.01 78.44,23.18 78.32,23.3 77.1,23.3 76.99,23.4 76.99,23.6 77.1,23.7 77.96,23.7 78.06,23.81 78.06,24.19 77.02,25.23 76.64,25.23 76.54,25.13 76.54,24.64 76.42,24.52 76.25,24.52 76.13,24.64 76.13,25.13 76.03,25.23 75.82,25.23 75.72,25.13 75.72,24.64 75.6,24.52 75.44,24.52 75.32,24.64 75.32,25.13 75.21,25.23 75.05,25.23 71.97,28.31 71.15,28.31 70.67,28.79 v1(70.67,28.99) 70.19,29.47 70.19,35.17 78.97,43.95 v1(80.04,43.95)
  L4 w0.203: v1(70.67,28.99) 68.41,31.25 68.41,39.56 69.3,40.45 69.3,47.17 76.99,54.86 76.99,55.84 80.58,59.42 81.56,59.42 89.76,67.63 92.46,67.63 93.76,68.92 93.76,72.85 94.9,73.99 v1(94.9,74.13)
  BOTTOM w0.102: v1(80.04,43.95) 79.69,43.7 79.51,43.64 79.14,43.31 77.93,42.1 77.45,40.55 DM1.5 ; 103.53,79.32 104.49,80.28 106.62,80.28 106.68,80.23 107.01,80.23 107.31,80.53 CPU1.B30 ; v1(78.06,21.6) 78.16,21.6 78.7,22.13 78.7,22.72 79.13,23.15 81.41,23.15 82.35,24.09 82.35,24.97 DM2.5
  BOTTOM w0.216: v1(94.9,74.13) 94.93,74.13 96.52,75.72 v2(99.42,75.72) 99.92,75.72 103.53,79.32
M_A_DQ<1>: length 124.7
  L3 w0.102: v1(80.12,43.19) 78.64,43.19 70.49,35.04 70.49,31.84 70.77,31.56 v1(70.77,29.68) 71.05,29.68 73.36,27.37 73.5,27.37 73.83,27.7 74,27.7 74.12,27.58 74.12,27.41 73.79,27.08 73.79,26.94 73.93,26.8 74.08,26.8 74.39,27.11 74.56,27.11 74.68,26.99 74.68,26.82 74.37,26.51 74.37,26.37 74.71,26.02 74.71,26 74.96,25.75 77.65,25.75 77.9,25.49 77.9,25.35 77.69,25.14 77.69,24.99 77.83,24.85 77.98,24.85 78.19,25.06 78.34,25.06 78.48,24.92 78.48,24.78 78.27,24.56 78.27,24.42 78.41,24.28 78.55,24.28 78.77,24.49 78.91,24.49 79.69,23.71 79.69,22.41 80.76,21.34 v1(80.76,20.69)
  L4 w0.203: v1(70.77,29.68) 68.92,31.53 68.92,39.2 69.91,40.2 69.91,46.91 78.82,55.83 78.82,56.8 80.83,58.81 81.81,58.81 90.01,67.02 92.72,67.02 94.37,68.67 94.37,72.59 96.37,74.6 v1(96.37,74.66)
  BOTTOM w0.102: v1(80.76,20.69) 80.7,20.74 80.7,21.45 80.04,22.11 80.04,22.52 80.4,22.87 81.74,22.87 82.95,24.08 DM2.7 ; CPU1.A32 104.19,79.43 104.06,79.3 ; v1(80.12,43.19) 79.76,43.19 78.05,41.48 DM1.7
  BOTTOM w0.216: v1(96.37,74.66) 96.37,74.29 95.69,73.61 95.69,73.32 96.1,72.9 96.39,72.9 v2(98.28,74.79) 99.55,74.79 104.06,79.3
M_A_DQ<2>: length 122.8
  L3 w0.102: v1(81.34,43.17) 80.6,42.43 80.6,41.69 79.84,40.93 79.29,40.93 72.96,34.59 72.96,31.13 v1(73.95,30.14) 75.15,30.14 82.39,22.9 82.39,22.43 82.24,22.29 82.24,22.12 82.36,22 82.53,22 83.04,22.51 83.2,22.51 83.45,22.26 83.45,21.6 v1(83.85,21.19)
  L4 w0.203: v1(73.95,30.14) 73.77,30.31 73.76,30.31 73.46,30.61 73.46,30.92 71.77,32.61 71.77,35.26 73.35,36.84 73.35,39.95 74.84,41.44 74.84,47.02 85.91,58.1 88.62,58.1 97.77,67.26 97.77,70.39 v1(98.53,71.16)
  BOTTOM w0.102: v1(83.85,21.19) 83.85,20.92 83.67,20.74 82.66,20.74 82.53,20.86 82.53,21.8 83.63,22.9 84.31,22.9 85.35,23.94 DM2.15 ; DM1.15 80.45,40.22 80.68,40.45 80.68,42.51 v1(81.34,43.17) ; 103.36,74.92 105.7,77.26 106.02,77.26 106.22,77.45 106.61,77.45 106.94,77.78 CPU1.B35
  BOTTOM w0.216: 103.36,74.92 100.79,72.35 99.53,72.35 v2(99.35,72.17) 99.32,72.2 96.76,72.2 95.79,71.23 95.79,68.24 96.2,67.83 96.62,67.83 96.82,68.03 96.82,70.98 97.02,71.18 98.51,71.18 v1(98.53,71.16)
M_A_DQ<3>: length 119.7
  L3 w0.102: v1(83.88,22.46) 83.44,22.9 82.82,22.9 75.04,30.68 75.04,31.43 74.91,31.56 74.35,31.56 74.23,31.43 74.23,31.08 v1(73.97,30.82) 73.26,31.53 73.26,34.47 79.21,40.41 79.98,40.41 v1(81.26,41.69)
  L4 w0.203: v1(98.41,69.4) 98.38,69.38 98.38,67 88.87,57.49 86.17,57.49 75.47,46.8 75.47,41.29 73.96,39.78 73.96,36.73 72.28,35.05 72.28,32.82 73.97,31.13 v1(73.97,30.82)
  BOTTOM w0.102: DM2.17 85.95,23.82 84.51,22.39 83.95,22.39 v1(83.88,22.46) ; 104.03,74.69 104.09,74.75 104.09,75.29 105.83,77.03 106.09,77.03 106.29,77.23 CPU1.A36 ; DM1.17 81.05,41.48 v1(81.26,41.69)
  BOTTOM w0.216: v1(98.41,69.4) 101.38,69.4 101.58,69.2 101.58,68.74 101.38,68.54 98.51,68.54 98.31,68.34 98.31,67.88 98.51,67.68 101.07,67.68 101.28,67.47 101.28,67.02 101.07,66.81 97.64,66.81 97.44,67.02 97.44,70.09 97.8,70.45 v2(98.38,70.45) 98.76,70.45 100.01,71.69 101.03,71.69 104.03,74.69
M_A_DQ<4>: length 112.7
  L3 w0.102: v1(71.84,27.82) 74.78,24.88 v1(74.78,24.7) 74.78,23.84 78.98,19.65 81.69,19.65 v1(81.77,19.72)
  L4 w0.203: v1(93.78,74.81) 93.56,74.59 89.05,74.59 86.93,72.46 86.93,66.51 82.74,62.33 81.59,62.33 75.78,56.51 75.78,55.37 68.08,47.67 68.08,41.04 67.19,40.14 67.19,30.13 73.74,23.58 74.58,23.58 74.78,23.79 v1(74.78,24.7)
  BOTTOM w0.102: CPU1.B29 106.93,81.08 106.63,80.78 104.01,80.78 103.33,80.09 ; v1(81.77,19.72) 82.05,19.44 DM2.4 ; DM1.4 77.15,29.15 76.46,28.46 74.35,28.46 73.99,28.11 73.51,28.11 73.11,28.51 73.11,29.3 72.75,29.65 72.07,29.65 71.84,29.42 v1(71.84,27.82)
  BOTTOM w0.216: v1(93.78,74.81) 95.95,76.98 99.91,76.98 102.07,79.13 102.07,79.13 v2(102.34,79.41) 103.02,80.09 103.33,80.09
M_A_DQ<5>: length 113.7
  L3 w0.102: v1(72.09,26.88) 72.09,26.83 72.14,26.78 72.14,24.14 72.27,24.01 72.52,24.01 72.65,24.14 72.65,26.07 72.8,26.22 73.01,26.22 73.16,26.07 v1(73.16,25.03) 79.05,19.14 82.52,19.14 v1(82.65,19.01)
  L4 w0.203: v1(93.86,73.92) 93.8,73.98 89.31,73.98 87.54,72.21 87.54,66.26 82.74,61.47 82.38,61.47 82.13,61.72 81.84,61.72 81.55,61.43 81.55,61.14 81.8,60.89 81.8,60.6 81.52,60.32 81.23,60.32 80.98,60.57 80.69,60.57 76.39,56.26 76.39,55.11 68.69,47.42 68.69,40.73 67.8,39.84 67.8,30.24 71.83,26.21 72.28,26.21 72.71,26.64 72.97,26.64 73.31,26.3 73.31,26.04 72.91,25.64 72.91,25.28 v1(73.16,25.03)
  BOTTOM w0.102: CPU1.A30 104.39,80.53 103.49,79.63 103.23,79.63 ; v1(72.09,26.88) 72.37,26.88 72.58,27.09 72.58,27.65 72.77,27.85 73.05,27.85 73.25,27.65 73.25,27.44 73.46,27.24 74.33,27.24 74.53,27.44 74.53,27.72 74.73,27.93 76.61,27.93 77.75,29.06 DM1.6 ; DM2.6 v1(82.65,19.01)
  BOTTOM w0.216: v1(93.86,73.92) 93.86,73.94 96.27,76.35 v2(97.72,76.35) 99.95,76.35 103.23,79.63
M_A_DQ<6>: length 118.2
  L3 w0.102: v1(85.65,18.23) 85.65,19.14 84.68,20.12 83,20.12 81.49,21.63 81.49,22.77 75.65,28.61 74.2,28.61 v1(74,28.81) 73.97,28.84 73.87,28.84 72.22,30.49 72.22,33.46 72.09,33.59 71.84,33.59 71.7,33.46 71.7,32.52 71.58,32.4 v1(71.31,32.4)
  L4 w0.203: v1(98.41,73.82) 97.83,73.82 95.94,71.94 95.94,68.02 93.37,65.44 90.67,65.44 88.65,63.43 88.65,63.14 88.92,62.87 88.92,62.58 88.63,62.29 88.34,62.29 88.08,62.56 87.79,62.56 87.5,62.28 87.5,61.99 88.54,60.95 88.54,60.66 88.26,60.37 87.97,60.37 86.93,61.41 86.64,61.41 86.37,61.15 86.37,60.82 86.6,60.59 86.6,60.21 86.32,59.93 85.15,59.93 72.3,47.07 72.3,43.84 72.5,43.63 72.88,43.63 73.08,43.43 73.08,43.02 72.88,42.82 72.5,42.82 72.3,42.62 72.3,41.72 71.51,40.93 71.51,37.47 70.21,36.17 70.21,32.09 73.31,28.99 73.82,28.99 v1(74,28.81)
  BOTTOM w0.102: DM2.16 v1(85.65,18.23) ; 103.21,76.53 104.22,76.53 104.48,76.79 104.48,77.91 104.89,78.33 106.84,78.33 CPU1.A34 ; DM1.16 80.75,31.28 80.09,31.94 76.27,31.94 75.86,31.53 74.2,31.53 74.2,31.58 73.33,32.44 72.75,32.44 72.58,32.27 72.58,31.15 72.45,31.02 72.19,31.02 72.07,31.15 72.07,32.27 71.94,32.4 v1(71.31,32.4)
  BOTTOM w0.216: v1(98.41,73.82) 98.62,73.61 100.29,73.61 v2(102.74,76.06) 103.21,76.53
M_A_DQ<7>: length 119.5
  L3 w0.102: v1(86.21,18.93) 86.21,19.04 84.68,20.57 83.33,20.57 81.82,22.08 81.82,23.04 75.2,29.65 74.04,29.65 v1(73.89,29.5) 73.71,29.5 72.6,30.61 72.6,35.14 72.4,35.34 71.94,35.34 71.71,35.11 71.71,33.89 71.58,33.77 v1(71.29,33.77)
  L4 w0.203: v1(97.7,72.83) 96.55,71.69 96.55,67.76 92.66,63.87 92.37,63.87 91.43,64.81 91.14,64.81 90.85,64.52 90.85,64.23 91.79,63.29 91.79,63 91.51,62.72 91.22,62.72 90.18,63.76 89.89,63.76 89.6,63.47 89.6,63.18 90.64,62.14 90.64,61.85 90.36,61.57 90.07,61.57 89.57,62.06 89.29,62.06 89,61.77 89,61.49 89.49,60.99 89.49,60.7 88.11,59.32 85.41,59.32 73.59,47.5 73.59,42.06 72.12,40.59 72.12,37.36 70.72,35.96 70.72,32.3 73.52,29.5 v1(73.89,29.5)
  BOTTOM w0.102: 104.06,76.02 104.68,76.64 104.68,77.51 104.91,77.73 104.98,77.73 105.37,78.12 106.59,78.12 106.62,78.1 106.7,78.03 106.98,78.03 107.29,78.33 CPU1.B34 ; DM2.18 86.25,18.9 v1(86.21,18.93) ; v1(71.29,33.77) 72.73,33.77 74.39,32.11 75.95,32.11 76.05,32.22 80.45,32.22 81.35,31.32 DM1.18
  BOTTOM w0.216: 104.06,76.02 103.58,76.02 v2(101.41,73.85) 100.53,72.97 97.84,72.97 v1(97.7,72.83)
M_A_DQ<8>: length 103.1
  TOP w0.216: v1(77.93,31.51) 77.93,30.95 v2(77.93,30.95)
  L3 w0.102: v1(85.9,22.92) 85.9,23.24 82.99,26.15 82.99,26.96 82.63,27.32 81.51,27.32 81.26,27.57 81.26,29.32 81.13,29.45 80.82,29.45 80.51,29.14 80.33,29.14 80.13,29.33 80.13,29.51 80.64,30.02 80.64,30.5 79.46,31.68 78.11,31.68 v1(77.93,31.51) 77.91,31.53 77.91,31.58 77.05,32.45 77.05,35.98 83.04,41.97 v1(83.32,41.97)
  L4 w0.203: v1(104.89,73.19) 104.84,73.24 103.72,73.24 101.56,71.08 101.56,69.43 100.87,68.74 100.87,66.04 89.88,55.05 87.18,55.05 77.96,45.84 77.96,40.86 76.39,39.29 76.39,34.11 76.64,33.85 76.64,33.31 77.07,32.88 77.07,31.02 78.48,29.62 78.76,29.62 79.39,30.25 79.39,30.53 78.42,31.51 v1(77.93,31.51)
  BOTTOM w0.102: v1(83.32,41.97) 83.32,40.52 82.25,39.45 DM1.21 ; v1(85.9,22.92) 86.34,22.92 87.15,23.73 DM2.21 ; CPU1.B37 106.96,76.68 106.64,76.36 106.05,76.36 104.92,75.23 104.92,73.21 v1(104.89,73.19)
M_A_DQ<9>: length 105.9
  TOP w0.216: v2(76.46,30.92) v1(76.46,31.51)
  L3 w0.102: v1(83.42,43.57) 82.9,43.05 82.9,42.26 76.74,36.1 76.74,31.79 v1(76.46,31.51) 76.89,31.07 77.88,31.07 78.27,30.69 78.41,30.69 78.72,31.01 78.89,31.01 79.01,30.89 79.01,30.72 78.7,30.41 78.7,30.26 78.97,29.99 79.11,29.99 79.5,30.38 79.67,30.38 79.79,30.26 79.79,30.09 79.4,29.7 79.4,29.56 80.96,28 80.96,27.44 85.47,22.93 85.47,22.3 v1(86.01,21.75)
  L4 w0.203: v1(76.46,31.51) 76.13,31.84 76.13,33.64 75.88,33.89 75.88,39.5 77.32,40.95 77.32,46.06 86.92,55.66 89.63,55.66 100.26,66.3 100.26,68.99 100.95,69.68 100.95,71.33 103.97,74.35 103.97,75.12 104.17,75.32 104.6,75.32 104.81,75.12 104.81,73.94 105.01,73.74 v1(105.49,73.74)
  BOTTOM w0.102: v1(86.01,21.75) 86.27,21.75 86.9,22.39 86.9,23.07 87.75,23.92 DM2.23 ; v1(105.49,73.74) 105.13,74.09 105.13,75.16 106.1,76.13 CPU1.A38 ; v1(83.42,43.57) 83.83,43.17 83.83,40.12 82.85,39.14 DM1.23
M_A_DQ<10>: length 104.4
  L3 w0.102: v1(85.71,42.23) 85.71,41.74 85.23,41.27 85.09,41.27 84.76,41.59 84.62,41.59 84.47,41.45 84.47,41.31 84.8,40.98 84.8,40.84 84.66,40.69 84.51,40.69 84.19,41.02 84.04,41.02 83.9,40.87 83.9,40.73 84.23,40.41 84.23,40.26 84.08,40.12 83.94,40.12 83.61,40.44 83.47,40.44 83.32,40.3 83.32,40.16 83.65,39.83 83.65,39.69 83.51,39.54 83.36,39.54 83.04,39.87 82.89,39.87 82.75,39.72 82.75,39.58 83.08,39.26 83.08,39.11 79.86,35.9 79.86,34.45 v1(79.43,34.02) 83.93,29.53 83.93,26.6 85.73,24.8 86.8,24.8 88.65,22.95 v1(88.65,22.77)
  L4 w0.203: v1(104.38,69.3) 104.05,69.3 103.64,69.71 103.64,70.22 104.58,71.16 106,71.16 106.18,71.33 106.18,71.74 105.93,71.99 104.2,71.99 102.78,70.57 102.78,69.35 103.21,68.92 103.21,65.29 90.78,52.87 88.11,52.87 80.68,45.44 80.68,41.14 78.93,39.39 78.93,34.53 v1(79.43,34.02)
  BOTTOM w0.102: CPU1.D40 108.45,74.96 108.14,74.66 108.14,74.4 108.28,74.27 108.28,73.42 107.96,73.1 107.65,73.1 ; DM1.33 85.85,42.08 v1(85.71,42.23) ; v1(88.65,22.77) 88.83,22.77 89.75,23.68 90.3,23.68 90.75,24.13 DM2.33
  BOTTOM w0.216: v1(104.38,69.3) v2(105.11,69.3) 105.24,69.3 106.07,70.13 106.07,71.53 107.65,73.1
M_A_DQ<11>: length 111.1
  L3 w0.102: v1(85.73,43.62) 85.73,43.52 82.06,39.84 82.06,39.7 82.55,39.21 82.55,39.07 82.4,38.92 82.26,38.92 81.77,39.41 81.62,39.41 81.48,39.27 81.48,39.13 81.97,38.63 81.97,38.49 81.83,38.35 81.68,38.35 81.19,38.84 81.05,38.84 80.91,38.69 80.91,38.55 81.4,38.06 81.4,37.92 81.25,37.77 81.11,37.77 80.62,38.26 80.47,38.26 80.33,38.12 80.33,37.98 80.82,37.48 80.82,37.34 80.68,37.2 80.53,37.2 80.06,37.67 79.88,37.67 79.75,37.54 79.75,37.36 80.17,36.94 80.17,36.76 80,36.6 79.67,36.6 79.43,36.36 v1(79.43,35.52) 79,35.09 79,33.79 83.62,29.17 83.62,26.48 88.65,21.45 v1(88.73,21.45)
  L4 w0.203: v1(79.43,35.52) 79.43,39.18 81.82,41.57 81.82,44.56 81.72,44.67 81.72,45.62 88.36,52.26 91.04,52.26 103.94,65.17 v1(103.94,68.57)
  BOTTOM w0.102: CPU1.D41 108.45,74.39 108.48,74.35 108.48,73.21 108.25,72.98 ; DM2.35 91.35,24.2 90.61,23.46 89.95,23.46 89.59,23.1 89.59,22.31 v1(88.73,21.45) ; DM1.35 86.45,41.74 86.32,41.87 86.32,43.04 v1(85.73,43.62)
  BOTTOM w0.216: 108.25,72.98 106.69,71.42 106.69,69.97 v2(106.59,69.86) 106.59,69.54 105.28,68.23 105.28,65.91 105.49,65.71 107.2,65.71 107.4,65.5 107.4,65.03 107.2,64.83 104.63,64.83 104.43,65.03 104.43,68.36 104.22,68.57 v1(103.94,68.57)
M_A_DQ<12>: length 103.6
  L3 w0.102: v1(87.36,18.4) 87.59,18.17 87.59,17.82 87.48,17.71 86.77,17.71 86.65,17.84 86.65,19.11 84.86,20.9 84.86,22.68 81.87,25.66 81.25,26.29 v1(80.04,26.29) 80.04,26.31 79.61,26.74 79.61,27.29 75.72,31.18 75.72,32.47 v1(75.6,32.6)
  L4 w0.203: v1(100.18,70.94) 99.84,70.94 98.99,70.09 98.99,66.75 89.12,56.88 86.42,56.88 76.08,46.54 76.08,41.18 74.59,39.69 74.59,36.65 72.79,34.84 72.79,33.2 79.7,26.29 v1(80.04,26.29)
  BOTTOM w0.102: v1(75.6,32.6) 75.62,32.62 80.74,32.62 82.55,30.8 DM1.22 ; v1(87.36,18.4) 87.45,18.31 DM2.22 ; 104.32,74.44 104.51,74.64 104.51,75.43 105.91,76.82 106.18,76.82 106.34,76.98 106.65,76.98 106.72,76.93 107.02,76.93 107.32,77.23 CPU1.B36
  BOTTOM w0.216: v1(100.18,70.94) 101.16,70.94 v2(101.78,71.57) 104.32,74.1 104.32,74.44
M_A_DQ<13>: length 103
  L3 w0.102: v1(75.65,33.28) 76.03,32.9 76.03,31.3 78.76,28.57 78.91,28.57 79.07,28.73 79.24,28.73 79.35,28.61 79.35,28.45 79.19,28.28 79.19,28.14 79.76,27.57 80.07,27.57 v1(80.08,27.56) 80.41,27.56 85.16,22.81 85.16,21.08 86.47,19.77 87.6,19.77 v1(87.82,19.55)
  L4 w0.203: v1(80.08,27.56) 80.07,27.57 79.31,27.57 79.27,27.59 73.29,33.57 73.29,34.63 75.15,36.49 75.15,39.52 76.69,41.06 76.69,46.29 86.67,56.27 89.37,56.27 99.6,66.5 99.6,69.68 v1(100.12,70.2)
  BOTTOM w0.102: 104.2,72.95 104.34,73.1 104.34,73.44 104.71,73.82 104.71,75.32 105.98,76.58 106.4,76.58 CPU1.A37 ; DM1.24 83.15,30.71 80.86,33.01 76.26,33.01 75.98,33.28 v1(75.65,33.28) ; v1(87.82,19.55) 88.83,19.55 88.96,19.42 88.96,19.04 88.83,18.91 88.4,18.91 88.05,18.56 DM2.24
  BOTTOM w0.216: v1(100.12,70.2) 100.14,70.19 v2(101.15,70.19) 101.43,70.19 104.2,72.95
M_A_DQ<14>: length 100.3
  L3 w0.102: v1(91.19,19.09) 90.48,19.09 90.08,19.49 90.08,20.58 90.89,21.4 90.89,23.43 88.3,26.02 86.75,26.02 85.63,27.14 v1(85.3,27.14) 85.71,27.54 85.71,29.96 82.15,33.51 v1(82.15,34.22)
  L4 w0.203: v1(85.3,27.14) 85.3,26.81 86.34,25.77 86.34,24.93 86.19,24.78 84.51,24.78 84.31,24.98 84.31,29.47 81.19,32.6 80.55,32.6 79.94,33.21 79.94,36.1 80.12,36.28 80.12,39.03 82.33,41.24 82.33,45.31 88.67,51.65 91.29,51.65 104.55,64.91 104.55,68.44 105.16,69.05 105.16,69.53 104.65,70.04 v1(104.17,70.04)
  BOTTOM w0.102: v1(82.15,34.22) 82.15,34.05 84.97,31.23 85.88,31.23 86.15,30.96 DM1.34 ; v1(91.19,19.09) 91.05,18.94 DM2.34
  BOTTOM w0.216: CPU1.B41 106.71,73.79 106.71,73.33 105.17,71.79 105.17,71.45 104.33,70.61 v2(104.33,70.6) 104.33,70.19 v1(104.17,70.04)
M_A_DQ<15>: length 103.2
  L3 w0.102: v1(91.65,18.4) 91.65,18.55 91.78,18.68 92.39,18.68 92.45,18.74 92.45,18.92 91.85,19.52 90.5,19.52 90.38,19.64 90.38,19.81 90.5,19.93 91.57,19.93 91.7,20.06 91.7,20.21 91.57,20.34 90.74,20.34 90.61,20.47 90.61,20.66 90.74,20.79 91.07,20.79 91.19,20.92 91.19,24.04 90.42,24.81 89.94,24.81 88.43,26.33 87.05,26.33 v1(86.6,26.78) 86.16,27.21 86.16,29.93 82.58,33.51 82.58,35.32 v1(82.23,35.67)
  L4 w0.203: v1(86.6,26.78) 85.94,27.44 85.94,28.71 81.43,33.22 80.92,33.22 80.45,33.69 80.45,35.57 80.63,35.75 80.63,38.82 82.84,41.03 82.84,44.05 83.29,44.51 83.29,45.41 88.92,51.04 91.54,51.04 105.16,64.66 105.16,68.18 105.69,68.71 106.12,68.71 106.59,69.18 106.59,70.32 106.38,70.52 105.09,70.52 v1(105.01,70.45)
  BOTTOM w0.102: CPU1.C40 107.48,74.46 107.48,73.95 107.34,73.82 107.34,73.42 ; v1(82.23,35.67) 82.63,35.27 82.63,33.89 85.02,31.51 86.06,31.51 86.75,30.82 DM1.36 ; DM2.36 v1(91.65,18.4)
  BOTTOM w0.216: v1(105.01,70.45) 105.11,70.45 v2(105.54,70.88) 105.65,70.99 105.65,71.73 107.34,73.42
M_A_DQ<16>: length 98.1
  L3 w0.102: v1(86.85,42.33) 86.85,40.12 85.99,39.26 85.85,39.26 85.31,39.8 85.16,39.8 85.02,39.66 85.02,39.51 85.56,38.97 85.56,38.83 85.42,38.68 85.27,38.68 84.77,39.19 84.6,39.19 84.48,39.07 84.48,38.9 84.99,38.4 84.99,38.25 84.84,38.11 84.7,38.11 84.22,38.59 84.05,38.59 83.93,38.47 83.93,38.3 84.41,37.82 84.41,37.68 84.27,37.53 84.12,37.53 83.67,37.99 83.5,37.99 83.38,37.87 83.38,37.7 83.84,37.25 83.84,37.1 83.69,36.96 82.4,36.96 81.01,35.57 v1(81.01,35.39) 81.41,34.99 81.41,33.23 84.54,30.11 84.54,26.86 85.99,25.41 87.74,25.41 v1(90.13,23.02)
  L4 w0.203: v1(81.01,35.39) 81.13,35.52 81.13,36.36 81.49,36.71 81.49,38.96 83.9,41.38 83.9,45.16 89.17,50.43 91.8,50.43 105.8,64.43 105.8,66.84 106.41,67.45 106.41,67.78 106.26,67.93 v1(105.77,67.93)
  BOTTOM w0.102: DM2.39 92.55,24.3 91.23,22.97 90.18,22.97 v1(90.13,23.02) ; CPU1.F40 109.55,74.96 109.24,74.66 109.24,74.36 109.3,74.31 109.3,72.16 109.2,72.06 ; DM1.39 87.65,41.63 86.95,42.33 v1(86.85,42.33)
  BOTTOM w0.216: 109.2,72.06 108.59,71.45 108.59,70.99 v2(108.6,70.98) 108.59,70.97 108.59,69.34 107.84,68.59 107.84,67.35 107.65,67.17 106.89,67.17 106.13,67.93 v1(105.77,67.93)
M_A_DQ<17>: length 99.6
  L3 w0.102: v1(86.88,43.72) 86.42,43.27 86.42,42.02 85.96,41.56 85.96,41.42 86.46,40.91 86.46,40.75 86.34,40.63 86.17,40.63 85.67,41.13 85.53,41.13 85.38,40.99 85.38,40.84 85.96,40.26 85.96,40.09 85.84,39.97 85.68,39.97 85.09,40.56 84.95,40.56 80.2,35.8 80.2,34.73 v1(80.96,33.97) 81.01,33.92 81.01,33.21 84.23,29.98 84.23,26.73 85.86,25.11 86.93,25.11 89.67,22.36 89.67,22.18 v1(90.15,21.7)
  L4 w0.203: v1(106.38,66.64) 106.43,66.59 106.43,64.2 92.05,49.82 89.43,49.82 84.53,44.93 84.53,41.29 82.1,38.85 82.1,36.36 81.64,35.9 81.64,34.22 81.39,33.97 v1(80.96,33.97)
  BOTTOM w0.102: v1(86.88,43.72) 87.79,42.81 87.79,42.14 88.25,41.68 DM1.41 ; v1(90.15,21.7) 90.99,21.7 93.15,23.86 DM2.41 ; 109.52,71.77 109.52,74.34 109.55,74.37 CPU1.F41
  BOTTOM w0.216: 109.52,71.77 109.27,71.53 v2(109.27,69.64) 109.27,69.14 108.37,68.23 108.37,66.81 107.88,66.33 106.69,66.33 v1(106.38,66.64)
M_A_DQ<18>: length 97.4
  L3 w0.102: v1(94.88,22.57) 94.83,22.57 90.94,26.45 90.46,26.45 89.87,27.04 89.87,29.65 86.85,32.68 86.85,33.77 v1(86.01,34.61) 86.01,34.91 87.56,36.46 89.19,36.46 89.44,36.71 89.44,37.02 89.34,37.12 88.44,37.12 88.32,37.24 88.32,37.41 88.44,37.53 89.34,37.53 89.44,37.63 89.44,37.93 89.34,38.03 88.54,38.03 88.42,38.15 88.42,38.32 88.54,38.44 89.34,38.44 89.44,38.54 89.44,41.97 v1(89.03,42.38)
  L4 w0.203: v1(109.76,64.25) 109.95,64.06 109.95,62.91 93.46,46.42 90.84,46.42 88.55,44.13 88.55,41.31 86.01,38.77 v1(86.01,34.61)
  BOTTOM w0.102: v1(94.88,22.57) 95.13,22.57 96.15,23.59 DM2.51 ; v1(89.03,42.38) 89.42,42 89.42,41.21 91.25,39.38 DM1.51 ; 111.79,72.07 111.79,72.51 111.56,72.75 111.56,74.25 111.44,74.36 111.44,74.68 111.75,74.98 CPU1.K40
  BOTTOM w0.216: 111.79,72.07 111.79,68.69 112.45,68.03 v2(112.45,66.08) 112.45,64.98 112.25,64.78 111.67,64.78 111.51,64.93 111.51,65.19 111.31,65.39 108.39,65.39 108.19,65.19 108.19,64.53 108.39,64.32 109.68,64.32 v1(109.76,64.25)
M_A_DQ<19>: length 98.9
  L3 w0.102: v1(94.88,21.22) 94.44,21.65 94.44,22.52 90.93,26.03 90.44,26.03 89.57,26.91 89.57,29.53 85.94,33.16 v1(85.94,33.26) 85.55,33.64 85.55,34.88 87.92,37.25 87.92,38.72 88.04,38.85 89.03,38.85 89.14,38.95 89.14,41.36 88.27,42.23 88.27,43.67 88.4,43.8 v1(89.03,43.8)
  L4 w0.203: v1(85.94,33.26) 86.37,33.26 86.55,33.44 86.55,38.49 89.57,41.51 89.57,44.29 91.09,45.81 93.71,45.81 110.56,62.66 110.56,64.67 v1(110.37,64.86)
  BOTTOM w0.102: DM1.53 91.85,39.44 90.2,41.09 90.2,42.94 89.34,43.8 v1(89.03,43.8) ; DM2.53 96.72,24.94 96.72,23.02 94.93,21.22 v1(94.88,21.22) ; 112.13,72.47 111.76,72.84 111.76,74.52 CPU1.K41
  BOTTOM w0.216: 112.13,72.47 112.13,69.17 v2(112.22,69.07) 113.11,68.18 113.11,64.37 112.88,64.15 111.08,64.15 v1(110.37,64.86)
M_A_DQ<20>: length 92.8
  L3 w0.102: v1(93.43,19.92) 92.51,19.92 92.31,20.13 92.31,23.79 90.68,25.42 90.19,25.42 88.55,27.06 v1(88.09,27.06) 88.09,27.09 87.66,27.52 87.66,29.53 v1(83.32,33.87)
  L4 w0.203: v1(88.09,27.06) 88.09,27.06 87.61,27.55 87.61,28.76 83.8,32.57 83.8,35.36 83.69,35.48 83.69,35.53 83.46,35.76 83.46,38.76 86.27,41.58 86.27,44.94 89.93,48.6 92.55,48.6 107.65,63.7 107.65,69.48 v1(107.4,69.73)
  BOTTOM w0.102: v1(93.43,19.92) 93.4,19.9 92.41,19.9 92.29,19.77 92.29,19.49 92.41,19.37 92.67,19.37 92.85,19.18 DM2.40 ; CPU1.E40 109,74.61 108.68,74.3 108.68,72.79 ; v1(83.32,33.87) 85.4,31.79 87.28,31.79 87.95,31.12 DM1.40
  BOTTOM w0.216: v1(107.4,69.73) v2(107.4,70.78) 107.4,71.51 108.68,72.79
M_A_DQ<21>: length 93.6
  L3 w0.102: v1(93.45,18.35) 92.01,19.79 92.01,21.58 91.88,21.71 91.74,21.71 91.63,21.83 91.63,21.99 91.74,22.11 91.88,22.11 92.01,22.24 92.01,22.39 91.88,22.52 91.77,22.52 91.65,22.64 91.65,22.81 91.77,22.93 91.88,22.93 92.01,23.05 92.01,23.66 90.55,25.12 90.06,25.12 88.55,26.63 87.92,26.63 87.36,27.19 87.36,28 87.23,28.13 v1(86.6,28.13) 86.6,29.93 82.89,33.64 82.89,35.04 v1(83.19,35.34)
  L4 w0.203: v1(107.04,68.92) 107.04,63.95 92.3,49.21 89.68,49.21 85.14,44.67 85.14,41.18 82.71,38.75 82.71,32.8 86.6,28.92 v1(86.6,28.13)
  BOTTOM w0.102: v1(93.45,18.35) DM2.42 ; DM1.42 88.55,30.87 87.28,32.14 86.11,32.14 84.67,33.59 84.66,33.59 84.41,33.84 84.41,33.84 83.87,34.39 83.87,34.75 83.27,35.34 v1(83.19,35.34)
  BOTTOM w0.14: 108.97,72.47 109,72.5 CPU1.E41
  BOTTOM w0.216: v1(107.04,68.92) 107.36,68.92 v2(108.01,69.56) 108.01,71.51 108.97,72.47
M_A_DQ<22>: length 91.5
  L3 w0.102: v1(95.84,18.73) 96.32,18.73 96.53,18.93 96.53,20.76 95.89,21.4 95.89,22.59 95.18,23.3 94.95,23.3 92.03,26.23 92.03,26.53 91.32,27.24 91.32,27.54 v1(90.61,28.26) 90.91,28.56 90.91,29.93 90.7,30.15 90.55,30.15 90.47,30.06 90.33,30.06 90.18,30.21 90.18,30.35 90.27,30.44 90.27,30.58 90.12,30.72 89.98,30.72 89.89,30.64 89.75,30.64 89.61,30.78 89.61,30.93 89.69,31.01 89.69,31.16 89.55,31.3 89.4,31.3 89.32,31.21 89.18,31.21 89.03,31.36 89.03,31.5 89.12,31.59 89.12,31.73 88.4,32.45 88.4,34.28 88.27,34.4 88.12,34.4 87.94,34.22 87.94,33.84 87.82,33.72 v1(87.59,33.72)
  L4 w0.203: v1(110.57,66.88) 111.03,67.34 111.45,67.34 111.78,67.02 111.78,62.15 94.32,44.69 91.55,44.69 90.66,43.79 90.66,40.89 88.12,38.36 88.12,32.32 90.95,29.49 90.95,28.6 v1(90.61,28.26)
  BOTTOM w0.102: v1(95.84,18.73) 95.85,18.72 DM2.50 ; DM1.50 90.95,31.19 90.36,31.79 89.44,31.79 87.59,33.64 v1(87.59,33.72) ; 111.03,72.06 111.03,73.8 110.89,73.93 110.89,74.31 111.2,74.62 CPU1.J40
  BOTTOM w0.216: v1(110.57,66.88) 110.95,67.27 v2(110.95,69.33) 110.95,71.98 111.03,72.06
M_A_DQ<23>: length 92.9
  L3 w0.102: v1(87.61,34.5) 87.15,34.05 87.15,32.8 90.18,29.78 90.18,27.34 v1(90.63,26.88) 91.24,26.88 91.73,26.4 91.73,26.1 94.83,23 95.06,23 95.59,22.47 95.59,21.32 95.13,20.86 95.13,20.28 95.23,20.18 95.79,20.18 v1(95.87,20.25)
  L4 w0.203: v1(90.63,26.88) 89.97,27.54 89.97,29.55 87.05,32.47 87.05,38.14 90.15,41.23 90.15,44 91.34,45.2 93.96,45.2 111.17,62.4 111.17,65.51 v1(110.57,66.12)
  BOTTOM w0.102: DM2.52 96.45,19.44 96.58,19.57 97.29,19.57 97.42,19.7 97.42,20 97.29,20.13 95.99,20.13 v1(95.87,20.25) ; DM1.52 91.55,30.95 90.23,32.27 89.64,32.27 88.35,33.56 88.35,33.77 v1(87.61,34.5)
  BOTTOM w0.14: 111.37,72.2 111.28,72.29 111.28,74.1 CPU1.J41
  BOTTOM w0.216: v1(110.57,66.12) 110.58,66.13 v2(111.16,66.13) 111.37,66.34 111.37,72.2
M_A_DQ<24>: length 98.7
  L3 w0.102: v1(91.57,43.34) 90,43.34 89.87,43.22 89.87,42.86 89.97,42.75 90.87,42.75 90.99,42.64 90.99,42.47 90.87,42.35 89.97,42.35 89.87,42.25 89.87,37.12 89.97,37.02 90.79,37.02 90.91,36.9 90.91,36.73 90.79,36.61 89.97,36.61 89.87,36.51 89.87,35.67 89.49,35.29 89.21,35.29 v1(89.14,35.22) 89.62,34.73 89.62,32.52 93,29.14 93,26.55 95.28,24.27 96.48,24.27 97.21,23.53 v1(97.21,23.2)
  L4 w0.203: v1(89.14,35.22) 89.14,37.78 113.01,61.66 113.01,67.93 112.48,68.46 112.48,68.75 112.78,69.04 113.07,69.04 113.64,68.47 v1(114.56,68.47)
  BOTTOM w0.102: DM1.57 93.05,39.15 91.29,40.91 90.96,40.91 90.71,41.16 90.71,42.48 v1(91.57,43.34) ; v1(97.21,23.2) 97.64,22.77 97.64,22.31 97.77,22.19 98.03,22.19 98.15,22.31 98.15,23.73 97.95,23.94 DM2.57 ; CPU1.M41 112.85,73.81 113.06,73.59 113.06,72.58 113.47,72.18 113.47,70.32 113.82,69.97
  BOTTOM w0.216: 113.82,69.97 v2(114.28,69.51) 114.37,69.42 115.25,69.42 115.45,69.21 115.45,67.12 115.25,66.91 114.82,66.91 114.61,67.12 114.61,68.42 v1(114.56,68.47)
M_A_DQ<25>: length 96.4
  L3 w0.102: v1(99.3,21.91) 96.63,24.57 95.41,24.57 93.3,26.68 93.3,29.32 90.33,32.29 v1(90.33,33.69) 89.95,34.07 89.95,35.32 91.55,36.92 91.55,37.32 91.45,37.43 90.32,37.43 90.2,37.55 90.2,37.71 90.32,37.83 91.45,37.83 91.55,37.93 91.55,38.14 91.45,38.24 90.3,38.24 90.18,38.36 90.18,38.53 90.3,38.65 91.45,38.65 91.55,38.75 91.55,38.95 91.45,39.05 90.36,39.05 90.23,39.18 90.23,41.21 90.36,41.33 91.13,41.33 v1(91.14,41.34)
  L4 w0.203: v1(90.33,33.69) 90.33,32.78 90.9,32.21 91.24,32.21 91.6,32.57 91.6,33.06 90.99,33.67 90.99,37.05 114.84,60.9 114.84,67.32 115.63,68.11 115.63,69.84 115.45,70.01 115.01,70.01 v1(114.9,69.91)
  BOTTOM w0.102: DM1.59 93.65,39.16 91.47,41.34 v1(91.14,41.34) ; v2(113.97,70.83) 113.7,71.11 113.7,72.32 113.31,72.71 113.31,73.84 113.09,74.05 113.09,74.31 113.4,74.61 CPU1.N40 ; DM2.59 98.48,24.9 98.48,22.72 v1(99.3,21.91)
  BOTTOM w0.216: v2(113.97,70.83) 113.98,70.83 v1(114.9,69.91)
M_A_DQ<26>: length 95.9
  L3 w0.102: v1(92.64,42.38) 92.62,42.38 92.36,42.12 92.36,32.35 92.64,32.07 v1(92.85,31.86) 92.9,31.81 92.9,31.66 96.3,28.26 96.3,27.16 98.56,24.9 100,24.9 100.2,24.7 102.01,24.7 102.14,24.57 102.14,24.07 102.01,23.94 101.38,23.94 v1(100.95,23.51)
  L4 w0.203: v1(116.56,65.39) 117.08,64.86 117.08,60.05 93.86,36.83 93.86,31.79 93.57,31.49 93.21,31.49 v1(92.85,31.86)
  BOTTOM w0.102: DM1.67 96.05,38.97 94.55,40.47 94.55,40.61 94.82,40.88 94.82,41.16 94.62,41.36 94.34,41.36 94.17,41.18 93.83,41.18 v1(92.64,42.38) ; v1(100.95,23.51) 100.95,23.53 100.95,23.53 DM2.67
  BOTTOM w0.14: CPU1.T41 115.05,74.28 115.65,73.67 115.97,73.67
  BOTTOM w0.216: v1(116.56,65.39) 115.65,65.39 115.09,65.95 114.64,65.95 114.43,65.75 114.43,64.72 114.64,64.51 116.95,64.51 117.23,64.8 117.23,67.3 117.03,67.5 v2(117.03,71.16) 117.03,72.61 115.97,73.67
M_A_DQ<27>: length 98.1
  L3 w0.102: v1(101.63,23.51) 102.22,23.51 102.65,23.94 102.65,24.83 102.27,25.21 98.69,25.21 96.63,27.27 96.63,28.41 93.38,31.66 93.38,32.55 93,32.93 92.99,32.93 v1(92.79,33.13) 92.67,33.26 92.67,41.74 93.1,42.17 93.1,43.24 92.69,43.65 v1(92.62,43.65)
  L4 w0.203: v1(92.79,33.13) 93.1,33.44 93.1,36.93 116.47,60.3 v1(116.47,63.89)
  BOTTOM w0.102: v1(92.62,43.65) 93.1,43.17 93.53,42.73 94.09,42.73 95.67,41.15 95.67,40.96 95.37,40.66 95.37,40.48 95.65,40.21 95.83,40.21 96.15,40.53 96.29,40.53 96.65,40.17 DM1.69 ; v1(101.63,23.51) 101.55,23.59 DM2.69 ; CPU1.U40 115.6,74.62 116.06,74.16
  BOTTOM w0.216: v1(116.47,63.89) 121.14,63.89 121.34,64.1 121.34,64.58 121.14,64.78 118.06,64.78 117.86,64.98 117.86,67.89 117.68,68.07 v2(117.68,69.33) 117.68,72.48 116.06,74.11 116.06,74.16
M_A_DQ<28>: length 97.6
  TOP w0.216: v2(87.64,36.41) v1(87.64,35.85)
  L3 w0.102: v1(87.64,35.85) 88.7,34.78 88.7,32.57 91.22,30.06 91.22,28.08 91.63,27.67 91.63,27.54 91.88,27.29 91.88,27.29 v1(92.08,27.09) 92.34,26.83 92.34,26.35 95.08,23.61 95.31,23.61 96.2,22.72 96.2,22.01 96.32,21.88 96.73,21.88 96.86,21.75 96.86,21.12 96.93,21.04 97.57,21.04 97.7,20.92 97.7,20.76 97.57,20.64 96.98,20.64 96.86,20.52 96.86,20.35 96.98,20.23 98.31,20.23 98.43,20.1 98.43,19.92 98.33,19.82 96.95,19.82 96.83,19.7 96.83,19.53 96.95,19.41 97.55,19.41 v1(97.9,19.06)
  L4 w0.203: v1(113.62,67.57) 113.62,61.41 89.67,37.45 89.67,32.52 92.54,29.65 92.54,27.52 92.26,27.24 92.23,27.24 v1(92.08,27.09)
  BOTTOM w0.102: v1(87.64,35.85) 88.55,34.94 88.55,33.84 89.57,32.83 90.71,32.83 92.75,30.79 DM1.56 ; DM2.56 97.65,18.81 v1(97.9,19.06) ; 112.55,70.3 v2(112.55,71.54) 112.55,72.59 111.99,73.15 111.99,74.31 112.3,74.61 CPU1.L40
  BOTTOM w0.216: 112.55,70.3 112.55,69.45 113.62,68.39 v1(113.62,67.57)
M_A_DQ<29>: length 92.1
  L3 w0.102: v1(98.74,19.06) 98.74,20.38 96.71,22.41 96.71,22.64 95.44,23.91 95.21,23.91 92.69,26.43 92.69,27.75 92.03,28.41 v1(91.98,28.41) 92.21,28.64 92.56,28.64 92.69,28.76 92.69,28.92 92.56,29.04 91.65,29.04 91.52,29.17 91.52,29.35 91.65,29.47 91.83,29.47 91.96,29.6 91.96,29.75 89.31,32.4 89.31,33.69 v1(89.19,33.82)
  L4 w0.203: v1(91.98,28.41) 91.98,29.32 88.63,32.68 88.63,38.15 92.11,41.63 92.11,43.9 92.39,44.18 94.67,44.18 112.39,61.9 112.39,67.54 111.89,68.03 111.89,69.33 112.34,69.78 113.14,69.78 v1(113.63,69.29)
  BOTTOM w0.102: v1(98.74,19.06) 98.25,18.57 DM2.58 ; 112.96,70.57 112.96,72.39 112.86,72.5 112.86,73.51 112.6,73.77 112.6,74.31 112.54,74.36 112.54,74.66 112.85,74.96 CPU1.M40 ; v1(89.19,33.82) 89.44,33.82 90.08,33.18 91.27,33.18 92.01,32.45 92.01,32.09 92.77,31.33 93.12,31.33 93.35,31.1 DM1.58
  BOTTOM w0.216: 112.96,70.57 112.96,70.09 113.13,69.92 v2(113.13,69.91) 113.63,69.42 v1(113.63,69.29)
M_A_DQ<30>: length 93.1
  TOP w0.216: v2(91.6,33.18) v1(91.6,33.74)
  L3 w0.102: v1(101.25,18.43) 101.42,18.6 101.42,19.22 101.29,19.34 101.09,19.34 100.97,19.46 100.97,19.63 101.09,19.75 101.29,19.75 101.42,19.88 101.42,20.16 101.25,20.33 101.05,20.33 100.92,20.46 100.92,20.66 101.05,20.79 101.2,20.79 101.33,20.92 101.33,21.14 101.2,21.27 100.75,21.27 100.08,21.94 100.08,23.81 99.6,24.29 98.15,24.29 95.56,26.88 v1(95.56,26.88) 94.75,27.7 94.75,28.84 91.6,31.99 v1(91.6,33.74)
  L4 w0.203: v1(95.56,26.88) 95.51,26.88 95.03,27.37 95.03,29.27 94.83,29.47 94.14,29.47 93.94,29.68 93.94,30.08 94.14,30.29 94.83,30.29 95.03,30.49 95.03,31 94.37,31.66 94.37,36.62 102.18,44.43 102.32,44.43 117.69,59.8 117.69,65.28 116.92,66.05 v1(116.59,66.05)
  BOTTOM w0.102: v1(91.6,33.74) 91.8,33.95 92.84,33.95 95.09,31.7 95.63,31.7 96.35,30.97 DM1.68 ; DM2.68 v1(101.25,18.43) ; CPU1.R40 114.5,74.63 114.19,74.32 114.19,73.54 114.63,73.1 114.88,73.1
  BOTTOM w0.216: v1(116.59,66.05) 115.88,66.76 v2(115.88,71.77) 115.88,72.4 115.18,73.1 114.88,73.1
M_A_DQ<31>: length 94.8
  L3 w0.102: v1(101.85,19.21) 102.17,19.21 102.29,19.34 102.29,19.82 102.17,19.95 101.99,19.95 101.86,20.08 101.86,20.38 101.99,20.51 102.22,20.51 102.34,20.64 102.34,21.19 102.22,21.32 101.96,21.32 100.39,22.9 100.39,23.94 99.73,24.6 98.28,24.6 95.99,26.88 95.99,27.82 v1(95.51,28.31) 95.51,28.59 92.03,32.07 92.03,34.81 v1(91.63,35.22)
  L4 w0.203: v1(116.75,67.09) 118.3,65.54 118.3,59.55 102.57,43.81 102.28,43.81 94.88,36.41 94.88,32.01 95.79,31.1 95.79,29.58 97.01,28.36 97.01,27.62 96.81,27.42 96.4,27.42 v1(95.51,28.31)
  BOTTOM w0.102: 115.27,73.58 115.27,73.74 114.8,74.2 114.8,74.31 114.74,74.36 114.74,74.66 115.05,74.96 CPU1.T40 ; DM1.70 96.95,30.88 95.83,32 95.09,32 91.88,35.22 v1(91.63,35.22) ; DM2.70 v1(101.85,19.21)
  BOTTOM w0.216: v1(116.75,67.09) 116.43,67.4 v2(116.43,69.72) 116.43,72.41 115.27,73.58
M_A_DQ<32>: length 85.5
  L3 w0.102: v1(119.51,26.66) 119.51,26.66 118.7,27.47 118.7,29.6 118.57,29.73 118.29,29.73 118.09,29.53 117.83,29.53 117.69,29.67 117.69,29.82 118.06,30.18 118.06,30.35 117.94,30.47 117.77,30.47 117.35,30.05 117.21,30.05 117.06,30.2 117.06,30.34 117.48,30.76 117.48,30.92 117.36,31.04 117.19,31.04 116.8,30.65 116.63,30.65 116.51,30.77 116.51,30.94 116.93,31.35 116.93,31.48 116.7,31.71 116.57,31.71 116.29,31.43 116.09,31.43 115.98,31.53 115.98,34.05 v1(116.54,34.61) 116.54,35.85 120,39.3 120,42.58 v1(121.22,43.8)
  L4 w0.203: v1(118.5,69.07) 118.5,68.92 120.74,66.68 120.74,57.55 116.62,53.42 116.62,52.38 116.42,52.18 115.68,52.18 115.48,51.98 115.48,51.57 115.68,51.37 116.42,51.37 116.62,51.17 116.62,50.76 116.42,50.56 115.63,50.56 115.42,50.35 115.42,49.95 115.63,49.74 116.42,49.74 116.62,49.54 116.62,48.93 115.76,48.07 115.76,45.53 116.92,44.36 116.92,36.51 116.54,36.13 v1(116.54,34.61)
  BOTTOM w0.102: v1(119.51,26.66) 119.54,26.68 120.12,26.68 120.33,26.48 121.52,26.48 121.95,26.05 DM2.129 ; 120.07,72.58 120.07,73.06 120.3,73.29 120.3,74.31 120.24,74.36 120.24,74.66 120.55,74.96 CPU1.AF40 ; v1(121.22,43.8) 117.05,39.63 DM1.129
  BOTTOM w0.216: v1(118.5,69.07) 118.93,69.07 119.33,69.47 119.33,71.21 v2(119.35,71.23) 119.33,71.25 119.33,71.83 120.07,72.58
M_A_DQ<33>: length 84.4
  L3 w0.102: v1(121.14,42.51) 120.43,41.79 120.43,39.28 117.1,35.95 117.1,33.75 v1(116.54,33.19) 116.54,32.5 116.62,32.42 116.8,32.42 117.05,32.68 117.23,32.68 117.36,32.55 117.36,32.37 117.01,32.03 117.01,31.83 117.15,31.69 117.29,31.69 117.6,32 117.75,32 117.89,31.86 117.89,31.72 117.58,31.4 117.58,31.26 117.72,31.12 117.86,31.12 118.18,31.43 118.32,31.43 118.47,31.29 118.47,31.14 118.15,30.83 118.15,30.68 118.3,30.54 118.44,30.54 118.75,30.85 118.9,30.85 119.04,30.71 119.04,30.57 118.73,30.25 118.73,30.11 119.03,29.8 119.03,27.77 v1(119.51,27.29)
  L4 w0.203: v1(118.65,68.08) 118.65,67.83 120.13,66.35 120.13,57.8 114.8,52.47 114.8,45.33 116.42,43.72 116.42,36.72 115.83,36.14 115.83,33.54 115.68,33.39 115.68,32.76 115.91,32.53 116.04,32.4 116.26,32.4 116.54,32.68 v1(116.54,33.19)
  BOTTOM w0.102: DM2.131 122.55,25.88 121.71,26.72 120.84,26.72 120.71,26.85 120.71,27.77 120.58,27.9 120.33,27.9 120.2,27.77 120.2,27.42 120.07,27.29 v1(119.51,27.29) ; v1(121.14,42.51) 120.83,42.51 117.65,39.32 DM1.131 ; 120.35,72.34 120.55,72.54 CPU1.AF41
  BOTTOM w0.216: v1(118.65,68.08) 118.65,67.61 119.07,67.19 119.64,67.19 119.82,67.37 v2(119.82,69.28) 119.79,69.3 119.79,71.79 120.35,72.34
M_A_DQ<34>: length 80.4
  TOP w0.216: v2(121.72,41.24) v1(121.14,41.24) ; v2(121.14,35.19) v1(120.57,35.19)
  L3 w0.102: v1(123.98,26.98) 123.57,27.39 123.57,29.97 121.75,31.8 121.75,34.01 v1(120.57,35.19) 120.43,35.19 120.02,35.6 120.02,36.08 119.92,36.18 119.02,36.18 118.9,36.3 118.9,36.47 119.02,36.59 119.92,36.59 120.02,36.69 120.02,38.21 121.57,39.76 121.57,40.8 v1(121.14,41.24)
  L4 w0.203: v1(123.02,69.21) 123.63,68.59 123.63,67.84 124.14,67.32 124.14,56.14 121.95,53.94 121.95,53.66 122.16,53.45 122.59,53.45 122.79,53.25 122.79,52.85 122.59,52.64 120.65,52.64 120.38,52.37 120.38,52 120.58,51.8 121.75,51.8 121.95,51.6 121.95,51.19 121.75,50.99 120.28,50.99 120.07,50.79 120.07,50.35 120.28,50.15 120.86,50.15 121.06,49.95 121.06,49.54 120.86,49.34 120.25,49.34 120.05,49.14 120.05,48.73 120.25,48.53 120.86,48.53 121.06,48.32 121.06,47.92 120.86,47.71 120.25,47.71 120.05,47.51 120.05,47.1 120.25,46.9 120.86,46.9 121.06,46.7 121.06,46.29 120.86,46.09 120.25,46.09 120.05,45.88 120.05,45.48 120.25,45.27 120.86,45.27 121.06,45.07 121.06,44.66 120.86,44.46 120.25,44.46 120.05,44.26 120.05,39.49 119.95,39.39 119.95,35.81 v1(120.57,35.19)
  BOTTOM w0.102: 122.77,72.53 122.54,72.76 122.54,74.26 122.44,74.36 122.44,74.69 122.75,74.99 CPU1.AK40 ; v1(121.14,41.24) 120.65,40.75 DM1.141 ; v1(123.98,26.98) 124.84,26.12 125.45,26.12 125.55,26.02 DM2.141
  BOTTOM w0.216: v1(123.02,69.21) 122.55,69.67 122.55,70.94 122.77,71.16 122.77,72.53
M_A_DQ<35>: length 82
  L3 w0.102: v1(124.44,43.67) 122.05,41.29 122.05,39.53 120.56,38.03 v1(120.56,36.61) 121.14,36.61 122.05,35.7 122.05,32.07 124,30.12 v1(124,28.25)
  L4 w0.203: v1(120.56,36.61) 120.45,36.71 120.45,39.18 121.7,40.43 121.7,50.05 123.4,51.75 123.4,54.53 123.85,54.98 124.75,55.88 124.75,67.47 124.04,68.19 124.04,70.7 123.83,70.9 119.9,70.9 119.69,70.7 119.69,69.45 119.9,69.25 120.3,69.25 120.5,69.45 120.5,69.84 120.71,70.04 121.22,70.04 121.42,69.84 121.42,69.45 121.62,69.25 122.03,69.25 122.23,69.45 122.23,69.73 122.44,69.94 123,69.94 v1(123.04,69.89)
  BOTTOM w0.102: 123.09,72.52 123.08,72.52 123.08,72.67 122.75,73.01 CPU1.AK41 ; v1(124.44,43.67) 122.66,41.9 122.66,41.06 121.25,39.64 DM1.143 ; v1(124,28.25) 124.21,28.05 124.22,28.05 124.47,27.79 124.47,26.96 124.99,26.44 125.67,26.44 126.15,25.96 DM2.143
  BOTTOM w0.216: v1(123.04,69.89) 123.09,69.94 v2(123.09,70.51) 123.09,72.52
M_A_DQ<36>: length 80.1
  TOP w0.216: v2(115.22,33.03) v1(115.22,33.62)
  L3 w0.102: v1(115.22,33.62) 115.22,31.1 117.36,28.97 117.36,28.03 117.23,27.9 117.1,27.9 116.97,27.77 116.97,27.4 117.1,27.27 117.71,27.27 v1(117.81,27.16) 117.81,26.86 122.59,22.08 122.59,20.38 v1(122.54,20.33)
  L4 w0.203: v1(117.81,27.16) 117.36,27.62 117.36,29.65 114.23,32.77 114.23,36 115.4,37.17 115.4,43.01 113.59,44.83 113.59,52.98 118.91,58.3 118.91,65.84 117.53,67.22 117.53,69.91 v1(118.24,70.61)
  BOTTOM w0.102: CPU1.AE40 120,74.62 119.69,74.32 119.69,73.58 ; DM1.130 117.35,30.8 115.22,32.93 v1(115.22,33.62) ; DM2.130 122.25,18.98 122.54,19.26 v1(122.54,20.33)
  BOTTOM w0.216: 119.69,73.58 119.18,73.07 119.18,72.88 v2(118.32,72.02) 118.24,71.94 v1(118.24,70.61)
M_A_DQ<37>: length 80.3
  L3 w0.102: v1(115.35,35.22) 115.68,34.89 115.68,31.15 117.86,28.97 v1(117.86,28.56) 117.86,28.51 118.3,28.08 118.3,27.09 123.07,22.32 123.07,19.77 v1(123.4,19.44)
  L4 w0.203: v1(118.26,69.85) 118.02,69.6 118.02,67.6 119.52,66.09 119.52,58.05 114.19,52.73 114.19,45.08 115.91,43.37 115.91,36.93 114.74,35.76 114.74,32.98 117.86,29.86 v1(117.86,28.56)
  BOTTOM w0.102: v1(123.4,19.44) 122.85,18.89 122.85,16.77 DM2.132 ; DM1.132 117.95,31.17 116.11,33.01 116.11,34.45 v1(115.35,35.22)
  BOTTOM w0.14: CPU1.AE41 120,73.34 119.51,72.86
  BOTTOM w0.216: 119.51,72.86 119.51,72.6 118.82,71.91 118.82,70.13 v2(118.83,70.13) 118.55,69.85 v1(118.26,69.85)
M_A_DQ<38>: length 79.3
  L3 w0.102: v1(118.45,33.89) 118.83,33.51 118.83,31.97 120.61,30.2 120.61,27.9 v1(121.36,27.15) 121.36,27.07 125.92,22.52 v1(125.92,20.46)
  L4 w0.203: v1(121.36,27.15) 121.32,27.19 121.32,27.22 120.81,27.73 120.81,30.54 120.54,30.81 119.78,30.81 119.63,30.96 119.63,31.27 120.08,31.72 120.08,32.13 119.85,32.37 119.56,32.37 119.04,31.84 118.75,31.84 118.49,32.1 118.49,32.51 118.93,32.95 118.93,37.58 118.8,37.7 118.8,52.52 122.92,56.64 122.92,67.68 v1(122.84,67.76)
  BOTTOM w0.102: v1(118.45,33.89) 118.96,33.39 118.96,32.7 120.35,31.31 DM1.140 ; DM2.140 125.25,19.92 125.79,20.46 v1(125.92,20.46) ; CPU1.AJ40 122.2,74.61 121.89,74.31 121.89,73.77 122.06,73.6 122.06,72.21
  BOTTOM w0.216: v1(122.84,67.76) 121.9,68.7 121.9,70.21 v2(121.62,70.5) 121.62,71.61 122.06,72.06 122.06,72.21
M_A_DQ<39>: length 83.9
  L3 w0.102: v1(119.97,34.83) 119.64,35.16 119.64,35.65 119.51,35.77 119.13,35.77 119.01,35.65 119.01,34.76 119.11,34.66 119.31,34.66 119.44,34.53 119.44,34.35 119.31,34.22 119.18,34.22 119.06,34.1 119.06,33.94 119.18,33.82 119.54,33.82 119.67,33.69 119.67,33.5 119.57,33.4 119.26,33.4 119.16,33.29 119.16,33.09 119.26,32.99 119.57,32.99 119.67,32.89 119.67,32.68 119.57,32.58 119.26,32.58 119.16,32.48 119.16,32.28 119.26,32.18 119.57,32.18 119.67,32.07 119.67,31.71 121.04,30.34 121.04,28.87 v1(121.32,28.59) 121.32,28.54 121.85,28 121.85,27.01 126.35,22.51 126.35,19.8 126.58,19.57 126.58,18.65 126.36,18.44 125.23,18.44 125.1,18.57 125.1,18.93 125.23,19.06 125.89,19.06 v1(125.92,19.09)
  L4 w0.203: v1(122.97,68.46) 123.1,68.46 123.32,68.24 123.32,67.45 123.53,67.24 123.53,56.39 119.44,52.29 119.44,33.59 121.32,31.71 v1(121.32,28.59)
  BOTTOM w0.102: v1(125.92,19.09) 125.85,19.02 DM2.142 ; DM1.142 120.95,31.54 119.41,33.08 119.41,34.25 119.82,34.66 119.82,34.68 v1(119.97,34.83) ; 122.4,72.54 122.27,72.66 122.27,74.11 CPU1.AJ41
  BOTTOM w0.216: v1(122.97,68.46) 122.23,69.2 122.23,71.44 v2(122.33,71.54) 122.4,71.6 122.4,72.54
M_A_DQ<40>: length 80.3
  TOP w0.216: v2(122.77,35.67) v1(122.77,35.11) ; v2(123.86,42.28) v1(124.47,42.28)
  L3 w0.102: v1(124.47,42.28) 122.77,40.57 v1(122.77,35.11) 122.77,34.96 123.17,34.56 123.17,31.59 125.84,28.93 125.84,27.85 v1(126.81,26.89)
  L4 w0.203: v1(122.77,35.11) 122.77,38.26 124.98,40.47 124.98,49.37 126.19,50.59 126.19,53.37 127.55,54.72 127.55,66.26 128.2,66.91 128.2,68.23 127.08,69.34 127.08,72.25 126.88,72.45 126.47,72.45 126.27,72.25 126.27,70.67 126.07,70.47 125.66,70.47 125.46,70.67 125.46,72.27 125.25,72.48 124.85,72.48 124.65,72.27 124.65,70.02 124.85,69.82 v1(125.28,69.82)
  BOTTOM w0.102: v1(124.47,42.28) 124.36,42.28 122.45,40.37 DM1.147 ; DM2.147 127.35,26.01 127.19,26.17 127.19,26.43 126.81,26.81 v1(126.81,26.89) ; CPU1.AM41 123.85,73.84 124.09,73.6 124.09,72.88
  BOTTOM w0.14: 124.09,71.29 124.09,72.88
  BOTTOM w0.216: 124.09,71.29 125.28,70.1 v1(125.28,69.82)
M_A_DQ<41>: length 83.7
  L3 w0.102: v1(124.44,40.9) 123.83,40.3 123.83,38.55 123.73,38.45 123.22,38.45 123.12,38.34 123.12,38.14 123.22,38.04 123.73,38.04 123.83,37.94 123.83,37.74 123.73,37.63 123.22,37.63 123.12,37.53 123.12,37.33 123.22,37.23 123.73,37.23 123.83,37.13 123.83,36.92 123.73,36.82 123.22,36.82 123.12,36.72 123.12,36.52 123.22,36.41 123.73,36.41 123.83,36.31 v1(123.83,35.82) 123.41,35.4 123.41,34.92 123.58,34.76 123.58,31.76 126.25,29.09 126.25,28.08 126.8,27.52 v1(126.83,27.52)
  L4 w0.203: v1(128.91,64.78) 128.77,64.63 128.77,54.22 127.41,52.87 127.41,50.09 126.19,48.87 126.19,45.02 126.63,44.59 126.63,40.37 123.81,37.55 123.81,35.85 v1(123.83,35.82)
  BOTTOM w0.102: v1(126.83,27.52) 126.88,27.47 126.88,27.42 127.24,27.06 127.24,26.74 127.39,26.59 127.39,26.3 127.95,25.74 DM2.149 ; v1(124.44,40.9) 123.27,40.9 123.05,40.68 DM1.149 ; CPU1.AN40 124.4,74.61 124.09,74.31 124.09,73.9 124.33,73.66 124.33,71.63 124.52,71.44
  BOTTOM w0.216: v1(128.91,64.78) 128.89,64.81 127.31,64.81 127.11,64.6 127.11,63.69 126.91,63.49 126.45,63.49 126.25,63.69 126.25,64.6 126.04,64.81 125.58,64.81 125.38,64.6 125.38,63.76 125.18,63.56 124.72,63.56 124.52,63.76 124.52,64.6 124.31,64.81 123.86,64.81 123.65,64.6 123.65,63.76 123.45,63.56 122.71,63.56 122.51,63.76 122.51,66.84 122.71,67.04 125.2,67.04 125.41,67.24 125.41,67.95 125.78,68.32 125.78,69.39 v2(125.76,69.4) 125.78,69.42 125.78,70.18 124.52,71.44
M_A_DQ<42>: length 80.4
  TOP w0.216: v2(126.68,42.45) v1(126.12,42.45)
  L3 w0.102: v1(126.12,42.45) 126.02,42.45 125.66,42.1 125.66,40.51 125.94,40.23 125.94,34.55 v1(126.4,34.1) 126.4,33.26 126.3,33.16 125.81,33.16 125.69,33.04 125.69,32.87 125.81,32.75 126.3,32.75 126.4,32.65 126.4,32.45 126.3,32.34 125.78,32.34 125.66,32.23 125.66,32.06 125.78,31.94 126.3,31.94 126.4,31.84 126.4,31.35 128.91,28.83 128.91,27.42 129.47,26.86 v1(129.47,26.66)
  L4 w0.203: v1(128.63,70) 128.63,70.03 129.31,70.71 129.31,72.58 129.51,72.78 129.93,72.78 130.13,72.58 130.13,70.34 129.98,70.19 129.98,69.78 130.18,69.58 130.54,69.58 130.74,69.38 130.74,68.95 130.54,68.75 130.26,68.75 130.06,68.55 130.06,68.14 130.26,67.94 130.54,67.94 130.74,67.74 130.74,67.29 130.56,67.11 130.26,67.11 130.06,66.91 130.06,66.5 130.26,66.3 130.56,66.3 130.74,66.12 130.74,53.61 129.24,52.11 129.24,49.33 128.25,48.34 128.25,43.78 129.02,43.01 129.02,40.12 125.99,37.09 125.99,34.5 v1(126.4,34.1)
  BOTTOM w0.102: DM1.157 125.45,41.98 125.93,42.45 v1(126.12,42.45) ; 126.7,72.29 126.29,72.7 126.29,73.59 126.05,73.83 CPU1.AT41 ; v1(129.47,26.66) 129.52,26.66 130.35,25.83 DM2.157
  BOTTOM w0.216: 126.7,72.29 128.32,70.67 128.32,70.31 v1(128.63,70)
M_A_DQ<43>: length 79.6
  TOP w0.216: v2(126.68,41.03) v1(126.1,41.03)
  L3 w0.102: v1(129.34,28.46) 129.34,28.87 127.03,31.18 127.03,35.11 v1(126.55,35.6) 126.78,35.82 126.78,36.25 126.68,36.35 126.35,36.35 126.25,36.45 126.25,36.65 126.35,36.76 126.68,36.76 126.78,36.86 126.78,37.06 126.68,37.16 126.35,37.16 126.25,37.26 126.25,37.47 126.35,37.57 126.68,37.57 126.78,37.67 126.78,37.87 126.68,37.97 126.35,37.97 126.25,38.08 126.25,38.28 126.35,38.38 126.68,38.38 126.78,38.48 126.78,38.69 126.68,38.79 126.35,38.79 126.25,38.89 126.25,39.09 126.35,39.19 126.68,39.19 126.78,39.3 126.78,40.36 v1(126.1,41.03)
  L4 w0.203: v1(126.55,35.6) 126.65,35.7 126.65,37.04 129.53,39.91 129.53,43.54 128.86,44.21 128.86,48.09 129.85,49.08 129.85,51.86 131.35,53.35 131.35,65.01 131.35,69.81 130.8,70.36 130.8,72.79 130.21,73.39 128.76,73.39 128.18,73.98 126.83,73.98 126.63,73.77 126.63,73.26 126.83,73.06 127.67,73.06 127.87,72.86 127.87,71.12 128.07,70.92 v1(128.75,70.92)
  BOTTOM w0.102: v1(129.34,28.46) 129.34,28.23 129.8,27.77 129.8,26.93 130.95,25.79 DM2.159 ; CPU1.AU40 126.6,74.61 126.29,74.31 126.29,74 126.52,73.78 126.52,73.02 126.82,72.72 ; v1(126.1,41.03) 126.1,41.02 126.05,40.96 DM1.159
  BOTTOM w0.216: 126.82,72.72 128.63,70.92 v1(128.75,70.92)
M_A_DQ<44>: length 80.1
  L3 w0.102: v1(120.56,33.16) 120.81,33.41 121.34,33.41 121.44,33.31 121.44,32.62 121.32,32.5 120.45,32.5 120.33,32.37 120.33,32.17 120.45,32.04 121.27,32.04 121.34,31.96 121.34,31.41 122.61,30.14 122.61,29.78 122.54,29.7 121.88,29.7 121.75,29.58 121.75,29.4 121.95,29.2 122.49,29.2 122.61,29.07 v1(122.61,28.26) 123.17,27.7 123.17,27.18 127.64,22.71 v1(127.64,19.21)
  L4 w0.203: v1(122.61,28.26) 122.64,28.28 122.64,31.91 121.56,32.99 121.56,38.81 122.94,40.19 122.94,49.57 124.62,51.25 124.62,54.02 125.97,55.38 125.97,67.63 126.57,68.23 126.57,68.52 126.09,69 125.8,69 125.2,68.4 v1(125.17,68.4)
  BOTTOM w0.102: CPU1.AL40 123.3,74.61 122.99,74.31 122.99,73.1 123.42,72.68 ; v1(120.56,33.16) 122.15,31.56 DM1.146 ; v1(127.64,19.21) 127.05,18.62 DM2.146
  BOTTOM w0.216: v1(125.17,68.4) 124.53,68.4 123.78,69.15 v2(123.78,69.2) 123.67,69.31 123.67,70.58 123.42,70.83 123.42,72.68
M_A_DQ<45>: length 81.3
  L3 w0.102: v1(120.57,34.5) 120.38,34.5 119.97,34.1 119.97,32.07 121.38,30.66 121.38,29.34 122.16,28.56 122.16,27.24 122.49,26.91 v1(122.61,26.91) 127.21,22.31 127.21,22.01 127.11,21.91 126.75,21.91 126.65,21.8 126.65,21.6 126.75,21.5 127.11,21.5 127.21,21.4 127.21,21.19 127.11,21.09 126.75,21.09 126.65,20.99 126.65,20.79 126.75,20.69 127.11,20.69 127.21,20.58 127.21,18.76 v1(127.62,18.35)
  L4 w0.203: v1(125.25,69.13) 125.22,69.13 124.69,68.6 124.69,67.96 125.36,67.29 125.36,55.63 124.01,54.28 124.01,51.5 122.33,49.82 122.33,40.3 121.05,39.02 121.05,32.78 122.05,31.78 122.05,27.37 122.51,26.91 v1(122.61,26.91)
  BOTTOM w0.102: 123.75,72.33 123.75,72.96 123.89,73.1 123.89,73.46 123.6,73.75 123.6,74.35 123.54,74.4 123.54,74.66 123.85,74.96 CPU1.AM40 ; v1(120.57,34.5) 122.75,32.32 DM1.148 ; DM2.148 127.65,18.32 v1(127.62,18.35)
  BOTTOM w0.216: 123.75,72.33 123.75,71.09 124.34,70.5 v2(124.34,70.32) 124.34,69.34 124.54,69.13 v1(125.25,69.13)
M_A_DQ<46>: length 80.7
  L3 w0.102: v1(130.2,19.72) 129.47,19.72 129.27,19.93 129.27,20.23 129.47,20.43 129.88,20.43 130.03,20.58 130.03,20.79 129.88,20.94 128.81,20.94 128.66,21.1 128.66,26.5 v1(128.18,26.99) 127.59,27.57 127.59,29 124.85,31.74 v1(124.85,34.4)
  L4 w0.203: v1(128.57,68.54) 128.81,68.3 128.81,66.66 128.16,66.01 128.16,54.47 126.8,53.12 126.8,50.34 125.58,49.12 125.58,40.19 123.3,37.91 123.3,35.64 123.35,35.59 123.35,33.54 124.31,32.57 124.31,31.3 127.57,28.05 127.57,27.6 v1(128.18,26.99)
  BOTTOM w0.102: 125.35,72.67 125.19,72.83 125.19,74.34 125.5,74.64 CPU1.AR40 ; DM2.158 130.65,19.27 v1(130.2,19.72) ; v1(124.85,34.4) 124.85,32.47 125.75,31.57 DM1.158
  BOTTOM w0.216: 125.35,72.67 126.88,71.14 v2(126.88,70.98) 127.38,70.48 127.38,69.54 128.38,68.54 v1(128.57,68.54)
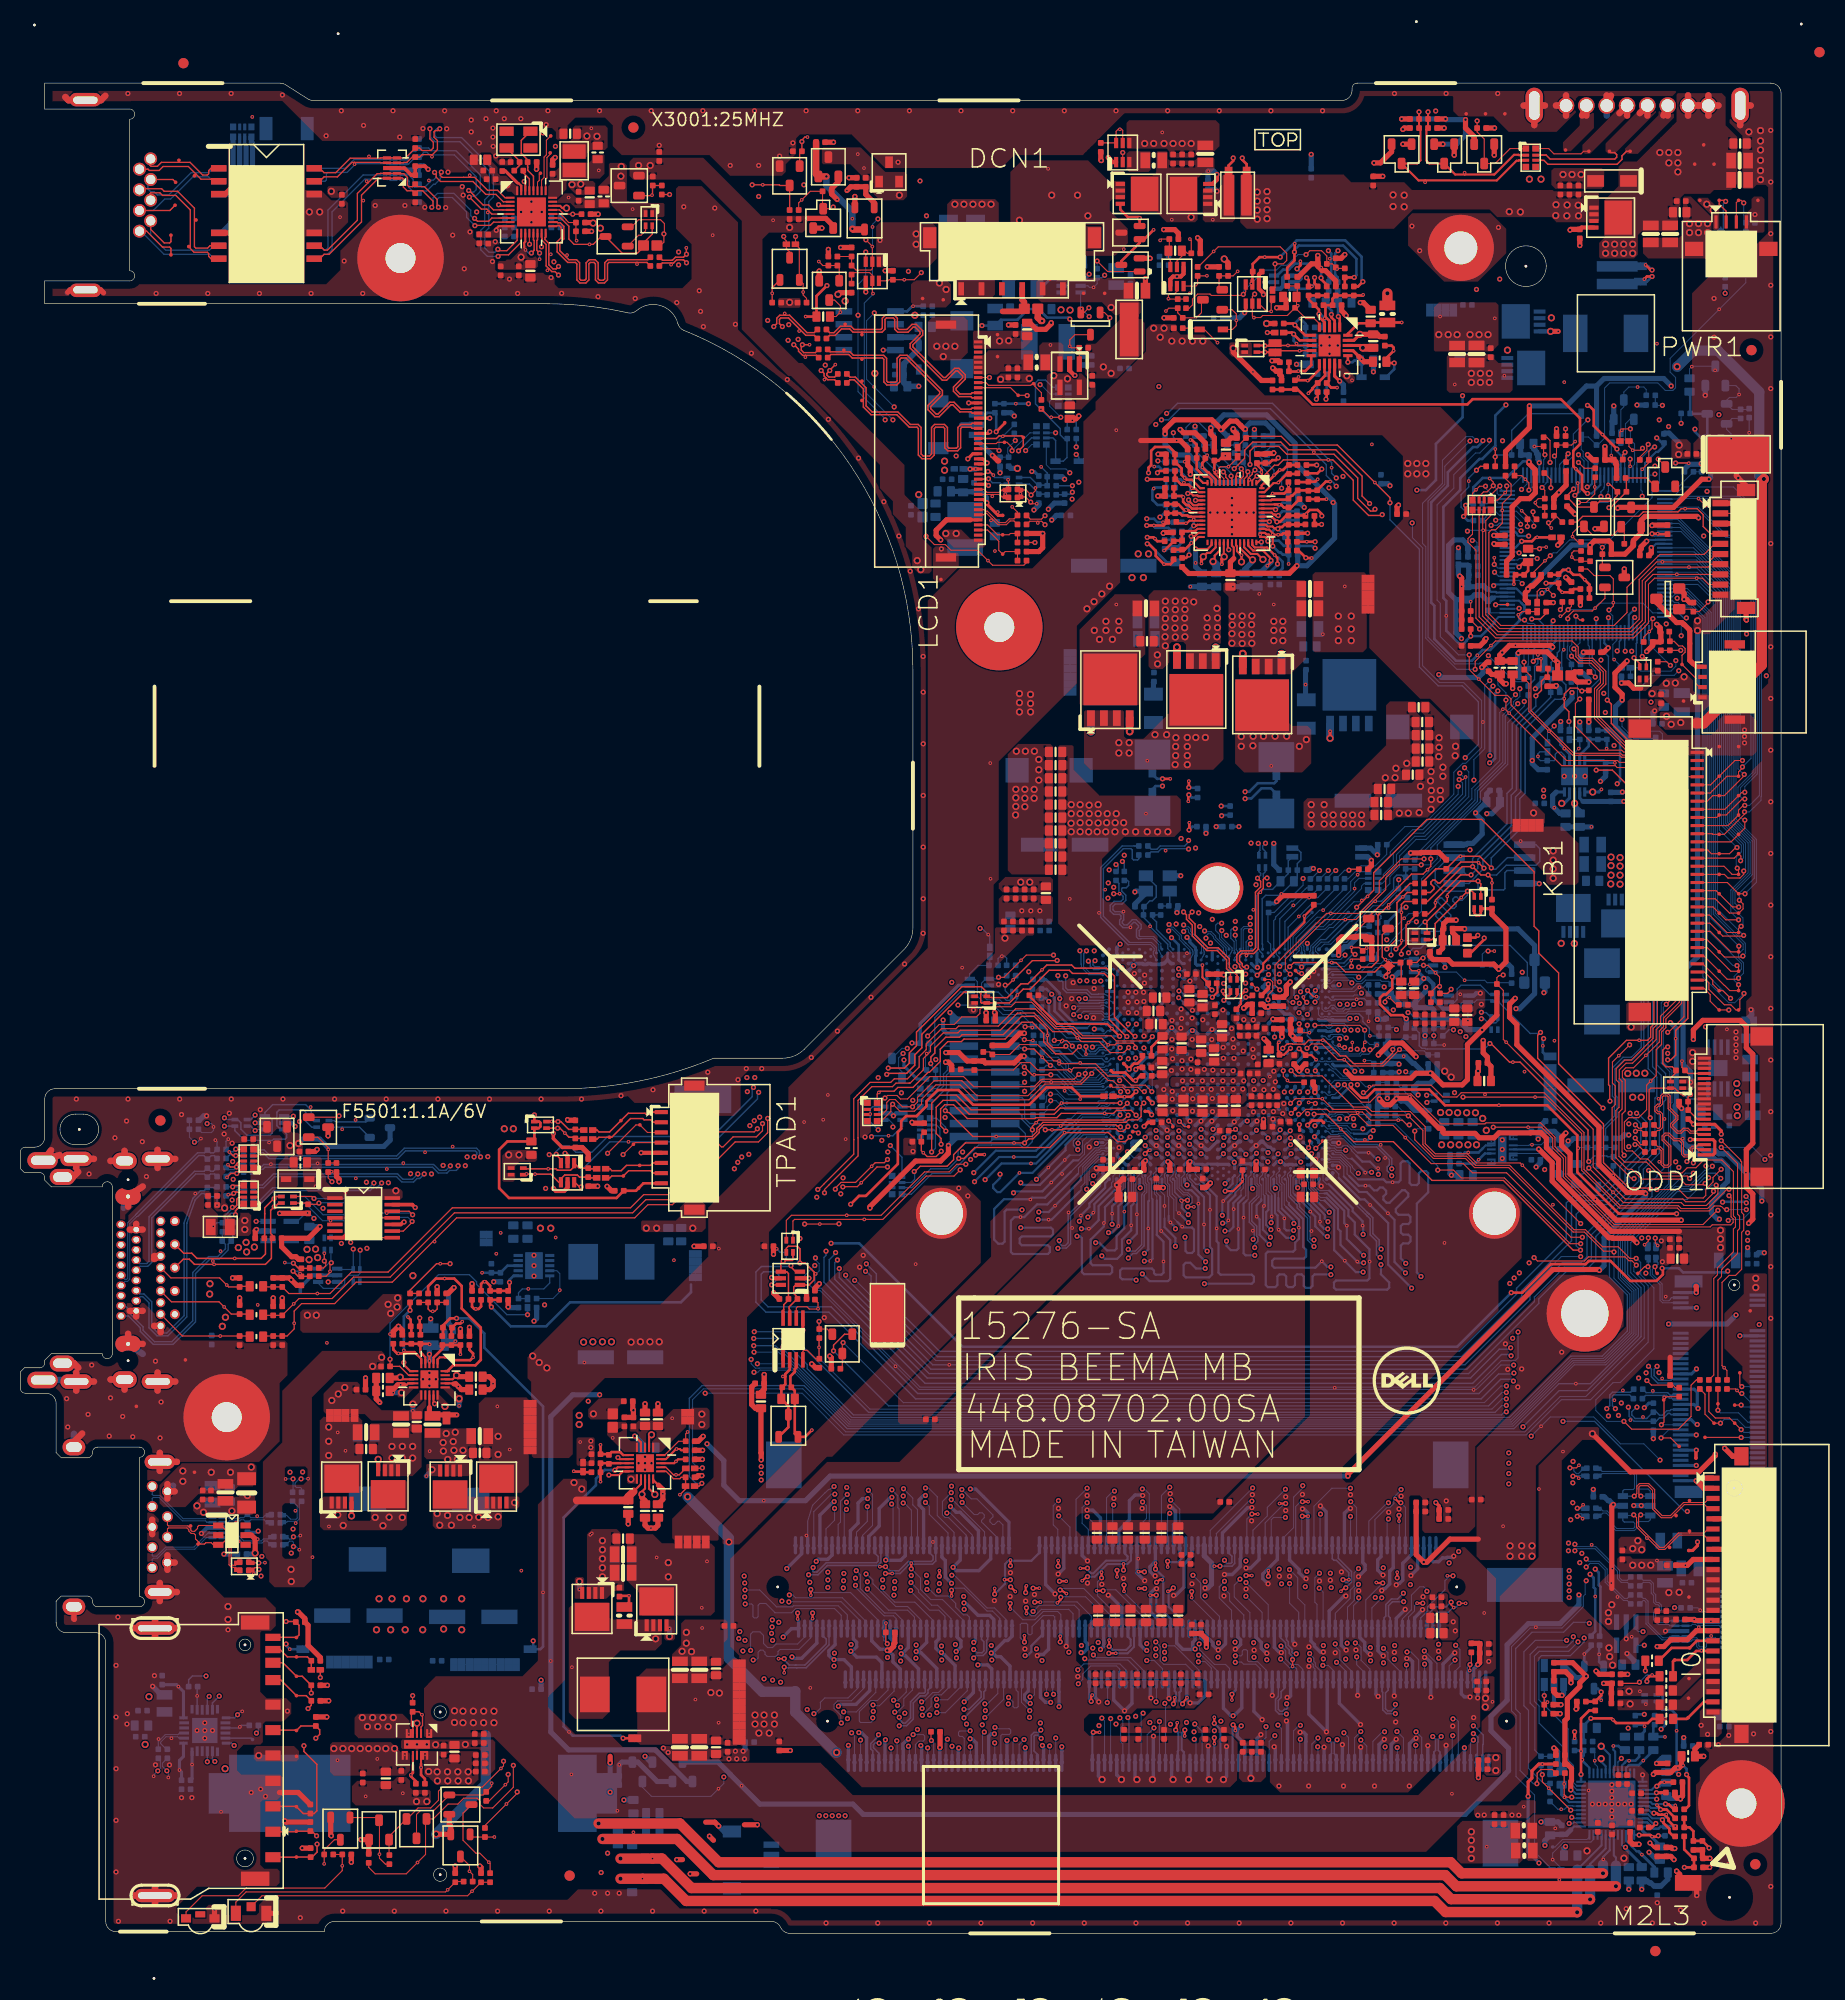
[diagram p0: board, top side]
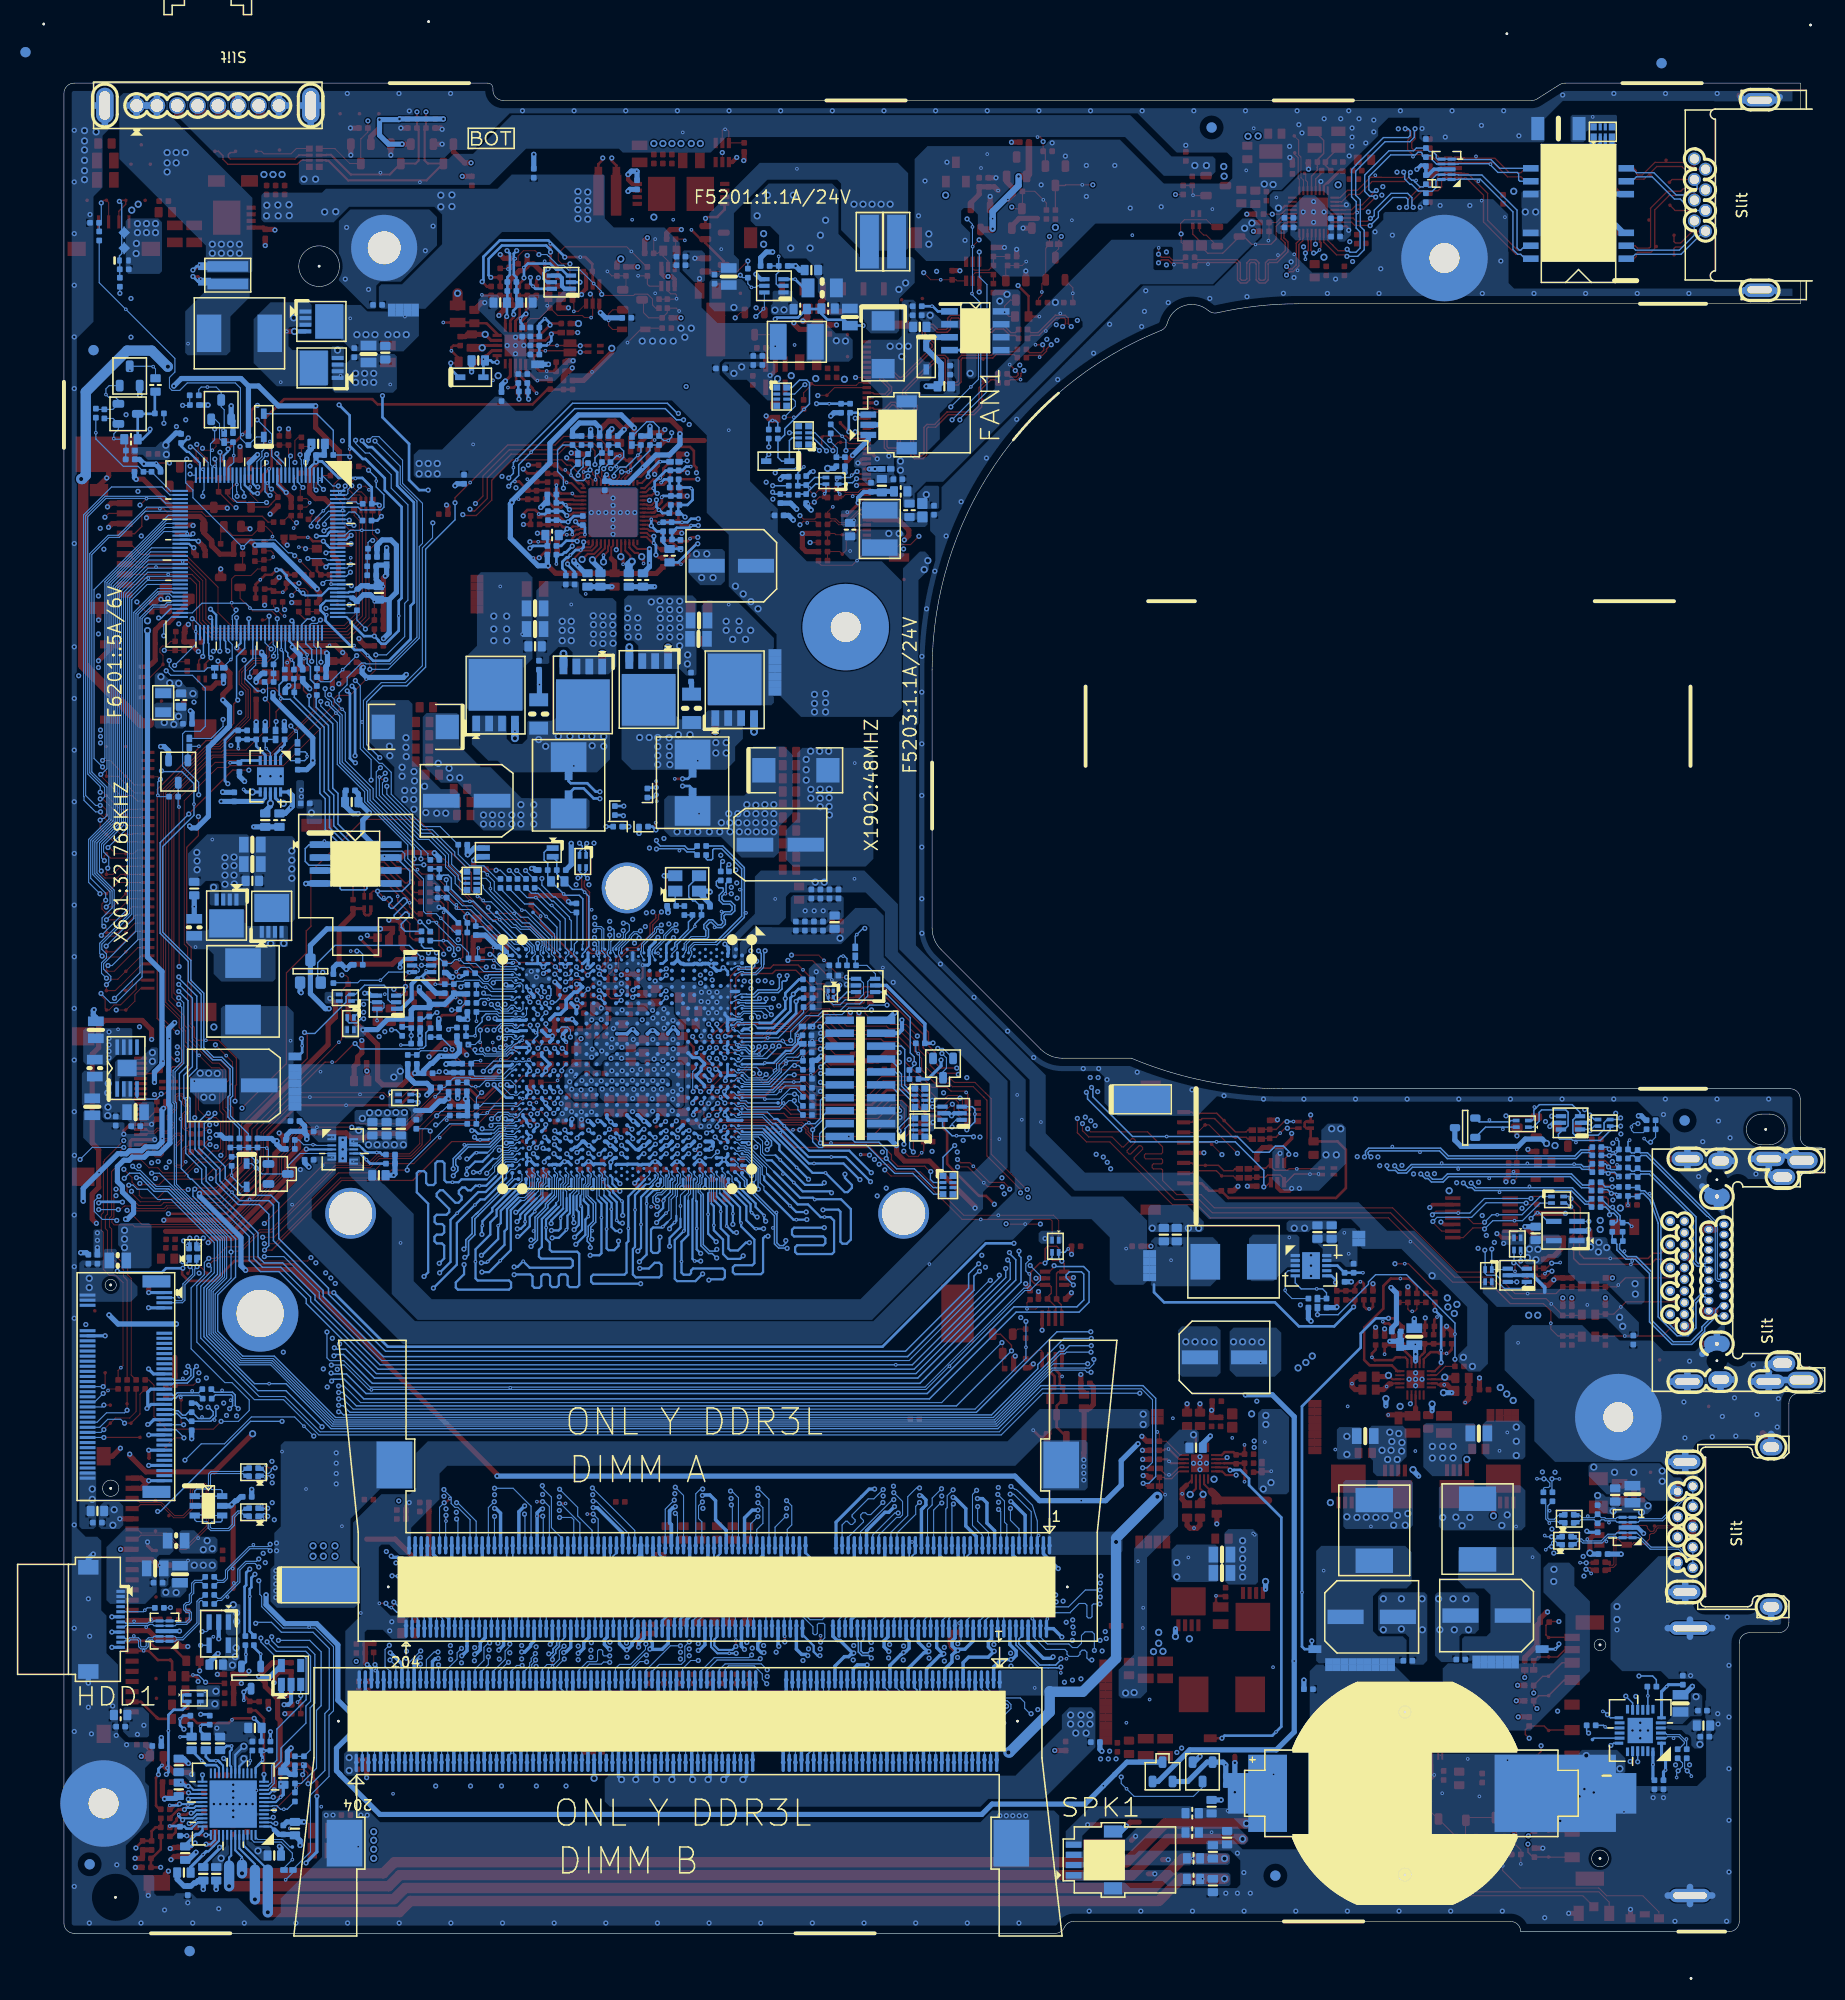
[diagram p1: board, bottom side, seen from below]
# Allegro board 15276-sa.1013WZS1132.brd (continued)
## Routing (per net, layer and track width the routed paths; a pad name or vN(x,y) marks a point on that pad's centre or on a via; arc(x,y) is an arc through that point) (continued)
M_A_DQ<47>: length 82.8
  L3 w0.102: v1(131.86,19.85) 131.17,19.16 130.96,19.16 130.8,19.31 130.8,20.9 129,22.71 129,26.87 128.61,27.26 128.61,27.87 v1(128.18,28.31) 128.12,28.36 128.12,29.04 125.36,31.81 125.36,35.27 v1(124.85,35.77)
  L4 w0.203: v1(128.18,28.31) 125.48,31 125.48,37.45 128.38,40.35 128.38,42.35 127.64,43.09 127.64,48.59 128.63,49.58 128.63,52.36 130.13,53.86 130.13,65.52 129.42,66.23 129.42,68.47 v1(128.6,69.28)
  BOTTOM w0.102: CPU1.AT40 126.05,74.96 125.74,74.66 125.74,74.36 125.8,74.31 125.8,73.79 126.08,73.5 126.08,72.39 ; v1(131.86,19.85) 131.25,19.24 DM2.160 ; v1(124.85,35.77) 125.65,34.97 125.65,33 126.35,32.29 DM1.160
  BOTTOM w0.216: 126.08,72.39 127.84,70.64 v2(127.84,69.99) 127.84,69.71 128.27,69.28 v1(128.6,69.28)
M_A_DQ<48>: length 84.9
  L3 w0.102: v1(130.84,43.78) 129.14,43.78 128.86,43.5 v1(128.86,35.42) 129.7,34.58 129.7,32.88 129.83,32.75 130.77,32.75 130.89,32.63 130.89,32.46 130.77,32.35 129.84,32.35 129.73,32.23 129.73,32.06 129.84,31.94 130.7,31.94 130.82,31.82 130.82,31.65 130.7,31.53 129.82,31.53 129.7,31.41 129.7,31.25 129.82,31.13 130.64,31.13 130.77,31 130.77,30.85 130.64,30.72 130.31,30.72 130.18,30.59 130.18,30.39 130.31,30.26 130.66,30.26 131.81,29.12 131.81,27.54 v1(131.45,27.19)
  L4 w0.203: v1(128.86,35.42) 128.86,36.67 131.96,39.77 131.96,46.54 131.76,46.74 130.92,46.74 130.73,46.93 130.73,47.37 130.92,47.56 131.48,47.56 131.68,47.76 131.68,51.1 133.35,52.76 133.35,65.4 133.09,65.66 133.09,67.93 132.89,68.13 132.37,68.13 132.16,67.93 132.16,66.71 v1(132.14,66.69)
  BOTTOM w0.102: CPU1.AV41 127.15,73.4 127.78,72.77 128.3,72.77 ; DM1.163 127.25,42.01 129.01,43.78 v1(130.84,43.78) ; DM2.163 132.15,25.73 131.45,26.43 v1(131.45,27.19)
  BOTTOM w0.216: v1(132.14,66.69) 132.09,66.69 130.49,68.29 v2(130.49,69.6) 130.23,69.85 130.23,71.07 128.53,72.77 128.3,72.77
M_A_DQ<49>: length 81
  L3 w0.102: v1(127.9,41.24) 128.38,40.75 128.38,34.58 v1(128.95,34.01) 129.29,33.66 129.29,30.69 131.33,28.66 v1(131.33,28.56)
  L4 w0.203: v1(128.95,34.01) 129.47,34.53 129.47,36.56 132.57,39.66 132.57,51.13 133.96,52.51 133.96,65.66 v1(133.84,65.77)
  BOTTOM w0.102: v1(127.9,41.24) 127.85,41.19 DM1.165 ; 128.75,73.05 127.79,73.05 127.39,73.44 127.39,74.34 127.7,74.64 CPU1.AW40 ; DM2.165 132.75,25.99 131.88,26.86 131.88,28.13 131.45,28.56 v1(131.33,28.56)
  BOTTOM w0.216: 128.75,73.05 130.64,71.16 130.64,70.55 131.26,69.93 131.26,68.72 132.71,67.27 132.71,66.08 v2(132.72,66.06) 132.71,66.05 132.71,64.41 132.51,64.21 129.42,64.21 129.22,64.01 129.22,63.51 129.42,63.31 134.45,63.31 134.65,63.51 134.65,64.01 133.84,64.82 v1(133.84,65.77)
M_A_DQ<50>: length 81.9
  L3 w0.102: v1(130.84,41.01) 132.09,39.76 132.09,34.99 133.28,33.79 v1(133.28,33.03) 133.1,32.85 133.1,31.59 133.23,31.47 133.61,31.47 133.74,31.34 133.74,31.19 133.61,31.06 133.17,31.06 133.05,30.94 133.05,30.77 133.17,30.64 134.22,30.64 134.35,30.52 134.35,30.33 134.24,30.22 133.84,30.22 133.74,30.11 133.74,29.86 134.22,29.38 134.22,28.15 v1(134.09,28.03)
  L4 w0.203: v1(133.28,33.03) 133.28,36.56 137.06,40.34 137.06,44.06 136.4,44.72 136.4,50.14 137.62,51.36 137.62,63.74 137.17,64.2 137.17,65.01 v1(136.28,65.9)
  BOTTOM w0.102: CPU1.BA38 129.77,76.13 130.51,75.4 130.51,74.68 130.73,74.46 ; v1(134.09,28.03) 134.53,27.6 134.53,26.96 135.75,25.74 DM2.175 ; v1(130.84,41.01) 130.85,41 DM1.175
  BOTTOM w0.216: 130.73,74.46 131.66,73.53 v2(132.32,73.53) 132.71,73.53 133.16,73.08 133.47,73.08 133.74,73.35 134.03,73.35 134.35,73.03 134.35,72.74 134.08,72.47 134.08,72.16 134.38,71.86 134.69,71.86 135.92,73.08 136.2,73.08 136.53,72.76 136.53,72.47 135.3,71.25 135.3,70.94 135.57,70.67 136.53,70.67 136.74,70.47 136.74,69.96 136.53,69.76 136,69.76 135.8,69.56 135.8,68.93 136.01,68.72 136.53,68.72 136.75,68.5 136.75,68.07 136.53,67.85 136.01,67.85 135.8,67.64 135.8,66.38 v1(136.28,65.9)
M_A_DQ<51>: length 83.3
  L3 w0.102: v1(136.35,26.4) 136.18,26.4 135.92,26.66 135.92,28.59 135.62,28.89 135.62,33.36 134.78,34.2 134.78,35.24 v1(134.07,35.95) 133,37.02 133,41.11 131.66,42.45 v1(130.87,42.45)
  L4 w0.203: v1(137.78,64.6) 137.78,64.5 138.23,64.04 138.23,51.11 137.01,49.88 137.01,44.83 137.57,44.27 137.57,40.13 134.07,36.63 v1(134.07,35.95)
  BOTTOM w0.102: DM2.177 v1(136.35,26.4) ; DM1.177 131.45,41.87 v1(130.87,42.45) ; CPU1.AY37 128.64,76.68 128.99,76.33 129.86,76.33 130.84,75.36 130.84,74.92 131.6,74.16 131.61,74.16
  BOTTOM w0.216: v1(137.78,64.6) 137.37,65.01 137.37,71.77 138.49,72.88 138.49,74.76 138.28,74.97 137.78,74.97 137.57,74.76 137.57,73.8 137.37,73.59 136.86,73.59 136.66,73.8 136.66,75.73 136.46,75.93 135.97,75.93 135.77,75.73 135.77,74.08 135.57,73.87 v2(134.98,73.87) 134.37,73.87 134.09,74.16 131.61,74.16
M_A_DQ<52>: length 84.1
  L3 w0.102: v1(131.86,19.01) 133,19.01 133.13,19.14 133.13,19.44 133,19.57 132.49,19.57 132.37,19.7 132.37,20.05 132.47,20.15 133.14,20.15 133.26,20.27 133.26,20.44 133.14,20.56 132.47,20.56 132.37,20.66 132.37,23.38 130.41,25.33 130.41,26.93 v1(130.37,26.97) 129.9,27.44 129.9,29.14 127.34,31.71 127.34,34.96 v1(127.79,35.42)
  L4 w0.203: v1(132.09,65.03) 132.09,53.23 130.46,51.6 130.46,48.82 129.51,47.87 129.51,44.52 130.04,44 130.04,39.52 127.29,36.77 127.29,31.2 129.83,28.66 129.83,27.49 130.3,27.01 130.33,27.01 v1(130.37,26.97)
  BOTTOM w0.102: CPU1.AU41 126.6,73.99 126.72,73.86 126.72,73.25 127.9,72.07 128.27,72.07 ; v1(131.86,19.01) 132.45,18.42 DM2.164 ; v1(127.79,35.42) 127.34,34.96 127.34,32.57 127.55,32.36 DM1.164
  BOTTOM w0.216: 128.27,72.07 128.29,72.07 129.24,71.12 129.24,67.19 v2(130.28,66.15) 130.28,66.13 131.38,65.03 v1(132.09,65.03)
M_A_DQ<53>: length 81.3
  L3 w0.102: v1(127.77,33.95) 127.77,33.51 127.87,33.41 128.59,33.41 128.71,33.29 128.71,33.12 128.59,33.01 127.87,33.01 127.77,32.9 127.77,32.7 127.87,32.6 128.51,32.6 128.63,32.48 128.63,32.31 128.51,32.19 127.87,32.19 127.77,32.09 127.77,31.79 130.44,29.12 130.44,28.61 v1(130.51,28.54) 130.89,28.15 130.89,26.02 133.13,23.79 133.13,21.58 134.2,20.51 v1(134.2,19.82)
  L4 w0.203: v1(130.51,28.54) 130.51,29.07 128.35,31.23 128.35,36.88 131.35,39.88 131.35,45.4 130.12,46.63 130.12,47.62 131.07,48.57 131.07,51.35 132.74,53.02 132.74,65.15 132.14,65.75 v1(132.14,65.95)
  BOTTOM w0.102: v1(127.77,33.95) 128.15,33.56 DM1.166 ; v1(134.2,19.82) 133.99,19.82 133.05,18.88 DM2.166 ; CPU1.AV40 127.15,74.98 126.84,74.68 126.84,74.4 126.93,74.32 126.93,73.34 127.89,72.37 128.48,72.37
  BOTTOM w0.216: 128.48,72.37 129.62,71.23 129.62,69.3 129.86,69.05 129.86,67.71 v2(131.5,66.08) 131.63,65.95 v1(132.14,65.95)
M_A_DQ<54>: length 82.4
  L3 w0.102: v1(131.63,34.33) 131.63,34.33 132.7,33.26 132.7,30.43 133.64,29.49 133.64,27.06 v1(134.09,26.6) 134.09,25.79 136.02,23.86 136.02,20.73 136.13,20.63 136.56,20.63 136.66,20.52 136.66,20.32 136.56,20.22 136.13,20.22 136.02,20.12 136.02,19.77 136.13,19.67 136.51,19.67 136.63,19.55 136.63,19.38 135.52,18.27 v1(135.44,18.27)
  L4 w0.203: v1(134.09,26.6) 134.58,27.09 134.58,28.24 134.04,28.77 134.04,29.58 132.77,30.85 132.77,36.77 136.41,40.4 136.41,43.83 135.79,44.44 135.79,50.39 136.86,51.46 v1(136.86,63.46)
  BOTTOM w0.102: DM2.174 135.45,18.26 v1(135.44,18.27) ; CPU1.AY39 128.83,75.14 129.23,75.14 129.69,74.68 129.69,74.3 ; DM1.174 130.55,32.08 131.22,32.75 131.22,33.87 131.63,34.28 v1(131.63,34.33)
  BOTTOM w0.216: 129.69,74.3 131.81,72.18 132.23,72.18 v2(132.77,71.64) 134.55,69.86 134.55,65.76 v1(136.86,63.46)
M_A_DQ<55>: length 79.7
  L3 w0.102: v1(135.41,19.85) 135.72,20.15 135.72,23.46 132.82,26.35 v1(132.82,26.81) 133.23,27.21 133.23,29.22 131.66,30.8 131.66,31.81 131.76,31.92 132.29,31.92 132.39,32.02 132.39,32.22 132.29,32.32 131.76,32.32 131.66,32.42 v1(131.66,33.01)
  L4 w0.203: v1(136.25,64.96) 136.25,51.71 134.76,50.22 134.76,43.29 135.08,42.96 135.08,39.8 132.27,36.98 132.27,30.44 133.33,29.37 133.33,27.29 132.85,26.81 v1(132.82,26.81)
  BOTTOM w0.102: v1(135.41,19.85) 136.05,19.21 DM2.176 ; CPU1.AY38 128.32,76.13 128.62,75.83 128.87,75.83 128.93,75.88 129.73,75.88 130.19,75.43 130.19,74.44 ; v1(131.66,33.01) 131.66,32.75 131.15,32.24 DM1.176
  BOTTOM w0.216: 130.19,74.44 131.71,72.91 132.44,72.91 v2(134.53,70.83) 135.17,70.18 135.17,66.03 v1(136.25,64.96)
M_A_DQ<56>: length 89.6
  TOP w0.216: v2(135.44,35.52) v1(135.44,34.96)
  L3 w0.102: v1(136.41,27.67) 136.66,27.93 136.66,29.04 136.56,29.14 136.1,29.14 136,29.25 136,29.45 136.1,29.55 136.56,29.55 136.66,29.65 136.66,29.96 136.56,30.06 136.13,30.06 136.02,30.16 136.02,30.36 136.13,30.47 136.56,30.47 136.66,30.57 136.66,33.74 v1(135.44,34.96) 135.44,35.7 134.14,36.99 134.14,41.92 v1(134.58,42.35)
  L4 w0.203: v1(130.38,77.02) 128.96,77.02 128.76,77.23 128.76,79.18 128.56,79.39 128.15,79.39 127.95,79.18 127.95,75.96 127.21,75.23 127.21,74.94 127.51,74.64 127.8,74.64 128.99,75.83 131.33,75.83 132.09,75.06 132.09,70.85 132.95,69.98 134.04,69.98 139.45,64.57 139.45,50.61 138.22,49.38 138.22,45.05 138.58,44.69 138.58,39.52 135.44,36.38 v1(135.44,34.96)
  BOTTOM w0.102: v1(130.38,77.02) 130.34,76.99 129.5,76.99 129.26,77.23 CPU1.BA36 ; v1(136.41,27.67) 136.79,27.67 137.55,26.91 DM2.181 ; v1(134.58,42.35) 134.47,42.35 132.65,40.54 DM1.181
M_A_DQ<57>: length 92.1
  L3 w0.102: v1(138.13,26.48) 138.67,27.01 138.67,27.93 137.45,29.14 137.45,29.45 137.55,29.55 138.03,29.55 138.13,29.65 138.13,29.86 138.03,29.96 137.55,29.96 137.45,30.06 137.45,30.26 137.55,30.36 138.03,30.36 138.13,30.47 138.13,30.67 138.03,30.77 137.55,30.77 137.45,30.87 137.45,35.32 v1(136.76,36) 136.76,37.91 135.19,39.48 135.19,43.01 v1(135.82,43.65)
  L4 w0.203: v1(133.59,74.65) 133.31,74.37 133.31,71.5 133.61,71.2 134.54,71.2 140.67,65.07 140.67,50.1 139.6,49.03 139.6,47.16 139.8,46.96 141,46.96 141.21,46.76 141.21,46.35 141,46.15 139.68,46.15 139.48,45.94 139.48,45.54 139.68,45.33 141,45.33 141.21,45.13 141.21,44.72 141,44.52 139.8,44.52 139.6,44.32 139.6,43.81 139.81,43.6 140.81,43.6 141.31,43.1 141.31,41.88 140.81,41.37 139.82,41.37 139.6,41.15 139.6,40.68 139.8,40.47 140.8,40.47 141,40.27 141,39.79 140.8,39.58 140.39,39.58 138.67,37.86 138.67,36.31 138.38,36.03 137.85,36.03 137.48,36.39 137.15,36.39 v1(136.76,36)
  BOTTOM w0.102: DM2.183 138.13,24.99 v1(138.13,26.48) ; v1(135.82,43.65) 135.82,43.6 135.11,42.89 135.11,42.28 134.73,41.9 134.45,41.9 133.25,40.7 DM1.183 ; CPU1.AY35 128.66,77.78 128.97,77.48 129.32,77.48 129.5,77.29 129.94,77.29 130.11,77.46 130.55,77.46 130.96,77.05 130.96,76.96 131.43,76.49
  BOTTOM w0.216: 131.43,76.49 132.02,75.9 132.75,75.9 133.35,75.3 133.5,75.3 v2(133.56,75.25) 133.59,75.22 v1(133.59,74.65)
M_A_DQ<58>: length 89.9
  TOP w0.216: v2(135.62,40.55) v1(135.62,41.11)
  L3 w0.102: v1(141.12,26.88) 140.62,27.39 140.62,28.15 139.81,28.96 139.81,35.7 v1(140.55,36.43) 140.29,36.43 139.24,37.48 139.1,37.48 138.8,37.18 138.63,37.18 138.51,37.3 138.51,37.47 138.81,37.77 138.81,37.91 138.67,38.06 138.52,38.06 138.16,37.69 137.99,37.69 137.87,37.81 137.87,37.98 138.24,38.35 138.24,38.49 138.09,38.63 137.95,38.63 137.64,38.32 137.47,38.32 137.35,38.44 137.35,38.61 137.66,38.92 137.66,39.06 v1(135.62,41.11)
  L4 w0.203: v1(132.06,79.13) 132.06,78.38 132.74,77.7 134.3,77.7 137.38,74.62 137.38,72.31 137.82,71.88 138.1,71.88 138.91,72.69 139.19,72.69 139.48,72.4 139.48,72.11 138.68,71.31 138.68,71.02 138.96,70.73 139.25,70.73 139.84,71.32 140.13,71.32 140.41,71.03 140.41,70.75 139.83,70.16 139.83,69.87 143.47,66.23 143.47,50.7 144,50.17 144,35.14 143.25,34.39 142.44,34.39 141.94,34.89 141.94,36.41 141.74,36.61 140.72,36.61 v1(140.55,36.43)
  BOTTOM w0.102: v1(141.12,26.88) 141.12,26.88 140.55,26.3 DM2.191 ; v1(132.06,79.13) 131.95,79.02 130.94,79.02 130.53,79.43 CPU1.BA32 ; v1(135.62,41.11) 135.62,40.94 135.65,40.9 DM1.191
M_A_DQ<59>: length 90.6
  TOP w0.216: v2(135.24,42.76) 135.64,42.35 v1(135.8,42.35)
  L3 w0.102: v1(141.19,28.33) 140.9,28.33 140.16,29.07 140.16,35.32 141.49,36.64 v1(141.49,37.55) 140.6,37.55 137.86,40.29 137.71,40.29 137.36,39.94 137.22,39.94 137.08,40.08 137.08,40.23 137.43,40.58 137.43,40.72 137.28,40.86 137.14,40.86 136.79,40.51 136.64,40.51 136.5,40.66 136.5,40.8 136.85,41.15 136.85,41.3 v1(135.8,42.35)
  L4 w0.203: v1(131.19,79.45) 131.19,79.28 130.99,79.08 129.6,79.08 129.39,78.88 129.39,78.45 129.6,78.24 131.66,78.24 132.88,77.02 134.12,77.02 136.77,74.37 136.77,72.06 142.86,65.98 142.86,50.45 143.39,49.91 143.39,35.34 143.19,35.14 142.78,35.14 142.58,35.34 142.58,37.88 142.37,38.09 141.92,38.09 141.49,37.65 v1(141.49,37.55)
  BOTTOM w0.102: v1(135.8,42.35) 136.25,41.9 DM1.193 ; v1(141.19,28.33) 141.61,27.91 141.61,26.26 141.15,25.8 DM2.193 ; CPU1.AY31 128.53,79.84 128.79,79.84 128.96,79.67 130.97,79.67 v1(131.19,79.45)
M_A_DQ<60>: length 89.6
  TOP w0.216: v2(133.38,34.5) 133.43,34.45 v1(134.02,34.45)
  L3 w0.102: v1(137.27,18.5) 137.73,18.96 137.73,24.24 135.59,26.38 135.59,27.94 135.23,28.31 v1(135.19,28.31) 135.19,31.61 135.07,31.72 134.6,31.72 134.47,31.85 134.47,32.04 134.6,32.17 134.81,32.17 134.93,32.29 134.93,32.47 134.81,32.6 134.49,32.6 134.37,32.72 134.37,32.89 134.49,33.01 134.79,33.01 134.91,33.13 134.91,33.29 134.79,33.41 134.45,33.41 134.35,33.51 134.35,34.12 v1(134.02,34.45)
  L4 w0.203: v1(131.61,74.75) 131.5,74.86 129.06,74.86 128.75,74.55 128.75,74.26 129.01,74 130.49,74 131.43,73.06 131.43,70.65 132.7,69.37 133.78,69.37 138.84,64.31 138.84,50.86 137.62,49.63 137.62,44.94 138.07,44.48 138.07,39.88 134.58,36.38 134.58,33.52 134.55,33.5 134.55,32.35 134.35,32.14 133.64,32.14 133.43,31.94 133.43,31.53 133.64,31.33 134.35,31.33 134.55,31.13 134.55,28.98 135.19,28.35 v1(135.19,28.31)
  BOTTOM w0.102: v1(137.27,18.5) 137.25,18.48 DM2.180 ; v1(134.02,34.45) 132.35,32.79 DM1.180 ; v1(131.61,74.75) 131.04,75.32 131.04,75.44 129.9,76.58 129.19,76.58 CPU1.BA37
M_A_DQ<61>: length 87.6
  L3 w0.102: v1(133.92,33.01) 134.04,32.88 134.04,32.43 133.92,32.3 133.54,32.3 133.41,32.18 133.41,31.92 133.54,31.8 133.92,31.8 134.04,31.67 134.04,31.3 134.65,30.69 134.65,27.46 v1(135.16,26.95) 135.11,26.9 135.11,26.28 137.29,24.1 v1(137.29,19.82)
  L4 w0.203: v1(135.16,26.95) 135.68,26.95 135.92,27.19 135.92,28.33 136.05,28.46 136.51,28.46 136.71,28.66 136.71,29.08 136.51,29.28 135.48,29.28 135.06,29.7 135.06,33.28 136.18,34.4 136.18,36.23 139.09,39.15 139.09,41.63 139.34,41.88 140.6,41.88 140.8,42.09 140.8,42.89 140.6,43.09 139.43,43.09 139.09,43.43 139.09,44.91 138.83,45.16 138.83,49.12 140.06,50.35 140.06,64.82 134.29,70.59 133.21,70.59 132.7,71.1 132.7,74.63 v1(132.92,74.85)
  BOTTOM w0.102: v1(137.29,19.82) 137.85,19.27 DM2.182 ; v1(133.92,33.01) 133.92,32.98 132.95,32.01 DM1.182 ; 130.94,76.19 130.59,76.19 129.99,76.78 129.42,76.78 129.22,76.98 128.97,76.98 128.92,76.93 128.59,76.93 128.28,77.23 CPU1.AY36
  BOTTOM w0.216: v1(132.92,74.85) 132.33,74.85 v2(132.29,74.81) 132.29,74.89 130.99,76.19 130.94,76.19
M_A_DQ<62>: length 88.9
  L3 w0.102: v1(138.36,33.64) 138.77,33.64 139.51,32.9 139.51,30.95 139.41,30.85 138.84,30.85 138.74,30.75 138.74,30.55 138.84,30.44 139.41,30.44 139.51,30.34 v1(139.51,28.43) 140.16,27.77 140.16,22.62 141.41,21.37 141.41,19.95 v1(140.9,19.44)
  L4 w0.203: v1(132.82,78.31) 134.55,78.31 141.03,71.84 141.03,69.53 144.08,66.48 144.08,50.95 144.61,50.42 144.61,34.86 141.73,31.98 139.71,31.98 139.51,31.77 v1(139.51,28.43)
  BOTTOM w0.102: CPU1.BA33 130.42,78.88 131.16,78.14 131.37,78.14 ; DM2.192 140.85,19.39 v1(140.9,19.44) ; DM1.192 135.95,30.92 136.84,31.81 136.84,33.26 137.66,34.09 138.04,34.09 138.36,33.77 v1(138.36,33.64)
  BOTTOM w0.216: 131.37,78.14 131.44,78.07 132.24,78.07 v2(132.27,78.04) 132.55,78.04 v1(132.82,78.31)
M_A_DQ<63>: length 89.1
  TOP w0.216: v2(137.4,32.47) v1(137.95,32.47)
  L3 w0.102: v1(140.93,21.09) 140.22,21.09 139.53,21.78 v1(139.53,27.06) 139.07,27.52 139.07,28.91 138.97,29.01 138.38,29.01 138.26,29.13 138.26,29.3 138.38,29.42 138.97,29.42 139.07,29.52 139.07,29.72 138.97,29.82 138.54,29.82 138.44,29.92 138.44,31.99 v1(137.95,32.47)
  L4 w0.203: v1(139.53,27.06) 140.52,28.05 140.52,28.44 141.79,29.71 141.79,31.18 145.22,34.61 145.22,50.67 144.69,51.21 144.69,66.74 141.64,69.78 141.64,72.09 134.77,78.95 v1(133.08,78.95)
  BOTTOM w0.102: v1(140.93,21.09) 141.2,21.09 141.45,20.84 DM2.194 ; 131.2,78.65 131.15,78.7 130.89,78.7 130.41,79.18 128.93,79.18 128.87,79.13 128.58,79.13 128.27,79.43 CPU1.AY32 ; v1(137.95,32.47) 137.39,32.47 137.14,32.22 137.14,31.71 136.55,31.12 DM1.194
  BOTTOM w0.216: 131.2,78.65 131.2,78.64 132.46,78.64 132.77,78.95 v1(133.08,78.95)
M_A_DQS_DN<0>: length 99.9
  TOP w0.152: v2(74.58,27.01) 75.14,27.01 v1(75.14,27.02)
  L4 w0.127: v1(104.02,77.07) 103.94,77.15 103.61,77.15 101.17,74.71 97.76,74.71 95.27,72.22 95.27,68.29 93.09,66.11 90.39,66.11 70.81,46.54 70.81,37.47 69.62,36.27 69.62,31.98 73.59,28 73.59,27 74.19,26.41 74.74,26.41 75.14,26.81 v1(75.14,27.02) 75.41,26.74 77.16,26.74 83.49,20.41 83.49,19.73 83.78,19.44 84.32,19.44 v1(84.42,19.53)
  BOTTOM w0.14: v1(104.02,77.07) 103.59,77.5 103.59,77.93 104.47,78.8 106.42,78.8 CPU1.A33
  BOTTOM w0.152: DM2.10 83.85,17.95 83.65,18.15 83.65,18.66 84.42,19.43 v1(84.42,19.53) ; v1(75.14,27.02) 75.15,27 75.15,26.88 75.64,26.39 76.26,26.39 77.19,26.39 79.28,28.48 79.28,28.93 78.95,29.26 DM1.10
M_A_DQS_DN<1>: length 88.9
  L4 w0.127: v1(102.19,68.13) 102.51,67.82 102.51,67.19 102.38,67.06 102.38,65.42 90.51,53.54 87.8,53.54 79.53,45.27 79.53,40.7 78.33,39.5 78.33,38.28 77.59,37.55 77.59,36.07 77.68,35.98 77.98,35.98 v1(77.99,35.98) 77.99,35.61 78.46,35.14 78.46,33.73 83.51,28.67 83.51,24.33 85.45,22.38 85.45,21.06 85.65,20.86 86.08,20.86 v1(86.46,21.25)
  BOTTOM w0.127: 103.21,70.8 v2(103.11,70.9)
  BOTTOM w0.14: v1(102.19,68.13) 102.19,67.88 102.44,67.64 102.79,67.64 103.07,67.91 103.07,70.66 106.01,73.6 106.01,74.09 106.5,74.58 CPU1.A40
  BOTTOM w0.152: v1(77.99,35.98) 77.96,35.95 77.96,35.65 78.07,35.53 78.36,35.53 79.27,36.45 84.22,36.45 84.38,36.61 84.38,37.07 84.05,37.4 DM1.27 ; v1(86.46,21.25) 86.46,21.06 86.83,20.68 87.07,20.68 87.57,21.19 87.57,22.78 88.42,23.62 88.9,23.62 89.02,23.74 89.02,24.04 88.95,24.11 DM2.27
M_A_DQS_DN<2>: length 82.9
  TOP w0.152: v2(84.55,36.07) v1(85.11,36.07)
  L4 w0.127: v1(108.98,67.27) 109.34,66.91 109.51,66.91 109.89,66.53 109.89,65.82 109.21,65.15 109.21,63.12 93.18,47.09 90.56,47.09 88.08,44.61 88.08,41.68 84.67,38.26 84.67,36.26 84.86,36.07 v1(85.11,36.07) 85.54,35.63 85.54,33.53 85.38,33.37 85.38,33.16 89.5,29.03 89.5,24.65 92.36,21.8 92.59,21.8 v1(92.82,22.03)
  BOTTOM w0.102: 110.31,72.59 110.31,72.63 110.34,72.67 110.34,72.72 110.61,72.98 110.61,73.57 110.45,73.73 110.45,74.3 110.44,74.31 110.34,74.4 110.34,74.69 110.65,75 CPU1.H40
  BOTTOM w0.14: 110.31,72.59 110.31,67.72 109.68,67.1 109.15,67.1 v1(108.98,67.27)
  BOTTOM w0.152: DM2.45 94.35,23.91 94.52,23.74 94.52,23.23 93.32,22.03 v1(92.82,22.03) ; DM1.45 89.45,37.42 89.78,37.09 89.78,36.74 89.62,36.57 87.34,36.57 86.42,35.66 85.52,35.66 v1(85.11,36.07)
M_A_DQS_DN<3>: length 79.5
  TOP w0.152: v1(114.81,72.1) v2(114.18,72.1)
  L4 w0.127: v1(100.38,19.99) 99.56,19.99 98,21.55 98,23.7 94.56,27.14 94.56,27.44 94.29,27.7 94,27.7 v1(93.78,27.92) 93.56,27.7 93.33,27.7 93.24,27.79 93.24,30.28 92.3,31.22 92.3,34.93 92.43,35.06 92.43,37.21 115.8,60.58 115.8,67.02 116.42,67.63 116.42,70.19 115.28,71.33 115.28,71.64 114.82,72.1 v1(114.81,72.1)
  BOTTOM w0.102: v1(114.81,72.1) 114.99,72.27 114.99,72.42 114.78,72.63 114.38,72.63 113.79,73.23 113.79,74.26 113.64,74.4 113.64,74.66 113.7,74.71 113.7,74.98 CPU1.P40
  BOTTOM w0.152: v1(93.78,27.92) 94.1,27.6 94.6,27.6 94.79,27.79 94.79,28.67 94.55,28.91 DM1.62 ; v1(100.38,19.99) 100.15,19.76 99.72,19.76 99.45,19.49 DM2.62
M_A_DQS_DN<4>: length 69.1
  L4 w0.127: v1(124.54,21.58) 125.28,21.58 125.56,21.85 125.56,23.21 124.52,24.25 124.46,24.31 123.43,24.31 120.29,27.46 120.29,29.4 117.89,31.8 117.89,35.37 118.46,35.94 118.46,36.65 118.45,36.66 v1(118.45,36.69) 118.13,37.01 118.13,52.8 122.25,56.92 122.25,67.42 121.92,67.75 121.74,67.75 121.6,67.89 121.41,67.89 121.27,68.03 v1(121.27,68.25)
  BOTTOM w0.102: 121.38,72.32 121.41,72.32 121.64,72.56 121.64,73.45 121.44,73.65 121.44,74.31 121.34,74.4 121.34,74.69 121.65,74.99 CPU1.AH40 ; 121.38,69.1 v2(121.24,69.1)
  BOTTOM w0.14: v1(121.27,68.25) 121.38,68.36 121.38,69.46 120.89,69.94 120.89,71.83 121.38,72.32
  BOTTOM w0.152: DM2.135 123.75,23.3 123.48,23.02 123.48,21.92 123.82,21.58 v1(124.54,21.58) ; v1(118.45,36.69) 118.45,36.59 118.66,36.38 119.08,36.38 119.18,36.48 119.18,37.09 118.85,37.42 DM1.135
M_A_DQS_DN<5>: length 70.1
  TOP w0.152: v2(125.15,26.25) v1(125.15,26.93)
  L4 w0.127: v1(128.7,19.04) 129.3,19.65 129.3,22.57 126,25.86 126,26.73 125.69,27.05 125.27,27.05 v1(125.15,26.93) 125.15,26.94 124.94,27.14 124.76,27.14 124.48,27.42 124.48,28.4 123.31,29.57 123.31,32.26 122.03,33.55 122.03,38.61 123.62,40.2 123.62,49.29 125.29,50.97 125.29,53.75 126.65,55.1 126.65,66.95 v1(127.25,67.56)
  BOTTOM w0.102: 124.76,72.47 124.74,72.49 124.74,74.26 124.64,74.36 124.64,74.66 124.95,74.96 CPU1.AP40
  BOTTOM w0.14: 124.76,72.47 125.09,72.14 125.6,71.64 125.6,71.36 126.62,70.33 126.62,68.19 127.25,67.56 v1(127.25,67.56)
  BOTTOM w0.152: v1(128.7,19.04) 128.98,18.76 128.98,17.68 128.85,17.55 DM2.152 ; v1(125.15,26.93) 125.15,27.21 125.05,27.3 125.05,27.32 124.82,27.55 124.82,27.86 124.46,28.22 124.46,28.58 123.95,29.09 DM1.152
M_A_DQS_DN<6>: length 71.3
  TOP w0.152: v2(130.69,34.78) v1(130.11,34.78)
  L4 w0.127: v1(133.76,66.48) 133.76,66.74 133.88,66.85 134.09,66.85 134.74,66.21 134.74,52.34 133.24,50.85 133.24,39.67 130.45,36.87 130.45,34.96 130.27,34.78 v1(130.11,34.78) 130.11,34.5 129.7,34.09 129.7,30.85 131.93,28.61 131.93,26.48 134.14,24.27 134.14,21.98 134.52,21.61 v1(135.26,21.61)
  BOTTOM w0.14: CPU1.AY41 128.87,74.18 132.03,71.02 132.34,70.72 132.48,70.57
  BOTTOM w0.152: 132.48,70.57 132.78,70.27 132.78,68.71 133.4,68.09 133.4,66.73 133.65,66.48 v1(133.76,66.48) ; v1(135.26,21.61) 134.39,21.61 134.02,21.98 134.02,23.71 133.95,23.78 DM2.169 ; v1(130.11,34.78) 130.35,34.54 130.55,34.54 130.68,34.66 130.68,35.47 129.46,36.69 129.22,36.69 129.05,36.86 DM1.169
M_A_DQS_DN<7>: length 80.5
  L4 w0.127: v1(138.93,19.36) 139.21,19.63 139.21,23.93 137.4,25.75 137.4,29.51 135.53,31.37 135.53,32.93 v1(136.05,33.45) 136.47,33.03 136.79,33.03 139.64,35.89 139.64,36.81 142.49,39.65 142.49,49.54 141.96,50.07 141.96,64.54 141.96,65.6 135.87,71.69 135.87,73.93 135.43,74.37 135.22,74.57 134.96,74.57 v1(134.9,74.51)
  BOTTOM w0.102: CPU1.BA34 128.78,78.36 129.67,78.36 129.75,78.44 130.19,78.44 130.31,78.31
  BOTTOM w0.14: 134.37,76.39 133.42,77.34 131.28,77.34 130.31,78.31 ; 134.37,76.39 v2(134.25,76.26) ; 134.37,76.39 134.67,76.09 134.67,75.59 134.46,75.38 134.46,75.01 134.6,74.86 134.9,74.56 v1(134.9,74.51)
  BOTTOM w0.152: v1(136.05,33.45) 135.48,32.89 134.87,32.89 134.32,32.34 134.32,31.2 134.15,31.03 DM1.186 ; v1(138.93,19.36) 139.22,19.07 139.22,18 139.05,17.83 DM2.186
M_A_DQS_DP<0>: length 99.7
  TOP w0.152: v2(75.14,25.62) v1(75.14,26.18)
  L4 w0.127: v1(104.05,77.71) 104.03,77.71 103.7,77.38 103.52,77.38 101.08,74.94 97.67,74.94 95.04,72.31 95.04,68.39 92.99,66.34 90.29,66.34 70.58,46.64 70.58,37.56 69.39,36.36 69.39,31.88 73.36,27.91 73.36,26.91 74.09,26.18 v1(75.14,26.18) 75.47,26.52 77.06,26.52 83.26,20.32 83.26,19.64 83.68,19.21 83.96,19.21 v1(84.47,18.7)
  BOTTOM w0.102: CPU1.B33 106.94,78.88 106.63,78.57
  BOTTOM w0.14: v1(104.05,77.71) 104.05,78.04 104.57,78.56 106.62,78.56 106.63,78.57
  BOTTOM w0.152: v1(84.47,18.7) 84.41,18.77 84.13,18.77 83.92,18.55 83.92,18.26 84.45,17.73 DM2.12 ; v1(75.14,26.18) 75.2,26.12 75.53,26.12 77.3,26.12 79.55,28.37 DM1.12
M_A_DQS_DP<1>: length 89.4
  L4 w0.127: v1(102.06,67.37) 102.15,67.28 102.15,65.51 90.41,53.77 87.71,53.77 79.31,45.37 79.31,40.8 78.1,39.59 78.1,38.38 77.36,37.64 77.36,35.44 v1(77.54,35.27) 77.58,35.31 77.96,35.31 78.23,35.04 78.23,33.63 83.28,28.58 83.28,24.23 85.22,22.29 85.22,20.97 85.55,20.64 86.23,20.64 v1(86.46,20.41)
  BOTTOM w0.127: 103.31,69.38 v2(103.46,69.38)
  BOTTOM w0.14: CPU1.B40 107.14,74.88 106.25,73.99 106.25,73.5 103.31,70.56 103.31,67.81 102.89,67.4 102.09,67.4 v1(102.06,67.37)
  BOTTOM w0.152: v1(77.54,35.27) 78.47,35.27 79.38,36.18 84.34,36.18 84.65,36.49 DM1.29 ; v1(86.46,20.41) 86.46,20.42 87.18,20.42 87.84,21.08 87.84,22.67 88.53,23.35 89.01,23.35 89.29,23.63 89.29,23.94 89.55,24.2 DM2.29
M_A_DQS_DP<2>: length 83.3
  TOP w0.152: v2(85.76,35.39) v1(85.1,35.39)
  L4 w0.127: v1(92.82,21.2) 92.45,21.57 92.27,21.57 91.93,21.91 89.28,24.56 89.28,28.94 85.15,33.06 85.15,33.46 85.31,33.63 85.31,35.18 v1(85.1,35.39) 85.1,35.45 84.67,35.88 84.67,35.94 84.44,36.16 84.44,38.36 87.85,41.77 87.85,44.71 90.46,47.32 93.08,47.32 108.99,63.22 108.99,65.24 109.66,65.92 109.66,66.44 109.41,66.69 109.26,66.69 v1(108.99,66.42)
  BOTTOM w0.102: 110.55,72.56 110.55,72.63 110.81,72.9 110.81,73.65 110.65,73.81 110.65,74.52 CPU1.H41
  BOTTOM w0.14: 110.55,72.56 110.55,67.62 109.78,66.86 109.43,66.86 v1(108.99,66.42)
  BOTTOM w0.152: DM1.47 90.05,36.63 89.73,36.31 87.45,36.31 86.53,35.39 v1(85.1,35.39) ; v1(92.82,21.2) 92.86,21.2 94.78,23.12 94.78,23.74 94.95,23.91 DM2.47
M_A_DQS_DP<3>: length 79.8
  TOP w0.152: v2(115.44,71.45) v1(114.83,71.45)
  L4 w0.127: v1(100.42,19.17) 100.42,19.33 100.03,19.71 99.98,19.77 99.46,19.77 99.4,19.83 99.33,19.89 97.77,21.46 97.77,23.6 94.77,26.6 94.7,26.67 94.33,27.04 94.33,27.34 94.2,27.47 93.92,27.47 93.78,27.34 v1(93.78,27.08) 93.4,27.47 93.23,27.47 93.01,27.69 93.01,30.19 92.07,31.13 92.07,35.03 92.2,35.16 92.2,37.3 115.57,60.68 115.57,67.11 116.19,67.73 116.19,70.1 115.12,71.17 v1(114.83,71.45)
  BOTTOM w0.102: CPU1.P41 113.99,74.49 113.99,73.31 114.46,72.84 114.86,72.84 115.26,72.43 115.26,71.88 v1(114.83,71.45)
  BOTTOM w0.152: DM2.64 100.05,17.6 99.72,17.93 99.72,19.38 99.83,19.49 100.1,19.49 v1(100.42,19.17) ; v1(93.78,27.08) 94.03,27.33 94.71,27.33 95.05,27.68 95.05,28.82 95.15,28.92 DM1.64
M_A_DQS_DP<4>: length 70.1
  TOP w0.152: v2(117.45,36.11) v1(118.01,36.11)
  L4 w0.127: v1(121.42,67.45) 121.5,67.52 121.83,67.52 122.02,67.33 122.02,57.01 117.9,52.89 117.9,36.22 v1(118.01,36.11) 118.01,35.81 117.66,35.46 117.66,31.71 120.06,29.31 120.06,27.36 123.34,24.09 124.36,24.09 125.33,23.12 125.33,21.95 125.19,21.8 124.94,21.8 124.73,22.02 124.44,22.02 124.31,22.15 124.31,22.44 124.44,22.57 v1(124.56,22.57)
  BOTTOM w0.102: CPU1.AH41 121.65,73.73 121.85,73.53 121.85,72.44 121.55,72.15
  BOTTOM w0.14: v1(121.42,67.45) 121.42,67.76 121.72,68.07 121.72,68.45 121.62,68.55 121.62,69.56 121.13,70.04 121.13,71.73 121.55,72.15
  BOTTOM w0.152: v1(124.56,22.57) 124.65,22.49 124.65,22.16 124.52,22.03 124.35,22.03 124.16,21.84 123.93,21.84 123.74,22.03 123.74,22.91 124.02,23.19 124.02,23.77 124.35,24.1 DM2.137 ; DM1.137 119.45,36.37 119.19,36.11 v1(118.01,36.11)
M_A_DQS_DP<5>: length 68.9
  L4 w0.127: v1(127.25,68.19) 127.62,68.19 127.82,67.99 127.82,67.32 127.62,67.11 127.13,67.11 126.87,66.85 126.87,55 125.52,53.65 125.52,50.87 123.85,49.2 123.85,40.1 122.26,38.52 122.26,33.64 123.54,32.35 123.54,29.66 124.71,28.5 124.71,27.52 124.85,27.37 125.39,27.37 v1(125.51,27.49) 125.57,27.49 126.06,27 126.23,26.83 126.23,25.96 129.09,23.1 129.53,22.66 v1(129.53,19.04)
  BOTTOM w0.102: 124.96,72.63 124.95,72.65 124.95,74.26 CPU1.AP41 ; 126.86,69.07 v2(127.01,69.07)
  BOTTOM w0.14: 124.96,72.63 124.96,72.61 125.84,71.74 125.84,71.46 126.86,70.43 126.86,68.29 126.96,68.19 127.25,68.19 v1(127.25,68.19)
  BOTTOM w0.152: DM2.154 129.45,17.48 129.25,17.68 129.25,18.76 v1(129.53,19.04) ; DM1.154 124.55,28.87 124.73,28.69 124.73,28.33 125.09,27.97 125.09,27.66 125.2,27.54 125.46,27.54 v1(125.51,27.49)
M_A_DQS_DP<6>: length 71
  TOP w0.152: v2(129.9,33.64) 130.25,33.99 v1(130.38,33.99)
  L4 w0.127: v1(135.26,22.52) 135.26,22.24 134.86,21.84 134.61,21.84 134.37,22.08 134.37,24.37 132.16,26.58 132.16,28.71 129.93,30.94 129.93,34 130.04,34.11 130.26,34.11 v1(130.38,33.99) 130.55,34.16 130.55,34.74 130.68,34.87 130.68,36.78 133.47,39.57 133.47,50.75 134.96,52.24 134.96,66.3 134.19,67.08 134.07,67.08 v1(133.86,67.3)
  BOTTOM w0.14: CPU1.BA40 129.1,74.3 132.2,71.19 132.52,70.88 132.58,70.82 132.59,70.82 132.63,70.77 132.66,70.77 132.67,70.76
  BOTTOM w0.152: DM2.171 134.55,23.91 134.28,23.65 134.28,22.09 134.5,21.88 134.88,21.88 135.26,22.26 v1(135.26,22.52) ; DM1.171 129.65,36.87 130.94,35.58 130.94,34.55 v1(130.38,33.99) ; v1(133.86,67.3) 133.67,67.49 133.67,68.2 133.05,68.82 133.05,70.38 132.67,70.76
M_A_DQS_DP<7>: length 79.7
  L4 w0.127: v1(134.91,75.19) 134.93,75.19 136.1,74.02 136.1,71.78 142.18,65.7 142.18,64.45 142.18,50.17 142.72,49.64 142.72,39.56 139.87,36.71 139.87,35.79 136.88,32.8 136.26,32.8 v1(136.08,32.62) 135.92,32.62 135.76,32.46 135.76,31.47 137.62,29.6 137.62,25.84 139.44,24.03 139.44,19.68 v1(139.77,19.36)
  BOTTOM w0.102: CPU1.AY33 128.62,78.88 128.94,78.57 129.59,78.57 129.66,78.64 130.33,78.64 130.42,78.55
  BOTTOM w0.14: 133.68,77.42 134.91,76.19 v1(134.91,75.19) ; 133.68,77.42 133.52,77.59 131.38,77.59 130.42,78.55 ; 133.68,77.42 v2(133.81,77.56)
  BOTTOM w0.152: DM2.188 139.65,17.83 139.48,18 139.48,19.07 v1(139.77,19.36) ; v1(136.08,32.62) 134.98,32.62 134.58,32.23 134.58,31.2 134.75,31.03 DM1.188
M_A_EVENT#: length 93.4
  TOP w0.114: v1(119.54,79.08) 119.4,78.94 R504.2 ; v2(140.37,35.16) v1(140.93,35.16)
  L3 w0.102: v1(119.54,79.08) 119.91,79.45 123.2,79.45 123.72,79.97 129.3,79.97 130.25,79.02 131.37,79.02 131.62,79.27 131.62,79.3 131.88,79.56 133.08,79.56 142.58,70.07 142.58,36.82 v1(140.93,35.16)
  L4 w0.102: v1(142.93,19.01) 142.93,19.03 142.12,19.85 142.12,22.95 138.62,26.45 138.62,32.85 v1(140.93,35.16)
  BOTTOM w0.114: DM2.198 142.65,18.73 v1(142.93,19.01) ; v1(140.93,35.16) 140.9,35.19 140.65,35.19 140.13,34.67 140.13,33.8 138.44,32.12 138.44,31.72 137.75,31.02 DM1.198 ; CPU1.AE34 119.94,78.68 v1(119.54,79.08)
M_A_RAS#: length 90.1
  TOP w0.216: v2(108.57,33.64) v1(108.57,34.25)
  L3 w0.102: v1(122.73,76.79) 123.3,76.22 123.3,74.9
  L3 w0.127: 123.91,72.93 123.91,74.29 123.3,74.9
  L3 w0.203: v1(112.55,26.99) 112.73,27.16 112.75,27.16 113.04,27.45 113.04,28.73 109.05,32.72 109.05,38.05 112.05,41.05 112.05,44.26 112.65,44.87 113.24,44.87 125.71,57.34 125.71,68.27 125.76,68.31 125.76,71.08 123.91,72.93
  L4 w0.102: v1(108.57,34.25) 108.57,33.44 112.12,29.88 112.12,27.42 v1(112.55,26.99) 112.58,26.99 116.52,23.05 116.52,19.92 116.39,19.8 116.09,19.8 115.96,19.92 115.96,20.15 v1(115.53,20.58)
  BOTTOM w0.102: DM2.110 116.25,19.86 v1(115.53,20.58) ; DM1.110 111.35,30.76 108.57,33.54 v1(108.57,34.25)
  BOTTOM w0.216: CPU1.AJ37 122.4,77.08 122.7,76.79 v1(122.73,76.79)
M_A_WE#: length 92
  TOP w0.216: v2(110.01,33.92) v1(110.6,33.92)
  L3 w0.102: v1(123.85,78.24) 124.31,77.77 124.31,77.31 124.57,77.05 124.57,76.5 124.87,76.2 124.87,75.06 125.78,74.15 126.09,74.15
  L3 w0.203: 126.09,74.15 128.09,72.16 128.09,68.34 128.68,67.74 128.68,66.48 128.23,66.03 128.23,64.25 128.96,63.51 128.96,55.61 128.42,55.07 126.32,55.07 115.63,44.38 115.63,41.67 111.08,37.12 111.08,34.22 110.78,33.92 v1(110.6,33.92)
  L4 w0.102: v1(113.06,43.88) 112.61,43.42 112.61,39.91 111.8,39.11 111.8,37.39 110.14,35.72 110.14,34.38 v1(110.6,33.92) 110.95,33.56 110.95,32.17 114.36,28.76 114.36,26.05 114.49,25.92 114.71,25.92 114.84,26.05 114.84,27.09 114.97,27.21 115.2,27.21 115.32,27.09 115.32,25.89 115.45,25.77 115.98,25.77 116.11,25.89 116.11,26.58 115.98,26.71 v1(115.88,26.71)
  BOTTOM w0.102: DM1.113 112.25,43.07 113.06,43.88 v1(113.06,43.88) ; v1(115.88,26.71) 115.91,26.73 116.53,26.73 117.15,26.12 DM2.113
  BOTTOM w0.216: v1(123.85,78.24) 123.8,78.24 123.44,77.88 CPU1.AL35
M_ANALOGIN: length 1.7
  TOP w0.102: v1(114.02,79.85) 114.53,79.34 TP418.1
  BOTTOM w0.102: v1(114.02,79.85) 114.12,79.85 CPU1.R32
M_ANALOGOUT: length 1.4
  TOP w0.102: v1(112.96,79.9) 113.36,79.5 TP420.1
  BOTTOM w0.102: CPU1.N32 112.97,79.9 v1(112.96,79.9)
M_B_DIM0_CKE0: length 75.2
  TOP w0.216: v2(105.44,23.43) 105.34,23.33 v1(105.34,22.82)
  L3 w0.102: 108.41,75.18 110.65,77.42 v1(110.65,77.48)
  L3 w0.203: v1(105.34,22.82) 105.16,23 105.16,25.89 104.66,26.4 103.33,26.4 103.26,26.33 99.1,26.33 97.75,27.68 97.75,28.9 94.83,31.82 94.83,32.94 93.83,33.93 93.83,41.34 94.47,41.98 94.47,58.39 98.66,62.58 100.83,62.58 104.78,66.54 104.78,68.71 105.45,69.37 105.45,70.15 106.46,71.16 106.46,74.31 107.25,75.09 108.33,75.09 108.41,75.18
  BOTTOM w0.216: DM2.73 105.15,23.01 v1(105.34,22.82) ; v1(110.65,77.48) 111.05,77.08 CPU1.J37
M_B_DIM0_CKE1: length 79.6
  TOP w0.216: v2(106.15,19.77) v1(105.54,19.77)
  L3 w0.102: v1(110.65,78.29) 110.12,77.76 110.12,77.17 108.53,75.59 108.15,75.59 108.14,75.58
  L3 w0.203: 108.14,75.58 107.07,75.58 106.05,74.56 106.05,72.6 103.46,70.01 103.46,65.93 100.62,63.09 98.45,63.09 93.96,58.61 93.96,42.19 93.33,41.55 93.33,33.72 94.32,32.73 94.32,31.75 97.34,28.73 97.34,27.51 99.04,25.82 103,25.82 103.54,25.28 103.54,23.6 105.54,21.59 v1(105.54,19.77)
  BOTTOM w0.216: DM2.74 105.45,19.68 v1(105.54,19.77) ; v1(110.65,78.29) 111.04,78.68 CPU1.J34
M_B_DIM0_CLK_DDR0: length 74.5
  TOP w0.203: v1(113.43,22.57) 113.49,22.69 v2(113.55,23.18)
  L3 w0.178: v1(113.43,22.57) 113.7,22.84 113.7,23.46 113.52,23.63 111.03,23.63 110.65,24.01 110.65,24.78 111.03,25.16 112.3,25.16 112.5,25.36 112.5,25.84 112.3,26.05 109.84,26.05 109.49,26.39 109.49,29.51 105.52,33.49 105.52,38.62 108.15,41.25 108.15,44.94 116.73,53.53 116.73,54.94 122.02,60.23 122.02,71.02 119.9,73.14 119.9,76.21 v1(119.46,76.64)
  BOTTOM w0.203: v1(113.43,22.57) 113.68,22.83 113.68,23.7 113.55,23.83 DM2.101 ; v1(119.46,76.64) 119.83,76.28 CPU1.AE38
M_B_DIM0_CLK_DDR1: length 75
  TOP w0.203: v1(113.65,20) 113.7,20.18 v2(113.8,20.71)
  L3 w0.102: 117.63,74.1 117.63,74.13 117.69,74.18 117.69,77.04 117.93,77.29 118.13,77.29 v1(118.35,77.51)
  L3 w0.178: v1(113.65,20) 113.85,20.2 113.85,20.59 112.91,21.52 111.74,21.52 108.71,24.56 108.71,29.16 103.92,33.95 103.92,34.93 103.39,35.46 103.39,37.55 103.94,38.11 103.94,39.27 105.54,40.87 105.54,45.72 106.97,47.14 106.97,50.29 119.18,62.51 119.18,70.9 117.63,72.45 117.63,72.7 117.63,74.1
  BOTTOM w0.203: DM2.102 113.85,17.91 113.91,17.97 113.91,19.74 v1(113.65,20) ; CPU1.AA37 117.92,77.08 v1(118.35,77.51)
M_B_DIM0_CLK_DDR#0: length 74.7
  TOP w0.203: v2(114.76,23.18) 114.38,22.69 v1(114.32,22.57)
  L3 w0.178: v1(120.56,76.62) 120.2,76.26 120.2,73.26 122.32,71.14 122.32,60.1 117.04,54.82 117.04,53.4 108.45,44.82 108.45,41.12 105.82,38.49 105.82,33.62 109.8,29.64 109.8,26.52 109.96,26.35 112.43,26.35 112.81,25.97 112.81,25.23 112.43,24.85 111.16,24.85 110.95,24.65 110.95,24.14 111.16,23.94 113.65,23.94 114,23.58 114,22.89 v1(114.32,22.57)
  BOTTOM w0.203: v1(120.56,76.62) 120.55,76.62 120.09,77.08 CPU1.AE37 ; v1(114.32,22.57) 114.02,22.88 114.02,23.7 114.15,23.83 DM2.103
M_B_DIM0_CLK_DDR#1: length 74.9
  TOP w0.203: v1(114.55,20) 114.54,19.99 v2(114.54,19.42)
  L3 w0.102: v1(118.35,76.68) 118.35,76.87 118.13,77.08 118.02,77.08 117.89,76.96 117.89,74.28 117.94,74.23 117.94,74.1
  L3 w0.178: 117.94,74.1 117.94,72.58 119.49,71.03 119.49,62.38 107.27,50.16 107.27,47.02 105.85,45.59 105.85,40.75 104.25,39.15 104.25,37.98 103.69,37.43 103.69,35.59 104.22,35.05 104.22,34.07 109.01,29.28 109.01,24.69 111.87,21.83 113.04,21.83 114.15,20.72 114.15,20.4 v1(114.55,20)
  BOTTOM w0.203: DM2.104 114.45,17.82 114.24,18.04 114.24,19.69 v1(114.55,20) ; CPU1.AA38 117.95,76.28 v1(118.35,76.68)
M_B_DIM0_CS#0: length 72.8
  TOP w0.216: v1(117.45,19.24) 117.45,18.66 v2(117.46,18.65)
  L3 w0.102: 124.26,73.29 124.26,74.32 123.53,75.05 123.53,76.47 v1(123.73,76.67)
  L3 w0.203: v1(117.45,19.24) 117.27,19.42 117.23,19.42 116.94,19.71 116.94,22.29 113.55,25.68 113.55,29.22 109.56,33.21 109.56,37.84 112.55,40.84 112.55,44.05 112.86,44.36 113.45,44.36 126.22,57.13 126.22,71.33 124.26,73.29
  BOTTOM w0.216: v1(123.73,76.67) 123.34,76.28 CPU1.AL38 ; DM2.114 v1(117.45,19.24)
M_B_DIM0_CS#1: length 77
  TOP w0.216: v2(119.18,22.95) v1(119.18,23.51)
  L3 w0.102: v1(124.96,78.22) 125.3,77.88 128.84,77.88
  L3 w0.203: v1(119.18,23.51) 118.37,23.51 115.07,26.81 115.07,29.85 114.31,30.61 114.31,35.18 119.11,39.98 119.11,42.83 121.44,45.16 126.13,45.16 133.26,52.28 133.26,73.65 132.42,74.48 132.42,75.68 131.55,76.54 130.18,76.54 128.84,77.88
  BOTTOM w0.216: v1(124.96,78.22) 124.73,78.22 CPU1.AN35 ; v1(119.18,23.51) 119.18,23.55 119.55,23.92 DM2.121
M_B_DIM0_ODT0: length 78.1
  TOP w0.216: v2(117.45,21.25) v1(117.45,20.65)
  L3 w0.102: 128.21,75.13 128.05,75.3 127.34,75.3 125.06,77.57 v1(124.95,77.57)
  L3 w0.203: 128.21,75.13 131.1,72.25 131.1,52.28 125.5,46.68 120.81,46.68 117.66,43.54 117.66,40.69 112.73,35.77 112.73,34.78 112.25,34.29 112.25,31.23 114.05,29.43 114.05,25.89 117.45,22.5 v1(117.45,20.65)
  BOTTOM w0.216: v1(124.95,77.57) 124.95,77.56 124.47,77.08 CPU1.AN37 ; v1(117.45,20.65) 118.05,20.05 DM2.116
M_B_DIM0_ODT1: length 78
  TOP w0.216: v1(119.3,20.51) 119.51,20.29 v2(119.51,19.95)
  L3 w0.102: v1(126.07,77.21) 126.07,76.85 127.24,75.68 128.5,75.68 128.68,75.5
  L3 w0.203: v1(119.3,20.51) 119.3,20.71 118.82,21.2 118.82,21.85 114.56,26.1 114.56,29.64 112.76,31.44 112.76,34.08 113.24,34.57 113.24,35.56 118.17,40.48 118.17,43.33 121.02,46.18 125.71,46.18 131.6,52.07 131.6,72.58 128.68,75.5
  BOTTOM w0.216: v1(126.07,77.21) 125.93,77.08 CPU1.AR37 ; v1(119.3,20.51) 119.3,20.5 119.25,20.45 DM2.120
M_ZVDDIO: length 5.2
  TOP w0.203: v1(118.52,72.99) 119.3,72.99 120.22,73.91 v2(120.22,74.17) R503.2
  BOTTOM w0.203: CPU1.AD41 119.25,74.33 119.25,73.73 v1(118.52,72.99)
MCT:
  vias: v2(22.82,178.65)
MCT0: length 6.6
  TOP w0.508: v1(20.81,171.71) 20.15,171.05 XF3102.3
  BOTTOM w0.508: RN3101.4 20.93,171.83 v1(20.81,171.71)
MCT1: length 11.6
  TOP w0.508: XF3102.4 v1(20.84,167.24)
  BOTTOM w0.508: v1(20.84,167.24) 20.84,167.41 22.84,169.42 22.84,176.04 22.73,176.16 RN3101.1
MCT2: length 7.5
  BOTTOM w0.305: 21.57,175.78 21.58,175.78 RN3101.3
  BOTTOM w0.508: XF3101.4 21.17,171.05 21.57,171.46 21.57,175.78
MCT3: length 10.8
  BOTTOM w0.305: 22.21,175.78 22.21,175.9 22.08,176.03 RN3101.2
  BOTTOM w0.508: 22.21,175.78 22.21,169.68 19.77,167.24 XF3101.3
MDO0+: length 13.3
  TOP w0.127: RJ45.1 12.42,167.41 13.99,165.85 14.69,165.85 14.82,165.72 AFTP3107.1
  BOTTOM w0.127: RJ45.1 11.85,167.41 14.13,165.14 18.63,165.14 19.06,164.7 XF3101.1
MDO0-: length 13
  TOP w0.127: AFTP3102.1 14.82,166.38 14.69,166.25 14.16,166.25 12.82,167.59 RJ45.2
  BOTTOM w0.127: RJ45.2 12.82,167.02 14.3,165.54 18.6,165.54 19.03,165.97 XF3101.2
MDO1+: length 13.1
  TOP w0.127: AFTP3101.1 14.71,169.45 RJ45.3
  BOTTOM w0.127: RJ45.3 13.08,169.45 14.21,170.57 14.78,170.57 16.97,172.76 18.52,172.76 18.96,172.32 XF3101.5
MDO1-: length 11.9
  TOP w0.127: AFTP3106.1 15,172.49 RJ45.6
  BOTTOM w0.127: XF3101.6 18.96,173.59 18.52,173.16 16.8,173.16 14.61,170.98 13.47,170.98 13.16,171.29 12.83,171.29 12.55,171.56 12.55,172.23 RJ45.6
MDO2+: length 12.7
  TOP w0.127: RJ45.4 12.71,170.57 12.71,171.05 12.83,171.18 13.73,171.18 13.99,170.93 15.3,170.93 16.72,169.51 16.72,165.9 ; AFTP3103.1 16.72,165.9 ; 16.72,165.9 16.72,165.7 17.09,165.34 18.4,165.34 18.52,165.21 18.52,164.93 18.75,164.7 XF3102.6
MDO2-: length 12.7
  TOP w0.127: XF3102.5 18.65,165.97 18.42,165.75 17.25,165.75 17.13,165.87 17.13,168.51 ; 17.13,168.51 17.13,169.67 15.47,171.33 14.16,171.33 13.9,171.59 11.83,171.59 RJ45.5 ; 17.13,168.51 AFTP3104.1
MDO3+: length 8.8
  TOP w0.127: 17.28,173.02 AFTP3105.1 ; 17.28,173.02 16.53,173.77 14.04,173.77 13.65,173.38 12.69,173.38 12.56,173.51 RJ45.7 ; 17.28,173.02 17.77,172.53 18.75,172.53 18.96,172.32 XF3102.2
MDO3-: length 8.8
  TOP w0.127: RJ45.8 12.73,174.44 12.73,173.92 12.86,173.79 13.49,173.79 13.88,174.18 15.6,174.18 ; 15.6,174.18 16.7,174.18 17.94,172.93 18.4,172.93 18.52,173.06 18.52,173.37 18.75,173.59 XF3102.1 ; 15.6,174.18 AFTP3108.1
MEM_1V5: length 4.7
  TOP w0.14: R644.1 131.72,96.96 v2(130.94,96.96) 130.94,96.51 131.17,96.28 v1(131.29,96.28)
  BOTTOM w0.14: CPU1.BA3 130.2,95.43 131.05,96.28 v1(131.29,96.28)
MIC2_VREFO: length 15.1
  L3 w0.254: v1(163.13,15.63) 163.13,15.55 162.21,14.63 162.21,14.29 161.12,13.19 v1(160.97,13.19)
  BOTTOM w0.203: v1(160.97,13.19) 160.84,13.19 160.72,13.31 HDA27.29
  BOTTOM w0.254: RN2901.1 161.44,23.45 161.57,23.33 161.57,22.92 161.44,22.8 RN2901.2 160.98,22.53 161.53,21.98 162.41,21.98 162.92,21.47 v2(162.92,19.92) 162.92,15.84 v1(163.13,15.63)
MIC_CAP: length 4.1
  BOTTOM w0.203: HDA27.19 156.75,16.39 156.88,16.52 156.88,17.74 156.88,17.89 156.7,18.06 v2(156.7,18.43)
  BOTTOM w0.254: C2713.1 157.61,18.02 157.21,18.43 v2(156.7,18.43)
MIC_GND: length 2
  TOP w0.305: LCD1.26 v1(93.42,144.02)
  BOTTOM w0.508: v2(93.98,144.02) v1(93.42,144.02) 93.42,144.03 R5201.1
MODEL_ID_DET: length 25.5
  L4 w0.102: v1(144.41,125.66) 143.11,126.96 143.11,136.79 142.91,136.99 v1(142.83,136.99)
  BOTTOM w0.102: v1(144.41,125.66) v2(145.78,124.29) 146.97,123.1 147.94,123.1 148.31,123.47 R2449.2 R2451.2 148.31,124.81 148.34,124.85 148.34,126.38 148.62,126.65 KBC24.94 ; v1(142.83,136.99) 143.09,136.99 143.29,136.79 143.29,136.19 R2405.2 R2446.2 143.37,135.3 C2403.2 R2407.1
NCT7718_DXN: length 9.8
  TOP w0.254: v2(77.86,49.49) 77.2,48.83 Q2603.E 76.18,49.14 C2606.2 76.18,53.36 C2607.2 75.75,53.8 75.75,54.79 76.19,55.23 76.19,55.49 76.33,55.63 THM26.3
NCT7718_DXP: length 8.8
  TOP w0.254: THM26.2 75.68,55.44 75.24,55 75.24,54.77 ; 75.24,54.77 75.24,54 C2607.1 74.86,53.62 C2606.1 75.55,51.88 Q2603.C 75.55,49.78 Q2603.B ; 75.24,54.77 v2(75.01,54.77)
ODD_PWR_5V:
  vias: v1(168.76,88.66) v1(168.76,88.02) v1(168.76,87.39) v1(168.76,86.75) v1(168.76,86.12) v2(167.88,88.91)
P_RX_ZVDD_095: length 3.5
  TOP w0.203: v1(117.23,92.77) 116.85,93.15 R301.2 116.66,93.63 116.66,93.64 116.28,94.02 v2(116.28,95.23)
  BOTTOM w0.203: CPU1.W7 116.94,93.08 117.23,92.79 v1(117.23,92.77)
P_TX_ZVDD_095: length 2.3
  TOP w0.203: R302.2 117.76,93.37 117.76,92.57 v1(117.25,92.06)
  BOTTOM w0.203: v1(117.25,92.06) 117.03,92.28 CPU1.W8
PANEL_SIZE_ID: length 209.4
  TOP w0.102: v1(146.13,121.3) 146.13,120.33 v2(146.45,120.01) 151.62,114.84 156.9,114.84 157.08,114.66 158.1,114.66 161.36,111.39 161.36,97.29 161.03,96.96 161.03,89.42 160.61,89 160.61,88.04 158.46,85.89 157.83,85.89 156.98,85.04 156.98,83.93 157.26,83.65 157.26,81.24 156.95,80.93 156.95,76.29 158.1,75.14 158.53,75.14 159.49,74.18 163.28,74.18 163.83,73.63 165.52,73.63 165.65,73.76 v1(165.73,73.76) ; v1(166.99,71.11) 166.91,71.11 165.51,69.71 156.8,69.71 152.01,74.49 152.01,76.33 150.96,77.37 150.96,78.29 149.54,79.72 144.18,79.72 144.08,79.61 139.73,79.61 136.79,82.56 133.57,82.56 132.76,81.75 131.9,81.75 130.25,83.4 v1(130.25,83.47)
  L3 w0.102: v1(142.6,146.77) 142.59,146.77 142.44,146.92 133.33,146.92 133.07,146.66 125.46,146.66 123.17,148.95 119.58,148.95 115.28,153.25 108.74,153.25 107.4,154.6 101.38,154.6 100.54,153.76 100.54,152.82 100.74,152.61 100.74,152.14 100.43,151.83 99.01,151.83 98.41,151.22 98.41,147.97 97.87,147.43 v1(97.87,146.82)
  L4 w0.102: v1(166.99,71.11) 166.96,71.11 165.82,72.25 165.82,73.42 165.73,73.5 v1(165.73,73.76)
  BOTTOM w0.102: v1(146.13,121.3) 146.13,122.01 145.35,122.79 145.35,123.53 143.94,124.94 143.58,124.94 143.49,124.85 141.1,124.85 138.48,127.48 138.48,140.87 140.12,142.51 140.12,144.29 v1(142.6,146.77) ; R5210.2 97.77,146.92 v1(97.87,146.82) 97.12,146.07 97.12,145.59 97.21,145.5 R5208.2 R5209.1 ; v1(130.25,83.47) 129.29,82.5 128.94,82.5 128.87,82.43 128.62,82.43 128.32,82.73 CPU1.AY26
PANEL_SIZE_ID_CONN: length 5.3
  TOP w0.102: v1(96.27,145.83) 96.22,145.83 96.04,146.02 LCD1.22
  BOTTOM w0.102: v1(96.27,145.83) 96.27,146.86 v2(96.65,147.24) 97.77,148.36 R5210.1
PBAT_PRES1#: length 7.6
  TOP w0.102: RN4301.8 150.34,175.54 150.86,175.02 153.52,175.02 153.78,175.27 AFTP3902.1
  TOP w0.635: 157.3,179.02 BATT1.5 158.05,178.78
PBAT_SMBCLK1: length 12.2
  TOP w0.14: AFTP3904.1 158,175.27 157.55,174.82 157.55,174.47 157.07,173.99 150.26,173.99 149.87,174.38 149.68,174.38 149.67,174.39 RN4301.6
  TOP w0.635: 162.05,178.78 BATT1.3 161.63,178.79
PBAT_SMBDAT1: length 11.4
  TOP w0.14: RN4301.7 149.67,174.89 149.68,174.9 150.09,174.9 150.48,174.51 156.85,174.51 157.03,174.69 157.03,174.94 156.83,175.14 156.45,175.14 AFTP3903.1
  TOP w0.635: 159.3,179.02 BATT1.4 160.05,178.78
PCB_VER_AD: length 7.2
  TOP w0.102: v2(142.67,130.97) R2406.1 C2402.2 142.67,129.16 v1(143.54,128.28)
  BOTTOM w0.102: v1(143.54,128.28) 143.54,128.33 144.38,129.17 R2404.2 144.64,129.87 KBC24.98
PCH_HDMI_CLK: length 114.6
  TOP w0.14: v1(108.85,88.2) 108.79,88.2 108.32,88.68 108.32,88.68 107.11,89.89 107.11,93.93 106.62,94.41 103.5,94.41 103.19,94.71 101.19,94.71 99.34,92.87 98.65,92.87 v2(98.08,92.29) 97.29,91.51 95.36,91.51 95.34,91.53 95.09,91.53 RN402.1 94.54,91.51 94.47,91.58 94.47,92.44 94.33,92.58 92.83,92.58 88.68,88.43 88.68,87.09 87.98,86.4 87.98,85.38 87.18,84.58 85.41,84.58 85.31,84.48 v1(85.22,84.48)
  L3 w0.127: v1(71.47,84.17) 71.51,84.12 71.52,84.12 71.98,83.66 81.69,83.66 83.33,85.3 84.45,85.3 84.74,85.02 84.74,84.61 84.86,84.48 v1(85.22,84.48)
  L4 w0.127: v1(71.47,84.17) 71.47,84.09 68.92,81.54 38.51,81.54 33.55,76.59 25.15,76.59 25.03,76.72 25.03,79.31 26.08,80.37 v1(26.86,80.37) 27.01,80.52 27.01,80.88 26.8,81.09 24.95,81.09 24.42,80.55 24.42,79.56 24.29,79.44 23.67,79.44 23.54,79.56 23.54,80.03 v1(23.1,80.48)
  BOTTOM w0.14: Q5402.4 v1(26.86,80.37) ; CPU1.D17 108.6,87.95 108.82,88.18 108.83,88.18 v1(108.85,88.2) ; v1(23.1,80.48) 22.66,80.04 RN5404.1
PCH_HDMI_DATA: length 108.1
  TOP w0.14: v1(109.66,88.23) 109.56,88.23 109.06,88.72 109.01,88.72 108.54,89.2 108.54,89.2 107.63,90.1 107.63,94.14 106.84,94.93 103.72,94.93 103.41,95.24 100.97,95.24 v2(100.5,94.77) 99.12,93.39 98.44,93.39 97.08,92.03 95.58,92.03 95.56,92.05 95.18,92.05 RN402.2 94.99,92.24 94.99,92.66 94.55,93.1 92.62,93.1 88.16,88.64 88.16,87.31 87.46,86.61 87.46,85.59 86.97,85.1 v1(85.38,85.1)
  L3 w0.127: v1(85.38,85.1) 85.1,85.38 85.1,85.38 84.67,85.81 83.12,85.81 81.48,84.17 v1(72.24,84.17)
  L4 w0.127: v1(23.1,78.95) 23.12,78.93 24.39,78.93 24.52,78.8 24.52,76.51 24.94,76.08 33.76,76.08 38.72,81.04 69.14,81.04 72.24,84.15 v1(72.24,84.17)
  BOTTOM w0.14: Q5402.1 23.21,79.07 v1(23.1,78.95) 22.66,79.39 RN5404.2 ; CPU1.E17 109.4,87.95 109.63,88.18 109.63,88.18 109.66,88.22 v1(109.66,88.23)
PCH_SUSCLK_KBC: length 73.3
  TOP w0.14: v1(156.1,121.3) 156.51,120.89 156.51,119 158.18,117.32 159.2,117.32 164.02,112.5 164.02,89.99 162.83,88.8 v2(162.83,88) 162.83,86.38 162.36,85.91 v1(162.05,85.91)
  L3 w0.14: v1(140.98,88.86) 141.25,89.13 142.13,89.13 142.44,89.44 145.17,89.44 150.73,83.88 160.57,83.88 162.03,85.34 162.03,85.9 v1(162.05,85.91)
  BOTTOM w0.14: v1(156.1,121.3) 156.22,121.41 156.22,125.59 155.42,126.38 155.42,127.91 KBC24.77 ; v1(140.98,88.86) 140.52,88.86 R609.2
PCIE_PRX_LANTX_N0: length 148.2
  TOP w0.14: C3016.2 63.17,164.55 64.14,164.55 64.45,164.86 65.24,164.86 v1(65.53,165.15) 65.51,165.16 v2(65.51,165.77)
  L4 w0.127: v1(65.53,165.15) 65.83,164.84 75.56,164.84 81.92,158.48 92.49,158.48 94.95,156.02 105.87,156.02 109.24,152.65 109.24,141.76 99.78,132.3 99.78,125.21 95.83,121.26 95.83,109.27 98.15,106.96 113.84,106.96 114.64,106.16 115.83,106.16 115.98,106.31 119.62,106.31 121.11,104.82 121.11,100.95 120.31,100.14 120.31,97.86 119.4,96.96 117.68,96.96 116.23,95.5 113.79,95.5 113.15,94.87 113.15,92.83 113.45,92.53 113.82,92.53 v1(113.97,92.69)
  BOTTOM w0.14: v1(113.97,92.69) 114.09,92.69 CPU1.R8
PCIE_PRX_LANTX_P0: length 147.8
  TOP w0.14: v2(64.02,164.12) 64.02,164.28 ; 64.02,164.28 63.15,164.28 C3014.2 ; 64.02,164.28 64.25,164.28 64.56,164.59 65.24,164.59 v1(65.53,164.3)
  L4 w0.127: v1(65.53,164.3) 65.8,164.58 75.45,164.58 81.81,158.21 92.38,158.21 94.84,155.75 105.76,155.75 108.97,152.54 108.97,141.87 99.51,132.41 99.51,125.32 95.56,121.37 95.56,109.16 98.04,106.69 113.73,106.69 114.53,105.89 115.94,105.89 116.09,106.04 119.51,106.04 120.84,104.71 120.84,101.06 120.04,100.25 120.04,97.97 119.29,97.22 117.57,97.22 116.11,95.77 113.68,95.77 112.88,94.98 112.88,92.72 113.34,92.26 113.71,92.26 v1(113.95,92.02)
  BOTTOM w0.14: v1(113.95,92.02) 114.49,91.48 CPU1.R10
PCIE_PRX_WLANTX_N1: length 88.3
  L4 w0.127: v1(113.95,94.87) 114.2,94.61 116.22,94.61 117.41,95.8 120.95,95.8 125.47,100.33 138.39,100.33 138.94,99.77 138.94,99.37 145.77,92.54 145.77,90.49 146.11,90.14 146.11,87.37 152.39,81.08 152.39,79.78 153,79.17 153,66.35 157.28,62.06 157.28,57.01 156.61,56.34 156.61,51.89 v1(156.9,51.6)
  BOTTOM w0.14: R5808.2 158.3,52.95 156.73,52.95 156.61,52.83 156.61,52.44 ; 156.61,52.44 v2(156.8,52.44) ; 156.61,52.44 156.61,51.89 v1(156.9,51.6) ; CPU1.R4 114.14,94.68 v1(113.95,94.87)
PCIE_PRX_WLANTX_N3_R: length 4.2
  BOTTOM w0.14: 161.7,52.91 159.87,52.91 R5808.1 ; 161.7,52.91 v2(161.7,52.72) ; 161.7,52.91 161.93,52.91 162.2,52.64 162.44,52.64 162.56,52.52 WLAN1.43
PCIE_PRX_WLANTX_P1: length 88.3
  L4 w0.127: v1(156.06,51.6) 156.34,51.89 156.34,56.45 157.02,57.12 157.02,61.95 152.73,66.24 152.73,79.06 152.13,79.67 152.13,80.97 145.84,87.26 145.84,90.03 145.5,90.38 145.5,92.43 138.68,99.25 138.68,99.66 138.28,100.06 125.58,100.06 121.06,95.53 117.52,95.53 116.33,94.35 114.06,94.35 v1(113.95,94.23)
  BOTTOM w0.14: 157.64,53.22 158.4,53.22 R5811.2 ; 157.64,53.22 v2(157.64,53.4) ; 157.64,53.22 156.62,53.22 156.34,52.94 156.34,51.89 v1(156.06,51.6) ; CPU1.R5 114.3,93.88 v1(113.95,94.23)
PCIE_PRX_WLANTX_P3_R: length 4.2
  BOTTOM w0.14: 160.59,53.17 162.04,53.17 162.31,52.9 162.47,52.9 162.58,53.02 WLAN1.41 ; 160.59,53.17 159.94,53.17 R5811.1 ; 160.59,53.17 v2(160.59,53.35)
PCIE_PTX_LANRX_N0: length 13.8
  BOTTOM w0.102: CPU1.L1 112.2,96.87 112.2,97 112.19,97.01 112.19,97.34 111.5,98.04 110.13,98.04
  BOTTOM w0.14: 110.13,98.04 110.06,98.1 110.06,98.64 110.26,98.83 110.26,99.21 109.77,99.69 109.39,99.69 108.88,99.18 108.58,99.18 108.4,99.36 108.4,99.54 108.53,99.67 108.53,100.2 108.37,100.35 ; 108.37,100.35 108.25,100.48 107.66,100.48 107.47,100.67 107.47,101 107.7,101.23 108.37,101.23 108.74,101.6 108.74,102.1 108.33,102.51 108.33,102.75 108.41,102.83 108.8,102.83 109.02,103.06 109.02,103.44 108.91,103.55 C306.1 ; 108.37,100.35 v2(108.52,100.49)
PCIE_PTX_LANRX_N0_C: length 131.3
  TOP w0.14: v1(51.08,165.26) 50.81,165.53 50.81,166.49 50.87,166.56 LOM30.14
  L4 w0.127: v1(51.08,165.26) 51.01,165.26 50.79,165.05 50.79,164.46 50.89,164.36 51.28,164.36 52.03,165.11 53.83,165.11 55.33,163.61 75.52,163.61 81.55,157.58 92.1,157.58 94.56,155.12 104.6,155.12 108.34,151.38 108.34,142.13 98.84,132.63 98.84,125.66 94.93,121.75 94.93,108.86 97.73,106.06 107.73,106.06 108.34,105.45 108.38,105.45 v1(108.41,105.42)
  BOTTOM w0.14: v1(108.41,105.42) 108.59,105.24 C306.2 ; v1(51.08,165.26) v2(51.08,164.65)
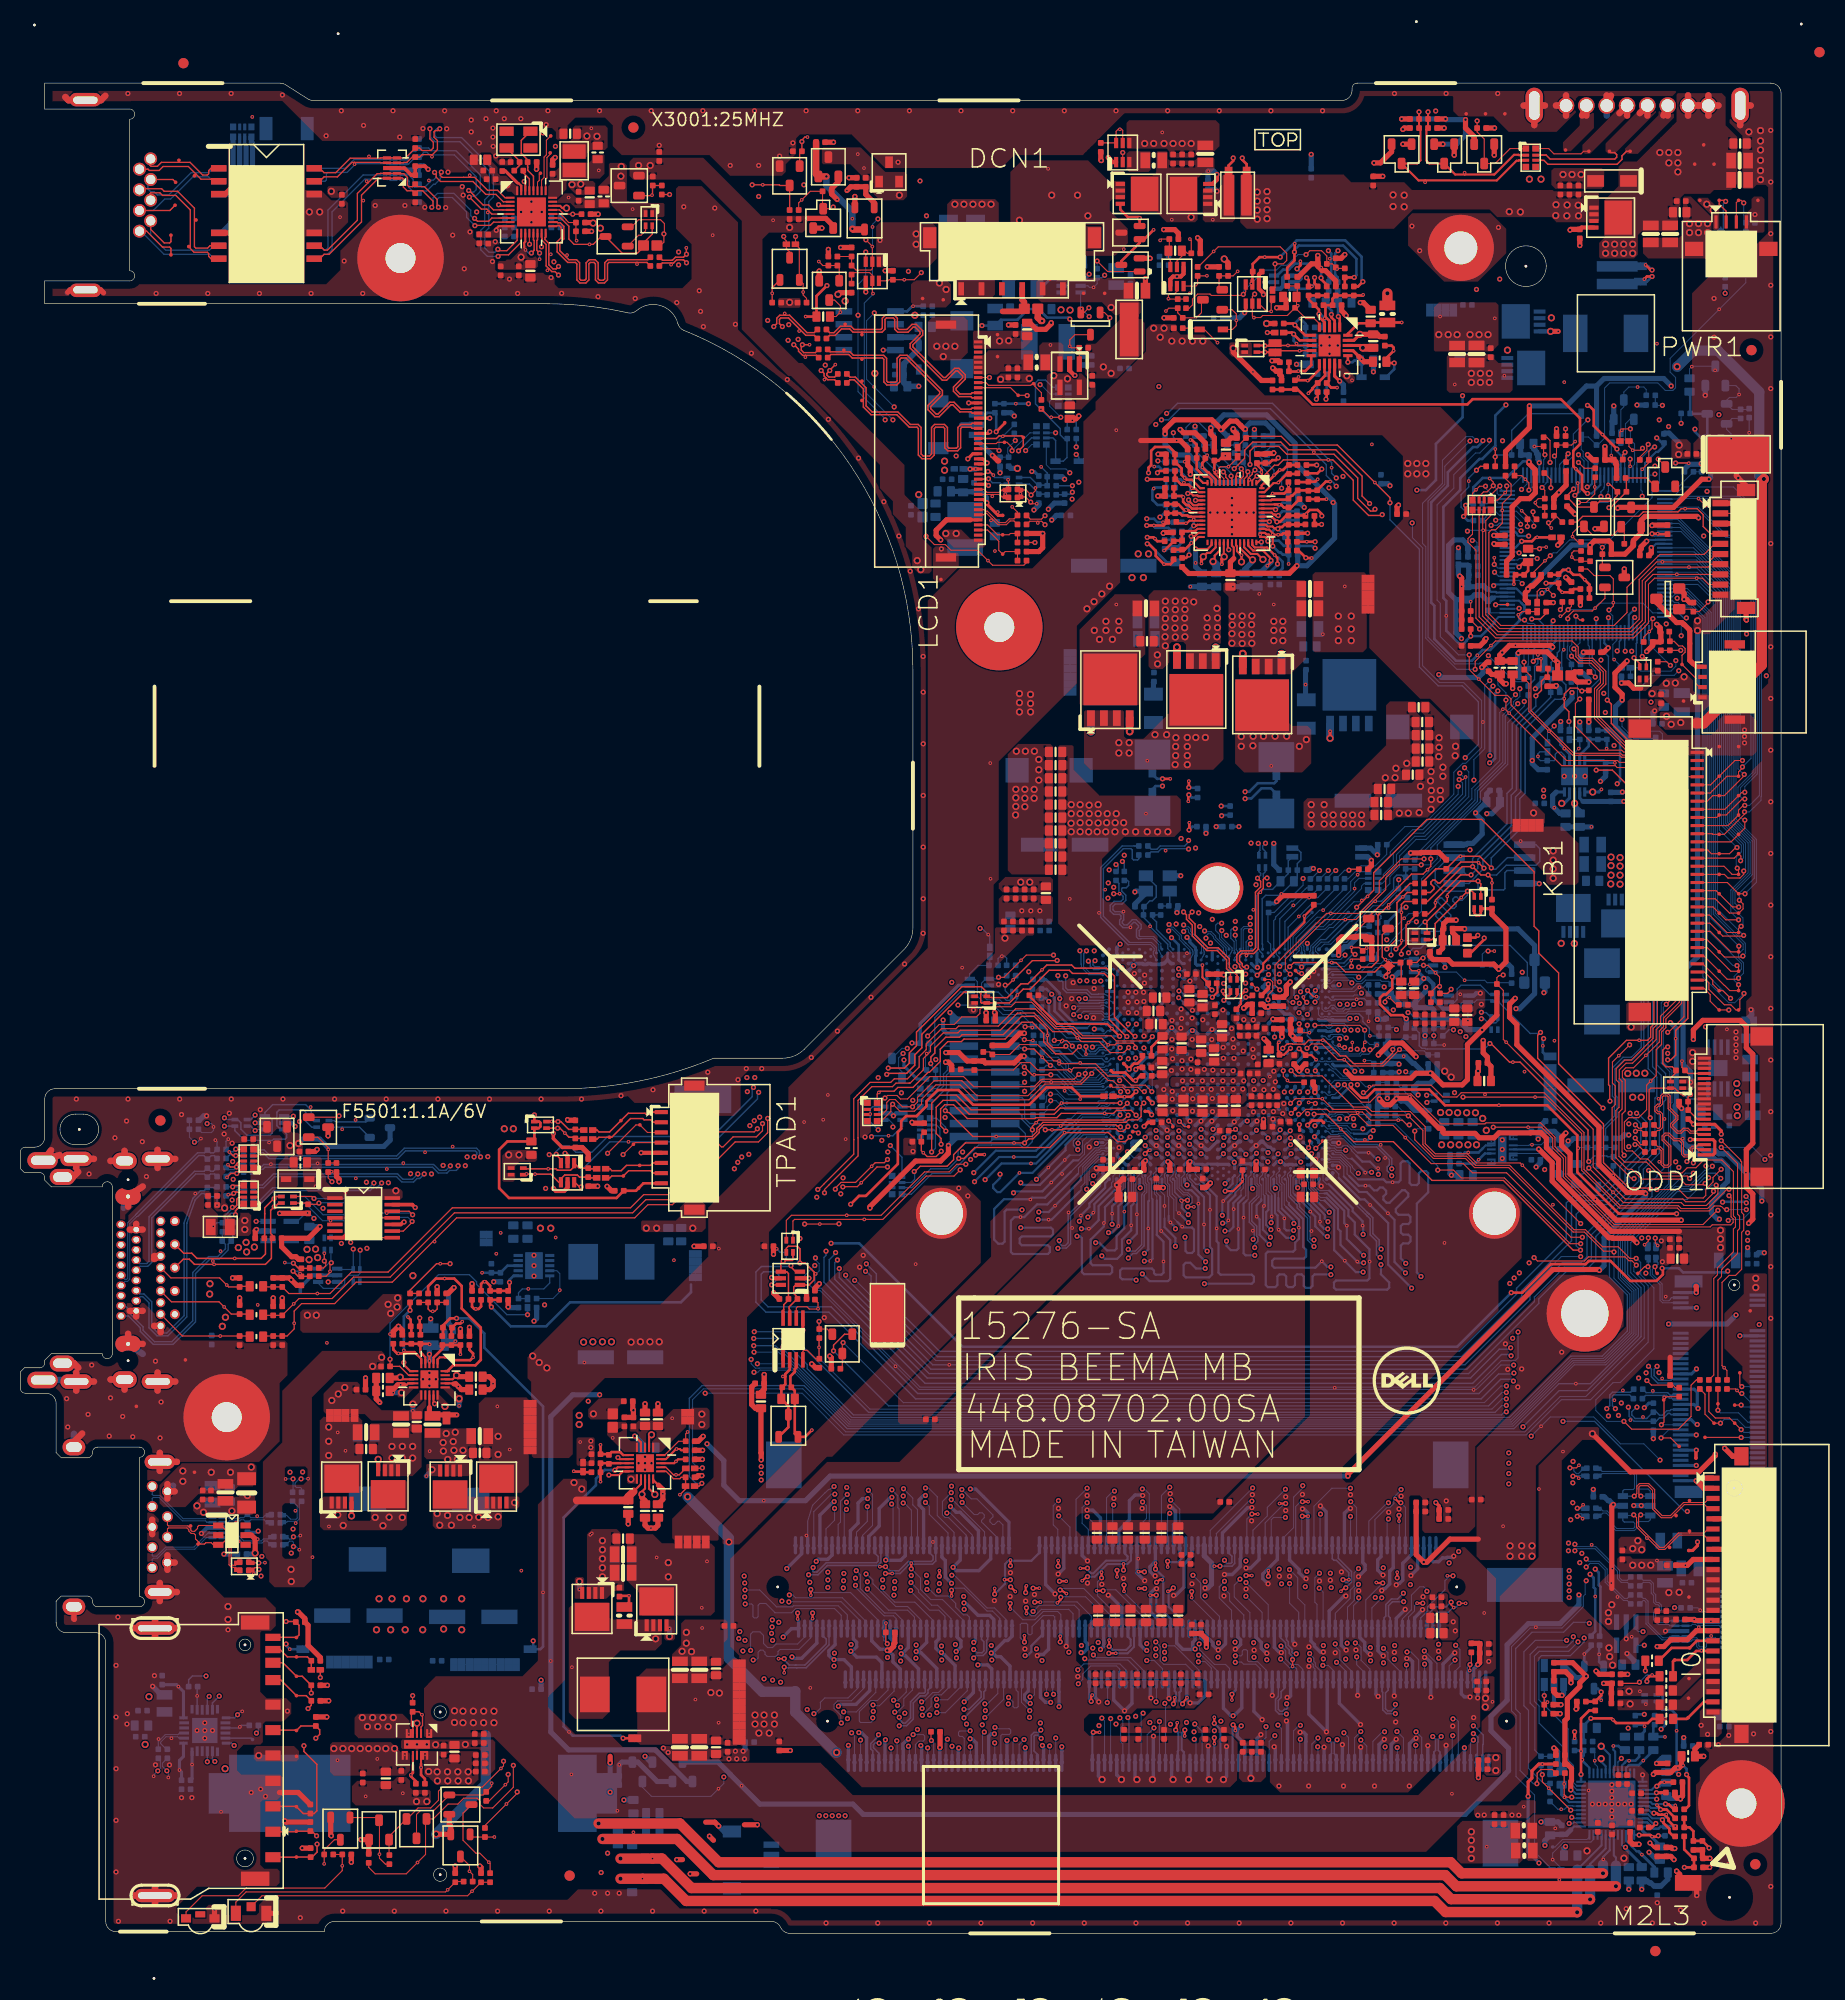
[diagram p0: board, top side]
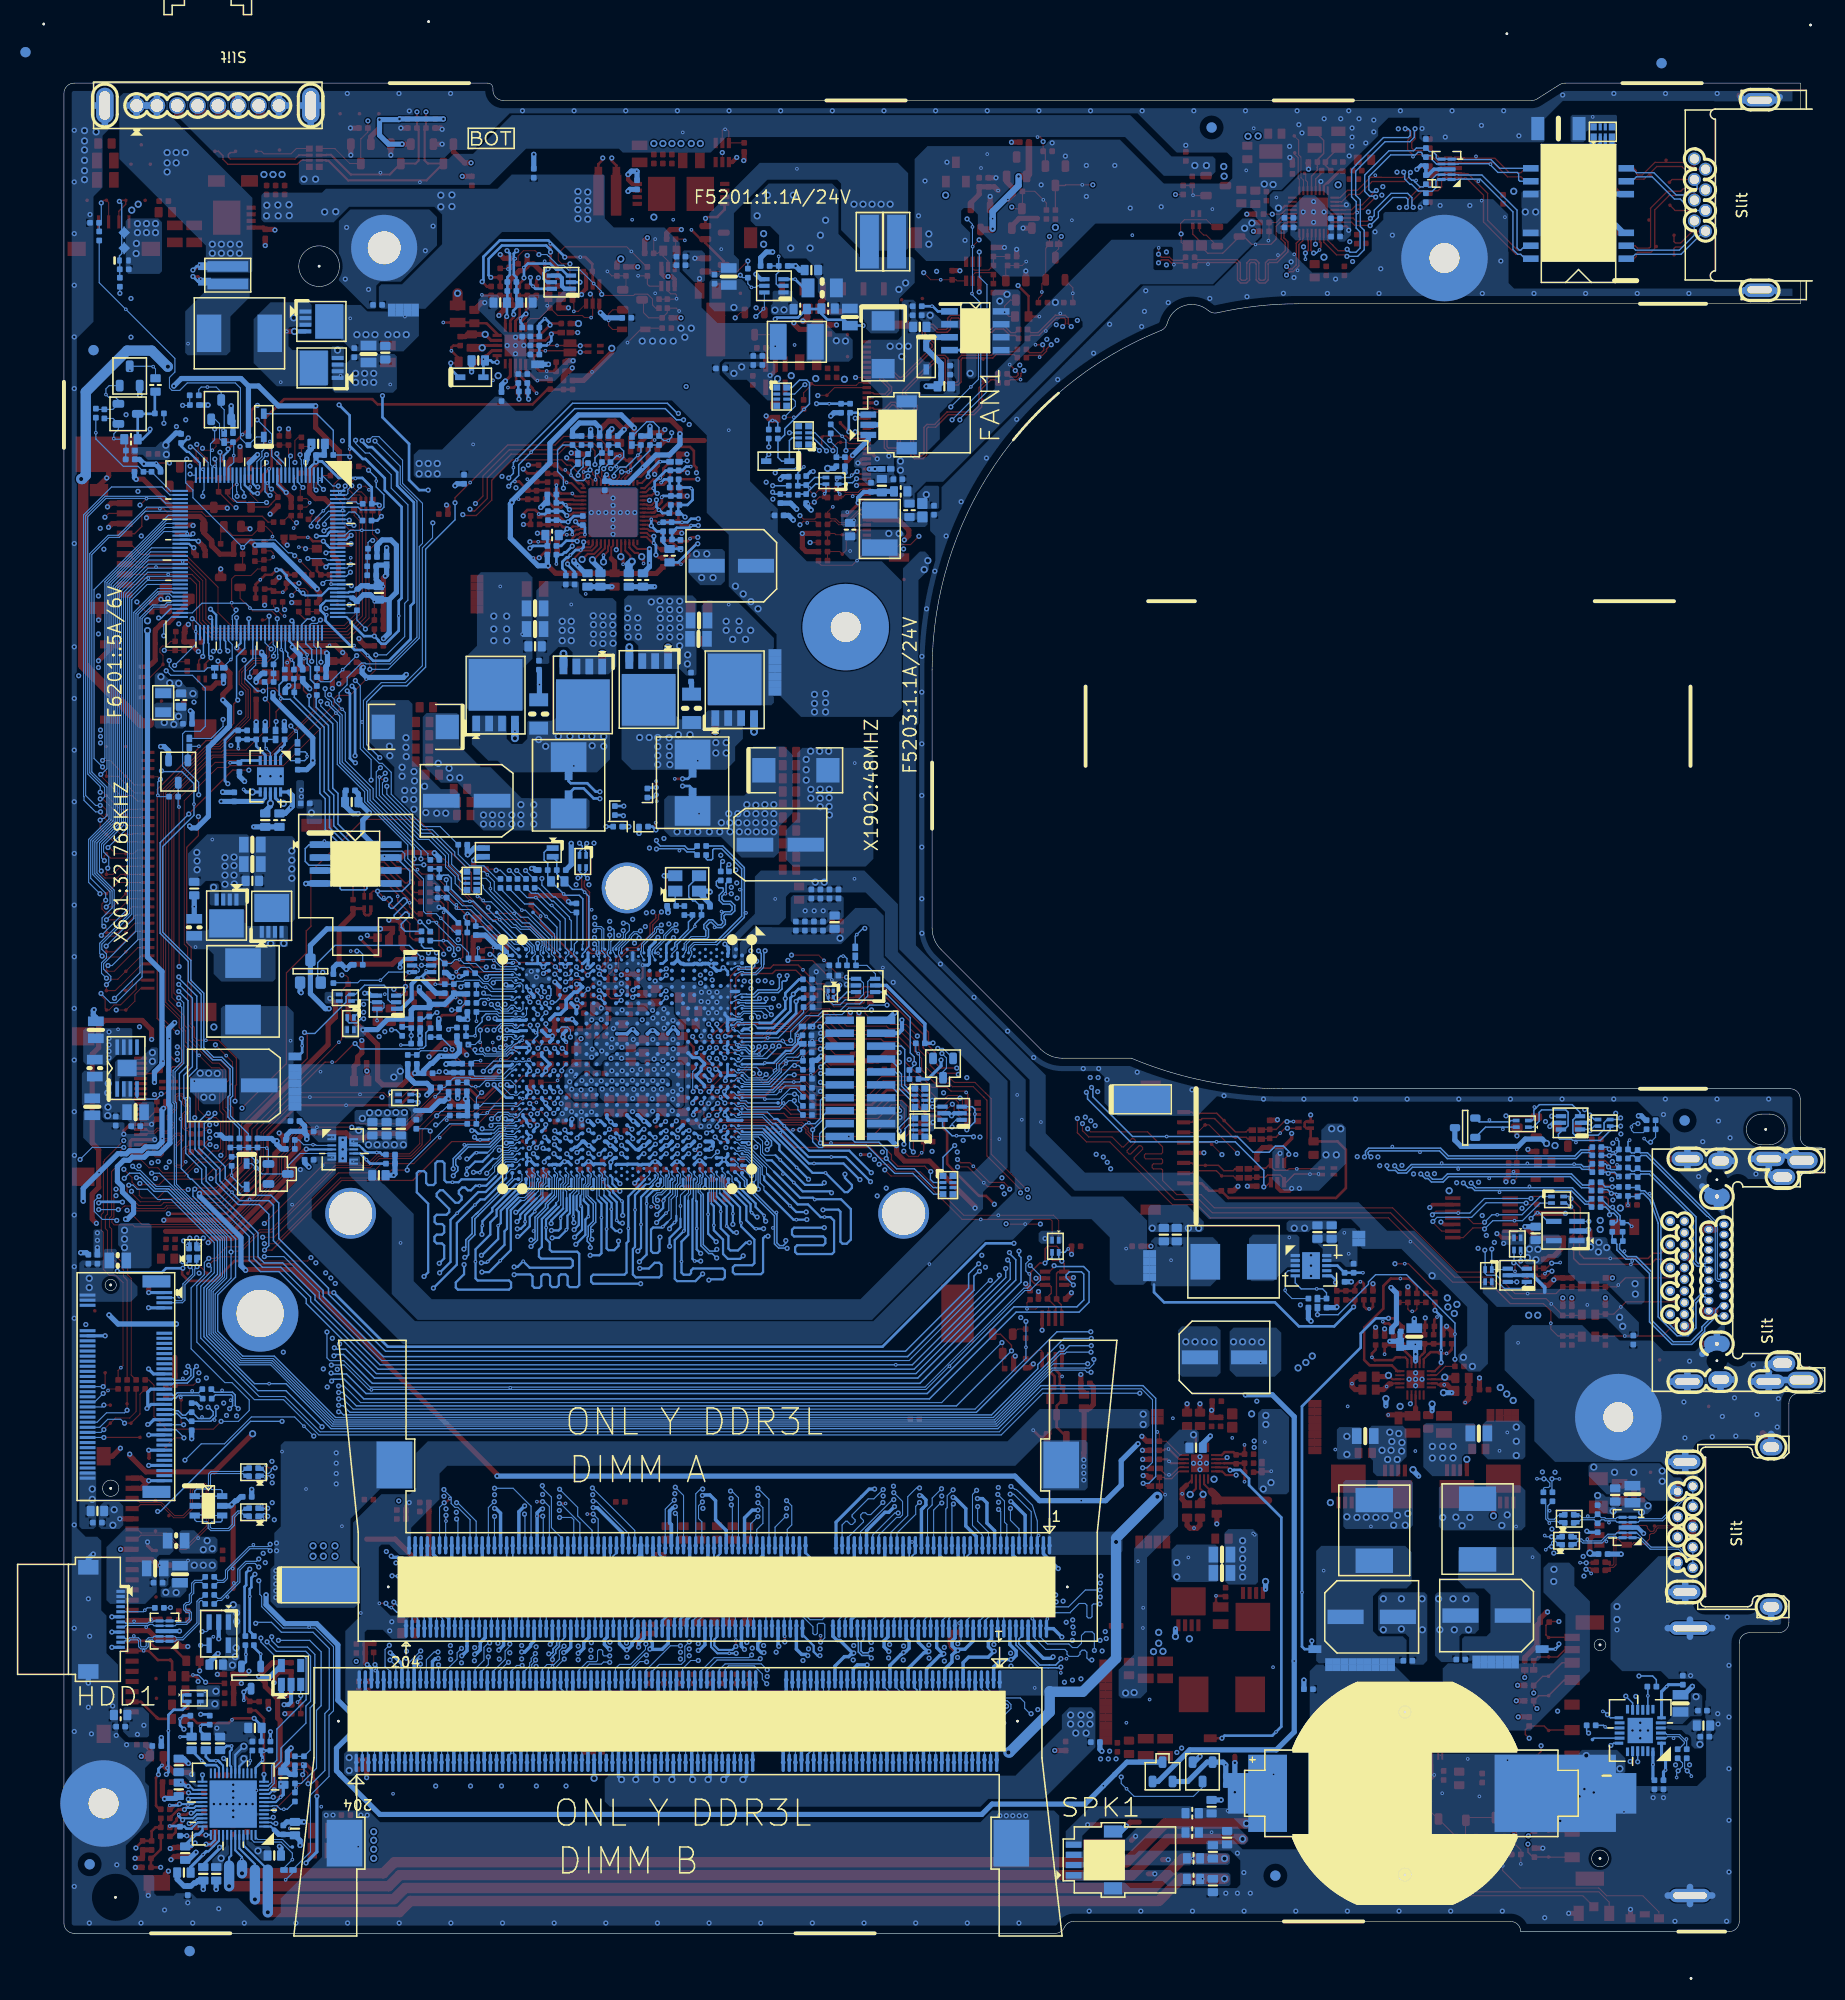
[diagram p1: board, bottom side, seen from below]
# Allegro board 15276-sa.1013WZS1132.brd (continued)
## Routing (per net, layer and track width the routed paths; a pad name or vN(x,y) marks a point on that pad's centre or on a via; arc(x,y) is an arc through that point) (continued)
PCIE_PTX_LANRX_P0: length 13.6
  BOTTOM w0.102: 109.96,97.83 109.98,97.81 110.22,97.81 110.24,97.83 111.41,97.83 111.99,97.26 111.99,96.71 112.02,96.63 CPU1.L2
  BOTTOM w0.14: 109.96,97.83 109.8,97.99 109.8,98.75 109.99,98.94 109.99,99.1 109.66,99.43 109.5,99.43 108.99,98.92 108.47,98.92 108.14,99.25 108.14,99.66 108.26,99.78 108.26,100.09 108.14,100.21 107.55,100.21 107.21,100.56 107.21,101.11 107.59,101.5 108.26,101.5 108.48,101.71 108.48,101.99 108.07,102.4 108.07,103.27 C305.1
PCIE_PTX_LANRX_P0_C: length 131.4
  TOP w0.14: LOM30.13 50.47,166.56 50.54,166.49 50.54,165.53 v1(50.27,165.26)
  L4 w0.127: v1(107.78,105.12) 107.88,105.22 107.88,105.53 107.62,105.79 97.62,105.79 94.66,108.74 94.66,121.86 98.57,125.78 98.57,132.74 108.07,142.24 108.07,151.27 104.49,154.85 94.45,154.85 91.98,157.31 81.44,157.31 75.41,163.35 55.22,163.35 53.72,164.84 52.14,164.84 51.39,164.09 50.78,164.09 50.53,164.35 50.53,165 v1(50.27,165.26)
  BOTTOM w0.14: v1(50.27,165.26) 50,165.26 v2(49.69,165.57) ; v1(107.78,105.12) 108.01,104.89 108.01,104.67 C305.2
PCIE_PTX_WLANRX_N1_C: length 94.8
  L4 w0.127: v1(160.16,55.77) 160.46,56.07 160.46,63.72 162.03,65.29 162.03,68.34 160.51,69.86 158.02,69.86 154.74,73.14 154.74,76.13 154.47,76.4 154.47,80.04 154.4,80.12 153.87,80.64 153.87,81.69 147.58,87.98 147.58,93.41 145.3,95.69 145.3,97.53 140.62,102.21 130.92,102.21 130.54,101.83 125.25,101.83 124.05,103.02 119.85,107.22 115.32,107.22 114.92,106.82 v1(114.92,106.64)
  BOTTOM w0.14: 112.66,106.68 v2(112.66,106.49) ; 112.66,106.68 114.88,106.68 v1(114.92,106.64) ; 112.66,106.68 112.24,106.68 111.92,106.36 111.22,106.36 C304.2 ; WLAN1.37 162.51,54.02 162.4,54.13 161.06,54.13 160.45,54.74 160.45,55.48 v1(160.16,55.77)
PCIE_PTX_WLANRX_P1_C: length 94.7
  L4 w0.127: v1(161,55.77) 160.73,56.05 160.73,63.61 162.3,65.18 162.3,68.45 160.62,70.13 158.13,70.13 155.01,73.25 155.01,76.24 154.74,76.51 154.74,80.15 154.51,80.38 154.13,80.75 154.13,81.8 147.85,88.09 147.85,93.52 145.56,95.8 145.56,97.64 140.73,102.47 130.81,102.47 130.43,102.09 125.36,102.09 124.31,103.13 119.96,107.49 v1(114.92,107.49)
  BOTTOM w0.14: C303.2 111.23,106.63 111.81,106.63 112.13,106.94 114.54,106.94 114.92,107.33 v1(114.92,107.49) ; v1(161,55.77) 160.71,55.48 160.71,54.85 161.17,54.39 161.5,54.39 ; v2(161.5,54.57) 161.5,54.39 ; 161.5,54.39 162.36,54.39 162.49,54.52 WLAN1.35
PCIE_RST#_C: length 4.6
  BOTTOM w0.127: CPU1.AY9 128.65,92.08 128.97,91.76 129.23,91.76 129.32,91.86 v2(131.45,91.86) 131.61,91.86 131.68,91.93 132.2,91.93 R618.2
PCIE_TXN1_C: length 17.5
  BOTTOM w0.102: CPU1.K1 111.75,96.97 111.26,97.45 109.11,97.45 109.08,97.49
  BOTTOM w0.14: v2(106.71,102.65) 106.53,102.65 ; 106.53,102.65 106.53,100.03 109.08,97.49 ; 106.53,102.65 106.53,104.71 108.5,106.68 109.25,106.68 109.38,106.55 109.38,105.7 109.51,105.57 109.9,105.57 110.03,105.7 C304.1
PCIE_TXP1_C: length 17.5
  BOTTOM w0.102: 108.97,97.22 109,97.25 111.17,97.25 111.54,96.88 111.54,96.65 111.44,96.56 111.44,96.3 CPU1.K2
  BOTTOM w0.14: v2(106.1,100.37) 106.27,100.37 ; 106.27,100.37 106.27,99.92 108.97,97.22 ; 106.27,100.37 106.27,104.82 108.39,106.94 C303.1
PCIE_WAKE#: length 221.1
  TOP w0.127: LOM30.21 53.05,169.5 53.47,169.08 v1(54.34,169.08) R3033.1 ; v1(159.98,109.84) 159.98,107.96 161.12,106.81 161.12,97.45 160.69,97.01 160.69,89.42 160.37,89.1 160.37,88.14 160.07,87.83 v2(159.24,87.83) 157.99,87.83 156.23,86.07 156.23,83.47 156.34,83.36 156.34,81.88 v1(156.37,81.85)
  L3 w0.127: v1(147.43,135.77) 145.5,135.77 140.15,130.42 140.15,125 146.07,119.07 148.56,119.07 150.59,117.04 156.56,117.04 v1(156.78,116.82) ; v1(145.8,146.8) 145.53,146.8 143.72,148.61 130.38,148.61 130.1,148.33 126.38,148.33 123.82,150.89 122.01,150.89 118.01,154.89 109.81,154.89 108.36,156.34 102.59,156.34 101.58,157.34 93.76,157.34 93.29,157.81 84.94,157.81 82.4,160.34 82.4,161.82 75.9,168.32 62.25,168.32 60.77,166.84 56.26,166.84 56.23,166.88 55.62,166.88 54.34,168.16 v1(54.34,169.08) ; v1(135.36,88.89) 136.14,88.89 136.37,89.12 138.76,89.12 138.99,88.89 139.78,88.89 140.33,88.34 141.29,88.34 142.62,87.01 146.21,87.01 150.32,82.89 155.33,82.89 v1(156.37,81.85)
  L4 w0.127: v1(145.8,146.8) 145.8,146.54 148.95,143.39 148.95,141.62 149.32,141.25 149.32,137.67 v1(147.43,135.77) ; v1(159.98,109.84) 159.47,110.35 159.47,114.13 v1(156.78,116.82)
  BOTTOM w0.127: v1(135.36,88.89) 135.16,89.09 R622.1 ; v1(147.43,135.77) 147.34,135.87 KBC24.113
PCIE_WAKE#_R: length 9.2
  BOTTOM w0.102: 131.38,90.43 130.63,90.43 130.38,90.18 128.97,90.18 128.91,90.13 128.62,90.13 128.56,90.18 128.27,90.18 128.21,90.13 127.92,90.13 127.7,90.35 CPU1.AW11
  BOTTOM w0.127: R622.2 R626.1 132.77,88.25 v2(132.75,88.28) 132.7,88.33 132.7,89.04 132.06,89.67 132.06,90.05 131.68,90.43 131.38,90.43
PD4403_A: length 4.2
  TOP w0.102: PD4404.A 119.23,157.74 119.62,158.13 v2(119.62,158.63) 119.62,159.27 119.2,159.68 PQ4409.B
PD4403_K: length 4
  TOP w0.102: v2(117.76,156.45) 116.47,157.74 PD4404.K 115.88,157.87 PR4468.2
PLT_RST#: length 439.8
  TOP w0.102: v1(89.1,137.4) 89.91,136.59 90.99,136.59 91.55,136.03 94.17,136.03 v2(95.18,135.01) 95.64,134.55 98.71,134.55 98.98,134.82 R5448.2 ; Q3003.E 60.11,167.84 60.81,168.54 62.97,168.54 63.35,168.16 63.35,167.19 v1(63.3,167.14) 63.3,166.33 62.97,166 R3016.1 ; R5807.1 166.99,64.24 167.34,64.59 167.34,65.26 167.42,65.34 167.42,65.37 168.92,66.86 168.92,69.11 169.12,69.32 169.12,70.53 168.92,70.73 168.92,75.7 v1(167.32,77.3)
  L3 w0.102: v1(135.06,90.82) 135.06,91.43 135.66,92.02 140.39,92.02 140.4,92.01 145.52,92.01 146.01,91.53 146.62,91.53 146.67,91.48 147.43,91.48 147.66,91.71 147.66,91.73 148.14,92.21 148.14,93.18 147.31,94.01 147.31,96.82 148.09,97.6 148.09,113.35 150.17,115.43 157.36,115.43 159.94,112.85 v1(159.94,111.98) ; v1(163.14,124.18) 164.31,125.35 169.2,125.35 169.82,125.97 170.26,125.97 171.75,124.48 v1(171.75,123.68) ; v1(86.83,86.54) 86.82,86.56 86.82,91.62 90.08,94.88 90.08,135.22 89.1,136.19 v1(89.1,137.4) 89.1,138.55 86.49,141.15 86.49,148.83 68.18,167.14 v1(63.3,167.14)
  L4 w0.102: v1(171.61,76.11) 171.74,76.24 171.74,123.67 v1(171.75,123.68) 171.75,140.74 170.95,141.54 170.95,167.75 166.43,172.27 161.22,172.27 158.6,174.89 148.57,174.89 142.96,180.5 133.29,180.5 131.13,178.34 70.58,178.34 63.3,171.07 v1(63.3,167.14)
  BOTTOM w0.102: D401.3 86.72,84.75 86.39,85.08 86.39,86.1 v1(86.83,86.54) ; v1(167.32,77.3) 170.42,77.3 v1(171.61,76.11) ; R618.1 133.72,91.51 C601.2 134.41,90.82 v1(135.06,90.82) ; v1(163.14,124.18) 162.69,123.73 160.56,123.73 159.29,122.46 159.29,118.71 159.77,118.22 161.27,118.22 161.53,117.97 161.53,114.79 159.94,113.21 v1(159.94,111.98)
PLT_RST#_DEBUG: length 16.9
  TOP w0.127: R6502.2 153.12,138.8 153.69,139.37 159.21,139.37 159.64,139.8 163.07,139.8 163.38,140.12 v2(163.76,140.12) 164.95,140.12 165.54,139.53 165.54,138.36 166.25,137.66 DB1.4
PLT_RST#_EC: length 5.8
  TOP w0.102: R2416.1 C2415.2 149.33,140.27 149.03,140.57 v2(149.03,140.7) 149.03,140.82 149.32,141.11 ED2401.1 149.96,141.93 v1(149.69,142.2)
  BOTTOM w0.102: KBC24.7 150.22,142.79 150.07,142.65 150.07,142.59 149.71,142.23 149.71,142.23 v1(149.69,142.2)
PLT_RST#_LAN: length 14.5
  TOP w0.127: LOM30.19 53.16,168.7 53.96,167.9 53.96,166.63 54.48,166.11 v2(55.99,166.11) 56.36,166.11 57.13,166.89 Q3003.C 59.21,165.24 60.69,165.24 61.3,165.85 R3016.2 61.3,166.25 62.16,167.11 RN3001.4
PLT_RST_NGFF#: length 6.5
  TOP w0.102: v1(166.99,51.45) AFTP5805.1 R5807.2
  BOTTOM w0.102: WLAN1.52 169.94,50.27 169.02,51.19 167.24,51.19 v1(166.99,51.45)
PM_CLKRUN#_EC: length 147.9
  TOP w0.102: v1(168.08,72.55) 168.28,72.35 168.28,70.47 168.49,70.27 168.49,69.91 168.26,69.68 166.43,69.68 166.23,69.48 156.7,69.48 151.79,74.4 151.79,76.21 150.74,77.26 150.74,78.2 149.65,79.28 v2(148.32,79.28) v1(144.89,79.28) ; R2401.1 150.55,142.97 v1(150.55,142.17)
  L3 w0.102: v1(150.55,142.17) 151.75,143.37 154.24,143.37 155.38,142.23 165.49,142.23 165.89,141.82 v1(165.92,141.82)
  L4 w0.102: v1(124.34,82.75) 124.4,82.75 125.55,83.9 131.91,83.9 132.64,83.17 138.21,83.17 139.04,82.34 139.04,80.64 140.17,79.51 144.66,79.51 v1(144.89,79.28) ; v1(165.92,141.82) 167.72,140.02 167.72,91.76 168.56,90.92 168.56,89.95 169.2,89.32 169.2,84.69 168.31,83.81 168.31,80.15 168.93,79.53 168.93,73.4 v1(168.08,72.55)
  BOTTOM w0.102: v1(150.55,142.17) 150.55,143.35 KBC24.8 ; CPU1.AP25 124.34,83.02 v1(124.34,82.75)
PM_LAN_ENABLE: length 97.2
  TOP w0.127: Q3001.G 76.66,175.05 R3023.1 v1(76.88,176.22) 76.88,176.38 77.17,176.67 v2(77.43,176.67)
  L4 w0.127: v1(147.62,137.94) 147.58,137.98 147.54,137.98 147.14,138.39 147.14,142.38 143.69,145.82 126.53,145.82 118.17,154.19 113.34,154.19 109.6,157.92 99.95,157.92 94.64,163.23 89.16,163.23 88.74,162.81 86.74,162.81 85.33,164.22 83.67,164.22 81.13,166.76 81.13,171.97 v1(76.88,176.22)
  BOTTOM w0.127: v1(147.62,137.94) 147.55,137.94 147.36,138.13 147.29,138.13 147.15,138.27 KBC24.119
PM_LAN_ENABLE_R: length 3.2
  TOP w0.127: R3022.2 C3015.2 62.19,171.88 62.19,171 v2(62.14,170.95) 62.09,170.91 Q3004.G
PM_PWRBTN#: length 64.2
  L3 w0.102: v1(134.16,93.08) 134.57,93.48 139.25,93.48 141.38,95.62 144.03,95.62 146.79,98.38 146.79,115.49 138.82,123.47 138.82,134.61 142.12,137.91 v1(142.35,137.91)
  BOTTOM w0.102: KBC24.117 145.58,137.47 145.13,137.92 145.08,137.92 145.01,137.99 v2(143.9,137.99) 142.43,137.99 v1(142.35,137.91) ; R625.1 133.95,93.29 v1(134.16,93.08)
PM_PWRBTN#_R: length 5
  BOTTOM w0.102: R630.1 R625.2 132.35,93.29 132.11,93.05 v2(131.72,93.05) 131.63,93.05 131.21,92.63 CPU1.BA8
PM_RSMRST#: length 7.6
  TOP w0.102: R629.1 R628.1 138.75,92.56 139.3,93.1 139.58,93.1 v1(139.61,93.13) 139.61,94.07 v2(139.2,94.47) 138.46,95.21 v1(138.03,95.21)
  BOTTOM w0.102: v1(139.61,93.13) 139.61,92.61 139.99,92.23 Q601.3 ; Q603.5 138.01,95.19 v1(138.03,95.21)
PM_RSMRST#_R: length 9.7
  BOTTOM w0.102: Q603.6 136.2,95.84 R649.2 135.12,95.38 134.73,95.77 v2(134.3,95.77) 134.22,95.77 133.84,95.39 132.7,95.39 131.91,94.6 128.99,94.6 128.67,94.28 CPU1.AY5
PM_SLP_S3#: length 327
  TOP w0.102: PR4910.2 67.04,45.73 v1(67.09,45.78) ; R3609.2 v1(38.59,23.38) ; v1(166.82,73.58) 166.99,73.42 166.99,72.73 165.85,71.59 163.66,71.59 163.38,71.87 157.69,71.87 v2(156.67,72.89) v1(154.29,75.27)
  L3 w0.102: v1(67.09,45.78) 66.66,45.78 65.64,46.8 65.64,47.43 63.5,49.57 59.34,49.57 56.57,52.33 v1(55.86,52.33) ; v1(134.41,97.72) 134.41,97.74 135.59,98.92 135.59,101.86 136.23,102.5 136.23,106.79 142.73,113.29 142.86,113.29 v1(142.98,113.42) ; v1(144.54,123.21) 145.18,123.86 154.61,123.86 154.77,124.01 159.77,124.01 v1(163.38,127.62)
  L4 w0.102: v1(163.38,127.62) 167.16,123.84 167.16,90.51 167.7,89.98 167.7,84.31 167.52,84.13 167.52,79.75 168.05,79.22 168.05,77 167.72,76.67 167.72,75.34 167.74,75.32 167.74,74.97 167.48,74.71 166.99,74.71 166.82,74.55 v1(166.82,73.58) ; v1(55.86,52.33) 55.61,52.08 55.61,49.92 51.98,46.29 51.98,29.42 45.93,23.38 v1(38.59,23.38) ; v1(130.31,96.22) 131.77,97.67 134.3,97.67 134.35,97.72 v1(134.41,97.72)
  BOTTOM w0.102: v1(142.98,113.42) 142.98,115.45 144.05,116.51 144.05,122.72 v1(144.54,123.21) ; U3603.5 149.97,76.7 151.18,75.49 D3603.3 153.7,74.69 v1(154.29,75.27) 154.61,75.59 154.72,75.7 D3606.K ; v1(130.31,96.22) 129.87,95.78 129.48,95.78 129.47,95.78 128.8,95.78 CPU1.AY3 ; v1(67.09,45.78) 66.66,45.78 66.12,46.32 66.12,52.49 67.19,53.55 76.97,53.55 81.19,49.33 148,49.33 151.47,52.79 153.99,52.79 159.74,58.55 159.74,63.64 158.41,64.97 158.41,67.94 162.64,72.17 163.97,72.17 164.99,73.19 166,73.19 166.4,73.59 166.81,73.59 v1(166.82,73.58) ; v1(163.38,127.62) 163.38,128.71 162.63,129.47 KBC24.64
PM_SLP_S5#: length 294.1
  TOP w0.127: v1(67.04,44.26) 66.77,43.99 PR4907.1
  L3 w0.127: v1(131.66,94.04) 132.94,94.04 133.67,94.77 136.1,94.77 136.1,94.77 138.22,94.77 140.33,96.88 144.03,96.88 146.31,99.16 146.31,115.32 138.35,123.27 138.35,123.86 138.35,134.86 143.92,140.43 148.81,140.43 149.26,139.98 149.26,139.08 150.05,138.29 150.93,138.29 151.9,139.25 151.9,141.79 152.81,142.7 154.32,142.7 155.48,141.53 v1(155.48,141.31) 155.51,141.31 155.99,140.83 161.73,140.83 165.03,137.53 165.5,137.53 v1(165.59,137.44)
  L4 w0.127: v1(165.59,137.44) 165.59,137.08 167.48,135.19 167.48,90.64 168.02,90.11 168.02,84.18 167.84,84 167.84,79.88 168.37,79.35 168.37,75.15 167.48,74.26 v1(167.27,74.26)
  BOTTOM w0.127: v1(67.04,44.26) 66.48,44.26 65.81,44.93 65.81,52.62 67.06,53.87 77.1,53.87 81.33,49.64 146.93,49.64 151.35,54.06 v2(153.02,54.06) 154.45,54.06 159.17,58.79 159.17,63.39 157.84,64.71 157.84,68.18 162.89,73.23 164.22,73.23 165.75,74.76 166.76,74.76 v1(167.27,74.26) ; CPU1.BA5 131.42,94.28 v1(131.66,94.04) ; KBC24.21 155.82,142.25 155.77,142.21 155.77,142.07 155.48,141.78 v1(155.48,141.31)
PQ3802_1: length 4.4
  TOP w0.508: v2(81.31,171.41) 81.68,171.78 PR4202.1 PR4209.2 83.17,171.03 83.99,170.21 PQ4202.B
PQ3808D: length 3.2
  TOP w0.102: PC4208.2 80.23,159.01 v2(80.67,159.45) 80.67,160.07 80.1,160.63 PQ4208.D
PQ3808G: length 3.6
  TOP w0.102: v2(78.54,164.43) 78.94,164.03 PC4209.1 PR4215.1 80.55,163.85 PQ4208.G
PQ3809_D: length 2.8
  BOTTOM w0.254: PR4214.2 100.42,161.83 v2(101.28,162.69) PQ4206.3
PQ4008_2: length 18
  TOP w0.254: PQ4408.2 121.19,163.4 PC4425.1 121.23,164.18 121.9,164.86 v2(122.41,164.86) v1(123.93,164.86) ; v1(132.06,162.44) 131.59,161.97 PR4437.2
  BOTTOM w0.254: v1(132.06,162.44) 131.93,162.57 131.93,164.9 130.32,166.51 125.55,166.51 123.93,164.89 v1(123.93,164.86)
PQ4008_6: length 2.8
  TOP w0.102: PR4426.1 123.17,160.41 123.04,160.28 v2(123.04,159.52) 122.6,159.52 PQ4408.6
PQ4203_5: length 4.9
  TOP w0.102: v2(83.88,161.28) 83.81,161.34 PQ4203.5 83.81,163.07 83.55,163.33 81.96,163.33 PC4210.1 PR4218.1
PQ4405_2: length 3.6
  TOP w0.102: PR4476.2 PR4475.2 112.97,160.73 v2(112.94,160.77) 112.94,161.12 113.06,161.25 113.52,161.25 113.77,161.5 PQ4410.2
PQ4405_3: length 3.2
  TOP w0.102: v2(116.72,163.03) 116.71,163.02 PR4466.1 115.81,162.19 115.63,162.01 PQ4410.3
PQ4405_5: length 4.3
  TOP w0.102: PQ4410.5 113.77,164.48 114.26,164.96 PC4434.1 114.54,165.49 114.79,165.24 PR4470.2 115.18,166.5 v2(115.04,166.63)
PQ4405_6: length 3.8
  TOP w0.102: v2(112.12,166.51) 112.25,166.63 PR4473.1 113.02,165.58 PC4434.2 112.94,164.73 113.12,164.54 PQ4410.6
PQ4408_C: length 5.8
  TOP w0.102: v2(112.69,159.56) 112.97,159.84 PR4475.1 113.85,159.38 PR4464.1 115.68,158.89 116.19,159.4 116.19,160.53 PQ4409.C
PQ4408_E: length 3.5
  TOP w0.102: v2(119.74,163.46) 119.3,163.02 PR4469.2 PR4467.1 117.91,161.97 PQ4409.E
PR4601_1: length 1.8
  TOP w0.254: PR4901.2 55.42,45.35 PR4906.1 54.48,45.41 v2(54.44,45.45)
PR4605_2: length 3
  TOP w0.508: PR4905.2 62.72,40.12 62.46,39.86 v2(62.03,39.86) 61.74,39.86 61.45,40.14 PC4919.1
PROCHOT_EC: length 7.5
  BOTTOM w0.102: KBC24.24 157.02,144.19 156.8,144.41 156.75,144.41 156.5,144.66 v2(156.5,145.35) 156.5,146.58 R2442.1 R2438.1 157.55,146.66 157.89,147 157.89,148.47 158.32,148.9 Q2401.G
PS_ID: length 2.8
  TOP w0.508: PQ4201.S 80.47,172.27 79.8,171.6 PR4205.1 79.8,171.07 v2(80.35,170.52)
PS_ID_R: length 4.3
  TOP w0.559: AFTP3802.1 98.51,159.52 PR4217.1 98.76,160.44 98.55,160.65 DCIN1.4
PS_ID_R2: length 25.1
  TOP w0.635: PR4217.2 100.08,158.91 100.41,158.58 v1(100.52,158.58)
  L3 w0.635: v1(87.36,163.46) 87.36,162.32 89.9,159.78 98.28,159.78 99.47,158.58 v1(100.52,158.58)
  L4 w0.635: v3(86.47,170.95) 86.47,164.35 v1(87.36,163.46)
  vias: v2(82.38,174.99) v2(82.99,173.62)
PSID_DISABLE#_R_C: length 11.7
  TOP w0.635: PQ4202.C 81.92,167.57 v1(81.85,167.65) ; PR4203.2 78.28,173.02 PQ4201.G v1(79.29,172.79)
  BOTTOM w0.635: v1(79.29,172.79) 79.29,171.91 81.85,169.35 v2(81.85,168.64) v1(81.85,167.65)
PSID_EC: length 99.8
  TOP w0.102: PR4204.2 76.56,170.19 v2(76.86,170.49) 77.71,171.33 PR4205.2 78.91,169.68 PD4203.3 79.8,169.62 v1(79.97,169.78)
  L4 w0.102: v1(79.97,169.78) 79.97,167.59 83.6,163.96 85.25,163.96 86.67,162.53 88.8,162.53 89.26,162.99 94.54,162.99 99.85,157.68 109.5,157.68 113.25,153.93 118.08,153.93 126.43,145.58 143.59,145.58 146.83,142.34 146.83,132.51 147.53,131.81 147.53,130.41 v1(147.43,130.31)
  BOTTOM w0.102: v1(147.43,130.31) 147.38,130.27 KBC24.99
PSL_IN1#: length 3.9
  BOTTOM w0.102: R2430.2 157.47,124.59 v2(156.78,125.28) 156.65,125.41 156.65,126.77 157.02,127.14 KBC24.73
PSL_IN2#: length 5
  TOP w0.102: R2427.2 R2425.1 147.72,130 147.61,129.88 147.56,129.88 v2(147.35,129.68) 147.35,129.42 147.61,129.17 v1(147.97,129.17)
  BOTTOM w0.102: v1(147.97,129.17) 148.3,128.84 148.86,128.84 149.02,128.67 KBC24.93
PSL_OUT#: length 9.2
  TOP w0.102: R2432.1 154.17,134.19 154.82,133.54 156.37,133.54 156.7,133.21 v2(156.7,130.87) 156.7,130.54 156.32,130.16 v1(156.27,130.16)
  BOTTOM w0.102: v1(156.27,130.16) 156.27,129.96 156.65,129.58 156.65,129.22 156.62,129.19 KBC24.74
PURE_HW_SHUTDOWN#: length 206.9
  TOP w0.102: R2602.2 148.81,133.83 v2(149.98,135) 150.48,135.49 v1(150.5,135.49) ; v1(80.93,58.1) 80.86,58.02 Q2602.D 80.86,55.73 C2610.1 ; v1(161.12,144.99) 161.81,144.31 D3602.3 ; v1(153.4,121.4) 152.97,120.97 152.97,118.7 155.3,116.37 157.53,116.37 157.71,116.18 158.73,116.18 162.89,112.03 162.89,91.75 161.34,90.19 161.34,89.3 160.92,88.88 160.92,87.91 158.59,85.58 157.95,85.58 157.28,84.91 157.28,84.06 157.56,83.78 157.56,81.07 157.25,80.76 157.25,76.42 157.82,75.86 159.95,75.86 161.32,74.48 163.97,74.48 v1(164.21,74.24) ; Q2404.B 155.62,134.6 R2439.2 v1(155.62,136.31)
  L3 w0.102: v1(146.18,53.83) 146.82,53.2 151.7,53.2 158.16,59.66 158.16,62.28 157.55,62.89 157.55,68.45 158.97,69.86 159.23,69.86 159.23,69.86 159.65,69.86 162.53,72.74 162.76,72.74 164.21,74.19 v1(164.21,74.24)
  L4 w0.102: v1(150.5,135.49) 151.49,134.5 151.49,131.81 153.47,129.83 153.47,128.71 154.19,128 154.19,125.21 153.17,124.19 153.17,121.63 v1(153.4,121.4)
  BOTTOM w0.102: R2424.1 153.17,122.78 153.17,121.63 v1(153.4,121.4) ; v1(80.93,58.1) 80.96,58.1 86.86,52.2 144.01,52.2 145.65,53.83 v1(146.18,53.83) ; v1(161.12,144.99) 161.22,144.89 161.22,142.66 160.51,141.95 160.51,141.2 v1(155.62,136.31) 154.88,137.04 152.4,137.04 151.13,135.77 150.78,135.77 v1(150.5,135.49)
PWR_0D95V_BOOT: length 3.9
  BOTTOM w0.305: PU4806.10 151.09,112.25
  BOTTOM w0.508: 151.09,112.25 150.73,111.89 150.73,110.86 v2(150.88,110.7) 151.44,110.15 PR4820.1
PWR_0D95V_BOOT_R: length 2.5
  BOTTOM w0.508: PR4820.2 PC4833.2 v2(154.54,108.82)
PWR_0D95V_CCM: length 3.1
  BOTTOM w0.254: v2(156.85,115.12) 156.84,115.14 PR4824.1 155.72,115.35 PU4806.5
PWR_0D95V_EN: length 3.3
  BOTTOM w0.127: PU4806.3 152.89,116.11 v2(153.3,116.52) 153.4,116.62 PC4831.1 PR4819.2
PWR_0D95V_FB: length 5.1
  BOTTOM w0.254: PU4806.4 153.39,115.88 154.29,116.77 PR4823.1 PR4822.2 PC4832.2 156.06,116.55 v2(156.04,116.52)
PWR_0D95V_LGATE: length 12.7
  L4 w1.016: v3(158.48,102.88) 158.48,107.58 155.07,110.98 155.07,111.85 v3(154.67,112.25)
  BOTTOM w0.305: PU4806.6 v3(154.67,112.25) 155.28,112.25 v2(155.53,112.51)
PWR_0D95V_PHASE: length 16.9
  L4 w1.016: v3(152.86,97.34) 152.86,97.67 153.78,98.59 153.78,107.96 152.89,108.85 v3(152.89,111.14)
  BOTTOM w0.305: v3(152.89,111.14) PU4806.8
  BOTTOM w0.508: v3(152.89,111.14) 152.89,110.88 153.4,110.37 PC4833.1
  vias: v2(160.26,97)
PWR_0D95V_PWR: length 47.8
  L3 w0.254: v1(157.08,113.07) 157.08,110.91 161.97,106.02 161.97,97.31 160.36,95.7 160.36,88.69 158.53,86.87 150.88,86.87 149.84,87.9 v1(149.84,88)
  BOTTOM w0.254: PR4822.1 PC4832.1 156.41,118.31 157.36,117.36 157.36,113.35 v1(157.08,113.07) ; PG4832.1 149.77,86.65 v2(149.77,87.29) 149.77,87.92 v1(149.84,88)
PWR_0D95V_PWRGD: length 5.4
  BOTTOM w0.127: PR4821.1 149.47,116.2 149.28,116.01 v2(149.28,115.76) 149.28,115.58 149.52,115.34 PR4835.2 150.87,115.34 150.98,115.45 150.98,115.96 151.19,116.17 151.57,116.17 151.89,115.85 PU4806.1
PWR_0D95V_TRIP: length 2.4
  BOTTOM w0.254: PU4806.2 152.39,115.98 151.87,116.5 v2(151.87,116.52) 151.49,116.9 PR4817.2
PWR_0D95V_UGATE: length 16.1
  L4 w1.016: v3(151.57,97.37) 151.57,98.26 152.51,99.2 152.51,107.43 151.62,108.32 v3(151.62,111.14)
  BOTTOM w0.305: PU4806.9 152.39,111.65 151.87,111.14 v3(151.62,111.14)
PWR_1D05V_SNUB: length 2.3
  BOTTOM w0.508: PR4837.2 v2(160.38,100.98) PC4838.1
PWR_1D8V_EN: length 5.6
  BOTTOM w0.127: PU5002.5 52.08,63.97 51.49,63.38 v2(49.97,63.38) 49.38,63.38 49,63 PC5005.1 PR5010.2
PWR_1D8V_FB: length 6.3
  TOP w0.254: v1(48.11,64.02) 48.11,63.32 PR5013.1 PR5009.2 PC5014.2 46.21,63.69 45.81,64.09 v2(45.68,64.09) 45.54,64.09 45.32,63.87 PC5020.1
  BOTTOM w0.254: PU5002.6 48.51,64.67 48.11,64.27 v1(48.11,64.02)
PWR_1D8V_FB_A: length 2.4
  TOP w0.254: PR5020.1 44.43,61.63 44.65,61.41 v2(44.81,61.41) 45.08,61.41 45.32,61.66 PC5020.2
PWR_1D8V_PHASE:
  vias: v2(52.66,68.44)
PWR_1D8V_PVDD:
  vias: v2(46.82,66.84) v2(47.25,68.9)
PWR_1D8V_SVIN: length 3.8
  BOTTOM w0.254: PU5002.8 47.92,65.67 PC5013.1 PR5012.2 v2(45.42,64.97)
PWR_1D35V_DRVH: length 17.1
  TOP w0.203: v3(62.42,43.17) 61.85,43.73 PU4901.14
  L4 w1.016: v3(63.86,29.2) 63.86,31.63 62.42,33.08 v3(62.42,43.17)
  BOTTOM w0.508: v2(63.86,29.96) v3(63.86,29.2)
PWR_1D35V_DRVL: length 12.9
  L4 w1.016: v3(60.07,44.66) 55,39.6 v3(55,34.61)
  BOTTOM w0.508: v2(55,33.84) v3(55,34.61)
PWR_1D35V_EN: length 4.7
  TOP w0.127: PU4901.16 63.53,45.44 64.25,44.71 64.87,44.71 65.01,44.85 PC4906.1 PR4907.2 65.44,43.7 v2(64.88,43.14)
PWR_1D35V_MODE: length 2.9
  TOP w0.203: PR4908.1 65.01,47.51 64.88,47.64 v2(64.55,47.64) 64.5,47.64 63.5,46.64 PU4901.19
PWR_1D35V_REFIN: length 4.7
  TOP w0.203: 59.04,46.24 PU4901.8
  TOP w0.254: 59.04,46.24 57.96,46.24 PR4903.2 57.83,46.24 PC4902.1 PR4901.1 v2(57.07,44.42)
PWR_1D35V_SW: length 17.5
  TOP w0.203: PU4901.13 61.45,43.75 61.14,43.44 v3(61.14,43.18)
  TOP w0.508: PC4919.2 61.45,42.56 61.14,42.86 v3(61.14,43.18)
  L4 w1.016: v3(62.49,28.97) 62.49,31.1 61.14,32.45 v3(61.14,43.18)
  vias: v2(54.26,26.17)
PWR_1D35V_TRIP: length 2.6
  TOP w0.203: PU4901.18 64.32,46.24 v2(64.49,46.42) 64.7,46.62 PR4902.1
PWR_1D35V_VBST: length 3.1
  TOP w0.203: 62.77,44.08 62.25,44.6 PU4901.15
  TOP w0.508: 62.77,44.08 63.2,43.65 v2(63.2,43.23) 63.2,42.68 PR4905.1
PWR_1D35V_VREF: length 4
  TOP w0.203: 59.3,47.04 PU4901.6
  TOP w0.254: v2(57.07,48.04) PC4903.1 57.83,47.13 PR4903.1 58.16,47.33 59.01,47.33 59.3,47.04
PWR_1D35V_VTTREF:
  vias: v2(58.27,48.73)
PWR_3D3V_BOOT: length 2.7
  TOP w0.203: 37.74,53.95 38,53.95 38.15,54.09 PU4509.9
  TOP w0.508: PR4505.2 36.53,53.35 37.13,53.95 v2(37.42,53.95) 37.74,53.95
PWR_3D3V_BOOT_A: length 2.6
  TOP w0.508: PC4505.2 PR4505.1 35.01,52.56 v2(35.36,52.21)
PWR_3D3V_CS: length 4.3
  TOP w0.203: PU4509.5 39.44,56.49 39.05,56.88
  TOP w0.254: 39.05,56.88 38.77,57.16 38.01,57.16 37.88,57.03 v2(37.19,57.03) 37.07,57.03 36.68,57.41 PR4507.1
PWR_3D3V_EN2: length 7.6
  TOP w0.203: v1(37.73,56.14) 37.73,55.92 38.35,55.29 PU4509.6
  TOP w0.254: PR4529.2 v1(38.34,61.28)
  BOTTOM w0.254: v1(37.73,56.14) v2(37.73,57.34) 37.73,60.67 v1(38.34,61.28)
PWR_3D3V_FB: length 4.9
  TOP w0.203: PU4509.4 39.84,56.67 39.61,56.91
  TOP w0.254: PR4516.2 39.35,57.16 39.61,56.91 ; PR4516.2 PC4506.2 PR4518.1 ; PR4516.2 40.2,57.99 v2(40.27,57.92)
PWR_3D3V_FB_A: length 1.9
  TOP w0.254: PC4506.1 38.46,59.64 PR4506.2 38.4,60.35 v2(38.13,60.62)
PWR_3D3V_FB_B: length 43.5
  TOP w0.254: v1(39.29,60.53) PR4506.1 39.35,59.64 PR4516.1
  L3 w0.254: v1(39.29,60.53) 38.97,60.21 34.4,60.21 28.76,54.57 28.76,34.28 26.68,32.19 26.68,28.99 v1(26.14,28.46)
  BOTTOM w0.254: v1(26.14,28.46) 26.14,28.31 v2(26.5,27.95) PG4537.2
PWR_3D3V_HG: length 17.1
  TOP w0.406: PU4510.4 v3(32.58,41.06)
  L4 w1.016: v3(32.58,41.06) 32.58,45.04 33.1,45.56 33.1,50.21 36.07,53.17 v3(37.5,53.17)
  BOTTOM w0.508: v2(36.68,53.17) v3(37.5,53.17)
PWR_3D3V_LG: length 8.6
  TOP w0.406: PU4506.4 v3(35.2,46.62)
  L4 w1.016: v3(35.2,46.62) 35.2,48.64 v3(38.62,52.06)
  BOTTOM w0.508: v2(38.62,51.4) v3(38.62,52.06)
PWR_3D3V_PH: length 19.5
  TOP w0.203: v3(37.37,54.7) 37.57,54.49 PU4509.8
  TOP w0.508: PC4505.1 37.29,54.62 v3(37.37,54.7)
  L4 w1.016: v3(37.37,54.7) 35.8,54.7 31.83,50.73 31.83,46.09 31.22,45.48 v3(31.22,41.16)
  vias: v2(30.36,40.02) v3(31.76,40.12) v3(34.91,40.9) v3(35.67,40.09) v3(36.28,40.93) v3(37.57,40.9)
PWR_5V_BOOT: length 2.6
  TOP w0.203: PU4509.17 42.6,54.09 42.65,54.04
  TOP w0.508: PR4524.1 43.39,53.48 v2(43.09,53.78) 42.83,54.04 42.65,54.04
PWR_5V_BOOT_A: length 2.9
  TOP w0.508: PR4524.2 46.18,53.48 46.5,53.79 v2(46.5,54.06) 46.5,54.38 46.13,54.75 PC4510.1
PWR_5V_CS: length 5.6
  TOP w0.203: PU4509.1 41.04,56.44 41.26,56.65 41.76,56.65
  TOP w0.254: PR4511.1 44.18,57.39 44.53,57.03 v2(44.53,56.65) 44.25,56.37 42.48,56.37 42.2,56.65 41.76,56.65
PWR_5V_EN1: length 16.6
  TOP w0.254: PU4509.20 42.01,55.29 42.58,55.87 44.76,55.87 45.3,56.4 45.3,59.57 43.42,61.45 43.42,63.66 42.68,64.4 v2(41.74,64.4) 40.88,64.4 40.11,63.64 PR4528.2
PWR_5V_EN1_R: length 4.2
  TOP w0.127: PR4527.2 PR4528.1 40.11,61.4 40.34,61.17 v2(40.57,61.17) 40.77,61.17 41,61.4 PR4531.2 PR4530.2
PWR_5V_FB: length 4.9
  TOP w0.203: PU4509.2 40.64,56.62
  TOP w0.254: v2(43.29,56.96) PR4523.1 PC4521.2 PR4514.2 41.51,57.49 40.64,56.62
PWR_5V_FB_A: length 2.1
  TOP w0.254: v2(43.47,60.16) 43.29,59.98 42.87,59.98 42.47,59.57 PR4513.2 42.4,59.51 PC4521.1
PWR_5V_HG: length 14.7
  L4 w1.016: v3(43.16,52.59) 45.68,52.59 48.62,49.65 v3(48.62,42.36)
  BOTTOM w0.508: v2(43.16,51.88) v3(43.16,52.59)
PWR_5V_LG: length 7.6
  L4 w1.016: v3(40.49,45.6) 40.49,50.3 41.76,51.57 v3(41.76,51.83)
  BOTTOM w0.508: v3(40.49,45.6) 40.49,45.53 v2(39.94,44.97)
PWR_5V_PH: length 23.1
  TOP w0.203: PU4509.18 42.53,54.49 v3(42.91,54.87)
  TOP w0.508: PC4510.2 43.03,54.75 v3(42.91,54.87)
  L4 w1.016: v3(47,40.97) 49.02,40.97 49.15,41.09 49.89,41.84 49.89,50.18 46.21,53.86 43.92,53.86 v3(42.91,54.87)
  vias: v2(44.64,40.02) v3(41,41.29) v3(41.26,40.14) v3(42.02,41.11) v3(42.4,40.14) v3(43.24,40.9) v3(44.15,40.9) v3(45.09,40.93) v3(46.01,40.9)
PWR_5V_VO: length 82.2
  TOP w0.203: v1(40.75,52.09) 40.64,52.2 PU4509.14
  TOP w0.254: v1(42.91,60.49) 42.27,60.49 41.57,59.79 PR4513.1 41.57,58.81 PR4514.1
  L4 w0.254: v1(50.45,28.76) 50.71,28.76 51.54,29.6 51.54,51.7 46.34,56.91 42.78,56.91 41.76,55.89 41.76,54.49 40.62,53.35 40.62,52.22 v1(40.75,52.09)
  BOTTOM w0.254: v1(42.91,60.49) 44.15,60.49 45.64,59 45.64,57.61 51.42,51.83 v2(51.42,33.54) 51.42,28.2 51.16,27.95 PG4547.2 v1(50.45,28.76)
PWR_APU_SVC: length 3.7
  TOP w0.127: v1(120.1,144.04) 120.1,143.95 120.3,143.75 120.3,143.29 119.98,142.97 PU4601.5
  BOTTOM w0.127: v1(120.1,144.04) 120.07,144.07 120.07,144.07 PR4653.2 118.82,145.32 v2(118.52,145.32)
PWR_APU_SVD: length 3
  TOP w0.127: PU4601.3 120.78,143.12 121.19,143.53 121.19,143.67 v1(121.44,143.93)
  BOTTOM w0.127: PR4652.2 121.44,144.4 v1(121.44,143.93) 121.6,143.77 121.83,143.77 121.88,143.72 v2(122.08,143.72)
PWR_APU_SVT: length 3.3
  TOP w0.127: PU4601.4 120.38,143.04 120.68,143.34 120.68,143.69 v1(120.75,143.75)
  BOTTOM w0.127: PR4651.2 120.28,144.5 120.5,144.27 120.5,144.27 120.55,144.22 120.55,143.95 v1(120.75,143.75) 120.91,143.58 v2(120.91,142.96)
PWR_APU_VDD_BST1: length 4.7
  TOP w0.203: v1(115.6,136.15) 116.8,136.15 117.18,136.54 PU4601.28
  BOTTOM w0.508: v1(115.6,136.15) v2(115.6,134.78) 115.6,134.4 PR4701.1
PWR_APU_VDD_BST1_1: length 2.5
  BOTTOM w0.508: v2(115.09,132.45) PR4701.2 PC4736.1
PWR_APU_VDD_CSN1: length 49.7
  TOP w0.254: PR4639.2 v2(126.55,136.87) v1(127.36,136.87)
  L4 w0.254: v1(112.35,112.84) 112.55,113.04 112.56,113.04 113.02,113.5 115.98,113.5 117.63,115.15 131.72,115.15 134.6,118.03 134.6,130.24 127.97,136.87 v1(127.36,136.87)
  BOTTOM w0.254: v1(112.35,112.84) 111.67,112.84 111.36,112.53 PG4702.1
PWR_APU_VDD_DCBATOUT:
  vias: v2(107.8,130.69) v3(105.65,128.15) v3(106.15,127.26) v3(106.79,129.04) v3(106.79,128.15) v3(107.42,127.26) v3(108.06,129.04) v3(108.06,128.15)
PWR_APU_VDD_HG1: length 32
  TOP w0.203: v3(116.36,135.39) 116.75,135.77 117.05,135.77 117.58,136.31 PU4601.29
  TOP w0.305: v3(116.36,135.39) 116.19,135.22 v2(116.19,134.73)
  TOP w0.762: PU4703.4 v3(109.13,118.2)
  L4 w0.762: v3(105.32,118.17) 107.3,118.17 ; 107.3,118.17 109.1,118.17 v3(109.13,118.2) ; 107.3,118.17 107.3,119.01 109.84,121.55 109.84,131.2 112.2,133.56 115.08,133.56 116.19,134.67 116.19,135.22 v3(116.36,135.39)
  BOTTOM w0.762: PU4701.4 v3(105.32,118.17)
PWR_APU_VDD_LG1: length 19
  TOP w0.203: v3(118.42,135.39) 118.38,135.43 PU4601.31
  TOP w0.305: v3(118.42,135.39) 118.19,135.16 v2(118.19,134.66)
  TOP w0.762: PU4704.4 v3(113.77,126.5)
  L4 w0.762: v3(113.77,126.5) 115.42,126.5 ; 115.42,126.5 v3(117.58,126.5) ; 115.42,126.5 115.42,129.55 118.47,132.6 118.47,135.34 v3(118.42,135.39)
  BOTTOM w0.762: PU4702.4 v3(117.58,126.5)
PWR_APU_VDD_PGOOD: length 6.1
  TOP w0.127: PU4601.7 119.18,143.04 119.16,143.06 119.16,143.27 v1(119.1,143.32)
  BOTTOM w0.127: v1(119.1,143.32) 119.1,143.6 118.5,144.21 117.91,144.21 v2(116.75,145.38) 116.44,145.68 PR4615.2 PR4616.1
PWR_APU_VDD_SNUB: length 1.3
  BOTTOM w0.508: PC4742.1 111.46,123.06 PR4709.2
PWR_APU_VDD_SW1: length 25.2
  TOP w0.203: v3(117.33,134.92) 117.48,135.07 117.48,135.49 117.98,136 PU4601.30
  L4 w0.762: v3(111.61,117.89) 110.85,118.65 110.85,130.78 112.62,132.55 115.5,132.55 117.33,134.38 v3(117.33,134.92)
  BOTTOM w0.762: v3(117.33,134.92) 117.63,134.62 PC4736.2
  vias: v2(110.85,115.33) v3(108.06,117.1) v3(108.06,116.09) v3(109.07,117.1) v3(109.07,116.09) v3(112.76,117.89) v3(113.65,116.72) v3(113.65,115.83) v3(113.6,114.95) v3(113.67,117.59) v3(114.79,117.61) v3(114.79,116.72) v3(114.79,115.83) v3(114.79,114.95) v3(115.63,117.61) v3(116.57,117.61)
PWR_APU_VDD_SWN1: length 49.7
  TOP w0.254: v2(113.11,113.55) v1(112.35,113.55)
  L4 w0.254: v1(112.35,113.55) 112.81,114.01 115.77,114.01 117.42,115.66 131.51,115.66 134.09,118.24 134.09,130.03 127.89,136.23 v1(127.36,136.23)
  BOTTOM w0.254: PG4701.1 111.82,113.55 v1(112.35,113.55) ; PR4644.2 125.65,137.34 PR4637.2 127.05,136.46 127.15,136.36 127.24,136.36 v1(127.36,136.23)
PWR_APU_VDDNB_DCBATOUT:
  vias: v2(128.12,127.77) v2(130.28,132.47) v3(129.65,129.55) v3(129.65,128.28) v3(129.65,127.14) v3(130.92,129.55) v3(130.92,128.28) v3(130.92,127.14)
PWR_CHG_ACDET: length 6.1
  TOP w0.254: PR4407.2 125.23,158.33 v1(125.38,158.18) 126.39,157.17 PU4404.6
  BOTTOM w0.254: v1(125.38,158.18) 125.38,158.35 125.84,158.81 v2(125.92,158.81) 126.44,158.29 PC4412.1 PR4431.1
PWR_CHG_ACN: length 26.6
  TOP w0.254: v1(120.2,174.61) 120.2,174.43 120.63,174 PG4403.2 ; v1(129.65,159.01) 129.65,158.98 129.79,158.84 PU4404.1
  L4 w0.254: v1(120.2,174.61) 120.56,174.25 127.77,174.25 129.33,172.7 129.33,172.38 129.33,165.77 v1(129.61,165.49)
  BOTTOM w0.254: 129.33,163.69 129.33,163.13 129.59,162.88 PR4406.1 PC4402.2 129.59,160.42 PC4403.1 129.62,159.04 v1(129.65,159.01) ; 129.33,163.69 v2(129.52,163.69) ; 129.33,163.69 129.33,165.21 v1(129.61,165.49)
PWR_CHG_ACOK: length 48.2
  TOP w0.102: v1(126.47,165.11) 126.85,165.49 128,165.49 128.52,164.97 PR4419.2 129.05,164.2 PR4436.1 129.5,163.75 PR4428.2 ; PR4476.1 114.98,159.84 115.3,160.16 115.3,160.72 115.8,161.22 117.03,161.22 117.16,161.09 120.19,161.09 v1(120.3,161.2) 120.54,161.44 PQ4408.3 ; PQ4402.2 v1(108.44,175.14)
  L4 w0.102: v1(108.44,175.14) 117.71,175.14 119.49,173.37 125.58,173.37 126.47,172.48 v1(126.47,165.11)
  BOTTOM w0.102: v1(126.47,165.11) 125.69,165.11 125.51,164.93 125.47,164.93 124.6,164.06 124.04,164.06 123.56,163.59 122.41,163.59 v2(121.09,162.27) 120.33,161.5 120.33,161.22 v1(120.3,161.2)
PWR_CHG_ACP: length 27.6
  TOP w0.254: PU4404.2 129.29,158.62 128.96,158.94 v1(128.96,159.22) ; PG4402.2 118.85,173.87 119.31,174.33 v1(119.31,174.61)
  L4 w0.254: v1(119.31,174.61) 119.31,174.43 119.87,173.87 127.62,173.87 128.95,172.54 128.95,165.77 v1(128.67,165.49)
  BOTTOM w0.254: v1(128.67,165.49) 128.95,165.21 128.95,164.7 ; 128.95,164.7 128.95,163.13 128.7,162.88 PR4406.2 PC4402.1 128.7,160.68 PC4404.1 128.4,160.18 129.01,159.57 129.01,159.27 v1(128.96,159.22) ; 128.95,164.7 v2(128.81,164.7)
PWR_CHG_AD_OFF: length 64.9
  L3 w0.102: v1(106.66,163.08) 110.5,159.24 110.5,156.83 111.69,155.64 118.25,155.64 122.3,151.59 124.11,151.59 126.67,149.03 129.81,149.03 130.09,149.31 144.7,149.31 145.31,148.7 154.04,148.7 v1(154.19,148.85)
  BOTTOM w0.102: v1(154.19,148.85) 154.16,148.85 152.76,147.46 152.76,145.3 151.82,144.35 KBC24.11 ; v1(106.66,163.08) 106.42,162.84 PR4210.1 105.93,162.24 v2(105.57,161.89) 105.16,161.89 105.01,162.04 PQ4206.5
PWR_CHG_AD_OFF_R: length 27.6
  TOP w0.102: PQ4203.6 85.35,162.53 85.45,162.63 PR4211.1 v2(86.95,162.63) 87.93,162.63 v1(88.63,163.33) ; v1(105.93,164.48) 106.96,163.44 PQ4204.B
  L4 w0.102: v1(105.93,164.48) 89.77,164.48 v1(88.63,163.33)
  BOTTOM w0.102: PR4210.2 v1(105.93,164.48)
PWR_CHG_BAT_SCL: length 3.4
  TOP w0.14: PU4404.9 126.05,155.67 126.03,155.65 v2(125.84,155.65) 123.9,155.65 PG4407.1
PWR_CHG_BAT_SDA: length 3.4
  TOP w0.14: PU4404.8 v2(124.7,156.17) 123.96,156.17 PG4408.1
PWR_CHG_BTST: length 2.9
  TOP w0.305: PU4404.17 131.09,155.67 131.68,155.08
  TOP w0.508: PR4409.1 132.19,154.57 v2(131.93,154.82) 131.68,155.08
PWR_CHG_BTST_R: length 5.3
  TOP w0.254: PC4411.1 134.89,156.16 135.09,155.96 v2(135.09,155.65) 134.37,154.94 PR4409.2 134.5,154.44 v1(135.15,154.44)
  BOTTOM w0.254: v1(135.15,154.44) 135.15,153.85 134.35,153.05 PD4401.K
PWR_CHG_CMPIN: length 7.3
  TOP w0.254: PR4429.1 PR4427.2 PR4411.2 126.73,160.7 PR4414.2 127.74,159.69 v1(127.74,159.27) 127.74,158.99 128.29,158.45 PU4404.4
  BOTTOM w0.254: v1(127.74,159.27) 127.87,159.27 v2(128.3,158.84) 128.3,158.46 128.12,158.28 PR4413.1
PWR_CHG_CMPIN_R: length 7.4
  TOP w0.254: v1(127.95,162.82) 127.95,162.7 128.51,162.14 PR4429.2
  BOTTOM w0.254: v1(127.95,162.82) 127.95,163.81 v2(127.96,163.83) 127.57,164.22 125.37,164.22 124.78,163.63 124.22,163.63 123.63,163.04 PQ4407.3
PWR_CHG_CMPIN_RR: length 3.9
  TOP w0.254: PR4427.1 127.31,162.28 v1(127.31,162.85)
  BOTTOM w0.254: PQ4407.6 126.81,161.74 v2(127.05,161.98) 127.31,162.24 v1(127.31,162.85)
PWR_CHG_CMPOUT: length 7.1
  TOP w0.254: v2(132.09,161.15) 132.02,161.09 PR4437.1 PR4430.2 PR4438.1 129.08,160.77 PR4432.1 PR4414.1 128.38,159.94 128.38,158.99 128.79,158.58 PU4404.3
PWR_CHG_CSON_1: length 51.5
  TOP w0.254: PR4420.2 127.62,151.01 v1(127.49,150.89) ; v2(159.87,164.09) 160.38,163.59 v1(160.51,163.59)
  L4 w0.254: v1(127.49,150.89) 128.12,150.25 142.58,150.25 143.21,150.89 153.4,150.89 154.92,152.41 161.02,152.41 162.03,153.43 162.03,162.73 161.3,163.46 160.64,163.46 v1(160.51,163.59)
  BOTTOM w0.254: v1(127.49,150.89) 127.55,150.95 PC4421.2 127.55,152.41 PC4423.1 ; v1(160.51,163.59) 160.13,163.97 PG4410.1
PWR_CHG_CSOP_1: length 49.2
  TOP w0.254: PR4421.2 128.51,150.96 v1(128.44,150.89) ; v1(160.51,162.95) 160,162.95 v2(159.75,162.7)
  L4 w0.254: v1(160.51,162.95) 160.64,163.08 161.14,163.08 161.65,162.57 161.65,153.58 160.86,152.79 154.76,152.79 153.24,151.27 143.05,151.27 142.42,150.63 128.69,150.63 v1(128.44,150.89)
  BOTTOM w0.254: PG4409.1 160,162.44 v1(160.51,162.95) ; v1(128.44,150.89) 128.44,150.89 PC4421.1 128.51,151.71 PC4420.1
PWR_CHG_HIDRV: length 24.9
  TOP w0.305: PU4404.18 131.83,156.17 v3(132.06,155.94)
  TOP w0.508: v2(151.27,157.56) v3(150.53,157.56)
  TOP w0.762: PC4413.2 v3(132.06,155.94)
  L4 w1.016: v3(150.53,157.56) 149.14,157.56 147.56,159.14 137.16,159.14 133.96,155.94 v3(132.06,155.94)
  BOTTOM w0.406: v3(150.53,157.56) PU4405.4
PWR_CHG_IFAULT: length 3.4
  TOP w0.254: PU4404.11 127.79,153.8 126.74,152.75 126.66,152.75 v2(126.63,152.72) 126.59,152.75 PR4418.2
PWR_CHG_ILIM: length 4.3
  TOP w0.254: PR4423.1 PR4417.2 124.81,153.6 125.66,153.6 v2(125.71,153.65) 126.4,153.65 126.98,154.24 PU4404.10
PWR_CHG_IOUT: length 13.3
  TOP w0.254: v1(126.52,162.82) 126.73,162.62 PR4411.1 ; PR4422.1 125.08,157.44 125.23,157.29 v1(125.25,157.29) 125.25,157.26 125.85,156.67 PU4404.7
  L4 w0.254: v1(125.25,157.29) 124.87,157.67 124.87,161.17 v1(126.52,162.82)
  BOTTOM w0.254: PR4424.1 PC4422.1 125.71,156.17 v2(125.53,156.35) 125.25,156.63 v1(125.25,157.29)
PWR_CHG_LODRV: length 17.3
  L4 w1.016: v3(130.49,153.2) 131.02,152.66 139.81,152.66 142.86,155.71 v3(146.29,155.71)
  vias: v2(131,152.74)
PWR_CHG_PHASE: length 24.8
  TOP w0.305: PU4404.19 131.17,156.67 v3(131.77,157.26)
  TOP w0.508: v3(131.77,157.26) PC4413.1 133.5,157.26 133.71,157.05 PC4411.2
  L4 w1.016: v3(150.6,158.89) 149.61,158.89 148.08,160.41 136.63,160.41 133.48,157.26 v3(131.77,157.26)
  vias: v2(151.87,152.56)
PWR_CHG_REGN: length 28.8
  TOP w0.254: v2(125.36,166.18) 125.36,165.39 v1(125.33,165.36) 125.33,164.53 124.62,163.82 PR4425.1 ; PU4404.16 v1(130.59,154.52) ; v1(131.21,162.86) PR4428.1 PR4430.1
  L4 w0.254: v1(131.21,162.86) 130.58,162.86 128.38,160.67 128.38,158.63 130.16,156.86 130.16,154.82 130.46,154.52 v1(130.59,154.52)
  BOTTOM w0.254: 131.93,153.05 131.93,154.54 PC4407.1 131.22,154.7 131.05,154.52 v1(130.59,154.52) ; v1(125.33,165.36) 125.33,165.57 125.76,166 130.11,166 131.43,164.69 131.43,163.08 v1(131.21,162.86)
PWR_CHG_SRN: length 3.6
  TOP w0.254: v2(126.7,151.47) 127.08,151.85 127.08,151.94 PR4420.1 128.34,153.2 128.34,153.48 128.29,153.54 PU4404.12
PWR_CHG_SRP: length 3.2
  TOP w0.254: v2(129.52,152.03) 128.94,152.03 128.51,152.46 PR4421.1 128.73,152.69 128.73,153.48 128.79,153.54 PU4404.13
PWR_CHG_VCC: length 5.9
  TOP w0.254: PU4404.20 130.59,157.31 131.63,158.35 PC4010.1 132.9,158.43 PR4408.2 v2(135.88,158.43)
PWR_COMP_R: length 1.8
  TOP w0.254: PC4626.2 127.55,141.06 PR4647.2 128.47,141.04 v2(128.48,141.06)
PWR_CPU_COMP: length 4.2
  TOP w0.203: PU4601.48 123.41,140.54
  TOP w0.254: 123.41,140.54 123.79,140.54 v2(123.83,140.5) 124.04,140.5 124.3,140.23 PC4627.2 125,140.23 PC4626.1
PWR_CPU_COMPNB: length 4.7
  TOP w0.203: PU4601.18 115.88,140.54 115.8,140.45 115.4,140.45 114.92,140.93 v1(114.92,140.98)
  BOTTOM w0.254: v1(114.92,140.98) 114.92,140.29 v2(114.64,140.01) 114.32,139.69 PC4612.2 113.49,139.85 PC4611.1
PWR_CPU_CSCOMP: length 61.4
  TOP w0.203: PU4601.45 123.05,139.34 123.15,139.24 123.18,139.24 v1(123.6,138.82)
  TOP w0.254: v1(123.6,138.82) 123.91,138.82 124.53,139.44 PC4618.1 PC4615.1 126.37,139.44 PR4642.1 126.41,139.57 126.83,139.99 127.62,139.99 128.02,139.58 v1(128.02,139.41) ; v2(114.89,111.34) 114.89,111.92 v1(114.94,111.97)
  L4 w0.254: v1(128.02,139.41) 128.02,139.37 136.38,131.01 136.38,117.72 131.83,113.17 117.59,113.17 116.5,112.08 115.04,112.08 v1(114.94,111.97)
  BOTTOM w0.254: v1(114.94,111.97) 115.21,111.71 PR4678.1 ; PR4641.2 PC4603.2 124.43,138.99 124.26,138.82 v1(123.6,138.82) 123.38,139.05 123.38,139.06 123.04,139.39 PR4640.2
PWR_CPU_CSCOMPNB: length 58
  TOP w0.203: PU4601.21 115.18,139.34
  TOP w0.254: v1(110.8,138.47) v2(111.51,138.47) 112.47,138.47 PR4626.2 112.76,138.89 PR4627.2 PC4624.2 114.07,139.67 114.29,139.46 114.8,139.46 114.92,139.34 115.18,139.34
  L4 w0.254: v1(110.8,138.47) 110.65,138.62 109.17,138.62 102.13,131.58 102.13,116.52 105.73,112.91 108.05,112.91 110.4,110.56 113.32,110.56 113.96,109.92 117.1,109.92 118.05,110.87 v1(118.13,110.87)
  BOTTOM w0.254: v1(110.8,138.47) 111.44,138.47 111.67,138.24 112.92,138.24 113.05,138.11 113.05,138.02 113.18,137.89 PR4629.1 113.38,137.86 PC4613.1 113.34,137.06 PC4617.1 ; PR4677.1 v1(118.13,110.87)
PWR_CPU_CSP1: length 9.3
  TOP w0.203: PU4601.40 122.42,137.34 122.71,137.04 v1(122.71,136.92)
  TOP w0.254: v2(127.03,135.27) 126.47,135.27 v1(126.45,135.29) 125.74,136 PC4628.2
  L4 w0.254: v1(122.71,136.92) 122.96,136.92 122.99,136.94 124.8,136.94 v1(126.45,135.29)
  BOTTOM w0.254: PR4637.1 124.29,136.46 123.78,136.97 122.77,136.97 v1(122.71,136.92)
PWR_CPU_CSP1NB: length 3.4
  TOP w0.203: PU4601.26 115.89,137.34 115.3,136.74 v2(115.2,136.74)
  TOP w0.254: PR4631.1 113.49,136.09 PC4623.1 114.55,136.09 v2(115.2,136.74)
PWR_CPU_CSP2: length 4.9
  TOP w0.203: v1(123.2,136.43) 123.2,137.2 122.82,137.58 122.61,137.58 122.55,137.64 122.53,137.64 122.43,137.74 PU4601.41
  BOTTOM w0.254: v2(124.76,134.68) PR4661.1 124.19,135.6 123.96,135.82 123.81,135.82 v1(123.2,136.43)
PWR_CPU_CSP2NB: length 4
  TOP w0.203: PU4601.25 115.86,137.74 115.55,137.42 115.2,137.42 v1(115.17,137.4)
  TOP w0.254: PR4660.1 114.68,135.28 v1(114.97,135.57)
  BOTTOM w0.254: v1(115.17,137.4) 115.17,137.4 v2(115.17,136.74) 114.97,136.54 v1(114.97,135.57)
PWR_CPU_CSREF: length 4.6
  TOP w0.203: v2(123.73,137.55) 123.35,137.55 122.84,138.06 122.54,138.06 122.47,138.14 PU4601.42
  TOP w0.254: v2(123.73,137.55) 124.09,137.55 124.24,137.7 PC4606.1 PR4639.1 PC4628.1
PWR_CPU_CSREFNB: length 5.1
  TOP w0.203: 115.15,137.91 115.17,137.93 115.55,137.93 115.58,137.96 115.63,137.96 115.8,138.14 PU4601.24
  TOP w0.254: 115.15,137.91 114.4,137.91 PC4622.1 114.27,136.99 PC4623.2 113.52,136.98 PR4632.1 112.54,136 v2(112.5,136)
PWR_CPU_CSSUM: length 6.7
  TOP w0.203: PU4601.43 122.5,138.54 122.67,138.36 123.17,138.36 123.35,138.19 123.66,138.19 v1(123.7,138.14)
  TOP w0.254: PR4643.2 126.4,138.56 PC4615.2 PC4618.2 124.36,138.56 124.12,138.31 123.87,138.31 v1(123.7,138.14)
  BOTTOM w0.254: PR4644.1 124.32,137.53 v1(123.7,138.14) 123.41,138.14 123.2,137.93 v2(123.2,137.58)
PWR_CPU_CSSUMNB: length 6
  TOP w0.203: v1(115.42,138.44) 115.68,138.44 115.77,138.54 PU4601.23
  BOTTOM w0.254: PC4617.2 113.35,136.17 113.37,136.15 113.62,136.15 114.27,136.8 PC4613.2 114.26,137.11 PR4630.2 114.88,137.89 v1(115.42,138.44) v2(115.42,139.08)
PWR_CPU_DIFF: length 3.7
  TOP w0.203: PU4601.50 122.92,141.34 123.17,141.59
  TOP w0.254: 123.17,141.59 123.19,141.61 v2(123.19,141.61) 124.33,141.61 124.64,141.92 PR4649.1 124.76,142.71 PR4650.1
PWR_CPU_DIFFNB: length 7
  TOP w0.203: v1(114.84,141.62) 115.17,141.62 115.37,141.42 115.8,141.42 115.88,141.34 PU4601.16
  BOTTOM w0.254: v2(111.54,144.26) 112,144.26 112.36,143.89 PR4622.1 PR4623.1 113.57,143.86 114,143.86 115.09,142.77 115.09,141.87 v1(114.84,141.62)
PWR_CPU_DROOP: length 4.8
  TOP w0.203: 123.5,139.46 123.41,139.55 123.28,139.55 123.09,139.74 PU4601.46
  TOP w0.254: v1(123.73,139.44) 123.72,139.44 123.71,139.46 123.5,139.46
  BOTTOM w0.254: v1(123.73,139.44) 124.17,139.88 PC4603.1 PR4641.1 125.88,139.58 v2(126.5,139.58)
PWR_CPU_DROOPNB: length 3.9
  TOP w0.203: PU4601.20 115.39,139.74
  TOP w0.254: PR4627.1 PC4624.1 113.9,140.56 114.5,139.96 v2(114.71,139.96) 114.92,139.96 115.11,139.77 115.11,139.77 115.15,139.74 115.39,139.74
PWR_CPU_EN: length 4
  TOP w0.102: PR4609.2 119.74,145.15 v2(118.84,144.24) 118.05,144.24 117.89,144.08 117.89,143.61 117.94,143.56 117.94,143.52 118.38,143.08 PU4601.9
PWR_CPU_FB: length 7.5
  TOP w0.203: PU4601.49 123.04,140.94 123.11,141.01
  TOP w0.254: 123.11,141.01 124.63,141.01 PC4627.1 125.01,141.39 125.12,141.39 PR4649.2 126.66,141.92 PC4648.2 127.52,141.88 PR4647.1 128.42,142.78 v2(128.84,142.78)
PWR_CPU_FBNB: length 11.3
  TOP w0.203: PU4601.17 v1(115.6,140.94)
  L3 w0.254: v1(115.6,140.94) 113.95,139.29 v1(112.1,139.29)
  BOTTOM w0.254: v1(112.1,139.29) 112.14,139.29 112.53,139.69 PC4612.1 112.77,140.37 PR4624.1 111.86,140.49 111.36,140.98 111.36,141.97 v2(111.49,142.1) 111.59,142.2 PC4610.2 112.72,142.99 PR4622.2
PWR_CPU_ILIM: length 2.7
  TOP w0.203: v1(122.87,138.85) 122.78,138.94 PU4601.44
  BOTTOM w0.254: v1(122.87,138.85) 122.53,138.5 PR4640.1 121.95,138.3 v2(121.95,137.58)
PWR_CPU_ILIMNB: length 2.7
  TOP w0.203: PU4601.22 115.01,138.94 114.75,138.68 v2(114.66,138.68) 113.85,138.68 PR4626.1
PWR_CPU_IOUT: length 4.7
  TOP w0.203: PU4601.47 123.37,140.14 v1(123.48,140.03)
  BOTTOM w0.254: v1(123.48,140.03) 124.15,140.7 PR4646.1 PC4609.1 v2(124.76,142.43)
PWR_CPU_IOUTNB: length 4.4
  TOP w0.203: PU4601.19 115.77,140.14 115.76,140.12 115.68,140.12
  TOP w0.254: 115.68,140.12 115.26,140.12 114.91,140.47 114.71,140.47 114.38,140.8 v2(114.38,141.26) 114.28,141.36 PR4625.1 PC4616.2
PWR_CPU_PHCONFIG: length 5.3
  TOP w0.203: v1(123.66,134.68) 123.66,135.28 v2(123.39,135.56) 122.64,136.31 121.42,136.31 121.18,136.54 PU4601.38
  BOTTOM w0.254: v1(123.66,134.68) 123.66,134.6 122.97,133.91 PR4635.1
PWR_CPU_ROSC: length 3.2
  TOP w0.203: PU4601.11 117.58,142.99 116.87,143.7
  TOP w0.254: PR4611.2 116.57,144.92 116.27,144.62 v2(116.27,144.2) 116.77,143.7 116.87,143.7
PWR_CPU_SR: length 5.2
  TOP w0.203: v1(122.08,136.84) 122.06,136.83 PU4601.39
  BOTTOM w0.254: PR4636.1 123.83,133.92 124.17,134.26 124.17,134.89 123.75,135.32 123.6,135.32 122.86,136.05 v2(122.36,136.05) 122.08,136.33 v1(122.08,136.84)
PWR_CPU_TEENSE: length 67.3
  TOP w0.203: PU4601.1 121.65,142.65 122.13,143.12 122.13,143.93 121.65,144.41 PR4606.2
  TOP w0.254: v2(114.99,109.23) 114.99,108.55 v1(114.97,108.52) ; PR4606.2 PC4607.2 122.85,144.6 123.15,144.89 123.51,144.89 v1(123.74,145.12)
  L4 w0.254: v1(114.97,108.52) 113.92,108.52 112.9,109.54 109.98,109.54 107.63,111.9 105.31,111.9 101.11,116.09 101.11,132 112.76,143.65 112.93,143.65 114.28,145 123.6,145 123.72,145.12 v1(123.74,145.12)
  BOTTOM w0.254: PR4605.2 115.3,108.85 v1(114.97,108.52)
PWR_CPU_TSENSENB: length 79.6
  TOP w0.203: PU4601.14 116.07,142.14 115.25,142.96
  TOP w0.254: 115.25,142.96 114.74,142.96 114.56,143.14 v2(114.53,143.14) 114.23,143.44 114.23,144.08 113.67,144.64 PC4619.2 PR4619.2 113.58,145.63 113.02,146.19 111.61,146.19 111.23,145.81 111.23,144.41 110.98,144.16 v1(110.98,143.65)
  L4 w0.254: v1(110.98,143.65) 111.49,144.16 112.72,144.16 115.06,146.49 123.48,146.49 127.36,142.61 127.36,141.17 136.91,131.62 136.91,117.54 131.27,111.9 125.84,111.9 123.45,109.51 120.53,109.51 v1(119.87,108.85)
  BOTTOM w0.254: PR4618.2 v1(119.87,108.85)
PWR_CPU_VCC: length 3.7
  TOP w0.203: PU4601.10 117.98,143.1 117.48,143.61 117.48,143.77 117.46,143.8
  TOP w0.254: PC4602.1 118.3,145.27 117.88,144.85 PR4610.1 v2(117.46,143.9) 117.46,143.8
PWR_CPU_VDD: length 4.3
  TOP w0.203: PU4601.51 122.38,141.74 123.27,142.63 123.69,142.63 v2(123.75,142.7) 123.75,142.7 123.82,142.77
  TOP w0.254: PR4601.2 125.56,143.53 PC4601.1 124.58,143.53 123.82,142.77
PWR_CPU_VDDNB: length 4
  TOP w0.203: PU4601.15 115.94,141.74 115.58,142.1
  TOP w0.254: 115.58,142.1 115.3,142.1 115.26,142.14 v2(115.23,142.14) 115.23,142.16 114.92,142.48 114.21,142.48 113.68,143.01 PR4621.2 113.58,143.04 PC4605.1
PWR_CPU_VRMP: length 5.4
  TOP w0.203: 116.47,143.27 116.88,143.27 117.18,142.96 PU4601.12
  TOP w0.254: v2(115.09,146.87) 115.25,146.87 115.72,146.4 PR4612.2 PC4614.2 115.72,144.02 116.47,143.27
PWR_CPU_VSS: length 4.6
  TOP w0.203: PU4601.52 122.1,142.39 122.31,142.61 122.56,142.61
  TOP w0.254: 122.56,142.61 v2(123.88,143.93) 124.21,143.93 124.71,144.42 PC4601.2 124.81,144.41 PR4603.2
PWR_DCBATOUT_0D95V:
  vias: v2(147.58,107.43) v3(150.78,106.46) v3(150.78,105.55) v3(150.78,104.68) v3(150.78,103.77)
PWR_DCBATOUT_3D3V:
  vias: v2(31.22,49.26) v2(31.99,47.46) v3(30.33,49.79) v3(30.33,48.4) v3(30.33,47)
PWR_DCBATOUT_5V:
  vias: v2(46.92,51.83) v2(48.14,47.59) v3(47,48.88) v3(47,47.1)
PWR_DIFF_R: length 2.1
  TOP w0.254: PR4650.2 126.66,142.73 PC4648.1 127.38,142.77 v2(127.62,143.01)
PWR_VDDNB_BST2: length 5.9
  TOP w0.203: PU4601.37 120.78,136.49 121.27,136 122.23,136 122.94,135.29 122.94,135.2 123.03,135.12 v1(123.03,135.02) 123.03,134.87 v2(122.66,134.5)
  BOTTOM w0.508: v1(123.03,135.02) 123.03,134.87 121.93,133.77 PR4702.1
PWR_VDDNB_BST2_1: length 2.4
  BOTTOM w0.508: PR4702.2 PC4734.1 v2(119.29,132.45)
PWR_VDDNB_CSN1NB: length 50.8
  TOP w0.254: PR4632.2 111.84,136.92 111.61,137.15 v2(111.61,137.17) 111.59,137.17 111.46,137.3 v1(110.85,137.3)
  L4 w0.254: v1(110.85,137.3) 110.78,137.22 109.17,137.22 102.98,131.03 102.98,116.85 106.15,113.68 108.77,113.68 111.05,111.39 113.69,111.39 114.48,110.6 116.75,110.6 117.74,111.59 v1(120.48,111.59)
  BOTTOM w0.254: v1(120.48,111.59) 120.5,111.62 121.09,111.62 122.08,112.61 123.02,112.61 PG4719.1
PWR_VDDNB_HG2: length 25.3
  TOP w0.203: v3(122.23,135.13) 122.22,135.13 121.67,135.67 121.04,135.67 120.38,136.33 PU4601.36
  TOP w0.305: v2(128.84,118.22) v3(128.84,117.54)
  L4 w0.762: v3(128.84,117.54) 127.11,119.26 127.11,129.34 122.27,134.18 122.27,135.09 v3(122.23,135.13)
  BOTTOM w0.762: PU4707.4 v3(128.84,117.54)
PWR_VDDNB_LG2: length 19.1
  TOP w0.203: PU4601.34 119.58,136.52 119.68,136.42 119.68,135.94 120.12,135.49 v3(120.12,134.88)
  TOP w0.762: PU4706.4 v3(120.25,125.87)
  L4 w0.762: 122.16,125.87 122.16,129.93 120,132.09 120,134.76 v3(120.12,134.88) ; 122.16,125.87 v3(120.25,125.87) ; 122.16,125.87 v3(124.06,125.87)
  BOTTOM w0.305: v2(120.12,135.55) v3(120.12,134.88)
  BOTTOM w0.762: PU4708.4 v3(124.06,125.87)
PWR_VDDNB_PGOOD: length 6.4
  TOP w0.127: v1(118.33,143.74) 118.33,143.71 118.57,143.47 118.57,143.22 118.78,143.01 PU4601.8
  BOTTOM w0.127: v1(118.33,143.74) 117.7,143.74 v2(117.69,143.72) 115.55,145.86 PR4614.2 PR4617.1
PWR_VDDNB_SNUB: length 3
  BOTTOM w0.508: PR4710.2 126.42,121.4 v2(126.42,122.82) 126.42,124.23 PC4743.1
PWR_VDDNB_SW2: length 23.8
  TOP w0.203: PU4601.35 119.98,136.22 120.94,135.27 121.04,135.27 v3(121.22,135.09)
  L4 w0.762: v3(126.5,117.41) 126.5,117.56 126.09,117.97 126.09,128.92 121.19,133.82 121.19,135.06 v3(121.22,135.09)
  BOTTOM w0.508: v3(121.22,135.09) 121.22,134.94 120.43,134.15 PC4734.2
  vias: v2(123.04,114.82) v3(120.1,117.71) v3(120.1,116.75) v3(121.24,116.8) v3(121.27,117.74) v3(122.28,117.74) v3(123.43,117.74) v3(124.57,117.74) v3(125.81,116.75)
PWR_VDDNB_SWN1NB: length 55
  TOP w0.254: v1(110.85,136.66) 111.01,136.66 111.69,135.98 111.69,135.47 v2(112.5,134.66) 113.14,134.66 113.44,134.96 PR4631.2
  L4 w0.254: v1(120.48,112.28) 120.3,112.1 117.53,112.1 116.54,111.11 114.69,111.11 113.9,111.9 111.26,111.9 108.98,114.18 106.36,114.18 103.49,117.06 103.49,130.82 109.38,136.71 110.8,136.71 v1(110.85,136.66)
  BOTTOM w0.254: PR4633.2 112.79,134.83 110.96,136.66 v1(110.85,136.66) ; v1(120.48,112.28) 120.89,112.28 121.72,113.12 123.35,113.12 123.55,113.32 PG4720.1
PWR_VDDQ_SENSE_APU: length 113.4
  TOP w0.203: PU4901.9 58.76,45.84 v1(58.48,45.55)
  TOP w0.254: v1(81.68,71.71) 82.5,72.53 83.18,72.53 86.32,75.67 86.32,78.8 86.65,79.13 86.65,79.89 87.13,80.38 88.15,80.38 89.14,81.36 89.14,81.84 90.24,82.94 92.27,82.94 93.72,81.49 99.25,81.49 100.95,83.2 103.41,83.2 104.27,82.33 R417.1 ; PG4907.1 v1(59.29,19.19)
  L4 w0.254: v1(58.48,45.55) 58.48,46.38 58.27,46.59 58.27,50.13 62.51,54.37 73.47,54.37 74.23,55.13 74.23,58.41 79.1,63.28 79.1,66.53 78.32,67.31 78.32,68.34 v1(81.68,71.71)
  BOTTOM w0.254: v1(59.29,19.19) 59.04,19.44 54.34,19.44 v2(53.97,19.81) 53.45,20.33 53.45,40.9 56.62,44.08 56.62,44.71 57.49,45.58 58.1,45.58 58.13,45.55 v1(58.48,45.55)
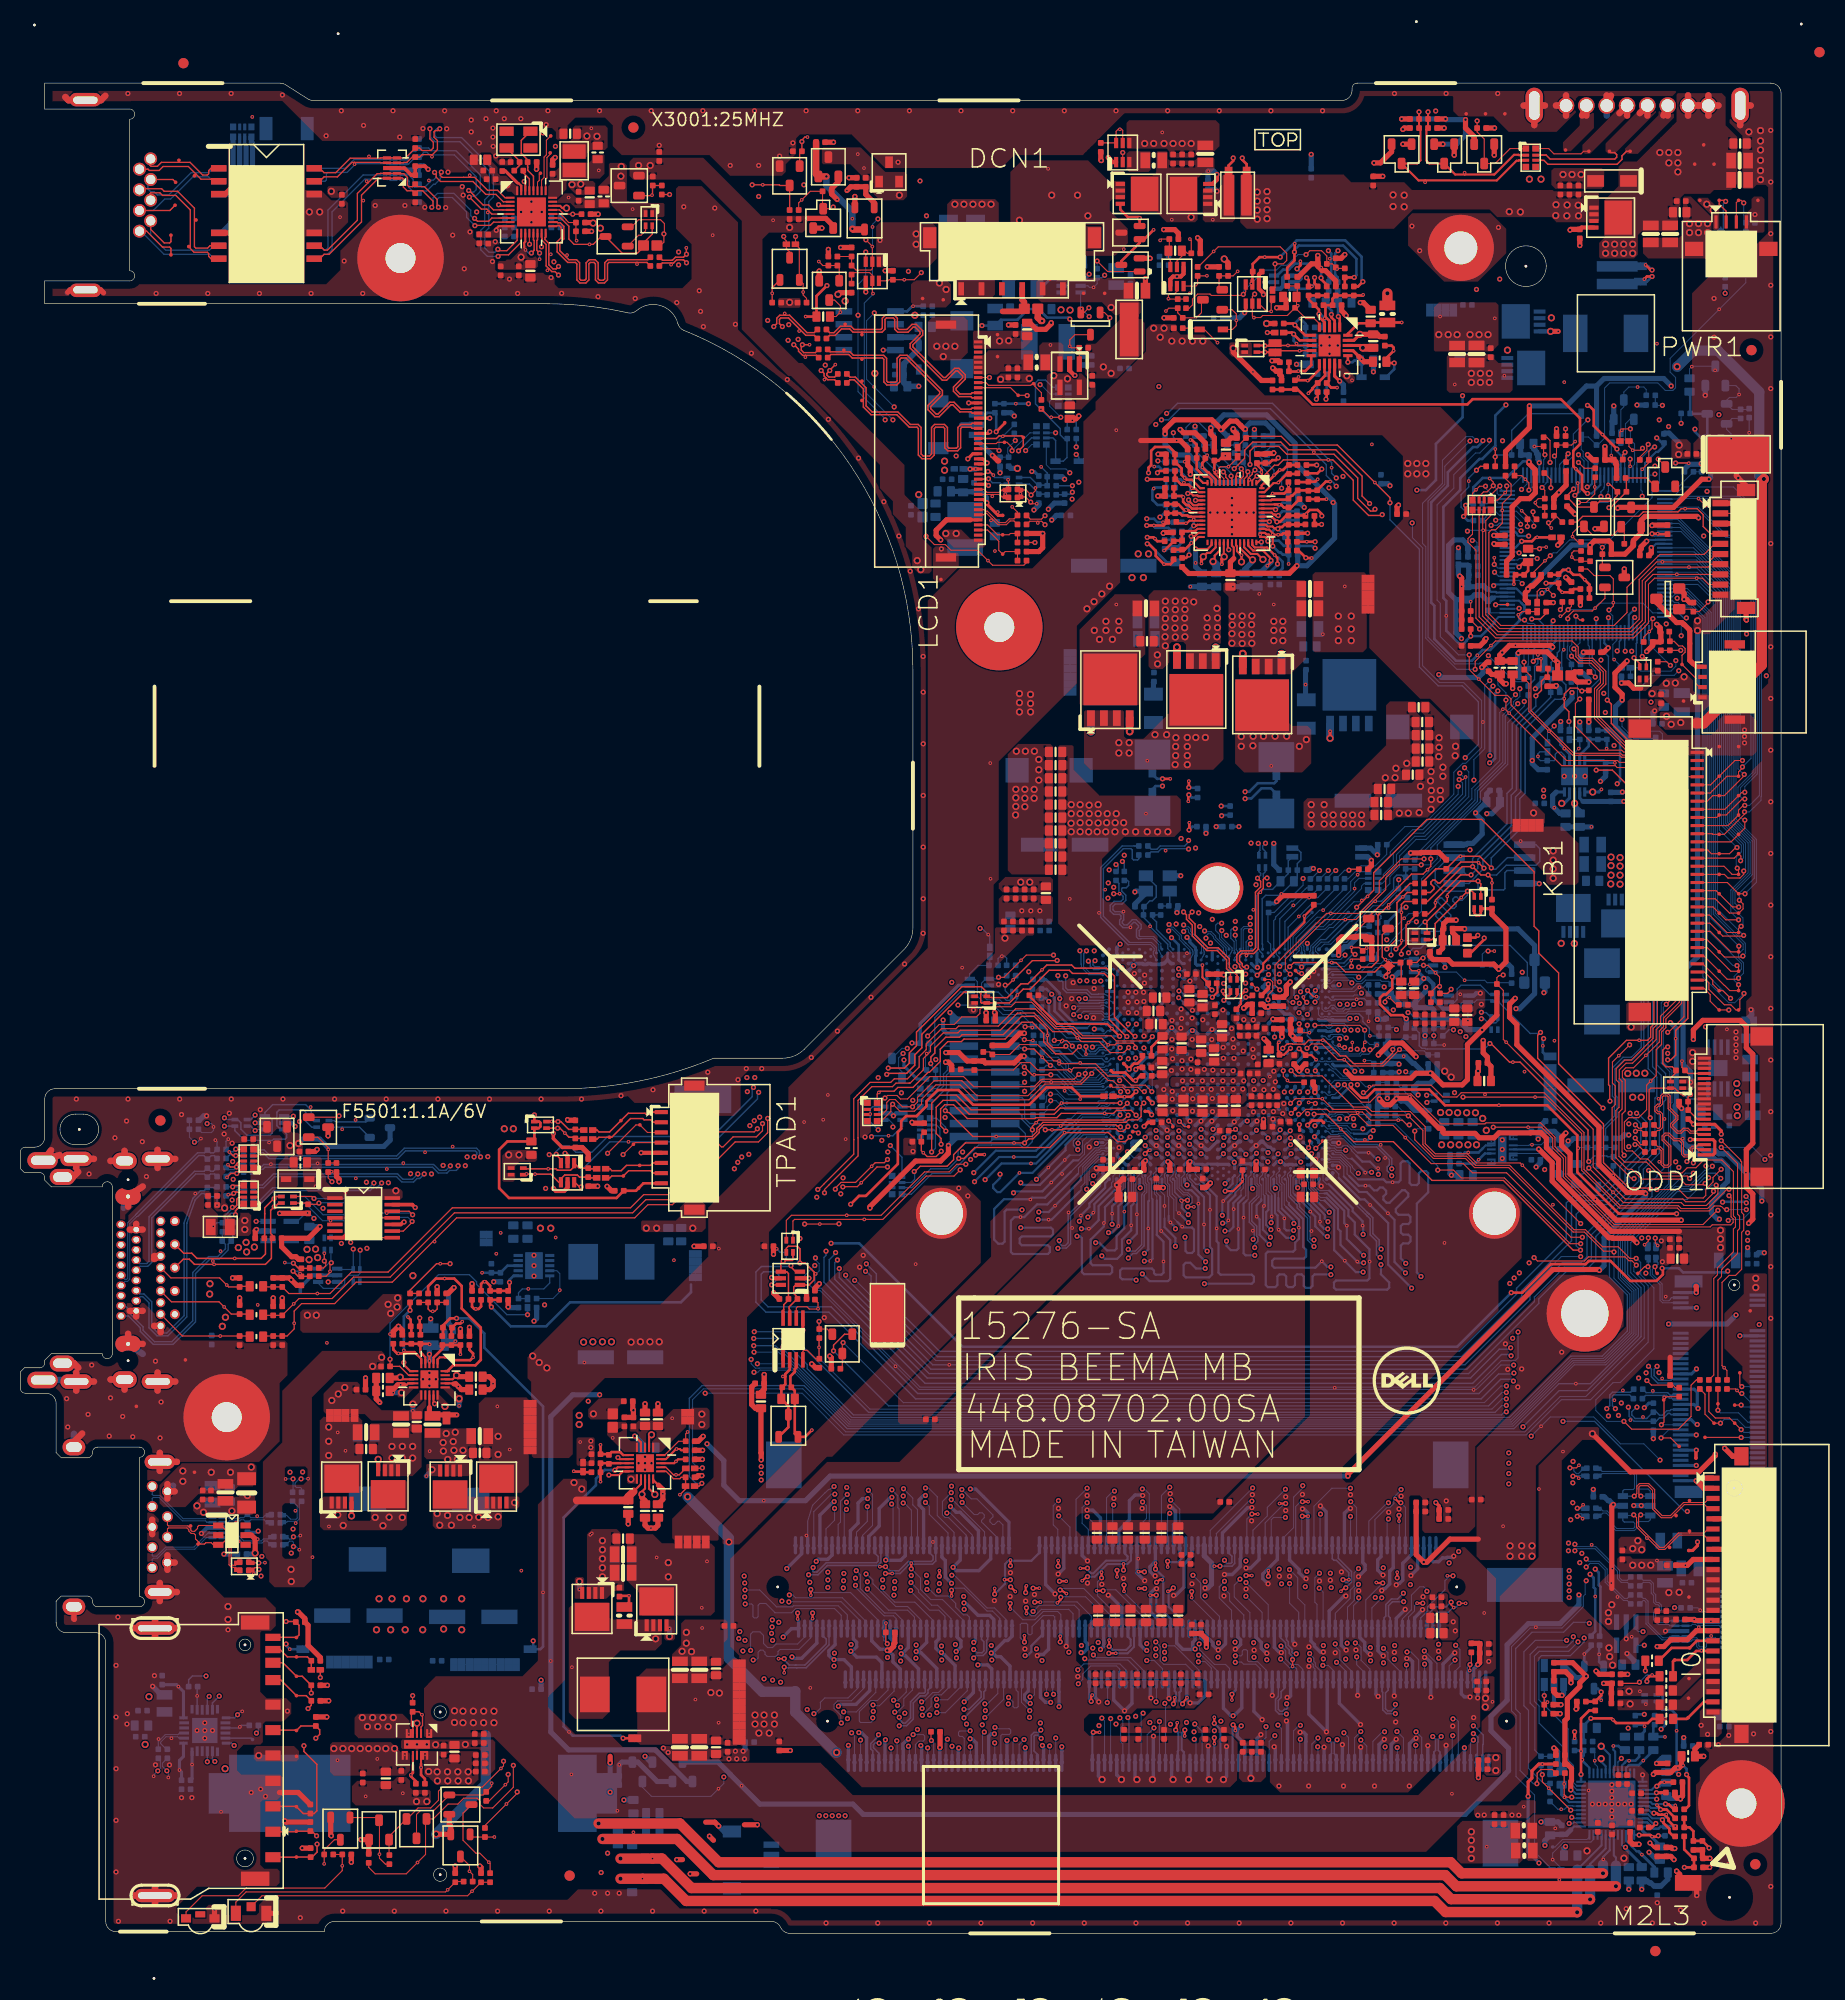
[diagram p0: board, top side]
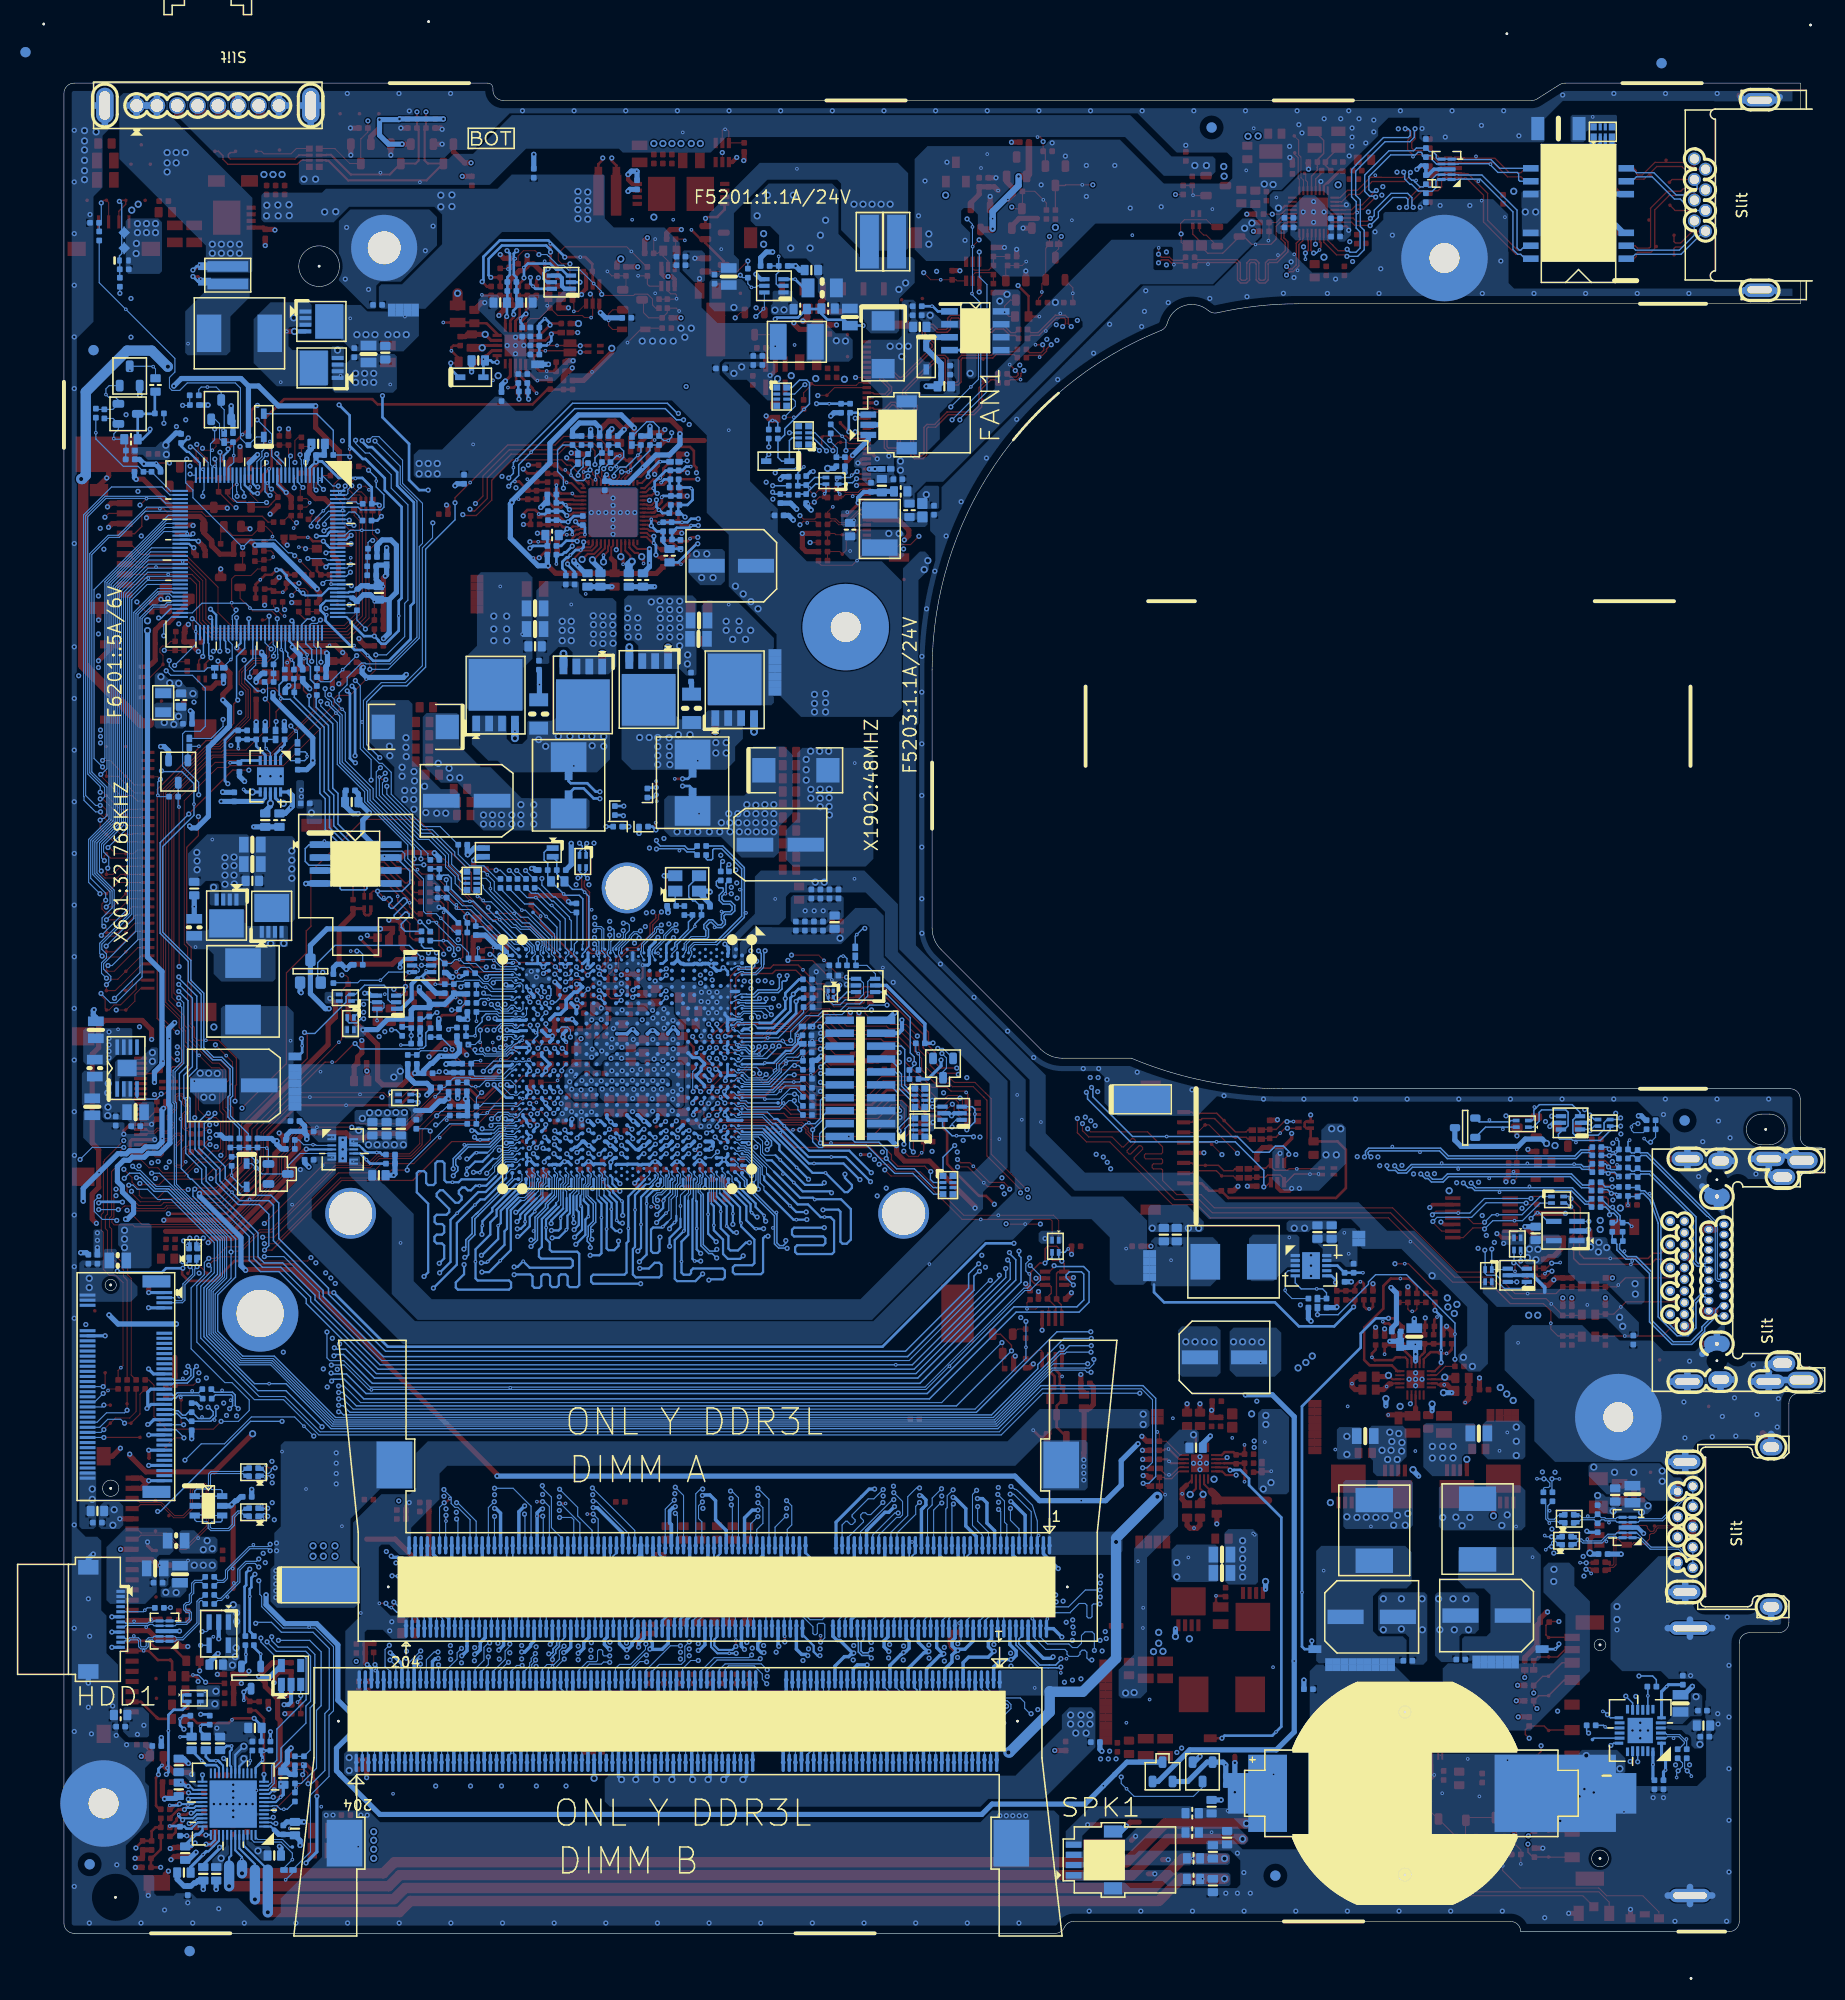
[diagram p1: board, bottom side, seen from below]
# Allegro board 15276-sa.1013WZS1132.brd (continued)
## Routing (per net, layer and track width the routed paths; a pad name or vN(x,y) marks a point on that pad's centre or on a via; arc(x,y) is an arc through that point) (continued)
PWR_VR_HOT: length 4.3
  TOP w0.203: PU4601.13 116.35,142.65 v1(115.73,143.27)
  BOTTOM w0.254: PR4613.1 v2(114.54,144.74) 114.66,144.74 115.73,143.67 v1(115.73,143.27)
PWROK: length 4.4
  TOP w0.127: PU4601.2 121.18,142.9 121.61,143.32 v1(121.65,143.32)
  BOTTOM w0.127: v1(121.65,143.32) 122.08,142.89 122.79,142.89 v2(123.32,143.42) 123.32,143.91 PR4607.2
Q402_1: length 2.9
  TOP w0.102: Q3003.B 60.83,167.02 61.07,167.02 61.51,167.45 RN3001.3
Q603_2: length 10
  BOTTOM w0.102: R648.2 146.65,93.5 144.29,93.5 144.05,93.74 v2(142.07,93.74) 141.26,94.54 Q603.3 138.34,94.54 138.25,94.64 138.25,94.82 138.62,95.19 Q603.2
Q6205_Q: length 3.6
  BOTTOM w0.102: R6214.2 164.19,153.86 v2(164.42,154.09) 164.46,154.13 Q6205.D
R1930.R: length 2.3
  BOTTOM w0.14: X1902.1 113.07,101.14 C1905.2 112.96,101.04 R1930.1
REGOUT:
  vias: v2(56.9,173.39)
RING2: length 1.6
  BOTTOM w0.203: HDA27.17 155.95,16.44 155.51,16.88 v3(155.51,17.18)
  vias: v2(159.9,22.54) v3(158.35,22.57)
RREF: length 3.9
  BOTTOM w0.305: R3203.1 15.86,15.86 v2(15.65,16.06) 15.65,17 16.05,17.4 U3201.1
RSET: length 3
  TOP w0.203: 48.88,172.17 48.93,172.12 49.02,172.12 49.27,171.88 49.27,171.88 LOM30.31
  TOP w0.305: R3032.2 47.72,173.33 48.88,172.17
RSMRST#_KBC: length 72.3
  TOP w0.127: R628.2 140.39,92.44 140.75,92.8 v1(140.75,92.85) ; v1(152.92,141.43) 153.23,141.74 153.23,142.59 v2(153.19,142.63)
  L3 w0.127: v1(152.92,141.43) 152.33,140.84 152.33,139.33 151.04,138.03 149.94,138.03 148.23,139.75 144.46,139.75 143.09,138.38 143.09,138.02 142.5,137.42 141.97,137.42 139.06,134.51 139.06,123.57 147.04,115.59 147.04,98.14 143.61,94.71 143.34,94.71 141.48,92.85 v1(140.75,92.85)
  BOTTOM w0.127: v1(152.92,141.43) 152.93,141.44 153.07,141.44 153.42,141.79 KBC24.15
RTC_1D5V_PWR: length 17.9
  TOP w0.127: v1(137.98,95.92) 137.8,95.92 137.37,95.49 R701.1 136.66,94.9 136.89,94.68 v2(137.57,94.68) 137.57,94.35 137.11,93.88 C702.1
  BOTTOM w0.127: U701.2 148.24,93.81 148.24,95.46 146.54,97.17 139.23,97.17 v1(137.98,95.92)
RTC_1D5V_S5: length 18.3
  TOP w0.127: C701.1 135.84,95.42 R701.2 134.7,95.49 G701.1 ; Q701.D 134.54,98.78 133.97,98.21 133.97,96.02 G701.1 ; v1(124.87,95.07) 125.28,95.48 v2(128.99,95.48) 129.42,95.48 130.35,94.55 133.24,94.55 133.89,95.2 134.41,95.2 G701.1
  BOTTOM w0.127: CPU1.AN4 124.47,94.68 v1(124.87,95.07)
RTC_AUX_S5: length 295
  TOP w0.508: R2428.2 151.56,136.85 v1(151.24,136.54) ; C705.1 141.23,98.08 140.89,98.42 C2503.2 142.04,98.82 v1(142.07,98.79) ; v1(157.56,121.3) 157.56,121.86 156.87,122.56 156.87,123.95 v1(158.05,125.13)
  L3 w0.508: v1(160.84,108.9) 162.72,107.02 162.72,97.17 161.02,95.46 161.02,91.33 162.31,90.03 v1(162.31,89.57) 161.73,89.57 160.99,88.83 160.99,88.43 158.8,86.23 150.62,86.23 147.12,89.72 v1(147.12,90.94) ; v1(158.05,125.13) 158.36,124.82 159.68,124.82 160.45,125.58 160.45,125.58 163.12,128.26 163.76,128.26 164.85,127.16 170.07,127.16 170.44,127.54 170.44,131.9 169.74,132.6 156.06,132.6 152.13,136.54 v1(151.24,136.54) ; v1(167.14,70.24) 167.14,70.22 166.99,70.06 166.99,69.94 164.7,67.65 164.7,64.55 164.19,64.04 164.19,54.49 157.72,48.02 157.72,40.52 157.08,39.89 157.08,36.04 154.32,33.28 v1(153.32,33.28)
  BOTTOM w0.508: v1(160.84,108.9) 160.66,108.72 160.13,108.72 158.99,109.87 158.99,116.65 158.54,117.09 158.54,117.09 157.12,118.52 157.12,118.52 156.91,118.72 156.91,120.64 v1(157.56,121.3) ; v1(162.31,89.57) 162.9,88.99 162.9,81.53 162.77,81.4 162.77,77.72 163.77,76.72 164.91,76.72 165.3,76.34 166.49,76.34 166.79,76.03 167.31,76.03 167.94,75.41 167.94,73.95 167.44,73.45 167.44,72.91 166.35,71.82 166.35,70.84 166.95,70.24 v1(167.14,70.24) ; v1(153.32,33.28) 153.32,32.31 151.46,30.46 148.34,30.46 146.25,28.37 146.25,22.93 144.67,21.35 144.67,19.92 146.39,18.19 146.39,15.99 146.03,15.63 146.03,15.6 142.13,11.69 82.91,11.69 81.9,12.71 72.75,12.71 v2(70.95,14.51) 69.83,15.63 69.83,15.64 68.63,16.84 D2501.3 ; v1(147.12,90.94) 147.48,90.94 148.95,92.42 U701.3 148.95,97.17 147.33,98.79 v1(142.07,98.79)
RTC_CLK: length 17.9
  L3 w0.14: v1(139.04,88.29) 138.59,88.74 136.54,88.74 136.23,88.43 133.76,88.43 132.2,89.99 v1(131.44,89.99)
  L4 w0.14: v1(131.44,89.99) 131,90.43 127.16,90.43 127.11,90.38 v1(126.6,90.38)
  BOTTOM w0.14: R609.1 139.17,89.16 R1918.1 v1(139.04,88.29) 139.05,88.28 R1917.1 139.19,87.37 v2(140.06,87.37) ; CPU1.AV11 127,90.87 126.6,90.48 v1(126.6,90.38)
RTC_DET#: length 212.2
  TOP w0.102: v1(158.96,65.72) 158.53,66.15 158.23,66.15 157.85,66.53 154.26,66.53 153.86,66.13 149.23,66.13 v1(148.9,66.46) ; v1(127.34,89.31) 131.77,89.31 v1(132.24,88.83)
  L3 w0.102: v1(67.37,53.12) 67.8,52.69 67.8,52.69 68.94,51.55 68.94,30.36 69.7,29.6 69.7,18.57 69.2,18.06 v1(69.2,15.38)
  L4 w0.102: v1(148.9,66.46) 148.96,66.52 148.96,72.75 148.75,72.96 146.44,75.27 146.44,78.99 141.8,83.63 139.54,83.63 139.01,84.16 137.55,84.16 135.47,86.24 134.7,86.24 134.12,86.83 133.41,86.83 133.05,86.47 130.17,86.47 129.17,87.48 129.17,88.56 128.41,89.31 v1(127.34,89.31)
  BOTTOM w0.102: v1(69.2,15.38) 69.2,14.74 v2(68.67,14.22) 67.93,13.47 62.08,13.47 61.2,14.36 Q2505.D ; v1(67.37,53.12) 76.89,53.12 79.3,50.71 81,49.02 148.13,49.02 151.59,52.49 154.46,52.49 160.13,58.15 160.13,63.69 158.72,65.1 158.72,65.5 158.94,65.72 v1(158.96,65.72) ; CPU1.AV15 127.07,88.78 127.34,89.04 v1(127.34,89.31) ; v1(132.24,88.83) 132.24,87.92 132.75,87.41 R634.1
RTC_PWR: length 8.1
  BOTTOM w0.508: D2501.2 62.66,14.93 60.75,16.84 Q2505.G 59.18,16.84 v2(58.91,16.57) R2502.1 R2504.1
RTCRST_ON: length 53.9
  TOP w0.127: v1(138.74,105.68) 138.74,104.94 v2(138.42,104.62) 137.98,104.18 136.84,104.18 132.63,99.97 Q701.G 131.71,98.88 R702.1
  L4 w0.127: v1(147.3,120.94) 147.21,120.85 144.71,120.85 143.76,121.8 143.76,123.19 146.59,126.02 146.59,136.56 v1(144.68,138.48)
  BOTTOM w0.127: v1(144.68,138.48) 145.28,138.48 145.47,138.67 KBC24.120 ; v1(147.3,120.94) 146.07,119.71 146.07,115.1 143.33,112.36 143.33,111.34 138.74,106.76 v1(138.74,105.68)
RUNPWROK_D: length 2.9
  BOTTOM w0.127: D3606.A 155.68,73.42 156.7,74.43 v2(156.7,74.56) R3627.1
S0_PWR_GOOD_R: length 16.2
  TOP w0.127: v1(124.18,87.05) 124.6,87.46 124.73,87.46 124.76,87.49 125.13,87.49 125.17,87.45 126.35,87.45 126.74,87.84 v2(128.12,87.84) 128.29,87.84 129.83,86.3 130.38,86.3 131.13,85.55 133.94,85.55 134.98,86.59 134.98,86.9 v1(135.01,86.93)
  BOTTOM w0.127: CPU1.AM19 123.8,86.66 v1(124.18,87.05) ; R611.2 R627.1 136.12,88.14 135.01,87.03 v1(135.01,86.93)
S5_ENABLE: length 9.9
  TOP w0.127: v2(156.19,142.5) 156.37,142.5 R3603.2 157.1,141.43 156.52,140.85 155.37,140.85 Q2403.D 153.09,140.28 152.83,140.54 152.83,140.57 R2436.2 152.15,141.41 v1(152.79,142.05)
  BOTTOM w0.127: v1(152.79,142.05) 152.81,142.05 153.02,142.25 KBC24.14
SATA3_PRX_HDDTX_N0: length 77
  L4 w0.102: v1(152.92,37.63) 153.14,37.86 153.39,37.86 153.67,38.13 153.67,39.09 153.27,39.48 151.21,39.48 149.33,41.36 149.33,56.88 148.58,57.63 148.58,63.96 149.7,65.07 149.7,73.05 149.48,73.27 147.17,75.58 147.17,79.36 139.61,86.93 137.69,86.93 136.99,87.63 130.88,87.63 130.45,88.06 v1(130.42,88.06)
  BOTTOM w0.102: C5616.1 158.07,34.52 157.48,34.52 157.11,34.89 157.11,35.61 156.72,36 ; v2(156.6,35.88) 156.72,36 ; 156.72,36 154.89,37.83 153.12,37.83 v1(152.92,37.63) ; v1(130.42,88.06) 130.41,88.07 130.33,88.07 129.99,88.42 129.7,88.42 129.69,88.41 128.93,88.41 CPU1.BA16
SATA3_PRX_HDDTX_P0: length 77.1
  L4 w0.102: v1(129.78,87.99) 130.17,87.59 130.6,87.59 130.79,87.4 136.9,87.4 137.6,86.7 139.51,86.7 146.95,79.27 146.95,75.48 149.26,73.17 149.47,72.96 149.47,65.16 148.36,64.05 148.36,57.54 149.11,56.79 149.11,41.26 151.11,39.25 153.18,39.25 153.44,38.99 153.44,38.23 153.3,38.09 153.09,38.09 v1(152.91,38.27)
  BOTTOM w0.102: 154.57,38.03 153.15,38.03 v1(152.91,38.27) ; 154.57,38.03 v2(154.57,38.21) ; 154.57,38.03 154.97,38.03 157.31,35.7 157.31,34.97 157.56,34.72 158.07,34.72 C5615.1 ; CPU1.AY16 128.32,88.23 128.62,87.93 128.92,87.93 129.19,88.2 129.56,88.2 v1(129.78,87.99)
SATA3_PTX_HDDRX_N0: length 79.6
  L4 w0.102: v1(130.26,88.83) 130.93,88.16 137.29,88.16 137.99,87.46 139.79,87.46 147.71,79.55 147.71,75.81 150.21,73.31 150.21,64.83 149.09,63.71 149.09,57.84 149.84,57.09 149.84,41.67 151.49,40.02 153.46,40.02 154.6,38.88 154.6,36.77 154.39,36.56 154.29,36.56 v1(154.03,36.82)
  BOTTOM w0.102: v2(156.5,34.45) 156.38,34.34 ; 156.38,34.34 157.78,32.94 158.07,32.94 C5603.2 ; 156.38,34.34 156.1,34.62 156.1,35.82 155.33,36.59 154.26,36.59 v1(154.03,36.82) ; CPU1.AY14 128.32,89.33 128.62,89.03 128.87,89.03 129.12,89.27 130.14,89.27 130.26,89.16 v1(130.26,88.83)
SATA3_PTX_HDDRX_P0: length 79.5
  L4 w0.102: v1(130.89,88.83) 130.88,88.82 130.88,88.54 131.03,88.39 137.38,88.39 138.08,87.69 139.89,87.69 147.94,79.64 147.94,75.91 150.44,73.41 150.44,64.73 149.32,63.62 149.32,57.94 150.07,57.19 150.07,41.76 151.59,40.24 153.55,40.24 154.82,38.97 154.82,36.67 154.48,36.33 154.34,36.33 v1(154.03,36.03)
  BOTTOM w0.102: CPU1.BA14 128.89,89.33 129.03,89.48 130.23,89.48 130.87,88.83 v1(130.89,88.83) ; v1(154.03,36.03) 154.06,36.03 154.42,36.38 155.24,36.38 155.89,35.73 155.89,34.54 157.23,33.2 ; 157.23,33.2 157.7,32.74 158.07,32.74 C5602.2 ; 157.23,33.2 v2(157.11,33.08)
SATA_LED: length 3.4
  TOP w0.102: Q6106.C 30.89,9.21 29.89,8.2 R6108.1 v2(29.89,6.83)
SATA_LED#: length 278
  TOP w0.102: v1(47.53,16.93) 47.53,16.47 v2(47.28,16.22) 45.45,14.39 41.54,14.39 41.13,13.98 41.13,13.09 40.37,12.33 39.12,12.33 38.04,11.25 Q6107.S 36.27,9.54 Q6105.S 36.27,7.73 R6106.1 ; v1(156.76,67.02) 156.69,67.09 155.73,67.09 153.86,68.97 152.74,68.97 146.41,75.31 143.05,75.31 142.15,76.21 139,76.21 137.17,78.05 v1(137.17,78.9) ; R2450.1 148.39,122.93 148.39,120.18 152.71,115.86 157.32,115.86 157.5,115.68 158.52,115.68 162.38,111.82 162.38,92.48 v1(161.91,92.01)
  L4 w0.102: v1(47.53,16.93) 47.53,22.82 52.28,27.57 52.28,46.06 63.38,57.16 v1(72.17,57.16) ; v1(131.14,80.11) 131.37,79.88 131.37,79.88 131.69,79.56 132.24,79.56 132.29,79.51 135.62,79.51 136.23,78.9 v1(137.17,78.9)
  BOTTOM w0.102: CPU1.BA30 128.91,80.53 128.95,80.57 129.31,80.57 129.48,80.75 130.51,80.75 v1(131.14,80.11) ; R1931.2 137.4,79.13 v1(137.17,78.9) ; v1(161.91,92.01) 161.41,91.51 161.41,85.58 162.26,84.73 162.26,81.79 162.14,81.67 162.14,73.7 156.76,68.33 v1(156.76,67.02) 156.76,64.44 158.32,62.88 158.32,59.14 155.71,56.53 152.61,56.53 146.58,50.49 81.68,50.49 75.17,57 74.74,57 74.58,57.16 v1(72.17,57.16)
SATA_LED#_B: length 7.9
  TOP w0.102: R6106.2 35.91,6.81 35.33,7.39 v2(35.33,7.78) 35.33,11.08 Q6105.D 35.02,11.39 Q6106.B
SATA_LED#_R: length 252.6
  TOP w0.102: v1(161.91,91.37) 162.58,92.05 162.58,111.9 158.61,115.88 157.59,115.88 157.4,116.06 152.8,116.06 148.6,120.26 148.6,123.63 147.95,124.28 R2450.2 147.94,125 v1(147.91,125.03) ; v1(48.5,16.52) 48.5,14.36 46.46,12.33 45.57,12.33 45.19,12.71 45.19,13.04 44.94,13.3 43.62,13.3 43.03,12.71 42.07,12.71 40.61,11.25 Q6107.G 39.86,11.16 39.86,7.76 v2(39.07,6.97) 37.95,5.85 34.91,5.85 34.27,6.49 R6110.2
  L4 w0.102: v1(48.5,16.52) 48.5,23.21 52.69,27.4 52.69,45.89 62.63,55.84 72.32,55.84 v1(72.5,56.02)
  BOTTOM w0.102: v1(161.91,91.37) 161.61,91.08 161.61,85.7 162.47,84.85 162.47,81.71 162.34,81.58 162.34,73.62 157.2,68.47 157.2,64.44 158.52,63.12 158.52,59.05 155.79,56.32 152.69,56.32 146.66,50.29 81.6,50.29 75.87,56.02 v1(72.5,56.02) ; v1(147.91,125.03) 147.91,126.35 148.22,126.66 KBC24.95
SATA_LED_R: length 20.2
  TOP w0.102: R6108.2 EC6106.1 v2(31.67,6.64) 31.67,6.17 29.95,4.46 22.21,4.46 21.44,3.69 17.89,3.69 16.3,2.1 HDLED1.1A
SATA_ODD_DA#: length 53.3
  TOP w0.127: v1(162.05,87.18) 162.01,87.18 161.95,87.12 161.82,87.12 161.56,86.87 161.56,85.55 161.88,85.23 162.5,85.23 R5602.2 162.86,84.66 162.32,84.12 RN5601.3
  L3 w0.127: v1(142.2,88.2) 142.26,88.26 145.8,88.26 150.57,83.49 160.73,83.49 162.52,85.28 162.52,86.78 162.11,87.18 v1(162.05,87.18)
  L4 w0.127: v1(142.2,88.2) 142.09,88.3 142.09,89.95 140.32,91.73 135,91.73 133.61,90.33 132.41,90.33 131.61,89.53 129.74,89.53 129.12,90.16 127.21,90.16 127,89.94 125.76,89.94 125.06,90.64 125.06,91.43 v1(125.18,91.55)
  BOTTOM w0.127: CPU1.AN8 124.4,92 124.85,91.55 v1(125.18,91.55)
SATA_ODD_DA#_C: length 3.1
  TOP w0.127: ODD1.17 164.05,84.57 R5602.1 163.46,85.16 v2(163.46,85.79)
SATA_ODD_PRSNT#: length 70.5
  TOP w0.127: v1(164.29,82.5) 164.05,82.26 R5610.1 164.05,80.99 R5604.1 164.97,80.07 ODD1.8 ; v1(155.68,81.16) 151.32,85.53 151.32,94.46 149.37,96.41 149.37,98.59 148.91,99.05 148.91,104.4 143.75,109.56 138.5,109.56 138.49,109.55 138.36,109.55 133.13,104.32 133.13,102.59 v2(132.52,101.98) v1(131.45,100.91)
  L3 w0.127: v1(164.29,82.5) 163.95,82.15 163.86,82.15 163.82,82.12 163.45,82.12 163.41,82.15 161.88,82.15 160.38,80.66 159.65,80.66 159.05,80.06 157.32,80.06 156.52,80.86 155.99,80.86 v1(155.68,81.16)
  BOTTOM w0.127: v1(131.45,100.91) 131.45,100.71 130.69,99.94 130.61,99.94 128.41,97.74 127.9,97.74 127.15,96.98 CPU1.AV1
SATA_ODD_PWRGT: length 59.9
  TOP w0.127: v1(153.47,67.19) 152.74,67.19 145.89,74.05 138.87,74.05 135.06,77.86 131.15,77.86 v2(129.88,79.13) 128.44,80.57 v1(127.27,80.57) ; v1(160.33,80.21) 160.22,80.33 160.22,82.96 160.38,83.12 RN5601.4 162.74,83.12 163.31,82.56 v1(163.63,82.56)
  BOTTOM w0.127: v1(160.33,80.21) 160.31,80.19 160.31,77.2 160.3,77.2 160.3,77.08 158.24,75.02 158.24,73.85 156.07,71.68 153.99,71.68 153.04,70.72 153.04,67.63 v1(153.47,67.19) ; v1(127.27,80.57) 127.27,80.25 CPU1.AV31 ; U5601.4 166.01,82.22 165.84,82.05 164.09,82.05 163.63,82.51 v1(163.63,82.56)
SATA_PRX_ODDTX_N1: length 36.7
  TOP w0.102: v1(158.88,78.88) 158.97,78.98 159.46,78.98 C5607.2 ; v2(131.02,87.62) 131.02,87.08 v1(130.87,86.93)
  L3 w0.102: v1(130.87,86.93) 131.07,87.13 131.32,87.39 131.33,87.39 131.53,87.59 140.98,87.59 142.31,86.26 145.82,86.26 151.27,80.81 154.34,80.81 156.2,78.95 158.8,78.95 v1(158.88,78.88)
  BOTTOM w0.102: v1(130.87,86.93) 130.63,86.69 129.78,86.69 129.38,87.09 129.22,87.09 128.89,87.41 CPU1.AY17
SATA_PRX_ODDTX_P1: length 36.6
  TOP w0.102: v1(130.27,87.13) 129.96,87.13 v2(129.73,87.36) ; v1(158.87,79.52) 159.2,79.18 159.48,79.18 C5608.2
  L3 w0.102: v1(130.27,87.13) 130.27,87.49 130.39,87.62 130.64,87.62 130.87,87.39 131,87.39 131.23,87.62 131.43,87.82 141.07,87.82 142.41,86.49 145.92,86.49 151.37,81.04 154.44,81.04 156.29,79.18 158.54,79.18 v1(158.87,79.52)
  BOTTOM w0.102: v1(130.27,87.13) 130.27,87.01 130.15,86.89 129.86,86.89 129.47,87.29 129.31,87.29 129.1,87.5 CPU1.BA17
SATA_PTX_ODDRX_N1: length 38.3
  TOP w0.102: v2(133.46,87.36) 133,86.9 v1(132.77,86.9) ; C5611.2 159.66,77.58 159.36,77.58 159.26,77.68 159.26,77.76 158.85,78.17 v1(158.85,78.21)
  L3 w0.102: v1(158.85,78.21) 158.85,78.21 158.85,78.22 158.84,78.22 158.66,78.04 155.91,78.04 153.78,80.17 151.09,80.17 145.51,85.75 142,85.75 140.69,87.06 136.41,87.06 135.84,86.49 135.3,86.49 134.77,85.96 132.56,85.96 132.37,86.16 132.37,86.45 132.49,86.57 132.65,86.57 132.77,86.7 v1(132.77,86.9)
  BOTTOM w0.102: v1(132.77,86.9) 132.77,86.6 132.65,86.47 131.99,86.47 131.81,86.28 129.61,86.28 129.31,86.58 CPU1.BA19
SATA_PTX_ODDRX_P1: length 38.2
  TOP w0.102: v2(132.27,87.64) 132.14,87.51 v1(132.14,86.9) ; v1(158.83,77.58) 159.08,77.58 C5612.2
  L3 w0.102: v1(132.14,86.9) 132.14,86.07 132.47,85.74 134.87,85.74 135.4,86.27 135.94,86.27 136.5,86.83 140.6,86.83 141.9,85.52 145.42,85.52 150.99,79.94 153.68,79.94 155.82,77.81 158.62,77.81 158.83,77.6 v1(158.83,77.58)
  BOTTOM w0.102: v1(132.14,86.9) 131.72,86.49 129.69,86.49 129.3,86.88 128.93,86.88 CPU1.AY19
SATA_RXN0_R: length 13.2
  BOTTOM w0.102: 165.11,30.29 164.88,30.29 164.78,30.39 164.48,30.39 164.34,30.25 EU5602.7 EU5602.4 162.27,30.25 162.13,30.39 161.12,30.39 160.66,30.85 160.66,31.56 160.88,31.78 161.09,31.78 161.22,31.91 161.22,32.2 161.09,32.33 160.88,32.33 160.66,32.55 160.66,33.23 160.43,33.45 160.43,34.34 160.26,34.52 159.65,34.52 C5616.2 ; 165.11,30.29 v2(165.11,30.11) ; 165.11,30.29 167.1,30.29 167.25,30.13 HDD1.8
SATA_RXN2_R: length 13
  TOP w0.102: 161.55,80.1 161.55,80.59 161.32,80.81 161.13,80.81 160.98,80.96 160.98,81.21 161.13,81.35 161.32,81.35 161.55,81.58 161.55,82.28 161.63,82.36 162.01,82.36 162.09,82.28 162.09,81.11 162.85,80.35 162.85,80.12 162.34,79.61 162.34,79.33 162.97,78.7 163.39,78.7 163.67,78.98 163.97,78.98 164.25,78.7 164.93,78.7 165.07,78.57 ODD1.5 ; 161.55,80.1 v2(161.73,80.1) ; 161.55,80.1 161.55,79.25 161.26,78.97 161.04,78.97 C5607.1
SATA_RXP0_R: length 13.2
  BOTTOM w0.102: 166.3,30.49 167.11,30.49 167.25,30.63 HDD1.7 ; 166.3,30.49 164.96,30.49 164.86,30.59 164.48,30.59 164.34,30.73 EU5602.6 EU5602.5 162.27,30.73 162.13,30.59 161.21,30.59 160.87,30.93 160.87,31.48 160.97,31.58 161.18,31.58 161.42,31.82 161.42,32.29 161.18,32.53 160.97,32.53 160.87,32.63 160.87,33.31 160.64,33.54 160.64,34.43 160.34,34.72 159.65,34.72 C5615.2 ; 166.3,30.49 v2(166.3,30.69)
SATA_RXP2_R: length 13
  TOP w0.102: ODD1.6 165.07,79.07 164.9,78.9 164.33,78.9 164.05,79.18 163.58,79.18 163.3,78.9 163.05,78.9 162.54,79.41 162.54,79.53 163.05,80.04 163.05,80.43 162.29,81.19 162.29,82.37 162.09,82.57 161.54,82.57 161.34,82.37 161.34,82.08 ; 161.34,82.08 v2(161.14,82.08) ; 161.34,82.08 161.34,81.66 161.24,81.56 161.04,81.56 160.78,81.29 160.78,80.87 161.04,80.61 161.24,80.61 161.34,80.5 161.34,79.34 161.18,79.17 161.04,79.17 C5608.1
SATA_TXN0_R: length 13.1
  BOTTOM w0.102: 166.33,29.07 166.74,29.07 166.84,28.97 167.11,28.97 167.28,29.13 HDD1.10 ; 166.33,29.07 v2(166.33,29.25) ; 166.33,29.07 165.88,29.07 165.65,28.85 165.65,28.28 165.55,28.18 165.21,28.18 165.11,28.28 165.11,28.85 164.89,29.07 164.48,29.07 164.34,29.21 EU5602.9 EU5602.2 162.27,29.21 162.13,29.07 161.58,29.07 160.12,30.53 160.12,32.66 159.83,32.94 159.65,32.94 C5603.1
SATA_TXN2_R: length 13
  TOP w0.102: 163.4,78.03 163.27,78.15 162.74,78.15 162.19,78.71 161.78,78.71 161.49,78.42 161.49,78.01 162.16,77.35 162.16,75.68 162.03,75.55 161.75,75.55 161.6,75.7 161.6,77.08 161.33,77.35 161.08,77.35 C5611.1 ; 163.4,78.03 v2(163.53,78.17) ; 163.4,78.03 163.61,77.82 163.61,76.69 163.74,76.57 164.13,76.57 164.25,76.69 164.25,77.24 164.44,77.42 164.92,77.42 165.07,77.57 ODD1.3
SATA_TXP0_R: length 13.1
  BOTTOM w0.102: C5602.1 159.65,32.74 159.75,32.74 159.91,32.57 159.91,30.44 161.49,28.87 162.13,28.87 162.27,28.73 EU5602.1 EU5602.10 164.34,28.73 164.48,28.87 164.8,28.87 164.91,28.77 164.91,28.2 165.13,27.98 165.36,27.98 ; 165.36,27.98 165.64,27.98 165.86,28.2 165.86,28.77 165.96,28.87 166.66,28.87 166.76,28.76 167.19,28.76 167.32,28.63 HDD1.11 ; 165.36,27.98 v2(165.36,27.8)
SATA_TXP2_R: length 13
  TOP w0.102: C5612.1 161.01,77.15 161.25,77.15 161.4,77 161.4,75.88 ; 161.4,75.88 161.4,75.61 161.66,75.35 162.12,75.35 162.36,75.59 162.36,77.43 161.7,78.1 161.7,78.34 161.86,78.5 162.1,78.5 162.65,77.95 163.19,77.95 163.41,77.73 163.41,76.61 163.65,76.36 164.21,76.36 164.46,76.61 164.46,77.15 164.52,77.22 164.91,77.22 165.06,77.07 ODD1.2 ; 161.4,75.88 v2(161.22,75.88)
SATA_ZVDD_095: length 3.3
  TOP w0.203: v1(124.94,87.05) 124.31,86.41 R1904.2 123.86,86.69 123.7,86.85 123.7,87.53 v2(123.81,87.64)
  BOTTOM w0.203: CPU1.AP19 124.6,86.7 v1(124.94,87.05)
SATA_ZVSS: length 2.7
  TOP w0.203: v2(127.46,85.93) 127.01,86.37 R1903.2 125.8,87.01 v1(125.79,87.01)
  BOTTOM w0.203: v1(125.79,87.01) 125.79,87.01 125.72,87.01 125.4,86.69 CPU1.AR19
SD_CD#: length 14.8
  TOP w0.14: R3301.1 v1(29.51,25.16)
  L4 w0.127: v1(21.37,21.5) 22.6,20.27 27.15,20.27 29.51,22.63 v1(29.51,25.16)
  BOTTOM w0.14: v2(21.83,21.83) 21.7,21.83 v1(21.37,21.5) 21.07,21.2 U3201.13
SD_CD_R#: length 5.1
  TOP w0.14: R3301.2 EC3305.1 28.24,27.19 AFTP3304.1 26.27,27.19 25.55,27.91 CARD1.10
SD_CLK: length 22.1
  TOP w0.14: v1(29.06,19.19) 29.45,19.57 29.45,20.01 EC3201.1 27.6,20.39 AFTP3303.1 27.12,19.99 CARD1.5
  L4 w0.127: v1(23.22,19.7) 21.93,19.7 21.8,19.82 21.8,20.31 21.67,20.43 21.42,20.43 21.29,20.31 21.29,19.82 21.17,19.7 20.91,19.7 20.78,19.82 20.78,20.31 20.66,20.43 20.23,20.43 20.1,20.31 20.1,19.06 20.23,18.93 28.81,18.93 v1(29.06,19.19)
  BOTTOM w0.14: v1(23.22,19.7) 23.41,19.89 R3201.2
SD_CLK_5170: length 2.5
  BOTTOM w0.14: U3201.15 21.49,20.2 v2(21.6,20.31) 21.75,20.46 R3201.1
SD_CMD: length 24.1
  TOP w0.14: CARD1.2 27.13,12.49 AFTP3302.1 27.83,11.78 EC3304.1 28.9,11.78 29.17,12.05 29.17,16.62 27.9,17.89 v1(27.9,18.45)
  L4 w0.127: v1(21.03,18.48) 19.34,18.48 19.21,18.35 19.21,17.92 19.34,17.79 22.02,17.79 22.14,17.92 22.14,18.34 22.27,18.46 27.88,18.46 v1(27.9,18.45)
  BOTTOM w0.14: U3201.18 20.77,18.7 20.99,18.48 v1(21.03,18.48)
SD_D0: length 25
  TOP w0.14: CARD1.7 25.63,24.91 AFTP3306.1 28.11,23.38 EC3306.1 28.62,22.43 v1(28.3,22.11)
  L4 w0.127: v1(28.3,22.11) 27.52,21.32 25.36,21.32 25.23,21.45 25.23,23.1 25.1,23.23 24.85,23.23 24.72,23.1 24.72,21.45 24.6,21.32 24.34,21.32 24.22,21.45 24.22,23.1 24.09,23.23 23.83,23.23 23.71,23.1 23.71,21.4 23.58,21.27 22.21,21.27 22.01,21.47 22.01,22.06 21.88,22.19 21.01,22.19 20.84,22.36 20.84,23.2 20.71,23.33 v1(19.57,23.33)
  BOTTOM w0.14: U3201.11 18.89,22.66 v1(19.57,23.33)
SD_D1: length 22.9
  TOP w0.14: CARD1.8 25.83,26.61 AFTP3307.1 27.73,25.28 EC3301.1 v1(28.62,23.63)
  L4 w0.127: v1(28.62,23.63) 26.78,23.63 26.55,23.86 23.07,23.86 22.94,23.73 22.94,22.21 22.82,22.08 22.56,22.08 22.44,22.21 22.44,23.73 22.31,23.86 22.06,23.86 21.93,23.73 21.93,22.77 21.8,22.64 21.55,22.64 21.42,22.77 21.42,23.73 21.29,23.86 18.73,23.86 18.57,23.71 v1(18.57,23.3)
  BOTTOM w0.14: v1(18.57,23.3) 18.39,23.12 U3201.10
SD_D2: length 25.2
  TOP w0.14: CARD1.9 27.15,7.49 AFTP3308.1 28.54,7.5 EC3302.1 28.69,7.49 29.19,7.99 v1(29.19,8.77)
  L4 w0.127: v1(18.39,16.88) 18.88,17.36 22.22,17.36 22.89,18.03 25.38,18.03 29.7,13.71 29.7,9.15 29.32,8.77 v1(29.19,8.77)
  BOTTOM w0.14: U3201.21 v1(18.39,16.88)
SD_D3: length 24.3
  TOP w0.14: v1(29.14,9.59) 28.67,10.06 EC3303.1 28.52,10.04 AFTP3309.1 27.11,9.99 CARD1.1
  L4 w0.127: v1(19.13,16.9) 25.9,16.9 26.26,16.55 26.26,16.37 25.71,15.82 25.71,15.64 25.89,15.46 26.07,15.46 26.62,16.01 26.8,16.01 26.98,15.83 26.98,15.65 26.53,15.2 26.53,15.02 26.71,14.84 26.89,14.84 27.33,15.29 27.51,15.29 29.14,13.66 v1(29.14,9.59)
  BOTTOM w0.14: U3201.20 18.89,17.14 v1(19.13,16.9)
SD_WP: length 17.7
  TOP w0.14: CARD1.11 27.14,29.11 AFTP3305.1 27.41,29.35 27.41,30.3 EC3307.1 27.05,30.67 v1(26.14,30.67)
  L4 w0.127: v1(18.27,25.31) 20.78,25.31 v1(26.14,30.67)
  BOTTOM w0.14: v1(18.27,25.31) 16.92,25.31 16.56,24.94 R3202.1
SD_WP_5170: length 2.3
  BOTTOM w0.14: R3202.2 17.39,24.22 v2(17.39,23.35) U3201.8
SDREFG: length 5
  BOTTOM w0.305: C3206.1 15.36,24.46 v2(15.55,24.27) 16.05,23.77 U3201.6
SLEEVE: length 3
  BOTTOM w0.203: HDA27.18 156.35,17.56 v3(155.51,18.4)
  vias: v2(159.32,23.81) v3(158.25,23.81)
SMB0_CLK: length 98.2
  TOP w0.14: v2(142.17,32.46) v1(141.53,32.46)
  L3 w0.127: v1(142.93,20.41) 142.37,20.97 142.37,22.36 142.15,22.58 142.15,31.24 141.33,32.05 141.33,32.33 141.46,32.46 v1(141.53,32.46) 141.6,32.46 141.82,32.68 141.97,32.68 143.62,34.33 143.62,64.65 148.55,69.57 148.55,72.38 147.05,73.88 147.05,79.47 144.52,82 142.3,82 142.1,81.8 141.73,81.8 141.53,82 139.33,82 138.9,82.43 v1(138.34,82.43)
  L4 w0.127: v1(138.34,82.43) 138.18,82.43 137.61,81.86 135.93,81.86 135.66,81.6 130.16,81.6 128.08,83.68 126.86,83.68 125.93,82.75 v1(125.83,82.75)
  BOTTOM w0.14: v1(141.53,32.46) 141.53,32.39 141.21,32.07 140.95,32.07 140.47,31.58 139.41,31.58 138.95,31.13 DM1.202 ; v1(125.83,82.75) 126.2,83.12 CPU1.AU25 ; RN601.4 138.41,82.51 v1(138.34,82.43) ; DM2.202 143.85,18.55 143.9,18.61 143.9,19.51 143,20.41 v1(142.93,20.41)
SMB0_DATA: length 96.3
  TOP w0.14: v2(141,32.04) 140.75,32.29 v1(140.75,32.57)
  L3 w0.127: v1(138.36,81.72) 138.89,81.72 139.12,81.49 141.32,81.49 141.52,81.29 142.31,81.29 142.52,81.49 144.3,81.49 146.54,79.26 146.54,73.67 148.04,72.17 148.04,69.78 143.11,64.86 143.11,34.54 141.76,33.19 141.61,33.19 141.39,32.97 141.25,32.97 140.86,32.57 v1(140.75,32.57) 140.82,32.5 140.82,31.84 141.64,31.02 141.64,22.37 141.86,22.15 141.86,20.76 142.41,20.21 142.41,20.17 v1(142.93,19.65)
  L4 w0.127: v1(138.36,81.72) 138.19,81.72 137.82,81.35 136.14,81.35 135.87,81.09 129.95,81.09 127.87,83.17 127.07,83.17 v1(126.64,82.74)
  BOTTOM w0.14: RN601.3 138.52,81.85 138.39,81.72 v1(138.36,81.72) ; DM1.200 138.43,30.05 138.43,31.34 139.19,32.1 140.25,32.1 140.72,32.57 v1(140.75,32.57) ; DM2.200 143.25,17.55 143.33,17.63 143.33,18.77 143.38,18.82 143.38,19.29 143.03,19.65 v1(142.93,19.65) ; CPU1.AV25 127,83.1 v1(126.64,82.74)
SMB1_CLK: length 195
  TOP w0.14: Q6202.6 54.54,73.87 55,73.42 v1(55.18,73.42)
  L3 w0.127: v1(83.22,65.85) 83.22,65.88 84.08,66.74 84.08,75.67 77.04,82.71 v1(72.63,82.71) ; v1(130.52,91.37) 130.52,91.07 130.77,90.83 130.78,90.83 131.17,90.43 133.59,90.43 134.16,89.86 135.45,89.86 136.01,90.42 136.01,90.8 136.29,91.08 142.46,91.08 143.59,89.95 v1(143.72,89.95) 145.27,89.95 150.07,85.15 159.24,85.15 161.76,87.67 162.31,87.67 162.9,87.07 162.9,84.44 160,81.54 159.16,81.54 158.48,80.87 158.48,80.86 158.35,80.73 v1(158.35,80.66)
  BOTTOM w0.102: CPU1.AY11 128.65,90.98 128.95,91.28 129.22,91.28 129.6,90.91 130.06,90.91 v1(130.52,91.37)
  BOTTOM w0.14: v1(143.72,89.95) 143.97,89.95 144.38,89.55 145.14,89.55 145.33,89.74 RN603.2 ; v1(55.18,73.42) 55.18,75.04 57.98,77.85 v2(59.82,77.85) 67.86,77.85 68.29,77.85 72.51,82.07 72.51,82.6 v1(72.63,82.71) ; v1(158.35,80.66) 158.35,80.65 158.47,80.54 158.47,80.44 158.77,80.14 158.87,80.14 158.91,80.1 158.93,80.1 159.39,79.63 159.39,77.46 157.33,75.4 157.33,74.23 155.69,72.59 152.82,72.59 152.07,71.83 152.07,68.34 147.17,63.44 147.17,62.86 141.56,57.24 90.43,57.24 84.21,63.46 84.21,64.86 v1(83.22,65.85)
SMB1_DATA: length 197.7
  TOP w0.14: v1(52.71,76.62) 52.71,76.57 53.18,76.1 Q6202.3
  L3 w0.127: v1(158.99,80.66) 159.37,81.04 160.21,81.04 163.41,84.23 163.41,87.29 162.52,88.17 161.86,88.17 161.55,88.17 159.03,85.66 150.28,85.66 145.48,90.46 143.85,90.46 v1(143.72,90.59) 143.68,90.59 142.67,91.59 136.08,91.59 135.5,91.01 135.5,91 135.5,91 135.5,90.63 135.24,90.37 134.37,90.37 133.8,90.94 131.38,90.94 131.16,91.16 v1(131.16,91.36) ; v1(72.12,83.2) 72.14,83.22 77.25,83.22 84.59,75.89 84.59,66.53 83.17,65.11 v1(83.14,65.11)
  BOTTOM w0.102: CPU1.BA11 129.24,90.98 129.51,90.7 130.17,90.7 130.35,90.89 130.72,90.89 131.16,91.33 v1(131.16,91.36)
  BOTTOM w0.14: v1(72.12,83.2) 71.99,83.07 71.99,82.28 68.08,78.37 v2(64.73,78.37) 57.77,78.37 56.22,76.82 54.64,76.82 54.04,77.42 53.24,77.42 53.01,77.19 52.71,76.89 v1(52.71,76.62) ; RN603.1 144.2,90.56 143.87,90.56 143.85,90.59 v1(143.72,90.59) ; v1(83.14,65.11) 83.22,65.11 83.69,64.64 83.69,63.24 90.21,56.72 141.77,56.72 147.7,62.64 147.7,63.23 152.59,68.12 152.59,71.62 153.04,72.06 155.91,72.06 157.86,74.01 157.86,75.18 159.91,77.24 159.91,79.85 159.11,80.66 v1(158.99,80.66)
SML1_CLK: length 199.3
  TOP w0.14: RN401.1 159.95,125.18 v1(159.55,125.58) ; Q2601.3 76.27,65.08 75.8,65.54 v1(75.8,65.67)
  L3 w0.127: v1(164.57,75.78) 164.57,75.39 164.38,75.19 164.37,75.19 159.41,70.24 158.99,70.24 158.73,70.24 156.29,67.8 156.29,63.53 157.39,62.43 157.39,59.41 152.45,54.47 147.02,54.47 v1(146.87,54.32)
  L4 w0.127: v1(83.73,78.34) 83.78,78.29 83.78,75.15 77.2,68.57 77.2,65.8 76.87,65.48 75.99,65.48 v1(75.8,65.67) ; v1(164.57,75.78) 164.57,75.83 164.65,75.9 164.65,76.69 163.79,77.56 163.79,79.66 165.26,81.13 165.26,85.03 165.55,85.32 165.55,88.32 165.06,88.82 165.06,111.24 162.95,113.35 162.95,114.97 158.52,119.4 158.52,123.29 159.55,124.32 v1(159.55,125.58)
  BOTTOM w0.14: v1(75.8,65.67) 75.71,65.58 72.89,65.58 72.36,65.05 72.36,62.08 73.34,61.1 79.53,61.1 88.06,52.57 143.7,52.57 145.63,54.49 146.69,54.49 v1(146.87,54.32) ; Q403.6 86.77,79.39 85.83,78.45 v2(85.4,78.45) 83.83,78.45 v1(83.73,78.34) ; v1(159.55,125.58) 159.48,125.65 159.48,126.86 159.42,126.92 KBC24.67
SML1_DATA: length 200.2
  TOP w0.14: RN401.2 159.3,124.89 v1(158.73,125.45) ; Q2601.6 v1(73.91,63.78)
  L3 w0.127: v1(163.94,75.91) 163.94,75.49 159.2,70.75 158.52,70.75 155.79,68.01 155.79,63.32 156.88,62.22 156.88,59.62 152.24,54.98 147.25,54.98 147.12,55.1 v1(146.92,55.1)
  L4 w0.127: v1(163.94,75.91) 164.14,76.11 164.14,76.48 163.28,77.35 163.28,79.87 164.75,81.34 164.75,85.24 165.04,85.54 165.04,88.11 164.55,88.61 164.55,111.03 162.44,113.14 162.44,114.76 158.01,119.19 158.01,123.5 159.04,124.53 159.04,125.14 v1(158.73,125.45) ; v1(84.39,79.03) 84.39,78.5 84.28,78.4 84.28,74.94 77.71,68.36 77.71,65.59 76.51,64.4 74.53,64.4 v1(73.91,63.78)
  BOTTOM w0.14: KBC24.68 159.02,126.92 158.96,126.86 158.96,125.68 v1(158.73,125.45) ; Q403.3 83.84,81.31 83.6,81.06 v2(83.6,80.58) 83.6,79.82 v1(84.39,79.03) ; v1(146.92,55.1) 146.83,55.01 145.41,55.01 143.49,53.09 88.28,53.09 79.75,61.62 73.55,61.62 72.88,62.29 72.88,64.83 73.11,65.06 74.3,65.06 74.61,64.76 74.61,64.48 v1(73.91,63.78)
SPI_CLK_R: length 31.9
  TOP w0.14: R2420.1 150.26,123.61 EC2503.1 150.02,123.54 149.63,123.15 149.63,122.25 v1(149.08,121.7) ; v1(142.7,104.1) 141.68,104.1 139.2,101.62 v2(139.2,101.36) 139.2,100.96 138.5,100.26 R1925.2
  BOTTOM w0.14: v1(149.08,121.7) 149.08,120.69 147.18,118.79 147.18,112.46 146.66,111.94 146.66,108.93 143.36,105.63 143.36,104.76 v1(142.7,104.1) 142.27,104.1 141.84,104.53 SSKT2.6
SPI_CS0#_R: length 38.3
  TOP w0.14: R2501.1 v2(144.76,103.31) 144.76,103.71 v1(144.38,104.09) 143.68,104.09 v1(142.86,104.91) 141.84,104.91 138.41,101.48 R1908.2
  BOTTOM w0.14: v1(142.86,104.91) 142.86,105.72 146.24,109.1 146.24,112.11 146.76,112.64 146.76,118.97 148.39,120.6 148.39,121.41 148.32,121.48 R2419.2 ; v1(144.38,104.09) 145.21,104.09 146.17,105.05 149.09,105.05 149.46,105.42 149.46,106.69 149.08,107.07 SPI25.1
SPI_CS2#: length 1.4
  TOP w0.14: TP1904.1 125.72,94.4 v1(126.04,94.4)
  BOTTOM w0.14: CPU1.AR4 125.76,94.68 v1(126.04,94.4)
SPI_HOLD#: length 28.2
  TOP w0.14: RN1904.1 138.85,97.73 139.17,98.05 139.17,99.31 v2(141.74,101.88) 142.35,102.49 v1(142.35,102.5) 142.8,102.5 143.01,102.28 RN2501.2
  BOTTOM w0.14: SPI25.7 140.5,105.8 139.17,104.47 139.17,103.26 139.94,102.5 v1(142.35,102.5) 142.35,102.12 141.83,101.6 141.63,101.6 141.3,101.93 141.12,101.93 140.9,101.72 140.9,101.54 141.24,101.2 141.24,101.01 141.04,100.81 140.84,100.81 139.82,101.83 139.64,101.83 139.43,101.61 139.43,101.43 140.71,100.15 140.71,99.97 140.49,99.76 140.31,99.76 139.63,100.44 139.45,100.44 139.24,100.22 139.24,100.04 140.01,99.27 140.01,98.94 139.62,98.55 R1923.2
SPI_SI_R: length 33.5
  TOP w0.14: v1(143.97,104.76) v2(143.45,105.29) 143.37,105.36 141.7,105.36 139.64,103.31 139.44,103.31 139.15,103.6 138.95,103.6 138.76,103.4 138.76,103.21 139.05,102.91 139.05,102.72 138.71,102.37 R1921.2
  BOTTOM w0.14: SSKT2.5 142.5,103.26 143.16,103.91 143.16,103.94 v1(143.97,104.76) 143.87,104.86 143.87,105.55 147.08,108.75 147.08,111.77 147.6,112.29 147.6,118.62 150.54,121.56 EC2501.1 150.54,122.41 150.48,122.47 150.48,123.3 R2422.2
SPI_SO_R: length 34.4
  TOP w0.14: v1(144.7,104.79) 143.55,105.93 v2(141.66,105.93) 141.5,105.93 EC2502.1 139.24,104.7 138.09,103.55 R1922.2
  BOTTOM w0.14: R2423.2 151.48,123.34 152.03,122.79 152.03,121.81 151.6,121.37 150.94,121.37 148.02,118.45 148.02,112.11 147.5,111.59 147.5,108.58 144.7,105.78 v1(144.7,104.79) 144.82,104.66 145.14,104.66 146.29,105.8 SSKT2.2
SPI_SW: length 14.5
  L4 w0.127: v1(136.51,90.56) 135.67,90.56 134.41,89.3 129.38,89.3 128.94,89.75 127.14,89.75 126.7,89.32 v1(126.6,89.32)
  BOTTOM w0.14: v1(136.51,90.56) 136.66,90.56 137.05,90.18 R1915.2 137.53,90.18 137.78,89.92 R1916.1 ; CPU1.AV17 127,87.89 126.6,88.28 v1(126.6,89.32)
SPI_WP#: length 18.6
  TOP w0.14: RN2501.1 143.66,103.22 v1(143.39,103.49) 141.66,103.49 140.37,102.2 v2(140.37,101.99) 140.37,101.53 138.32,99.48 v1(138.18,99.48) 138.28,99.38 138.28,99.32 138.38,99.23 RN1904.2
  BOTTOM w0.14: SSKT2.3 146.24,104.53 146.03,104.32 146.03,102.75 145.9,102.63 143.52,102.63 143.39,102.75 v1(143.39,103.49) ; v1(138.18,99.48) 138.06,99.48 137.17,98.59 R1924.2
SYS_PWRGD: length 177.3
  TOP w0.127: v1(154.28,75.91) 154.21,75.98 154.21,79 147.53,85.69 v2(146.82,85.69) 146.49,85.69 144.66,87.51 v1(144.56,87.51) ; v1(157.85,145.67) 157.63,145.44 ED2403.1
  L3 w0.127: v1(146.8,58.53) 145.64,59.69 145.64,66.03 149.56,69.96 149.56,71.46 154.01,75.91 v1(154.28,75.91)
  L4 w0.127: v1(166.07,74.32) 165.98,74.32 165.3,75 165.3,75.89 165.78,76.38 165.78,79.34 166.14,79.69 166.14,84.53 166.44,84.83 166.44,89.46 165.91,89.99 165.91,113.67 165.55,114.03 159.71,119.87 159.71,122.76 161.14,124.18 161.14,126.78 159.42,128.49 158.58,128.49 157.53,129.55 157.53,131.71 157.07,132.17 157.07,137.89 155.82,139.14 155.82,140.4 156.25,140.83 156.29,140.83 157.85,142.39 v1(157.85,145.67) ; v1(146.8,58.53) 146.84,58.48 146.88,58.48 147.15,58.21 147.15,57.67 148.17,56.65 148.17,50.18 v1(147.81,49.82)
  BOTTOM w0.127: v1(147.81,49.82) 151.37,53.38 154.12,53.38 159.42,58.68 159.42,63.49 158.1,64.82 158.1,68.08 162.99,72.97 164.32,72.97 165.67,74.32 v1(166.07,74.32) ; R3627.2 156.14,76.38 156.05,76.46 154.84,76.46 v1(154.28,75.91) ; KBC24.26 157.82,145.63 v1(157.85,145.67) ; R611.1 137.6,88.56 137.6,87.3 137.86,87.04 138.18,87.04 138.25,86.98 138.39,86.98 138.4,86.98 144.03,86.98 v1(144.56,87.51)
SYS_RESET#: length 8.9
  BOTTOM w0.102: CPU1.AY7 128.62,93.18 128.93,92.87 130.97,92.87 131.5,93.41 131.98,93.41 132.03,93.46 132.04,93.46 132.32,93.74 133.8,93.74 133.91,93.64 134.56,93.64 R1927.1 R1926.1 v2(136.68,93.35)
T_CRIT#: length 4.9
  TOP w0.102: R2601.1 78.57,58.52 v2(78.57,57.64) 78.57,56.54 R2604.2 78.25,56.51 77.43,57.34 77.07,57.34 76.98,57.25 THM26.4
TEMPINRETURN: length 8
  BOTTOM w0.102: R412.2 101.49,86.52 102.12,86.52 103.11,85.53 103.11,85.03 v2(103.31,84.83) 103.36,84.78 103.36,84.62 104.05,83.93 106.05,83.93 CPU1.A23
THERM_SYS_SHDN#: length 194.8
  TOP w0.102: v1(78.57,60.18) 78.57,59.46 R2601.2 79.36,59.43 Q2602.S ; v2(150.1,136.33) 149.59,136.33 v1(149.44,136.18) R2607.2
  L3 w0.102: v1(149.44,136.18) 148.6,135.34 148.6,134.93 145.37,131.71 144.66,131.71 140.72,127.77 140.72,125.23 146.31,119.64 148.85,119.64 150.88,117.61 157.3,117.61 166.55,108.37 166.55,90.58 167.09,90.04 167.09,79.41 166.44,78.76 166.44,76.74 165.37,75.67 165.37,74.28 163.2,72.11 162.79,72.11 159.91,69.23 159.23,69.23 158.19,68.18 158.19,63.15 158.8,62.54 158.8,59.39 151.97,52.56 v1(146.18,52.56)
  BOTTOM w0.102: v1(78.57,60.18) 78.57,56.56 83.57,51.56 144.75,51.56 145.75,52.56 v1(146.18,52.56)
THM_SML1_CLK: length 10.4
  TOP w0.14: RN2601.4 76,66.25 75.93,66.18 75.11,66.18 v1(75.04,66.11) 74.81,65.88 Q2601.4 75.38,65.08 75.56,64.9 C2608.1 75.56,62.29 75.09,61.82 75.09,61.35 75.03,61.29 THM26.8
  BOTTOM w0.14: v1(75.04,66.11) 75.35,66.42 RN2602.4 74.75,66.98 v2(74.4,67.32)
THM_SML1_DATA: length 13.3
  TOP w0.14: 78.09,64.86 78.09,65.03 77.2,65.92 v1(76.69,65.92) 76.69,67.32 76.44,67.57 75.55,67.57 75.35,67.38 RN2601.3 ; 78.09,64.86 v2(78.24,64.86) ; 78.09,64.86 78.09,64.27 77.59,63.78 Q2601.1 76.27,63.78 76.08,63.58 76.08,62.93 76.45,62.57 C2609.1 76.4,62.39 75.61,61.61 75.61,61.42 75.68,61.35 THM26.7
  BOTTOM w0.14: v1(76.69,65.92) 76.31,66.3 76.18,66.3 76,66.49 RN2602.3
TOUCH_PANEL_INTR#: length 71.9
  TOP w0.127: v2(145.09,145.98) 145.09,145.24 v1(145.08,145.22) R2411.1 ; R5205.2 v1(99.8,136.79)
  L3 w0.127: v1(99.8,136.79) 99.8,137.55 100.18,137.93 100.18,142.12 102.41,144.35 102.41,146.42 106.59,150.59 113.81,150.59 116,148.4 116,147.78 116.66,147.12 123.42,147.12 124.98,145.55 144.75,145.55 v1(145.08,145.22)
  BOTTOM w0.127: v1(145.08,145.22) 145.26,145.4 R2443.1 146.71,147.83 148.34,149.46 D2401.A
TOUCH_PANEL_INTR_KBC#: length 10.1
  TOP w0.127: v1(143.24,143.9) 143.62,144.28 R2411.2
  BOTTOM w0.127: v1(143.24,143.9) 142.48,143.14 v2(142.48,142.84) 142.48,142.25 141.73,141.5 141.73,140.26 141.99,140 144,140 144.27,140.27 KBC24.124
TP41: length 1.2
  TOP w0.102: v1(125.01,80.64) 125.43,81.06 TP421.1
  BOTTOM w0.102: v1(125.01,80.64) 124.6,81.06 CPU1.AP29
TP_LOCK#: length 218.2
  TOP w0.102: v1(153.27,144.66) 153.84,144.09 R2454.2 ; TPAD1.3 61.68,78.77 AFTP6242.1 60.56,79.51 v1(57.77,76.72)
  L3 w0.102: v1(57.77,76.72) 57.77,76.97 58.15,77.35 59.16,77.35 61.53,74.99 68.43,74.99 74.29,69.12 76.99,69.12 77.99,68.12 77.99,66.66 v1(78.21,66.43) ; v1(165.77,89.16) 165.77,88.72 166.53,87.96 166.53,79.84 165.86,79.17 165.86,77.97 164.44,76.55 162.55,76.55 161.48,75.47 159.05,75.47 153.92,70.34 153.92,69.5 153.54,69.12 153.38,69.12 147.81,63.56 147.81,59.62 v1(147.33,59.14)
  L4 w0.102: v1(153.27,144.66) 154.79,143.14 154.79,139.44 156.6,137.63 156.6,131.94 157.06,131.48 157.06,129.36 158.39,128.02 159.17,128.02 160.67,126.53 160.67,124.38 159.24,122.95 159.24,119.68 165.42,113.49 165.42,89.5 v1(165.77,89.16)
  BOTTOM w0.102: v1(78.21,66.43) 78.21,66.23 78.58,65.86 78.58,65.15 78.16,64.73 78.16,63.71 78.42,63.45 78.77,63.45 88.5,53.72 143.07,53.72 145.68,56.32 147.05,56.32 147.33,56.6 v1(147.33,59.14)
TP_LOCK#_R: length 9.4
  TOP w0.102: R2454.1 154.87,143.15 v2(154.87,142.25) 154.87,141.57 154.03,140.73 v1(153.27,140.73)
  BOTTOM w0.102: v1(153.27,140.73) 156.17,140.73 156.62,141.18 KBC24.23
TP_ON#: length 12.5
  BOTTOM w0.102: KBC24.33 162.71,141.87 R2452.1 R2453.1 165.91,144.28 167.37,144.28 170.06,146.98 v2(170.06,147.58) R6218.1
TP_ON#_GATE: length 6.3
  BOTTOM w0.102: Q6205.G 168.75,152.22 169.07,151.9 v2(169.07,151.34) 168.79,151.06 168.13,151.06 167.84,150.78 Q6204.G 168.39,149.88 C6205.2 169.98,149.88 R6218.2
TP_ON#_S: length 6.4
  BOTTOM w0.102: R6215.2 167.13,145.81 R6217.2 167.1,146.78 R6216.1 168.24,146.95 v2(168.3,147) 168.3,147.47 167.84,147.92 Q6204.S 168.38,148.99 C6205.1
TP_RESET: length 6.4
  TOP w0.102: R5448.1 C5214.1 96.88,135.9 AFTP5214.1 96.25,136.03 96.25,136.92 95.15,138.02 LCD1.38
TP_RS: length 5.2
  TOP w0.102: R5205.1 C5208.1 97.39,137.68 97.26,137.55 AFTP5209.1 96.12,137.55 95.15,138.52 LCD1.37
TP_SMB1_CLK: length 8
  TOP w0.14: R6212.1 55.93,75.19 EC6207.1 54.98,75.26 Q6202.1 54.48,75.41 54.11,75.05 52.89,75.05 52.88,75.07 52.81,75.07 52.69,75.19 v2(51.92,75.19) 49.75,75.19 49.69,75.24 49.5,75.24 RN6201.2
TP_SMB1_CLK_R: length 5.9
  TOP w0.14: R6212.2 58,75.19 58.18,75.01 59.11,75.01 59.63,75.53 AFTP6237.1 62.01,75.53 62.25,75.77 TPAD1.6
TP_SMB1_DATA: length 8.2
  TOP w0.14: RN6201.1 49.85,74.62 49.91,74.67 v2(50.63,74.67) 52.17,74.67 52.97,73.87 Q6202.4 53.18,74.21 53.54,74.58 54.8,74.58 55.01,74.37 EC6206.1 55.93,74.31 R6213.1
TP_SMB1_DATA_R: length 5.9
  TOP w0.14: TPAD1.7 62.25,74.77 62.01,75.01 59.84,75.01 59.32,74.49 AFTP6240.1 58.18,74.49 58,74.31 R6213.2
TP_VDD: length 263.5
  TOP w0.254: v1(161.5,65.42) 161.58,65.34 161.58,64.81 160.94,64.17 158.38,64.17 156.42,66.13 154.29,66.13 153.98,65.82 150.55,65.82 147.74,63.01 v1(146.66,63.01) ; v1(50.56,80.49) RN6203.1 51.03,79.84 51.16,79.71 51.16,79.35 50.99,79.19 RN6203.2 50.56,78.18 R6209.2 47.91,77.89 47.1,77.07 47.1,73.29 48.06,72.32 58.64,72.32 C6202.1 60.56,73.04 AFTP6239.1 61.29,73.77 TPAD1.8
  L3 w0.254: v1(79.75,67.86) 79.75,70.76 81.62,72.63 81.62,75.33 80.24,76.71 79.74,77.2 76.16,80.78 62.24,80.78 61.09,79.64 56.32,79.64 54.85,78.17 52.22,78.17 50.56,79.83 v1(50.56,80.49)
  L4 w0.254: v1(167.95,65.14) 167.95,66.13 168.76,66.94 168.76,69.49 169.23,69.96 169.23,79.49 169.5,79.75 169.5,89.44 168.87,90.08 168.87,92.09 168.08,92.87 168.08,144.59 v1(164.73,147.94)
  BOTTOM w0.254: R6214.1 164.26,151.56 R6203.2 164.3,149.45 Q6204.D 165.94,146.96 R6216.2 165.46,146.95 164.73,147.69 v1(164.73,147.94) ; v1(161.5,65.42) 163.15,65.42 163.56,65.01 167.7,65.01 167.83,65.14 v1(167.95,65.14) ; v1(146.66,63.01) 141.34,57.69 92.69,57.69 82.52,67.86 v1(79.75,67.86)
TP_WAKE_KBC#: length 12.1
  TOP w0.102: v2(151.49,129.55) 151.62,129.55 v1(152.25,130.19) 152.57,130.5 R2448.2
  BOTTOM w0.102: KBC24.63 160.57,129.87 159.62,130.82 155.3,130.82 154.67,130.19 v1(152.25,130.19)
TPAN_VDD:
  vias: v2(95.87,135.95) v3(91.04,137.68) v3(92.06,137.68)
TPAN_VDD_F:
  vias: v2(96.15,139.79)
TPCLK: length 205.9
  TOP w0.14: R6210.1 55.35,79.07 EC6205.1 53.94,79.07 53.17,79.84 v1(52.89,79.84) RN6203.4
  L3 w0.127: v1(80.2,66.96) 82.72,69.49 82.72,75.57 76.44,81.86 61.71,81.86 60.89,81.04 55.79,81.04 54.33,79.58 53.31,79.58 53.05,79.84 v1(52.89,79.84) ; v1(146.6,57.59) 146.87,57.59 148.29,59.02 148.29,61.66 152.2,65.57 153.29,65.57 154.52,66.79 154.52,68.61 158.45,72.54 158.45,73.09 159.51,74.15 161.27,74.15 162.52,75.4 162.52,75.43 162.83,75.75 v1(162.83,75.88)
  L4 w0.127: v1(162.83,75.88) 162.36,76.35 162.36,83.56 163.38,84.58 163.38,88.38 163.66,88.66 163.66,110.26 163.3,110.62 161.35,112.58 161.35,114.15 156.55,118.95 156.55,125.44 157.06,125.94 157.06,126.1 v1(157.08,126.12)
  BOTTOM w0.14: v2(52.26,79.84) 52.89,79.84 v1(52.89,79.84) ; v1(146.6,57.59) 146.48,57.59 146.35,57.45 145.49,57.45 142.65,54.61 89.21,54.61 88.95,54.87 88.95,54.87 79.57,64.25 79.57,66.26 80.2,66.88 v1(80.2,66.96) ; KBC24.72 157.42,127.18 157.3,127.06 157.3,126.39 157.08,126.17 v1(157.08,126.12)
TPCLK_C: length 7.7
  TOP w0.14: TPAD1.1 62.25,80.77 62.01,80.53 61.58,80.53 61.45,80.66 59.8,80.66 AFTP6238.1 57.96,78.82 56.91,78.82 56.73,79 R6210.2
TPDATA: length 206.6
  TOP w0.14: R6211.1 55.35,78.18 EC6208.1 54.47,78.3 53.97,78.3 v2(53.57,78.7) 53.08,79.19 v1(52.85,79.19) RN6203.3
  L3 w0.127: v1(79.26,67.09) 79.31,67.09 79.53,67.32 79.84,67.32 82.21,69.7 82.21,75.36 76.23,81.35 61.92,81.35 61.1,80.53 56,80.53 54.54,79.07 53.1,79.07 52.92,79.25 v1(52.85,79.19) ; v1(146.64,56.81) 146.74,56.91 146.9,56.91 148.8,58.8 148.8,61.45 152.41,65.06 153.5,65.06 155.02,66.58 155.02,68.4 158.96,72.33 158.96,72.88 159.72,73.65 161.48,73.65 163.02,75.19 163.02,75.19 163.15,75.32 v1(163.15,75.32)
  L4 w0.127: v1(157.87,126.1) 157.87,126.05 157.74,125.92 157.74,125.91 157.06,125.23 157.06,119.16 161.86,114.36 161.86,112.79 164.17,110.48 164.17,88.45 163.89,88.17 163.89,84.37 162.87,83.35 162.87,76.56 163.34,76.09 163.34,75.67 163.34,75.54 163.15,75.35 163.15,75.33 v1(163.15,75.32)
  BOTTOM w0.14: v1(79.26,67.09) 79.26,66.67 79.05,66.47 79.05,64.03 88.43,54.66 88.99,54.09 142.86,54.09 145.7,56.93 146.41,56.93 146.54,56.81 v1(146.64,56.81) ; KBC24.71 157.82,126.25 157.87,126.2 v1(157.87,126.1)
TPDATA_C: length 7.7
  TOP w0.14: R6211.2 56.73,78.12 56.91,78.3 AFTP6236.1 58.18,78.3 60.01,80.14 61.23,80.14 61.36,80.01 62.01,80.01 62.25,79.77 TPAD1.2
TPS51216_PHS_SET: length 2.3
  TOP w0.254: PC4922.1 59.01,33.2 v2(59.88,33.2) 59.88,32.55 PR4912.2
USB3_PRX_CTX_N0: length 138.3
  L4 w0.102: v1(114.43,98.54) 114.43,98.64 114.33,98.74 114.12,98.74 113.9,98.52 113.9,97.27 112.25,95.62 112.25,88.02 111.77,87.54 107.9,87.54 105.39,85.02 103.84,85.02 103.46,84.64 103.46,81.16 101.81,79.51 94.88,79.51 92.17,82.23 89.69,82.23 88.09,80.63 87.05,80.63 86.55,80.13 86.55,80.13 86.16,79.74 83.9,79.74 74.09,69.94 45.52,69.94 40.98,65.39 38.44,65.39 33.26,60.21 33.26,59.63 28.15,54.53 28.15,46.52 28.51,46.16 28.51,39.16 28.12,38.77 27.42,38.77 27.29,38.64 27.29,38.14 27.19,38.03 v1(26.86,38.03)
  BOTTOM w0.102: R3411.1 25.89,38.28 TR3402.1 26.19,38.28 26.49,38.57 26.75,38.57 26.86,38.46 v1(26.86,38.03) 27.13,38.03 v2(27.44,37.73) ; v1(114.43,98.54) 114.69,98.8 114.82,98.8 114.91,98.71 114.91,98.47 116.19,97.19 116.19,96.47 CPU1.V1
USB3_PRX_CTX_N0_C: length 14.4
  BOTTOM w0.102: 21.61,38.68 21.9,38.39 23.79,38.39 23.99,38.59 24.27,38.59 24.58,38.28 TR3402.2 24.87,38.28 R3411.2 ; 21.61,38.68 v2(21.47,38.54) ; 21.61,38.68 21.24,39.05 20.56,39.05 20.42,38.91 U3402.10 U3402.1 18.29,38.91 17.16,37.78 14.38,37.78 13.49,36.89 13.1,36.89 12.97,36.76 USB1.5
USB3_PRX_CTX_P0: length 138.3
  L4 w0.102: v1(114.43,99.17) 114.23,99.17 113.67,98.62 113.67,97.37 112.02,95.72 112.02,88.12 111.67,87.77 107.8,87.77 105.29,85.25 103.75,85.25 103.23,84.74 103.23,81.26 101.72,79.74 94.98,79.74 92.26,82.46 89.59,82.46 87.99,80.86 86.95,80.86 86.32,80.22 86.32,80.22 86.06,79.97 83.8,79.97 74,70.17 45.43,70.17 40.88,65.62 38.34,65.62 33.03,60.3 33.03,59.73 27.92,54.62 27.92,46.42 28.28,46.07 28.28,39.25 28.02,39 v1(26.86,39)
  BOTTOM w0.102: v2(27.54,39.13) 27.42,39 v1(26.86,39) 26.64,38.77 26.46,38.77 26.27,38.96 TR3402.4 25.89,38.96 R3410.1 ; v1(114.43,99.17) 114.6,99 114.91,99 115.11,98.79 115.11,98.55 116.39,97.28 116.39,96.64 116.45,96.59 116.45,96.3 CPU1.V2
USB3_PRX_CTX_P0_C: length 14.4
  BOTTOM w0.102: USB1.6 12.97,37.17 13.05,37.09 13.41,37.09 14.3,37.98 17.07,37.98 18.48,39.39 U3402.2 U3402.9 20.42,39.39 20.56,39.26 21.32,39.26 21.99,38.59 23.35,38.59 ; R3410.2 24.87,38.96 TR3402.3 24.53,38.96 24.36,38.79 23.9,38.79 23.71,38.59 23.35,38.59 ; 23.35,38.59 v2(23.35,38.77)
USB3_PTX_CRX_N0: length 131.1
  L4 w0.102: v1(112.96,98.59) 112.93,98.56 112.73,98.56 112.61,98.69 112.61,99.02 112.48,99.15 111.82,99.15 111.26,98.58 111.26,89.86 110.11,88.72 107.99,88.72 104.98,85.71 103.56,85.71 102.83,84.97 102.83,81.42 101.76,80.35 95.23,80.35 92.51,83.07 88.27,83.07 86.09,80.88 83.86,80.88 73.75,70.78 45.18,70.78 40.63,66.23 38.09,66.23 32.42,60.56 32.42,59.98 27.19,54.75 27.19,44.95 27.26,44.88 27.26,44.82 27.38,44.7 v1(27.62,44.7)
  BOTTOM w0.102: v2(28.3,44.71) 28.29,44.7 v1(27.62,44.7) 27.44,44.7 27.03,44.29 27.03,43.98 27.16,43.85 27.57,43.85 27.67,43.75 C3403.1 ; v1(112.96,98.59) 113.13,98.77 113.31,98.77 114,98.07 114,97.75 114.46,97.29 114.51,97.25 114.51,97.24 115.05,96.7 CPU1.T1
USB3_PTX_CRX_N0_C: length 14.2
  BOTTOM w0.102: v2(21.22,40.4) 21.22,40.57 ; 21.22,40.57 21.6,40.57 21.71,40.68 21.98,40.68 22.32,40.33 C3402.1 22.68,40.68 23.98,40.68 24.22,40.44 TR3401.2 24.62,40.44 R3409.2 ; 21.22,40.57 20.56,40.57 20.42,40.44 U3402.7 U3402.4 18.35,40.44 18.21,40.57 15.93,40.57 13.64,42.87 13.07,42.87 12.97,42.77 USB1.8
USB3_PTX_CRX_N0_R: length 4
  BOTTOM w0.102: v2(27.08,40.35) 27.08,40.52 ; 27.08,40.52 27.21,40.52 27.44,40.75 27.44,42.26 C3403.2 ; 27.08,40.52 26.29,40.52 26.2,40.44 TR3401.1 25.64,40.44 R3409.1
USB3_PTX_CRX_P0: length 131.3
  L4 w0.102: v1(26.83,44.7) 26.96,44.83 26.96,54.84 32.19,60.07 32.19,60.65 38,66.46 40.54,66.46 45.08,71 73.65,71 83.76,81.11 85.99,81.11 88.18,83.3 92.61,83.3 95.33,80.58 101.67,80.58 102.6,81.51 102.6,85.07 103.47,85.94 104.89,85.94 107.9,88.95 110.01,88.95 111.03,89.96 111.03,98.68 111.59,99.24 111.72,99.38 112.57,99.38 112.73,99.22 v1(113,99.22)
  BOTTOM w0.102: v1(113,99.22) 113,99.19 113.22,98.97 113.39,98.97 114.21,98.16 114.21,97.83 114.59,97.45 114.65,97.39 114.69,97.35 114.69,97.35 115.29,96.75 115.29,96.65 115.35,96.6 115.35,96.3 CPU1.T2 ; C3404.1 26.83,43.43 v1(26.83,44.7) 26.1,44.7 v2(26.09,44.69)
USB3_PTX_CRX_P0_C: length 14.2
  BOTTOM w0.102: USB1.9 12.97,43.17 13.07,43.07 13.72,43.07 16.02,40.78 18.21,40.78 18.35,40.91 U3402.5 U3402.6 20.42,40.91 20.56,40.78 21.52,40.78 21.62,40.88 21.98,40.88 22.32,41.22 C3401.1 22.68,40.88 23.3,40.88 ; v2(23.3,41.03) 23.3,40.88 ; 23.3,40.88 23.85,40.88 24.09,41.12 TR3401.3 24.62,41.12 R3408.2
USB3_PTX_CRX_P0_R: length 3.9
  BOTTOM w0.102: R3408.1 25.64,41.12 TR3401.4 26.2,41.12 26.59,40.73 27.13,40.73 27.24,40.84 27.24,41.57 ; 27.24,41.57 27.24,42.04 C3404.2 ; 27.24,41.57 v2(27.06,41.57)
USB20_VCCA: length 10.7
  TOP w0.508: 156.55,33.92 156.55,42.02 v1(156.7,42.17)
  BOTTOM w0.508: EU3404.5 156.83,42.05 v1(156.7,42.17) 156.32,42.56 156.19,42.56 155.81,42.94 C3406.1
  vias: v3(156.22,31.53) v3(156.22,30.67) v3(156.55,32.32) v3(162.16,33.51) v3(163.18,33.54)
USB30_VCCC: length 7
  TOP w0.508: v3(23.1,37.4) 23.1,38.8 22.73,39.17 EU3403.5
  TOP w0.635: USB1.1 14.47,44.18 ; USB1.1 14.47,42.76 ; USB1.1 15.18,43.47
  BOTTOM w0.508: v3(23.1,37.4) 22.99,37.3 C3405.1
  BOTTOM w0.635: 15.02,44.02 USB1.1 15.18,43.47
  vias: v3(15.98,45.48) v3(15.98,44.46) v3(18.63,62.88) v3(18.65,63.89) v3(18.78,45.35) v3(20.67,45.35) v3(21.44,67.45) v3(22.21,67.96) v3(22.26,67.02) v3(22.71,45.86) v3(23.02,67.5)
USB_ATEST0: length 3.5
  TOP w0.102: TP416.1 122.94,93.81 123.2,93.56 123.2,92.75 122.73,92.29 v1(122.73,91.82)
  BOTTOM w0.102: v1(122.73,91.82) 122.39,91.48 CPU1.AJ10
USB_ATEST1: length 1.5
  TOP w0.102: v1(121.64,92.86) 121.15,93.36 TP417.1
  BOTTOM w0.102: v1(121.64,92.86) 121.64,92.83 CPU1.AJ8
USB_CAMERA_EDP: length 3.3
  TOP w0.102: 95.61,141.52 96.32,141.52 96.56,141.28 TR5209.2 97.09,141.21 R5207.1 ; 95.61,141.52 v2(95.61,141.34) ; 95.61,141.52 LCD1.31
USB_CAMERA_EDP#: length 4.1
  TOP w0.102: v2(97.16,142.96) 97.2,142.92 97.2,142.14 TR5209.3 96.56,141.96 96.33,141.72 95.08,141.72 94.78,142.02 LCD1.30
USB_OC#0: length 109.8
  TOP w0.102: v1(166.56,72.99) 166.48,72.91 166.48,72.74 165.69,71.96 163.81,71.96 163.53,72.24 157.86,72.24 154.72,75.38 154.72,79.08 v2(146.16,87.64) 145.88,87.92 145.88,92.73 R650.1 145.24,93.99 145.45,94.19 145.8,94.19 v1(145.87,94.26)
  L3 w0.102: v1(145.87,94.26) 145.74,94.26 145.7,94.3 143.52,94.3 141.64,92.42 140.57,92.42 140.56,92.43 133.98,92.43 133.59,92.04 131.74,92.04 130.97,92.82 v1(130.97,93.48)
  L4 w0.102: v1(166.56,72.99) 166.99,72.99 168.43,71.54 168.43,69.84 168.28,69.69 168.28,67.14 167.47,66.33 167.47,62.98 169.2,61.25 169.2,60.21 168.36,59.37 168.36,50.4 162.45,44.5 162.45,38.5 163.79,37.16 163.79,35.9 159.62,31.73 v1(159.62,29.68)
  BOTTOM w0.102: CPU1.AY8 128.05,93.26 128.27,93.48 128.57,93.48 128.62,93.43 128.87,93.43 129.18,93.74 130.72,93.74 v1(130.97,93.48) ; U3503.3 158.92,29.92 159.16,29.68 v1(159.62,29.68)
USB_OC#1: length 237
  TOP w0.102: v1(158.3,87.39) v2(157.24,86.33) 156.61,85.7 156.61,83.63 156.89,83.35 156.89,81.51 156.58,81.2 156.58,76.14 158.46,74.26 158.6,74.26 158.62,74.24 158.7,74.24 158.71,74.23 v1(158.74,74.23)
  L3 w0.102: v1(82.07,64.22) 82.07,68.24 83.14,69.31 83.14,75.74 76.61,82.28 61.54,82.28 60.72,81.46 23.26,81.46 22.21,80.4 22.21,77.99 23.2,77 v1(23.2,70.02) ; v1(158.3,87.39) 151.33,87.39 150.48,88.24 150.48,92.59 148.85,94.22 148.04,94.22 v1(147.74,94.52) ; v1(158.74,74.23) 158.03,73.52 158.03,72.72 154.08,68.77 154.08,67.16 v1(153.49,66.56)
  L4 w0.102: v1(135.59,103.63) 135.71,103.74 140.34,103.74 146.18,97.9 146.18,96.06 147.72,94.52 v1(147.74,94.52)
  BOTTOM w0.102: CPU1.AW1 128.25,97.28 128.9,97.28 129.6,97.98 129.97,97.98 133.05,101.06 134.01,101.06 135.55,102.61 R631.1 135.55,103.45 135.59,103.49 v1(135.59,103.63) ; U3504.3 v1(23.2,70.02) ; v1(82.07,64.22) 82.16,64.22 89.82,56.56 90.05,56.34 141.93,56.34 148.08,62.48 148.08,63.06 151.58,66.56 v1(153.49,66.56)
USB_OC#3: length 9.2
  BOTTOM w0.102: CPU1.AY1 128.78,96.78 129.73,97.73 130.24,97.73 133.2,100.7 134.45,100.7 v2(134.6,100.85) 134.6,100.91 R637.1
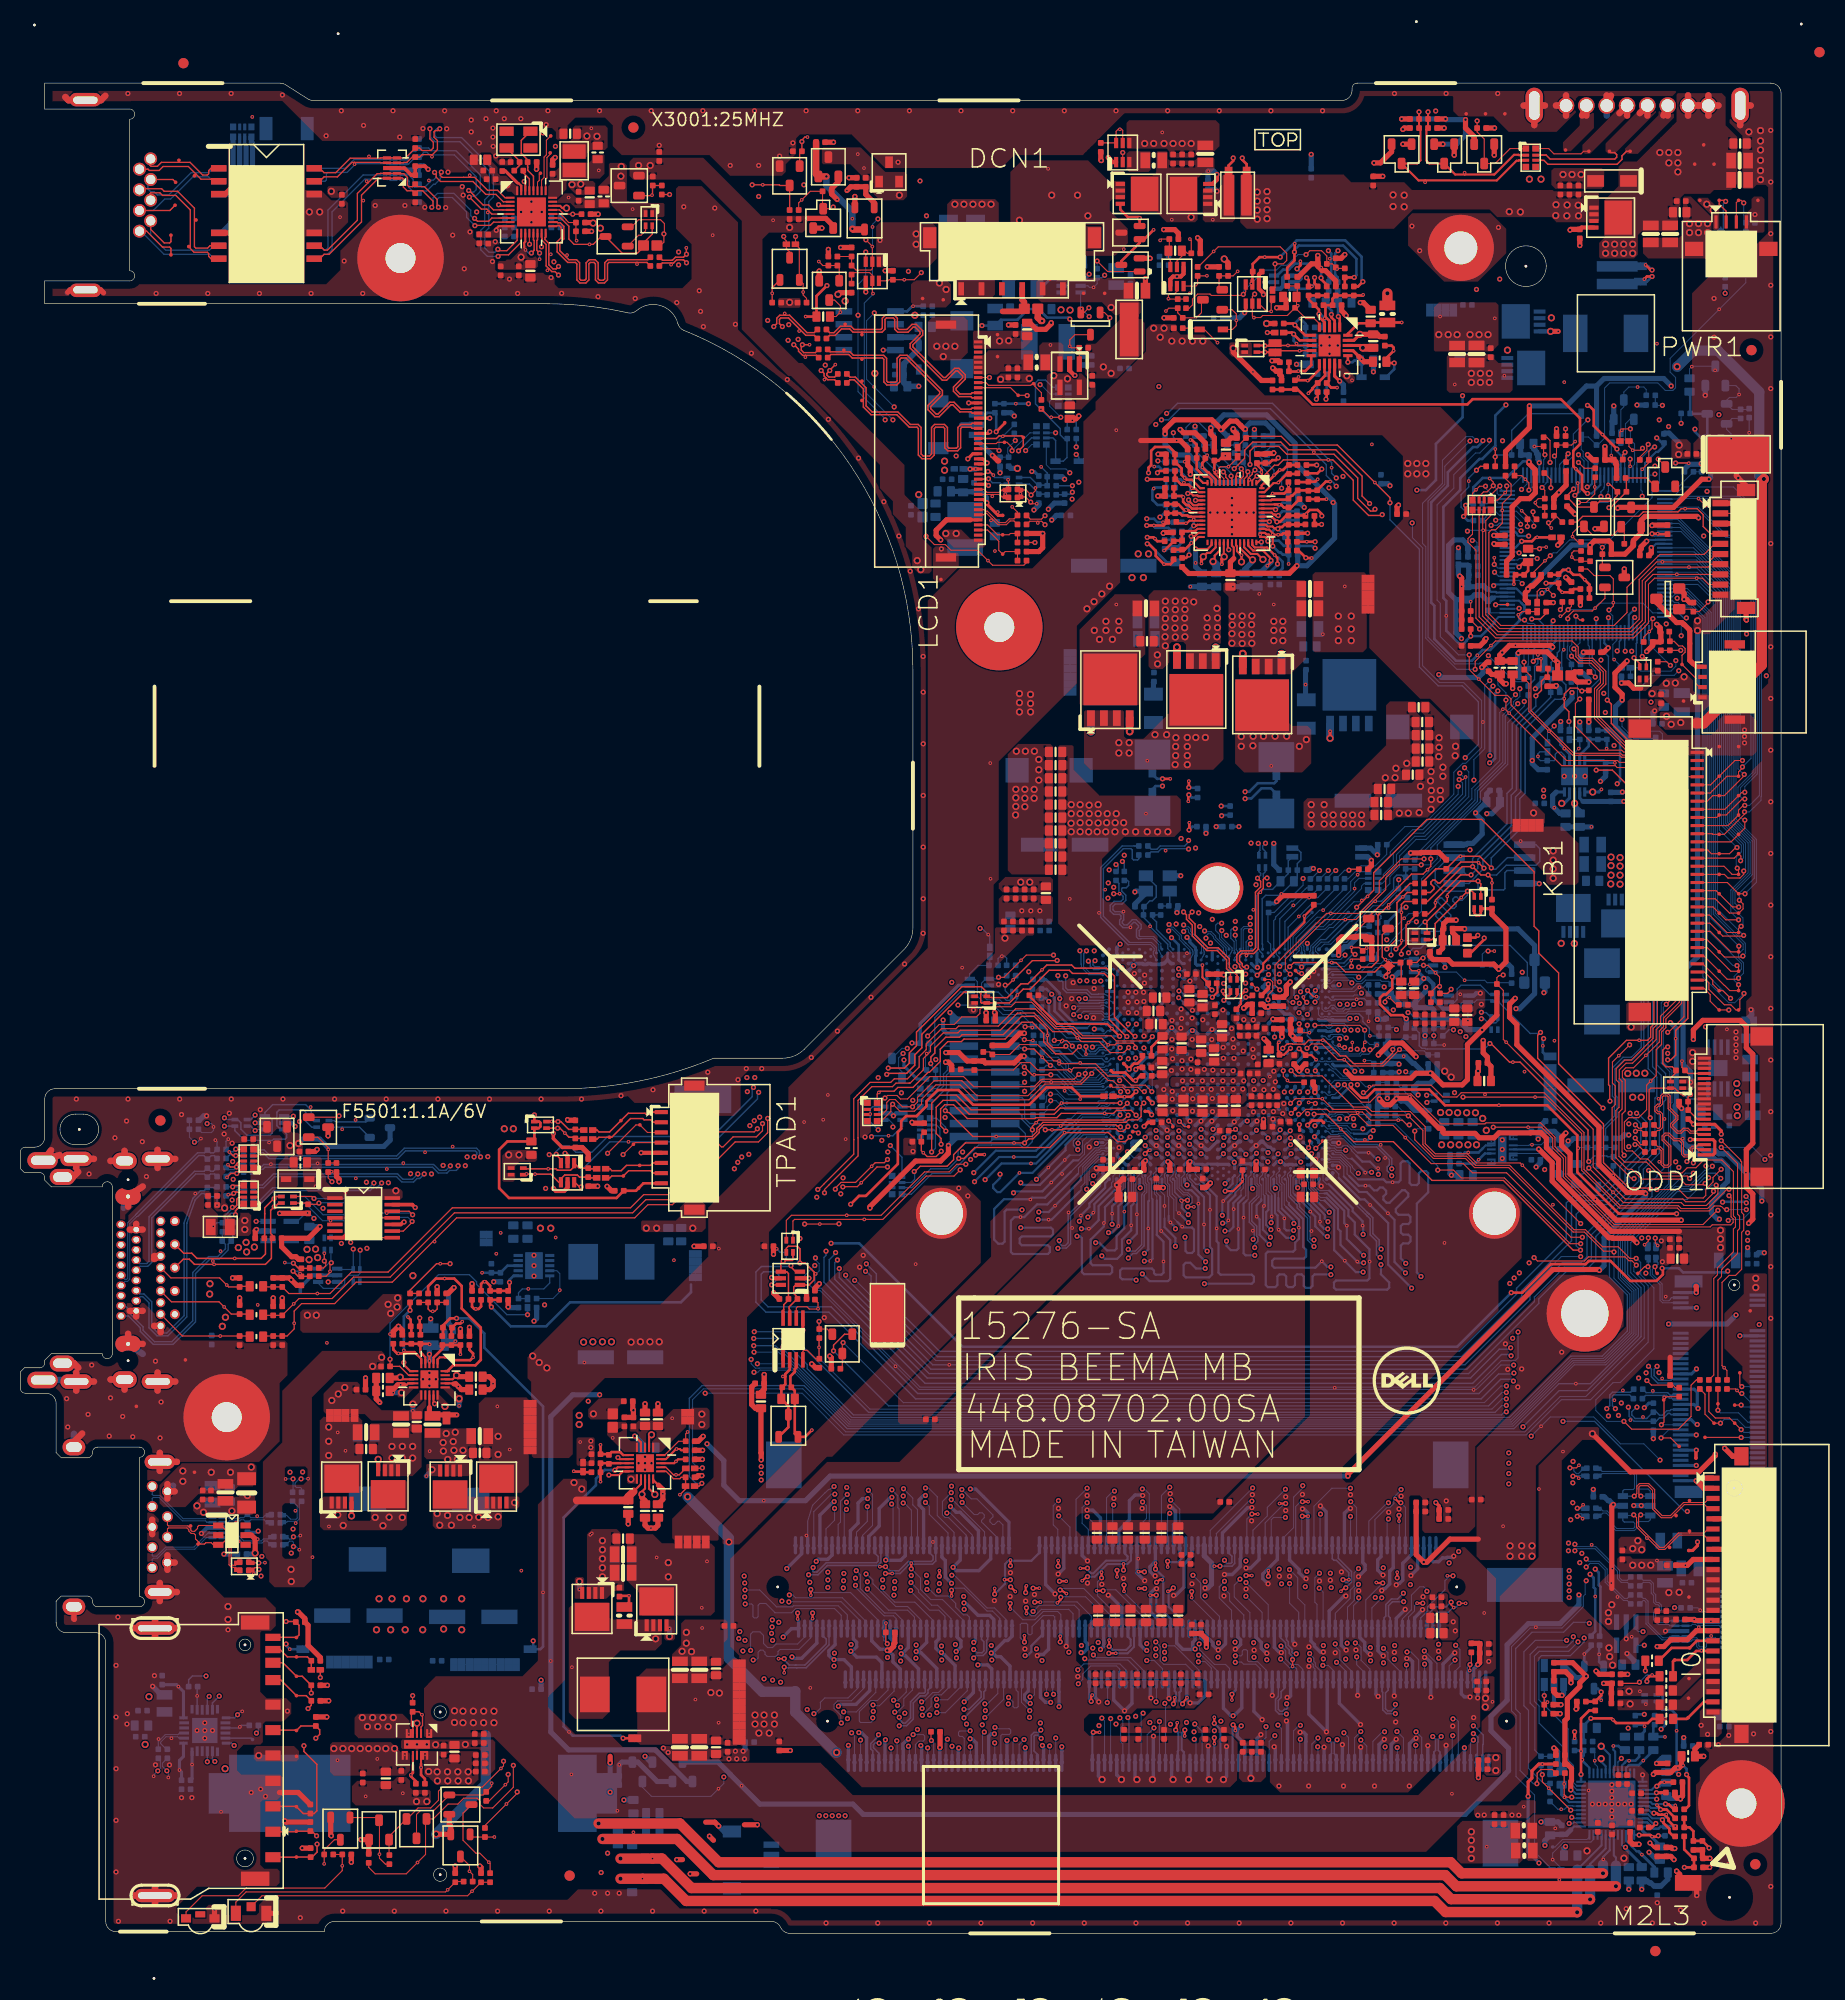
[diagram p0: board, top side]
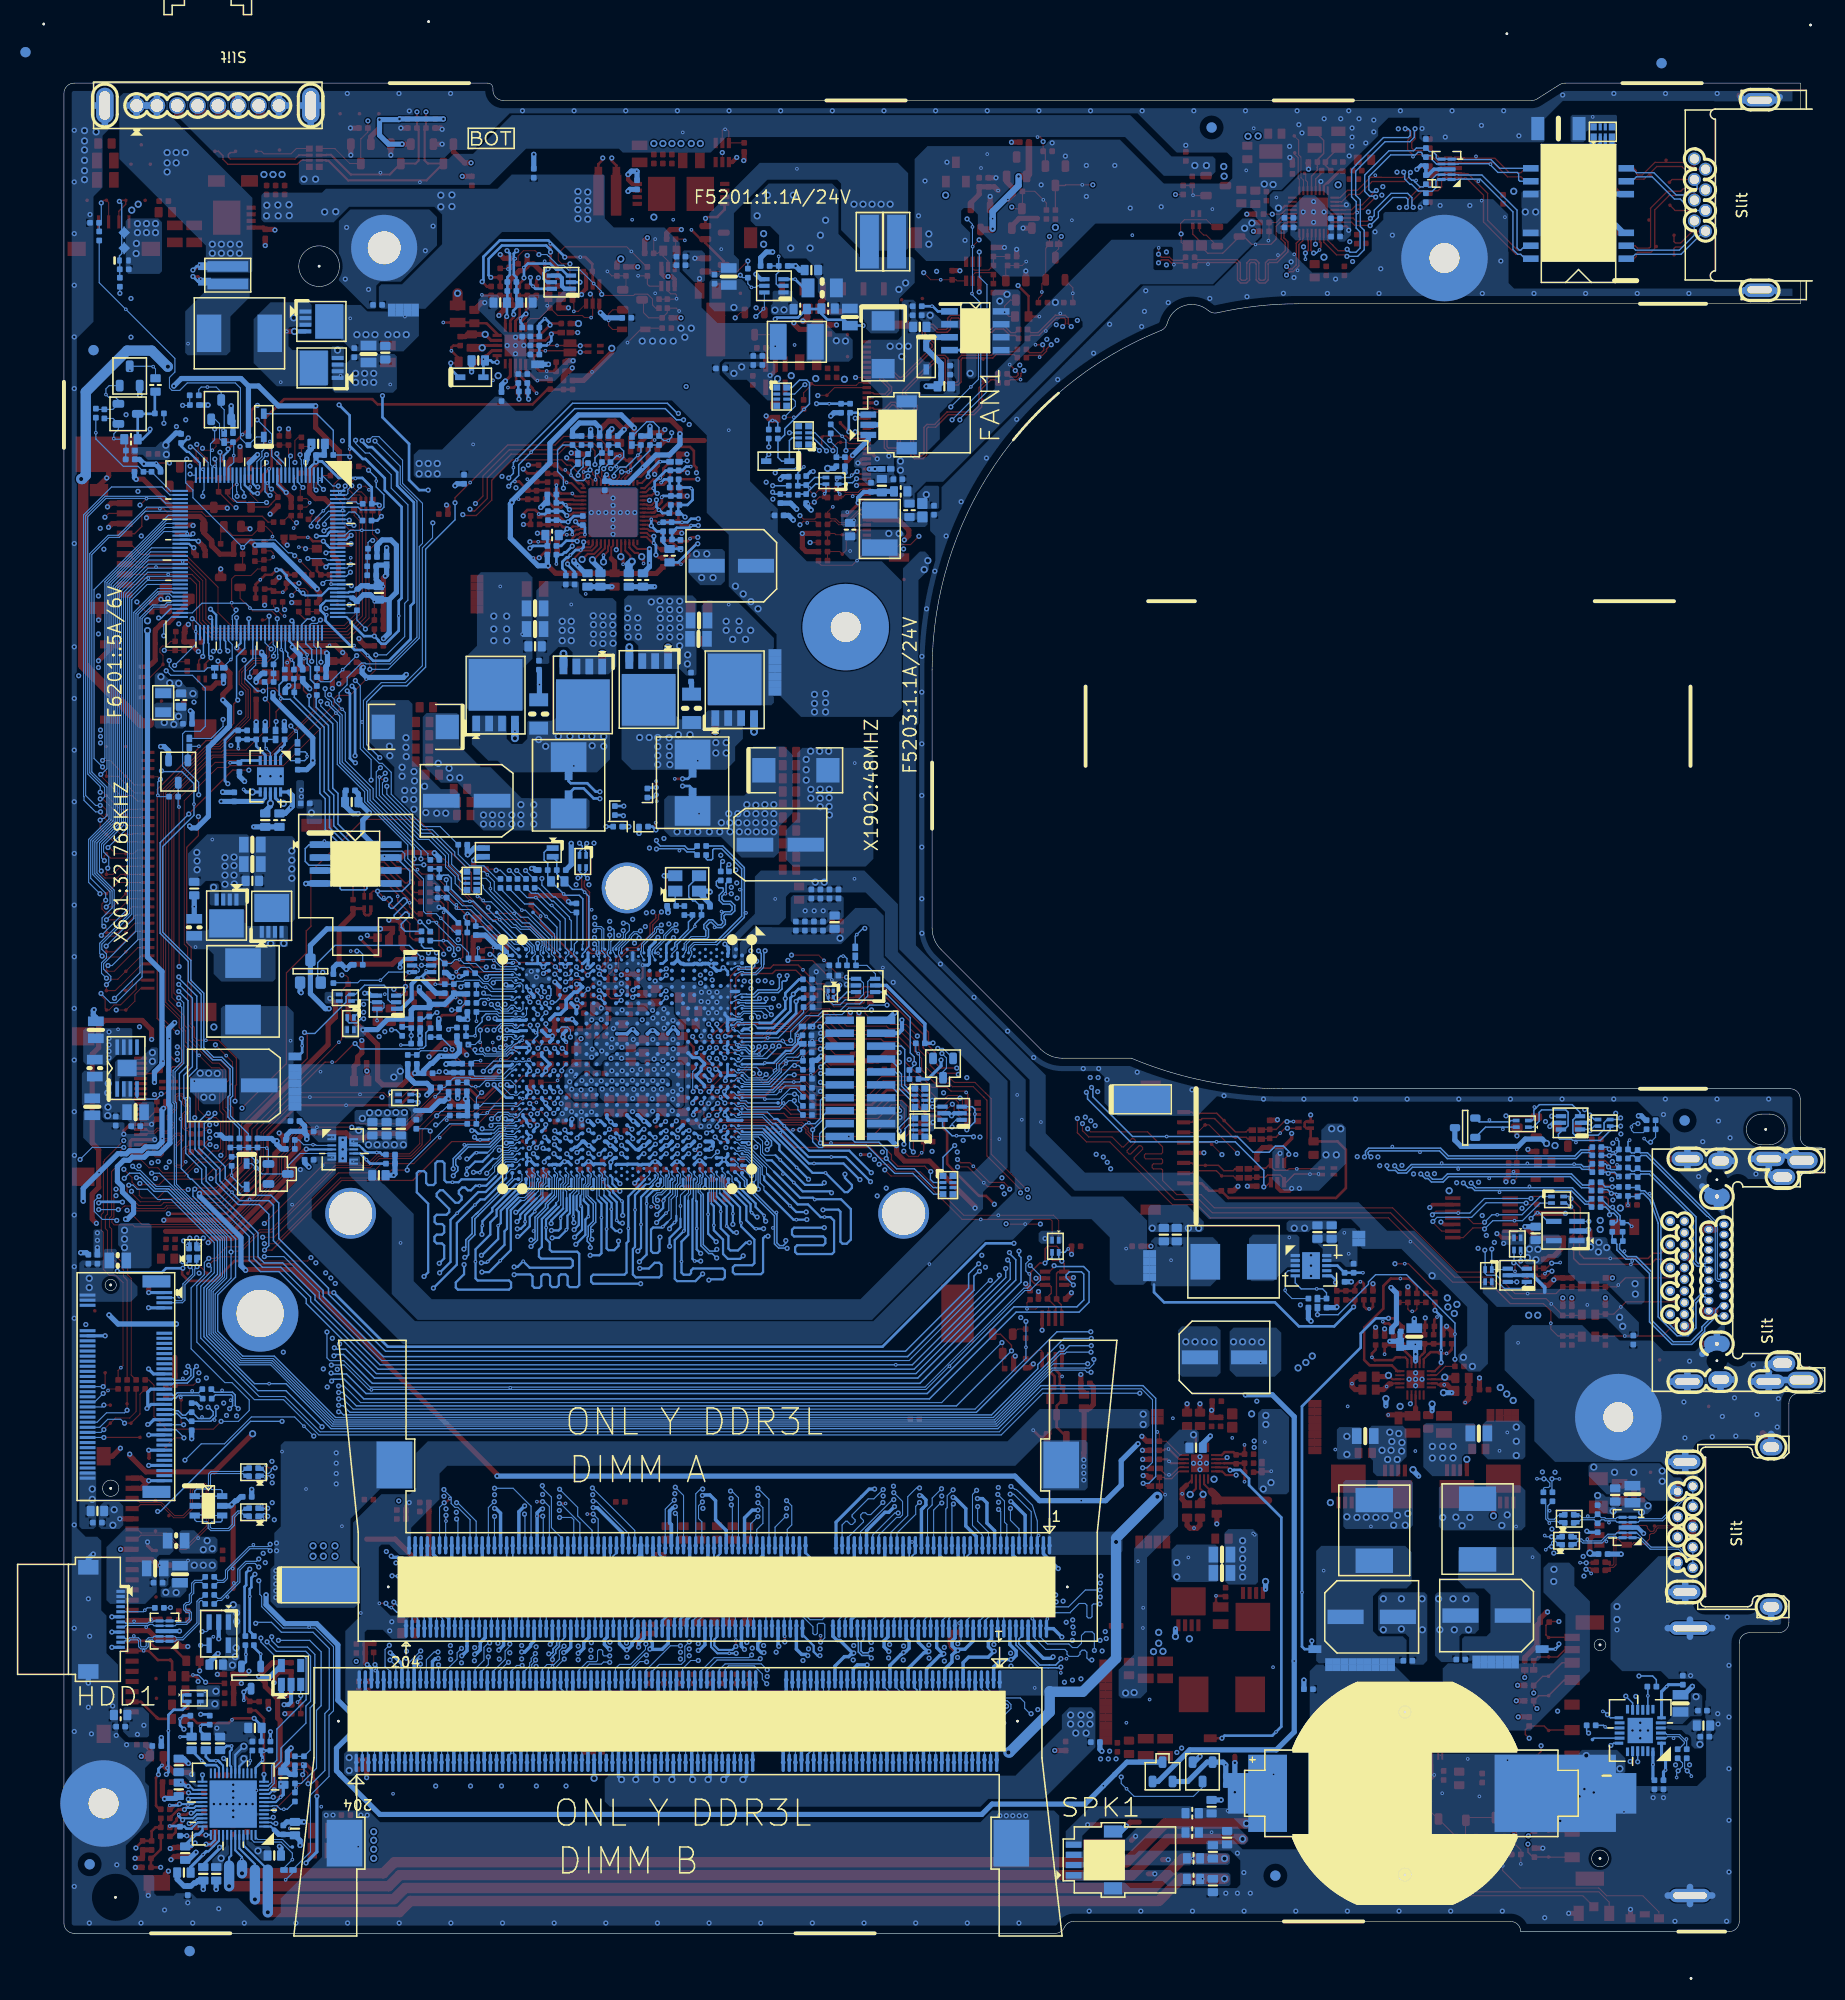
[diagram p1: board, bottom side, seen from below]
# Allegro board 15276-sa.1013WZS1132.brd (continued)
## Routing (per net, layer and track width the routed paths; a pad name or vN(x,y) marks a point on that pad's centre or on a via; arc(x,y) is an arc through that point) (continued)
USB_PN0: length 84.3
  TOP w0.102: v2(153.73,42.15) 153.39,41.81 v1(153.15,41.81)
  L4 w0.102: v1(123.85,93.57) 123.85,93.73 123.22,94.36 123.22,95.37 124.53,96.68 127.16,96.68 129.06,98.59 136.15,98.59 136.53,98.21 137.31,98.21 139.15,96.37 139.15,95.39 139.96,94.58 139.96,94.58 143.19,91.35 143.19,87.84 150.67,80.36 150.67,76.76 151.27,76.15 151.27,64.38 150.16,63.27 150.16,58.28 150.91,57.54 150.91,42.89 151.99,41.81 v1(153.15,41.81)
  BOTTOM w0.102: CPU1.AL5 v1(123.85,93.57) ; v1(153.15,41.81) 153.21,41.81 153.26,41.75 TR3406.4
USB_PN0_C: length 18.9
  TOP w0.102: 162.1,38.09 161.76,37.76 161.19,37.76 158.99,39.96 158.99,40.88 v1(158.71,41.16) ; 162.1,38.09 163.18,39.17 165.62,39.17 166.01,38.77 CN6301.7 ; 162.1,38.09 AFTP6303.1
  BOTTOM w0.102: TR3406.3 155.47,41.75 155.68,41.54 156.09,41.54 156.64,40.99 156.64,40.21 157.04,39.81 158.67,39.81 158.81,39.95 158.81,40.33 158.68,40.46 157.77,40.46 157.64,40.58 EU3404.4 158.64,41.1 v1(158.71,41.16)
USB_PN1: length 84.2
  TOP w0.102: v2(153.3,44.77) 153.11,44.95 v1(152.73,44.95)
  L4 w0.102: v1(152.73,44.95) 153.49,44.95 153.73,45.2 153.73,56.5 151,59.23 151,62.76 152.11,63.88 152.11,76.5 151.51,77.11 151.51,80.71 145.22,87 145.22,89.78 144.88,90.12 144.88,92.17 138,99.05 136.88,99.05 136.5,99.43 125.83,99.43 122.13,95.73 122.13,94.99 122.78,94.33 v1(122.78,94.3)
  BOTTOM w0.102: TR3405.1 152.78,45.01 v1(152.73,44.95) ; CPU1.AJ5 v1(122.78,94.3)
USB_PN1_C: length 19.9
  TOP w0.102: CN6301.3 166.11,42.77 165.71,42.37 164.19,42.37 ; v1(158.76,43) 159.01,43.25 159.01,43.98 159.27,44.23 160.18,44.23 160.76,43.65 160.76,41.82 161.5,41.08 162.31,41.08 163.6,42.37 164.19,42.37 ; 164.19,42.37 AFTP6301.1
  BOTTOM w0.102: TR3405.2 155.39,45.01 155.61,45.22 158.66,45.22 158.78,45.1 158.78,43.78 158.66,43.65 157.77,43.65 157.64,43.52 EU3404.6 v1(158.76,43)
USB_PN4: length 166.4
  L3 w0.102: v1(121.01,97.31) 120.77,97.55 120.55,97.55 120.37,97.37 118.42,97.37 117,95.95 107.93,95.95 106,94.02 106,93.94 v1(106.28,93.66)
  L4 w0.102: v1(106.28,93.66) 106.28,93.3 106.89,92.69 106.89,89.25 105.92,88.28 100.36,88.28 99.04,89.6 97.77,89.6 96.04,87.87 91.02,87.87 85.78,82.64 84.42,82.64 73.4,71.61 44.83,71.61 40.28,67.07 37.74,67.07 31.58,60.9 31.58,60.33 25.66,54.41 25.66,33.69 15.3,23.33 15.3,18.64 13.98,17.32 13.98,16.42 v1(14.41,15.98)
  BOTTOM w0.102: CPU1.AF2 120.55,96 120.85,96.3 120.85,96.56 120.78,96.63 120.78,97.08 v1(121.01,97.31) ; R3204.1 13.98,16.74 13.98,16.42 v1(14.41,15.98) 14.56,15.84 v2(14.56,15.33)
USB_PN4_R: length 3.8
  BOTTOM w0.102: 14.87,19.34 14.34,19.34 13.8,18.8 13.8,18.66 14.35,18.11 R3204.2 ; 14.87,19.34 v2(14.87,19.19) ; 14.87,19.34 15.48,19.34 15.62,19.2 U3201.2
USB_PN5: length 67.4
  TOP w0.102: v2(159.77,67.73) 160.14,68.1 v1(160.14,68.4)
  L4 w0.102: v1(160.14,68.4) 160.28,68.54 160.33,68.59 160.33,68.84 160.17,69 157.49,69 153.62,72.86 153.62,79.43 153.02,80.03 153.02,81.34 146.73,87.62 146.73,90.4 146.39,90.75 146.39,92.8 139.57,99.62 139.57,100.03 138.9,100.7 138.24,101.36 131.27,101.36 130.89,100.98 125.02,100.98 122.82,98.78 121.18,98.78 v1(121.01,98.6)
  BOTTOM w0.102: v1(160.14,68.4) 160.17,68.38 TR5801.3 ; v1(121.01,98.6) 120.79,98.82 120.42,98.82 120.29,98.69 120.29,96.91 120.3,96.91 120.3,96.61 120,96.31 CPU1.AE2
USB_PN5_R: length 8
  TOP w0.102: v1(160.1,65.57) 159.77,65.57 AFTP5806.1
  BOTTOM w0.102: WLAN1.5 161.54,62.02 161.3,62.27 161.3,63.78 160.33,64.75 160.33,65.34 v1(160.1,65.57) 160.13,65.6 160.13,65.87 160.17,65.91 TR5801.4
USB_PN6: length 81.4
  TOP w0.102: v2(108.14,102.25) v1(107.55,102.25) ; R5203.2 99.35,139.09 100.45,139.09 v1(100.8,139.43)
  L3 w0.102: v1(119.51,98.17) 119.24,98.44 119.03,98.44 118.68,98.79 118.68,99.7 120.48,101.5 120.48,104.56 119.49,105.55 114.21,105.55 113.78,105.98 110.01,105.98 109.05,105.02 109.05,102.96 108.33,102.25 v1(107.55,102.25)
  L4 w0.102: v1(107.55,102.25) 104.82,102.25 103.03,104.04 96.89,104.04 92.91,108.02 92.91,131.72 99.12,137.93 99.12,138.57 99.85,139.3 100.67,139.3 100.8,139.43 v1(100.8,139.43)
  BOTTOM w0.102: v1(119.51,98.17) 119.52,98.16 119.52,97.74 119.61,97.66 119.61,96.74 119.75,96.6 119.75,96.26 119.45,95.96 CPU1.AD2
USB_PN6_TPNL: length 5.7
  TOP w0.102: v2(97.57,140.3) 98.09,139.77 R5203.1 97.75,139.11 97.28,139.11 96.91,138.75 96.25,138.75 95.13,139.87 94.94,139.87 94.79,140.02 LCD1.34
USB_PN7: length 72.2
  TOP w0.102: v2(99.85,142.15) 99.85,141.9 v1(99.42,141.46) 98.93,141.96 TR5209.4
  L4 w0.102: v1(99.42,141.46) 99.25,141.29 98.9,141.29 98.28,140.66 98.28,138.28 92.07,132.07 92.07,107.67 97.57,102.17 103.34,102.17 105.81,99.71 116.22,99.71 117.12,98.81 117.29,98.63 v1(118.18,98.63)
  BOTTOM w0.102: v1(118.18,98.63) 118.17,98.62 118.17,97.94 119.2,96.91 119.2,96.65 CPU1.AC2
USB_PN8: length 141.2
  TOP w0.102: TR3404.4 22.81,36.44 22.82,36.43 v1(23.45,36.43)
  L3 w0.102: v1(104.22,93.69) 104.22,94.49 104.51,94.78 105.83,95.16 107.48,96.81 110.45,96.81 114.26,97.3 114.9,97.45 115.88,98.44 116.34,98.44 v1(116.49,98.59)
  L4 w0.102: v1(23.45,36.43) 23.79,36.43 24.54,37.19 24.54,54.8 30.51,60.77 30.51,61.35 37.3,68.13 39.84,68.13 44.39,72.68 72.96,72.68 83.98,83.7 85.34,83.7 90.57,88.94 95.32,88.94 97.04,90.66 99.14,90.66 100.67,89.13 104.89,89.13 105.39,89.62 105.77,89.62 106.05,89.9 106.05,91.48 104.38,93.15 104.38,93.53 v1(104.22,93.69)
  BOTTOM w0.102: v1(116.49,98.59) 116.57,98.51 117.15,98.51 117.58,98.08 117.58,97.94 117.78,97.75 117.78,97.74 118.59,96.93 118.59,96.65 118.65,96.6 118.65,96.3 CPU1.AB2 ; v2(24.06,36.46) 24.04,36.43 v1(23.45,36.43)
USB_PN8_C: length 12
  TOP w0.102: USB1.2 14.47,40.17 14.57,40.07 16.49,40.07 16.62,39.94 ; 16.62,39.94 16.77,39.79 16.77,39.66 16.9,39.53 17.14,39.53 17.43,39.82 17.43,39.99 17.56,40.12 EU3403.1 19.74,40.12 20.73,39.13 20.73,36.33 20.87,36.2 21.17,36.2 TR3404.3 ; 16.62,39.94 AFTP3402.1
USB_PP0: length 84.2
  TOP w0.102: v1(153.15,41.02) 153.44,41.02 v2(153.68,40.78)
  L4 w0.102: v1(123.86,94.34) 123.57,94.34 123.45,94.46 123.45,95.28 124.63,96.45 127.25,96.45 129.16,98.36 136.06,98.36 136.43,97.98 137.21,97.98 138.92,96.28 138.92,95.29 139.87,94.35 142.96,91.25 142.96,87.75 150.44,80.27 150.44,76.66 151.05,76.06 151.05,64.48 149.93,63.36 149.93,58.19 150.68,57.44 150.68,42.79 151.89,41.58 152.55,41.58 152.66,41.46 152.66,41.14 152.79,41.02 v1(153.15,41.02)
  BOTTOM w0.102: TR3406.1 153.74,41.07 153.55,41.26 153.28,41.26 153.15,41.13 v1(153.15,41.02) ; CPU1.AL4 123.3,94.38 123.48,94.19 123.73,94.19 123.86,94.32 v1(123.86,94.34)
USB_PP0_C: length 18.9
  TOP w0.102: AFTP6304.1 164.19,39.37 ; 164.19,39.37 165.62,39.37 166.01,39.77 CN6301.6 ; 164.19,39.37 163.09,39.37 161.68,37.96 161.27,37.96 159.19,40.04 159.19,40.96 v1(159.39,41.16)
  BOTTOM w0.102: v1(159.39,41.16) 160.27,41.16 EU3404.3 160.33,40.68 160.15,40.5 159.14,40.5 159.01,40.37 159.01,39.86 158.76,39.61 156.95,39.61 156.43,40.13 156.43,40.9 156,41.34 155.68,41.34 155.42,41.07 TR3406.2
USB_PP1: length 84.5
  TOP w0.102: v1(152.43,45.78) 153.07,45.78 v2(153.32,46.04)
  L4 w0.102: v1(152.43,45.78) 152.71,45.78 152.84,45.65 152.84,45.45 153.11,45.18 153.39,45.18 153.5,45.29 153.5,56.41 150.77,59.14 150.77,62.86 151.88,63.97 151.88,76.4 151.28,77.01 151.28,80.62 144.99,86.9 144.99,89.68 144.65,90.02 144.65,92.08 137.91,98.82 136.78,98.82 136.4,99.2 125.92,99.2 122.36,95.63 122.36,95.08 122.49,94.96 122.69,94.96 v1(122.78,95.05)
  BOTTOM w0.102: TR3405.4 153.68,45.69 153.55,45.56 153.55,45.49 153.27,45.21 153.08,45.21 152.81,45.48 152.81,45.66 152.69,45.78 v1(152.43,45.78) ; v1(122.78,95.05) 122.78,94.9 122.57,94.68 CPU1.AJ4
USB_PP1_C: length 19.9
  TOP w0.102: CN6301.4 166.07,41.77 165.67,42.17 163.69,42.17 162.74,41.22 ; 162.74,41.22 162.4,40.88 161.42,40.88 160.56,41.73 160.56,43.56 160.1,44.03 159.35,44.03 159.21,43.89 159.21,43.19 v1(159.41,43) ; 162.74,41.22 AFTP6302.1
  BOTTOM w0.102: TR3405.3 155.34,45.69 155.61,45.43 158.74,45.43 158.99,45.18 158.99,43.83 159.11,43.7 160.13,43.7 160.33,43.5 EU3404.1 v1(159.41,43)
USB_PP4: length 166.4
  L3 w0.102: v1(105.65,93.61) 105.77,93.74 105.77,94.12 107.83,96.18 116.91,96.18 118.33,97.6 120.28,97.6 120.45,97.78 120.84,97.78 v1(121.01,97.94)
  L4 w0.102: v1(105.65,93.61) 106.12,93.14 106.66,92.59 106.66,89.34 105.83,88.51 100.45,88.51 99.14,89.83 97.67,89.83 95.94,88.1 90.92,88.1 85.69,82.87 84.33,82.87 73.3,71.84 44.73,71.84 40.19,67.3 37.65,67.3 31.35,61 31.35,60.42 25.43,54.5 25.43,33.79 15.07,23.42 15.07,18.73 13.75,17.41 13.75,16.21 v1(13.52,15.98)
  BOTTOM w0.102: v1(121.01,97.94) 120.57,97.51 120.57,96.46 CPU1.AF1 ; v2(13.11,15.45) 13.11,15.57 v1(13.52,15.98) 13.77,16.23 13.77,17.02 R3205.1
USB_PP4_R: length 3.8
  BOTTOM w0.102: 13.71,19 13.57,18.86 R3205.2 ; 13.71,19 14.26,19.54 15.5,19.54 15.66,19.7 U3201.3 ; 13.71,19 v2(13.6,19.11)
USB_PP5: length 67.4
  TOP w0.102: v1(160.83,68.38) 160.83,67.89 v2(161.07,67.65)
  L4 w0.102: v1(160.83,68.38) 160.83,68.4 160.56,68.67 160.56,68.93 160.26,69.23 157.58,69.23 153.85,72.96 153.85,79.52 153.25,80.13 153.25,81.43 146.96,87.72 146.96,90.5 146.62,90.84 146.62,92.9 139.79,99.72 139.79,100.13 139.13,100.79 138.34,101.59 131.18,101.59 130.8,101.2 124.92,101.2 122.73,99.01 121.23,99.01 121.01,99.24 v1(120.99,99.24)
  BOTTOM w0.102: v1(120.99,99.24) 120.77,99.02 120.34,99.02 120.09,98.77 120.09,96.87 CPU1.AE1 ; v1(160.83,68.38) 160.85,68.35 TR5801.2
USB_PP5_R: length 7.6
  TOP w0.102: AFTP5807.1 160.85,65.08 160.85,65.52 v1(160.8,65.57)
  BOTTOM w0.102: TR5801.1 160.85,66.22 161.09,65.97 161.09,65.8 160.87,65.57 v1(160.8,65.57) 160.54,65.3 160.54,64.83 161.5,63.87 161.5,62.35 161.63,62.22 162.19,62.22 162.31,62.35 162.31,62.42 162.41,62.52 WLAN1.3
USB_PP6: length 81
  TOP w0.102: v1(100.8,138.54) 100.45,138.89 100.08,138.89 ; v2(100.08,138.72) 100.08,138.89 ; 100.08,138.89 99.3,138.89 R5204.2
  L3 w0.102: v1(119.51,98.81) 119.37,98.66 119.13,98.66 118.9,98.89 118.9,99.6 120.71,101.41 120.71,104.65 119.58,105.78 114.31,105.78 113.88,106.21 109.91,106.21 108.82,105.12 108.82,103.06 108.24,102.47 107.93,102.47 107.78,102.63 107.78,102.65 v1(107.55,102.88)
  L4 w0.102: v1(100.8,138.54) 100.8,138.64 100.36,139.08 99.95,139.08 99.35,138.47 99.35,137.84 93.14,131.63 93.14,108.11 96.98,104.27 103.13,104.27 104.92,102.47 107.17,102.47 107.35,102.65 107.35,102.68 v1(107.55,102.88)
  BOTTOM w0.102: v1(119.51,98.81) 119.2,98.81 119.08,98.69 119.08,98.36 119.08,98.35 119.08,97.87 119.4,97.54 119.4,96.66 119.45,96.61 CPU1.AD1
USB_PP6_TPNL: length 4.9
  TOP w0.102: R5204.1 97.75,138.91 97.36,138.91 96.99,138.54 96.17,138.54 95.61,139.1 ; v2(95.49,138.97) 95.61,139.1 ; 95.61,139.1 95.04,139.67 94.94,139.67 94.79,139.52 LCD1.35
USB_PP7: length 72
  TOP w0.102: TR5209.1 98.87,141.28 v1(99.39,140.76) 99.55,140.6 v2(99.98,140.6)
  L4 w0.102: v1(118.17,99.35) 118.17,99.25 117.88,98.96 117.83,98.96 117.73,98.86 117.39,98.86 116.31,99.93 105.9,99.93 103.44,102.4 97.67,102.4 92.3,107.77 92.3,131.98 98.51,138.19 98.51,140.57 99,141.06 99.09,141.06 v1(99.39,140.76)
  BOTTOM w0.102: CPU1.AC1 118.9,96.92 117.96,97.85 117.96,98.24 117.58,98.62 117.58,99.16 117.77,99.35 v1(118.17,99.35)
USB_PP8: length 141.3
  TOP w0.102: TR3404.1 22.85,35.76 23.05,35.95 23.33,35.95 v1(23.48,35.8)
  L3 w0.102: v1(116.63,97.88) 116.59,97.88 116.26,98.21 115.98,98.21 115.01,97.24 114.3,97.08 110.46,96.58 107.58,96.58 106.02,95.02 105.99,94.97 104.63,94.57 104.45,94.4 104.45,94.07 104.83,93.69 v1(104.91,93.69)
  L4 w0.102: v1(104.91,93.69) 104.6,93.38 104.6,93.25 106.28,91.57 106.28,89.81 105.87,89.39 105.48,89.39 104.99,88.9 100.58,88.9 99.04,90.43 97.14,90.43 95.41,88.71 90.67,88.71 85.44,83.48 84.08,83.48 73.05,72.45 44.48,72.45 39.94,67.91 37.4,67.91 30.74,61.25 30.74,60.67 24.77,54.7 24.77,37.09 23.88,36.2 23.88,35.93 23.76,35.8 v1(23.48,35.8)
  BOTTOM w0.102: v1(23.48,35.8) 23.38,35.8 v2(22.97,35.39) ; v1(116.63,97.88) 116.63,98.09 116.85,98.31 117.07,98.31 117.38,98 117.38,97.86 117.58,97.66 117.58,97.66 118.35,96.89 CPU1.AB1
USB_PP8_C: length 11.9
  TOP w0.102: TR3404.2 21.17,35.99 20.78,35.99 20.53,36.25 20.53,38.64 20.4,38.77 20.3,38.77 19.74,38.21 EU3403.3 18.98,38.21 18.78,38.42 18.24,38.42 18.12,38.29 17.74,38.29 17.61,38.42 ; AFTP3403.1 17.61,38.42 ; 17.61,38.42 17.23,38.8 17.23,39.17 17.07,39.33 16.81,39.33 16.57,39.58 16.57,39.7 16.4,39.87 14.57,39.87 14.47,39.77 USB1.3
USB_PWR_EN#: length 287
  TOP w0.127: R2429.1 150.1,129.84 149.52,129.27 v1(148.67,129.27)
  L3 w0.127: v1(169.81,127.8) 169.73,127.8 167.34,130.19 160.27,130.19 157.67,127.58 153.89,127.58 153.87,127.6 150.9,127.6 149.28,129.22 148.72,129.22 v1(148.67,129.27) ; v1(151.75,50.35) 150.81,51.29 v1(146.18,51.29) ; v1(72.14,58.51) 72.04,58.51 69.58,60.97 51.29,60.97 51.16,61.1 49.13,63.13 48.37,63.13 46.08,65.42 41.26,65.42 40.75,65.92 32.42,65.92 28.88,69.47 v1(28.88,70.31)
  L4 w0.127: v1(159.75,28.33) 159.94,28.52 159.99,28.52 161.64,30.17 162.15,30.17 165.07,33.1 165.07,37.69 163.98,38.78 v1(163.98,41.5) 167.47,44.98 168.16,44.98 171.72,48.54 171.72,66.14 170.77,67.09 170.77,73.16 170.43,73.51 170.43,78.9 170.68,79.15 170.68,122.99 169.36,124.31 169.36,125.34 169.81,125.79 v1(169.81,127.8)
  BOTTOM w0.127: v1(163.98,41.5) 163.71,41.5 154.85,50.35 v1(151.75,50.35) ; v1(148.67,129.27) 149.26,129.27 149.82,128.71 KBC24.91 ; U3503.4 v1(159.75,28.33) ; U3504.4 27.25,70.02 28.07,70.85 v2(28.25,70.85) 28.36,70.85 28.88,70.33 v1(28.88,70.31) ; v1(72.14,58.51) 74.83,58.51 77.4,55.94 77.4,55.54 81.95,50.99 145.7,50.99 146.01,51.29 v1(146.18,51.29)
USB_RCOMP: length 10
  TOP w0.203: v1(121.67,94.23) 122.26,94.83 122.26,95.39 126.31,99.44 v2(126.31,100.05) 127.24,100.98 R1902.2
  BOTTOM w0.203: CPU1.AG4 121.22,94.68 v1(121.67,94.23)
USB_SS_ZVDD_095: length 3
  TOP w0.203: v1(120.54,92.74) 120.36,92.55 120.34,92.55 120.07,92.28 120.07,92.21 120.06,92.21 120.06,91.4 119.86,91.2 119.86,91.12 R1910.1
  BOTTOM w0.203: CPU1.AE8 120.45,92.74 v1(120.54,92.74)
USB_SS_ZVSS: length 1.5
  TOP w0.203: R1909.1 121.01,92.07 v1(120.54,92.07)
  BOTTOM w0.203: CPU1.AE10 120,91.53 v1(120.54,92.07)
VCORE_EN: length 107.7
  TOP w0.127: v1(160.92,110.09) 156.6,114.4 v1(155.01,114.4) ; v1(134.73,140.7) 134.73,141.2 v2(133.24,142.69) 129.55,146.38 124.89,146.38 124.04,147.23 120.72,147.23 PC4660.2 119.74,146.25 PR4609.1
  L4 w0.127: v1(155.01,114.4) 153.15,116.27 142.76,116.27 v1(142.13,115.63)
  BOTTOM w0.127: v1(134.73,140.7) 134.73,139.03 137.62,136.13 137.62,124.54 139.47,122.69 141.85,122.69 143.42,121.12 143.42,116.93 v1(142.13,115.63) ; v1(160.92,110.09) 163.74,107.27 163.74,98.36 160.97,95.59 160.97,93.64 159.84,92.51 159.84,92.5 159.7,92.36 159.7,87.03 158.58,85.91 157.76,85.91 156.86,85.02 156.86,82.46 157.07,82.25 157.07,80.28 155.94,79.15 R3605.2
VD1_EN#: length 4.4
  TOP w0.102: v1(160.59,129.3) 160.51,129.22 160.51,128.31 v2(160.24,128.04) 159.68,127.48 R2447.2
  BOTTOM w0.102: KBC24.66 159.82,128.6 160.51,129.3 v1(160.59,129.3)
VD_IN1: length 53.1
  TOP w0.254: R2622.2 C2615.1 154.35,132.66 v2(153.89,133.13) 153.4,133.61 152.76,133.61 v1(152.28,134.1) 151.73,134.1 C2616.1 151.25,133.61 R2611.2 ; v1(143.36,98.16) 143.14,97.93 R2610.1
  L3 w0.254: v1(144.53,115.12) 145.2,114.45 145.2,100 v1(143.36,98.16)
  L4 w0.254: v1(145.33,122.2) 145.65,122.52 145.65,123.11 145.95,123.4 148.56,123.4 149.84,124.68 149.84,131.66 v1(149.69,131.81)
  BOTTOM w0.203: v1(149.69,131.81) 149.46,131.58 147.85,131.58 147.16,132.27 KBC24.104
  BOTTOM w0.254: v1(152.28,134.1) 151.85,134.1 151.32,133.56 151.32,133.3 149.82,131.81 v1(149.69,131.81) ; v1(145.33,122.2) 145.07,121.93 145.07,115.56 144.63,115.12 v1(144.53,115.12)
VD_IN1_C: length 46.7
  TOP w0.254: R2610.2 142.65,96.4 144,97.75 v1(144,97.89) ; C2615.2 152.8,132.22 R2612.1 152.48,131.9 v2(151.67,131.9) 151.32,132.25 C2616.2 v1(150.08,132.79)
  L3 w0.254: v1(144.56,115.82) 145.71,114.67 145.71,99.6 v1(144,97.89)
  L4 w0.254: v1(144.86,122.67) 145.14,122.95 145.14,123.32 145.74,123.91 148.35,123.91 149.33,124.9 149.33,131.45 149.18,131.6 149.18,132.02 149.95,132.79 v1(150.08,132.79)
  BOTTOM w0.254: v1(144.86,122.67) 144.56,122.36 v1(144.56,115.82)
VD_OUT1#: length 5.6
  TOP w0.254: v1(147.43,134.38) 147.91,134.86 R2607.1 148.32,134.01 R2602.1 R2624.2 146.92,133.45 v2(146.92,132.7)
  BOTTOM w0.203: v1(147.43,134.38) 147.14,134.67 KBC24.110
VRAM SIZE1: length 9.4
  BOTTOM w0.102: CPU1.BA22 128.93,84.93 129.05,84.81 129.13,84.81 129.84,84.1 131.78,84.1 131.81,84.07 132.66,84.07 132.67,84.07 133.15,84.07 133.22,84.14 134.82,84.14 134.9,84.07 134.94,84.07 R638.2 135.36,83.58 135.74,83.2 R641.1 136.19,82.78 v2(136.68,82.28)
VTT_CT_0.95V: length 3.6
  BOTTOM w0.203: U3603.12 144.15,77.5 143.87,77.23
  BOTTOM w0.254: C3619.1 141.89,76.59 142.09,76.8 v2(142.43,76.8) 143.44,76.8 143.87,77.23
VTT_CT_1.8V: length 3.6
  BOTTOM w0.203: U3603.10 144.06,76.7
  BOTTOM w0.254: C3618.1 143.07,75.7 v2(143.45,76.08) 144.06,76.7
WHITE_LED_BAT: length 8.4
  TOP w0.102: R6101.2 46.21,6.87 v2(46.08,7) 45.19,7.88 44.81,7.88 43.54,9.15 43.54,11.82 Q6103.C
WIFI_RF_EN: length 94.5
  TOP w0.102: v1(152.81,126.33) 153.02,126.12 153.02,125.57 153.4,125.18 154.59,125.18 155.71,124.06 155.71,122.92 155.07,122.29 155.07,119.58 157.93,116.72 158.95,116.72 163.42,112.25 163.42,91.47 161.87,89.92 161.87,89.08 161.45,88.66 161.45,87.44 160.92,86.9 160.92,84.36 v2(160.37,83.82) 159.98,83.42 159.98,81.01 159.19,80.22 158.22,80.22 157.79,79.79 157.79,77.16 158,76.95 158.58,76.95 159.37,76.16 160.08,76.16 161.45,74.79 163.46,74.79 163.96,75.3 164.83,75.3 165.59,76.06 167.37,76.06 168.51,74.92 168.51,70.57 168.71,70.36 168.71,69.49 168.51,69.28 168.51,67.03 166.94,65.46 166.94,64.76 166.58,64.41 166.58,54.91 R5805.1
  BOTTOM w0.102: v1(152.81,126.33) 153.42,126.93 KBC24.82
WLAN_DISABLE#1: length 7.8
  TOP w0.102: R5805.2 166.1,51.32 166.73,50.68 168.13,50.68 AFTP5803.1 v1(169.27,49.54)
  BOTTOM w0.102: WLAN1.56 169.54,49.27 v1(169.27,49.54)
WLAN_WAKE: length 4.4
  TOP w0.102: TP5801.1 162.34,48.73 v1(161.4,48.73)
  BOTTOM w0.102: v1(161.4,48.73) 161.4,48.78 162.14,49.52 WLAN1.55

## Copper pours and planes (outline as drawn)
5V_HDD_S0 on BOTTOM: 165.21,32.4 164.07,33.54 164.07,36.97 163.81,37.22 162.8,37.22 162.41,37.6 162.41,39.63 162.67,39.89 167.11,39.89 169.02,37.98 169.02,32.78 168.64,32.4 ; 2 cut-outs
5V_HDMI_CRT_S0 on TOP: 30.23,70.19 30.18,70.24 30.18,70.52 30.21,70.55 31.91,70.55 32.06,70.7 32.06,72.05 31.96,72.15 29.95,72.15 29.19,72.91 28.3,72.91 27.79,73.42 27.79,76.21 27.92,76.34 29.5,76.34 29.65,76.19 29.65,74.86 30.08,74.43 30.08,73.92 30.77,73.24 37.35,73.24 37.6,72.99 37.6,72.38 37.35,72.12 33.54,72.12 33.26,71.84 33.26,70.42 33.03,70.19 ; 1 cut-out
5V_HDMI_CRT_S0 on TOP: 20.05,68.59 19.92,68.72 19.92,70.62 20.17,70.88 22.46,70.88 22.71,70.62 22.71,68.84 22.46,68.59
5V_HDMI_CRT_S0 on BOTTOM: 29.5,67.73 29.37,67.85 29.37,69.07 29.5,69.2 31.63,69.2 31.78,69.05 31.78,67.88 31.63,67.73
5V_HDMI_CRT_S0 on L4: 21.44,69.1 21.83,68.72 28.18,68.72 30.59,71.13 37.45,71.13 37.57,71.26 37.57,73.16 37.19,73.54 24.24,73.54 21.44,70.75
5V_HDMI_CRT_S0_R on TOP: 12.43,66 12.02,66.41 12.02,68.46 11.72,68.77 10.9,68.77 10.62,69.05 10.62,70.62 13.04,73.04 18.52,73.04 18.78,72.78 18.78,71.38 19.41,70.75 19.41,68.72 19.16,68.46 16.75,68.46 16.62,68.59 16.62,70.37 16.01,70.98 13.67,70.98 13.19,70.5 13.19,67.4 13.44,67.14 14.36,67.14 14.54,66.97 14.54,66.18 14.36,66 ; 2 cut-outs
5V_PWR on BOTTOM: 41.26,26.55 41.13,26.68 41.13,28.84 41.51,29.22 43.92,29.22 44.43,29.73 44.43,33.16 43.67,33.92 41.13,33.92 40.62,34.43 40.62,37.48 41.26,38.11 49.51,38.11 50.02,37.6 50.02,26.81 49.77,26.55 ; 1 cut-out
5V_S0 on TOP: 161.78,118.37 161.27,118.88 161.27,120.03 161.4,120.15 162.41,120.15 162.92,119.64 165.08,119.64 165.21,119.52 165.21,118.63 164.95,118.37
5V_S0 on TOP: 25.64,73.29 25.38,73.54 25.38,75.7 26.02,76.34 26.02,78.5 25.76,78.75 25.76,80.02 25.89,80.15 26.52,80.15 26.65,80.02 26.65,78.88 26.78,78.75 27.29,78.75 27.54,78.5 27.54,78.12 27.79,77.86 27.79,76.46 27.29,75.96 27.29,73.54 27.03,73.29 ; 4 cut-outs
5V_S0 on TOP: 157.33,37.35 157.21,37.48 157.21,38.75 157.46,39 159.37,39 159.87,38.49 159.87,37.6 159.62,37.35 ; 1 cut-out
5V_S0 on TOP: 40.88,14.62 40.11,15.38 39.86,15.38 39.73,15.5 39.73,17.79 39.86,17.92 44.94,17.92 45.07,17.79 45.07,15.12 44.56,14.62 ; 8 cut-outs
5V_S0 on TOP: 141.71,6.87 141.33,7.25 141.33,10.55 141.84,11.06 147.68,11.06 147.81,10.93 147.81,7.25 147.43,6.87 ; 3 cut-outs
5V_S0 on BOTTOM: 166.22,79 166.1,79.13 166.1,81.67 166.48,82.05 166.48,83.7 166.61,83.83 167.37,83.83 167.49,83.7 167.49,82.18 167.75,81.93 168.23,81.93 168.51,82.21 168.51,84.49 168.87,84.85 171.18,84.85 171.43,84.59 171.43,81.54 171.18,81.29 169.65,81.29 169.4,81.04 169.4,80.27 169.15,80.02 166.99,80.02 166.73,79.77 166.73,79.13 166.61,79 ; 2 cut-outs
5V_S0 on BOTTOM: 87.23,140.09 87.1,140.22 87.1,142.25 87.23,142.38 88.5,142.38 89.26,141.62 89.26,140.22 89.14,140.09 ; 2 cut-outs
5V_S0 on BOTTOM: 158.35,37.35 158.1,37.6 158.1,38.75 158.35,39 159.75,39 160.38,39.63 161.65,39.63 161.91,39.38 161.91,37.6 161.65,37.35
5V_S0 on BOTTOM: 83.67,152.92 83.42,153.17 83.42,158.13 83.93,158.63 86.85,158.63 87.74,159.52 89.01,159.52 89.14,159.4 89.14,158.89 88.75,158.51 88.75,157.62 88.63,157.49 87.61,157.49 87.23,157.87 84.94,157.87 84.44,157.36 84.44,153.17 84.18,152.92 ; 2 cut-outs
5V_S0 on BOTTOM: 161.5,118.5 161.09,118.91 161.09,120.89 161.25,121.04 164.12,121.04 164.29,120.86 164.29,118.71 164.09,118.5 ; 2 cut-outs
5V_S0 on L3: outline of 116 points within 10.01,1.53 171.81,120.28
5V_S5 on TOP: 27.79,59.07 27.54,59.32 27.54,61.1 27.79,61.35 34.14,61.35 35.67,62.88 37.45,62.88 37.57,62.75 37.57,61.35 35.29,59.07
5V_S5 on TOP: 75.29,8.01 71.99,11.31 54.54,11.31 46.57,19.29 39.81,19.29 39.71,19.39 39.71,24.12 40.88,25.28 49.38,25.28 50.91,26.81 50.91,42.17 53.45,44.71 55.48,44.71 55.73,44.46 55.73,42.94 53.58,40.78 53.58,24.9 51.92,23.25 51.92,22.24 54.59,19.57 58.02,19.57 59.29,18.3 62.59,18.3 64.12,16.77 78.72,16.77 81.9,13.6 137.52,13.6 143.75,19.82 143.75,20.84 145.52,22.62 145.52,33.16 149.33,36.97 149.33,45.98 153.14,49.79 155.18,49.79 155.3,49.67 155.3,48.78 155.05,48.52 153.65,48.52 151.62,46.49 151.62,32.78 152.25,32.14 153.65,32.14 157.08,28.71 157.08,26.17 156.95,26.05 155.43,26.05 155.18,26.3 154.22,26.3 153.52,27 149.52,27 149.21,26.68 149.21,17.54 148.32,16.65 148.32,15.63 145.65,12.96 143.24,12.96 138.28,8.01 ; 6 cut-outs
5V_S5 on BOTTOM: 38.97,19.31 38.46,19.82 38.46,22.49 42.4,26.43 50.02,26.43 50.65,25.79 50.65,20.84 49.13,19.31 ; 2 cut-outs
5V_S5 on BOTTOM: 156.5,25.82 156.14,26.17 156.14,26.76 155.91,26.99 155.91,29.02 156.01,29.12 157.28,29.12 157.33,29.07 157.33,27.37 157.77,26.93 157.77,25.97 157.61,25.82 ; 1 cut-out
5V_S5 on BOTTOM: 27.92,65.8 27.29,66.43 26.22,66.43 25.89,66.76 25.89,68.46 26.14,68.72 28.81,68.72 29.06,68.46 29.06,67.83 29.57,67.32 29.57,66.05 29.32,65.8 ; 1 cut-out
5V_S5 on BOTTOM: 52.94,43.19 52.69,43.44 52.69,50.81 53.45,51.57 55.35,51.57 55.73,51.19 55.73,43.7 55.23,43.19
5V_S5 on L3: 42.65,20.2 42.27,20.58 42.27,22.24 42.78,22.74 46.84,22.74 50.65,26.55 50.65,41.79 52.81,43.95 52.81,55.76 51.16,57.41 47.61,57.41 45.07,59.95 44.18,59.95 43.29,60.84 38.97,60.84 38.59,60.46 30.84,60.46 27.29,64.02 27.29,66.69 28.18,67.57 29.19,67.57 29.57,67.19 29.57,65.8 30.08,65.29 30.59,65.29 32.87,63 43.8,63 45.07,61.73 45.96,61.73 48.62,59.07 52.56,59.07 55.61,56.02 55.61,42.81 53.07,40.27 53.07,24.39 48.88,20.2
5V_S5 on L4: 53.19,49.54 54.97,49.54 55.35,49.92 55.35,54.87 50.02,60.21 49,60.21 47.99,61.22 46.21,61.22 46.08,61.35 39.99,61.35 38.46,62.88 36.68,62.88 35.67,61.86 35.67,58.56 35.92,58.3 46.59,58.3 52.56,52.33 52.56,50.18
5V_S5 on L4: 27.67,67.83 29.32,67.83 29.57,67.57 29.57,60.59 29.32,60.34 27.54,60.34 27.29,60.59 27.29,67.45
+5V_AVDD on BOTTOM: 159.11,14.41 159.09,14.44 159.09,14.59 159.11,14.62 160.13,14.62 160.26,14.74 160.26,15.81 160.74,16.29 162.36,16.29 162.44,16.22 162.44,15.5 162.36,15.43 161.32,15.43 160.31,14.41
+5V_KB_BL on TOP: 162.97,120.1 161.53,121.55 160.26,121.55 160.13,121.68 160.13,122.18 160.64,122.69 161.14,122.69 161.91,123.45 163.08,123.45 163.61,123.99 163.79,123.99 164.55,123.23 164.55,122.21 164.83,121.93 165.87,121.93 166.15,121.65 166.15,120.79 165.46,120.1 ; 2 cut-outs
+5V_KB_BL on BOTTOM: 160.13,121.42 160,121.55 160,122.18 160.38,122.57 161.14,122.57 161.91,123.33 162.87,123.33 163.53,123.99 164.04,123.99 164.27,123.76 164.27,121.52 164.17,121.42 ; 1 cut-out
+5V_PVDD on TOP: 150.22,6.61 149.71,7.12 148.32,7.12 148.06,7.38 148.06,11.06 148.19,11.19 148.32,11.19 148.83,11.69 152.25,11.69 153.65,10.3 157.72,10.3 157.84,10.17 157.84,9.03 158.22,8.65 158.22,7 157.84,6.61 ; 4 cut-outs
+5V_PVDD on BOTTOM: 152.92,7.12 152.86,7.17 152.86,8.42 153.04,8.6 154.36,8.6 154.74,8.98 154.9,8.98 155.05,9.13 155.05,10.15 155.07,10.17 155.23,10.17 155.25,10.15 155.25,8.75 153.63,7.12 ; 1 cut-out
+5V_PVDD on BOTTOM: 157.67,6.11 157.49,6.28 157.49,7.28 156.93,7.83 156.93,8.57 157.03,8.67 157.03,10.15 157.06,10.17 157.23,10.17 157.26,10.15 157.26,8.57 158.6,7.22 158.6,6.23 158.48,6.11
GND on TOP: 124.7,79.39 124.44,79.64 124.44,79.89 123.81,80.53 121.52,80.53 121.27,80.27 117.58,80.27 117.33,80.53 111.74,80.53 111.61,80.66 111.61,81.16 111.74,81.29 120.38,81.29 120.89,81.8 123.93,81.8 124.06,81.93 124.44,81.93 124.57,81.8 124.57,80.66 125.2,80.02 125.2,79.51 125.08,79.39 ; 5 cut-outs
GND on TOP: 158.2,88.78 157.97,89.01 157.97,91.4 158.3,91.73 160.18,91.73 160.41,91.5 160.41,89.55 159.65,88.78
GND on TOP: 157.33,35.57 157.08,35.82 157.08,36.84 157.33,37.09 158.35,37.09 158.6,36.84 162.29,36.84 162.41,36.71 162.41,35.7 162.29,35.57 ; 3 cut-outs
GND on TOP: 86.6,50.05 86.34,50.3 86.34,53.1 103.61,70.37 103.61,73.54 105.52,75.45 107.93,75.45 108.82,74.56 108.82,73.42 108.44,73.04 108.44,69.73 89.39,50.68 89.39,50.3 89.14,50.05 ; 8 cut-outs
GND on TOP: 90.15,132.85 89.77,133.23 89.77,136.15 90.02,136.41 90.91,136.41 91.55,135.77 92.18,135.77 92.31,135.65 92.31,134.38 90.79,132.85
GND on TOP: 115.88,91.93 115.67,92.14 114.43,92.14 114.35,92.22 114.35,92.8 114.07,93.08 114.07,93.59 114.27,93.79 114.78,93.79 115.29,94.3 115.29,94.68 115.42,94.81 115.92,94.81 116.05,94.68 116.05,93.92 116.43,93.54 116.43,93.2 116.85,92.79 116.85,92.04 116.75,91.93 ; 3 cut-outs
GND on TOP: 143.36,11.31 142.98,11.69 142.98,12.2 143.36,12.58 147.17,12.58 147.68,13.09 148.95,13.09 149.08,12.96 149.08,11.69 148.7,11.31 ; 3 cut-outs
GND on TOP: 84.31,163.84 84.18,163.97 84.18,167.9 84.56,168.29 89.64,168.29 90.15,167.78 90.15,164.73 89.26,163.84
GND on TOP: 33,12.58 32.62,12.96 32.62,14.49 33.13,15 36.68,15 37.07,15.38 37.95,15.38 38.34,15 38.34,14.36 38.59,14.11 40.24,14.11 40.37,13.98 40.37,12.96 39.99,12.58 ; 9 cut-outs
GND on TOP: outline of 168 points within 0.76,0.76 172.44,181.21 ; 34 cut-outs
GND on TOP: 161.4,65.67 161.27,65.8 161.27,68.54 161.4,68.67 162.64,68.67 162.8,68.51 162.8,66.43 162.03,65.67 ; 1 cut-out
GND on TOP: 30.59,170.7 30.21,171.08 30.21,171.71 30.33,171.84 32.11,171.84 32.24,171.71 32.24,170.95 31.99,170.7 ; 2 cut-outs
GND on TOP: 17.38,41.16 17,41.54 17,42.17 17.76,42.94 21.44,42.94 21.46,42.92 21.85,43.32 22.71,43.32 23.1,42.94 23.1,41.46 22.79,41.16 ; 2 cut-outs
GND on TOP: 162.16,115.83 160.51,117.49 158.22,117.49 158.1,117.61 158.1,121.17 158.35,121.42 161.53,121.42 161.78,121.17 161.78,120.79 161.02,120.03 161.02,118.88 162.03,117.87 166.35,117.87 166.99,118.5 166.99,119.26 167.62,119.9 170.16,119.9 170.8,119.26 170.8,116.22 170.42,115.83 ; 1 cut-out
GND on TOP: 54.69,170.98 53.96,171.71 53.96,172.22 54.08,172.35 56.32,172.35 56.55,172.12 56.55,171.05 56.47,170.98 ; 2 cut-outs
GND on TOP: 169.91,167.27 169.53,167.65 169.53,168.92 170.29,169.68 170.29,170.57 170.54,170.83 171.3,170.83 171.56,170.57 171.56,167.4 171.43,167.27
GND on TOP: 137.01,90.05 136.89,90.18 136.89,90.82 136.76,90.94 135.9,90.94 135.9,91.04 135.64,91.3 135.64,91.65 135.57,91.73 135.44,91.73 135.24,91.93 135.24,92.72 137.65,92.72 138.16,92.21 138.16,91.45 138.41,91.2 139.17,91.2 139.3,91.32 139.3,91.83 139.43,91.96 140.67,91.96 141.56,92.85 143.85,92.85 144.1,92.59 144.1,91.12 143.95,90.97 143.42,90.97 143.24,90.79 143.24,90.43 142.86,90.05 ; 12 cut-outs
GND on TOP: 97.52,104.15 97.14,104.53 97.14,115.96 98.15,116.98 101.33,116.98 101.58,116.72 101.58,104.28 101.45,104.15 ; 10 cut-outs
GND on TOP: 96.2,152.46 96.04,152.61 96.04,153.02 96.43,153.4 99.32,153.4 99.63,153.1 99.63,152.69 99.4,152.46 ; 3 cut-outs
GND on TOP: 35.8,44.97 35.67,45.1 35.67,46.87 35.41,47.13 34.4,47.13 34.27,47.25 34.27,49.92 34.53,50.18 39.22,50.18 39.48,49.92 39.48,45.86 38.59,44.97 ; 2 cut-outs
GND on TOP: 123.93,13.85 122.92,14.87 122.92,18.04 122.54,18.43 120.12,18.43 118.85,19.7 108.31,19.7 108.19,19.82 108.19,20.58 108.31,20.71 110.09,20.71 111.36,21.98 115.55,21.98 116.69,23.12 116.69,24.78 116.44,25.03 105.26,25.03 105.01,25.28 105.01,30.36 105.65,31 114.28,31 114.79,31.51 114.79,39.13 114.41,39.51 105.26,39.51 105.14,39.63 105.14,40.52 105.26,40.65 117.2,40.65 118.6,42.05 118.6,42.68 126.85,50.94 126.85,76.08 128.38,77.61 128.38,78.24 128.63,78.5 129.78,78.5 130.79,77.48 134.73,77.48 138.54,73.67 145.9,73.67 147.68,71.89 147.68,66.43 145.4,64.15 145.4,61.22 130.03,45.86 130.03,44.71 130.41,44.33 130.92,44.33 151.37,64.78 156.06,64.78 157.72,63.13 157.72,59.7 155.3,57.29 152.51,57.29 143.11,47.89 143.11,40.02 142.48,39.38 138.16,39.38 137.9,39.63 137.9,42.81 137.65,43.06 136.76,43.06 136.63,42.94 136.63,37.09 137.78,35.95 138.41,35.95 140.44,37.98 142.09,37.98 145.14,34.94 145.14,26.05 144.63,25.54 144,25.54 143.62,25.16 143.62,20.33 143.36,20.08 142.73,20.08 136.51,13.85 ; 80 cut-outs
GND on TOP: 113.14,174.64 113.01,174.76 113.01,175.27 112.76,175.52 108.95,175.52 108.82,175.65 108.82,178.06 109.07,178.32 117.58,178.32 117.96,177.94 117.96,175.78 117.46,175.27 116.06,175.27 115.42,174.64 ; 3 cut-outs
GND on TOP: 134.22,109.48 134.09,109.61 134.09,111.64 134.35,111.9 134.35,112.91 134.6,113.17 136.89,113.17 137.14,113.42 137.14,114.31 137.27,114.44 137.9,114.44 138.16,114.69 138.16,119.77 137.65,120.28 137.65,121.04 137.78,121.17 138.54,121.17 141.59,118.12 141.59,115.71 140.57,114.69 140.57,111.9 138.41,109.74 135.24,109.74 134.98,109.48 ; 9 cut-outs
GND on TOP: 116.26,88.64 116.09,88.81 116.09,88.81 116.09,90.26 116.26,90.43 116.87,90.43 117.13,90.69 117.75,90.69 117.99,90.92 118.62,90.92 118.72,90.82 118.72,89.13 118.56,88.97 117.78,88.97 117.45,88.64 ; 2 cut-outs
GND on TOP: 160.13,164.73 159.62,165.24 159.62,166.51 159.87,166.76 163.18,166.76 163.56,167.14 163.56,170.7 163.68,170.83 164.32,170.83 166.35,168.79 166.35,164.98 166.1,164.73 ; 2 cut-outs
GND on TOP: 64.24,26.3 64.12,26.43 64.12,27.44 65.01,28.33 65.01,30.49 65.39,30.87 69.32,30.87 69.58,30.62 69.58,28.97 69.2,28.59 69.2,26.55 68.94,26.3 ; 3 cut-outs
GND on TOP: 55.86,32.9 55.73,33.03 55.73,39.25 56.24,39.76 58.66,39.76 59.04,39.38 59.04,34.94 59.39,34.58 59.39,33.74 59.32,33.67 58.4,33.67 57.64,32.9 ; 3 cut-outs
GND on TOP: 164.07,84.97 163.94,85.1 163.94,87.01 164.07,87.13 166.22,87.13 166.35,87.01 166.35,85.1 166.22,84.97
GND on TOP: 113.18,83.18 113.08,83.28 113.08,84.14 113.21,84.27 119.61,84.27 119.68,84.35 119.68,85.08 119.56,85.21 116.41,85.21 116.05,85.57 113.22,85.57 112.91,85.25 112.02,85.25 111.61,84.85 111.01,84.85 110.93,84.92 110.93,85.53 111.03,85.63 111.33,85.63 111.78,86.09 111.78,86.86 112.29,87.37 113.43,87.37 113.89,86.91 116.25,86.91 116.86,86.3 120.24,86.3 120.25,86.29 120.57,86.29 120.85,86.57 120.85,87.78 120.7,87.93 119.76,87.93 119.63,88.05 119.63,88.54 119.73,88.64 121.89,88.64 122.05,88.79 122.05,89.27 122.17,89.4 122.66,89.4 122.81,89.25 122.81,88.43 122.76,88.38 122.16,88.38 122,88.23 122,87.72 122.05,87.67 122.05,85.2 122,85.15 120.56,85.15 120.47,85.07 120.47,84.19 120.6,84.07 120.6,83.66 120.34,83.41 114.2,83.41 113.97,83.18 ; 7 cut-outs
GND on TOP: 96.37,99.2 96.25,99.32 96.25,101.74 96.63,102.12 101.33,102.12 101.58,101.86 101.58,99.58 101.2,99.2 ; 10 cut-outs
GND on TOP: 159.04,10.09 158.86,10.27 158.86,10.45 158.73,10.58 157.26,10.58 157,10.32 155.81,10.32 155.58,10.55 153.88,10.55 153.55,10.88 153.55,14.51 153.88,14.84 158.45,14.84 158.73,14.57 158.73,11.62 159.04,11.31 159.49,11.31 159.65,11.16 159.65,10.2 159.54,10.09 ; 12 cut-outs
GND on TOP: 54.85,45.98 54.72,46.11 54.72,48.65 54.85,48.78 56.37,48.78 56.5,48.65 56.5,46.11 56.37,45.98 ; 3 cut-outs
GND on TOP: 140.06,162.44 136.51,166 136.51,168.79 136.89,169.17 144.63,169.17 146.16,167.65 146.16,165.24 143.36,162.44
GND on TOP: 140.57,151.52 140.32,151.78 140.32,155.08 140.57,155.33 144.89,155.33 145.02,155.2 145.02,154.82 145.4,154.44 146.67,154.44 146.79,154.32 146.79,151.78 146.54,151.52 ; 1 cut-out
GND on TOP: 61.32,68.97 61.07,69.23 61.07,69.99 61.2,70.11 64.5,70.11 64.88,70.5 64.88,71.38 65.39,71.89 67.16,71.89 67.42,71.64 67.42,69.35 67.04,68.97
GND on TOP: 157.49,26.5 157.33,26.66 157.33,28.71 158.86,30.24 158.86,31 159.11,31.25 163.05,31.25 163.18,31.13 163.18,30.62 163.05,30.49 162.92,30.49 161.78,29.35 160.13,29.35 158.99,28.2 158.99,26.71 158.78,26.5 ; 3 cut-outs
GND on TOP: 111.23,124.34 110.98,124.6 110.98,131.58 111.49,132.09 117.46,132.09 118.09,131.46 118.09,124.6 117.84,124.34 114.79,124.34 114.66,124.47 114.66,126.76 114.41,127.01 113.27,127.01 113.01,126.76 113.01,124.98 112.38,124.34 ; 2 cut-outs
GND on TOP: 64.12,16.9 62.97,18.04 62.97,18.3 63.1,18.43 63.86,18.43 64.12,18.17 71.61,18.17 71.74,18.04 71.74,17.03 71.61,16.9 ; 4 cut-outs
GND on TOP: 110.4,88 110.34,88.06 110.34,89.86 109.96,90.24 108.49,90.24 108.01,90.72 108.01,92.67 108.19,92.85 110.98,92.85 110.99,92.86 111.46,92.86 111.77,92.55 111.77,91.5 111.54,91.27 111.54,90.16 111.56,90.16 111.73,89.98 111.73,88.71 111.61,88.59 111.06,88.59 110.88,88.41 110.88,88.15 110.73,88 ; 7 cut-outs
GND on TOP: 18.07,38.87 17.69,39.25 17.69,39.43 17.84,39.58 18.6,39.58 18.73,39.46 19.74,39.46 19.79,39.41 19.79,38.92 19.74,38.87
GND on TOP: 101.99,89.72 99.85,91.86 99.85,92.77 100.77,93.69 102.9,93.69 103.16,93.94 103.64,93.94 103.89,93.69 103.89,93.41 104.07,93.23 106.36,93.23 106.61,92.97 106.61,89.98 106.36,89.72 ; 2 cut-outs
GND on TOP: 41.89,44.97 41.76,45.1 41.76,46.49 41.64,46.62 39.99,46.62 39.73,46.87 39.73,49.54 39.86,49.67 44.56,49.67 44.81,49.41 44.81,46.87 44.43,46.49 44.43,45.35 44.05,44.97 ; 2 cut-outs
GND on TOP: 45.45,15.5 45.32,15.63 45.32,17.92 45.12,18.12 39.2,18.12 39.12,18.04 39.12,17.08 39.07,17.03 38.97,17.03 38.92,17.08 38.92,18.04 38.84,18.12 37.57,18.12 37.45,18.25 37.45,18.93 37.57,19.06 46.46,19.06 46.72,18.81 46.72,16.14 46.08,15.5 ; 8 cut-outs
GND on TOP: 104.12,165.62 103.74,166 103.74,167.65 103.99,167.9 106.28,167.9 106.41,167.78 106.41,165.75 106.28,165.62
GND on TOP: 121.39,123.84 121.14,124.09 121.14,126.38 121.01,126.5 118.98,126.5 118.85,126.63 118.85,131.46 118.35,131.96 118.35,132.73 118.73,133.11 126.35,133.11 126.47,132.98 126.47,125.36 124.95,123.84 ; 2 cut-outs
GND on TOP: 116.85,137.35 116.8,137.4 116.8,142.07 116.87,142.15 121.52,142.15 121.57,142.1 121.57,137.45 121.47,137.35
GND on TOP: 83.42,57.41 82.79,58.05 82.79,59.45 82.28,59.95 79.23,59.95 78.85,60.34 78.85,63.51 88.88,73.54 92.95,73.54 94.47,72.02 94.47,65.92 85.96,57.41
GND on TOP: 105.14,152.92 104.76,153.3 104.76,156.22 104.88,156.35 105.77,156.35 108.19,158.76 110.22,158.76 110.6,158.38 110.6,155.59 107.93,152.92 ; 3 cut-outs
GND on TOP: 89.64,154.7 89.26,155.08 89.26,158.51 89.77,159.01 92.82,159.01 93.2,158.63 93.2,155.46 92.44,154.7
GND on TOP: 150.98,171.59 150.6,171.97 150.6,173.37 150.86,173.62 155.56,173.62 155.81,173.37 155.81,171.84 155.56,171.59 ; 4 cut-outs
GND on BOTTOM: 167.81,82.24 167.75,82.31 167.75,84.08 167.62,84.21 165.34,84.21 163.94,85.61 163.94,87.01 164.07,87.13 164.57,87.13 165.72,85.99 167.88,85.99 168.18,85.69 168.18,82.33 168.09,82.24
GND on BOTTOM: outline of 171 points within 0.76,0.76 172.44,181.21 ; 33 cut-outs
GND on BOTTOM: 80.25,155.2 79.1,156.35 79.1,161.43 79.36,161.68 81.64,161.68 81.9,161.43 81.9,155.33 81.77,155.2
GND on BOTTOM: 99.32,86.32 99.17,86.47 99.17,87.89 98.53,88.53 98.53,88.71 98.61,88.78 99.75,88.78 99.93,88.61 99.93,86.42 99.83,86.32
GND on BOTTOM: 122.66,83.28 122.56,83.38 122.13,83.38 122.06,83.31 121.39,83.31 121.34,83.36 121.03,83.36 120.99,83.31 120.63,83.31 120.51,83.43 120.09,83.43 119.97,83.31 119.61,83.31 119.46,83.46 119.1,83.46 118.96,83.31 118.65,83.31 118.5,83.46 118.09,83.46 117.94,83.31 117.63,83.31 117.51,83.43 117.05,83.43 116.92,83.31 116.59,83.31 116.47,83.43 116.06,83.43 115.93,83.31 115.62,83.31 115.48,83.46 115.09,83.46 114.94,83.31 114.66,83.31 114.51,83.46 114.07,83.46 113.93,83.31 113.72,83.31 113.59,83.44 113.59,83.86 113.89,84.16 121.18,84.16 121.67,84.65 121.9,84.65 122.15,84.4 122.29,84.4 122.91,83.77 122.91,83.76 123.01,83.66 123.02,83.38 122.91,83.28
GND on BOTTOM: 110.08,87.43 109.9,87.61 109.9,89.69 109.83,89.77 109.65,89.77 109.47,89.59 109.24,89.59 109.09,89.74 108.84,89.74 108.66,89.56 107.31,89.56 107.06,89.82 107.06,89.92 107.31,90.17 107.59,90.17 107.77,90.35 107.77,90.71 107.72,90.76 107.72,91.85 107.16,92.41 106.78,92.41 106.63,92.56 106.63,92.79 106.73,92.89 107.36,92.89 107.54,93.07 107.54,93.32 107.64,93.42 107.87,93.42 108.38,92.92 109.52,92.92 110.18,93.58 112.34,93.58 112.6,93.83 112.98,93.83 113.31,93.5 114.48,93.5 114.88,93.91 115.16,93.91 115.44,93.63 115.77,93.63 115.95,93.81 115.95,95.25 116.53,95.84 116.86,95.84 116.97,95.94 116.97,96.49 117.09,96.61 117.45,96.61 117.58,96.49 117.58,95.99 118.03,95.53 120.14,95.53 120.24,95.43 120.24,95.33 119.68,94.77 119.68,94.42 119.43,94.16 117.4,94.16 116.23,92.99 116.23,92.3 115.95,92.02 114.96,92.02 114.83,92.14 114.83,92.43 114.3,92.97 113.74,92.97 113.08,92.31 113.08,90.48 111.89,89.28 111.02,89.28 110.62,88.88 110.62,87.74 110.31,87.43
GND on BOTTOM: 72.75,43.57 72.5,43.83 72.5,48.27 72.75,48.52 76.82,48.52 77.07,48.27 77.07,43.83 76.82,43.57
GND on BOTTOM: 50.78,68.97 50.53,69.23 48.11,69.23 47.99,69.35 47.99,69.99 48.11,70.11 52.69,70.11 52.94,69.86 52.94,69.23 52.69,68.97
GND on BOTTOM: 167.75,39.76 167.37,40.14 167.37,42.05 167.75,42.43 169.27,42.43 169.78,41.92 169.78,40.02 169.53,39.76 ; 4 cut-outs
GND on BOTTOM: 121.19,85.89 120.84,86.24 120.69,86.24 120.6,86.33 120.6,86.69 121.16,87.25 121.16,87.84 120.15,88.84 120.15,89.13 120.71,89.68 120.96,89.68 121.63,89.01 122.82,89.01 122.97,88.86 122.97,87.85 122.98,87.84 122.98,87.63 123.04,87.57 123.04,86.04 122.89,85.89
GND on BOTTOM: 108.57,132.6 108.19,132.98 108.19,135.9 108.44,136.15 111.11,136.15 111.74,135.52 111.74,133.74 110.6,132.6
GND on BOTTOM: 155.3,101.1 154.92,101.48 154.92,107.83 155.18,108.09 159.11,108.09 161.02,106.18 161.02,103.13 160.89,103.01 159.75,103.01 159.24,103.52 157.97,103.52 157.72,103.26 157.72,101.23 157.59,101.1 ; 3 cut-outs
GND on BOTTOM: 61.32,68.97 61.07,69.23 61.07,69.99 62.72,71.64 66.28,71.64 66.53,71.38 66.53,69.23 66.28,68.97 ; 3 cut-outs
GND on BOTTOM: 48.37,166.51 48.24,166.63 48.24,168.92 49.13,169.81 49.13,169.94 50.15,170.95 51.16,170.95 52.56,169.56 52.56,167.02 52.05,166.51 ; 7 cut-outs
GND on BOTTOM: 55.99,34.3 55.73,34.55 55.73,39.25 56.24,39.76 58.66,39.76 59.04,39.38 59.04,34.68 58.66,34.3
GND on BOTTOM: 39.48,26.43 39.1,26.81 39.1,33.28 39.35,33.54 43.54,33.54 43.92,33.16 43.92,29.86 43.54,29.47 41.26,29.47 40.88,29.09 40.88,26.55 40.75,26.43 ; 1 cut-out
GND on BOTTOM: 116.95,137.3 116.69,137.55 116.69,142 116.95,142.25 121.39,142.25 121.65,142 121.65,137.68 121.27,137.3 ; 2 cut-outs
GND on BOTTOM: 99.3,80.15 99.17,80.27 99.17,82.31 98.91,82.56 98.66,82.56 98.53,82.69 98.53,83.2 98.66,83.32 99.04,83.32 99.17,83.45 99.17,84.34 99.3,84.47 99.8,84.47 99.93,84.34 99.93,80.27 99.8,80.15 ; 1 cut-out
GND on BOTTOM: 145.4,75.83 145.35,75.88 145.35,76.9 145.24,77 144.28,77 144.25,77.02 144.25,77.18 144.28,77.2 145.27,77.2 145.35,77.28 145.35,78.32 145.4,78.37 146.16,78.37 146.21,78.32 146.21,75.88 146.16,75.83
GND on BOTTOM: 140.82,151.52 140.44,151.9 140.44,155.08 140.7,155.33 144.89,155.33 145.02,155.2 145.02,154.82 145.4,154.44 146.67,154.44 146.79,154.32 146.79,151.78 146.54,151.52 ; 3 cut-outs
GND on BOTTOM: 42.02,44.97 41.76,45.22 41.76,46.24 41.13,46.87 41.13,49.54 41.51,49.92 44.56,49.92 44.81,49.67 44.81,46.87 44.43,46.49 44.43,45.35 44.05,44.97
GND on BOTTOM: 163.81,163.21 163.56,163.46 163.56,168.29 163.94,168.67 166.86,168.67 167.11,168.41 167.11,163.46 166.86,163.21 ; 1 cut-out
GND on BOTTOM: 115.65,90.25 115.52,90.37 115.52,90.5 116.15,91.14 120.22,91.14 120.73,91.64 121.23,91.64 121.41,91.47 121.41,90.68 121.03,90.3 120.55,90.3 120.09,90.75 119.46,90.75 118.95,90.25
GND on BOTTOM: 87.36,81.8 87.23,81.93 87.23,83.32 87.48,83.58 88.75,83.58 88.88,83.45 88.88,81.93 88.75,81.8
GND on BOTTOM: 35.8,44.97 35.67,45.1 35.67,46.87 35.41,47.13 34.4,47.13 34.27,47.25 34.27,49.92 34.53,50.18 39.22,50.18 39.48,49.92 39.48,45.86 38.59,44.97
GND on BOTTOM: 98.91,90.69 98.66,90.94 98.66,93.58 98.48,93.76 97.77,93.76 97.64,93.89 97.64,95.26 97.77,95.39 99.42,95.39 99.93,94.88 99.93,90.82 99.8,90.69 ; 7 cut-outs
GND on BOTTOM: 111.11,123.71 110.98,123.84 110.98,131.2 111.36,131.58 117.71,131.58 118.09,131.2 118.09,127.39 117.84,127.14 117.2,127.14 116.69,126.63 116.69,124.47 116.57,124.34 112.63,124.34 112,123.71 ; 1 cut-out
GND on BOTTOM: 149.71,110.63 149.59,110.75 149.59,113.29 149.71,113.42 150.22,113.42 150.35,113.29 150.35,110.75 150.22,110.63
GND on BOTTOM: 163.18,34.05 162.92,34.3 162.92,34.94 162.29,35.57 158.35,35.57 158.1,35.82 158.1,36.59 158.35,36.84 163.68,36.84 163.81,36.71 163.81,34.17 163.68,34.05 ; 1 cut-out
GND on BOTTOM: 117.7,92.07 117.6,92.17 117.6,93.22 118.19,93.8 118.57,93.8 118.82,93.55 120.17,93.55 120.42,93.8 120.73,93.8 121.03,94.11 121.18,94.11 121.36,93.93 121.36,93.8 120.35,92.79 118.19,92.79 118.06,92.66 118.06,92.25 118.06,92.25 117.88,92.07
GND on BOTTOM: 142.6,159.78 142.48,159.9 142.48,162.06 142.09,162.44 140.06,162.44 136.51,166 136.51,168.79 137.27,169.56 145.02,169.56 146.16,168.41 146.16,162.57 143.36,159.78 ; 1 cut-out
GND on BOTTOM: 90.53,79.13 90.28,79.39 90.28,81.42 91.42,82.56 94.09,82.56 94.22,82.43 94.22,79.26 94.09,79.13
GND on BOTTOM: 119.62,123.84 118.85,124.6 118.85,130.95 119.23,131.33 122.03,131.33 122.54,131.84 122.54,132.85 122.66,132.98 125.84,132.98 126.73,132.09 126.73,124.98 126.6,124.85 125.58,124.85 125.46,124.98 125.46,125.61 124.57,126.5 123.68,126.5 123.17,125.99 123.17,123.96 123.04,123.84 ; 5 cut-outs
GND on BOTTOM: 54.08,54.75 53.45,55.38 53.45,59.07 53.96,59.57 58.15,59.57 58.53,59.19 58.53,55.38 57.89,54.75
GND on BOTTOM: 165.72,77.35 165.34,77.73 164.19,77.73 164.07,77.86 164.07,78.37 164.32,78.62 164.32,81.67 164.45,81.8 165.46,81.8 165.72,81.54 165.72,78.75 165.84,78.62 167.11,78.62 167.24,78.75 167.24,79.64 167.37,79.77 169.27,79.77 169.53,80.02 169.53,80.78 169.65,80.91 171.18,80.91 171.3,80.78 171.3,78.24 170.42,77.35 ; 4 cut-outs
GND on BOTTOM: 169.53,66.43 169.4,66.56 169.4,69.1 169.53,69.23 170.16,69.23 170.29,69.1 170.29,66.56 170.16,66.43
GND on BOTTOM: 20.66,41.01 20.28,41.39 18.5,41.39 18.27,41.16 17.51,41.16 17,41.67 17,42.05 17.76,42.81 19.92,42.81 20.05,42.94 21.52,42.94 21.83,43.24 22.31,43.24 22.59,42.96 22.59,42.05 21.55,41.01 ; 3 cut-outs
GND on BOTTOM: 102.85,150.76 102.72,150.89 102.72,152.28 102.85,152.41 103.23,152.41 103.49,152.66 103.49,153.05 103.23,153.3 103.23,154.32 103.49,154.57 108.19,154.57 108.44,154.32 108.44,153.55 107.68,152.79 106.03,152.79 103.99,150.76 ; 5 cut-outs
GND on BOTTOM: 110.29,162.42 110.14,162.57 110.14,165.21 110.45,165.52 112.2,165.52 112.35,165.36 112.35,163.56 111.21,162.42 ; 3 cut-outs
GND on BOTTOM: 134.47,109.23 134.22,109.48 134.22,112.02 134.73,112.53 136.13,112.53 138.92,115.33 138.92,120.91 139.3,121.3 142.98,121.3 143.24,121.04 143.24,117.23 140.7,114.69 140.7,112.02 137.9,109.23
GND on BOTTOM: 139.58,79.31 139.58,79.34 139.33,79.59 139.33,80.63 139.68,80.99 144.43,80.99 144.61,80.81 144.61,79.72 144.46,79.56 143.62,79.56 143.36,79.31 ; 3 cut-outs
GND on BOTTOM: outline of 124 points within 109.05,79.04 124.92,87.83
GND on BOTTOM: 93.45,142.38 93.2,142.63 91.42,142.63 91.29,142.76 91.29,143.27 91.55,143.52 91.55,145.04 91.17,145.43 88.56,145.43 87.04,146.95 87.04,149.49 85.07,151.46 85.07,154.7 85.2,154.82 86.21,154.82 86.34,154.7 86.34,151.78 86.72,151.39 88.88,151.39 89.01,151.52 89.01,152.54 88.88,152.66 88.12,152.66 87.87,152.92 87.87,154.32 88.12,154.57 88.5,154.57 89.01,155.08 89.01,158.38 89.39,158.76 89.39,160.41 89.64,160.67 90.53,160.67 90.79,160.41 90.79,157.11 91.17,156.73 94.09,156.73 94.6,156.22 94.6,153.05 92.69,151.14 92.69,147.33 93.58,146.44 93.96,146.44 95.49,144.92 95.49,144.28 95.36,144.16 94.85,144.16 94.72,144.03 94.72,143.01 94.09,142.38 ; 12 cut-outs
GND on BOTTOM: 36.05,26.68 35.92,26.81 35.92,29.22 35.67,29.47 34.4,29.47 34.02,29.86 34.02,33.16 34.4,33.54 38.08,33.54 38.34,33.28 38.34,27.32 37.7,26.68 ; 1 cut-out
GND on BOTTOM: 157.92,81.54 157.21,82.26 157.21,84.85 157.37,85.01 159.86,85.01 160.79,84.08 160.79,82.84 159.49,81.54
GND on BOTTOM: 154.36,10.4 154.24,10.53 154.24,11.49 154.13,11.59 153.09,11.59 153.04,11.64 153.04,11.77 153.09,11.82 154.13,11.82 154.24,11.92 154.24,14.97 154.31,15.05 158.78,15.05 158.86,14.97 158.86,10.5 158.76,10.4
GND on BOTTOM: 101.12,159.17 100.97,159.32 100.97,160.44 101.53,161 101.53,161.5 101.58,161.55 103.36,161.55 103.49,161.43 103.49,160.28 103.66,160.11 103.66,159.37 103.46,159.17 ; 1 cut-out
GND on BOTTOM: 94.34,104.91 93.58,105.67 93.58,115.83 94.34,116.6 100.57,116.6 101.07,116.09 101.07,109.61 102.22,108.47 102.22,105.67 101.45,104.91
GND on BOTTOM: 144.63,32.01 144.25,32.4 144.25,35.95 145.02,36.71 145.02,40.78 142.09,43.7 138.92,43.7 138.79,43.83 138.79,48.27 138.92,48.4 151.49,48.4 151.87,48.02 151.87,40.02 152.51,39.38 152.51,36.21 152.89,35.82 152.89,32.65 152.25,32.01
GND on BOTTOM: 98.28,99.2 97.77,99.71 96.76,99.71 96.5,99.96 96.5,101.86 96.76,102.12 101.45,102.12 101.71,101.86 101.71,99.58 101.33,99.2 ; 10 cut-outs
GND on L2VCC: outline of 109 points within 0.76,0.76 172.44,181.21 ; 4 cut-outs
GND on L3: outline of 186 points within 0.76,0.76 172.44,181.21
GND on L4: outline of 190 points within 0.76,0.76 172.44,181.21
GND on L5GND: outline of 109 points within 0.76,0.76 172.44,181.21 ; 3 cut-outs
VDD10 on TOP: 44.89,166.76 44.81,166.84 44.81,167.35 44.89,167.42 46.34,167.42 46.92,168.01 48.55,168.01 48.62,167.93 48.62,167.37 48.01,166.76
VDD10 on TOP: 53.32,174.51 53.19,174.64 53.19,175.91 53.45,176.16 53.96,176.16 54.34,176.54 54.34,177.56 54.59,177.81 57.51,177.81 57.77,177.56 57.77,175.65 57.51,175.4 56.12,175.4 55.73,175.02 55.73,174.76 55.48,174.51 ; 4 cut-outs
VDD10 on BOTTOM: 47.23,166.38 46.59,167.02 46.59,170.06 47.1,170.57 47.1,172.98 47.23,173.11 51.54,173.11 53.32,171.33 54.21,171.33 54.59,170.95 54.59,169.94 53.96,169.3 53.96,167.4 53.7,167.14 53.07,167.14 52.81,167.4 52.81,169.94 51.42,171.33 49.26,171.33 48.88,170.95 48.88,169.81 47.99,168.92 47.99,166.63 47.73,166.38 ; 7 cut-outs
VDD10 on L3: 54.85,177.56 57.39,177.56 57.77,177.18 57.77,172.1 55.1,169.43 52.81,169.43 52.43,169.81 52.43,172.35 54.46,174.38 54.46,177.18
VDDREG on TOP: 54.62,169.66 54.08,170.19 51.98,170.19 51.92,170.24 51.92,170.37 51.98,170.42 52.84,170.42 53.55,171.13 54.26,171.13 54.67,170.72 57.94,170.72 58.02,170.65 58.02,169.76 57.92,169.66 ; 2 cut-outs
0D95V_GFX_S0 on TOP: 115.16,90.57 114.53,91.2 114.37,91.2 114.25,91.33 114.25,91.74 114.37,91.86 115.55,91.86 115.73,91.68 117.68,91.68 117.78,91.58 117.78,90.95 117.68,90.85 117.03,90.85 116.75,90.57 ; 1 cut-out
0D95V_GFX_S0 on BOTTOM: 115.19,90.54 115.04,90.7 115.04,91.48 115.39,91.84 116.81,91.84 116.97,91.99 116.97,92.19 117.09,92.32 117.4,92.32 117.52,92.19 117.52,91.99 117.73,91.79 117.85,91.79 118.03,91.61 118.03,91.33 117.91,91.2 116.1,91.2 115.44,90.54
0D95V_PWR on BOTTOM: 150.73,79.64 150.6,79.77 150.6,90.59 151.21,91.2 157.54,91.2 157.77,90.97 157.77,87.72 155.94,85.89 155.94,79.89 155.68,79.64 ; 1 cut-out
0D95V_S0 on TOP: 120.8,81.96 120.67,82.09 120.67,84.94 120.76,85.02 122.08,85.02 122.21,85.15 122.21,85.74 122.28,85.82 122.53,85.82 122.78,86.07 124.08,86.07 124.09,86.07 124.24,86.07 124.85,86.68 125.66,86.68 125.74,86.6 125.74,86.17 125.53,85.96 125.1,85.96 124.96,85.82 125.04,85.74 125.04,85.31 124.89,85.16 124.13,85.16 123.62,84.65 123.62,83.13 124.03,82.72 124.03,82.14 123.85,81.96 ; 4 cut-outs
0D95V_S0 on BOTTOM: 139.68,77.1 139.43,77.35 139.43,78.75 139.68,79 143.47,79 143.85,79.39 144.89,79.39 145.14,79.13 145.14,77.86 145.02,77.73 143.87,77.73 143.24,77.1 ; 3 cut-outs
0D95V_S0 on BOTTOM: 120.81,81.84 120.68,81.96 120.68,83 120.83,83.15 122.99,83.15 123.19,83.36 123.19,83.74 122.1,84.83 121.64,84.83 121.1,84.29 120.47,84.29 120.35,84.42 120.35,84.79 120.47,84.91 120.98,84.91 121.49,85.42 121.49,85.55 121.7,85.75 122.98,85.75 123.96,84.78 123.96,82.85 122.94,81.84
0D95V_S0 on L2VCC: 138.11,75.89 133.03,80.97 123.76,80.97 123.38,81.35 121.35,81.35 121.2,81.5 121.2,84.77 121.47,85.04 134.65,85.04 139.73,79.96 143.79,79.96 144.57,79.18 144.57,76.29 144.17,75.89
0D95V_S0 on L3: 121.39,85.16 123.42,85.16 124.05,84.52 135.31,84.52 139.94,79.89 143.49,79.89 143.7,79.69 144.1,79.69 144.61,79.18 144.61,76.31 144.25,75.96 138.08,75.96 133.07,80.97 123.67,80.97 123.42,81.22 121.26,81.22 121,81.48 121,84.78
0D95V_S5 on TOP: 140.82,83.7 138.16,86.37 136.76,86.37 136.76,87.26 136,88.02 133.59,88.02 132.32,89.29 129.01,89.29 128.51,89.8 125.69,89.8 125.25,90.24 123.09,90.24 122.46,89.62 122.03,89.62 121.94,89.53 121.94,88.94 121.79,88.79 119.76,88.79 119.61,88.94 119.61,89.29 119.06,89.84 119.06,90.31 119.13,90.38 120.5,90.38 120.78,90.11 121.49,90.11 121.69,90.32 121.69,90.72 121.82,90.85 122.27,90.85 122.32,90.8 123.06,90.8 123.16,90.9 123.95,90.9 124.28,91.23 124.28,92.4 124.66,92.78 124.69,92.78 126.44,94.53 126.44,94.84 126.62,95.01 127.74,95.01 127.74,95.01 129.52,95.01 131.05,93.48 131.68,93.48 135.11,90.05 135.87,90.05 136.13,89.8 142.73,89.8 142.86,89.67 142.86,84.21 142.35,83.7 ; 8 cut-outs
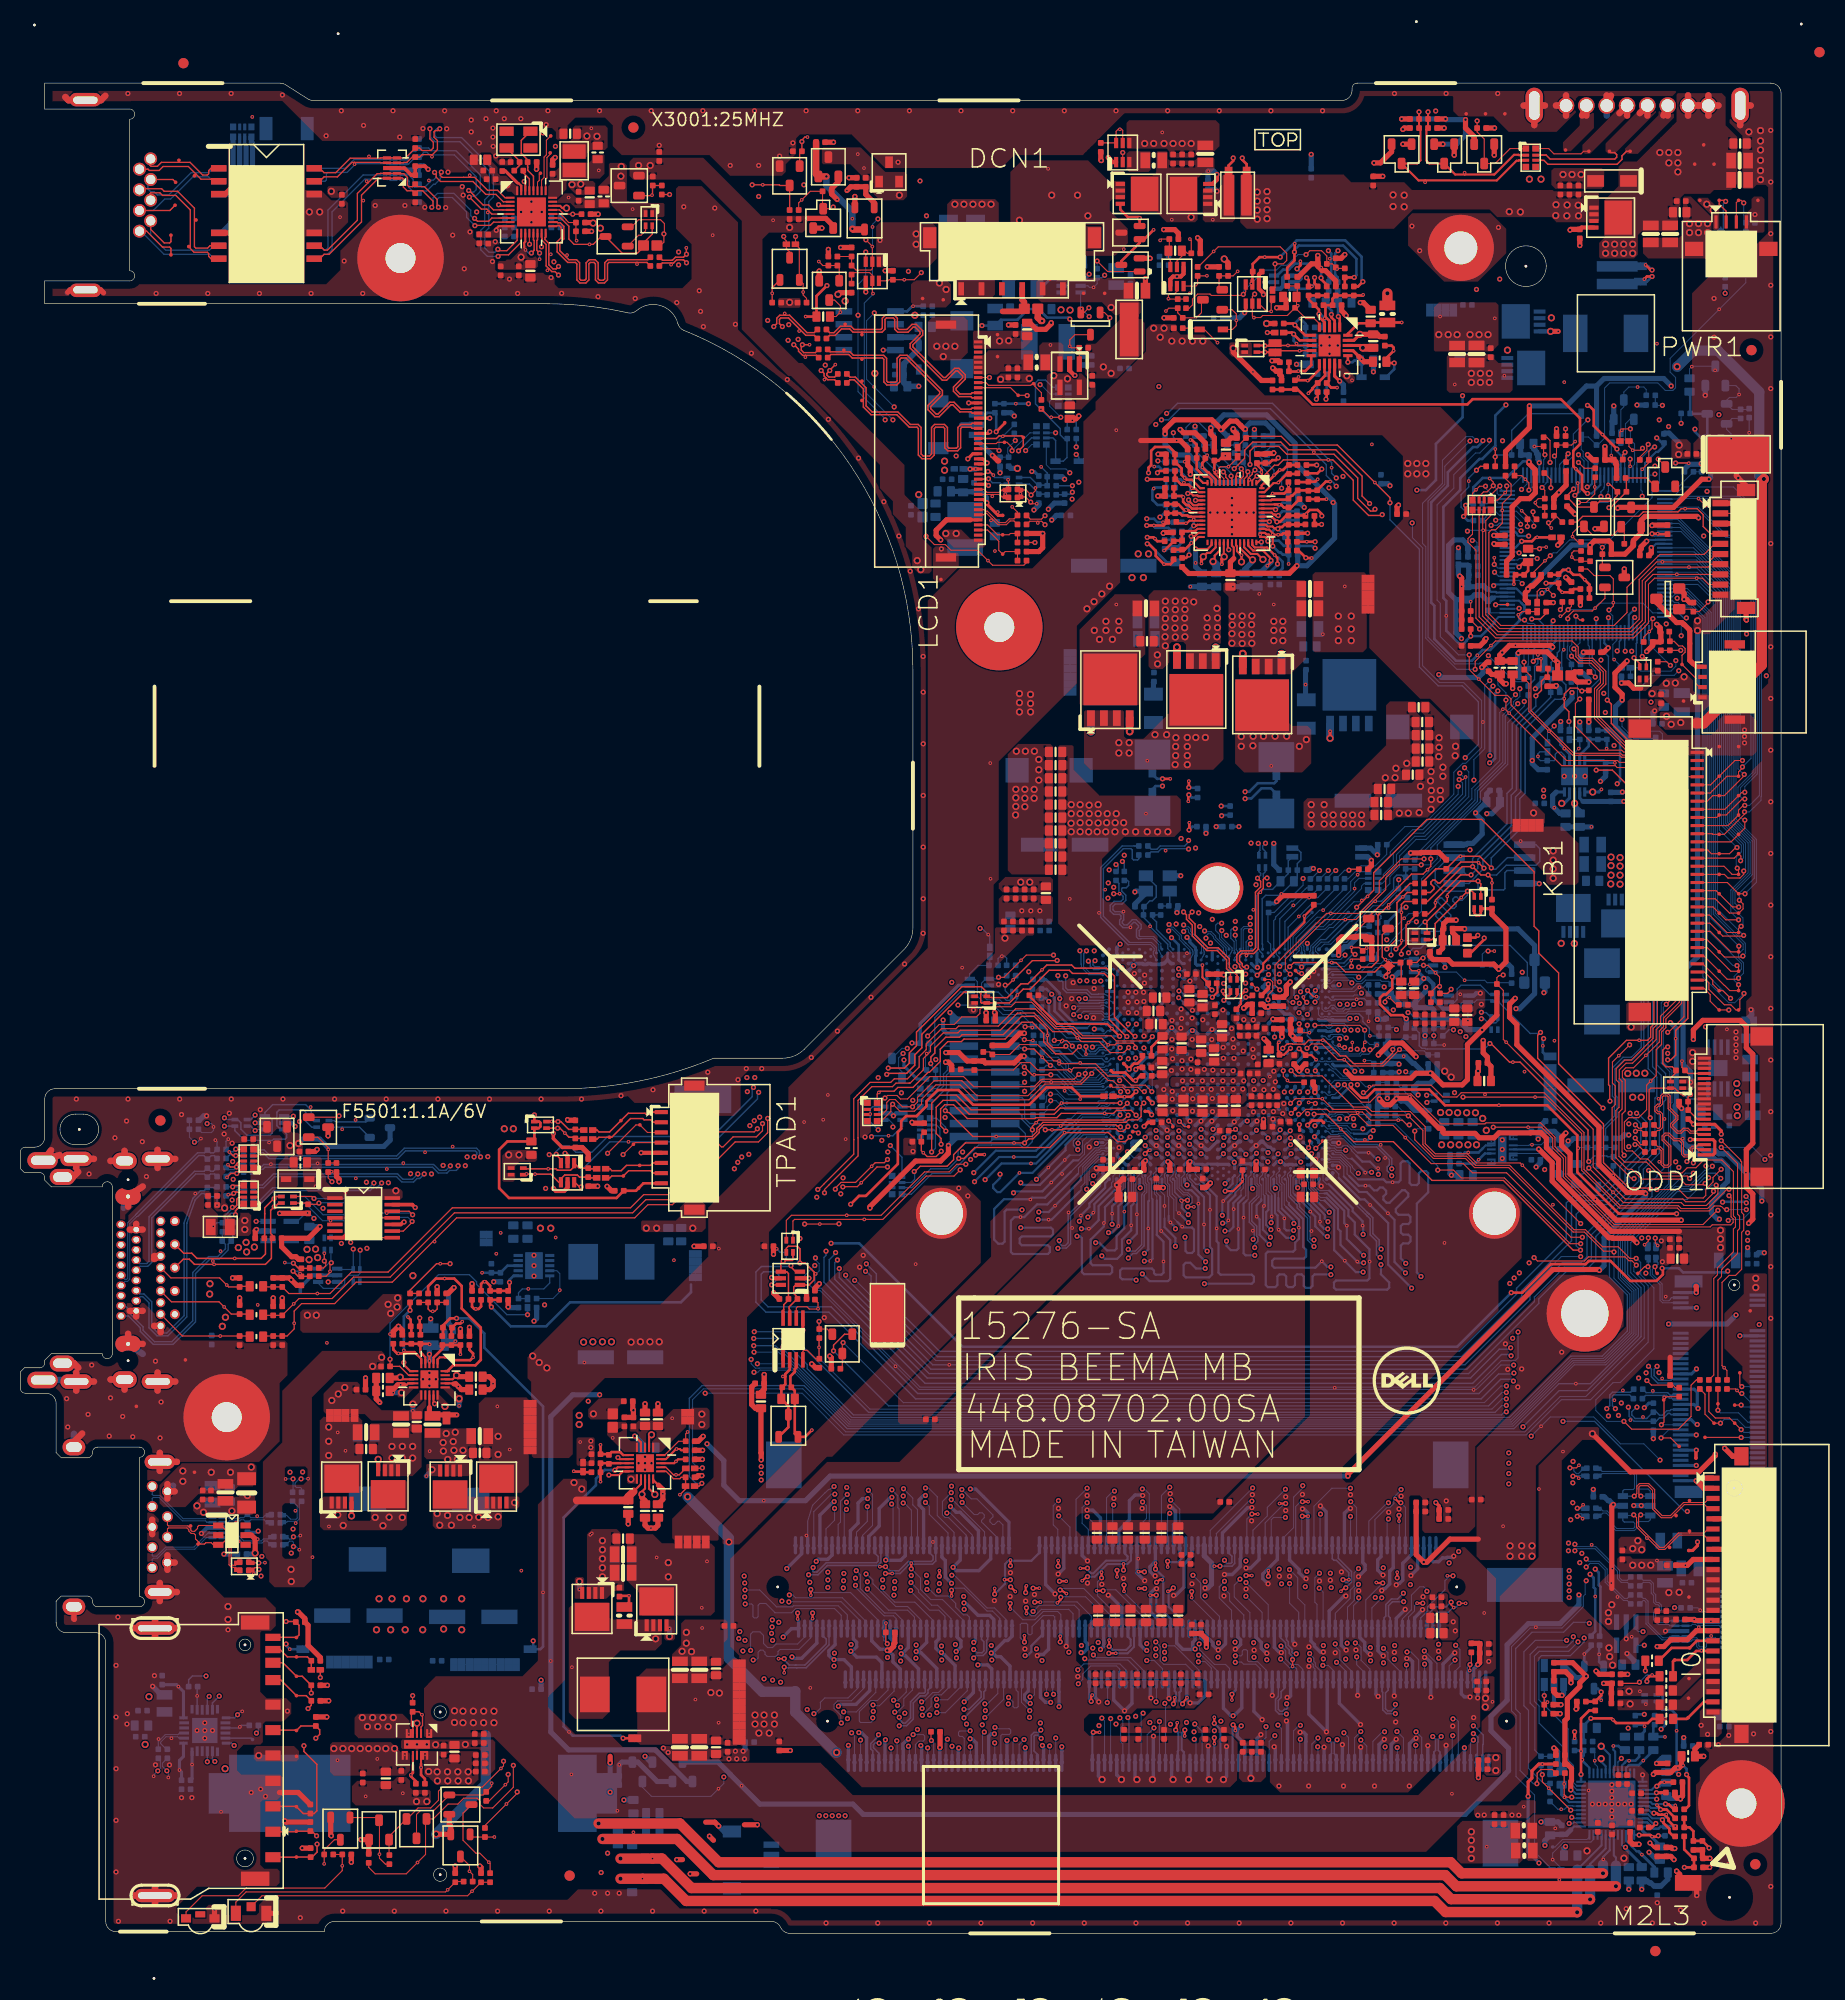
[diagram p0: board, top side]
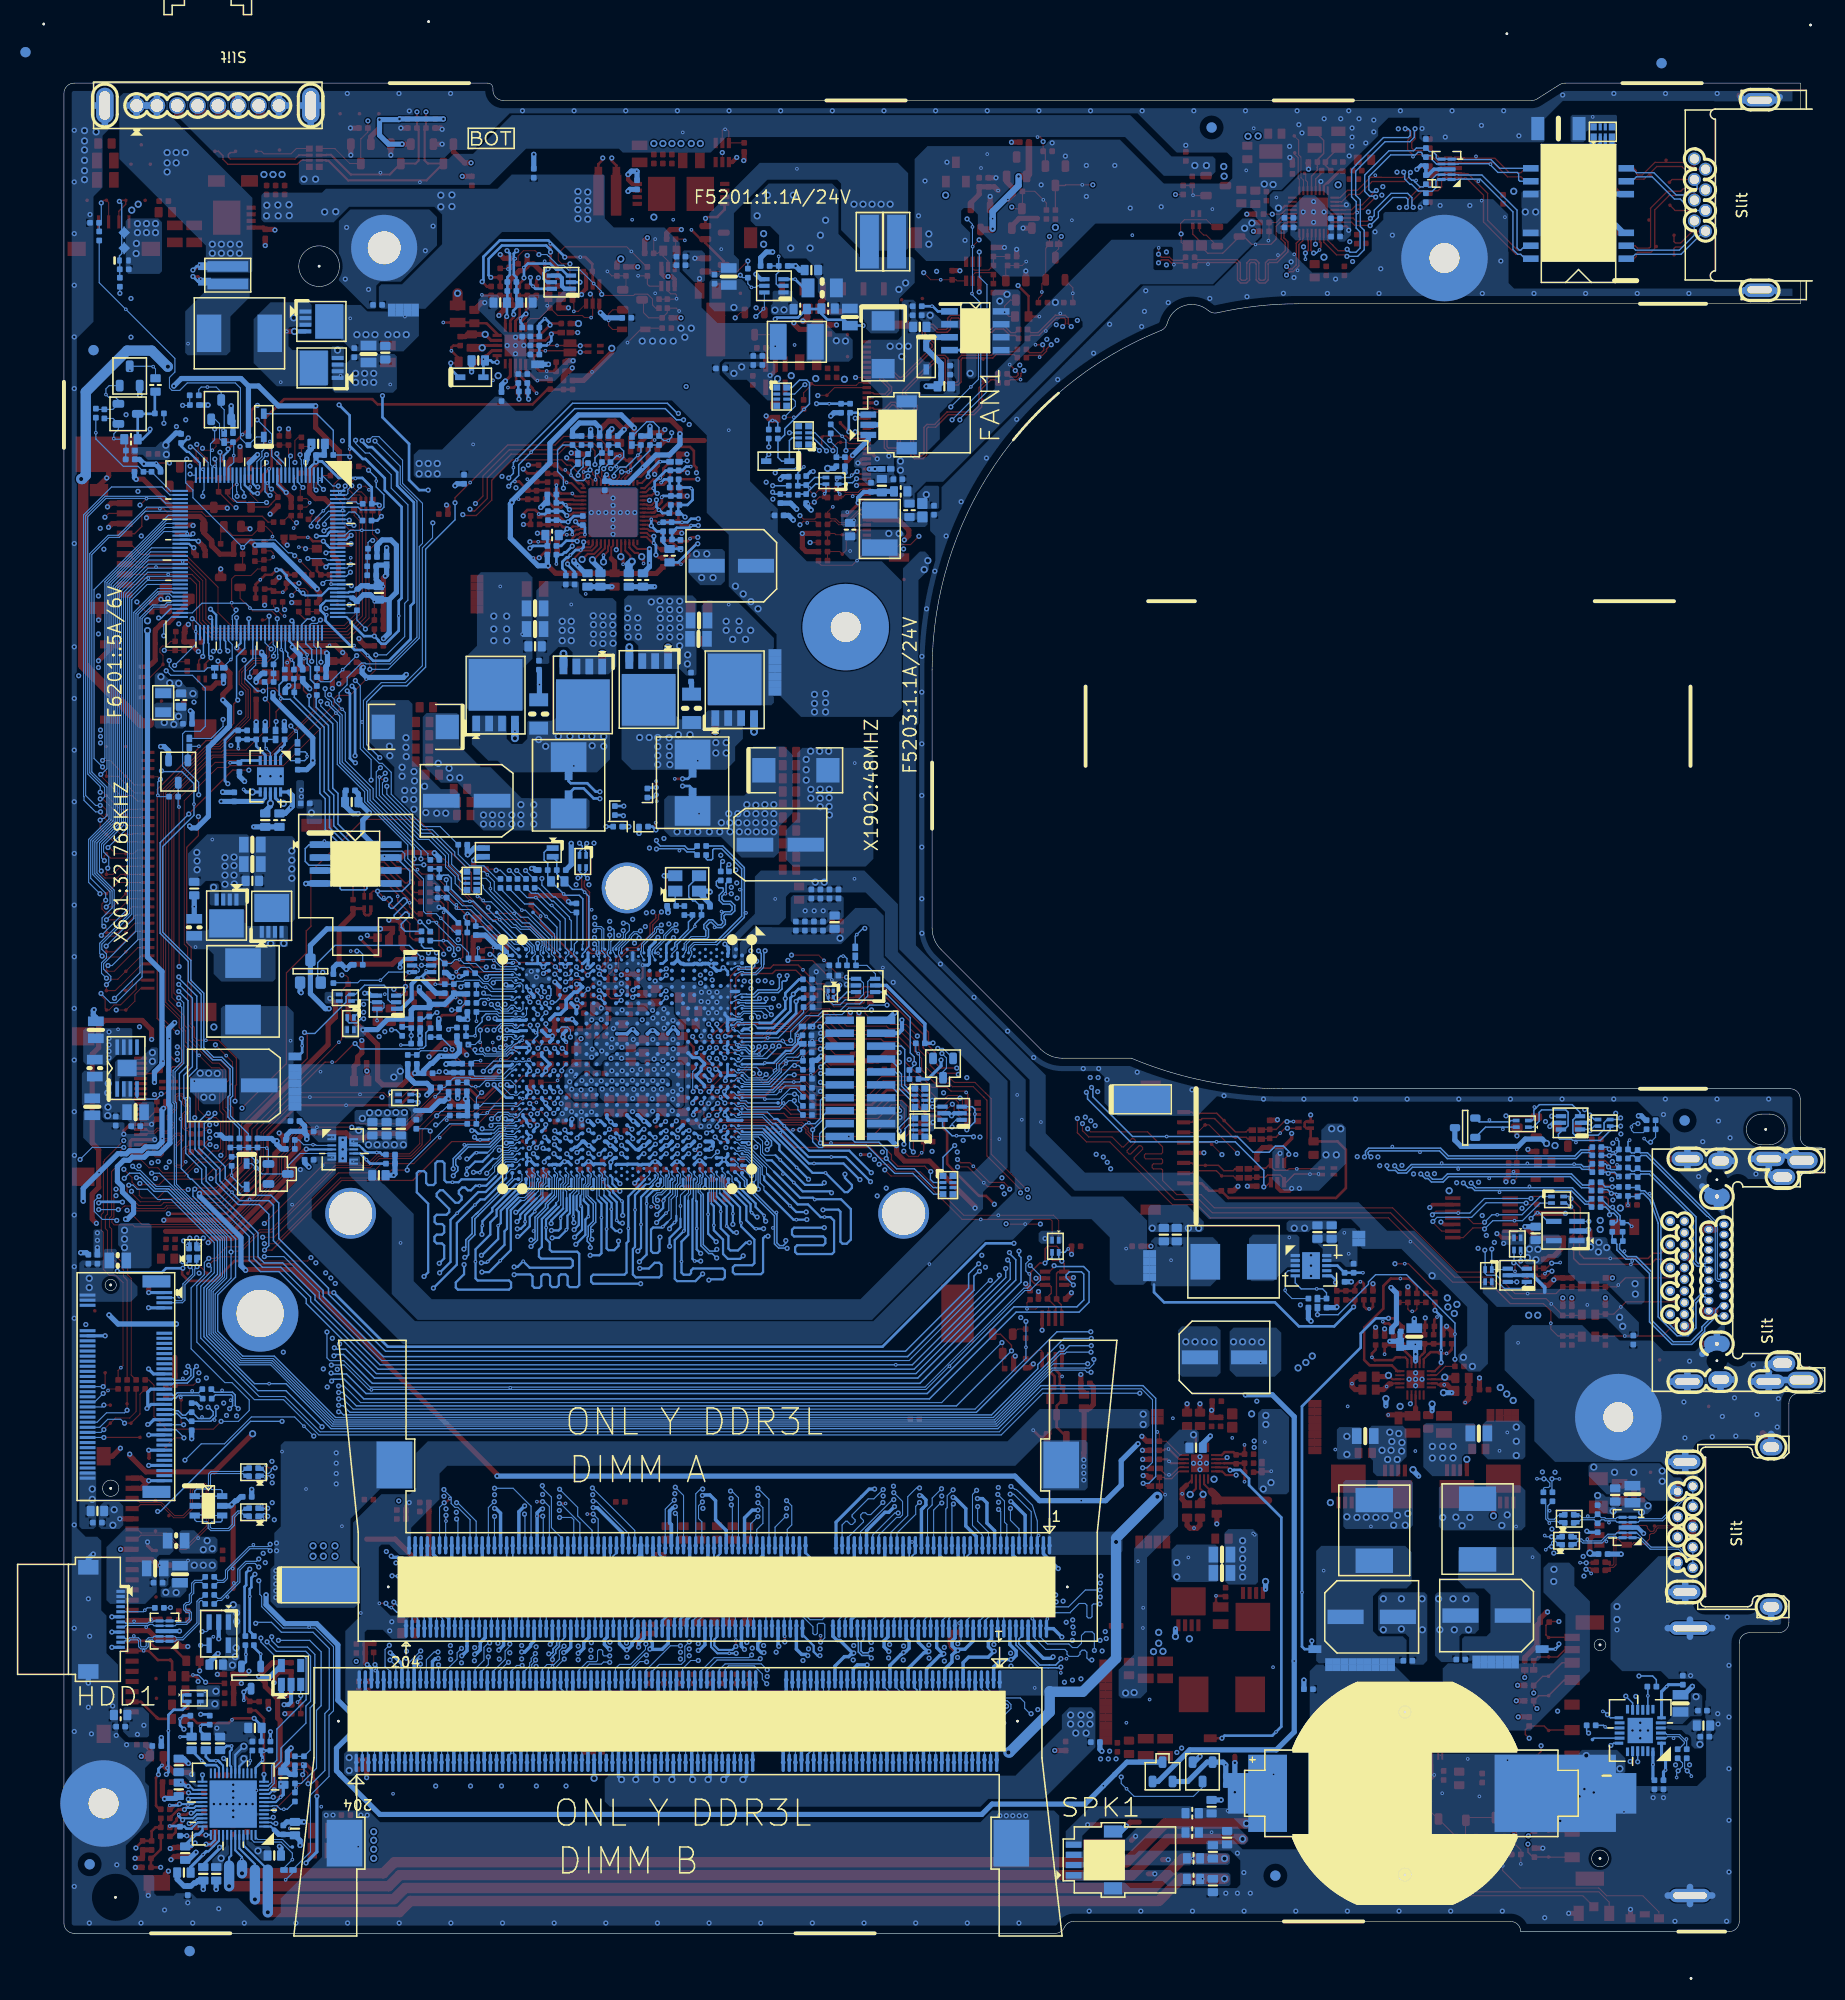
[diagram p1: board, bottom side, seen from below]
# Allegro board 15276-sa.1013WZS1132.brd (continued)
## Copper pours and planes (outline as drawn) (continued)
0D95V_S5 on BOTTOM: 119.71,89.36 119.58,89.48 119.58,90.5 119.71,90.63 119.96,90.63 120.35,90.25 121.23,90.25 121.62,90.63 121.87,90.63 122,90.5 122,89.48 121.87,89.36 121.62,89.36 121.23,89.74 120.35,89.74 119.96,89.36
0D95V_S5 on BOTTOM: 126.85,92.91 126.34,93.41 125.45,93.41 125.2,93.67 125.2,94.05 125.32,94.18 125.7,94.18 125.83,94.05 126.21,94.05 126.34,94.18 126.34,94.81 126.47,94.94 127.61,94.94 127.86,94.68 127.86,94.05 127.35,93.54 127.35,93.16 127.1,92.91
0D95V_S5 on BOTTOM: 146.46,77.81 146.41,77.86 146.41,79.39 144.51,81.29 143.75,81.29 141.84,83.2 140.44,83.2 139.86,83.78 139.86,85.28 140.06,85.48 150.22,85.48 150.35,85.35 150.35,80.78 148.93,79.36 148.93,78.57 148.17,77.81 ; 2 cut-outs
0D95V_S5 on L4: 120.19,89.5 121.74,89.5 121.74,89.5 122.01,89.5 122.28,89.77 122.28,91.86 122.56,92.14 122.93,92.14 123.16,91.92 123.16,91.31 123.34,91.13 124.38,91.13 124.42,91.13 125.35,92.05 125.35,92.8 125.83,93.29 126.01,93.29 126.29,93.57 126.86,93.57 127.87,94.58 127.87,95.62 127.67,95.82 124.57,95.82 124.24,95.49 124.24,92.6 124.14,92.5 123.67,92.5 123.21,92.96 122.22,92.96 120.7,91.43 120.7,90.67 120.06,90.04 120.06,89.63
0D675V_S0 on TOP: 144.25,15.5 144,15.76 144,17.54 144.13,17.66 145.52,17.66 145.65,17.54 145.65,15.76 145.4,15.5 ; 3 cut-outs
0D675V_S0 on TOP: 139.83,28.81 139.58,29.07 139.58,31.79 139.45,31.91 139.45,33.36 139.55,33.46 140.27,33.46 140.44,33.28 140.44,32.57 140.42,32.55 140.42,32.12 141.46,31.08 141.46,29.17 141.1,28.81 ; 5 cut-outs
0D675V_S0 on TOP: 144,21.85 143.75,22.11 143.75,25.16 143.87,25.28 144.89,25.28 145.02,25.16 145.02,22.36 144.51,21.85 ; 2 cut-outs
0D675V_S0 on TOP: 66.02,49.54 65.77,49.79 65.77,51.45 66.02,51.7 67.55,51.7 67.8,51.45 67.8,49.79 67.55,49.54
0D675V_S0 on BOTTOM: 143.87,21.73 143.75,21.85 143.75,23.63 144,23.89 144,25.79 143.62,26.17 143.62,29.6 143.36,29.86 141.84,29.86 140.95,28.97 139.55,28.97 139.33,29.2 139.33,31.05 139.53,31.25 141.08,31.25 142.22,32.4 142.22,37.98 141.97,38.24 141.21,38.24 140.19,37.22 139.17,37.22 139.05,37.35 139.05,39.89 136.25,42.68 136.25,45.22 135.49,45.98 79.61,45.98 75.93,49.67 66.66,49.67 66.4,49.92 66.4,51.32 66.66,51.57 77.2,51.57 80.37,48.4 137.4,48.4 138.54,47.25 138.54,43.83 139.17,43.19 141.97,43.19 144.76,40.4 144.76,36.71 144,35.95 144,31.25 145.52,29.73 145.52,22.74 144.51,21.73
0D675V_S0 on BOTTOM: 144.38,15.5 144.25,15.63 144.25,17.79 144.38,17.92 145.4,17.92 145.65,17.66 145.65,15.76 145.4,15.5
0D675V_S0 on L3: 144.63,23.63 144.76,23.51 144.76,19.57 145.52,18.81 145.52,15.76 145.27,15.5 144.25,15.5 143.75,16.01 143.75,18.17 143.24,18.68 143.24,23.51 143.36,23.63
1D8V_PWR on BOTTOM: 60.43,63.64 59.67,64.4 59.67,67.96 60.18,68.46 65.89,68.46 66.28,68.08 66.28,63.76 66.15,63.64 ; 3 cut-outs
1D8V_S0 on TOP: 95.51,93 95,93.51 95,95.54 95.87,96.4 95.87,98.82 95.99,98.94 99.7,98.94 99.73,98.92 99.73,98.26 99.6,98.13 98.99,98.13 95.74,94.88 95.74,93.81 95.94,93.61 96.35,93.61 96.5,93.46 96.5,93.1 96.4,93 ; 3 cut-outs
1D8V_S0 on BOTTOM: 93.71,60.34 82.79,71.26 82.79,72.91 80.37,75.32 80.37,83.83 92.56,96.02 92.56,100.09 93.33,100.85 95.36,100.85 96.88,99.32 97.9,99.32 98.28,98.94 103.54,98.94 103.56,98.97 105.18,98.97 106.7,97.45 106.7,95.84 106.88,95.66 107.92,95.66 108.05,95.53 108.05,95.33 107.92,95.2 107.16,95.2 107.06,95.3 106.68,95.3 106.6,95.23 106.4,95.23 106.3,95.33 106.3,96.18 106.02,96.46 106.02,96.78 105.51,97.29 96.76,97.29 94.85,99.2 94.22,99.2 93.96,98.94 93.96,95.39 82.15,83.58 82.15,76.46 83.67,74.94 85.83,74.94 86.09,74.69 86.09,71.13 94.85,62.37 137.01,62.37 138.79,64.15 138.79,70.75 141.71,73.67 141.79,73.67 142.43,74.31 142.43,75.04 142.63,75.25 143.49,75.25 144.08,75.83 144.08,76.34 144.15,76.41 145.09,76.41 145.14,76.36 145.14,74.59 140.95,70.39 140.95,62.88 138.41,60.34 ; 7 cut-outs
1D8V_S0 on BOTTOM: 97.39,92.52 97.34,92.57 97.34,93.38 97.11,93.61 96.73,93.61 96.5,93.38 96.5,93.1 96.37,92.97 94.85,92.97 94.72,93.1 94.72,93.36 94.85,93.48 95.99,93.48 96.48,93.97 96.48,94.47 96.58,94.58 97.34,94.58 97.47,94.45 97.47,93.79 97.64,93.61 98.2,93.61 98.41,93.41 98.41,92.59 98.33,92.52
1D8V_S0 on BOTTOM: 87.74,78.88 87.48,79.13 87.48,80.53 87.61,80.66 88.75,80.66 88.88,80.53 88.88,79 88.75,78.88
1D8V_S5 on TOP: 96.63,102.37 96.25,102.75 96.25,103.26 96.88,103.9 101.33,103.9 101.58,103.64 101.58,102.5 101.45,102.37 ; 6 cut-outs
1D8V_S5 on BOTTOM: 92.82,57.92 82.53,68.21 79.86,68.21 77.83,70.24 72.12,70.24 70.33,68.46 70.33,64.29 69.82,63.78 67.02,63.78 66.66,64.15 66.66,70.11 69.01,72.46 74.09,72.46 78.59,76.97 78.59,83.96 91.17,96.53 91.17,101.23 94.47,104.53 104.63,104.53 105.24,103.92 105.24,100.26 107.47,98.03 107.49,98.03 107.49,96 107.38,95.89 107.08,95.89 106.91,96.07 106.91,96.88 106.9,96.89 106.9,97.67 105.38,99.19 102.86,99.19 102.18,99.87 102.18,101.95 101.76,102.37 94.34,102.37 92.44,100.47 92.44,96.15 80.12,83.83 80.12,74.88 79.67,74.43 79.67,72.97 82.4,70.24 83.55,70.24 93.58,60.21 138.67,60.21 148.83,70.37 148.83,72.38 146.46,74.74 146.46,76.26 146.62,76.41 148.78,76.41 148.95,76.24 148.95,75.32 149.27,75 149.59,75.32 150.17,75.32 150.3,75.19 150.3,73.98 151.24,73.04 151.24,69.35 139.81,57.92 ; 6 cut-outs
1D35V_PWR on TOP: 69.32,18.43 69.2,18.55 60.94,18.55 60.69,18.81 60.69,25.16 61.58,26.05 69.07,26.05 70.09,27.06 70.47,27.06 70.59,26.93 70.59,18.55 70.47,18.43 ; 8 cut-outs
1D35V_PWR on BOTTOM: 67.29,23.12 66.66,23.76 66.66,36.97 63.61,40.02 63.61,46.75 63.23,47.13 62.08,47.13 61.96,47.25 61.96,48.02 61.58,48.4 61.58,49.29 61.83,49.54 63.48,49.54 65.01,48.02 65.01,40.78 67.93,37.86 67.93,27.44 69.45,25.92 69.45,23.38 69.2,23.12 ; 1 cut-out
1D35V_S3 on TOP: 82.79,14.36 78.72,18.43 70.85,18.43 70.72,18.55 70.72,27.32 69.83,28.2 69.83,36.84 79.36,46.37 86.47,46.37 89.66,49.55 89.66,50.54 108.87,69.76 108.87,75.6 110.17,76.9 110.17,78.37 111.06,79.26 111.67,79.26 111.95,79.54 111.95,80.3 112.02,80.22 114.08,80.22 114.21,80.35 114.21,80.4 114.84,80.4 114.79,80.35 114.79,80.22 114.84,80.17 121.62,80.17 121.85,80.4 123.96,80.4 124.29,80.07 124.29,79 124.62,78.67 126.09,78.67 126.37,78.4 126.37,50.84 118.35,42.81 118.35,42.3 117.33,41.29 104.25,41.29 103.87,40.9 103.87,39.63 104.38,39.13 114.28,39.13 114.54,38.87 114.54,31.63 114.28,31.38 104.5,31.38 103.87,30.74 103.87,26.81 104.63,26.05 104.63,25.28 105.01,24.9 116.19,24.9 116.31,24.78 116.31,23 115.42,22.11 109.84,22.11 109.33,21.6 105.14,21.6 104.63,21.09 104.63,19.95 105.14,19.44 114.54,19.44 115.3,18.68 115.81,18.68 115.93,18.81 115.93,19.19 116.19,19.44 116.82,19.44 117.33,18.93 117.71,18.93 118.22,19.44 119.11,19.44 119.74,18.81 119.74,15.89 119.68,15.82 119.68,15.06 118.98,14.36 ; 75 cut-outs
1D35V_S3 on BOTTOM: 83.04,12.46 82.28,13.22 76.82,13.22 71.74,18.3 71.74,21.85 72.12,22.24 74.28,22.24 75.04,21.47 75.04,20.08 79.61,15.5 119.62,15.5 120,15.12 120,12.96 119.49,12.46 ; 2 cut-outs
1D35V_S3 on L2VCC: 104.07,14.55 103.27,15.36 103.27,25.03 102.63,25.68 98.92,25.68 97.18,27.42 97.18,28.61 94.15,31.64 94.15,32.7 93.19,33.67 93.19,41.61 93.7,42.12 93.7,58.78 98.28,63.37 100.54,63.37 103.25,66.07 103.25,70.24 105.84,72.83 105.84,74.66 107.02,75.84 108.6,75.84 109.7,76.94 109.7,77.73 111.41,79.45 112.07,79.45 112.58,79.96 120.2,79.96 121.2,80.96 121.2,80.97 123.22,80.97 123.6,80.59 127.49,80.59 127.86,80.22 127.86,79.22 128.68,78.41 130.59,78.41 132.81,76.18 132.81,74.56 134.39,72.98 134.39,53.05 126.32,44.98 121.52,44.98 119.32,42.79 119.32,39.97 114.52,35.17 114.52,30.74 116.15,29.12 116.15,27.21 118.33,25.03 120.67,22.69 120.67,18.99 119.7,18.02 119.7,15.18 119.08,14.55
1D35V_S3 on L3: 71.48,22.11 74.15,22.11 78.98,17.28 119.87,17.28 120.25,16.9 120.25,14.74 119.49,13.98 76.31,13.98 71.1,19.19 71.1,21.73
1D35V_S3 on L5GND: 122.49,75.77 121.83,76.43 121.42,76.43 121.09,76.1 115.55,76.1 115.28,76.38 114.86,76.38 114.58,76.1 113.37,76.1 113.12,76.35 112.6,76.35 112.37,76.12 111.16,76.12 110.75,76.53 110.53,76.53 110.36,76.7 110.36,78.42 111.9,79.96 119.54,79.96 120.17,79.32 125.25,79.32 127.3,77.27 127.3,76.67 126.39,75.77 124.83,75.77 124.17,76.43 123.78,76.43 123.12,75.77
1D35V_S3 on L5GND: 104.38,14.65 103.83,15.2 103.83,23.1 102.61,24.32 102.61,25.36 101.53,26.44 98.51,26.44 98.04,26.91 98.04,30.42 97.4,31.05 97.4,31.46 96.2,32.66 95.79,32.66 95.42,33.03 95.42,35.57 96.89,37.03 98.38,37.03 99.51,38.16 99.51,40.32 102.45,43.25 102.88,43.25 103.87,44.25 113.29,44.25 114.83,42.71 114.83,37.3 113.71,36.18 113.71,32.47 116,30.18 116,29.01 116.38,28.63 116.38,27.67 117.5,26.54 118.55,26.54 119.16,25.93 119.59,25.93 119.68,25.84 119.68,21.39 120.34,20.73 120.34,18.78 119.45,17.9 119.45,15.05 119.05,14.65
3D3V_AUX_KBC on TOP: 119.18,155.08 118.93,155.33 118.93,156.35 119.06,156.47 121.01,156.47 121.14,156.35 121.14,155.2 121.01,155.08
3D3V_AUX_KBC on TOP: 159.11,122.18 158.99,122.31 158.99,123.58 159.11,123.71 160.13,123.71 160.51,124.09 160.51,124.34 160.69,124.52 161.25,124.52 161.37,124.39 161.37,123.68 159.87,122.18 ; 1 cut-out
3D3V_AUX_S5 on BOTTOM: 145.9,91.45 145.78,91.58 145.78,92.47 145.9,92.59 147.43,92.59 147.56,92.47 147.56,91.58 147.43,91.45
3D3V_CARD_S0 on TOP: 23.22,16.9 22.97,17.16 22.97,18.2 23.2,18.43 26.91,18.43 27.41,17.92 27.41,17.16 27.16,16.9
3D3V_CARD_S0 on BOTTOM: 13.98,20.58 13.22,21.35 12.17,21.35 12.05,21.47 12.05,23.38 12.3,23.63 13.06,23.63 13.16,23.53 13.16,22.79 13.6,22.36 14.84,22.36 15.09,22.11 15.09,21.22 15.48,20.84 16.59,20.84 16.64,20.79 16.64,20.64 16.59,20.58 ; 2 cut-outs
3D3V_CARD_S0 on BOTTOM: 19.87,15.63 19.62,15.89 19.62,17.23 20.43,18.04 23.86,18.04 24.24,17.66 24.24,15.89 23.98,15.63 ; 4 cut-outs
3D3V_LAN_S5 on TOP: 59.29,168.79 58.15,169.94 58.15,170.7 57.89,170.95 57,170.95 56.88,171.08 56.88,171.84 57.89,172.86 57.89,174 58.02,174.13 59.42,174.13 59.67,173.87 59.67,170.44 59.93,170.19 63.23,170.19 63.35,170.06 63.35,168.92 63.23,168.79 ; 1 cut-out
3D3V_LAN_S5 on TOP: 47.1,163.61 46.97,163.74 46.97,164.35 47.1,164.48 47.71,164.48 47.86,164.63 47.91,164.63 49.56,166.28 49.56,167.65 49.59,167.68 49.77,167.68 49.79,167.65 49.79,165.47 50.25,165.01 50.58,165.01 50.91,164.68 50.91,163.94 50.58,163.61 ; 3 cut-outs
3D3V_LAN_S5 on TOP: 48.65,170.95 48.32,171.28 47.96,171.28 47.33,171.92 46.54,171.92 46.36,172.1 46.36,172.88 46.11,173.14 46.11,173.72 45.93,173.9 45.6,173.9 45.52,173.98 45.52,174.71 45.6,174.79 46.29,174.79 46.39,174.69 46.39,174.25 46.95,173.7 46.95,173.14 47.23,172.86 47.96,172.86 48.98,171.84 48.98,170.98 48.95,170.95 ; 1 cut-out
3D3V_LAN_S5 on L4: 46.34,174.38 59.04,174.38 59.54,173.87 59.54,172.1 58.53,171.08 48.37,171.08 47.73,170.44 47.73,167.27 49.77,165.24 49.77,164.09 49.38,163.71 45.83,163.71 45.45,164.09 45.45,173.49
3D3V_PWR on BOTTOM: 28.18,26.81 27.92,27.06 27.92,37.22 28.68,37.98 35.67,37.98 36.05,37.6 36.05,34.68 35.29,33.92 33.51,33.92 32.87,33.28 32.87,29.6 33.26,29.22 35.41,29.22 35.67,28.97 35.67,26.93 35.54,26.81 ; 1 cut-out
3D3V_S0 on TOP: 165.08,127.77 164.57,128.28 164.57,129.04 165.21,129.68 165.59,129.68 166.73,130.82 166.73,131.84 166.86,131.96 168.51,131.96 168.64,131.84 168.64,130.95 168.63,130.94 168.63,130.22 166.17,127.77
3D3V_S0 on TOP: 163.3,82.94 163.18,83.07 163.18,83.96 163.3,84.08 164.57,84.08 164.7,83.96 164.7,83.2 164.45,82.94
3D3V_S0 on TOP: 74.68,159.88 74.53,160.03 74.53,160.72 74.66,160.84 76.64,160.84 76.74,160.74 76.74,160.01 76.61,159.88
3D3V_S0 on TOP: 101.84,149.87 100.97,150.73 100.97,153.22 101.18,153.43 104.38,153.43 105.14,152.66 105.52,152.66 105.77,152.41 105.77,151.27 104.38,149.87 ; 3 cut-outs
3D3V_S0 on TOP: 143.62,36.71 143.24,37.09 143.24,47.76 153.27,57.8 156.06,57.8 157.97,59.7 157.97,61.22 162.92,66.18 162.92,69.15 163.06,69.29 166.29,69.29 166.48,69.48 167.62,69.48 167.75,69.35 167.75,66.81 166.86,65.92 166.86,64.86 166.4,64.4 166.4,59.62 163.18,56.4 160.26,56.4 156.45,52.59 155.68,52.59 149.08,45.98 149.08,36.97 148.83,36.71 ; 8 cut-outs
3D3V_S0 on TOP: 82.66,78.24 82.56,78.34 82.56,81.82 82.79,82.05 83.55,82.05 83.67,81.93 83.67,78.83 83.09,78.24
3D3V_S0 on TOP: 93.45,90.43 93.2,90.69 93.2,92.21 93.33,92.34 94.09,92.34 94.22,92.21 94.22,90.69 93.96,90.43
3D3V_S0 on TOP: 162.54,145.04 162.41,145.17 162.41,146.82 162.54,146.95 163.94,146.95 164.32,146.57 164.32,145.17 164.19,145.04 ; 1 cut-out
3D3V_S0 on TOP: 30.84,15.5 30.46,15.89 30.46,18.55 30.72,18.81 36.43,18.81 37.45,17.79 38.21,17.79 38.34,17.66 38.34,16.01 37.83,15.5 ; 6 cut-outs
3D3V_S0 on TOP: 47.53,73.92 47.4,74.05 47.4,76.49 47.96,77.05 50.5,77.05 50.83,76.72 50.83,76.08 50.62,75.87 49.07,75.87 48.67,75.47 48.67,74.1 48.5,73.92 ; 1 cut-out
3D3V_S0 on TOP: 86.95,76.52 86.85,76.62 86.85,78.12 86.98,78.24 87.97,78.24 88.12,78.09 88.12,76.67 87.97,76.52 ; 1 cut-out
3D3V_S0 on BOTTOM: 49.77,73.04 47.1,75.7 47.1,79.26 47.48,79.64 48.88,79.64 49.51,79 49.51,76.21 50.65,75.07 52.94,75.07 53.19,75.32 53.19,77.1 53.32,77.23 53.96,77.23 54.34,76.85 54.34,74.18 53.19,73.04
3D3V_S0 on BOTTOM: 18.52,58.56 18.27,58.81 18.27,60.08 21.57,63.38 32.24,63.38 32.49,63.64 32.49,64.27 32.62,64.4 33.51,64.4 33.64,64.27 33.64,63 32.24,61.61 27.29,61.61 26.14,60.46 21.44,60.46 19.54,58.56 ; 2 cut-outs
3D3V_S0 on BOTTOM: 75.17,67.83 75.04,67.96 75.04,68.97 75.17,69.1 77.07,69.1 77.32,68.84 77.32,68.08 77.07,67.83
3D3V_S0 on BOTTOM: 164.83,65.42 164.57,65.67 164.57,69.61 164.83,69.86 167.62,69.86 167.88,69.61 167.88,67.7 167.49,67.32 167.49,65.67 167.24,65.42
3D3V_S0 on BOTTOM: 138.16,79.77 137.9,80.02 137.9,80.53 138.92,81.54 139.86,81.54 139.96,81.65 139.96,82.92 140.11,83.07 141.18,83.07 141.28,82.97 141.28,81.27 141.18,81.16 139.43,81.16 139.05,80.78 139.05,80.02 138.79,79.77 ; 1 cut-out
3D3V_S0 on BOTTOM: 89.64,140.22 89.52,140.35 89.52,141.62 88.37,142.76 86.72,142.76 67.29,162.19 60.18,162.19 55.48,166.89 55.48,168.03 56.12,168.67 57.26,168.67 59.35,166.57 70.15,166.57 78.72,158 78.72,156.47 81.64,153.55 81.64,151.9 88.37,145.17 91.17,145.17 91.29,145.04 91.29,143.77 91.04,143.52 91.04,142.63 90.66,142.25 90.66,140.35 90.53,140.22 ; 6 cut-outs
3D3V_S0 on BOTTOM: 12.17,18.17 11.92,18.43 11.92,20.84 12.17,21.09 12.94,21.09 13.57,20.46 15.48,20.46 15.6,20.33 16.57,20.33 16.64,20.25 16.64,20.15 16.57,20.08 15.09,20.08 14.21,19.19 13.82,19.19 12.81,18.17 ; 3 cut-outs
3D3V_S0 on BOTTOM: 162.92,144.92 162.8,145.04 162.8,146.57 162.92,146.7 163.68,146.7 164.19,146.19 166.48,146.19 166.61,146.06 166.61,145.55 166.48,145.43 165.46,145.43 164.95,144.92
3D3V_S0 on L2VCC: 166.28,67.18 166.19,67.27 166.19,69.6 166.33,69.75 167.6,69.75 169.01,71.15 169.01,79.54 169.97,80.5 169.97,89.78 169.67,90.08 169.67,91.45 170.23,92.01 170.23,122.26 164.51,127.98 164.51,129.27 164.81,129.56 165.94,129.56 171.55,123.96 171.55,77.46 170.81,76.72 170.81,70.88 169.01,69.08 169.01,67.6 168.58,67.18
3D3V_S0 on L3: 73.13,54.49 72.88,54.75 72.88,66.76 66.83,72.81 51.52,72.81 51.37,72.96 51.37,73.62 51.54,73.8 53.83,73.8 54.62,74.59 68.43,74.59 74.43,68.59 76.94,68.59 77.58,67.96 77.58,65.42 78.85,64.15 78.85,62.24 78.09,61.48 78.09,55.64 76.94,54.49
3D3V_S0 on L3: 55.61,168.67 58.78,168.67 68.31,178.19 131.3,178.19 132.19,179.08 136.25,179.08 138.28,177.05 158.22,177.05 163.68,171.59 163.68,167.02 165.59,165.11 165.59,145.55 164.95,144.92 163.05,144.92 162.67,145.3 162.67,151.39 163.68,152.41 163.68,164.09 161.02,166.76 161.02,170.95 157.08,174.89 146.54,174.89 145.78,174.13 136.25,174.13 134.35,176.03 119.36,176.03 117.96,174.64 68.31,174.64 60.69,167.02 55.73,167.02 55.35,167.4 55.35,168.41
3D3V_S0 on L3: 22.21,64.27 25.76,67.83 25.76,78.37 26.02,78.62 27.79,78.62 28.43,77.99 48.5,77.99 48.88,78.37 48.88,79.89 48.37,80.4 39.48,80.4 38.72,81.16 24.75,81.16 23.6,80.02 22.71,80.02 22.46,79.77 22.46,78.37 23.6,77.23 23.6,67.19 22.84,66.43 21.7,66.43 19.67,64.4 19.67,61.86 19.29,61.48 19.29,59.45 19.54,59.19 22.33,59.19 22.59,59.45 22.59,61.99 22.21,62.37
3D3V_S0 on L4: 97.77,144.41 98.28,144.41 98.53,144.16 98.53,143.52 96.37,141.36 92.82,141.36 90.53,143.65 90.53,150.51 92.31,152.28 99.8,152.28 100.18,151.9 100.57,151.9 100.82,152.16 100.82,153.05 101.2,153.43 103.23,153.43 103.61,153.05 103.61,152.16 103.55,152.09 103.55,150.95 100.18,147.58 97.9,147.58 97.26,146.95 97.26,144.92
3D3V_S0 on L4: 164.7,137.3 165.72,136.28 165.72,130.44 166.22,129.93 166.22,127.52 165.97,127.26 165.08,127.26 164.32,128.03 164.32,135.14 162.92,136.54 162.92,144.92 162.67,145.17 162.67,146.57 162.92,146.82 164.32,146.82 164.83,146.31 164.83,144.28 164.7,144.16
3D3V_S0 on L4: 38.08,2.8 37,3.88 18.59,3.88 15.98,6.49 11.92,6.49 10.27,8.14 10.27,18.3 11.28,19.31 11.28,25.41 16.36,30.49 16.36,46.37 14.97,47.76 14.97,52.72 16.36,54.11 16.36,59.57 17.89,61.1 20.3,61.1 20.56,60.84 20.56,57.29 19.41,56.14 19.41,54.11 17.25,51.95 17.25,48.78 19.79,46.24 19.79,29.73 14.33,24.27 14.33,18.81 12.68,17.16 12.68,12.46 14.97,10.17 24.75,10.17 26.91,8.01 29.57,8.01 30.21,8.65 30.21,10.3 30.46,10.55 30.46,18.43 30.84,18.81 36.43,18.81 43.16,12.08 73.01,12.08 73.77,11.31 138.28,11.31 144.51,17.54 144.51,24.14 142.98,25.66 142.98,27.7 143.75,28.46 143.75,31.13 144.63,32.01 145.02,32.01 146.16,33.16 146.16,38.24 146.92,39 149.84,39 151.87,36.97 151.87,21.19 151.24,20.56 151.24,20.38 151.28,20.34 151.28,8.05 150.86,7.63 149.33,7.63 144.51,2.8
3D3V_S5 on TOP: 33.26,19.19 32.87,19.57 32.87,21.22 33.26,21.6 37.57,21.6 38.34,20.84 38.34,19.31 38.21,19.19
3D3V_S5 on TOP: 166.61,167.52 166.48,167.65 166.48,168.79 164.95,170.32 164.95,170.57 165.08,170.7 165.97,170.7 167.11,169.56 167.11,167.65 166.99,167.52
3D3V_S5 on TOP: 88.37,133.74 87.74,134.38 87.74,135.77 87.1,136.41 87.1,138.31 85.83,139.58 85.83,140.85 84.56,142.12 84.56,144.41 75.8,153.17 75.55,153.17 70.97,157.74 70.97,168.41 66.91,172.48 60.31,172.48 59.93,172.86 59.93,174.25 60.31,174.64 67.16,174.64 72.88,168.92 77.66,168.92 77.71,168.87 77.71,168.62 77.2,168.11 77.2,167.52 76.94,167.27 73.64,167.27 73.01,166.63 73.01,158 76.56,154.44 76.94,154.44 86.98,144.41 86.98,141.49 88.75,139.71 88.75,137.17 89.64,136.28 89.64,134 89.39,133.74 ; 7 cut-outs
3D3V_S5 on TOP: 25,34.05 24.49,34.55 24.49,36.59 23.86,37.22 23.86,46.37 25.76,48.27 25.76,53.35 29.7,57.29 35.54,57.29 35.8,57.03 35.8,55.51 35.67,55.38 31.35,55.38 28.68,52.72 28.68,34.81 27.92,34.05 ; 3 cut-outs
3D3V_S5 on TOP: 138.34,96.18 138.23,96.28 137.83,96.28 137.75,96.2 137.19,96.2 137.07,96.33 137.07,96.43 136.51,96.99 136.51,98.82 136.63,98.94 137.52,98.94 137.65,98.82 137.65,97.52 137.93,97.24 138.82,97.24 138.95,97.12 138.95,96.3 138.82,96.18 ; 1 cut-out
3D3V_S5 on BOTTOM: 136.38,100.47 136.25,100.59 136.25,103.13 136.76,103.64 136.76,104.02 136.89,104.15 137.52,104.15 137.65,104.02 137.65,100.59 137.52,100.47 ; 3 cut-outs
3D3V_S5 on BOTTOM: 131.3,171.97 127.74,175.52 118.6,175.52 118.22,175.14 109.58,175.14 108.06,176.67 68.82,176.67 65.01,172.86 60.31,172.86 59.93,173.24 59.93,174.51 60.18,174.76 64.24,174.76 68.31,178.83 129.14,178.83 132.95,175.02 134.86,175.02 135.36,174.51 149.71,174.51 150.1,174.13 150.1,172.22 149.84,171.97
3D3V_S5 on BOTTOM: 143.87,88.02 143.49,88.4 143.49,89.04 143.75,89.29 145.52,89.29 145.65,89.16 145.65,88.15 145.52,88.02
3D3V_S5 on BOTTOM: 28.94,19.95 23.1,25.79 23.1,32.65 24.62,34.17 24.62,35.95 25.13,36.46 27.16,36.46 27.67,35.95 27.67,33.54 25.51,31.38 25.51,27.7 26.65,26.55 37.07,26.55 37.57,26.05 37.57,20.71 36.81,19.95
3D3V_S5 on BOTTOM: 33.89,55.26 33.13,56.02 33.13,61.86 40.37,69.1 43.03,69.1 45.83,71.89 58.91,71.89 61.83,74.81 72.75,74.81 76.63,78.69 76.63,84.4 89.39,97.17 89.39,118.76 89.14,119.01 89.14,133.11 88.12,134.12 88.12,135.52 88.5,135.9 89.01,135.9 90.66,134.25 90.66,119.52 91.04,119.14 91.04,96.78 78.21,83.96 78.21,77.48 73.77,73.04 63.35,73.04 60.56,70.24 46.59,70.24 45.7,69.35 45.7,67.57 45.45,67.32 41.64,67.32 38.59,64.27 37.83,64.27 35.16,61.61 35.16,57.8 36.05,56.91 36.05,56.27 35.03,55.26
3D3V_S5 on L4: 170.29,167.4 170.29,148.85 170.03,148.6 168.76,148.6 168.51,148.85 168.51,166.51 165.46,169.56 160.51,169.56 158.48,171.59 147.81,171.59 147.56,171.84 147.56,173.62 147.81,173.87 159.37,173.87 161.14,172.1 165.59,172.1
3D3V_WLAN_S0 on TOP: 169.78,42.17 169.53,42.43 169.53,45.1 170.16,45.73 170.16,53.86 169.4,54.62 169.4,55.76 167.62,57.54 167.62,60.97 169.53,62.88 169.53,64.78 169.65,64.91 171.69,64.91 171.81,64.78 171.81,42.43 171.56,42.17
3D3V_WLAN_S0 on BOTTOM: 170.29,39.76 170.03,40.02 170.03,45.35 170.16,45.48 171.56,45.48 171.69,45.35 171.69,40.02 171.43,39.76 ; 4 cut-outs
3D3V_WLAN_S0 on BOTTOM: 166.61,62.11 165.97,62.75 165.97,63.64 168,65.67 168,67.19 168.13,67.32 169.15,67.32 169.27,67.19 169.27,66.3 169.4,66.18 171.43,66.18 171.69,65.92 171.69,62.24 171.56,62.11 ; 3 cut-outs
3D3V_WLAN_S0 on L2VCC: 170.11,42.24 169.97,42.38 169.97,64.96 170.11,65.1 171.35,65.1 171.5,64.96 171.5,42.63 171.1,42.24
+0D675V_DDR_P on TOP: 61.37,47.33 61.35,47.36 61.35,48.27 60.84,48.78 60.84,49.06 60.56,49.34 60.05,49.34 59.95,49.44 59.95,50.07 60.05,50.18 60.56,50.18 60.81,50.43 63.1,50.43 64.24,51.57 65.31,51.57 65.49,51.4 65.49,49.79 63.02,47.33 62.16,47.33 62.14,47.36 62.14,48.37 62.59,48.83 62.59,49.29 62.47,49.41 61.83,49.41 61.55,49.13 61.55,47.36 61.53,47.33 ; 2 cut-outs
+DC_IN on TOP: 97.77,164.98 97.39,165.36 97.39,173.24 98.53,174.38 105.01,174.38 107.04,172.35 108.57,172.35 108.69,172.22 108.69,170.7 108.57,170.57 107.42,170.57 107.17,170.32 107.17,169.43 108.95,167.65 108.95,166.25 107.68,164.98
+DC_IN on TOP: 88.12,159.9 87.61,160.41 87.61,162.19 87.99,162.57 91.17,162.57 91.55,162.19 91.55,160.41 91.04,159.9
+DC_IN on BOTTOM: 91.29,157.36 91.04,157.62 91.04,160.79 89.52,162.32 89.52,164.6 89.77,164.86 94.72,164.86 97.01,167.14 97.01,171.46 97.64,172.1 103.87,172.1 105.65,170.32 105.65,168.41 105.14,167.9 103.74,167.9 102.85,167.02 102.85,165.24 102.34,164.73 100.18,164.73 99.42,163.97 99.42,163.08 99.04,162.7 99.04,161.43 97.9,160.28 97.9,159.27 97.77,159.14 94.98,159.14 94.47,158.63 94.47,158 93.83,157.36 ; 3 cut-outs
+DC_IN_C on TOP: 92.18,160.79 91.8,161.17 91.8,162.57 91.17,163.21 91.17,170.06 91.68,170.57 95.87,170.57 96.25,170.19 96.25,163.46 95.87,163.08 95.87,161.17 95.49,160.79
+DC_IN_C on BOTTOM: 108.95,162.82 108.57,163.21 107.04,163.21 106.79,163.46 106.79,164.6 107.3,165.11 107.3,169.17 103.99,172.48 97.14,172.48 96.76,172.1 96.76,167.52 94.72,165.49 90.41,165.49 90.15,165.75 90.15,173.11 91.17,174.13 104.76,174.13 109.71,169.17 109.71,163.08 109.46,162.82 ; 1 cut-out
+PWR_SRC_1D35V on TOP: 61.2,31.25 60.94,31.51 60.94,33.41 59.67,34.68 59.67,39.25 62.21,39.25 63.1,38.36 67.93,38.36 68.31,37.98 68.31,31.63 67.93,31.25 ; 1 cut-out
+PWR_SRC_1D35V on BOTTOM: 59.8,34.55 59.67,34.68 59.67,37.98 59.93,38.24 63.74,38.24 64.24,37.73 64.24,35.06 63.74,34.55
AD+ on TOP: 112.76,168.29 111.74,169.3 109.33,169.3 109.2,169.43 109.2,172.73 109.33,172.86 111.36,172.86 111.74,173.24 111.74,175.14 111.87,175.27 112.76,175.27 112.88,175.14 112.88,174.51 113.01,174.38 115.55,174.38 115.81,174.64 117.33,174.64 117.46,174.51 117.46,173.49 117.08,173.11 116.31,173.11 115.81,172.6 115.81,168.54 115.55,168.29 ; 4 cut-outs
AD+_TO_SYS on TOP: 116.57,168.29 116.31,168.54 116.31,171.46 116.44,171.59 117.84,171.59 118.22,171.97 118.22,172.86 118.35,172.98 119.36,172.98 119.49,172.86 119.49,168.54 119.23,168.29
APU_VDD on TOP: 112,81.54 111.73,81.81 111.73,83.09 111.48,83.34 111.23,83.34 110.97,83.59 110.97,84.23 111.23,84.48 111.61,84.48 111.73,84.61 111.73,84.8 111.89,84.95 112.86,84.95 113.27,85.35 116.07,85.35 116.31,85.12 119.48,85.12 119.61,84.99 119.61,84.48 119.48,84.36 113.26,84.36 113,84.1 113,83.34 113.26,83.09 114.02,83.09 114.27,83.34 120.37,83.34 120.62,83.09 120.62,81.92 120.25,81.54 ; 9 cut-outs
APU_VDD on TOP: 108.31,92.97 108.06,93.23 108.06,94.37 107.3,95.13 107.3,95.77 105.9,97.17 104.25,97.17 102.09,99.32 102.09,116.72 102.22,116.85 103.49,116.85 103.61,116.72 103.61,114.44 106.15,111.9 113.77,111.9 114.15,111.52 114.15,108.47 113.52,107.83 108.57,107.83 106.41,105.67 106.41,101.86 106.85,101.42 108.5,101.42 111.87,98.05 111.87,93.1 111.74,92.97 ; 10 cut-outs
APU_VDD on BOTTOM: 103.36,105.8 102.85,106.31 102.85,108.85 101.52,110.18 101.52,115.9 102.34,116.72 105.39,116.72 105.77,116.34 105.77,112.41 106.28,111.9 113.77,111.9 114.15,111.52 114.15,108.47 113.52,107.83 108.57,107.83 106.53,105.8
APU_VDD on BOTTOM: 112.5,81.18 112.24,81.44 112.24,85.5 112.5,85.75 113.77,85.75 114.02,85.5 114.53,85.5 114.65,85.63 115.92,85.63 116.05,85.5 116.43,85.5 116.69,85.75 119.99,85.75 120.12,85.63 120.12,84.48 119.86,84.23 113.77,84.23 113.38,83.85 113.38,83.34 113.51,83.21 114.02,83.21 114.15,83.34 120.5,83.34 120.62,83.21 120.62,82.32 120.12,81.82 113.64,81.82 113,81.18
APU_VDD on L2VCC: 96.83,76.91 94.41,79.34 94.41,88.2 95.68,89.47 95.68,90.89 95.31,91.26 94.55,91.26 94.41,91.4 94.41,105.47 100.9,111.96 113.95,111.96 114.22,111.69 114.22,108.67 113.31,107.77 109.25,107.77 106.34,104.86 106.34,101.94 103.3,98.9 103.3,95.44 103.68,95.05 103.68,93.4 104.17,92.91 104.93,92.91 105.44,92.4 106.23,92.4 108.52,94.69 111.79,94.69 112.57,93.91 112.57,87.82 113.06,87.32 117.25,87.32 118.01,86.56 119.54,86.56 120.82,85.28 120.82,81.12 120.04,80.34 112.42,80.34 111.92,79.83 107.73,79.83 106.2,78.31 103.66,78.31 102.26,76.91
APU_VDD on L3: 120.9,81.08 119.99,80.17 112.37,80.17 111.99,79.78 107.8,79.78 106.39,78.37 103.74,78.37 102.27,76.9 96.83,76.9 94.41,79.32 94.41,90.94 93.83,91.51 93.83,98.18 94.34,98.69 94.34,105.42 100.82,111.9 113.77,111.9 114.15,111.52 114.15,108.47 113.52,107.83 109.58,107.83 106.41,104.66 106.41,101.99 103.87,99.45 103.87,93.23 104.2,92.9 104.93,92.9 105.38,92.45 106.4,92.45 108.69,94.75 112,94.75 112.63,94.12 112.63,87.77 112.88,87.51 117.2,87.51 117.96,86.75 119.62,86.75 120.9,85.47
APU_VDDNB on TOP: 126.47,108.47 126.22,108.72 126.22,111.26 126.6,111.64 129.14,111.64 134.35,116.85 134.35,120.79 134.73,121.17 137.14,121.17 137.4,120.91 137.4,120.03 137.78,119.64 137.78,114.82 137.65,114.69 136.89,114.69 136.76,114.56 136.76,113.55 136.51,113.29 134.35,113.29 133.97,112.91 133.97,111.9 133.71,111.64 133.71,109.36 132.82,108.47 ; 10 cut-outs
APU_VDDNB on TOP: 116.94,86.39 116.31,87.02 115.29,87.02 115.16,87.15 114.02,87.15 113.64,87.53 112.11,87.53 111.99,87.66 111.99,89.94 112,89.95 112,90 111.74,90.26 111.74,91.15 112.17,91.58 112.17,95.84 112.88,96.55 114.91,96.55 115.16,96.29 115.16,94.26 114.78,93.88 114.15,93.88 113.89,93.63 113.89,93.12 113.64,92.87 113.64,91.6 113.64,91.59 113.64,91.43 113.89,91.18 114.3,91.18 115.17,90.31 115.43,90.31 115.8,89.94 115.8,88.67 115.92,88.55 117.58,88.55 117.76,88.73 118.73,88.73 118.85,88.86 118.85,89.24 118.96,89.34 119.38,89.34 119.48,89.24 119.48,88.17 119.86,87.79 120.5,87.79 120.62,87.66 120.62,86.52 120.5,86.39 ; 12 cut-outs
APU_VDDNB on BOTTOM: 121.9,108.47 121.5,108.88 121.5,111.39 121.75,111.64 127.49,111.64 127.5,111.66 128.19,111.66 131.22,114.69 132.19,114.69 134.32,116.83 134.32,119.8 134.55,120.03 137.52,120.03 137.9,119.64 137.9,114.95 136.13,113.17 134.47,113.17 132.95,111.64 132.95,109.48 131.93,108.47
APU_VDDNB on BOTTOM: 120.47,85.3 119.98,85.78 119.95,85.78 119.17,86.56 118.79,86.94 118.57,86.94 118.57,86.94 117.04,86.94 116.67,87.31 112.39,87.31 112.21,87.49 112.21,89.32 113.08,90.19 113.08,90.22 113.07,90.23 113.07,90.94 113.29,91.15 113.67,91.15 113.8,91.28 114.56,91.28 114.93,90.9 114.93,90.77 115.59,90.11 118.8,90.11 118.8,90.11 119.26,90.11 119.45,89.92 119.45,89.39 121.05,87.79 121.05,87.3 120.48,86.73 120.48,86.29 120.64,86.14 121.11,85.66 121.11,85.4 121.02,85.3
APU_VDDNB on L2VCC: 121.22,85.42 119.69,86.94 118.17,86.94 117.41,87.7 113.22,87.7 112.95,87.97 112.95,91.3 113.29,91.64 116.44,91.64 117.05,91.03 119.8,91.03 120.31,91.55 120.31,93.15 121.33,94.17 121.33,95 122.68,96.35 122.68,101.71 126.28,105.32 126.28,115.63 127.44,116.79 137.7,116.79 138.22,116.26 138.22,114.39 137.44,113.61 136.3,113.61 135.05,112.36 135.05,99.02 129.08,93.05 129.08,85.81 128.68,85.42
APU_VDDNB on L3: 129.26,93.23 134.97,98.94 134.97,112.72 135.86,113.61 137.39,113.61 138.28,114.5 138.28,116.09 137.64,116.72 127.49,116.72 126.35,115.58 126.35,105.74 121.89,101.29 121.89,97.48 121,96.59 117.96,96.59 115.67,94.3 115.67,92.65 114.65,91.64 113.27,91.64 112.86,91.23 112.86,87.89 113.11,87.64 117.33,87.64 118.09,86.88 119.74,86.88 121.34,85.29 128.62,85.29 129.26,85.92
AUD_AGND on TOP: 165.21,19.31 165.21,21.85 165.46,22.11 167.24,22.11 167.37,21.98 167.37,19.7 166.99,19.31
AUD_AGND on TOP: 159.32,11.77 159.19,11.9 159.19,14.82 158.68,15.33 156.83,15.33 156.62,15.53 156.62,16.29 156.8,16.47 159.39,16.47 160.21,15.66 160.21,12.03 159.95,11.77 ; 6 cut-outs
AUD_AGND on BOTTOM: 164.99,19.28 164.83,19.44 164.83,21.6 165.46,22.24 167.24,22.24 167.37,22.11 167.37,19.82 166.82,19.28 ; 3 cut-outs
AUD_AGND on BOTTOM: 154.41,18.55 154.29,18.68 154.29,19.31 154.54,19.57 154.54,20.71 154.67,20.84 158.1,20.84 158.48,20.46 158.48,19.57 158.35,19.44 158.35,19.06 158.1,18.81 155.3,18.81 155.05,18.55 ; 3 cut-outs
AUD_AGND on L2VCC: 159.19,4.01 158.92,4.28 158.92,7.33 157.53,8.73 157.53,9.96 157.67,10.11 158.4,10.11 158.41,10.09 158.41,9.2 158.65,8.96 159.54,8.96 160.81,7.69 163,7.69 163.37,8.06 163.37,8.73 162.9,9.19 162.42,9.19 162.05,9.56 162.05,10.12 161.51,10.66 161.51,10.86 161.1,11.28 160.56,11.28 160.08,11.76 159.19,11.76 159.18,11.77 159.18,14.82 158.68,15.31 154.37,15.31 154.22,15.46 154.22,16.22 152.7,17.74 152.7,20.12 153.21,20.63 153.21,21.14 153.72,21.65 153.72,23.05 154.22,23.55 154.22,24.44 154.62,24.84 158.81,24.84 159.43,25.46 159.43,27.24 159.7,27.51 160.21,27.51 160.57,27.87 160.57,28.51 160.84,28.78 161.86,28.78 163.13,30.05 167.29,30.05 167.43,29.9 167.43,19.77 166.91,19.25 164.37,19.25 163.88,18.76 163.88,16.95 164.61,16.22 164.76,16.06 164.76,15.18 164.33,14.75 164.33,10.73 164.94,10.12 166.69,8.36 166.69,6.52 166.35,6.17 164.24,6.17 163.88,5.8 163.88,4.15 163.86,4.14 162.62,4.14 162.37,4.39 160.43,4.39 160.05,4.01
AUD_AGND on L5GND: 159.19,4.01 158.92,4.28 158.92,7.33 157.53,8.73 157.53,9.96 157.67,10.11 158.4,10.11 158.41,10.09 158.41,9.2 158.65,8.96 159.54,8.96 160.81,7.69 163,7.69 163.37,8.06 163.37,8.73 162.9,9.19 162.42,9.19 162.05,9.56 162.05,10.12 161.51,10.66 161.51,10.86 161.1,11.28 160.56,11.28 160.08,11.76 159.19,11.76 159.18,11.77 159.18,14.82 158.68,15.31 154.37,15.31 154.22,15.46 154.22,16.22 152.7,17.74 152.7,20.12 153.21,20.63 153.21,21.14 153.72,21.65 153.72,23.05 154.22,23.55 154.22,24.44 154.62,24.84 158.81,24.84 159.43,25.46 159.43,27.24 159.7,27.51 160.21,27.51 160.57,27.87 160.57,28.51 160.67,28.6 161.02,28.6 161.68,27.94 164.11,27.94 164.95,27.1 167.26,27.1 167.43,26.93 167.43,19.77 166.91,19.25 164.37,19.25 163.88,18.76 163.88,16.95 164.76,16.06 164.76,15.18 164.33,14.75 164.33,10.73 166.69,8.36 166.69,6.52 166.35,6.17 164.24,6.17 163.88,5.8 163.88,4.15 163.86,4.14 162.62,4.14 162.37,4.39 160.43,4.39 160.05,4.01
AUD_SPK_L+ on BOTTOM: 57.06,8.72 56.7,9.08 56.7,9.43 57.74,10.48 62.03,10.48 62.14,10.37 62.14,9.49 62.03,9.38 58.1,9.38 57.44,8.72 ; 2 cut-outs
AUD_SPK_L+_C on BOTTOM: 72.37,7.43 71.67,8.13 68.07,8.13 66.83,9.36 62.39,9.36 62.29,9.46 62.29,10.4 62.42,10.53 67.52,10.53 68.87,9.18 71.86,9.18 73.01,8.04 74.58,8.04 74.66,7.96 74.66,7.5 74.58,7.43
AUD_SPK_L- on BOTTOM: 56.75,10.3 56.37,10.68 56.37,11.06 57.64,12.33 61.96,12.33 62.08,12.2 62.08,11.44 61.96,11.31 58.15,11.31 57.13,10.3
AUD_SPK_L-_C on BOTTOM: 73.16,8.42 73.03,8.55 73.03,9.59 71.31,11.31 62.42,11.31 62.31,11.42 62.31,12.41 62.42,12.51 72.19,12.51 74.66,10.04 74.66,8.52 74.56,8.42
AUD_SPK_R+ on BOTTOM: 58.61,4.66 58.45,4.81 58.45,5.78 58.63,5.95 61.91,5.95 61.98,5.88 61.98,4.79 61.86,4.66 ; 2 cut-outs
AUD_SPK_R+_C on BOTTOM: 62.34,4.66 62.24,4.76 62.24,5.85 62.36,5.98 64.12,5.98 64.37,6.23 71.46,6.23 71.66,6.03 74.63,6.03 74.66,6.01 74.66,5.22 74.58,5.14 65.11,5.14 64.62,4.66
AUD_SPK_R- on BOTTOM: 58.71,6.72 58.5,6.92 58.5,7.68 58.71,7.88 61.88,7.88 61.98,7.78 61.98,6.87 61.83,6.72
AUD_SPK_R-_C on BOTTOM: 71.64,6.41 71.36,6.69 62.42,6.69 62.24,6.87 62.24,7.96 62.42,8.14 67.42,8.14 67.8,7.76 71.76,7.76 72.5,7.02 74.56,7.02 74.66,6.92 74.66,6.49 74.58,6.41
BAT_ALERT on TOP: 151.87,175.27 151.75,175.4 151.75,176.16 153.4,177.81 153.4,180.1 153.52,180.22 154.16,179.59 154.16,179.84 153.65,180.35 154.54,180.35 154.79,180.1 154.79,177.56 152.51,175.27
BT+ on TOP: 155.43,164.73 155.3,164.86 155.3,166.25 155.81,166.76 155.81,170.44 157.21,171.84 157.21,173.75 157.72,174.25 158.99,174.25 162.92,178.19 162.92,180.86 163.05,180.99 167.37,180.99 167.75,180.6 167.75,177.81 168.89,176.67 168.89,172.1 168.26,171.46 166.61,171.46 166.22,171.08 163.68,171.08 163.3,170.7 163.3,169.94 163.05,169.68 163.05,167.65 162.8,167.4 159.49,167.4 159.11,167.02 159.11,165.11 158.73,164.73 ; 6 cut-outs
BT+ on BOTTOM: 154.79,163.33 154.67,163.46 154.67,170.7 162.92,178.95 162.92,180.86 163.05,180.99 167.37,180.99 167.75,180.6 167.75,174.51 159.24,166 159.24,163.46 159.11,163.33
BT+_R on BOTTOM: 157.21,155.2 156.83,155.59 156.83,159.01 154.92,160.92 154.92,162.7 155.05,162.82 159.11,162.82 159.24,162.7 159.24,161.55 161.27,159.52 161.27,155.46 161.02,155.2
CHARGER_SRC on TOP: 139.17,155.59 139.05,155.71 139.05,159.9 139.55,160.41 145.14,160.41 145.4,160.16 145.4,156.22 144.76,155.59 ; 1 cut-out
CHARGER_SRC on BOTTOM: 139.81,155.59 138.28,157.11 138.28,159.4 138.41,159.52 143.36,159.52 144,160.16 148.32,160.16 148.44,160.03 148.44,157.11 148.19,156.86 146.03,156.86 144.76,155.59 ; 3 cut-outs
CHG_AGND on BOTTOM: 124.92,152.66 123.2,154.39 122.97,154.39 122.84,154.52 122.84,154.85 122.94,154.95 123.55,154.95 124.95,153.55 126.6,153.55 126.73,153.68 126.73,154.7 126.98,154.95 126.98,158.25 124.82,160.41 124.24,160.41 123.4,161.25 123.04,161.25 122.79,161.5 122.79,161.94 123.68,161.94 124.44,161.17 127.36,161.17 127.62,160.92 127.62,159.78 127.36,159.52 127.36,159.01 127.62,158.76 127.62,157.54 127.69,157.47 129.5,157.47 130.79,158.76 130.79,159.52 130.41,159.9 130.41,161.05 130.54,161.17 131.93,161.17 132.44,160.67 132.44,159.68 129.85,157.08 129.85,155.87 128.96,154.98 128.96,153.12 128.89,153.05 127.24,153.05 126.85,152.66 ; 10 cut-outs
DC_IN_D on TOP: 109.07,173.24 108.82,173.49 108.82,175.02 109.07,175.27 111.11,175.27 111.23,175.14 111.23,173.49 110.98,173.24
DCBATOUT on TOP: 34.53,50.43 33.89,51.06 30.08,51.06 29.83,51.32 29.83,53.1 30.97,54.24 33.13,54.24 33.38,53.99 33.38,53.1 33.51,52.97 34.02,52.97 35.54,51.45 38.77,51.45 39.73,52.41 39.73,53.38 39.76,53.4 39.91,53.4 39.94,53.38 39.94,51.83 39.61,51.5 39.61,50.68 39.35,50.43 ; 2 cut-outs
DCBATOUT on TOP: outline of 94 points within 49.89,38.62 149.97,158.25 ; 7 cut-outs
DCBATOUT on TOP: 120.63,167.65 120,168.29 120,172.86 120.12,172.98 130.16,172.98 130.92,172.22 136.13,172.22 136.89,171.46 150.73,171.46 150.86,171.33 155.05,171.33 155.3,171.08 155.3,168.41 155.18,168.29 151.11,168.29 150.6,168.79 145.27,168.79 144.51,169.56 137.01,169.56 135.11,167.65 ; 6 cut-outs
DCBATOUT on BOTTOM: 147.94,109.1 147.81,109.23 147.81,111.39 147.94,111.52 149.08,111.52 149.33,111.26 149.33,109.23 149.21,109.1 ; 1 cut-out
DCBATOUT on BOTTOM: 91.68,119.64 90.79,120.53 90.79,132.98 92.76,134.95 100.12,134.95 102.98,137.81 102.98,140.09 105.71,142.82 105.71,150.32 108.69,153.3 108.69,154.44 108.31,154.82 102.22,154.82 102.09,154.95 102.09,158.25 102.22,158.38 108.95,158.38 110.47,159.9 110.47,161.3 112.63,163.46 112.63,166.28 114.13,167.78 119.11,167.78 120,168.67 120,172.86 120.12,172.98 129.14,172.98 130.54,171.59 147.43,171.59 147.81,171.21 153.52,171.21 153.78,170.95 153.78,168.54 153.52,168.29 146.67,168.29 145.14,169.81 136.76,169.81 136,169.05 136,166.13 139.94,162.19 141.97,162.19 142.22,161.94 142.22,160.03 141.97,159.78 137.65,159.78 130.09,167.33 125.39,167.33 117.71,159.65 117.71,157.11 121.39,153.43 123.43,153.43 127.11,149.74 128.76,149.74 130.16,151.14 130.79,151.14 136,145.93 138.28,145.93 138.79,145.43 138.79,143.39 138.54,143.14 130.92,143.14 123.3,150.76 113.39,150.76 109.96,147.33 109.96,139.71 107.8,137.55 107.8,132.47 103.11,127.77 103.11,122.06 100.69,119.64 ; 18 cut-outs
DCBATOUT on BOTTOM: 59.8,54.75 59.42,55.13 59.42,59.32 59.8,59.7 63.23,59.7 63.61,59.32 63.61,55.13 63.23,54.75
DCBATOUT on L3: 134.47,171.97 153.52,171.97 153.78,171.71 153.78,168.67 153.52,168.41 134.35,168.41 133.97,168.79 133.97,171.46
DCBATOUT on L3: 32.87,53.86 32.87,54.62 35.54,57.29 44.43,57.29 47.1,54.62 51.92,54.62 52.18,54.87 52.18,56.02 51.04,57.16 47.61,57.16 45.57,59.19 34.02,59.19 29.83,55 29.83,52.59 30.33,52.08 31.1,52.08
DCBATOUT on L3: 120.38,171.97 123.3,171.97 123.81,171.46 123.81,168.16 117.71,162.06 117.71,156.86 117.08,156.22 112.25,156.22 111.11,157.36 111.11,161.43 120.12,170.44 120.12,171.71
DCBATOUT_LCD on TOP: 93.83,155.84 93.71,155.97 93.71,157.49 93.83,157.62 99.3,157.62 99.55,157.36 99.55,156.73 98.66,155.84 ; 3 cut-outs
DCBATOUT_LCD on BOTTOM: 95.99,154.57 95.61,154.95 95.61,156.73 96.25,157.36 97.26,157.36 98.53,158.63 99.93,158.63 100.18,158.38 100.18,154.7 100.06,154.57
DDR_VREF_S3 on TOP: 69.2,38.24 69.07,38.36 69.07,40.14 95.49,66.56 95.49,68.34 95.42,68.4 95.42,70.05 103.61,78.24 107.8,78.24 108.57,77.48 108.57,77.1 107.93,76.46 107.93,75.96 107.68,75.7 105.52,75.7 103.3,73.48 103.3,70.31 79.86,46.87 79.36,46.87 70.72,38.24 ; 2 cut-outs
DDR_VREF_S3 on TOP: 56.12,50.53 55.86,50.79 55.86,51.55 56.95,52.64 59.57,52.64 59.65,52.56 59.65,52.11 59.57,52.03 59.04,52.03 58.81,51.8 58.81,50.63 58.71,50.53 ; 1 cut-out
DDR_VREF_S3 on TOP: 120.25,14.87 119.87,15.25 119.87,17.92 120.12,18.17 122.28,18.17 122.54,17.92 122.54,15.38 122.03,14.87 ; 2 cut-outs
DDR_VREF_S3 on BOTTOM: 69.45,37.22 69.07,37.6 69.07,39.25 69.32,39.51 76.05,39.51 76.44,39.13 76.44,37.35 76.31,37.22
DDR_VREF_S3 on BOTTOM: 75.67,23.38 75.42,23.63 75.42,25.79 75.55,25.92 81.13,25.92 81.26,25.79 81.26,23.76 80.88,23.38
DDR_VREF_S3 on L4: 119.03,77.02 119.72,77.02 119.95,76.8 119.95,75.42 118.73,74.2 107.53,74.2 104.5,77.23 104.5,78.24 104.63,78.37 106.66,78.37 107.42,77.61 108.21,77.61 108.39,77.43 108.39,77 107.83,76.44 107.83,75.88 108.19,75.53 117.56,75.53 119.03,77
HDMI_PLL_GND on TOP: 22.84,71.33 22.64,71.54 22.64,78.17 22.97,78.5 25.51,78.5 25.76,78.24 25.76,76.85 25.13,76.21 25.13,73.16 23.3,71.33 ; 1 cut-out
JGND on TOP: 107.68,159.14 106.41,160.41 100.44,160.41 99.93,160.92 99.93,162.44 100.31,162.82 109.46,162.82 109.71,162.57 109.71,160.79 110.22,160.28 110.22,159.4 109.96,159.14
JGND on BOTTOM: 106.15,159.52 105.65,160.03 105.65,161.81 106.53,162.7 109.46,162.7 109.71,162.44 109.71,160.03 109.2,159.52 ; 1 cut-out
LCDVDD on TOP: 100.34,153.63 100.24,153.73 100.24,156.14 100.57,156.47 102.34,156.47 102.6,156.22 102.6,153.73 102.5,153.63
LCDVDD_LCD on TOP: 93.83,153.3 93.71,153.43 93.71,155.08 93.83,155.2 94.75,155.2 95.24,155.7 99.49,155.7 99.68,155.51 99.68,153.73 99.52,153.58 96.4,153.58 96.12,153.3 ; 3 cut-outs
LOM_TCT on TOP: 27.92,166.89 27.67,167.14 27.67,171.21 27.92,171.46 29.57,171.46 30.59,170.44 31.99,170.44 32.24,170.19 32.24,168.29 30.84,166.89 ; 2 cut-outs
LOM_TCT on BOTTOM: 27.92,166.89 27.67,167.14 27.67,171.21 27.92,171.46 29.57,171.46 29.83,171.21 29.83,167.02 29.7,166.89
MCT on BOTTOM: 23.73,176.16 23.48,176.41 23.48,177.18 23.35,177.3 20.56,177.3 20.43,177.43 20.43,178.75 20.53,178.85 24.82,178.85 25,178.67 25,176.29 24.87,176.16
ODD_PWR_5V on TOP: 168,79.39 166.48,80.91 164.95,80.91 164.83,81.04 164.83,83.58 164.95,83.7 166.35,83.7 166.61,83.96 166.61,89.04 166.86,89.29 169.15,89.29 169.4,89.04 169.4,86.24 170.03,85.61 170.03,80.27 169.15,79.39
ODD_PWR_5V on BOTTOM: 169.02,85.35 168,86.37 166.61,86.37 166.48,86.5 166.48,88.91 166.61,89.04 171.05,89.04 171.3,88.78 171.3,85.74 170.92,85.35
PBAT_PRES1# on TOP: 153.91,175.02 153.65,175.27 153.65,175.91 157.21,179.46 157.21,180.1 157.59,180.48 158.35,180.48 158.73,180.1 158.73,179.33 154.41,175.02
PBAT_SMBCLK1 on TOP: 158.1,175.02 157.84,175.27 157.84,175.52 161.14,178.83 161.14,179.97 161.4,180.22 162.41,180.22 162.67,179.97 162.67,178.57 159.11,175.02
PBAT_SMBDAT1 on TOP: 156.19,175.02 155.94,175.27 155.94,176.03 159.11,179.21 159.11,180.1 159.37,180.35 160.51,180.35 160.89,179.97 160.89,179.08 156.83,175.02
PS_ID_R2 on TOP: 84.56,170.44 83.93,171.08 83.93,172.1 83.67,172.35 82.91,172.35 82.79,172.48 82.79,172.86 81.64,174 78.98,174 78.85,174.13 78.85,175.52 78.98,175.65 82.66,175.65 85.07,173.24 86.98,173.24 87.23,172.98 87.23,170.83 86.85,170.44 ; 1 cut-out
PWR_0D95V_LGATE on BOTTOM: 158.1,101.1 157.97,101.23 157.97,103.13 158.1,103.26 158.73,103.26 158.86,103.13 158.86,101.23 158.73,101.1
PWR_0D95V_PHASE on BOTTOM: 152.64,93.61 152.38,93.86 152.38,97.67 152.23,97.83 152.23,99.02 152.28,99.07 155.1,99.07 155.43,99.4 155.43,100.59 155.56,100.72 158.81,100.72 158.91,100.62 158.91,98.79 159.09,98.61 161.12,98.61 161.17,98.56 161.17,97.45 160.51,96.78 158.99,96.78 158.48,96.28 158.48,94.37 157.72,93.61
PWR_0D95V_UGATE on BOTTOM: 151.26,97.01 151.16,97.12 151.16,98.99 151.26,99.1 151.9,99.1 152,98.99 152,97.12 151.9,97.01
PWR_1D8V_PHASE on BOTTOM: 54.21,64.15 52.84,65.52 51.72,65.52 51.67,65.57 51.67,68.46 51.92,68.72 56.24,68.72 56.62,68.34 56.62,64.4 56.37,64.15
PWR_1D8V_PVDD on BOTTOM: 46.08,65.54 45.96,65.67 45.96,69.1 46.21,69.35 47.48,69.35 47.99,68.84 50.27,68.84 50.4,68.72 50.4,67.96 50.27,67.83 49.89,67.83 49.38,67.32 49.38,66.18 49.26,66.05 47.61,66.05 47.1,65.54 ; 3 cut-outs
PWR_1D35V_DRVH on TOP: 63.51,28.81 63.35,28.97 63.35,30.8 63.43,30.87 64.29,30.87 64.4,30.77 64.4,28.97 64.24,28.81
PWR_1D35V_DRVL on TOP: 54.62,32.9 54.54,32.98 54.54,34.89 54.69,35.04 55.33,35.04 55.46,34.91 55.46,32.95 55.4,32.9
PWR_1D35V_SW on TOP: 54.59,21.09 53.96,21.73 53.96,32.01 54.46,32.52 57.77,32.52 57.89,32.4 57.89,31.13 58.15,30.87 62.97,30.87 63.1,30.74 63.1,28.46 62.47,27.82 59.04,27.82 57.89,26.68 57.89,21.73 57.26,21.09
PWR_1D35V_VTTREF on TOP: 59.39,47.33 57.72,49.01 57.72,50.18 57.84,50.3 59.54,50.3 59.67,50.18 59.67,48.78 60.05,48.4 60.64,48.4 60.76,48.27 60.76,47.36 60.74,47.33 ; 1 cut-out
PWR_3D3V_HG on TOP: 37.22,52.72 37.12,52.82 37.12,53.33 37.35,53.55 37.93,53.55 38.18,53.81 39.1,53.81 39.15,53.76 39.15,53.6 39.12,53.58 38.69,53.58 37.83,52.72
PWR_3D3V_LG on TOP: 38.41,51.7 38.26,51.85 38.26,52.23 39.22,53.2 39.22,53.38 39.25,53.4 39.5,53.4 39.53,53.38 39.53,52.44 38.79,51.7
PWR_3D3V_PH on TOP: 29.85,39.63 29.47,40.02 29.47,42.61 29.83,42.96 32.09,42.96 32.14,42.91 32.14,40.7 32.27,40.57 34.37,40.57 34.48,40.68 34.48,44.46 34.58,44.56 37.88,44.56 38.03,44.41 38.03,40.14 37.52,39.63
PWR_3D3V_PH on BOTTOM: 29.83,39.63 29.45,40.02 29.45,43.57 29.95,44.08 37.7,44.08 37.95,43.83 37.95,40.02 37.57,39.63
PWR_5V_HG on TOP: 47.71,41.77 47.63,41.84 47.63,42.89 47.71,42.96 48.98,42.96 49.11,42.84 49.11,42 48.88,41.77
PWR_5V_HG on TOP: 42.98,52.16 41.56,53.58 41.38,53.58 41.33,53.63 41.33,53.73 41.41,53.81 42.22,53.81 43.06,52.97 43.42,52.97 43.52,52.87 43.52,52.28 43.39,52.16
PWR_5V_LG on TOP: 40.04,44.97 39.94,45.07 39.94,46.09 40.01,46.16 41.46,46.16 41.51,46.11 41.51,45.05 41.43,44.97
PWR_5V_LG on TOP: 41.66,51.47 41.36,51.78 41.36,52.03 40.93,52.46 40.93,53.35 40.98,53.4 41.16,53.4 41.21,53.35 41.21,53 42.15,52.06 42.15,51.67 41.94,51.47
PWR_5V_PH on TOP: 40.88,39.76 40.57,40.07 40.57,44.54 40.62,44.59 43.92,44.59 43.97,44.54 43.97,43.11 44.15,42.94 47.35,42.94 47.38,42.91 47.38,40.04 47.1,39.76
PWR_5V_PH on BOTTOM: 40.88,39.76 40.49,40.14 40.49,44.33 40.75,44.59 47.1,44.59 47.35,44.33 47.35,40.02 47.1,39.76
PWR_APU_VDD_DCBATOUT on TOP: 104.31,120.79 104.19,120.91 104.19,128.22 107.68,131.71 110.22,131.71 110.66,131.27 110.66,125.8 110.22,125.36 110.22,121.04 109.96,120.79 ; 2 cut-outs
PWR_APU_VDD_DCBATOUT on BOTTOM: 103.61,120.79 103.36,121.04 103.36,127.39 107.04,131.07 109.96,131.07 110.47,130.57 110.47,126.38 109.89,125.79 109.89,120.91 109.76,120.79
PWR_APU_VDD_SW1 on TOP: 105.26,114.44 104.63,115.07 104.63,120.15 104.76,120.28 108.44,120.28 108.57,120.15 108.57,117.74 108.82,117.49 110.47,117.49 113.01,120.03 113.01,123.58 113.27,123.84 118.22,123.84 118.35,123.71 118.35,115.45 117.33,114.44
PWR_APU_VDD_SW1 on BOTTOM: 108.06,114.44 107.17,115.33 107.17,116.72 106.41,117.49 106.41,120.15 106.53,120.28 109.84,120.28 110.73,119.39 112.63,119.39 113.01,119.77 113.01,123.58 113.27,123.84 118.22,123.84 118.35,123.71 118.35,115.45 117.33,114.44
PWR_APU_VDDNB_DCBATOUT on TOP: 127.36,125.99 127.11,126.25 127.11,133.61 127.36,133.87 132.19,133.87 132.44,133.61 132.44,126.38 132.06,125.99
PWR_APU_VDDNB_DCBATOUT on BOTTOM: 128.12,120.28 128,120.41 128,124.47 127.11,125.36 127.11,133.36 127.62,133.87 132.19,133.87 132.57,133.49 132.57,126.63 133.59,125.61 133.59,120.53 133.33,120.28 ; 2 cut-outs
PWR_CHG_LODRV on TOP: 130.64,152.44 129.62,153.45 129.62,154.75 129.7,154.82 129.93,154.82 129.98,154.77 129.98,154.37 131.27,153.07 131.27,152.72 131,152.44
PWR_CHG_LODRV on BOTTOM: 145.75,154.72 145.65,154.82 145.65,155.97 145.78,156.09 146.79,156.09 146.92,155.97 146.92,154.82 146.82,154.72
PWR_CHG_PHASE on BOTTOM: 147.43,152.16 147.17,152.41 147.17,155.59 147.3,155.71 150.73,155.71 151.11,156.09 151.11,157.87 150.98,158 148.95,158 148.83,158.13 148.83,160.16 149.08,160.41 152.89,160.41 154.54,158.76 154.54,154.44 152.25,152.16
PWR_DCBATOUT_0D95V on TOP: 150.35,103.13 150.1,103.39 150.1,104.15 146.54,107.71 146.54,108.72 146.67,108.85 151.62,108.85 153.27,107.2 153.27,103.39 153.02,103.13
PWR_DCBATOUT_0D95V on BOTTOM: 150.73,99.48 150.45,99.76 150.45,107.61 150.76,107.91 154.21,107.91 154.54,107.58 154.54,99.6 154.41,99.48 ; 2 cut-outs
PWR_DCBATOUT_3D3V on TOP: 29.7,43.32 29.45,43.57 29.45,50.43 29.83,50.81 33.26,50.81 33.64,50.43 33.64,43.57 33.38,43.32 ; 2 cut-outs
PWR_DCBATOUT_3D3V on BOTTOM: 29.7,46.62 29.45,46.87 29.45,49.92 29.95,50.43 33.26,50.43 33.64,50.05 33.64,47.13 33.13,46.62
PWR_DCBATOUT_5V on TOP: 45.18,43.33 45.14,43.37 45.14,46.21 45.09,46.26 45.09,52.11 45.7,52.72 49.77,52.72 50.02,52.46 50.02,44.08 49.27,43.33 ; 4 cut-outs
PWR_DCBATOUT_5V on BOTTOM: 45.7,46.62 45.57,46.75 45.57,49.67 45.7,49.79 47.73,49.79 47.99,49.54 47.99,46.75 47.86,46.62
PWR_VDDNB_SW2 on TOP: 120.38,114.18 119.49,115.07 119.49,123.07 119.74,123.33 124.57,123.33 124.82,123.07 124.82,119.01 125.08,118.76 126.6,118.76 126.98,118.37 126.98,115.07 126.09,114.18
PWR_VDDNB_SW2 on BOTTOM: 120.76,114.18 119.49,115.45 119.49,123.07 119.74,123.33 124.57,123.33 124.82,123.07 124.82,119.52 125.08,119.26 127.49,119.26 127.62,119.14 127.62,117.49 128.12,116.98 129.14,116.98 129.65,117.49 129.65,119.64 129.78,119.77 132.95,119.77 133.08,119.64 133.08,116.95 131.45,115.33 130.54,115.33 129.39,114.18
REGOUT on TOP: 51.98,170.6 51.92,170.65 51.92,171.82 52.08,171.97 52.08,173.29 52.15,173.37 52.69,173.37 53.12,173.8 53.12,174 53.27,174.15 55.96,174.15 56.22,174.41 56.22,174.84 56.32,174.94 57.39,174.94 57.46,174.86 57.46,173.06 56.98,172.58 54.08,172.58 53.72,172.21 53.72,171.52 52.79,170.6 ; 1 cut-out
RING2 on TOP: 157.21,21.93 157.11,22.03 157.11,22.92 157.21,23.02 161.75,23.02 161.83,22.95 161.83,22.03 161.73,21.93 ; 1 cut-out
RING2 on BOTTOM: 157.97,22.01 157.89,22.08 157.89,22.95 157.97,23.02 160.08,23.02 160.13,22.97 160.13,22.08 160.05,22.01
RING2 on BOTTOM: 155.89,15.25 155.84,15.3 155.84,16.29 155.1,17.03 155.1,17.46 155.2,17.56 155.68,17.56 156.04,17.21 156.04,15.3 155.99,15.25
RING2 on L3: 155.05,16.52 156.19,16.52 157.46,17.79 157.46,21.35 157.97,21.85 158.73,21.85 158.86,21.98 158.86,22.87 158.73,23 157.46,23 156.32,21.85 156.32,18.17 155.94,17.79 155.05,17.79 154.92,17.66 154.92,16.65
RING2_R on TOP: 162.14,21.91 162.06,21.98 162.06,22.9 162.16,23 163.25,23 165.29,25.03 167.14,25.03 167.19,24.98 167.19,23.63 167.06,23.51 165.72,23.51 164.12,21.91
SLEEVE on TOP: 157.16,23.33 157.08,23.4 157.08,24.29 157.18,24.39 161.75,24.39 161.86,24.29 161.86,23.48 161.7,23.33 ; 1 cut-out
SLEEVE on BOTTOM: 157.94,23.28 157.84,23.38 157.84,24.29 157.94,24.39 160.08,24.39 160.15,24.32 160.15,23.38 160.05,23.28
SLEEVE on BOTTOM: 156.29,15.25 156.24,15.3 156.24,17.23 155.68,17.79 155.35,17.79 155.1,18.04 155.1,18.6 155.25,18.76 155.68,18.76 156.65,17.79 156.65,16.55 156.45,16.34 156.45,15.3 156.4,15.25
SLEEVE on L3: 156.83,24.27 158.6,24.27 158.73,24.14 158.73,23.51 158.6,23.38 157.46,23.38 156.19,22.11 156.19,18.3 155.94,18.04 155.18,18.04 155.05,18.17 155.05,22.49
SLEEVE_R on TOP: 162.14,23.35 162.07,23.42 162.07,24.32 162.2,24.45 162.82,24.45 165.41,27.04 167.11,27.04 167.16,26.99 167.16,25.56 167.09,25.49 165.51,25.49 163.38,23.35
TPAN_VDD on TOP: 91.8,136.28 90.66,137.42 90.66,137.81 90.91,138.06 92.56,138.06 93.45,137.17 94.85,137.17 94.98,137.04 94.98,136.54 94.72,136.28
TPAN_VDD on BOTTOM: 90.91,135.14 90.53,135.52 90.53,137.68 90.91,138.06 96.25,138.06 96.63,137.68 96.63,135.9 95.87,135.14 ; 2 cut-outs
TPAN_VDD_F on BOTTOM: 88.5,138.31 88.25,138.57 88.25,139.58 88.37,139.71 90.66,139.71 91.04,140.09 91.04,140.85 91.29,141.11 94.34,141.11 94.72,140.73 94.72,140.35 95.1,139.96 96.63,139.96 96.76,139.84 96.76,138.57 96.5,138.31 ; 4 cut-outs
USB20_VCCA on TOP: 156.19,29.86 155.3,30.74 155.3,34.43 156.19,35.32 164.07,35.32 164.83,36.08 167.11,36.08 167.24,35.95 167.24,31.63 167.11,31.51 158.99,31.51 157.33,29.86 ; 3 cut-outs
USB20_VCCA on BOTTOM: 156.12,29.3 155.84,29.58 155.84,32.29 155.91,32.37 157.21,32.37 157.28,32.29 157.28,29.86 157.27,29.84 157.27,29.51 157.06,29.3
USB20_VCCA on BOTTOM: 161.78,33.03 161.14,33.67 161.14,34.81 161.27,34.94 162.54,34.94 162.67,34.81 162.67,34.17 162.92,33.92 163.56,33.92 163.68,33.79 163.68,33.16 163.56,33.03
USB30_VCCC on TOP: 14.08,41.92 13.7,42.3 13.7,44.08 15.86,46.24 22.97,46.24 23.22,45.98 23.22,44.33 22.84,43.95 21.44,43.95 20.68,43.19 17.51,43.19 16.24,41.92 ; 3 cut-outs
USB30_VCCC on BOTTOM: 18.02,61.86 17.51,62.37 17.51,64.4 18.78,65.67 19.54,65.67 21.06,67.19 21.06,67.57 21.32,67.83 21.32,68.21 21.57,68.46 25.13,68.46 25.25,68.34 25.25,65.03 24.11,63.89 21.44,63.89 19.41,61.86
USB30_VCCC on BOTTOM: 14.46,42.56 13.95,43.06 13.95,44.59 14.21,44.84 14.84,44.84 16.24,46.24 22.97,46.24 23.22,45.98 23.22,44.97 21.44,43.19 18.02,43.19 17.38,42.56 ; 2 cut-outs
USB30_VCCC on L3: 20.3,68.46 23.22,68.46 23.48,68.21 23.48,67.32 22.84,66.69 21.44,66.69 19.16,64.4 19.16,62.24 18.14,61.22 18.14,57.67 17.38,56.91 17.38,44.33 17.13,44.08 15.48,44.08 15.22,44.33 15.22,57.8 15.98,58.56 15.98,64.15
